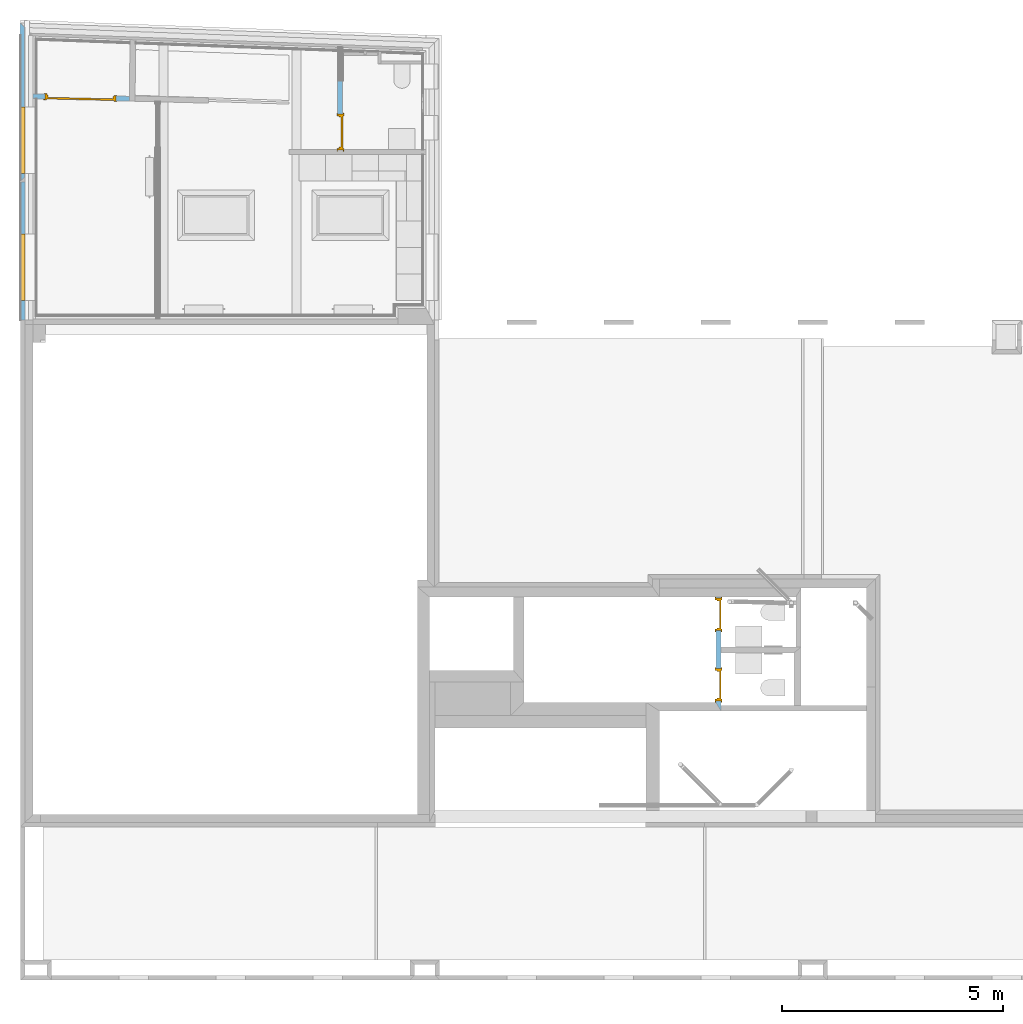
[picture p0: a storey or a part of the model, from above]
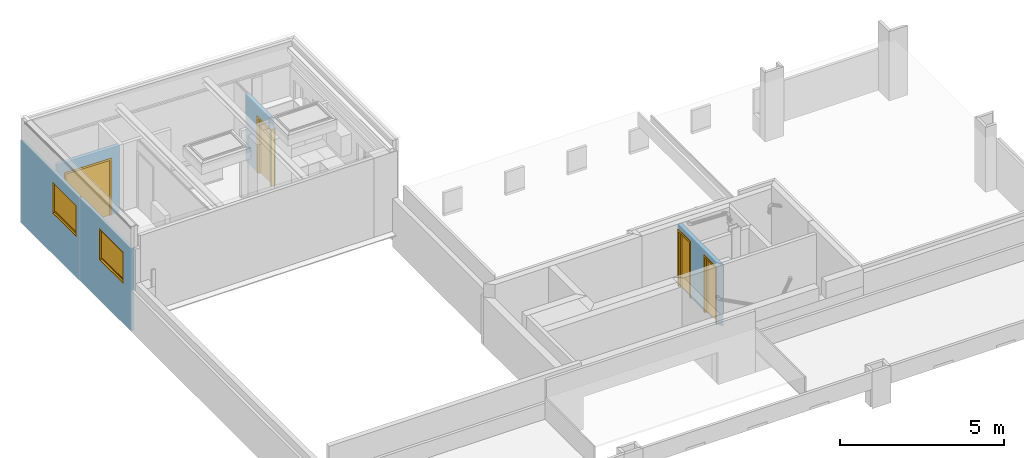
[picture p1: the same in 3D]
Properties of the parts of a building model (IFC2X3), part 1 of 17

# File
Description: ViewDefinition [CoordinationView_V2.0], Comment [Comments], Comment [System: OpenBuildings Designer24.00.03.14]
File name: SHE_DRAWING+SHEET revH1
Time: 2026-07-15T07:19:15+02:00
Author: First Name Last Name
Organization: spaceAgent.com
Written by: ST-DEVELOPER v16.13
Made in: OpenBuildings Designer 24.00.03.14
Authorization: Administrator
Comment: Generated by software containing ST-Developer * from STEP Tools, Inc. (www.steptools.com)
Comment: description
Comment: implementation_level
Comment: name
Comment: time_stamp
Comment: author
Comment: organization
Comment: preprocessor_version
Comment: originating_system
Comment: authorisation

# IfcProject, BuildingTemplate_UK
Project - Project Name: BuildingTemplate_UK

# IfcSite, Site
RefElevation: 0 m
Pset_SiteCommon - BuildableArea: 0 m2
Site - Site Name: Site; Building Height Limit: 0 m

# IfcBuilding, Building01
ElevationOfRefHeight: 4.64 m; ElevationOfTerrain: 0 m
Classification - Uniclass2015: Co_20
Building Parameters - Building Name: Building01

# IfcBuildingStorey (7)
In: Building01
Pset_BuildingStoreyCommon - GrossAreaPlanned: 9600 m2; NetAreaPlanned: 9600 m2
Structural Floor Parameters - Column Splice Floor: no
Floor Parameters - Length (Approx.): 120 m; Width (Approx.): 80 m; Typical Floor: no; Typical Floor Base Elevation: 0 m; ACS Rotation Angle: 0:0; Annotate: yes
Floor - Area (Gross): 9600 m2; Area (Net): 9600 m2
Name | Description = Floor Parameters, Description | Elevation (m) = Elevation | Finished Floor | Floor Name | Typical Floor Height (m)
GF | Ground Floor | 0 | GF | 3
MF | Mezzanine Floor | 2.6 | MF | 3
1F | First Floor | 5.15 | 1F | 0.004 | Classification - Uniclass2015: EF_30_20
3F | Third Floor | 12.13 | 3F | 3
5F | Fifth floor | 17.71 | 5F | 3
RL |  | 20.96 | RL | 0 | Classification - Uniclass2015: EF_30_20
2F | Second Floor | 8.64 | 2F | 3 | Classification - Uniclass2015: \

# IfcSpace: A-AdministrativeCommercialAndProtectiveSer, 0
In: GF
Type - PredefinedType: USERDEFINED
Type - Space Parameters - Label: Administrative & Commercial Spaces; Ceiling Height: 3 m; major: 1; minor: 1
Type - Materials - Part Definition: A-Spaces::A_BSUK_AdministrativeCommercialAndProtectiveSer
Type - Energy Analysis - Energy Analysis | Space Category: Interior
Type - Discipline - Discipline: Architectural
Type - Construction Phase - Phase: New Construction
Type - Classification - Uniclass2015: SL_20
Description: UNIT; LongName: commercial; ElevationWithFlooring: -4.64 m
Space Parameters - Label: UNIT; Space Number: 0; Label 2: commercial; Ceiling Height: 4.5 m; Perimeter: 44.9707 m; Area | Program: 0 m2; Area | Actual: 99.3628 m2
Space - Notes: skirting white

# IfcSpace: A-CirculationAndStorageSpaces (65)
Type - PredefinedType: USERDEFINED
Type - Space Parameters - Label: Circulation & Storage Spaces; Ceiling Height: 3 m; major: 1; minor: 1
Type - Materials - Part Definition: A-Spaces::A_BSUK_CirculationAndStorageSpaces
Type - Energy Analysis - Energy Analysis | Space Category: Interior
Type - Discipline - Discipline: Architectural
Type - Construction Phase - Phase: New Construction
ElevationWithFlooring: -4.64 m
Space Parameters - Area | Program: 0 m2
Name | In | Description = Label | LongName | Space Number | Label 2 | Ceiling Height (m) | Perimeter (m) | Area | Actual (m2) | Notes | Part Definition
1 | GF | stair | vinyl (acD) | 1 | vinyl (acD) | 2.5 | 9.93685 | 4.25527 | skirting vinyl
1 | GF | riser | 1 | 1 |  | 2.5 | 3.72964 | 0.510705 | n/a | A-Spaces::_Void
0 | GF | riser | 0 | 0 |  | 2.5 | 11.4772 | 2.99959 | n/a | A-Spaces::_Void
bike store | GF | bike store | asphalt |  | asphalt | 2 | 15.5649 | 11.0029 | n/a | A-Spaces::_Exterior_Space
bike store | GF | bike store | asphalt |  | asphalt | 2 | 9.73329 | 5.58868 | n/a | A-Spaces::_Exterior_Space
landing | MF | landing | vinyl (acD) |  | vinyl (acD) | 2.5 | 11.3025 | 5.20961 | skirting vinyl
WC | MF | WC | tile |  | tile | 2.5 | 8.28221 | 4.08071 | wall tile (up to 2m) | A-Spaces::_Interior_Space
1 | MF | storage | screed | 1 | screed | 2.5 | 8.26251 | 3.91896 | n/a
storage | MF | storage | screed |  | screed | 2.5 | 13.8687 | 10.5472 | n/a
1 | MF | stair | vinyl (acD) | 1 | vinyl (acD) | 2.5 | 11.6311 | 5.18709 | skirting vinyl
2 | MF | stair | vinyl (acD) | 2 | vinyl (acD) | 2.5 | 9.10975 | 3.67745 | skirting vinyl
landing | MF | landing | parquet |  | parquet | 2.5 | 6.70142 | 2.46885 | skirting white | A-Spaces::_Interior_Space
storage | MF | storage | parquet |  | parquet | 2.5 | 6.66153 | 2.57457 | n/a
bath | MF | bath | tile |  | tile | 2.5 | 8.02096 | 3.98235 | wall tile (up to 2m) | A-Spaces::_Interior_Space
1 | 1F | AOV | 1 | 1 |  | 2.6 | 3.35384 | 0.672727 | n/a | A-Spaces::_Void
1 | 1F | riser | 1 | 1 |  | 2.6 | 3.35384 | 0.672727 | n/a | A-Spaces::_Void
hall (vented) | 1F | hall (vented) | carpet (acC) |  | carpet (acC) | 2.6 | 20.45 | 10.5189 | skirting oak | A-Spaces::_Interior_Space
1 | 1F | stair | vinyl (acD) | 1 | vinyl (acD) | 2.5 | 11.2192 | 7.00439 | skirting vinyl
landing | 1F | landing | vinyl (acD) |  | vinyl (acD) | 2.6 | 7.88137 | 3.11561 | skirting vinyl
1 | 1F | lobby | carpet (acC) | 1 | carpet (acC) | 2.6 | 6.79532 | 2.84649 | skirting oak | A-Spaces::_Interior_Space
2 | 1F | riser | 2 | 2 |  | 2.6 | 2.83 | 0.258 | n/a | A-Spaces::_Void
2 | 1F | lobby | carpet (acC) | 2 | carpet (acC) | 2.6 | 13.4953 | 7.50678 | skirting oak | A-Spaces::_Interior_Space
1 | 3F | AOV | 1 | 1 |  | 2.6 | 3.35384 | 0.672727 | n/a | A-Spaces::_Void
1 | 3F | riser | 1 | 1 |  | 2.6 | 3.35384 | 0.672727 | n/a | A-Spaces::_Void
hall (vented) | 3F | hall (vented) | carpet (acC) |  | carpet (acC) | 2.6 | 20.4452 | 10.5149 | skirting oak | A-Spaces::_Interior_Space
1 | 3F | stair | vinyl (acD) | 1 | vinyl (acD) | 2.5 | 11.2192 | 7.00458 | skirting vinyl
landing | 3F | landing | vinyl (acD) |  | vinyl (acD) | 2.6 | 7.9118 | 3.13941 | skirting vinyl
1 | 3F | lobby | carpet (acC) | 1 | carpet (acC) | 2.6 | 6.79532 | 2.84649 | skirting oak | A-Spaces::_Interior_Space
2 | 3F | riser | 2 | 2 |  | 2.6 | 2.83 | 0.258 | n/a | A-Spaces::_Void
2 | 3F | lobby | carpet (acC) | 2 | carpet (acC) | 2.6 | 13.4942 | 7.50726 | skirting oak | A-Spaces::_Interior_Space
landing | 1F | landing | vinyl (acD) |  | vinyl (acD) | 2.5 | 7.02024 | 2.75607 | skirting vinyl
hall (vented) | 1F | hall (vented) | carpet (acC) |  | carpet (acC) | 2.5 | 16.6709 | 8.79017 | skirting oak | A-Spaces::_Interior_Space
1 | 1F | lobby | carpet (acC) | 1 | carpet (acC) | 2.5 | 7.86583 | 3.64937 | skirting oak | A-Spaces::_Interior_Space
2 | 1F | lobby | carpet (acC) | 2 | carpet (acC) | 2.5 | 7.53988 | 3.40491 | skirting oak | A-Spaces::_Interior_Space
1 | 1F | AOV | 1 | 1 |  | 2.5 | 4.25 | 0.936464 | n/a | A-Spaces::_Void
1 | 1F | riser | 1 | 1 |  | 2.5 | 3.23114 | 0.605336 | n/a | A-Spaces::_Void
1 | 1F | stair | vinyl (acD) | 1 | vinyl (acD) | 2.5 | 11.3017 | 7.67441 | skirting vinyl
3 | 1F | stair | parquet | 3 | parquet | 2.5 | 9.30005 | 3.43648 | skirting white | A-Spaces::_Interior_Space
4 | 1F | stair | parquet | 4 | parquet | 2.5 | 9.86062 | 3.62728 | skirting white | A-Spaces::_Interior_Space
5 | 1F | stair | parquet | 5 | parquet | 2.5 | 9.09993 | 3.28497 | skirting white | A-Spaces::_Interior_Space
6 | 1F | stair | parquet | 6 | parquet | 2.5 | 9.4 | 3.42 | skirting white | A-Spaces::_Interior_Space
26 | 5F | FLAT | 4b6p (upper) | 26 | 4b6p (upper) | 2.5 | 35.2527 | 38.2118 | n/a | A-Spaces::A_BSUK_ResidentialSpaces
23 | 5F | FLAT | 4b6p (upper) | 23 | 4b6p (upper) | 2.5 | 35.2129 | 43.2149 | n/a | A-Spaces::A_BSUK_ResidentialSpaces
24 | 5F | FLAT | 3b6p (upper) | 24 | 3b6p (upper) | 2.5 | 35.1807 | 43.4478 | n/a | A-Spaces::A_BSUK_ResidentialSpaces
25 | 5F | FLAT | 3b6p (upper) | 25 | 3b6p (upper) | 2.5 | 38.0413 | 41.0862 | n/a | A-Spaces::A_BSUK_ResidentialSpaces
1 | 5F | AOV | 1 | 1 |  | 2.5 | 3.5 | 0.715 | n/a | A-Spaces::_Void
2 | 5F | AOV | hatch over | 2 | hatch over | 2.5 | 5.99988 | 1.99994 | n/a | A-Spaces::_Void
ter.23 | 5F | ter.23 | tile |  | tile | 2.5 | 19.7927 | 12.5632 | n/a | A-Spaces::_Exterior_Space
ter.24 | 5F | ter.24 | tile |  | tile | 2.5 | 19.7924 | 12.5622 | n/a | A-Spaces::_Exterior_Space
ter.26 | 5F | ter.26 | tile |  | tile | 2.5 | 19.7922 | 12.5629 | n/a | A-Spaces::_Exterior_Space
ter.25 | 5F | ter.25 | tile |  | tile | 2.5 | 19.7919 | 12.5618 | n/a | A-Spaces::_Exterior_Space
k/d/l | 5F | k/d/l | parquet |  | parquet | 2.5 | 38.0527 | 44.7522 | skirting white | A-Spaces::_Interior_Space
k/d/l | 5F | k/d/l | parquet |  | parquet | 2.5 | 40.8413 | 47.1014 | skirting white | A-Spaces::_Interior_Space
k/d/l | 5F | k/d/l | parquet |  | parquet | 2.5 | 38.0129 | 49.2272 | skirting white | A-Spaces::_Interior_Space
k/d/l | 5F | k/d/l | parquet |  | parquet | 2.5 | 37.9807 | 49.449 | skirting white | A-Spaces::_Interior_Space
2 | RL | AOV | access hatch | 2 | access hatch | 2.5 | 5.99988 | 1.99994 | n/a | A-Spaces::_Void
1 | RL | AOV | MSVS | 1 | MSVS | 2.5 | 10.8891 | 5.66237 | n/a | A-Spaces::_Void
1 | 2F | AOV | 1 | 1 |  | 2.6 | 3.35384 | 0.672727 | n/a | A-Spaces::_Void
1 | 2F | riser | 1 | 1 |  | 2.6 | 3.35384 | 0.672727 | n/a | A-Spaces::_Void
hall (vented) | 2F | hall (vented) | carpet (acC) |  | carpet (acC) | 2.6 | 20.45 | 10.5189 | skirting oak | A-Spaces::_Interior_Space
1 | 2F | stair | vinyl (acD) | 1 | vinyl (acD) | 2.5 | 11.2192 | 7.00458 | skirting vinyl
landing | 2F | landing | vinyl (acD) |  | vinyl (acD) | 2.6 | 7.9118 | 3.13941 | skirting vinyl
1 | 2F | lobby | carpet (acC) | 1 | carpet (acC) | 2.6 | 6.79532 | 2.84649 | skirting oak | A-Spaces::_Interior_Space
2 | 2F | riser | 2 | 2 |  | 2.6 | 2.83 | 0.258 | n/a | A-Spaces::_Void
2 | 2F | lobby | carpet (acC) | 2 | carpet (acC) | 2.6 | 13.4953 | 7.50721 | skirting oak | A-Spaces::_Interior_Space

# IfcSpace: A-ResidentialSpaces (28)
Type - PredefinedType: USERDEFINED
Type - Space Parameters - Label: Residential Spaces; Ceiling Height: 3 m; major: 1; minor: 1
Type - Materials - Part Definition: A-Spaces::A_BSUK_ResidentialSpaces
Type - Energy Analysis - Energy Analysis | Space Category: Interior
Type - Discipline - Discipline: Architectural
Type - Construction Phase - Phase: New Construction
Type - Classification - Uniclass2015: SL_45
ElevationWithFlooring: -4.64 m
Space Parameters - Area | Program: 0 m2
Space - Notes: n/a
Name | In | Description = Label | LongName = Label 2 | Space Number | Ceiling Height (m) | Perimeter (m) | Area | Actual (m2)
01 | GF | FLAT | 2b4p (lower) | 01 | 2.5 | 30.3387 | 47.5078
ENTRANCE | GF | ENTRANCE | residential |  | 4.5 | 31.3079 | 32.4907
01 | MF | FLAT | 2b4p (upper) | 01 | 2.5 | 38.9329 | 49.2519
07 | 1F | FLAT | 1b1p | 07 | 2.6 | 25.786 | 41.2992
06 | 1F | FLAT | 1b1p | 06 | 2.6 | 30.6107 | 40.6276
05 | 1F | FLAT | 1b1p | 05 | 2.6 | 28.883 | 41.0837
04 | 1F | FLAT | 1b1p | 04 | 2.6 | 28.903 | 41.1303
03 | 1F | FLAT | 1b1p | 03 | 2.6 | 30.9647 | 42.3191
02 | 1F | FLAT | 2b4p | 02 | 2.6 | 40.6617 | 73.0578
08 | 1F | FLAT | 1b1p | 08 | 2.6 | 29.5789 | 45.4997
21 | 3F | FLAT | 1b1p | 21 | 2.6 | 27.53 | 42.5859
20 | 3F | FLAT | 1b1p | 20 | 2.6 | 31.4827 | 41.2785
19 | 3F | FLAT | 1b1p | 19 | 2.6 | 28.883 | 41.0727
18 | 3F | FLAT | 1b1p | 18 | 2.6 | 28.903 | 41.1303
17 | 3F | FLAT | 1b1p | 17 | 2.6 | 31.8367 | 42.96
16 | 3F | FLAT | 2b4p | 16 | 2.6 | 41.0977 | 73.3782
22 | 3F | FLAT | 1b1p | 22 | 2.6 | 30.0149 | 45.8163
26 | 1F | FLAT | 4b6p (lower) | 26 | 2.5 | 39.478 | 74.3995
23 | 1F | FLAT | 4b6p (lower) | 23 | 2.5 | 39.2381 | 76.1835
24 | 1F | FLAT | 3b6p (lower) | 24 | 2.5 | 39.6636 | 68.1409
25 | 1F | FLAT | 3b6p (lower) | 25 | 2.5 | 39.3775 | 63.4613
14 | 2F | FLAT | 1b1p | 14 | 2.6 | 27.53 | 42.5859
13 | 2F | FLAT | 1b1p | 13 | 2.6 | 31.4827 | 41.2785
12 | 2F | FLAT | 1b1p | 12 | 2.6 | 28.883 | 41.0837
11 | 2F | FLAT | 1b1p | 11 | 2.6 | 28.903 | 41.1303
10 | 2F | FLAT | 1b1p | 10 | 2.6 | 31.8367 | 42.96
09 | 2F | FLAT | 2b4p | 09 | 2.6 | 41.2696 | 73.3567
15 | 2F | FLAT | 1b1p | 15 | 2.6 | 30.0149 | 45.8163

# IfcSpace: _Exterior Space (23)
Type - PredefinedType: USERDEFINED
Type - Space Parameters - Label: EXTERIOR SPACE; Ceiling Height: 3 m; Area | Program: 0 m2; major: 1; minor: 1
Type - Materials - Part Definition: A-Spaces::_Exterior_Space
Type - Energy Analysis - Energy Analysis | Space Category: Exterior
Type - Discipline - Discipline: Architectural
Type - Construction Phase - Phase: New Construction
Type - Classification - Uniclass2015: PM_40_30_17
ElevationWithFlooring: -4.64 m
Name | In | Description = Label | LongName = Label 2 | Ceiling Height (m) | Perimeter (m) | Area | Actual (m2) | Notes | Space Number
storage | GF | storage | asphalt | 2.5 | 10.2434 | 4.88146 | n/a
plant | GF | plant | sprinkler | 2.5 | 13.8942 | 9.76522 | n/a
refuse area | GF | refuse area | asphalt | 2 | 23.634 | 16.6836 | n/a
bike store | GF | bike store | asphalt | 2 | 15.0532 | 9.86402 | n/a
0 | GF | YARD | asphalt | 4 | 45.5698 | 90.2117 | n/a | 0
UNDERCROFT (front) | GF | UNDERCROFT (front) | paving | 4 | 62.6011 | 86.1884 | n/a
UNDERCROFT (back) | GF | UNDERCROFT (back) | asphalt | 4 | 58.8215 | 136.239 | n/a
1 | GF | Car P. | flat23 | 2 | 14.8 | 12 | n/a | 1
2 | GF | Car P. | flat24 | 2 | 14.8 | 12 | n/a | 2
3 | GF | Car P. | flat25 | 2 | 14.8002 | 12.0005 | n/a | 3
4 | GF | Car P. | flat26 | 2 | 14.8 | 12 | n/a | 4
1 | GF | YARD | asphalt (flat01) | 4 | 17.9409 | 17.4995 | n/a | 1
5 | GF | Car P. | flat01 | 2 | 14.8 | 12 | n/a | 5
storage | 1F | storage | carpet | 2.5 | 8.04048 | 2.75523 | skirting white | Materials - Part Definition: A-Spaces::_Interior_Space
storage | 1F | storage | carpet | 2.5 | 8.04048 | 3.18825 | skirting white | Materials - Part Definition: A-Spaces::_Interior_Space
1 | 5F | AC | optional |  | 2.79325 | 0.397029 | n/a | 1
2 | 5F | AC | optional |  | 2.79325 | 0.397029 | n/a | 2
4 | 5F | AC | optional |  | 2.79325 | 0.397029 | n/a | 4
3 | 5F | AC | optional |  | 2.79325 | 0.397029 | n/a | 3
flat roof | RL | flat roof | brown roof (tbc) | 2 | 56.1601 | 160.64 | n/a
16 | GF | balc. | tile |  | 17.6972 | 14.8939 | n/a | 16
09 | GF | balc. | tile |  | 17.6972 | 14.8939 | n/a | 09
02 | GF | balc. | tile |  | 17.6972 | 14.8939 | n/a | 02

# IfcSpace: _Interior (139)
Type - PredefinedType: USERDEFINED
Type - Space Parameters - Label: INTERIOR SPACE; Ceiling Height: 3 m; Area | Program: 0 m2; major: 1; minor: 1
Type - Materials - Part Definition: A-Spaces::_Interior_Space
Type - Energy Analysis - Energy Analysis | Space Category: Interior
Type - Discipline - Discipline: Architectural
Type - Construction Phase - Phase: New Construction
Type - Classification - Uniclass2015: PM_40_30_17
ElevationWithFlooring: -4.64 m
Name | In | Description = Label | LongName = Label 2 | Ceiling Height (m) | Perimeter (m) | Area | Actual (m2) | Notes
firef. LIFT | GF | firef. LIFT | (1.1x1.4m) | 2.2 | 4.8 | 1.4 | n/a | Materials - Part Definition: A-Spaces::_Void
bed | GF | bed | carpet | 2.6 | 16.9306 | 16.1823 | skirting white
bath | GF | bath | tile | 2.6 | 8.42663 | 4.02329 | wall tile (up to 2m)
corridor | GF | corridor | parquet | 2.6 | 22.8095 | 18.4831 | skirting white
F | GF | WC | tile (disab.) | 2.6 | 8.46664 | 4.29711 | wall tile (up to 2m) | Space Parameters - Space Number: F
M | GF | WC | tile | 2.6 | 6.8273 | 2.65638 | wall tile (up to 2m) | Space Parameters - Space Number: M
firef. LIFT | MF | firef. LIFT | (1.1x1.4m) | 2.2 | 4.8 | 1.4 | n/a | Materials - Part Definition: A-Spaces::_Void
2 | MF | bed | carpet | 2.6 | 15.1363 | 13.1528 | skirting white | Space Parameters - Space Number: 2
k/d/l | MF | k/d/l | parquet | 2.6 | 21.6917 | 25.0467 | skirting white
k/d/l | 1F | k/d/l | parquet | 2.6 | 19.206 | 18.8529 | skirting white
bath | 1F | bath | tile | 2.6 | 7.57 | 3.188 | wall tile (up to 2m)
storage | 1F | storage | parquet | 2.6 | 5 | 1.26 | skirting white
bath | 1F | bath | tile | 2.6 | 8.85627 | 3.75315 | wall tile (up to 2m)
storage | 1F | storage | parquet | 2.6 | 4.75839 | 1.24325 | skirting white
k/d/l | 1F | k/d/l | parquet | 2.6 | 25.4441 | 23.3097 | skirting white
2 x bed | 1F | bed | carpet | 2.6 | 14.94 | 11.4885 | skirting white
k/d/l | 1F | k/d/l | parquet | 2.6 | 24.0409 | 23.4095 | skirting white
2 x bath | 1F | bath | tile | 2.6 | 7.8 | 3.6 | wall tile (up to 2m)
storage | 1F | storage | parquet | 2.6 | 6.58993 | 1.70217 | skirting white
storage | 1F | storage | parquet | 2.6 | 6.59 | 1.70223 | skirting white
2 x firef. LIFT | 1F | firef. LIFT | (1.1x1.4m) | 2.2 | 4.8 | 1.4 | n/a | Materials - Part Definition: A-Spaces::_Void
k/d/l | 1F | k/d/l | parquet | 2.6 | 24.497 | 23.2991 | skirting white
studio | 1F | studio | parquet | 2.6 | 31.4647 | 37.2975 | skirting white
bath | 1F | bath | tile | 2.6 | 7.898 | 3.43088 | wall tile (up to 2m)
corridor | 1F | corridor | parquet | 2.6 | 16.5296 | 9.0203 | skirting white
bath | 1F | bath | tile | 2.6 | 8.19 | 4.176 | wall tile (up to 2m)
k/d/l | 1F | k/d/l | parquet | 2.6 | 20.4702 | 23.828 | skirting white
2 | 1F | bed | carpet | 2.6 | 15.0894 | 11.9399 | skirting white | Space Parameters - Space Number: 2
1 | 1F | bed | carpet | 2.6 | 17.0797 | 15.1572 | skirting white | Space Parameters - Space Number: 1
storage | 1F | storage | parquet | 2.6 | 2.74374 | 0.470142 | skirting white
k/d/l | 1F | k/d/l | parquet | 2.6 | 20.6123 | 21.7383 | skirting white
corridor | 1F | corridor | parquet | 2.6 | 11.3315 | 6.13542 | skirting white
bath | 1F | bath | tile | 2.6 | 7.80943 | 3.60707 | wall tile (up to 2m)
storage | 1F | storage | parquet | 2.6 | 4.56315 | 1.30038 | skirting white
corridor | 1F | corridor | parquet | 2.6 | 13.57 | 6.7325 | skirting white
bed | 1F | bed | carpet | 2.6 | 14.4144 | 11.4258 | skirting white
bed | 1F | bed | carpet | 2.6 | 12.7068 | 9.99626 | skirting white
bed | 1F | bed | carpet | 2.6 | 14.3106 | 11.3749 | skirting white
ensuite | 1F | ensuite | tile | 2.6 | 7.89374 | 3.31102 | wall tile (up to 2m)
storage | 1F | storage | parquet | 2.6 | 4.59 | 1.1165 | skirting white
storage | 1F | storage | parquet | 2.6 | 10.8267 | 2.53079 | skirting white
k/d/l | 3F | k/d/l | parquet | 2.6 | 20.514 | 19.8142 | skirting white
bath | 3F | bath | tile | 2.6 | 7.57 | 3.188 | wall tile (up to 2m)
storage | 3F | storage | parquet | 2.6 | 5 | 1.26 | skirting white
bath | 3F | bath | tile | 2.6 | 8.85627 | 3.75315 | wall tile (up to 2m)
storage | 3F | storage | parquet | 2.6 | 4.75839 | 1.24325 | skirting white
k/d/l | 3F | k/d/l | parquet | 2.6 | 26.3161 | 23.9605 | skirting white
2 x bed | 3F | bed | carpet | 2.6 | 14.94 | 11.4885 | skirting white
k/d/l | 3F | k/d/l | parquet | 2.6 | 24.0409 | 23.4095 | skirting white
2 x bath | 3F | bath | tile | 2.6 | 7.8 | 3.6 | wall tile (up to 2m)
storage | 3F | storage | parquet | 2.6 | 6.58993 | 1.70217 | skirting white
storage | 3F | storage | parquet | 2.6 | 6.59 | 1.70223 | skirting white
firef. LIFT | 3F | firef. LIFT | (1.1x1.4m) | 2.2 | 4.8 | 1.4 | n/a | Materials - Part Definition: A-Spaces::_Void
k/d/l | 3F | k/d/l | parquet | 2.6 | 24.497 | 23.2991 | skirting white
studio | 3F | studio | parquet | 2.6 | 32.3367 | 37.9385 | skirting white
bath | 3F | bath | tile | 2.6 | 7.898 | 3.43088 | wall tile (up to 2m)
corridor | 3F | corridor | parquet | 2.6 | 16.5296 | 9.0203 | skirting white
bath | 3F | bath | tile | 2.6 | 8.19 | 4.176 | wall tile (up to 2m)
k/d/l | 3F | k/d/l | parquet | 2.6 | 20.9062 | 24.1484 | skirting white
2 | 3F | bed | carpet | 2.6 | 15.0894 | 11.9399 | skirting white | Space Parameters - Space Number: 2
1 | 3F | bed | carpet | 2.6 | 17.0797 | 15.1572 | skirting white | Space Parameters - Space Number: 1
storage | 3F | storage | parquet | 2.6 | 2.74374 | 0.470142 | skirting white
k/d/l | 3F | k/d/l | parquet | 2.6 | 20.8123 | 22.155 | skirting white
corridor | 3F | corridor | parquet | 2.6 | 11.1315 | 6.01011 | skirting white
bath | 3F | bath | tile | 2.6 | 7.80943 | 3.60707 | wall tile (up to 2m)
storage | 3F | storage | parquet | 2.6 | 4.56315 | 1.30038 | skirting white
corridor | 3F | corridor | parquet | 2.6 | 13.57 | 6.7325 | skirting white
bed | 3F | bed | carpet | 2.6 | 14.6504 | 11.4605 | skirting white
bed | 3F | bed | carpet | 2.6 | 13.1428 | 10.3217 | skirting white
bed | 3F | bed | carpet | 2.6 | 14.3106 | 11.3749 | skirting white
ensuite | 3F | ensuite | tile | 2.6 | 7.89374 | 3.31102 | wall tile (up to 2m)
storage | 3F | storage | parquet | 2.6 | 4.59 | 1.1165 | skirting white
storage | 3F | storage | parquet | 2.6 | 10.8267 | 2.53079 | skirting white
1 | 1F | bed | carpet | 2.5 | 18.5595 | 16.7018 | skirting white | Space Parameters - Space Number: 1
2 | 1F | bed | carpet | 2.5 | 17.0596 | 17.0642 | skirting white | Space Parameters - Space Number: 2
3 | 1F | bed | carpet | 2.5 | 15.5204 | 13.1055 | skirting white | Space Parameters - Space Number: 3
1 | 1F | bed | carpet | 2.5 | 15.4796 | 12.4714 | skirting white | Space Parameters - Space Number: 1
2 | 1F | bed | carpet | 2.5 | 17.0597 | 17.0642 | skirting white | Space Parameters - Space Number: 2
3 | 1F | bed | carpet | 2.5 | 21.2205 | 20.0816 | skirting white | Space Parameters - Space Number: 3
1 | 1F | bed | carpet | 2.5 | 15.8135 | 14.5623 | skirting white | Space Parameters - Space Number: 1
2 | 1F | bed | carpet | 2.5 | 13.9942 | 11.7202 | skirting white | Space Parameters - Space Number: 2
3 | 1F | bed | carpet | 2.5 | 15.43 | 13.4523 | skirting white | Space Parameters - Space Number: 3
1 | 1F | bed | carpet | 2.5 | 15.9594 | 15.0373 | skirting white | Space Parameters - Space Number: 1
2 | 1F | bed | carpet | 2.5 | 13.98 | 10.1834 | skirting white | Space Parameters - Space Number: 2
3 | 1F | bed | carpet | 2.5 | 15.39 | 13.2723 | skirting white | Space Parameters - Space Number: 3
corridor (protected) | 1F | corridor (protected) | parquet | 2.5 | 17.0031 | 11.5791 | skirting white
corridor (protected) | 1F | corridor (protected) | parquet | 2.5 | 15.5899 | 9.09301 | skirting white
corridor (protected) | 1F | corridor (protected) | parquet | 2.5 | 14.14 | 7.78613 | skirting white
corridor (protected) | 1F | corridor (protected) | parquet | 2.5 | 17.46 | 9.28961 | skirting white
bath | 1F | bath | tile | 2.5 | 11.4399 | 7.26747 | wall tile (up to 2m)
bath | 1F | bath | tile | 2.5 | 9.60027 | 4.97525 | wall tile (up to 2m)
bath | 1F | bath | tile | 2.5 | 9.61248 | 4.99208 | wall tile (up to 2m)
ensuite | 1F | ensuite | tile | 2.5 | 9.6127 | 4.9406 | wall tile (up to 2m)
ensuite | 1F | ensuite | tile | 2.5 | 8.21964 | 4.07132 | wall tile (up to 2m)
ensuite | 1F | ensuite | tile | 2.5 | 8.21964 | 4.07133 | wall tile (up to 2m)
bath | 1F | bath | tile | 2.5 | 8.94446 | 4.54559 | wall tile (up to 2m)
ensuite | 1F | ensuite | tile | 2.5 | 7.27294 | 3.08918 | wall tile (up to 2m)
storage | 1F | storage | parquet | 2.5 | 4.47976 | 1.20139 | skirting white
storage | 1F | storage | parquet | 2.5 | 5.08042 | 1.46085 | skirting white
firef. LIFT | 5F | firef. LIFT | (1.1x1.4m) | 2.2 | 4.8 | 1.4 | n/a | Materials - Part Definition: A-Spaces::_Void
k/d/l | 2F | k/d/l | parquet | 2.6 | 20.514 | 19.8142 | skirting white
bath | 2F | bath | tile | 2.6 | 7.57 | 3.188 | wall tile (up to 2m)
storage | 2F | storage | parquet | 2.6 | 5 | 1.26 | skirting white
bath | 2F | bath | tile | 2.6 | 8.85627 | 3.75315 | wall tile (up to 2m)
storage | 2F | storage | parquet | 2.6 | 4.75839 | 1.24325 | skirting white
k/d/l | 2F | k/d/l | parquet | 2.6 | 26.3161 | 23.9605 | skirting white
2 x bed | 2F | bed | carpet | 2.6 | 14.94 | 11.4885 | skirting white
k/d/l | 2F | k/d/l | parquet | 2.6 | 24.0409 | 23.4095 | skirting white
2 x bath | 2F | bath | tile | 2.6 | 7.8 | 3.6 | wall tile (up to 2m)
storage | 2F | storage | parquet | 2.6 | 6.58993 | 1.70217 | skirting white
storage | 2F | storage | parquet | 2.6 | 6.59 | 1.70223 | skirting white
firef. LIFT | 2F | firef. LIFT | (1.1x1.4m) | 2.2 | 4.8 | 1.4 | n/a | Materials - Part Definition: A-Spaces::_Void
k/d/l | 2F | k/d/l | parquet | 2.6 | 24.497 | 23.2991 | skirting white
studio | 2F | studio | parquet | 2.6 | 32.3367 | 37.9385 | skirting white
bath | 2F | bath | tile | 2.6 | 7.898 | 3.43088 | wall tile (up to 2m)
corridor | 2F | corridor | parquet | 2.6 | 16.5296 | 9.0203 | skirting white
bath | 2F | bath | tile | 2.6 | 8.19 | 4.176 | wall tile (up to 2m)
k/d/l | 2F | k/d/l | parquet | 2.6 | 20.9062 | 24.1484 | skirting white
2 | 2F | bed | carpet | 2.6 | 15.0894 | 11.9399 | skirting white | Space Parameters - Space Number: 2
1 | 2F | bed | carpet | 2.6 | 17.0797 | 15.1572 | skirting white | Space Parameters - Space Number: 1
storage | 2F | storage | parquet | 2.6 | 2.74374 | 0.470142 | skirting white
k/d/l | 2F | k/d/l | parquet | 2.6 | 20.8123 | 22.155 | skirting white
corridor | 2F | corridor | parquet | 2.6 | 11.1315 | 6.01011 | skirting white
bath | 2F | bath | tile | 2.6 | 7.80943 | 3.60707 | wall tile (up to 2m)
storage | 2F | storage | parquet | 2.6 | 4.56315 | 1.30038 | skirting white
corridor | 2F | corridor | parquet | 2.6 | 13.57 | 6.7325 | skirting white
bed | 2F | bed | carpet | 2.6 | 14.6504 | 11.4605 | skirting white
bed | 2F | bed | carpet | 2.6 | 13.1428 | 10.3217 | skirting white
bed | 2F | bed | carpet | 2.6 | 14.3106 | 11.3749 | skirting white
ensuite | 2F | ensuite | tile | 2.6 | 7.89374 | 3.31102 | wall tile (up to 2m)
storage | 2F | storage | parquet | 2.6 | 4.59 | 1.1165 | skirting white
storage | 2F | storage | parquet | 2.6 | 10.8267 | 2.53079 | skirting white

# IfcBeam: A-Beams-Steel (244)
Type - PredefinedType: BEAM
Type - Profile - Name: UB203X133X25
Type - Thermal Transmittance - Is External: no; Is Below Grade: no
Type - Structural Usage - Structural | Material: Steel
Type - Structural Parameters - Section Name: UB203X133X25; Structural Type: Beam; Tapered Member: no
Type - Steel Beam Results - End 1 Shear: 0; End 2 Shear: 0
Type - Materials - Part Definition: A-Beams::A_BSUK_Beams_Steel
Type - Fireproofing - Has Fireproofing: no
Type - Fire Resistance - Fire | IsCombustible: no; Fire | Compartmentation: no
Type - Discipline - Discipline: Architectural
Type - Construction Phase - Phase: New Construction
Type - Classification - Uniclass2015: Pr_20_85_08_11
Material: A_BSUK_Beams_Steel
Pset_BeamCommon - IsExternal: no; LoadBearing: no
Quantities | Structural - Material Density: 7850.000000
Fireproofing - Fireproofing Thickness: 0 m
BuildingDesignerForm - Cope Flange Clearance: 0.000; Cope Web Clearance: 0.000; Cope Corner Treatment: 0; Cope Corner Radius: 0.000; Local Y Offset: 0.000; Local Z Offset: 0.000
Name | In | Description | CodeSystem | Name = StructuralFramingCommon, Section Name | Structural Parameters, Section Name | Camber (m) | Length (m) | Area | Cross-sectional (m2) | Area | Cross-sectional Modeled (m2) | Area | Side Surfaces Modeled (Gross) (m2) | Area | All Surfaces Modeled (Net) (m2) | Volume | Perforation(s) (m3) | Volume (Gross) (m3) | Volume (Gross Modeled) (m3) | Volume (Net) (m3) | Volume (Net Modeled) (m3) | Unit Weight | Length x Unit Weight | Volume (Gross) x Density | Volume (Gross Modeled) x Density | Volume (Net) x Density | Volume (Net Modeled) x Density | ID | Number | ID | Name (Alternate) | ID | Description | ID | Keynote | FireRating = Fire | Rating
MZ | MF | existing internal beam :2 ,SHE-02.MEZZANINE.dgn,Design Model:192737 | BS UC | UC203X203X46 | 1\BS UC\UC203X203X46 | 0 | 6.35664 | 0.00587 | 0.005784 | 7.66866 | 7.68022 | 0 | 0.037314 | 0.036766 | 0.037314 | 0.036766 | 46.100000 | 293.041306 | 292.910995 | 288.611640 | 292.910995 | 288.611640 | MZ | retained beam | existing internal beam | intumescent paint | Construction Phase - Phase: Existing to Remain
MZ | MF | existing internal beam :2 ,SHE-02.MEZZANINE.dgn,Design Model:192800 | BS UC | UC203X203X46 | 1\BS UC\UC203X203X46 | 0 | 6.46778 | 0.00587 | 0.005784 | 7.80273 | 7.8143 | 0 | 0.037966 | 0.037409 | 0.037966 | 0.037409 | 46.100000 | 298.164608 | 298.032018 | 293.657497 | 298.032018 | 293.657497 | MZ | retained beam | existing internal beam | intumescent paint | Construction Phase - Phase: Existing to Remain
4F | 1F | internal beam :5 ,SHE-13.STEEL.dgn,Design Model:105049 | BS UC | UC203X203X46 | 1\BS UC\UC203X203X46 | 0 | 2.3816 | 0.00587 | 0.005784 | 2.87316 | 2.88473 | 0 | 0.01398 | 0.013775 | 0.01398 | 0.013775 | 46.100000 | 109.791760 | 109.742937 | 108.132128 | 109.742937 | 108.132128 | 4F | UC203a - pink | internal beam | intumescent paint | FD60 | Identification - ID | Notes: supported via bracket
4F | 1F | internal beam :5 ,SHE-13.STEEL.dgn,Design Model:105052 | BS UC | UC305X305X158 | 1\BS UC\UC305X305X158 | 0.015 | 8.21635 | 0.0201 | 0.019938 | 15.3432 | 15.3831 | 0 | 0.165149 | 0.163819 | 0.165149 | 0.163819 | 158.100000 | 1299.004935 | 1296.416785 | 1285.979662 | 1296.416785 | 1285.979662 | 4F | UC305d - turquoise | internal beam | intumescent paint | FD60 | Identification - ID | Notes: supported via bracket , PRE-CAMBER
4F | 1F | internal beam :5 ,SHE-13.STEEL.dgn,Design Model:105055 | BS UC | UC305X305X240 | 1\BS UC\UC305X305X240 | 0.015 | 8.6109 | 0.0306 | 0.030381 | 16.6414 | 16.7022 | 0 | 0.263494 | 0.261605 | 0.263494 | 0.261605 | 240.000000 | 2066.616000 | 2068.424289 | 2053.597878 | 2068.424289 | 2053.597878 | 4F | UC305f - blue | internal beam | intumescent paint | FD60 | Identification - ID | Notes: supported via bracket , PRE-CAMBER
4F | 1F | internal beam :5 ,SHE-13.STEEL.dgn,Design Model:105063 | BS UC | UC305X305X240 | 1\BS UC\UC305X305X240 | 0 | 8.42545 | 0.0306 | 0.030381 | 16.283 | 16.3438 | 0 | 0.257819 | 0.255971 | 0.257819 | 0.255971 | 240.000000 | 2022.108000 | 2023.877344 | 2009.370245 | 2023.877344 | 2009.370245 | 4F | UC305f - blue | internal beam | intumescent paint | FD60 | Identification - ID | Notes: supported via bracket
4F | 1F | internal beam :5 ,SHE-13.STEEL.dgn,Design Model:105065 | BS UC | UC305X305X240 | 1\BS UC\UC305X305X240 | 0 | 5.70725 | 0.0306 | 0.030381 | 11.0298 | 11.0906 | 0 | 0.174642 | 0.17339 | 0.174642 | 0.17339 | 240.000000 | 1369.740000 | 1370.938522 | 1361.111671 | 1370.938522 | 1361.111671 | 4F | UC305f - blue | internal beam | intumescent paint | FD120
4F | 1F | internal beam :5 ,SHE-13.STEEL.dgn,Design Model:105067 | BS UC | UC305X305X240 | 1\BS UC\UC305X305X240 | 0 | 8.435 | 0.0306 | 0.030381 | 16.3015 | 16.3622 | 0 | 0.258111 | 0.256261 | 0.258111 | 0.256261 | 240.000000 | 2024.400000 | 2026.171350 | 2011.647807 | 2026.171350 | 2011.647807 | 4F | UC305f - blue | internal beam | intumescent paint | FD60 | Identification - ID | Notes: supported via bracket
4F | 1F | internal beam :5 ,SHE-13.STEEL.dgn,Design Model:105069 | BS UC | UC305X305X240 | 1\BS UC\UC305X305X240 | 0 | 8.42545 | 0.0306 | 0.030381 | 16.283 | 16.3438 | 0 | 0.257819 | 0.255971 | 0.257819 | 0.255971 | 240.000000 | 2022.108000 | 2023.877344 | 2009.370245 | 2023.877344 | 2009.370245 | 4F | UC305f - blue | internal beam | intumescent paint | FD60 | Identification - ID | Notes: supported via bracket
4F | 1F | internal beam :5 ,SHE-13.STEEL.dgn,Design Model:105071 | BS UC | UC305X305X240 | 1\BS UC\UC305X305X240 | 0 | 8.61545 | 0.0306 | 0.030381 | 16.6502 | 16.711 | 0 | 0.263633 | 0.261743 | 0.263633 | 0.261743 | 240.000000 | 2067.708000 | 2069.517244 | 2054.682999 | 2069.517244 | 2054.682999 | 4F | UC305f - blue | internal beam | intumescent paint | FD120
4F | 1F | internal beam :5 ,SHE-13.STEEL.dgn,Design Model:105073 | BS UC | UC305X305X240 | 1\BS UC\UC305X305X240 | 0 | 8.41 | 0.0306 | 0.030381 | 16.2532 | 16.3139 | 0 | 0.257346 | 0.255501 | 0.257346 | 0.255501 | 240.000000 | 2018.400000 | 2020.166100 | 2005.685602 | 2020.166100 | 2005.685602 | 4F | UC305f - blue | internal beam | intumescent paint | FD60 | Identification - ID | Notes: supported via bracket
4F | 1F | internal beam :5 ,SHE-13.STEEL.dgn,Design Model:105076 | BS UC | UC203X203X86 | 1\BS UC\UC203X203X86 | 0 | 5.4208 | 0.011 | 0.010874 | 6.80527 | 6.82702 | 0 | 0.059629 | 0.058948 | 0.059629 | 0.058948 | 86.100000 | 466.730880 | 468.086080 | 462.738835 | 468.086080 | 462.738835 | 4F | UC203e - green | internal beam | intumescent paint | FD60 | Identification - ID | Notes: supported via bracket
4F | 1F | internal beam :5 ,SHE-13.STEEL.dgn,Design Model:105078 | BS UC | UC203X203X86 | 1\BS UC\UC203X203X86 | 0 | 5.1096 | 0.011 | 0.010874 | 6.41459 | 6.43634 | 0 | 0.056206 | 0.055564 | 0.056206 | 0.055564 | 86.100000 | 439.936560 | 441.213960 | 436.173692 | 441.213960 | 436.173692 | 4F | UC203e - green | internal beam | intumescent paint | FD60
4F | 1F | internal beam :5 ,SHE-13.STEEL.dgn,Design Model:105080 | BS UC | UC203X203X86 | 1\BS UC\UC203X203X86 | 0 | 5.7392 | 0.011 | 0.010874 | 7.20499 | 7.22674 | 0 | 0.063131 | 0.06241 | 0.063131 | 0.06241 | 86.100000 | 494.145120 | 495.579920 | 489.918595 | 495.579920 | 489.918595 | 4F | UC203e - green | internal beam | intumescent paint | FD60
4F | 1F | internal beam :5 ,SHE-13.STEEL.dgn,Design Model:105082 | BS UC | UC203X203X86 | 1\BS UC\UC203X203X86 | 0 | 5.1024 | 0.011 | 0.010874 | 6.40555 | 6.4273 | 0 | 0.056126 | 0.055485 | 0.056126 | 0.055485 | 86.100000 | 439.316640 | 440.592240 | 435.559074 | 440.592240 | 435.559074 | 4F | UC203e - green | internal beam | intumescent paint | FD60
4F | 1F | internal beam :5 ,SHE-13.STEEL.dgn,Design Model:105084 | BS UC | UC203X203X86 | 1\BS UC\UC203X203X86 | 0 | 5.505 | 0.011 | 0.010874 | 6.91098 | 6.93273 | 0 | 0.060555 | 0.059863 | 0.060555 | 0.059863 | 86.100000 | 473.980500 | 475.356750 | 469.926447 | 475.356750 | 469.926447 | 4F | UC203e - green | internal beam | intumescent paint | FD60
4F | 1F | internal beam :5 ,SHE-13.STEEL.dgn,Design Model:105086 | BS UC | UC203X203X86 | 1\BS UC\UC203X203X86 | 0 | 5.1096 | 0.011 | 0.010874 | 6.41459 | 6.43634 | 0 | 0.056206 | 0.055564 | 0.056206 | 0.055564 | 86.100000 | 439.936560 | 441.213960 | 436.173692 | 441.213960 | 436.173692 | 4F | UC203e - green | internal beam | intumescent paint | FD60
4F | 1F | internal beam :5 ,SHE-13.STEEL.dgn,Design Model:105088 | BS UC | UC203X203X86 | 1\BS UC\UC203X203X86 | 0 | 5.4208 | 0.011 | 0.010874 | 6.80527 | 6.82702 | 0 | 0.059629 | 0.058948 | 0.059629 | 0.058948 | 86.100000 | 466.730880 | 468.086080 | 462.738835 | 468.086080 | 462.738835 | 4F | UC203e - green | internal beam | intumescent paint | FD60 | Identification - ID | Notes: supported via bracket
4F | 1F | internal beam :5 ,SHE-13.STEEL.dgn,Design Model:105090 | BS UC | UC203X203X86 | 1\BS UC\UC203X203X86 | 0 | 5.4208 | 0.011 | 0.010874 | 6.80527 | 6.82702 | 0 | 0.059629 | 0.058948 | 0.059629 | 0.058948 | 86.100000 | 466.730880 | 468.086080 | 462.738835 | 468.086080 | 462.738835 | 4F | UC203e - green | internal beam | intumescent paint | FD60 | Identification - ID | Notes: supported via bracket
4F | 1F | internal beam :5 ,SHE-13.STEEL.dgn,Design Model:105092 | BS UC | UC203X203X86 | 1\BS UC\UC203X203X86 | 0 | 5.1096 | 0.011 | 0.010874 | 6.41459 | 6.43634 | 0 | 0.056206 | 0.055564 | 0.056206 | 0.055564 | 86.100000 | 439.936560 | 441.213960 | 436.173692 | 441.213960 | 436.173692 | 4F | UC203e - green | internal beam | intumescent paint | FD60
4F | 1F | internal beam :5 ,SHE-13.STEEL.dgn,Design Model:105094 | BS UC | UC203X203X86 | 1\BS UC\UC203X203X86 | 0 | 5.7392 | 0.011 | 0.010874 | 7.20499 | 7.22674 | 0 | 0.063131 | 0.06241 | 0.063131 | 0.06241 | 86.100000 | 494.145120 | 495.579920 | 489.918595 | 495.579920 | 489.918595 | 4F | UC203e - green | internal beam | intumescent paint | FD60
4F | 1F | internal beam :5 ,SHE-13.STEEL.dgn,Design Model:105096 | BS UC | UC203X203X86 | 1\BS UC\UC203X203X86 | 0 | 5.1024 | 0.011 | 0.010874 | 6.40555 | 6.4273 | 0 | 0.056126 | 0.055485 | 0.056126 | 0.055485 | 86.100000 | 439.316634 | 440.592234 | 435.559069 | 440.592234 | 435.559069 | 4F | UC203e - green | internal beam | intumescent paint | FD60
4F | 1F | internal beam :5 ,SHE-13.STEEL.dgn,Design Model:105098 | BS UC | UC203X203X86 | 1\BS UC\UC203X203X86 | 0 | 5.58 | 0.011 | 0.010874 | 7.00513 | 7.02688 | 0 | 0.06138 | 0.060679 | 0.06138 | 0.060679 | 86.100000 | 480.438000 | 481.833000 | 476.328715 | 481.833000 | 476.328715 | 4F | UC203e - green | internal beam | intumescent paint | FD60
4F | 1F | internal beam :5 ,SHE-13.STEEL.dgn,Design Model:105100 | BS UC | UC203X203X86 | 1\BS UC\UC203X203X86 | 0 | 5.1096 | 0.011 | 0.010874 | 6.41459 | 6.43634 | 0 | 0.056206 | 0.055564 | 0.056206 | 0.055564 | 86.100000 | 439.936560 | 441.213960 | 436.173692 | 441.213960 | 436.173692 | 4F | UC203e - green | internal beam | intumescent paint | FD60
4F | 1F | internal beam :5 ,SHE-13.STEEL.dgn,Design Model:105102 | BS UC | UC203X203X86 | 1\BS UC\UC203X203X86 | 0 | 5.4208 | 0.011 | 0.010874 | 6.80527 | 6.82702 | 0 | 0.059629 | 0.058948 | 0.059629 | 0.058948 | 86.100000 | 466.730880 | 468.086080 | 462.738835 | 468.086080 | 462.738835 | 4F | UC203e - green | internal beam | intumescent paint | FD60 | Identification - ID | Notes: supported via bracket
4F | 1F | internal beam :5 ,SHE-13.STEEL.dgn,Design Model:105104 | BS UC | UC203X203X46 | 1\BS UC\UC203X203X46 | 0 | 2.3816 | 0.00587 | 0.005784 | 2.87316 | 2.88473 | 0 | 0.01398 | 0.013775 | 0.01398 | 0.013775 | 46.100000 | 109.791760 | 109.742937 | 108.132128 | 109.742937 | 108.132128 | 4F | UC203a - pink | internal beam | intumescent paint | FD60
4F | 1F | internal beam :5 ,SHE-13.STEEL.dgn,Design Model:105106 | BS UC | UC203X203X46 | 1\BS UC\UC203X203X46 | 0 | 2.3816 | 0.00587 | 0.005784 | 2.87316 | 2.88473 | 0 | 0.01398 | 0.013775 | 0.01398 | 0.013775 | 46.100000 | 109.791763 | 109.742940 | 108.132131 | 109.742940 | 108.132131 | 4F | UC203a - pink | internal beam | intumescent paint | FD120
4F | 1F | internal beam :5 ,SHE-13.STEEL.dgn,Design Model:105108 | BS UC | UC203X203X46 | 1\BS UC\UC203X203X46 | 0 | 2.3816 | 0.00587 | 0.005784 | 2.87316 | 2.88473 | 0 | 0.01398 | 0.013775 | 0.01398 | 0.013775 | 46.100000 | 109.791763 | 109.742940 | 108.132131 | 109.742940 | 108.132131 | 4F | UC203a - pink | internal beam | intumescent paint | FD120
4F | 1F | internal beam :5 ,SHE-13.STEEL.dgn,Design Model:105110 | BS UC | UC203X203X46 | 1\BS UC\UC203X203X46 | 0 | 1.9664 | 0.00587 | 0.005784 | 2.37227 | 2.38383 | 0 | 0.011543 | 0.011373 | 0.011543 | 0.011373 | 46.100000 | 90.651040 | 90.610729 | 89.280742 | 90.610729 | 89.280742 | 4F | UC203a - pink | internal beam | intumescent paint | FD60
4F | 1F | internal beam :5 ,SHE-13.STEEL.dgn,Design Model:105112 | BS UC | UC203X203X46 | 1\BS UC\UC203X203X46 | 0 | 2.3816 | 0.00587 | 0.005784 | 2.87316 | 2.88473 | 0 | 0.01398 | 0.013775 | 0.01398 | 0.013775 | 46.100000 | 109.791760 | 109.742937 | 108.132128 | 109.742937 | 108.132128 | 4F | UC203a - pink | internal beam | intumescent paint | FD60
4F | 1F | internal beam :5 ,SHE-13.STEEL.dgn,Design Model:105114 | BS UC | UC203X203X46 | 1\BS UC\UC203X203X46 | 0 | 2.3816 | 0.00587 | 0.005784 | 2.87316 | 2.88473 | 0 | 0.01398 | 0.013775 | 0.01398 | 0.013775 | 46.100000 | 109.791760 | 109.742937 | 108.132128 | 109.742937 | 108.132128 | 4F | UC203a - pink | internal beam | intumescent paint | FD60 | Identification - ID | Notes: supported via bracket
4F | 1F | internal beam :5 ,SHE-13.STEEL.dgn,Design Model:105116 | BS UC | UC203X203X46 | 1\BS UC\UC203X203X46 | 0 | 4.2009 | 0.00587 | 0.005784 | 5.06797 | 5.07953 | 0 | 0.024659 | 0.024297 | 0.024659 | 0.024297 | 46.100000 | 193.661490 | 193.575372 | 190.734068 | 193.575372 | 190.734068 | 4F | UC203a - pink | internal beam | intumescent paint | FD60
4F | 1F | internal beam :5 ,SHE-13.STEEL.dgn,Design Model:105118 | BS UC | UC203X203X46 | 1\BS UC\UC203X203X46 | 0 | 4.2009 | 0.00587 | 0.005784 | 5.06797 | 5.07953 | 0 | 0.024659 | 0.024297 | 0.024659 | 0.024297 | 46.100000 | 193.661490 | 193.575372 | 190.734068 | 193.575372 | 190.734068 | 4F | UC203a - pink | internal beam | intumescent paint | FD60
4F | 1F | internal beam :5 ,SHE-13.STEEL.dgn,Design Model:105120 | BS UC | UC203X203X46 | 1\BS UC\UC203X203X46 | 0 | 0.6764 | 0.00587 | 0.005784 | 0.816009 | 0.827577 | 0 | 0.00397 | 0.003912 | 0.00397 | 0.003912 | 46.100000 | 31.182040 | 31.168174 | 30.710687 | 31.168174 | 30.710687 | 4F | UC203a - pink | internal beam | intumescent paint | FD60
4F | 1F | internal beam :5 ,SHE-13.STEEL.dgn,Design Model:105122 | BS UC | UC203X203X46 | 1\BS UC\UC203X203X46 | 0 | 0.7764 | 0.00587 | 0.005784 | 0.936649 | 0.948217 | 0 | 0.004557 | 0.004491 | 0.004557 | 0.004491 | 46.100000 | 35.792040 | 35.776124 | 35.251001 | 35.776124 | 35.251001 | 4F | UC203a - pink | internal beam | intumescent paint | FD60
4F | 1F | internal beam :5 ,SHE-13.STEEL.dgn,Design Model:105124 | BS UC | UC203X203X46 | 1\BS UC\UC203X203X46 | 0 | 4.2009 | 0.00587 | 0.005784 | 5.06797 | 5.07953 | 0 | 0.024659 | 0.024297 | 0.024659 | 0.024297 | 46.100000 | 193.661490 | 193.575372 | 190.734068 | 193.575372 | 190.734068 | 4F | UC203a - pink | internal beam | intumescent paint | FD60
4F | 1F | internal beam :5 ,SHE-13.STEEL.dgn,Design Model:105126 | BS UC | UC203X203X46 | 1\BS UC\UC203X203X46 | 0 | 4.2009 | 0.00587 | 0.005784 | 5.06797 | 5.07953 | 0 | 0.024659 | 0.024297 | 0.024659 | 0.024297 | 46.100000 | 193.661490 | 193.575372 | 190.734068 | 193.575372 | 190.734068 | 4F | UC203a - pink | internal beam | intumescent paint | FD60
4F | 1F | internal beam :5 ,SHE-13.STEEL.dgn,Design Model:105252 | BS UC | UC305X305X240 | 1\BS UC\UC305X305X240 | 0.015 | 8.6109 | 0.0306 | 0.030381 | 16.6414 | 16.7022 | 0 | 0.263494 | 0.261605 | 0.263494 | 0.261605 | 240.000000 | 2066.616000 | 2068.424289 | 2053.597878 | 2068.424289 | 2053.597878 | 4F | UC305f - blue | internal beam | intumescent paint | FD60 | Identification - ID | Notes: supported via bracket , PRE-CAMBER
4F | 1F | internal beam :5 ,SHE-13.STEEL.dgn,Design Model:105254 | BS UC | UC305X305X158 | 1\BS UC\UC305X305X158 | 0.015 | 8.19635 | 0.0201 | 0.019938 | 15.3059 | 15.3457 | 0 | 0.164747 | 0.16342 | 0.164747 | 0.16342 | 158.100000 | 1295.842935 | 1293.261085 | 1282.849368 | 1293.261085 | 1282.849368 | 4F | UC305d - turquoise | internal beam | intumescent paint | FD60 | Identification - ID | Notes: supported via bracket , PRE-CAMBER
4F | 1F | internal beam :5 ,SHE-13.STEEL.dgn,Design Model:105258 | BS UC | UC305X305X158 | 1\BS UC\UC305X305X158 | 0.015 | 8.21635 | 0.0201 | 0.019938 | 15.3432 | 15.3831 | 0 | 0.165149 | 0.163819 | 0.165149 | 0.163819 | 158.100000 | 1299.004935 | 1296.416785 | 1285.979662 | 1296.416785 | 1285.979662 | 4F | UC305d - turquoise | internal beam | intumescent paint | FD60 | Identification - ID | Notes: supported via bracket , PRE-CAMBER
4F | 1F | internal beam :5 ,SHE-13.STEEL.dgn,Design Model:105264 | BS UC | UC305X305X158 | 1\BS UC\UC305X305X158 | 0.015 | 8.19635 | 0.0201 | 0.019938 | 15.3059 | 15.3457 | 0 | 0.164747 | 0.16342 | 0.164747 | 0.16342 | 158.100000 | 1295.842935 | 1293.261085 | 1282.849368 | 1293.261085 | 1282.849368 | 4F | UC305d - turquoise | internal beam | intumescent paint | FD60 | Identification - ID | Notes: supported via bracket , PRE-CAMBER
5F | 1F | internal beam :5 ,SHE-13.STEEL.dgn,Design Model:105389 | BS UC | UC203X203X46 | 1\BS UC\UC203X203X46 | 0 | 2.4348 | 0.00587 | 0.005784 | 2.93734 | 2.94891 | 0 | 0.014292 | 0.014082 | 0.014292 | 0.014082 | 46.100000 | 112.244283 | 112.194370 | 110.547578 | 112.194370 | 110.547578 | 5F | UC203a - pink | internal beam | intumescent paint | FD60
5F | 1F | internal beam :5 ,SHE-13.STEEL.dgn,Design Model:105391 | BS UC | UC203X203X46 | 1\BS UC\UC203X203X46 | 0 | 3.5036 | 0.00587 | 0.005784 | 4.22674 | 4.23831 | 0 | 0.020566 | 0.020264 | 0.020566 | 0.020264 | 46.100000 | 161.515960 | 161.444136 | 159.074455 | 161.444136 | 159.074455 | 5F | UC203a - pink | internal beam | intumescent paint | FD60
5F | 1F | internal beam :5 ,SHE-13.STEEL.dgn,Design Model:105393 | BS UC | UC203X203X46 | 1\BS UC\UC203X203X46 | 0 | 8.3836 | 0.00587 | 0.005784 | 10.114 | 10.1255 | 0 | 0.049212 | 0.048489 | 0.049212 | 0.048489 | 46.100000 | 386.483960 | 386.312096 | 380.641798 | 386.312096 | 380.641798 | 5F | UC203a - pink | internal beam | intumescent paint | FD60
5F | 1F | internal beam :5 ,SHE-13.STEEL.dgn,Design Model:105395 | BS UC | UC203X203X46 | 1\BS UC\UC203X203X46 | 0 | 8.3936 | 0.00587 | 0.005784 | 10.126 | 10.1376 | 0 | 0.04927 | 0.048547 | 0.04927 | 0.048547 | 46.100000 | 386.944960 | 386.772891 | 381.095829 | 386.772891 | 381.095829 | 5F | UC203a - pink | internal beam | intumescent paint | FD60
5F | 1F | internal beam :5 ,SHE-13.STEEL.dgn,Design Model:105397 | BS UC | UC203X203X46 | 1\BS UC\UC203X203X46 | 0 | 3.4636 | 0.00587 | 0.005784 | 4.17849 | 4.19006 | 0 | 0.020331 | 0.020033 | 0.020331 | 0.020033 | 46.100000 | 159.671960 | 159.600956 | 157.258330 | 159.600956 | 157.258330 | 5F | UC203a - pink | internal beam | intumescent paint | FD60
5F | 1F | internal beam :5 ,SHE-13.STEEL.dgn,Design Model:105399 | BS UC | UC203X203X71 | 1\BS UC\UC203X203X71 | 0 | 4.66557 | 0.00904 | 0.008953 | 5.77225 | 5.79015 | 0 | 0.042177 | 0.041773 | 0.042177 | 0.041773 | 71.000000 | 331.255712 | 331.087752 | 327.917513 | 331.087752 | 327.917513 | 5F | UC203d - black | internal beam | intumescent paint | FD60
5F | 1F | internal beam :5 ,SHE-13.STEEL.dgn,Design Model:105401 | BS UC | UC203X203X71 | 1\BS UC\UC203X203X71 | 0 | 4.66557 | 0.00904 | 0.008953 | 5.77225 | 5.79015 | 0 | 0.042177 | 0.041773 | 0.042177 | 0.041773 | 71.000000 | 331.255712 | 331.087752 | 327.917513 | 331.087752 | 327.917513 | 5F | UC203d - black | internal beam | intumescent paint | FD60
5F | 1F | internal beam :5 ,SHE-13.STEEL.dgn,Design Model:105403 | BS UC | UC203X203X71 | 1\BS UC\UC203X203X71 | 0 | 4.86615 | 0.00904 | 0.008953 | 6.02039 | 6.0383 | 0 | 0.04399 | 0.043569 | 0.04399 | 0.043569 | 71.000000 | 345.496319 | 345.321138 | 342.014612 | 345.321138 | 342.014612 | 5F | UC203d - black | internal beam | intumescent paint | FD60
5F | 1F | internal beam :5 ,SHE-13.STEEL.dgn,Design Model:105405 | BS UC | UC203X203X71 | 1\BS UC\UC203X203X71 | 0 | 4.6839 | 0.00904 | 0.008953 | 5.79492 | 5.81283 | 0 | 0.042342 | 0.041937 | 0.042342 | 0.041937 | 71.000000 | 332.556900 | 332.388280 | 329.205588 | 332.388280 | 329.205588 | 5F | UC203d - black | internal beam | intumescent paint | FD60
5F | 1F | internal beam :5 ,SHE-13.STEEL.dgn,Design Model:105407 | BS UC | UC203X203X71 | 1\BS UC\UC203X203X71 | 0 | 4.90545 | 0.00904 | 0.008953 | 6.06902 | 6.08692 | 0 | 0.044345 | 0.043921 | 0.044345 | 0.043921 | 71.000000 | 348.286619 | 348.110023 | 344.776793 | 348.110023 | 344.776793 | 5F | UC203d - black | internal beam | intumescent paint | FD60
5F | 1F | internal beam :5 ,SHE-13.STEEL.dgn,Design Model:105409 | BS UC | UC203X203X71 | 1\BS UC\UC203X203X71 | 0 | 4.66557 | 0.00904 | 0.008953 | 5.77225 | 5.79015 | 0 | 0.042177 | 0.041773 | 0.042177 | 0.041773 | 71.000000 | 331.255712 | 331.087752 | 327.917513 | 331.087752 | 327.917513 | 5F | UC203d - black | internal beam | intumescent paint | FD60
5F | 1F | internal beam :5 ,SHE-13.STEEL.dgn,Design Model:105411 | BS UC | UC203X203X71 | 1\BS UC\UC203X203X71 | 0 | 4.66557 | 0.00904 | 0.008953 | 5.77225 | 5.79015 | 0 | 0.042177 | 0.041773 | 0.042177 | 0.041773 | 71.000000 | 331.255712 | 331.087752 | 327.917513 | 331.087752 | 327.917513 | 5F | UC203d - black | internal beam | intumescent paint | FD60
5F | 1F | internal beam :5 ,SHE-13.STEEL.dgn,Design Model:105413 | BS UC | UC203X203X46 | 1\BS UC\UC203X203X46 | 0 | 3.50225 | 0.00587 | 0.005784 | 4.22511 | 4.23668 | 0 | 0.020558 | 0.020256 | 0.020558 | 0.020256 | 46.100000 | 161.453725 | 161.381929 | 159.013161 | 161.381929 | 159.013161 | 5F | UC203a - pink | internal beam | intumescent paint | FD60
5F | 1F | internal beam :5 ,SHE-13.STEEL.dgn,Design Model:105415 | BS UC | UC203X203X46 | 1\BS UC\UC203X203X46 | 0 | 8.3836 | 0.00587 | 0.005784 | 10.114 | 10.1255 | 0 | 0.049212 | 0.048489 | 0.049212 | 0.048489 | 46.100000 | 386.483960 | 386.312096 | 380.641798 | 386.312096 | 380.641798 | 5F | UC203a - pink | internal beam | intumescent paint | FD60
5F | 1F | internal beam :5 ,SHE-13.STEEL.dgn,Design Model:105417 | BS UC | UC203X203X46 | 1\BS UC\UC203X203X46 | 0 | 8.38225 | 0.00587 | 0.005784 | 10.1123 | 10.1239 | 0 | 0.049204 | 0.048482 | 0.049204 | 0.048482 | 46.100000 | 386.421725 | 386.249889 | 380.580504 | 386.249889 | 380.580504 | 5F | UC203a - pink | internal beam | intumescent paint | FD60
5F | 1F | internal beam :5 ,SHE-13.STEEL.dgn,Design Model:105419 | BS UC | UC203X203X46 | 1\BS UC\UC203X203X46 | 0 | 3.47225 | 0.00587 | 0.005784 | 4.18892 | 4.20049 | 0 | 0.020382 | 0.020083 | 0.020382 | 0.020083 | 46.100000 | 160.070725 | 159.999544 | 157.651067 | 159.999544 | 157.651067 | 5F | UC203a - pink | internal beam | intumescent paint | FD60
5F | 1F | internal beam :5 ,SHE-13.STEEL.dgn,Design Model:105421 | BS UC | UC203X203X71 | 1\BS UC\UC203X203X71 | 0 | 4.66557 | 0.00904 | 0.008953 | 5.77225 | 5.79015 | 0 | 0.042177 | 0.041773 | 0.042177 | 0.041773 | 71.000000 | 331.255712 | 331.087752 | 327.917513 | 331.087752 | 327.917513 | 5F | UC203d - black | internal beam | intumescent paint | FD60
5F | 1F | internal beam :5 ,SHE-13.STEEL.dgn,Design Model:105423 | BS UC | UC203X203X71 | 1\BS UC\UC203X203X71 | 0 | 4.66557 | 0.00904 | 0.008953 | 5.77225 | 5.79015 | 0 | 0.042177 | 0.041773 | 0.042177 | 0.041773 | 71.000000 | 331.255712 | 331.087752 | 327.917513 | 331.087752 | 327.917513 | 5F | UC203d - black | internal beam | intumescent paint | FD60
5F | 1F | internal beam :5 ,SHE-13.STEEL.dgn,Design Model:105425 | BS UC | UC203X203X71 | 1\BS UC\UC203X203X71 | 0 | 4.98031 | 0.00904 | 0.008953 | 6.16164 | 6.17955 | 0 | 0.045022 | 0.044591 | 0.045022 | 0.044591 | 71.000000 | 353.602046 | 353.422755 | 350.038654 | 353.422755 | 350.038654 | 5F | UC203d - black | internal beam | intumescent paint | FD60
5F | 1F | internal beam :5 ,SHE-13.STEEL.dgn,Design Model:105427 | BS UC | UC203X203X71 | 1\BS UC\UC203X203X71 | 0 | 4.7982 | 0.00904 | 0.008953 | 5.93633 | 5.95424 | 0 | 0.043376 | 0.04296 | 0.043376 | 0.04296 | 71.000000 | 340.672200 | 340.499465 | 337.239107 | 340.499465 | 337.239107 | 5F | UC203d - black | internal beam | intumescent paint | FD60
5F | 1F | internal beam :5 ,SHE-13.STEEL.dgn,Design Model:105429 | BS UC | UC203X203X71 | 1\BS UC\UC203X203X71 | 0 | 4.98031 | 0.00904 | 0.008953 | 6.16164 | 6.17955 | 0 | 0.045022 | 0.044591 | 0.045022 | 0.044591 | 71.000000 | 353.602046 | 353.422755 | 350.038654 | 353.422755 | 350.038654 | 5F | UC203d - black | internal beam | intumescent paint | FD60
5F | 1F | internal beam :5 ,SHE-13.STEEL.dgn,Design Model:105431 | BS UC | UC203X203X71 | 1\BS UC\UC203X203X71 | 0 | 4.66557 | 0.00904 | 0.008953 | 5.77225 | 5.79015 | 0 | 0.042177 | 0.041773 | 0.042177 | 0.041773 | 71.000000 | 331.255712 | 331.087752 | 327.917513 | 331.087752 | 327.917513 | 5F | UC203d - black | internal beam | intumescent paint | FD60
5F | 1F | internal beam :5 ,SHE-13.STEEL.dgn,Design Model:105433 | BS UC | UC203X203X71 | 1\BS UC\UC203X203X71 | 0 | 4.66557 | 0.00904 | 0.008953 | 5.77225 | 5.79015 | 0 | 0.042177 | 0.041773 | 0.042177 | 0.041773 | 71.000000 | 331.255712 | 331.087752 | 327.917513 | 331.087752 | 327.917513 | 5F | UC203d - black | internal beam | intumescent paint | FD60
5F | 1F | internal beam :5 ,SHE-13.STEEL.dgn,Design Model:105435 | BS UC | UC203X203X46 | 1\BS UC\UC203X203X46 | 0 | 1.08477 | 0.00587 | 0.005784 | 1.30867 | 1.32024 | 0 | 0.006368 | 0.006274 | 0.006368 | 0.006274 | 46.100000 | 50.008057 | 49.985819 | 49.252126 | 49.985819 | 49.252126 | 5F | UC203a - pink | internal beam | intumescent paint | FD60
5F | 1F | internal beam :5 ,SHE-13.STEEL.dgn,Design Model:105437 | BS UC | UC203X203X46 | 1\BS UC\UC203X203X46 | 0 | 1.08298 | 0.00587 | 0.005784 | 1.30651 | 1.31808 | 0 | 0.006357 | 0.006264 | 0.006357 | 0.006264 | 46.100000 | 49.925527 | 49.903326 | 49.170844 | 49.903326 | 49.170844 | 5F | UC203a - pink | internal beam | intumescent paint | FD60
5F | 1F | internal beam :5 ,SHE-13.STEEL.dgn,Design Model:105439 | BS UC | UC203X203X46 | 1\BS UC\UC203X203X46 | 0 | 1.08483 | 0.00587 | 0.005784 | 1.30873 | 1.3203 | 0 | 0.006368 | 0.006274 | 0.006368 | 0.006274 | 46.100000 | 50.010506 | 49.988267 | 49.254538 | 49.988267 | 49.254538 | 5F | UC203a - pink | internal beam | intumescent paint | FD60
5F | 1F | internal beam :5 ,SHE-13.STEEL.dgn,Design Model:105441 | BS UC | UC203X203X46 | 1\BS UC\UC203X203X46 | 0 | 1.08477 | 0.00587 | 0.005784 | 1.30867 | 1.32024 | 0 | 0.006368 | 0.006274 | 0.006368 | 0.006274 | 46.100000 | 50.008057 | 49.985819 | 49.252126 | 49.985819 | 49.252126 | 5F | UC203a - pink | internal beam | intumescent paint | FD60
5F | 1F | internal beam :5 ,SHE-13.STEEL.dgn,Design Model:105443 | BS UC | UC203X203X46 | 1\BS UC\UC203X203X46 | 0 | 2.4857 | 0.00587 | 0.005784 | 2.99875 | 3.01032 | 0 | 0.014591 | 0.014377 | 0.014591 | 0.014377 | 46.100000 | 114.590770 | 114.539813 | 112.858595 | 114.539813 | 112.858595 | 5F | UC203a - pink | internal beam | intumescent paint | FD60
5F | 1F | internal beam :5 ,SHE-13.STEEL.dgn,Design Model:105445 | BS UC | UC203X203X46 | 1\BS UC\UC203X203X46 | 0 | 2.4839 | 0.00587 | 0.005784 | 2.99658 | 3.00815 | 0 | 0.01458 | 0.014366 | 0.01458 | 0.014366 | 46.100000 | 114.507833 | 114.456913 | 112.776911 | 114.456913 | 112.776911 | 5F | UC203a - pink | internal beam | intumescent paint | FD120
5F | 1F | internal beam :5 ,SHE-13.STEEL.dgn,Design Model:105447 | BS UC | UC203X203X46 | 1\BS UC\UC203X203X46 | 0 | 2.4857 | 0.00587 | 0.005784 | 2.99875 | 3.01032 | 0 | 0.014591 | 0.014377 | 0.014591 | 0.014377 | 46.100000 | 114.590770 | 114.539813 | 112.858595 | 114.539813 | 112.858595 | 5F | UC203a - pink | internal beam | intumescent paint | FD120
5F | 1F | internal beam :5 ,SHE-13.STEEL.dgn,Design Model:105449 | BS UC | UC203X203X46 | 1\BS UC\UC203X203X46 | 0 | 2.525 | 0.00587 | 0.005784 | 3.04616 | 3.05773 | 0 | 0.014822 | 0.014604 | 0.014822 | 0.014604 | 46.100000 | 116.402500 | 116.350737 | 114.642939 | 116.350737 | 114.642939 | 5F | UC203a - pink | internal beam | intumescent paint | FD60
5F | 1F | internal beam :5 ,SHE-13.STEEL.dgn,Design Model:105451 | BS UC | UC203X203X46 | 1\BS UC\UC203X203X46 | 0 | 1.08483 | 0.00587 | 0.005784 | 1.30873 | 1.3203 | 0 | 0.006368 | 0.006274 | 0.006368 | 0.006274 | 46.100000 | 50.010506 | 49.988267 | 49.254538 | 49.988267 | 49.254538 | 5F | UC203a - pink | internal beam | intumescent paint | FD60
5F | 1F | internal beam :5 ,SHE-13.STEEL.dgn,Design Model:105453 | BS UC | UC203X203X46 | 1\BS UC\UC203X203X46 | 0 | 1.08446 | 0.00587 | 0.005784 | 1.30829 | 1.31986 | 0 | 0.006366 | 0.006272 | 0.006366 | 0.006272 | 46.100000 | 49.993466 | 49.971235 | 49.237756 | 49.971235 | 49.237756 | 5F | UC203a - pink | internal beam | intumescent paint | FD60
5F | 1F | internal beam :5 ,SHE-13.STEEL.dgn,Design Model:105455 | BS UC | UC203X203X46 | 1\BS UC\UC203X203X46 | 0 | 2.43448 | 0.00587 | 0.005784 | 2.93696 | 2.94853 | 0 | 0.01429 | 0.014081 | 0.01429 | 0.014081 | 46.100000 | 112.229692 | 112.179785 | 110.533208 | 112.179785 | 110.533208 | 5F | UC203a - pink | internal beam | intumescent paint | FD60
5F | 1F | internal beam :5 ,SHE-13.STEEL.dgn,Design Model:105457 | BS UC | UC203X203X46 | 1\BS UC\UC203X203X46 | 0 | 2.53639 | 0.00587 | 0.005784 | 3.0599 | 3.07147 | 0 | 0.014889 | 0.01467 | 0.014889 | 0.01467 | 46.100000 | 116.927702 | 116.875705 | 115.160201 | 116.875705 | 115.160201 | 5F | UC203a - pink | internal beam | intumescent paint | FD60
5F | 1F | internal beam :5 ,SHE-13.STEEL.dgn,Design Model:105459 | BS UC | UC203X203X46 | 1\BS UC\UC203X203X46 | 0 | 0.695 | 0.00587 | 0.005784 | 0.838448 | 0.850016 | 0 | 0.00408 | 0.00402 | 0.00408 | 0.00402 | 46.100000 | 32.039500 | 32.025252 | 31.555185 | 32.025252 | 31.555185 | 5F | UC203a - pink | internal beam | intumescent paint | FD60
5F | 1F | internal beam :5 ,SHE-13.STEEL.dgn,Design Model:105461 | BS UC | UC203X203X46 | 1\BS UC\UC203X203X46 | 0 | 0.695 | 0.00587 | 0.005784 | 0.838448 | 0.850016 | 0 | 0.00408 | 0.00402 | 0.00408 | 0.00402 | 46.100000 | 32.039500 | 32.025252 | 31.555185 | 32.025252 | 31.555185 | 5F | UC203a - pink | internal beam | intumescent paint | FD60
5F | 1F | internal beam :5 ,SHE-13.STEEL.dgn,Design Model:105463 | BS UC | UC203X203X46 | 1\BS UC\UC203X203X46 | 0 | 1.9682 | 0.00587 | 0.005784 | 2.37444 | 2.386 | 0 | 0.011553 | 0.011384 | 0.011553 | 0.011384 | 46.100000 | 90.734020 | 90.693672 | 89.362468 | 90.693672 | 89.362468 | 5F | UC203a - pink | internal beam | intumescent paint | FD60
5F | 1F | internal beam :5 ,SHE-13.STEEL.dgn,Design Model:105465 | BS UC | UC203X203X46 | 1\BS UC\UC203X203X46 | 0 | 1.86305 | 0.00587 | 0.005784 | 2.24758 | 2.25915 | 0 | 0.010936 | 0.010776 | 0.010936 | 0.010776 | 46.100000 | 85.886605 | 85.848412 | 84.588327 | 85.848412 | 84.588327 | 5F | UC203a - pink | internal beam | intumescent paint | FD60
5F | 1F | internal beam :5 ,SHE-13.STEEL.dgn,Design Model:105467 | BS UC | UC203X203X46 | 1\BS UC\UC203X203X46 | 0 | 2.1297 | 0.00587 | 0.005784 | 2.56927 | 2.58084 | 0 | 0.012501 | 0.012318 | 0.012501 | 0.012318 | 46.100000 | 98.179170 | 98.135511 | 96.695076 | 98.135511 | 96.695076 | 5F | UC203a - pink | internal beam | intumescent paint | FD120
5F | 1F | internal beam :5 ,SHE-13.STEEL.dgn,Design Model:105469 | BS UC | UC203X203X46 | 1\BS UC\UC203X203X46 | 0 | 4.22985 | 0.00587 | 0.005784 | 5.10289 | 5.11446 | 0 | 0.024829 | 0.024465 | 0.024829 | 0.024465 | 46.100000 | 194.996085 | 194.909373 | 192.048489 | 194.909373 | 192.048489 | 5F | UC203a - pink | internal beam | intumescent paint | FD120
5F | 1F | internal beam :5 ,SHE-13.STEEL.dgn,Design Model:105471 | BS UC | UC203X203X46 | 1\BS UC\UC203X203X46 | 0 | 4.21 | 0.00587 | 0.005784 | 5.07894 | 5.09051 | 0 | 0.024713 | 0.02435 | 0.024713 | 0.02435 | 46.100000 | 194.081000 | 193.994695 | 191.147236 | 193.994695 | 191.147236 | 5F | UC203a - pink | internal beam | intumescent paint | FD120
5F | 1F | internal beam :5 ,SHE-13.STEEL.dgn,Design Model:105473 | BS UC | UC203X203X46 | 1\BS UC\UC203X203X46 | 0 | 4.2082 | 0.00587 | 0.005784 | 5.07677 | 5.08834 | 0 | 0.024702 | 0.02434 | 0.024702 | 0.02434 | 46.100000 | 193.998020 | 193.911752 | 191.065511 | 193.911752 | 191.065511 | 5F | UC203a - pink | internal beam | intumescent paint | FD120
5F | 1F | internal beam :5 ,SHE-13.STEEL.dgn,Design Model:105477 | BS UC | UC203X203X46 | 1\BS UC\UC203X203X46 | 0 | 4.2036 | 0.00587 | 0.005784 | 5.07122 | 5.08279 | 0 | 0.024675 | 0.024313 | 0.024675 | 0.024313 | 46.100000 | 193.785960 | 193.699786 | 190.856656 | 193.699786 | 190.856656 | 5F | UC203a - pink | internal beam | intumescent paint | FD60
5F | 1F | internal beam :5 ,SHE-13.STEEL.dgn,Design Model:105479 | BS UC | UC203X203X46 | 1\BS UC\UC203X203X46 | 0 | 3.9836 | 0.00587 | 0.005784 | 4.80581 | 4.81738 | 0 | 0.023384 | 0.023041 | 0.023384 | 0.023041 | 46.100000 | 183.643960 | 183.562296 | 180.867964 | 183.562296 | 180.867964 | 5F | UC203a - pink | internal beam | intumescent paint | FD60
5F | 1F | internal beam :5 ,SHE-13.STEEL.dgn,Design Model:105481 | BS UC | UC203X203X46 | 1\BS UC\UC203X203X46 | 0 | 4.20358 | 0.00587 | 0.005784 | 5.07119 | 5.08276 | 0 | 0.024675 | 0.024313 | 0.024675 | 0.024313 | 46.100000 | 193.784852 | 193.698678 | 190.855564 | 193.698678 | 190.855564 | 5F | UC203a - pink | internal beam | intumescent paint | FD60
5F | 1F | internal beam :5 ,SHE-13.STEEL.dgn,Design Model:105483 | BS UC | UC203X203X46 | 1\BS UC\UC203X203X46 | 0 | 3.9736 | 0.00587 | 0.005784 | 4.79375 | 4.80532 | 0 | 0.023325 | 0.022983 | 0.023325 | 0.022983 | 46.100000 | 183.182960 | 183.101501 | 180.413933 | 183.101501 | 180.413933 | 5F | UC203a - pink | internal beam | intumescent paint | FD60
5F | 1F | internal beam :5 ,SHE-13.STEEL.dgn,Design Model:105485 | BS UC | UC203X203X46 | 1\BS UC\UC203X203X46 | 0 | 3.9736 | 0.00587 | 0.005784 | 4.79375 | 4.80532 | 0 | 0.023325 | 0.022983 | 0.023325 | 0.022983 | 46.100000 | 183.182960 | 183.101501 | 180.413933 | 183.101501 | 180.413933 | 5F | UC203a - pink | internal beam | intumescent paint | FD60
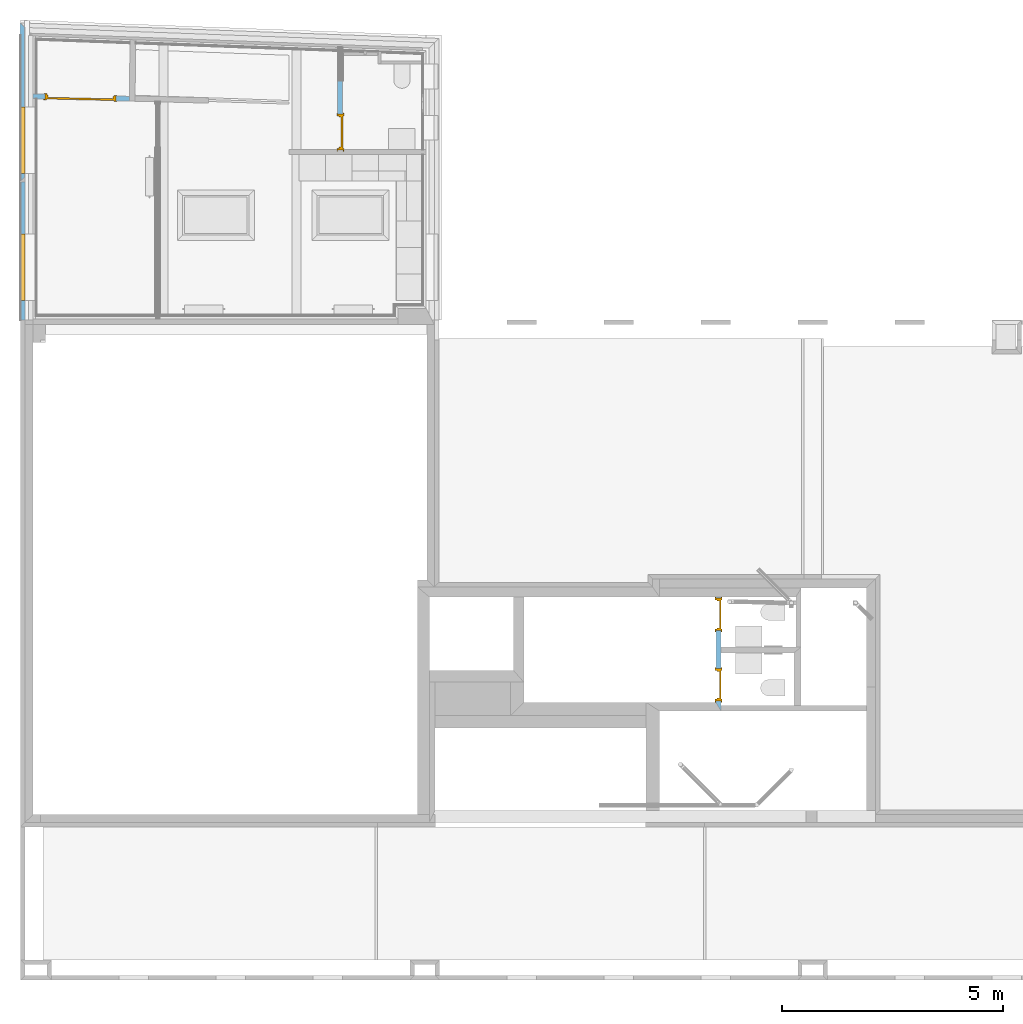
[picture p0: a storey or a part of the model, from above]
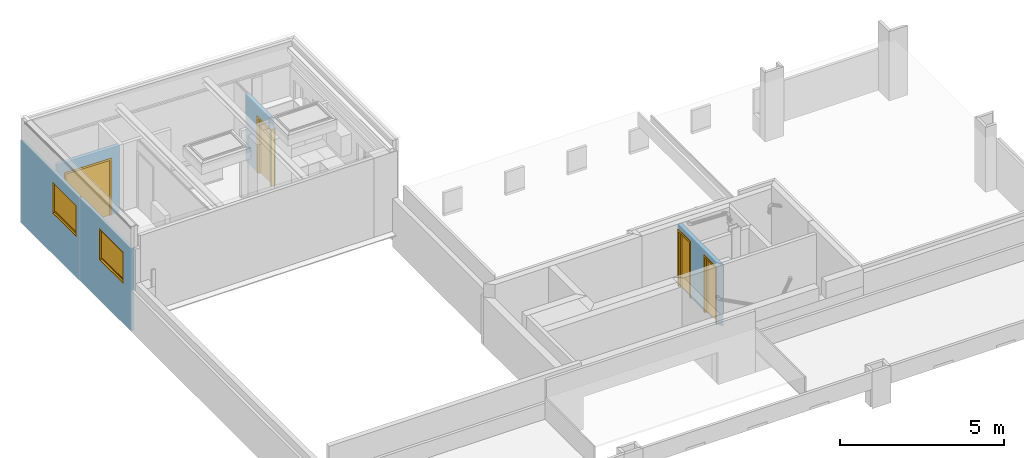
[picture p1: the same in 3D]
Properties of the parts of a building model (IFC2X3), part 2 of 17

# IfcBeam: A-Beams-Steel (244)
Name | In | Description | CodeSystem | Name = StructuralFramingCommon, Section Name | Structural Parameters, Section Name | Camber (m) | Length (m) | Area | Cross-sectional (m2) | Area | Cross-sectional Modeled (m2) | Area | Side Surfaces Modeled (Gross) (m2) | Area | All Surfaces Modeled (Net) (m2) | Volume | Perforation(s) (m3) | Volume (Gross) (m3) | Volume (Gross Modeled) (m3) | Volume (Net) (m3) | Volume (Net Modeled) (m3) | Unit Weight | Length x Unit Weight | Volume (Gross) x Density | Volume (Gross Modeled) x Density | Volume (Net) x Density | Volume (Net Modeled) x Density | ID | Number | ID | Name (Alternate) | ID | Description | ID | Keynote | FireRating = Fire | Rating
5F | 1F | internal beam :5 ,SHE-13.STEEL.dgn,Design Model:105487 | BS UC | UC203X203X46 | 1\BS UC\UC203X203X46 | 0 | 4.20358 | 0.00587 | 0.005784 | 5.07119 | 5.08276 | 0 | 0.024675 | 0.024313 | 0.024675 | 0.024313 | 46.100000 | 193.784852 | 193.698678 | 190.855564 | 193.698678 | 190.855564 | 5F | UC203a - pink | internal beam | intumescent paint | FD60
5F | 1F | internal beam :5 ,SHE-13.STEEL.dgn,Design Model:105489 | BS UC | UC203X203X46 | 1\BS UC\UC203X203X46 | 0 | 4.2036 | 0.00587 | 0.005784 | 5.07122 | 5.08279 | 0 | 0.024675 | 0.024313 | 0.024675 | 0.024313 | 46.100000 | 193.785960 | 193.699786 | 190.856656 | 193.699786 | 190.856656 | 5F | UC203a - pink | internal beam | intumescent paint | FD60
5F | 1F | internal beam :5 ,SHE-13.STEEL.dgn,Design Model:105491 | BS UC | UC203X203X46 | 1\BS UC\UC203X203X46 | 0 | 3.9836 | 0.00587 | 0.005784 | 4.80581 | 4.81738 | 0 | 0.023384 | 0.023041 | 0.023384 | 0.023041 | 46.100000 | 183.643960 | 183.562296 | 180.867964 | 183.562296 | 180.867964 | 5F | UC203a - pink | internal beam | intumescent paint | FD60
5F | 1F | internal beam :5 ,SHE-13.STEEL.dgn,Design Model:105494 | BS UC | UC254X254X167 | 1\BS UC\UC254X254X167 | 0 | 7.88305 | 0.0213 | 0.021147 | 12.6176 | 12.6599 | 0 | 0.167909 | 0.166704 | 0.167909 | 0.166704 | 167.100000 | 1317.257655 | 1318.085375 | 1308.624864 | 1318.085375 | 1308.624864 | 5F | UC254e - red | internal beam | intumescent paint | FD60
5F | 1F | internal beam :5 ,SHE-13.STEEL.dgn,Design Model:105496 | BS UC | UC254X254X167 | 1\BS UC\UC254X254X167 | 0 | 7.685 | 0.0213 | 0.021147 | 12.3006 | 12.3429 | 0 | 0.163691 | 0.162516 | 0.163691 | 0.162516 | 167.100000 | 1284.163500 | 1284.970425 | 1275.747595 | 1284.970425 | 1275.747595 | 5F | UC254e - red | internal beam | intumescent paint | FD60
5F | 1F | internal beam :5 ,SHE-13.STEEL.dgn,Design Model:105498 | BS UC | UC254X254X167 | 1\BS UC\UC254X254X167 | 0 | 7.685 | 0.0213 | 0.021147 | 12.3006 | 12.3429 | 0 | 0.16369 | 0.162516 | 0.16369 | 0.162516 | 167.100000 | 1284.163500 | 1284.970425 | 1275.747595 | 1284.970425 | 1275.747595 | 5F | UC254e - red | internal beam | intumescent paint | FD60
5F | 1F | internal beam :5 ,SHE-13.STEEL.dgn,Design Model:105500 | BS UC | UC254X254X167 | 1\BS UC\UC254X254X167 | 0 | 7.6568 | 0.0213 | 0.021147 | 12.2555 | 12.2978 | 0 | 0.16309 | 0.161919 | 0.16309 | 0.161919 | 167.100000 | 1279.451280 | 1280.255244 | 1271.066257 | 1280.255244 | 1271.066257 | 5F | UC254e - red | internal beam | intumescent paint | FD60
5F | 1F | internal beam :5 ,SHE-13.STEEL.dgn,Design Model:105502 | BS UC | UC254X254X167 | 1\BS UC\UC254X254X167 | 0 | 7.64359 | 0.0213 | 0.021147 | 12.2343 | 12.2766 | 0 | 0.162809 | 0.16164 | 0.162809 | 0.16164 | 167.100000 | 1277.244413 | 1278.046990 | 1268.873853 | 1278.046990 | 1268.873853 | 5F | UC254e - red | internal beam | intumescent paint | FD60
5F | 1F | internal beam :5 ,SHE-13.STEEL.dgn,Design Model:105504 | BS UC | UC254X254X167 | 1\BS UC\UC254X254X167 | 0 | 7.6818 | 0.0213 | 0.021147 | 12.2955 | 12.3378 | 0 | 0.163622 | 0.162448 | 0.163622 | 0.162448 | 167.100000 | 1283.628780 | 1284.435369 | 1275.216379 | 1284.435369 | 1275.216379 | 5F | UC254e - red | internal beam | intumescent paint | FD60
5F | 1F | internal beam :5 ,SHE-13.STEEL.dgn,Design Model:124955 | BS UC | UC203X203X46 | 1\BS UC\UC203X203X46 | 0 | 2.0364 | 0.00587 | 0.005784 | 2.45671 | 2.46828 | 0 | 0.011954 | 0.011778 | 0.011954 | 0.011778 | 46.100000 | 93.878040 | 93.836294 | 92.458962 | 93.836294 | 92.458962 | 5F | UC203a - pink | internal beam | intumescent paint | FD120
RP | 1F | internal beam :5 ,SHE-13.STEEL.dgn,Design Model:125220 | BS UC | UC305X305X240 | 1\BS UC\UC305X305X240 | 0 | 8.38638 | 0.0306 | 0.030381 | 16.2075 | 16.2683 | 0 | 0.256623 | 0.254784 | 0.256623 | 0.254784 | 240.000000 | 2012.730796 | 2014.491935 | 2000.052110 | 2014.491935 | 2000.052110 | RP | UC305f - blue | internal beam | intumescent paint | FD60
RP | 1F | internal beam :5 ,SHE-13.STEEL.dgn,Design Model:125222 | BS UC | UC203X203X46 | 1\BS UC\UC203X203X46 | 0 | 2.3424 | 0.00587 | 0.005784 | 2.82587 | 2.83744 | 0 | 0.01375 | 0.013548 | 0.01375 | 0.013548 | 46.100000 | 107.984640 | 107.936621 | 106.352325 | 107.936621 | 106.352325 | RP | UC203a - pink | internal beam | intumescent paint | FD60
RP | 1F | internal beam :5 ,SHE-13.STEEL.dgn,Design Model:125224 | BS UC | UC203X203X46 | 1\BS UC\UC203X203X46 | 0 | 2.546 | 0.00587 | 0.005784 | 3.07149 | 3.08306 | 0 | 0.014945 | 0.014726 | 0.014945 | 0.014726 | 46.100000 | 117.370600 | 117.318407 | 115.596405 | 117.318407 | 115.596405 | RP | UC203a - pink | internal beam | intumescent paint | FD60
RP | 1F | internal beam :5 ,SHE-13.STEEL.dgn,Design Model:125226 | BS UC | UC203X203X46 | 1\BS UC\UC203X203X46 | 0 | 2.49165 | 0.00587 | 0.005784 | 3.00593 | 3.01749 | 0 | 0.014626 | 0.014411 | 0.014626 | 0.014411 | 46.100000 | 114.865065 | 114.813986 | 113.128744 | 114.813986 | 113.128744 | RP | UC203a - pink | internal beam | intumescent paint | FD60
RP | 1F | internal beam :5 ,SHE-13.STEEL.dgn,Design Model:125228 | BS UC | UC203X203X46 | 1\BS UC\UC203X203X46 | 0 | 2.4936 | 0.00587 | 0.005784 | 3.00828 | 3.01985 | 0 | 0.014637 | 0.014423 | 0.014637 | 0.014423 | 46.100000 | 114.954960 | 114.903841 | 113.217280 | 114.903841 | 113.217280 | RP | UC203a - pink | internal beam | intumescent paint | FD60
RP | 1F | internal beam :5 ,SHE-13.STEEL.dgn,Design Model:125230 | BS UC | UC203X203X46 | 1\BS UC\UC203X203X46 | 0 | 2.546 | 0.00587 | 0.005784 | 3.07149 | 3.08306 | 0 | 0.014945 | 0.014726 | 0.014945 | 0.014726 | 46.100000 | 117.370600 | 117.318407 | 115.596405 | 117.318407 | 115.596405 | RP | UC203a - pink | internal beam | intumescent paint | FD60
RP | 1F | internal beam :5 ,SHE-13.STEEL.dgn,Design Model:125232 | BS UC | UC203X203X46 | 1\BS UC\UC203X203X46 | 0 | 2.3424 | 0.00587 | 0.005784 | 2.82587 | 2.83744 | 0 | 0.01375 | 0.013548 | 0.01375 | 0.013548 | 46.100000 | 107.984640 | 107.936621 | 106.352325 | 107.936621 | 106.352325 | RP | UC203a - pink | internal beam | intumescent paint | FD60
RP | 1F | internal beam :5 ,SHE-13.STEEL.dgn,Design Model:125234 | BS UC | UC203X203X46 | 1\BS UC\UC203X203X46 | 0 | 1.15342 | 0.00587 | 0.005784 | 1.39149 | 1.40306 | 0 | 0.006771 | 0.006671 | 0.006771 | 0.006671 | 46.100000 | 53.172740 | 53.149095 | 52.368971 | 53.149095 | 52.368971 | RP | UC203a - pink | internal beam | intumescent paint | FD60
RP | 1F | internal beam :5 ,SHE-13.STEEL.dgn,Design Model:125236 | BS UC | UC203X203X46 | 1\BS UC\UC203X203X46 | 0 | 1.15342 | 0.00587 | 0.005784 | 1.39149 | 1.40306 | 0 | 0.006771 | 0.006671 | 0.006771 | 0.006671 | 46.100000 | 53.172740 | 53.149095 | 52.368971 | 53.149095 | 52.368971 | RP | UC203a - pink | internal beam | intumescent paint | FD60
RP | 1F | internal beam :5 ,SHE-13.STEEL.dgn,Design Model:125238 | BS UC | UC203X203X46 | 1\BS UC\UC203X203X46 | 0 | 2.3176 | 0.00587 | 0.005784 | 2.79595 | 2.80752 | 0 | 0.013604 | 0.013405 | 0.013604 | 0.013405 | 46.100000 | 106.841360 | 106.793849 | 105.226327 | 106.793849 | 105.226327 | RP | UC203a - pink | internal beam | intumescent paint | FD60
RP | 1F | internal beam :5 ,SHE-13.STEEL.dgn,Design Model:125240 | BS UC | UC203X203X46 | 1\BS UC\UC203X203X46 | 0 | 2.4968 | 0.00587 | 0.005784 | 3.01214 | 3.02371 | 0 | 0.014656 | 0.014441 | 0.014656 | 0.014441 | 46.100000 | 115.102480 | 115.051296 | 113.362570 | 115.051296 | 113.362570 | RP | UC203a - pink | internal beam | intumescent paint | FD60
RP | 1F | internal beam :5 ,SHE-13.STEEL.dgn,Design Model:125242 | BS UC | UC203X203X46 | 1\BS UC\UC203X203X46 | 0 | 2.4208 | 0.00587 | 0.005784 | 2.92045 | 2.93202 | 0 | 0.01421 | 0.014002 | 0.01421 | 0.014002 | 46.100000 | 111.598880 | 111.549254 | 109.911931 | 111.549254 | 109.911931 | RP | UC203a - pink | internal beam | intumescent paint | FD60
RP | 1F | internal beam :5 ,SHE-13.STEEL.dgn,Design Model:125244 | BS UC | UC203X203X46 | 1\BS UC\UC203X203X46 | 0 | 2.4849 | 0.00587 | 0.005784 | 2.99778 | 3.00935 | 0 | 0.014586 | 0.014372 | 0.014586 | 0.014372 | 46.100000 | 114.553890 | 114.502950 | 112.822273 | 114.502950 | 112.822273 | RP | UC203a - pink | internal beam | intumescent paint | FD60
RP | 1F | internal beam :5 ,SHE-13.STEEL.dgn,Design Model:125246 | BS UC | UC203X203X46 | 1\BS UC\UC203X203X46 | 0 | 2.4857 | 0.00587 | 0.005784 | 2.99875 | 3.01032 | 0 | 0.014591 | 0.014377 | 0.014591 | 0.014377 | 46.100000 | 114.590770 | 114.539813 | 112.858595 | 114.539813 | 112.858595 | RP | UC203a - pink | internal beam | intumescent paint | FD60
RP | 1F | internal beam :5 ,SHE-13.STEEL.dgn,Design Model:125248 | BS UC | UC203X203X46 | 1\BS UC\UC203X203X46 | 0 | 2.5992 | 0.00587 | 0.005784 | 3.13567 | 3.14724 | 0 | 0.015257 | 0.015033 | 0.015257 | 0.015033 | 46.100000 | 119.823120 | 119.769836 | 118.011852 | 119.769836 | 118.011852 | RP | UC203a - pink | internal beam | intumescent paint | FD60
RP | 1F | internal beam :5 ,SHE-13.STEEL.dgn,Design Model:125250 | BS UC | UC203X203X46 | 1\BS UC\UC203X203X46 | 0 | 2.3176 | 0.00587 | 0.005784 | 2.79595 | 2.80752 | 0 | 0.013604 | 0.013405 | 0.013604 | 0.013405 | 46.100000 | 106.841360 | 106.793849 | 105.226327 | 106.793849 | 105.226327 | RP | UC203a - pink | internal beam | intumescent paint | FD60
RP | 1F | internal beam :5 ,SHE-13.STEEL.dgn,Design Model:125252 | BS UC | UC203X203X46 | 1\BS UC\UC203X203X46 | 0 | 2.495 | 0.00587 | 0.005784 | 3.00997 | 3.02154 | 0 | 0.014646 | 0.014431 | 0.014646 | 0.014431 | 46.100000 | 115.019500 | 114.968353 | 113.280844 | 114.968353 | 113.280844 | RP | UC203a - pink | internal beam | intumescent paint | FD60
RP | 1F | internal beam :5 ,SHE-13.STEEL.dgn,Design Model:125254 | BS UC | UC203X203X46 | 1\BS UC\UC203X203X46 | 0 | 2.319 | 0.00587 | 0.005784 | 2.79764 | 2.80921 | 0 | 0.013613 | 0.013413 | 0.013613 | 0.013413 | 46.100000 | 106.905900 | 106.858360 | 105.289891 | 106.858360 | 105.289891 | RP | UC203a - pink | internal beam | intumescent paint | FD60
RP | 1F | internal beam :5 ,SHE-13.STEEL.dgn,Design Model:125256 | BS UC | UC203X203X46 | 1\BS UC\UC203X203X46 | 0 | 2.546 | 0.00587 | 0.005784 | 3.07149 | 3.08306 | 0 | 0.014945 | 0.014726 | 0.014945 | 0.014726 | 46.100000 | 117.370600 | 117.318407 | 115.596405 | 117.318407 | 115.596405 | RP | UC203a - pink | internal beam | intumescent paint | FD60
RP | 1F | internal beam :5 ,SHE-13.STEEL.dgn,Design Model:125258 | BS UC | UC203X203X46 | 1\BS UC\UC203X203X46 | 0 | 2.4936 | 0.00587 | 0.005784 | 3.00828 | 3.01985 | 0 | 0.014637 | 0.014423 | 0.014637 | 0.014423 | 46.100000 | 114.954960 | 114.903841 | 113.217280 | 114.903841 | 113.217280 | RP | UC203a - pink | internal beam | intumescent paint | FD60
RP | 1F | internal beam :5 ,SHE-13.STEEL.dgn,Design Model:125260 | BS UC | UC203X203X46 | 1\BS UC\UC203X203X46 | 0 | 2.546 | 0.00587 | 0.005784 | 3.07149 | 3.08306 | 0 | 0.014945 | 0.014726 | 0.014945 | 0.014726 | 46.100000 | 117.370600 | 117.318407 | 115.596405 | 117.318407 | 115.596405 | RP | UC203a - pink | internal beam | intumescent paint | FD60
RP | 1F | internal beam :5 ,SHE-13.STEEL.dgn,Design Model:125262 | BS UC | UC203X203X46 | 1\BS UC\UC203X203X46 | 0 | 2.3424 | 0.00587 | 0.005784 | 2.82587 | 2.83744 | 0 | 0.01375 | 0.013548 | 0.01375 | 0.013548 | 46.100000 | 107.984640 | 107.936621 | 106.352325 | 107.936621 | 106.352325 | RP | UC203a - pink | internal beam | intumescent paint | FD60
RP | 1F | internal beam :5 ,SHE-13.STEEL.dgn,Design Model:125264 | BS UC | UC203X203X46 | 1\BS UC\UC203X203X46 | 0 | 2.4936 | 0.00587 | 0.005784 | 3.00828 | 3.01985 | 0 | 0.014637 | 0.014423 | 0.014637 | 0.014423 | 46.100000 | 114.954960 | 114.903841 | 113.217280 | 114.903841 | 113.217280 | RP | UC203a - pink | internal beam | intumescent paint | FD60
RP | 1F | internal beam :5 ,SHE-13.STEEL.dgn,Design Model:125266 | BS UC | UC203X203X46 | 1\BS UC\UC203X203X46 | 0 | 2.3424 | 0.00587 | 0.005784 | 2.82587 | 2.83744 | 0 | 0.01375 | 0.013548 | 0.01375 | 0.013548 | 46.100000 | 107.984640 | 107.936621 | 106.352325 | 107.936621 | 106.352325 | RP | UC203a - pink | internal beam | intumescent paint | FD60
RP | 1F | internal beam :5 ,SHE-13.STEEL.dgn,Design Model:125268 | BS UC | UC203X203X46 | 1\BS UC\UC203X203X46 | 0 | 1.13364 | 0.00587 | 0.005784 | 1.36762 | 1.37919 | 0 | 0.006654 | 0.006557 | 0.006654 | 0.006557 | 46.100000 | 52.260631 | 52.237392 | 51.470650 | 52.237392 | 51.470650 | RP | UC203a - pink | internal beam | intumescent paint | FD60
RP | 1F | internal beam :5 ,SHE-13.STEEL.dgn,Design Model:125270 | BS UC | UC203X203X46 | 1\BS UC\UC203X203X46 | 0 | 1.13364 | 0.00587 | 0.005784 | 1.36762 | 1.37919 | 0 | 0.006654 | 0.006557 | 0.006654 | 0.006557 | 46.100000 | 52.260631 | 52.237392 | 51.470650 | 52.237392 | 51.470650 | RP | UC203a - pink | internal beam | intumescent paint | FD60
RP | 1F | internal beam :5 ,SHE-13.STEEL.dgn,Design Model:125272 | BS UC | UC203X203X46 | 1\BS UC\UC203X203X46 | 0 | 2.0364 | 0.00587 | 0.005784 | 2.45671 | 2.46828 | 0 | 0.011954 | 0.011778 | 0.011954 | 0.011778 | 46.100000 | 93.878040 | 93.836294 | 92.458962 | 93.836294 | 92.458962 | RP | UC203a - pink | internal beam | intumescent paint | FD60
RP | 1F | internal beam :5 ,SHE-13.STEEL.dgn,Design Model:125274 | BS UC | UC203X203X46 | 1\BS UC\UC203X203X46 | 0 | 1.9664 | 0.00587 | 0.005784 | 2.37227 | 2.38383 | 0 | 0.011543 | 0.011373 | 0.011543 | 0.011373 | 46.100000 | 90.651040 | 90.610729 | 89.280742 | 90.610729 | 89.280742 | RP | UC203a - pink | internal beam | intumescent paint | FD60
RP | 1F | internal beam :5 ,SHE-13.STEEL.dgn,Design Model:125276 | BS UC | UC203X203X46 | 1\BS UC\UC203X203X46 | 0 | 1.9597 | 0.00587 | 0.005784 | 2.36418 | 2.37575 | 0 | 0.011503 | 0.011335 | 0.011503 | 0.011335 | 46.100000 | 90.342170 | 90.301996 | 88.976541 | 90.301996 | 88.976541 | RP | UC203a - pink | internal beam | intumescent paint | FD60
RP | 1F | internal beam :5 ,SHE-13.STEEL.dgn,Design Model:125278 | BS UC | UC203X203X46 | 1\BS UC\UC203X203X46 | 0 | 2.4839 | 0.00587 | 0.005784 | 2.99658 | 3.00814 | 0 | 0.01458 | 0.014366 | 0.01458 | 0.014366 | 46.100000 | 114.507790 | 114.456870 | 112.776869 | 114.456870 | 112.776869 | RP | UC203a - pink | internal beam | intumescent paint | FD60
RP | 1F | internal beam :5 ,SHE-13.STEEL.dgn,Design Model:125280 | BS UC | UC203X203X46 | 1\BS UC\UC203X203X46 | 0 | 2.0297 | 0.00587 | 0.005784 | 2.44863 | 2.4602 | 0 | 0.011914 | 0.011739 | 0.011914 | 0.011739 | 46.100000 | 93.569170 | 93.527561 | 92.154761 | 93.527561 | 92.154761 | RP | UC203a - pink | internal beam | intumescent paint | FD60
RP | 1F | internal beam :5 ,SHE-13.STEEL.dgn,Design Model:125282 | BS UC | UC203X203X46 | 1\BS UC\UC203X203X46 | 0 | 0.6964 | 0.00587 | 0.005784 | 0.840137 | 0.851705 | 0 | 0.004088 | 0.004028 | 0.004088 | 0.004028 | 46.100000 | 32.104040 | 32.089764 | 31.618749 | 32.089764 | 31.618749 | RP | UC203a - pink | internal beam | intumescent paint | FD60
RP | 1F | internal beam :5 ,SHE-13.STEEL.dgn,Design Model:125284 | BS UC | UC203X203X46 | 1\BS UC\UC203X203X46 | 0 | 2.319 | 0.00587 | 0.005784 | 2.79764 | 2.80921 | 0 | 0.013613 | 0.013413 | 0.013613 | 0.013413 | 46.100000 | 106.905900 | 106.858360 | 105.289891 | 106.858360 | 105.289891 | RP | UC203a - pink | internal beam | intumescent paint | FD60
RP | 1F | internal beam :5 ,SHE-13.STEEL.dgn,Design Model:125286 | BS UC | UC203X203X46 | 1\BS UC\UC203X203X46 | 0 | 4.20305 | 0.00587 | 0.005784 | 5.07056 | 5.08213 | 0 | 0.024672 | 0.02431 | 0.024672 | 0.02431 | 46.100000 | 193.760605 | 193.674442 | 190.831684 | 193.674442 | 190.831684 | RP | UC203a - pink | internal beam | intumescent paint | FD60
RP | 1F | internal beam :5 ,SHE-13.STEEL.dgn,Design Model:125288 | BS UC | UC203X203X46 | 1\BS UC\UC203X203X46 | 0 | 4.2064 | 0.00587 | 0.005784 | 5.0746 | 5.08617 | 0 | 0.024692 | 0.024329 | 0.024692 | 0.024329 | 46.100000 | 193.915040 | 193.828809 | 190.983785 | 193.828809 | 190.983785 | RP | UC203a - pink | internal beam | intumescent paint | FD60
RP | 1F | internal beam :5 ,SHE-13.STEEL.dgn,Design Model:125290 | BS UC | UC203X203X46 | 1\BS UC\UC203X203X46 | 0 | 4.2082 | 0.00587 | 0.005784 | 5.07677 | 5.08834 | 0 | 0.024702 | 0.02434 | 0.024702 | 0.02434 | 46.100000 | 193.998020 | 193.911752 | 191.065511 | 193.911752 | 191.065511 | RP | UC203a - pink | internal beam | intumescent paint | FD60
RP | 1F | internal beam :5 ,SHE-13.STEEL.dgn,Design Model:125292 | BS UC | UC203X203X46 | 1\BS UC\UC203X203X46 | 0 | 4.2082 | 0.00587 | 0.005784 | 5.07677 | 5.08834 | 0 | 0.024702 | 0.02434 | 0.024702 | 0.02434 | 46.100000 | 193.998020 | 193.911752 | 191.065511 | 193.911752 | 191.065511 | RP | UC203a - pink | internal beam | intumescent paint | FD60
RP | 1F | internal beam :5 ,SHE-13.STEEL.dgn,Design Model:125294 | BS UC | UC203X203X71 | 1\BS UC\UC203X203X71 | 0 | 5.53365 | 0.00904 | 0.008953 | 6.84623 | 6.86414 | 0 | 0.050024 | 0.049545 | 0.050024 | 0.049545 | 71.000000 | 392.889150 | 392.689939 | 388.929846 | 392.689939 | 388.929846 | RP | UC203d - black | internal beam | intumescent paint | FD60
RP | 1F | internal beam :5 ,SHE-13.STEEL.dgn,Design Model:125296 | BS UC | UC203X203X71 | 1\BS UC\UC203X203X71 | 0 | 5.537 | 0.00904 | 0.008953 | 6.85038 | 6.86828 | 0 | 0.050054 | 0.049575 | 0.050054 | 0.049575 | 71.000000 | 393.127000 | 392.927668 | 389.165299 | 392.927668 | 389.165299 | RP | UC203d - black | internal beam | intumescent paint | FD60
RP | 1F | internal beam :5 ,SHE-13.STEEL.dgn,Design Model:125298 | BS UC | UC203X203X71 | 1\BS UC\UC203X203X71 | 0 | 5.5172 | 0.00904 | 0.008953 | 6.82588 | 6.84379 | 0 | 0.049876 | 0.049398 | 0.049876 | 0.049398 | 71.000000 | 391.721352 | 391.522733 | 387.773816 | 391.522733 | 387.773816 | RP | UC203d - black | internal beam | intumescent paint | FD60
RP | 1F | internal beam :5 ,SHE-13.STEEL.dgn,Design Model:125300 | BS UC | UC203X203X71 | 1\BS UC\UC203X203X71 | 0 | 5.5172 | 0.00904 | 0.008953 | 6.82588 | 6.84379 | 0 | 0.049876 | 0.049398 | 0.049876 | 0.049398 | 71.000000 | 391.721352 | 391.522733 | 387.773816 | 391.522733 | 387.773816 | RP | UC203d - black | internal beam | intumescent paint | FD60
RP | 1F | internal beam :5 ,SHE-13.STEEL.dgn,Design Model:125302 | BS UC | UC305X305X240 | 1\BS UC\UC305X305X240 | 0 | 8.38637 | 0.0306 | 0.030381 | 16.2075 | 16.2683 | 0 | 0.256623 | 0.254783 | 0.256623 | 0.254783 | 240.000000 | 2012.727813 | 2014.488949 | 2000.049145 | 2014.488949 | 2000.049145 | RP | UC305f - blue | internal beam | intumescent paint | FD60
RP | 1F | internal beam :5 ,SHE-13.STEEL.dgn,Design Model:125306 | BS UC | UC305X305X240 | 1\BS UC\UC305X305X240 | 0 | 8.38638 | 0.0306 | 0.030381 | 16.2075 | 16.2683 | 0 | 0.256623 | 0.254784 | 0.256623 | 0.254784 | 240.000000 | 2012.730796 | 2014.491935 | 2000.052110 | 2014.491935 | 2000.052110 | RP | UC305f - blue | internal beam | intumescent paint | FD60
RP | 1F | internal beam :5 ,SHE-13.STEEL.dgn,Design Model:125308 | BS UC | UC305X305X240 | 1\BS UC\UC305X305X240 | 0 | 8.38637 | 0.0306 | 0.030381 | 16.2075 | 16.2683 | 0 | 0.256623 | 0.254783 | 0.256623 | 0.254783 | 240.000000 | 2012.727813 | 2014.488949 | 2000.049145 | 2014.488949 | 2000.049145 | RP | UC305f - blue | internal beam | intumescent paint | FD60
4F | 1F | FLT 100x10 - horizontal bracing :5,SHE-13.STEEL.dgn,Design Model:142506 | AS_FLAT | 100X10 | 1\AS_FLAT\100X10 | 0 | 6.51154 | 0.01 | 0.001 | 1.43254 | 1.43454 | 0 | 0.065115 | 0.006512 | 0.065115 | 0.006512 | 7.850000 | 51.115577 | 511.155771 | 51.115577 | 511.155771 | 51.115577 | 4F | HB | horizontal bracing | intumescent paint | FD60 | Identification - ID | Type ID: FLT 100x10
5F | 1F | FLT 100x10 - horizontal bracing :5,SHE-13.STEEL.dgn,Design Model:142679 | AS_FLAT | 100X10 | 1\AS_FLAT\100X10 | 0 | 5.83462 | 0.01 | 0.001 | 1.28362 | 1.28562 | 0 | 0.058346 | 0.005835 | 0.058346 | 0.005835 | 7.850000 | 45.801765 | 458.017654 | 45.801765 | 458.017654 | 45.801765 | 5F | HB | horizontal bracing | intumescent paint | FD60 | Identification - ID | Type ID: FLT 100x10
RP | 1F | FLT 100x10 - horizontal bracing :5,SHE-13.STEEL.dgn,Design Model:142681 | AS_FLAT | 100X10 | 1\AS_FLAT\100X10 | 0 | 5.82512 | 0.01 | 0.001 | 1.28153 | 1.28353 | 0 | 0.058251 | 0.005825 | 0.058251 | 0.005825 | 7.850000 | 45.727172 | 457.271720 | 45.727172 | 457.271720 | 45.727172 | RP | HB | horizontal bracing | intumescent paint | FD60 | Identification - ID | Type ID: FLT 100x10
4F | 1F | FLT 100x10 - horizontal bracing :5,SHE-13.STEEL.dgn,Design Model:142705 | AS_FLAT | 100X10 | 1\AS_FLAT\100X10 | 0 | 6.51154 | 0.01 | 0.001 | 1.43254 | 1.43454 | 0 | 0.065115 | 0.006512 | 0.065115 | 0.006512 | 7.850000 | 51.115577 | 511.155771 | 51.115577 | 511.155771 | 51.115577 | 4F | HB | horizontal bracing | intumescent paint | FD60 | Identification - ID | Type ID: FLT 100x10
4F | 1F | FLT 100x10 - horizontal bracing :5,SHE-13.STEEL.dgn,Design Model:142710 | AS_FLAT | 100X10 | 1\AS_FLAT\100X10 | 0 | 4.69133 | 0.01 | 0.001 | 1.03209 | 1.03409 | 0 | 0.046913 | 0.004691 | 0.046913 | 0.004691 | 7.850000 | 36.826934 | 368.269345 | 36.826934 | 368.269345 | 36.826934 | 4F | HB | horizontal bracing | intumescent paint | FD60 | Identification - ID | Type ID: FLT 100x10
4F | 1F | FLT 100x10 - horizontal bracing :5,SHE-13.STEEL.dgn,Design Model:142712 | AS_FLAT | 100X10 | 1\AS_FLAT\100X10 | 0 | 4.69133 | 0.01 | 0.001 | 1.03209 | 1.03409 | 0 | 0.046913 | 0.004691 | 0.046913 | 0.004691 | 7.850000 | 36.826934 | 368.269345 | 36.826934 | 368.269345 | 36.826934 | 4F | HB | horizontal bracing | intumescent paint | FD60 | Identification - ID | Type ID: FLT 100x10
4F | 1F | FLT 100x10 - horizontal bracing :5,SHE-13.STEEL.dgn,Design Model:142714 | AS_FLAT | 100X10 | 1\AS_FLAT\100X10 | 0 | 6.51154 | 0.01 | 0.001 | 1.43254 | 1.43454 | 0 | 0.065115 | 0.006512 | 0.065115 | 0.006512 | 7.850000 | 51.115577 | 511.155771 | 51.115577 | 511.155771 | 51.115577 | 4F | HB | horizontal bracing | intumescent paint | FD60 | Identification - ID | Type ID: FLT 100x10
4F | 1F | FLT 100x10 - horizontal bracing :5,SHE-13.STEEL.dgn,Design Model:142716 | AS_FLAT | 100X10 | 1\AS_FLAT\100X10 | 0 | 6.51154 | 0.01 | 0.001 | 1.43254 | 1.43454 | 0 | 0.065115 | 0.006512 | 0.065115 | 0.006512 | 7.850000 | 51.115577 | 511.155771 | 51.115577 | 511.155771 | 51.115577 | 4F | HB | horizontal bracing | intumescent paint | FD60 | Identification - ID | Type ID: FLT 100x10
4F | 1F | FLT 100x10 - horizontal bracing :5,SHE-13.STEEL.dgn,Design Model:142718 | AS_FLAT | 100X10 | 1\AS_FLAT\100X10 | 0 | 6.47117 | 0.01 | 0.001 | 1.42366 | 1.42566 | 0 | 0.064712 | 0.006471 | 0.064712 | 0.006471 | 7.850000 | 50.798695 | 507.986953 | 50.798695 | 507.986953 | 50.798695 | 4F | HB | horizontal bracing | intumescent paint | FD60 | Identification - ID | Type ID: FLT 100x10
4F | 1F | FLT 100x10 - horizontal bracing :5,SHE-13.STEEL.dgn,Design Model:142720 | AS_FLAT | 100X10 | 1\AS_FLAT\100X10 | 0 | 6.47117 | 0.01 | 0.001 | 1.42366 | 1.42566 | 0 | 0.064712 | 0.006471 | 0.064712 | 0.006471 | 7.850000 | 50.798695 | 507.986953 | 50.798695 | 507.986953 | 50.798695 | 4F | HB | horizontal bracing | intumescent paint | FD60 | Identification - ID | Type ID: FLT 100x10
4F | 1F | FLT 100x10 - horizontal bracing :5,SHE-13.STEEL.dgn,Design Model:142722 | AS_FLAT | 100X10 | 1\AS_FLAT\100X10 | 0 | 6.60924 | 0.01 | 0.001 | 1.45403 | 1.45603 | 0 | 0.066092 | 0.006609 | 0.066092 | 0.006609 | 7.850000 | 51.882530 | 518.825300 | 51.882530 | 518.825300 | 51.882530 | 4F | HB | horizontal bracing | intumescent paint | FD60 | Identification - ID | Type ID: FLT 100x10
4F | 1F | FLT 100x10 - horizontal bracing :5,SHE-13.STEEL.dgn,Design Model:142724 | AS_FLAT | 100X10 | 1\AS_FLAT\100X10 | 0 | 6.60924 | 0.01 | 0.001 | 1.45403 | 1.45603 | 0 | 0.066092 | 0.006609 | 0.066092 | 0.006609 | 7.850000 | 51.882530 | 518.825300 | 51.882530 | 518.825300 | 51.882530 | 4F | HB | horizontal bracing | intumescent paint | FD60 | Identification - ID | Type ID: FLT 100x10
4F | 1F | FLT 100x10 - horizontal bracing :5,SHE-13.STEEL.dgn,Design Model:142726 | AS_FLAT | 100X10 | 1\AS_FLAT\100X10 | 0 | 6.60913 | 0.01 | 0.001 | 1.45401 | 1.45601 | 0 | 0.066091 | 0.006609 | 0.066091 | 0.006609 | 7.850000 | 51.881654 | 518.816536 | 51.881654 | 518.816536 | 51.881654 | 4F | HB | horizontal bracing | intumescent paint | FD60 | Identification - ID | Type ID: FLT 100x10
4F | 1F | FLT 100x10 - horizontal bracing :5,SHE-13.STEEL.dgn,Design Model:142728 | AS_FLAT | 100X10 | 1\AS_FLAT\100X10 | 0 | 6.60913 | 0.01 | 0.001 | 1.45401 | 1.45601 | 0 | 0.066091 | 0.006609 | 0.066091 | 0.006609 | 7.850000 | 51.881654 | 518.816536 | 51.881654 | 518.816536 | 51.881654 | 4F | HB | horizontal bracing | intumescent paint | FD60 | Identification - ID | Type ID: FLT 100x10
4F | 1F | FLT 100x10 - horizontal bracing :5,SHE-13.STEEL.dgn,Design Model:142730 | AS_FLAT | 100X10 | 1\AS_FLAT\100X10 | 0 | 6.47105 | 0.01 | 0.001 | 1.42363 | 1.42563 | 0 | 0.06471 | 0.006471 | 0.06471 | 0.006471 | 7.850000 | 50.797741 | 507.977409 | 50.797741 | 507.977409 | 50.797741 | 4F | HB | horizontal bracing | intumescent paint | FD60 | Identification - ID | Type ID: FLT 100x10
4F | 1F | FLT 100x10 - horizontal bracing :5,SHE-13.STEEL.dgn,Design Model:142732 | AS_FLAT | 100X10 | 1\AS_FLAT\100X10 | 0 | 6.47105 | 0.01 | 0.001 | 1.42363 | 1.42563 | 0 | 0.06471 | 0.006471 | 0.06471 | 0.006471 | 7.850000 | 50.797741 | 507.977409 | 50.797741 | 507.977409 | 50.797741 | 4F | HB | horizontal bracing | intumescent paint | FD60 | Identification - ID | Type ID: FLT 100x10
4F | 1F | FLT 100x10 - horizontal bracing :5,SHE-13.STEEL.dgn,Design Model:142734 | AS_FLAT | 100X10 | 1\AS_FLAT\100X10 | 0 | 6.49916 | 0.01 | 0.001 | 1.42982 | 1.43182 | 0 | 0.064992 | 0.006499 | 0.064992 | 0.006499 | 7.850000 | 51.018405 | 510.184053 | 51.018405 | 510.184053 | 51.018405 | 4F | HB | horizontal bracing | intumescent paint | FD60 | Identification - ID | Type ID: FLT 100x10
4F | 1F | FLT 100x10 - horizontal bracing :5,SHE-13.STEEL.dgn,Design Model:142736 | AS_FLAT | 100X10 | 1\AS_FLAT\100X10 | 0 | 6.49916 | 0.01 | 0.001 | 1.42982 | 1.43182 | 0 | 0.064992 | 0.006499 | 0.064992 | 0.006499 | 7.850000 | 51.018405 | 510.184053 | 51.018405 | 510.184053 | 51.018405 | 4F | HB | horizontal bracing | intumescent paint | FD60 | Identification - ID | Type ID: FLT 100x10
4F | 1F | FLT 100x10 - horizontal bracing :5,SHE-13.STEEL.dgn,Design Model:142738 | AS_FLAT | 100X10 | 1\AS_FLAT\100X10 | 0 | 4.66551 | 0.01 | 0.001 | 1.02641 | 1.02841 | 0 | 0.046655 | 0.004666 | 0.046655 | 0.004666 | 7.850000 | 36.624233 | 366.242328 | 36.624233 | 366.242328 | 36.624233 | 4F | HB | horizontal bracing | intumescent paint | FD60 | Identification - ID | Type ID: FLT 100x10
4F | 1F | FLT 100x10 - horizontal bracing :5,SHE-13.STEEL.dgn,Design Model:142740 | AS_FLAT | 100X10 | 1\AS_FLAT\100X10 | 0 | 4.66551 | 0.01 | 0.001 | 1.02641 | 1.02841 | 0 | 0.046655 | 0.004666 | 0.046655 | 0.004666 | 7.850000 | 36.624233 | 366.242328 | 36.624233 | 366.242328 | 36.624233 | 4F | HB | horizontal bracing | intumescent paint | FD60 | Identification - ID | Type ID: FLT 100x10
4F | 1F | FLT 100x10 - horizontal bracing :5,SHE-13.STEEL.dgn,Design Model:142742 | AS_FLAT | 100X10 | 1\AS_FLAT\100X10 | 0 | 6.49916 | 0.01 | 0.001 | 1.42982 | 1.43182 | 0 | 0.064992 | 0.006499 | 0.064992 | 0.006499 | 7.850000 | 51.018405 | 510.184053 | 51.018405 | 510.184053 | 51.018405 | 4F | HB | horizontal bracing | intumescent paint | FD60 | Identification - ID | Type ID: FLT 100x10
4F | 1F | FLT 100x10 - horizontal bracing :5,SHE-13.STEEL.dgn,Design Model:142744 | AS_FLAT | 100X10 | 1\AS_FLAT\100X10 | 0 | 6.49916 | 0.01 | 0.001 | 1.42982 | 1.43182 | 0 | 0.064992 | 0.006499 | 0.064992 | 0.006499 | 7.850000 | 51.018405 | 510.184053 | 51.018405 | 510.184053 | 51.018405 | 4F | HB | horizontal bracing | intumescent paint | FD60 | Identification - ID | Type ID: FLT 100x10
5F | 1F | FLT 100x10 - horizontal bracing :5,SHE-13.STEEL.dgn,Design Model:143241 | AS_FLAT | 100X10 | 1\AS_FLAT\100X10 | 0 | 5.83546 | 0.01 | 0.001 | 1.2838 | 1.2858 | 0 | 0.058355 | 0.005835 | 0.058355 | 0.005835 | 7.850000 | 45.808366 | 458.083656 | 45.808366 | 458.083656 | 45.808366 | 5F | HB | horizontal bracing | intumescent paint | FD60 | Identification - ID | Type ID: FLT 100x10
5F | 1F | FLT 100x10 - horizontal bracing :5,SHE-13.STEEL.dgn,Design Model:143243 | AS_FLAT | 100X10 | 1\AS_FLAT\100X10 | 0 | 6.12838 | 0.01 | 0.001 | 1.34824 | 1.35024 | 0 | 0.061284 | 0.006128 | 0.061284 | 0.006128 | 7.850000 | 48.107803 | 481.078027 | 48.107803 | 481.078027 | 48.107803 | 5F | HB | horizontal bracing | intumescent paint | FD60 | Identification - ID | Type ID: FLT 100x10
5F | 1F | FLT 100x10 - horizontal bracing :5,SHE-13.STEEL.dgn,Design Model:143245 | AS_FLAT | 100X10 | 1\AS_FLAT\100X10 | 0 | 6.12838 | 0.01 | 0.001 | 1.34824 | 1.35024 | 0 | 0.061284 | 0.006128 | 0.061284 | 0.006128 | 7.850000 | 48.107803 | 481.078027 | 48.107803 | 481.078027 | 48.107803 | 5F | HB | horizontal bracing | intumescent paint | FD60 | Identification - ID | Type ID: FLT 100x10
5F | 1F | FLT 100x10 - horizontal bracing :5,SHE-13.STEEL.dgn,Design Model:143247 | AS_FLAT | 100X10 | 1\AS_FLAT\100X10 | 0 | 6.30289 | 0.01 | 0.001 | 1.38664 | 1.38864 | 0 | 0.063029 | 0.006303 | 0.063029 | 0.006303 | 7.850000 | 49.477694 | 494.776936 | 49.477694 | 494.776936 | 49.477694 | 5F | HB | horizontal bracing | intumescent paint | FD60 | Identification - ID | Type ID: FLT 100x10
5F | 1F | FLT 100x10 - horizontal bracing :5,SHE-13.STEEL.dgn,Design Model:143249 | AS_FLAT | 100X10 | 1\AS_FLAT\100X10 | 0 | 6.30159 | 0.01 | 0.001 | 1.38635 | 1.38835 | 0 | 0.063016 | 0.006302 | 0.063016 | 0.006302 | 7.850000 | 49.467486 | 494.674858 | 49.467486 | 494.674858 | 49.467486 | 5F | HB | horizontal bracing | intumescent paint | FD60 | Identification - ID | Type ID: FLT 100x10
5F | 1F | FLT 100x10 - horizontal bracing :5,SHE-13.STEEL.dgn,Design Model:143251 | AS_FLAT | 100X10 | 1\AS_FLAT\100X10 | 0 | 6.30254 | 0.01 | 0.001 | 1.38656 | 1.38856 | 0 | 0.063025 | 0.006303 | 0.063025 | 0.006303 | 7.850000 | 49.474923 | 494.749232 | 49.474923 | 494.749232 | 49.474923 | 5F | HB | horizontal bracing | intumescent paint | FD60 | Identification - ID | Type ID: FLT 100x10
5F | 1F | FLT 100x10 - horizontal bracing :5,SHE-13.STEEL.dgn,Design Model:143253 | AS_FLAT | 100X10 | 1\AS_FLAT\100X10 | 0 | 6.30278 | 0.01 | 0.001 | 1.38661 | 1.38861 | 0 | 0.063028 | 0.006303 | 0.063028 | 0.006303 | 7.850000 | 49.476838 | 494.768383 | 49.476838 | 494.768383 | 49.476838 | 5F | HB | horizontal bracing | intumescent paint | FD60 | Identification - ID | Type ID: FLT 100x10
5F | 1F | FLT 100x10 - horizontal bracing :5,SHE-13.STEEL.dgn,Design Model:143255 | AS_FLAT | 100X10 | 1\AS_FLAT\100X10 | 0 | 6.13475 | 0.01 | 0.001 | 1.34964 | 1.35164 | 0 | 0.061348 | 0.006135 | 0.061348 | 0.006135 | 7.850000 | 48.157804 | 481.578037 | 48.157804 | 481.578037 | 48.157804 | 5F | HB | horizontal bracing | intumescent paint | FD60 | Identification - ID | Type ID: FLT 100x10
5F | 1F | FLT 100x10 - horizontal bracing :5,SHE-13.STEEL.dgn,Design Model:143257 | AS_FLAT | 100X10 | 1\AS_FLAT\100X10 | 0 | 6.17869 | 0.01 | 0.001 | 1.35931 | 1.36131 | 0 | 0.061787 | 0.006179 | 0.061787 | 0.006179 | 7.850000 | 48.502717 | 485.027171 | 48.502717 | 485.027171 | 48.502717 | 5F | HB | horizontal bracing | intumescent paint | FD60 | Identification - ID | Type ID: FLT 100x10
5F | 1F | FLT 100x10 - horizontal bracing :5,SHE-13.STEEL.dgn,Design Model:143259 | AS_FLAT | 100X10 | 1\AS_FLAT\100X10 | 0 | 5.81069 | 0.01 | 0.001 | 1.27835 | 1.28035 | 0 | 0.058107 | 0.005811 | 0.058107 | 0.005811 | 7.850000 | 45.613904 | 456.139043 | 45.613904 | 456.139043 | 45.613904 | 5F | HB | horizontal bracing | intumescent paint | FD60 | Identification - ID | Type ID: FLT 100x10
5F | 1F | FLT 100x10 - horizontal bracing :5,SHE-13.STEEL.dgn,Design Model:143261 | AS_FLAT | 100X10 | 1\AS_FLAT\100X10 | 0 | 5.81069 | 0.01 | 0.001 | 1.27835 | 1.28035 | 0 | 0.058107 | 0.005811 | 0.058107 | 0.005811 | 7.850000 | 45.613904 | 456.139043 | 45.613904 | 456.139043 | 45.613904 | 5F | HB | horizontal bracing | intumescent paint | FD60 | Identification - ID | Type ID: FLT 100x10
5F | 1F | FLT 100x10 - horizontal bracing :5,SHE-13.STEEL.dgn,Design Model:143263 | AS_FLAT | 100X10 | 1\AS_FLAT\100X10 | 0 | 3.30507 | 0.01 | 0.001 | 0.727115 | 0.729115 | 0 | 0.033051 | 0.003305 | 0.033051 | 0.003305 | 7.850000 | 25.944786 | 259.447860 | 25.944786 | 259.447860 | 25.944786 | 5F | HB | horizontal bracing | intumescent paint | FD60 | Identification - ID | Type ID: FLT 100x10
5F | 1F | FLT 100x10 - horizontal bracing :5,SHE-13.STEEL.dgn,Design Model:143265 | AS_FLAT | 100X10 | 1\AS_FLAT\100X10 | 0 | 3.6256 | 0.01 | 0.001 | 0.797633 | 0.799633 | 0 | 0.036256 | 0.003626 | 0.036256 | 0.003626 | 7.850000 | 28.460983 | 284.609827 | 28.460983 | 284.609827 | 28.460983 | 5F | HB | horizontal bracing | intumescent paint | FD60 | Identification - ID | Type ID: FLT 100x10
5F | 1F | FLT 100x10 - horizontal bracing :5,SHE-13.STEEL.dgn,Design Model:143267 | AS_FLAT | 100X10 | 1\AS_FLAT\100X10 | 0 | 5.83462 | 0.01 | 0.001 | 1.28362 | 1.28562 | 0 | 0.058346 | 0.005835 | 0.058346 | 0.005835 | 7.850000 | 45.801765 | 458.017654 | 45.801765 | 458.017654 | 45.801765 | 5F | HB | horizontal bracing | intumescent paint | FD60 | Identification - ID | Type ID: FLT 100x10
5F | 1F | FLT 100x10 - horizontal bracing :5,SHE-13.STEEL.dgn,Design Model:143269 | AS_FLAT | 100X10 | 1\AS_FLAT\100X10 | 0 | 5.83546 | 0.01 | 0.001 | 1.2838 | 1.2858 | 0 | 0.058355 | 0.005835 | 0.058355 | 0.005835 | 7.850000 | 45.808366 | 458.083656 | 45.808366 | 458.083656 | 45.808366 | 5F | HB | horizontal bracing | intumescent paint | FD60 | Identification - ID | Type ID: FLT 100x10
5F | 1F | FLT 100x10 - horizontal bracing :5,SHE-13.STEEL.dgn,Design Model:143271 | AS_FLAT | 100X10 | 1\AS_FLAT\100X10 | 0 | 4.6102 | 0.01 | 0.001 | 1.01424 | 1.01624 | 0 | 0.046102 | 0.00461 | 0.046102 | 0.00461 | 7.850000 | 36.190062 | 361.900625 | 36.190062 | 361.900625 | 36.190062 | 5F | HB | horizontal bracing | intumescent paint | FD60 | Identification - ID | Type ID: FLT 100x10
5F | 1F | FLT 100x10 - horizontal bracing :5,SHE-13.STEEL.dgn,Design Model:143273 | AS_FLAT | 100X10 | 1\AS_FLAT\100X10 | 0 | 4.23491 | 0.01 | 0.001 | 0.931681 | 0.933681 | 0 | 0.042349 | 0.004235 | 0.042349 | 0.004235 | 7.850000 | 33.244056 | 332.440561 | 33.244056 | 332.440561 | 33.244056 | 5F | HB | horizontal bracing | intumescent paint | FD60 | Identification - ID | Type ID: FLT 100x10
5F | 1F | FLT 100x10 - horizontal bracing :5,SHE-13.STEEL.dgn,Design Model:143275 | AS_FLAT | 100X10 | 1\AS_FLAT\100X10 | 0 | 5.81069 | 0.01 | 0.001 | 1.27835 | 1.28035 | 0 | 0.058107 | 0.005811 | 0.058107 | 0.005811 | 7.850000 | 45.613904 | 456.139043 | 45.613904 | 456.139043 | 45.613904 | 5F | HB | horizontal bracing | intumescent paint | FD60 | Identification - ID | Type ID: FLT 100x10
5F | 1F | FLT 100x10 - horizontal bracing :5,SHE-13.STEEL.dgn,Design Model:143277 | AS_FLAT | 100X10 | 1\AS_FLAT\100X10 | 0 | 5.81069 | 0.01 | 0.001 | 1.27835 | 1.28035 | 0 | 0.058107 | 0.005811 | 0.058107 | 0.005811 | 7.850000 | 45.613904 | 456.139043 | 45.613904 | 456.139043 | 45.613904 | 5F | HB | horizontal bracing | intumescent paint | FD60 | Identification - ID | Type ID: FLT 100x10
RP | 1F | FLT 100x10 - horizontal bracing :5,SHE-13.STEEL.dgn,Design Model:143571 | AS_FLAT | 100X10 | 1\AS_FLAT\100X10 | 0 | 5.76082 | 0.01 | 0.001 | 1.26738 | 1.26938 | 0 | 0.057608 | 0.005761 | 0.057608 | 0.005761 | 7.850000 | 45.222471 | 452.224712 | 45.222471 | 452.224712 | 45.222471 | RP | HB | horizontal bracing | intumescent paint | FD60 | Identification - ID | Type ID: FLT 100x10
RP | 1F | FLT 100x10 - horizontal bracing :5,SHE-13.STEEL.dgn,Design Model:143573 | AS_FLAT | 100X10 | 1\AS_FLAT\100X10 | 0 | 5.88451 | 0.01 | 0.001 | 1.29459 | 1.29659 | 0 | 0.058845 | 0.005885 | 0.058845 | 0.005885 | 7.850000 | 46.193414 | 461.934142 | 46.193414 | 461.934142 | 46.193414 | RP | HB | horizontal bracing | intumescent paint | FD60 | Identification - ID | Type ID: FLT 100x10
RP | 1F | FLT 100x10 - horizontal bracing :5,SHE-13.STEEL.dgn,Design Model:143575 | AS_FLAT | 100X10 | 1\AS_FLAT\100X10 | 0 | 5.88755 | 0.01 | 0.001 | 1.29526 | 1.29726 | 0 | 0.058875 | 0.005888 | 0.058875 | 0.005888 | 7.850000 | 46.217235 | 462.172352 | 46.217235 | 462.172352 | 46.217235 | RP | HB | horizontal bracing | intumescent paint | FD60 | Identification - ID | Type ID: FLT 100x10
RP | 1F | FLT 100x10 - horizontal bracing :5,SHE-13.STEEL.dgn,Design Model:143577 | AS_FLAT | 100X10 | 1\AS_FLAT\100X10 | 0 | 5.82512 | 0.01 | 0.001 | 1.28153 | 1.28353 | 0 | 0.058251 | 0.005825 | 0.058251 | 0.005825 | 7.850000 | 45.727172 | 457.271720 | 45.727172 | 457.271720 | 45.727172 | RP | HB | horizontal bracing | intumescent paint | FD60 | Identification - ID | Type ID: FLT 100x10
RP | 1F | FLT 100x10 - horizontal bracing :5,SHE-13.STEEL.dgn,Design Model:143579 | AS_FLAT | 100X10 | 1\AS_FLAT\100X10 | 0 | 5.76082 | 0.01 | 0.001 | 1.26738 | 1.26938 | 0 | 0.057608 | 0.005761 | 0.057608 | 0.005761 | 7.850000 | 45.222471 | 452.224712 | 45.222471 | 452.224712 | 45.222471 | RP | HB | horizontal bracing | intumescent paint | FD60 | Identification - ID | Type ID: FLT 100x10
RP | 1F | FLT 100x10 - horizontal bracing :5,SHE-13.STEEL.dgn,Design Model:143581 | AS_FLAT | 100X10 | 1\AS_FLAT\100X10 | 0 | 4.73664 | 0.01 | 0.001 | 1.04206 | 1.04406 | 0 | 0.047366 | 0.004737 | 0.047366 | 0.004737 | 7.850000 | 37.182611 | 371.826109 | 37.182611 | 371.826109 | 37.182611 | RP | HB | horizontal bracing | intumescent paint | FD60 | Identification - ID | Type ID: FLT 100x10
RP | 1F | FLT 100x10 - horizontal bracing :5,SHE-13.STEEL.dgn,Design Model:143583 | AS_FLAT | 100X10 | 1\AS_FLAT\100X10 | 0 | 4.73155 | 0.01 | 0.001 | 1.04094 | 1.04294 | 0 | 0.047315 | 0.004732 | 0.047315 | 0.004732 | 7.850000 | 37.142632 | 371.426325 | 37.142632 | 371.426325 | 37.142632 | RP | HB | horizontal bracing | intumescent paint | FD60 | Identification - ID | Type ID: FLT 100x10
RP | 1F | FLT 100x10 - horizontal bracing :5,SHE-13.STEEL.dgn,Design Model:143585 | AS_FLAT | 100X10 | 1\AS_FLAT\100X10 | 0 | 4.73149 | 0.01 | 0.001 | 1.04093 | 1.04293 | 0 | 0.047315 | 0.004731 | 0.047315 | 0.004731 | 7.850000 | 37.142206 | 371.422058 | 37.142206 | 371.422058 | 37.142206 | RP | HB | horizontal bracing | intumescent paint | FD60 | Identification - ID | Type ID: FLT 100x10
RP | 1F | FLT 100x10 - horizontal bracing :5,SHE-13.STEEL.dgn,Design Model:143587 | AS_FLAT | 100X10 | 1\AS_FLAT\100X10 | 0 | 4.73658 | 0.01 | 0.001 | 1.04205 | 1.04405 | 0 | 0.047366 | 0.004737 | 0.047366 | 0.004737 | 7.850000 | 37.182181 | 371.821812 | 37.182181 | 371.821812 | 37.182181 | RP | HB | horizontal bracing | intumescent paint | FD60 | Identification - ID | Type ID: FLT 100x10
RP | 1F | FLT 100x10 - horizontal bracing :5,SHE-13.STEEL.dgn,Design Model:143589 | AS_FLAT | 100X10 | 1\AS_FLAT\100X10 | 0 | 5.74247 | 0.01 | 0.001 | 1.26334 | 1.26534 | 0 | 0.057425 | 0.005742 | 0.057425 | 0.005742 | 7.850000 | 45.078377 | 450.783775 | 45.078377 | 450.783775 | 45.078377 | RP | HB | horizontal bracing | intumescent paint | FD60 | Identification - ID | Type ID: FLT 100x10
RP | 1F | FLT 100x10 - horizontal bracing :5,SHE-13.STEEL.dgn,Design Model:143591 | AS_FLAT | 100X10 | 1\AS_FLAT\100X10 | 0 | 5.80696 | 0.01 | 0.001 | 1.27753 | 1.27953 | 0 | 0.05807 | 0.005807 | 0.05807 | 0.005807 | 7.850000 | 45.584641 | 455.846412 | 45.584641 | 455.846412 | 45.584641 | RP | HB | horizontal bracing | intumescent paint | FD60 | Identification - ID | Type ID: FLT 100x10
RP | 1F | FLT 100x10 - horizontal bracing :5,SHE-13.STEEL.dgn,Design Model:143593 | AS_FLAT | 100X10 | 1\AS_FLAT\100X10 | 0 | 5.87017 | 0.01 | 0.001 | 1.29144 | 1.29344 | 0 | 0.058702 | 0.00587 | 0.058702 | 0.00587 | 7.850000 | 46.080860 | 460.808600 | 46.080860 | 460.808600 | 46.080860 | RP | HB | horizontal bracing | intumescent paint | FD60 | Identification - ID | Type ID: FLT 100x10
RP | 1F | FLT 100x10 - horizontal bracing :5,SHE-13.STEEL.dgn,Design Model:143595 | AS_FLAT | 100X10 | 1\AS_FLAT\100X10 | 0 | 5.86958 | 0.01 | 0.001 | 1.29131 | 1.29331 | 0 | 0.058696 | 0.00587 | 0.058696 | 0.00587 | 7.850000 | 46.076190 | 460.761903 | 46.076190 | 460.761903 | 46.076190 | RP | HB | horizontal bracing | intumescent paint | FD60 | Identification - ID | Type ID: FLT 100x10
RP | 1F | FLT 100x10 - horizontal bracing :5,SHE-13.STEEL.dgn,Design Model:143597 | AS_FLAT | 100X10 | 1\AS_FLAT\100X10 | 0 | 5.74247 | 0.01 | 0.001 | 1.26334 | 1.26534 | 0 | 0.057425 | 0.005742 | 0.057425 | 0.005742 | 7.850000 | 45.078377 | 450.783775 | 45.078377 | 450.783775 | 45.078377 | RP | HB | horizontal bracing | intumescent paint | FD60 | Identification - ID | Type ID: FLT 100x10
RP | 1F | FLT 100x10 - horizontal bracing :5,SHE-13.STEEL.dgn,Design Model:143599 | AS_FLAT | 100X10 | 1\AS_FLAT\100X10 | 0 | 5.80697 | 0.01 | 0.001 | 1.27753 | 1.27953 | 0 | 0.05807 | 0.005807 | 0.05807 | 0.005807 | 7.850000 | 45.584690 | 455.846899 | 45.584690 | 455.846899 | 45.584690 | RP | HB | horizontal bracing | intumescent paint | FD60 | Identification - ID | Type ID: FLT 100x10
4F | 1F | FLT 100x10 - vertical bracing :5,SHE-13.STEEL.dgn,Design Model:143623 | AS_FLAT | 100X10 | 1\AS_FLAT\100X10 | 0 | 3.23324 | 0.01 | 0.001 | 0.711313 | 0.713313 | 0 | 0.032332 | 0.003233 | 0.032332 | 0.003233 | 7.850000 | 25.380928 | 253.809283 | 25.380928 | 253.809283 | 25.380928 | 4F | VB | vertical bracing | intumescent paint | FD120 | Identification - ID | Type ID: FLT 100x10
4F | 1F | FLT 100x10 - vertical bracing :5,SHE-13.STEEL.dgn,Design Model:144035 | AS_FLAT | 100X10 | 1\AS_FLAT\100X10 | 0 | 3.19483 | 0.01 | 0.001 | 0.702863 | 0.704863 | 0 | 0.031948 | 0.003195 | 0.031948 | 0.003195 | 7.850000 | 25.079424 | 250.794238 | 25.079424 | 250.794238 | 25.079424 | 4F | VB | vertical bracing | intumescent paint | FD120 | Identification - ID | Type ID: FLT 100x10
4F | 1F | FLT 100x10 - vertical bracing :5,SHE-13.STEEL.dgn,Design Model:144037 | AS_FLAT | 100X10 | 1\AS_FLAT\100X10 | 0 | 3.18225 | 0.01 | 0.001 | 0.700095 | 0.702095 | 0 | 0.031823 | 0.003182 | 0.031823 | 0.003182 | 7.850000 | 24.980671 | 249.806712 | 24.980671 | 249.806712 | 24.980671 | 4F | VB | vertical bracing | intumescent paint | FD60 | Identification - ID | Type ID: FLT 100x10
4F | 1F | FLT 100x10 - vertical bracing :5,SHE-13.STEEL.dgn,Design Model:144039 | AS_FLAT | 100X10 | 1\AS_FLAT\100X10 | 0 | 3.18242 | 0.01 | 0.001 | 0.700132 | 0.702132 | 0 | 0.031824 | 0.003182 | 0.031824 | 0.003182 | 7.850000 | 24.981973 | 249.819726 | 24.981973 | 249.819726 | 24.981973 | 4F | VB | vertical bracing | intumescent paint | FD60 | Identification - ID | Type ID: FLT 100x10
5F | 1F | FLT 100x10 - vertical bracing :5,SHE-13.STEEL.dgn,Design Model:144041 | AS_FLAT | 100X10 | 1\AS_FLAT\100X10 | 0 | 3.37475 | 0.01 | 0.001 | 0.742445 | 0.744445 | 0 | 0.033748 | 0.003375 | 0.033748 | 0.003375 | 7.850000 | 26.491792 | 264.917916 | 26.491792 | 264.917916 | 26.491792 | 5F | VB | vertical bracing | intumescent paint | FD120 | Identification - ID | Type ID: FLT 100x10
5F | 1F | FLT 100x10 - vertical bracing :5,SHE-13.STEEL.dgn,Design Model:144043 | AS_FLAT | 100X10 | 1\AS_FLAT\100X10 | 0 | 3.40824 | 0.01 | 0.001 | 0.749813 | 0.751813 | 0 | 0.034082 | 0.003408 | 0.034082 | 0.003408 | 7.850000 | 26.754700 | 267.546997 | 26.754700 | 267.546997 | 26.754700 | 5F | VB | vertical bracing | intumescent paint | FD120 | Identification - ID | Type ID: FLT 100x10
5F | 1F | FLT 100x10 - vertical bracing :5,SHE-13.STEEL.dgn,Design Model:144045 | AS_FLAT | 100X10 | 1\AS_FLAT\100X10 | 0 | 3.36923 | 0.01 | 0.001 | 0.74123 | 0.74323 | 0 | 0.033692 | 0.003369 | 0.033692 | 0.003369 | 7.850000 | 26.448448 | 264.484478 | 26.448448 | 264.484478 | 26.448448 | 5F | VB | vertical bracing | intumescent paint | FD60 | Identification - ID | Type ID: FLT 100x10
5F | 1F | FLT 100x10 - vertical bracing :5,SHE-13.STEEL.dgn,Design Model:144047 | AS_FLAT | 100X10 | 1\AS_FLAT\100X10 | 0 | 3.33626 | 0.01 | 0.001 | 0.733977 | 0.735977 | 0 | 0.033363 | 0.003336 | 0.033363 | 0.003336 | 7.850000 | 26.189616 | 261.896163 | 26.189616 | 261.896163 | 26.189616 | 5F | VB | vertical bracing | intumescent paint | FD60 | Identification - ID | Type ID: FLT 100x10
4F | 1F | FLT 100x10 - vertical bracing :5,SHE-13.STEEL.dgn,Design Model:144049 | AS_FLAT | 100X10 | 1\AS_FLAT\100X10 | 0 | 3.59478 | 0.01 | 0.001 | 0.790853 | 0.792853 | 0 | 0.035948 | 0.003595 | 0.035948 | 0.003595 | 7.850000 | 28.219056 | 282.190563 | 28.219056 | 282.190563 | 28.219056 | 4F | VB | vertical bracing | intumescent paint | FD60 | Identification - ID | Type ID: FLT 100x10
4F | 1F | FLT 100x10 - vertical bracing :5,SHE-13.STEEL.dgn,Design Model:144051 | AS_FLAT | 100X10 | 1\AS_FLAT\100X10 | 0 | 3.50123 | 0.01 | 0.001 | 0.770271 | 0.772271 | 0 | 0.035012 | 0.003501 | 0.035012 | 0.003501 | 7.850000 | 27.484655 | 274.846555 | 27.484655 | 274.846555 | 27.484655 | 4F | VB | vertical bracing | intumescent paint | FD60 | Identification - ID | Type ID: FLT 100x10
5F | 1F | FLT 100x10 - vertical bracing :5,SHE-13.STEEL.dgn,Design Model:169533 | AS_FLAT | 100X10 | 1\AS_FLAT\100X10 | 0 | 3.55995 | 0.01 | 0.001 | 0.78319 | 0.78519 | 0 | 0.0356 | 0.00356 | 0.0356 | 0.00356 | 7.850000 | 27.945633 | 279.456334 | 27.945633 | 279.456334 | 27.945633 | 5F | VB | vertical bracing | intumescent paint | FD60 | Identification - ID | Type ID: FLT 100x10
5F | 1F | FLT 100x10 - vertical bracing :5,SHE-13.STEEL.dgn,Design Model:169535 | AS_FLAT | 100X10 | 1\AS_FLAT\100X10 | 0 | 3.50123 | 0.01 | 0.001 | 0.770271 | 0.772271 | 0 | 0.035012 | 0.003501 | 0.035012 | 0.003501 | 7.850000 | 27.484655 | 274.846555 | 27.484655 | 274.846555 | 27.484655 | 5F | VB | vertical bracing | intumescent paint | FD60 | Identification - ID | Type ID: FLT 100x10
4F | 1F | FLT 100x10 - vertical bracing :5,SHE-13.STEEL.dgn,Design Model:176325 | AS_FLAT | 100X10 | 1\AS_FLAT\100X10 | 0 | 3.59478 | 0.01 | 0.001 | 0.790853 | 0.792853 | 0 | 0.035948 | 0.003595 | 0.035948 | 0.003595 | 7.850000 | 28.219056 | 282.190563 | 28.219056 | 282.190563 | 28.219056 | 4F | VB | vertical bracing | intumescent paint | FD60 | Identification - ID | Type ID: FLT 100x10
4F | 1F | FLT 100x10 - vertical bracing :5,SHE-13.STEEL.dgn,Design Model:176327 | AS_FLAT | 100X10 | 1\AS_FLAT\100X10 | 0 | 3.50123 | 0.01 | 0.001 | 0.770271 | 0.772271 | 0 | 0.035012 | 0.003501 | 0.035012 | 0.003501 | 7.850000 | 27.484655 | 274.846555 | 27.484655 | 274.846555 | 27.484655 | 4F | VB | vertical bracing | intumescent paint | FD60 | Identification - ID | Type ID: FLT 100x10
4F | 1F | internal beam :5 ,SHE-13.STEEL.dgn,Design Model:190658 | AS_PFC | 200X75PFC | 1\AS_PFC\200X75PFC | 0 | 25.8472 | 0.0292 | 0.002856 | 17.7829 | 17.6453 | 0.000571 | 0.754738 | 0.07382 | 0.754167 | 0.073248 | 22.900000 | 591.900880 | 5924.695184 | 579.483885 | 5920.211264 | 574.999965 | 4F |  | internal beam | intumescent paint | FD60 | Identification - ID | Notes: SFS support at cranck position
5F | 1F | internal beam :5 ,SHE-13.STEEL.dgn,Design Model:190730 | AS_PFC | 200X75PFC | 1\AS_PFC\200X75PFC | 0 | 3.35433 | 0.0292 | 0.002856 | 2.30778 | 2.23275 | 0.000316 | 0.097946 | 0.00958 | 0.09763 | 0.009264 | 22.900000 | 76.814203 | 768.879988 | 75.202782 | 766.397190 | 72.719984 | 5F |  | internal beam | intumescent paint | FD60 | Identification - ID | Notes: SFS support at cranck position
RP | 1F | internal beam :5 ,SHE-13.STEEL.dgn,Design Model:190732 | AS_PFC | 200X75PFC | 1\AS_PFC\200X75PFC | 0 | 2.11979 | 0.0292 | 0.002856 | 1.45842 | 1.38339 | 0.000316 | 0.061898 | 0.006054 | 0.061582 | 0.005738 | 22.900000 | 48.543215 | 485.898500 | 47.524867 | 483.415702 | 45.042069 | RP |  | internal beam | intumescent paint | FD60 | Identification - ID | Notes: SFS support at cranck position
4F | 1F | internal beam :5 ,SHE-13.STEEL.dgn,Design Model:190734 | AS_PFC | 200X75PFC | 1\AS_PFC\200X75PFC | 0 | 13.7774 | 0.0292 | 0.002856 | 9.47885 | 9.34125 | 0.000571 | 0.4023 | 0.039348 | 0.401729 | 0.038777 | 22.900000 | 315.502460 | 3158.055628 | 308.883797 | 3153.571708 | 304.399877 | 4F |  | internal beam | intumescent paint | FD60 | Identification - ID | Notes: SFS support at cranck position
5F | 1F | internal beam :5 ,SHE-13.STEEL.dgn,Design Model:190736 | AS_PFC | 200X75PFC | 1\AS_PFC\200X75PFC | 0 | 11.9453 | 0.0292 | 0.002856 | 8.21833 | 8.06256 | 0.000633 | 0.348801 | 0.034116 | 0.348169 | 0.033483 | 22.900000 | 273.546284 | 2738.090794 | 267.807785 | 2733.125198 | 262.842188 | 5F |  | internal beam | intumescent paint | FD60 | Identification - ID | Notes: SFS support at cranck position
RP | 1F | internal beam :5 ,SHE-13.STEEL.dgn,Design Model:190738 | AS_PFC | 200X75PFC | 1\AS_PFC\200X75PFC | 0 | 9.43344 | 0.0292 | 0.002856 | 6.4902 | 6.33444 | 0.000633 | 0.275456 | 0.026942 | 0.274824 | 0.026309 | 22.900000 | 216.025704 | 2162.332400 | 211.493881 | 2157.366803 | 206.528285 | RP |  | internal beam | intumescent paint | FD60 | Identification - ID | Notes: SFS support at cranck position
5F | 1F | internal beam :5 ,SHE-13.STEEL.dgn,Design Model:190766 | AS_PFC | 200X75PFC | 1\AS_PFC\200X75PFC | 0 | 11.9453 | 0.0292 | 0.002856 | 8.21833 | 8.06256 | 0.000633 | 0.348801 | 0.034116 | 0.348169 | 0.033483 | 22.900000 | 273.546284 | 2738.090794 | 267.807785 | 2733.125198 | 262.842188 | 5F |  | internal beam | intumescent paint | FD60 | Identification - ID | Notes: SFS support at cranck position
RP | 1F | internal beam :5 ,SHE-13.STEEL.dgn,Design Model:190768 | AS_PFC | 200X75PFC | 1\AS_PFC\200X75PFC | 0 | 9.43344 | 0.0292 | 0.002856 | 6.4902 | 6.33444 | 0.000633 | 0.275456 | 0.026942 | 0.274824 | 0.026309 | 22.900000 | 216.025704 | 2162.332400 | 211.493881 | 2157.366803 | 206.528285 | RP |  | internal beam | intumescent paint | FD60 | Identification - ID | Notes: SFS support at cranck position
4F | 1F | internal beam :5 ,SHE-13.STEEL.dgn,Design Model:190770 | AS_PFC | 200X75PFC | 1\AS_PFC\200X75PFC | 0 | 13.7774 | 0.0292 | 0.002856 | 9.47885 | 9.34125 | 0.000571 | 0.4023 | 0.039348 | 0.401729 | 0.038777 | 22.900000 | 315.502460 | 3158.055628 | 308.883797 | 3153.571708 | 304.399877 | 4F |  | internal beam | intumescent paint | FD60 | Identification - ID | Notes: SFS support at cranck position
4F | 1F | internal beam :5 ,SHE-13.STEEL.dgn,Design Model:190772 | AS_PFC | 200X75PFC | 1\AS_PFC\200X75PFC | 0 | 25.8472 | 0.0292 | 0.002856 | 17.7829 | 17.6453 | 0.000571 | 0.754738 | 0.07382 | 0.754167 | 0.073248 | 22.900000 | 591.900880 | 5924.695184 | 579.483885 | 5920.211264 | 574.999965 | 4F |  | internal beam | intumescent paint | FD60 | Identification - ID | Notes: SFS support at cranck position
5F | 1F | internal beam :5 ,SHE-13.STEEL.dgn,Design Model:190990 | AS_PFC | 200X75PFC | 1\AS_PFC\200X75PFC | 0 | 3.35433 | 0.0292 | 0.002856 | 2.30778 | 2.23275 | 0.000316 | 0.097946 | 0.00958 | 0.09763 | 0.009264 | 22.900000 | 76.814203 | 768.879988 | 75.202782 | 766.397190 | 72.719984 | 5F |  | internal beam | intumescent paint | FD60 | Identification - ID | Notes: SFS support at cranck position
RP | 1F | internal beam :5 ,SHE-13.STEEL.dgn,Design Model:190992 | AS_PFC | 200X75PFC | 1\AS_PFC\200X75PFC | 0 | 2.11979 | 0.0292 | 0.002856 | 1.45842 | 1.38339 | 0.000316 | 0.061898 | 0.006054 | 0.061582 | 0.005738 | 22.900000 | 48.543215 | 485.898500 | 47.524867 | 483.415702 | 45.042069 | RP |  | internal beam | intumescent paint | FD60 | Identification - ID | Notes: SFS support at cranck position
5F | 1F | internal beam :5 ,SHE-13.STEEL.dgn,Design Model:190998 | AS_PFC | 200X75PFC | 1\AS_PFC\200X75PFC | 0 | 3.35433 | 0.0292 | 0.002856 | 2.30778 | 2.23275 | 0.000316 | 0.097946 | 0.00958 | 0.09763 | 0.009264 | 22.900000 | 76.814203 | 768.879988 | 75.202782 | 766.397190 | 72.719984 | 5F |  | internal beam | intumescent paint | FD60 | Identification - ID | Notes: SFS support at cranck position
RP | 1F | internal beam :5 ,SHE-13.STEEL.dgn,Design Model:191000 | AS_PFC | 200X75PFC | 1\AS_PFC\200X75PFC | 0 | 2.11979 | 0.0292 | 0.002856 | 1.45842 | 1.38339 | 0.000316 | 0.061898 | 0.006054 | 0.061582 | 0.005738 | 22.900000 | 48.543215 | 485.898500 | 47.524867 | 483.415702 | 45.042069 | RP |  | internal beam | intumescent paint | FD60 | Identification - ID | Notes: SFS support at cranck position
RP | 1F | internal beam :5 ,SHE-13.STEEL.dgn,Design Model:191002 | AS_PFC | 200X75PFC | 1\AS_PFC\200X75PFC | 0 | 2.11979 | 0.0292 | 0.002856 | 1.45842 | 1.38339 | 0.000316 | 0.061898 | 0.006054 | 0.061582 | 0.005738 | 22.900000 | 48.543215 | 485.898500 | 47.524867 | 483.415702 | 45.042069 | RP |  | internal beam | intumescent paint | FD60 | Identification - ID | Notes: SFS support at cranck position
5F | 1F | internal beam :5 ,SHE-13.STEEL.dgn,Design Model:191004 | AS_PFC | 200X75PFC | 1\AS_PFC\200X75PFC | 0 | 3.35433 | 0.0292 | 0.002856 | 2.30778 | 2.23275 | 0.000316 | 0.097946 | 0.00958 | 0.09763 | 0.009264 | 22.900000 | 76.814203 | 768.879988 | 75.202782 | 766.397190 | 72.719984 | 5F |  | internal beam | intumescent paint | FD60 | Identification - ID | Notes: SFS support at cranck position
external | GF | existing external beam :15,SHE-14.BALCONY.dgn,Design Model:168529 | BS5950_UC | UC152X152X51 | 1\BS5950_UC\UC152X152X51 | 0 | 5.3944 | 0.0065 | 0.006469 | 5.11389 | 5.04575 | 0.000509 | 0.035064 | 0.034897 | 0.034554 | 0.034388 | 51.200000 | 276.193337 | 275.249317 | 273.943365 | 271.252702 | 269.946750 | external | retained beam | existing external beam | galvanized
external | GF | existing external beam :15,SHE-14.BALCONY.dgn,Design Model:168535 | BS5950_UC | UC152X152X51 | 1\BS5950_UC\UC152X152X51 | 0 | 5.4786 | 0.0065 | 0.006469 | 5.19371 | 5.0445 | 0.001018 | 0.035611 | 0.035442 | 0.034593 | 0.034424 | 51.200000 | 280.504377 | 279.545622 | 278.219285 | 271.552392 | 270.226056 | external | retained beam | existing external beam | galvanized
external | GF | existing external beam :15,SHE-14.BALCONY.dgn,Design Model:168539 | BS5950_UC | UC152X152X51 | 1\BS5950_UC\UC152X152X51 | 0 | 5.4786 | 0.0065 | 0.006469 | 5.19371 | 5.0445 | 0.001018 | 0.035611 | 0.035442 | 0.034593 | 0.034424 | 51.200000 | 280.504377 | 279.545622 | 278.219285 | 271.552392 | 270.226056 | external | retained beam | existing external beam | galvanized
external | GF | existing external beam :15,SHE-14.BALCONY.dgn,Design Model:168541 | BS5950_UC | UC152X152X51 | 1\BS5950_UC\UC152X152X51 | 0 | 2.905 | 0.0065 | 0.006469 | 2.75394 | 2.60473 | 0.001018 | 0.018882 | 0.018793 | 0.017864 | 0.017775 | 51.200000 | 148.736000 | 148.227625 | 147.524342 | 140.234396 | 139.531113 | external | retained beam | existing external beam | galvanized
external | GF | existing external beam :15,SHE-14.BALCONY.dgn,Design Model:168551 | BS5950_UC | UC152X152X51 | 1\BS5950_UC\UC152X152X51 | 0 | 3.84218 | 0.0065 | 0.006469 | 3.64239 | 3.57425 | 0.000509 | 0.024974 | 0.024856 | 0.024465 | 0.024347 | 51.200000 | 196.719650 | 196.047268 | 195.117099 | 192.050653 | 191.120485 | external | retained beam | existing external beam | galvanized
external | GF | existing external beam :15,SHE-14.BALCONY.dgn,Design Model:169209 | BS5950_UC | UC152X152X51 | 1\BS5950_UC\UC152X152X51 | 0 | 1.01038 | 0.0065 | 0.006469 | 0.957841 | 0.970779 | 0 | 0.006567 | 0.006536 | 0.006567 | 0.006536 | 51.200000 | 51.731490 | 51.554673 | 51.310066 | 51.554673 | 51.310066 | external | retained beam | existing external beam | galvanized
external | GF | existing external beam :15,SHE-14.BALCONY.dgn,Design Model:174204 | BS5950_UC | UC152X152X51 | 1\BS5950_UC\UC152X152X51 | 0 | 1.01038 | 0.0065 | 0.006469 | 0.957841 | 0.970779 | 0 | 0.006567 | 0.006536 | 0.006567 | 0.006536 | 51.200000 | 51.731490 | 51.554673 | 51.310066 | 51.554673 | 51.310066 | external | retained beam | existing external beam | galvanized
external | GF | existing external beam :15,SHE-14.BALCONY.dgn,Design Model:174262 | BS5950_UC | UC152X152X51 | 1\BS5950_UC\UC152X152X51 | 0 | 1.01038 | 0.0065 | 0.006469 | 0.957841 | 0.970779 | 0 | 0.006567 | 0.006536 | 0.006567 | 0.006536 | 51.200000 | 51.731490 | 51.554673 | 51.310066 | 51.554673 | 51.310066 | external | retained beam | existing external beam | galvanized
external | GF | existing external beam :15,SHE-14.BALCONY.dgn,Design Model:179383 | BS5950_UC | UC152X152X51 | 1\BS5950_UC\UC152X152X51 | 0 | 2.905 | 0.0065 | 0.006469 | 2.75394 | 2.60473 | 0.001018 | 0.018882 | 0.018793 | 0.017864 | 0.017775 | 51.200000 | 148.736000 | 148.227625 | 147.524342 | 140.234396 | 139.531113 | external | retained beam | existing external beam | galvanized
external | GF | existing external beam :15,SHE-14.BALCONY.dgn,Design Model:179385 | BS5950_UC | UC152X152X51 | 1\BS5950_UC\UC152X152X51 | 0 | 2.905 | 0.0065 | 0.006469 | 2.75394 | 2.60473 | 0.001018 | 0.018882 | 0.018793 | 0.017864 | 0.017775 | 51.200000 | 148.736000 | 148.227625 | 147.524342 | 140.234396 | 139.531113 | external | retained beam | existing external beam | galvanized
external | GF | existing external beam :15,SHE-14.BALCONY.dgn,Design Model:179389 | BS5950_UC | UC152X152X51 | 1\BS5950_UC\UC152X152X51 | 0 | 3.84218 | 0.0065 | 0.006469 | 3.64239 | 3.57425 | 0.000509 | 0.024974 | 0.024856 | 0.024465 | 0.024347 | 51.200000 | 196.719650 | 196.047268 | 195.117099 | 192.050653 | 191.120485 | external | retained beam | existing external beam | galvanized
external | GF | existing external beam :15,SHE-14.BALCONY.dgn,Design Model:179391 | BS5950_UC | UC152X152X51 | 1\BS5950_UC\UC152X152X51 | 0 | 3.84218 | 0.0065 | 0.006469 | 3.64239 | 3.57425 | 0.000509 | 0.024974 | 0.024856 | 0.024465 | 0.024347 | 51.200000 | 196.719650 | 196.047268 | 195.117099 | 192.050653 | 191.120485 | external | retained beam | existing external beam | galvanized
external | GF | existing external beam :15,SHE-14.BALCONY.dgn,Design Model:179394 | BS5950_UC | UC152X152X51 | 1\BS5950_UC\UC152X152X51 | 0 | 5.4786 | 0.0065 | 0.006469 | 5.19371 | 5.0445 | 0.001018 | 0.035611 | 0.035442 | 0.034593 | 0.034424 | 51.200000 | 280.504377 | 279.545622 | 278.219285 | 271.552392 | 270.226056 | external | retained beam | existing external beam | galvanized
external | GF | existing external beam :15,SHE-14.BALCONY.dgn,Design Model:179404 | BS5950_UC | UC152X152X51 | 1\BS5950_UC\UC152X152X51 | 0 | 5.3944 | 0.0065 | 0.006469 | 5.11389 | 5.04575 | 0.000509 | 0.035064 | 0.034897 | 0.034554 | 0.034388 | 51.200000 | 276.193337 | 275.249317 | 273.943365 | 271.252702 | 269.946750 | external | retained beam | existing external beam | galvanized
external | GF | existing external beam :15,SHE-14.BALCONY.dgn,Design Model:179406 | BS5950_UC | UC152X152X51 | 1\BS5950_UC\UC152X152X51 | 0 | 5.3944 | 0.0065 | 0.006469 | 5.11389 | 5.04575 | 0.000509 | 0.035064 | 0.034897 | 0.034554 | 0.034388 | 51.200000 | 276.193337 | 275.249317 | 273.943365 | 271.252702 | 269.946750 | external | retained beam | existing external beam | galvanized

# IfcBeam: S-Beams-PrecastConcrete (67)
Type - PredefinedType: BEAM
Type - Thermal Transmittance - Is External: no; Is Below Grade: no
Type - Structural Usage - Structural | Function: Undefined; Structural | Material: Concrete
Type - Structural Parameters - Section Name: 300x600; Structural Type: Beam; Tapered Member: no
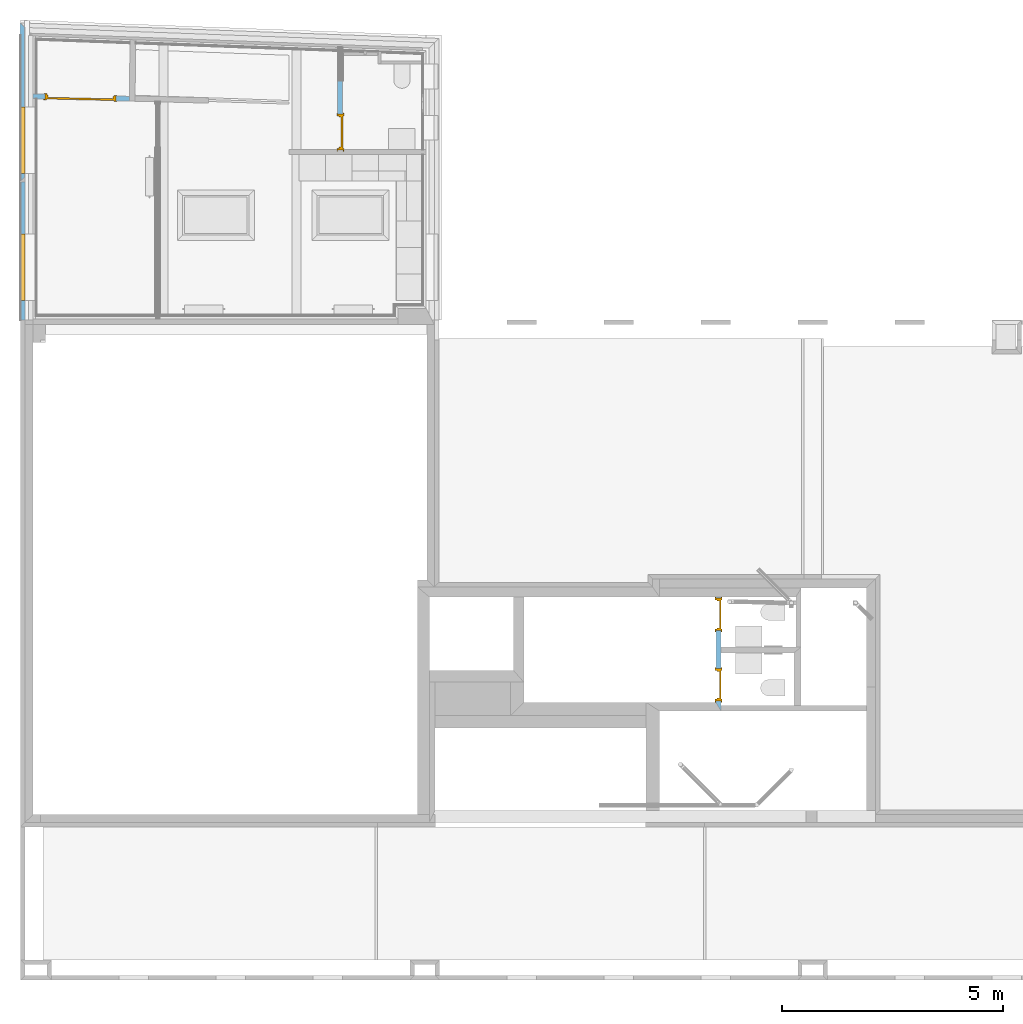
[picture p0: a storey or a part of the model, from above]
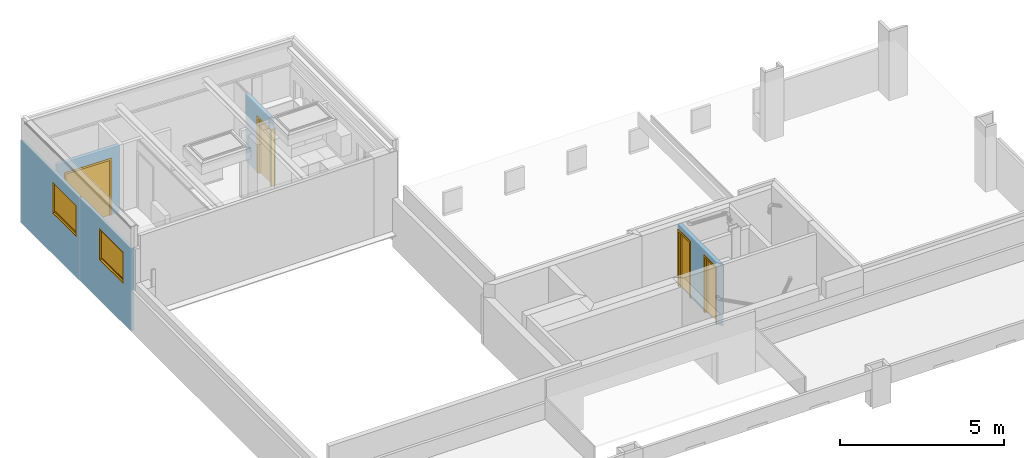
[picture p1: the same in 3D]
Properties of the parts of a building model (IFC2X3), part 3 of 17

# IfcBeam: S-Beams-PrecastConcrete (67)
Type - Quantities | Structural - Length: 0 m; Area | Cross-sectional: 0 m2; Area | Cross-sectional Modeled: 0 m2; Volume | Perforation(s): 0 m3; Volume (Gross): 0 m3; Volume (Gross Modeled): 0 m3; Volume (Net): 0 m3; Volume (Net Modeled): 0 m3; Unit Weight: 0; Material Density: 0; Length x Unit Weight: 0; Volume (Gross) x Density: 0; Volume (Gross Modeled) x Density: 0; Volume (Net) x Density: 0; Volume (Net Modeled) x Density: 0
Type - Materials - Part Definition: S-Beams::S_BSUK_Beams_PrecastConcrete
Type - LEED Parameters - LEED | Pre-consumer Recycled (%): 0; LEED | Regional Material: no; LEED | Post-consumer Recycled (%): 0
Type - Fire Resistance - Fire | IsCombustible: no; Fire | Compartmentation: no
Type - Discipline - Discipline: Structural
Type - Construction Phase - Phase: New Construction
Type - Classification - Uniclass2015: Pr_20_85_08_15
Material: S_BSUK_Beams_PrecastConcrete
Pset_BeamCommon - IsExternal: no; LoadBearing: no
Quantities | Structural - Material Density: 2400.000000
Construction Phase - Phase: Existing to Remain
Name | In | Description | StructuralFramingCommon, Section Name | Structural Parameters, Section Name | Length (m) | Area | Cross-sectional (m2) = Area | Cross-sectional Modeled (m2) | Area | Side Surfaces Modeled (Gross) (m2) | Area | All Surfaces Modeled (Net) (m2) | Volume (Gross) (m3) = Volume (Gross Modeled) (m3) = Volume (Net) (m3) = Volume (Net Modeled) (m3) | Unit Weight | Length x Unit Weight | Volume (Gross) x Density = Volume (Gross Modeled) x Density = Volume (Net) x Density = Volume (Net Modeled) x Density | Type | Material | Grade | Class | Cope Flange Clearance = Cope Web Clearance = Cope Corner Radius = Local Y Offset = Local Z Offset | Cope Corner Treatment
S-Beams-PrecastConcrete | 1F | 4 ,SHE-03.FIRST.dgn,Design Model:422495 | 0.250X2.700 | 6\RECTANGLE\0.250X2.700 | 2.7 | 0.675 | 15.93 | 17.28 | 1.8225 | 5298.750000 | 14306.625000 | 4374.000000 | Beam | Concrete | C40 | Gravity | 0.000 | 0
S-Beams-PrecastConcrete | 1F | 4 ,SHE-03.FIRST.dgn,Design Model:428088 | 0.250X0.548 | 6\RECTANGLE\0.250X0.548 | 0.95 | 0.137 | 1.5162 | 1.7902 | 0.13015 | 1075.450000 | 1021.677500 | 312.360000 | Beam | Concrete | C40 | Gravity | 0.000 | 0
S-Beams-PrecastConcrete | 3F | 6 ,SHE-05.THIRD.dgn,Design Model:524232 | 0.250X0.548 | 6\RECTANGLE\0.250X0.548 | 0.95 | 0.137 | 1.5162 | 1.7902 | 0.13015 | 1075.450000 | 1021.677500 | 312.360000 | Beam | Concrete | C40 | Gravity | 0.000 | 0
S-Beams-PrecastConcrete | 3F | 6 ,SHE-05.THIRD.dgn,Design Model:543879 |  | 6\RECTANGLE\0.250X2.700 | 2.71 | 0.6875 | 16.26 | 17.635 | 1.86312 | 5396.875000 | 14625.531250 | 4471.500000
S-Beams-PrecastConcrete | GF | 9 ,SHE-10.CONCRETE.dgn,Design Model:202154 | 0.400X0.500 | 6\RECTANGLE\0.400X0.500 | 14.06 | 0.2 | 25.308 | 25.708 | 2.812 | 1570.000000 | 22074.200000 | 6748.800000 | Beam | Concrete | C40 | Gravity | 0.000 | 0
S-Beams-PrecastConcrete | GF | 9 ,SHE-10.CONCRETE.dgn,Design Model:202156 | 0.400X0.500 | 6\RECTANGLE\0.400X0.500 | 5.8299 | 0.2 | 10.4938 | 10.8938 | 1.16598 | 1570.000000 | 9152.938324 | 2798.350570 | Beam | Concrete | C40 | Gravity | 0.000 | 0
S-Beams-PrecastConcrete | GF | 9 ,SHE-10.CONCRETE.dgn,Design Model:201619 | 0.400X0.380 | 6\RECTANGLE\0.400X0.380 | 11.1535 | 0.152 | 17.3995 | 17.7035 | 1.69534 | 1193.200000 | 13308.401638 | 4068.810692 | Beam | Concrete | C40 | Gravity | 0.000 | 0
S-Beams-PrecastConcrete | GF | 9 ,SHE-10.CONCRETE.dgn,Design Model:141247 | 0.500X1.800 | 6\RECTANGLE\0.500X1.800 | 13.62 | 0.9 | 62.652 | 64.452 | 12.258 | 7065.000000 | 96225.300000 | 29419.200000 | Beam | Concrete | C40 | Gravity | 0.000 | 0
S-Beams-PrecastConcrete | GF | 9 ,SHE-10.CONCRETE.dgn,Design Model:201617 | 0.400X1.030 | 6\RECTANGLE\0.400X1.030 | 3.54646 | 0.412 | 10.1429 | 10.9669 | 1.46114 | 3234.200000 | 11469.967139 | 3506.741546 | Beam | Concrete | C40 | Gravity | 0.000 | 0
S-Beams-PrecastConcrete | GF | 9 ,SHE-10.CONCRETE.dgn,Design Model:141269 | 0.300X1.030 | 6\RECTANGLE\0.300X1.030 | 25.98 | 0.309 | 69.1068 | 69.7248 | 8.02782 | 2425.650000 | 63018.387000 | 19266.768000 | Beam | Concrete | C40 | Gravity | 0.000 | 0
S-Beams-PrecastConcrete | GF | 9 ,SHE-10.CONCRETE.dgn,Design Model:201404 | 0.400X1.030 | 6\RECTANGLE\0.400X1.030 | 3.54646 | 0.412 | 10.1429 | 10.9669 | 1.46114 | 3234.200000 | 11469.967139 | 3506.741546 | Beam | Concrete | C40 | Gravity | 0.000 | 0
S-Beams-PrecastConcrete | GF | 9 ,SHE-10.CONCRETE.dgn,Design Model:201590 | 0.400X0.380 | 6\RECTANGLE\0.400X0.380 | 11.1535 | 0.152 | 17.3995 | 17.7035 | 1.69534 | 1193.200000 | 13308.401638 | 4068.810692 | Beam | Concrete | C40 | Gravity | 0.000 | 0
S-Beams-PrecastConcrete | GF | 9 ,SHE-10.CONCRETE.dgn,Design Model:204340 | 0.500X0.380 | 6\RECTANGLE\0.500X0.380 | 4.07 | 0.19 | 7.1632 | 7.5432 | 0.7733 | 1491.500000 | 6070.405000 | 1855.920000 | Beam | Concrete | C40 | Gravity | 0.000 | 0
S-Beams-PrecastConcrete | GF | 9 ,SHE-10.CONCRETE.dgn,Design Model:204388 | 0.500X0.380 | 6\RECTANGLE\0.500X0.380 | 8.29 | 0.19 | 14.5904 | 14.9704 | 1.5751 | 1491.500000 | 12364.535000 | 3780.240000 | Beam | Concrete | C40 | Gravity | 0.000 | 0
S-Beams-PrecastConcrete | GF | 9 ,SHE-10.CONCRETE.dgn,Design Model:221948 | 0.300X0.250 | 6\RECTANGLE\0.300X0.250 | 8.36 | 0.075 | 9.196 | 9.346 | 0.627 | 588.750000 | 4921.950000 | 1504.800000 | Beam | Concrete | C40 | Gravity | 0.000 | 0
S-Beams-PrecastConcrete | GF | 9 ,SHE-10.CONCRETE.dgn,Design Model:223033 | 0.250X0.700 | 6\RECTANGLE\0.250X0.700 | 8.40304 | 0.175 | 15.9658 | 16.3158 | 1.47053 | 1373.750000 | 11543.673441 | 3529.275956 | Beam | Concrete | C40 | Gravity | 0.000 | 0
S-Beams-PrecastConcrete | GF | 9 ,SHE-10.CONCRETE.dgn,Design Model:223466 | 0.400X0.340 | 6\RECTANGLE\0.400X0.340 | 14.06 | 0.136 | 20.8088 | 21.0808 | 1.91216 | 1067.600000 | 15010.456000 | 4589.184000 | Beam | Concrete | C40 | Gravity | 0.000 | 0
S-Beams-PrecastConcrete | GF | 9 ,SHE-10.CONCRETE.dgn,Design Model:223473 | 0.400X0.340 | 6\RECTANGLE\0.400X0.340 | 14.06 | 0.136 | 20.8088 | 21.0808 | 1.91216 | 1067.600000 | 15010.456000 | 4589.184000 | Beam | Concrete | C40 | Gravity | 0.000 | 0
S-Beams-PrecastConcrete | GF | 9 ,SHE-10.CONCRETE.dgn,Design Model:224976 | 0.400X0.340 | 6\RECTANGLE\0.400X0.340 | 6.47788 | 0.136 | 9.58727 | 9.85927 | 0.880992 | 1067.600000 | 6915.788288 | 2114.381133 | Beam | Concrete | C40 | Gravity | 0.000 | 0
S-Beams-PrecastConcrete | GF | 9 ,SHE-10.CONCRETE.dgn,Design Model:224978 | 0.400X0.340 | 6\RECTANGLE\0.400X0.340 | 6.17178 | 0.136 | 9.13424 | 9.40624 | 0.839363 | 1067.600000 | 6588.997190 | 2014.470479 | Beam | Concrete | C40 | Gravity | 0.000 | 0
S-Beams-PrecastConcrete | GF | 9 ,SHE-10.CONCRETE.dgn,Design Model:292563 | 0.330X0.950 | 6\RECTANGLE\0.330X0.950 | 25.9 | 0.3135 | 66.304 | 66.931 | 8.11965 | 2460.975000 | 63739.252500 | 19487.160000 | Beam | Concrete | C40 | Gravity | 0.000 | 0
S-Beams-PrecastConcrete | GF | 9 ,SHE-10.CONCRETE.dgn,Design Model:292566 | 0.370X0.950 | 6\RECTANGLE\0.370X0.950 | 14.56 | 0.3515 | 38.4384 | 39.1414 | 5.11784 | 2759.275000 | 40175.044000 | 12282.816000 | Beam | Concrete | C40 | Gravity | 0.000 | 0
S-Beams-PrecastConcrete | GF | 9 ,SHE-10.CONCRETE.dgn,Design Model:292568 | 0.330X0.950 | 6\RECTANGLE\0.330X0.950 | 25.9 | 0.3135 | 66.304 | 66.931 | 8.11965 | 2460.975000 | 63739.252500 | 19487.160000 | Beam | Concrete | C40 | Gravity | 0.000 | 0
S-Beams-PrecastConcrete | GF | 9 ,SHE-10.CONCRETE.dgn,Design Model:292570 | 0.370X0.950 | 6\RECTANGLE\0.370X0.950 | 14.56 | 0.3515 | 38.4384 | 39.1414 | 5.11784 | 2759.275000 | 40175.044000 | 12282.816000 | Beam | Concrete | C40 | Gravity | 0.000 | 0
S-Beams-PrecastConcrete | GF | 9 ,SHE-10.CONCRETE.dgn,Design Model:313489 | 0.390X0.500 | 6\RECTANGLE\0.390X0.500 | 8.46 | 0.195 | 15.0588 | 15.4488 | 1.6497 | 1530.750000 | 12950.145000 | 3959.280000 | Beam | Concrete | C40 | Gravity | 0.000 | 0
S-Beams-PrecastConcrete | GF | 9 ,SHE-10.CONCRETE.dgn,Design Model:314231 | 0.400X0.500 | 6\RECTANGLE\0.400X0.500 | 5.8299 | 0.2 | 10.4938 | 10.8938 | 1.16598 | 1570.000000 | 9152.938324 | 2798.350570 | Beam | Concrete | C40 | Gravity | 0.000 | 0
S-Beams-PrecastConcrete | GF | 9 ,SHE-10.CONCRETE.dgn,Design Model:314234 | 0.300X0.500 | 6\RECTANGLE\0.300X0.500 | 2.42021 | 0.15 | 3.87233 | 4.17233 | 0.363031 | 1177.500000 | 2849.792514 | 871.274144 | Beam | Concrete | C40 | Gravity | 0.000 | 0
S-Beams-PrecastConcrete | GF | 9 ,SHE-10.CONCRETE.dgn,Design Model:314855 | 0.400X0.500 | 6\RECTANGLE\0.400X0.500 | 5.8299 | 0.2 | 10.4938 | 10.8938 | 1.16598 | 1570.000000 | 9152.938324 | 2798.350570 | Beam | Concrete | C40 | Gravity | 0.000 | 0
S-Beams-PrecastConcrete | GF | 9 ,SHE-10.CONCRETE.dgn,Design Model:314857 | 0.300X0.500 | 6\RECTANGLE\0.300X0.500 | 2.42021 | 0.15 | 3.87233 | 4.17233 | 0.363031 | 1177.500000 | 2849.792514 | 871.274144 | Beam | Concrete | C40 | Gravity | 0.000 | 0
S-Beams-PrecastConcrete | GF | 9 ,SHE-10.CONCRETE.dgn,Design Model:314859 | 0.400X0.500 | 6\RECTANGLE\0.400X0.500 | 5.8299 | 0.2 | 10.4938 | 10.8938 | 1.16598 | 1570.000000 | 9152.938324 | 2798.350570 | Beam | Concrete | C40 | Gravity | 0.000 | 0
S-Beams-PrecastConcrete | GF | 9 ,SHE-10.CONCRETE.dgn,Design Model:314864 | 0.400X0.500 | 6\RECTANGLE\0.400X0.500 | 5.8299 | 0.2 | 10.4938 | 10.8938 | 1.16598 | 1570.000000 | 9152.938324 | 2798.350570 | Beam | Concrete | C40 | Gravity | 0.000 | 0
S-Beams-PrecastConcrete | GF | 9 ,SHE-10.CONCRETE.dgn,Design Model:314866 | 0.300X0.500 | 6\RECTANGLE\0.300X0.500 | 2.42021 | 0.15 | 3.87233 | 4.17233 | 0.363031 | 1177.500000 | 2849.792514 | 871.274144 | Beam | Concrete | C40 | Gravity | 0.000 | 0
S-Beams-PrecastConcrete | GF | 9 ,SHE-10.CONCRETE.dgn,Design Model:314868 | 0.400X0.500 | 6\RECTANGLE\0.400X0.500 | 5.8299 | 0.2 | 10.4938 | 10.8938 | 1.16598 | 1570.000000 | 9152.938324 | 2798.350570 | Beam | Concrete | C40 | Gravity | 0.000 | 0
S-Beams-PrecastConcrete | GF | 9 ,SHE-10.CONCRETE.dgn,Design Model:314879 | 0.390X0.500 | 6\RECTANGLE\0.390X0.500 | 8.46 | 0.195 | 15.0588 | 15.4488 | 1.6497 | 1530.750000 | 12950.145000 | 3959.280000 | Beam | Concrete | C40 | Gravity | 0.000 | 0
S-Beams-PrecastConcrete | GF | 9 ,SHE-10.CONCRETE.dgn,Design Model:314885 | 0.390X0.500 | 6\RECTANGLE\0.390X0.500 | 8.46 | 0.195 | 15.0588 | 15.4488 | 1.6497 | 1530.750000 | 12950.145000 | 3959.280000 | Beam | Concrete | C40 | Gravity | 0.000 | 0
S-Beams-PrecastConcrete | GF | 9 ,SHE-10.CONCRETE.dgn,Design Model:314897 | 0.400X0.500 | 6\RECTANGLE\0.400X0.500 | 14.06 | 0.2 | 25.308 | 25.708 | 2.812 | 1570.000000 | 22074.200000 | 6748.800000 | Beam | Concrete | C40 | Gravity | 0.000 | 0
S-Beams-PrecastConcrete | GF | 9 ,SHE-10.CONCRETE.dgn,Design Model:314899 | 0.400X0.500 | 6\RECTANGLE\0.400X0.500 | 14.06 | 0.2 | 25.308 | 25.708 | 2.812 | 1570.000000 | 22074.200000 | 6748.800000 | Beam | Concrete | C40 | Gravity | 0.000 | 0
S-Beams-PrecastConcrete | GF | 9 ,SHE-10.CONCRETE.dgn,Design Model:315719 | 0.390X0.500 | 6\RECTANGLE\0.390X0.500 | 8.46 | 0.195 | 15.0588 | 15.4488 | 1.6497 | 1530.750000 | 12950.145000 | 3959.280000 | Beam | Concrete | C40 | Gravity | 0.000 | 0
S-Beams-PrecastConcrete | GF | 9 ,SHE-10.CONCRETE.dgn,Design Model:315765 | 0.250X4.495 | 6\RECTANGLE\0.250X4.495 | 2.75 | 1.12375 | 26.0975 | 28.345 | 3.09031 | 8821.437500 | 24258.953125 | 7416.750000 | Beam | Concrete | C40 | Gravity | 0.000 | 0
S-Beams-PrecastConcrete | GF | 9 ,SHE-10.CONCRETE.dgn,Design Model:204245 | 0.250X0.750 | 6\RECTANGLE\0.250X0.750 | 26.14 | 0.1875 | 52.28 | 52.655 | 4.90125 | 1471.875000 | 38474.812500 | 11763.000000 | Beam | Concrete | C40 | Gravity | 0.000 | 0
S-Beams-PrecastConcrete | GF | 9 ,SHE-10.CONCRETE.dgn,Design Model:203918 | 0.250X0.750 | 6\RECTANGLE\0.250X0.750 | 14.56 | 0.1875 | 29.12 | 29.495 | 2.73 | 1471.875000 | 21430.500000 | 6552.000000 | Beam | Concrete | C40 | Gravity | 0.000 | 0
S-Beams-PrecastConcrete | GF | 9 ,SHE-10.CONCRETE.dgn,Design Model:204122 | 0.250X0.750 | 6\RECTANGLE\0.250X0.750 | 26.14 | 0.1875 | 52.28 | 52.655 | 4.90125 | 1471.875000 | 38474.812500 | 11763.000000 | Beam | Concrete | C40 | Gravity | 0.000 | 0
S-Beams-PrecastConcrete | GF | 9 ,SHE-10.CONCRETE.dgn,Design Model:204107 | 0.250X0.750 | 6\RECTANGLE\0.250X0.750 | 14.56 | 0.1875 | 29.12 | 29.495 | 2.73 | 1471.875000 | 21430.500000 | 6552.000000 | Beam | Concrete | C40 | Gravity | 0.000 | 0
S-Beams-PrecastConcrete | GF | 9 ,SHE-10.CONCRETE.dgn,Design Model:209403 | 0.250X0.750 | 6\RECTANGLE\0.250X0.750 | 14.56 | 0.1875 | 29.12 | 29.495 | 2.73 | 1471.875000 | 21430.500000 | 6552.000000 | Beam | Concrete | C40 | Gravity | 0.000 | 0
S-Beams-PrecastConcrete | GF | 9 ,SHE-10.CONCRETE.dgn,Design Model:209404 | 0.250X0.750 | 6\RECTANGLE\0.250X0.750 | 26.14 | 0.1875 | 52.28 | 52.655 | 4.90125 | 1471.875000 | 38474.812500 | 11763.000000 | Beam | Concrete | C40 | Gravity | 0.000 | 0
S-Beams-PrecastConcrete | GF | 9 ,SHE-10.CONCRETE.dgn,Design Model:209405 | 0.250X0.750 | 6\RECTANGLE\0.250X0.750 | 26.14 | 0.1875 | 52.28 | 52.655 | 4.90125 | 1471.875000 | 38474.812500 | 11763.000000 | Beam | Concrete | C40 | Gravity | 0.000 | 0
S-Beams-PrecastConcrete | GF | 9 ,SHE-10.CONCRETE.dgn,Design Model:209406 | 0.250X0.750 | 6\RECTANGLE\0.250X0.750 | 14.56 | 0.1875 | 29.12 | 29.495 | 2.73 | 1471.875000 | 21430.500000 | 6552.000000 | Beam | Concrete | C40 | Gravity | 0.000 | 0
S-Beams-PrecastConcrete | GF | 9 ,SHE-10.CONCRETE.dgn,Design Model:209414 | 0.250X0.750 | 6\RECTANGLE\0.250X0.750 | 26.14 | 0.1875 | 52.28 | 52.655 | 4.90125 | 1471.875000 | 38474.812500 | 11763.000000 | Beam | Concrete | C40 | Gravity | 0.000 | 0
S-Beams-PrecastConcrete | GF | 9 ,SHE-10.CONCRETE.dgn,Design Model:209412 | 0.250X0.750 | 6\RECTANGLE\0.250X0.750 | 14.56 | 0.1875 | 29.12 | 29.495 | 2.73 | 1471.875000 | 21430.500000 | 6552.000000 | Beam | Concrete | C40 | Gravity | 0.000 | 0
S-Beams-PrecastConcrete | GF | 9 ,SHE-10.CONCRETE.dgn,Design Model:209413 | 0.250X0.750 | 6\RECTANGLE\0.250X0.750 | 26.14 | 0.1875 | 52.28 | 52.655 | 4.90125 | 1471.875000 | 38474.812500 | 11763.000000 | Beam | Concrete | C40 | Gravity | 0.000 | 0
S-Beams-PrecastConcrete | GF | 9 ,SHE-10.CONCRETE.dgn,Design Model:209415 | 0.250X0.750 | 6\RECTANGLE\0.250X0.750 | 14.56 | 0.1875 | 29.12 | 29.495 | 2.73 | 1471.875000 | 21430.500000 | 6552.000000 | Beam | Concrete | C40 | Gravity | 0.000 | 0
S-Beams-PrecastConcrete | GF | 9 ,SHE-10.CONCRETE.dgn,Design Model:223496 | 0.400X0.340 | 6\RECTANGLE\0.400X0.340 | 14.06 | 0.136 | 20.8088 | 21.0808 | 1.91216 | 1067.600000 | 15010.456000 | 4589.184000 | Beam | Concrete | C40 | Gravity | 0.000 | 0
S-Beams-PrecastConcrete | GF | 9 ,SHE-10.CONCRETE.dgn,Design Model:223489 | 0.400X0.340 | 6\RECTANGLE\0.400X0.340 | 14.06 | 0.136 | 20.8088 | 21.0808 | 1.91216 | 1067.600000 | 15010.456000 | 4589.184000 | Beam | Concrete | C40 | Gravity | 0.000 | 0
S-Beams-PrecastConcrete | GF | 9 ,SHE-10.CONCRETE.dgn,Design Model:223615 | 0.400X0.340 | 6\RECTANGLE\0.400X0.340 | 14.06 | 0.136 | 20.8088 | 21.0808 | 1.91216 | 1067.600000 | 15010.456000 | 4589.184000 | Beam | Concrete | C40 | Gravity | 0.000 | 0
S-Beams-PrecastConcrete | GF | 9 ,SHE-10.CONCRETE.dgn,Design Model:223953 | 0.400X0.340 | 6\RECTANGLE\0.400X0.340 | 14.06 | 0.136 | 20.8088 | 21.0808 | 1.91216 | 1067.600000 | 15010.456000 | 4589.184000 | Beam | Concrete | C40 | Gravity | 0.000 | 0
S-Beams-PrecastConcrete | GF | 9 ,SHE-10.CONCRETE.dgn,Design Model:224292 | 0.400X0.340 | 6\RECTANGLE\0.400X0.340 | 14.06 | 0.136 | 20.8088 | 21.0808 | 1.91216 | 1067.600000 | 15010.456000 | 4589.184000 | Beam | Concrete | C40 | Gravity | 0.000 | 0
S-Beams-PrecastConcrete | GF | 9 ,SHE-10.CONCRETE.dgn,Design Model:224293 | 0.400X0.340 | 6\RECTANGLE\0.400X0.340 | 14.06 | 0.136 | 20.8088 | 21.0808 | 1.91216 | 1067.600000 | 15010.456000 | 4589.184000 | Beam | Concrete | C40 | Gravity | 0.000 | 0
S-Beams-PrecastConcrete | GF | 9 ,SHE-10.CONCRETE.dgn,Design Model:224297 | 0.400X0.340 | 6\RECTANGLE\0.400X0.340 | 14.06 | 0.136 | 20.8088 | 21.0808 | 1.91216 | 1067.600000 | 15010.456000 | 4589.184000 | Beam | Concrete | C40 | Gravity | 0.000 | 0
S-Beams-PrecastConcrete | GF | 9 ,SHE-10.CONCRETE.dgn,Design Model:224635 | 0.400X0.340 | 6\RECTANGLE\0.400X0.340 | 14.06 | 0.136 | 20.8088 | 21.0808 | 1.91216 | 1067.600000 | 15010.456000 | 4589.184000 | Beam | Concrete | C40 | Gravity | 0.000 | 0
S-Beams-PrecastConcrete | GF | 9 ,SHE-10.CONCRETE.dgn,Design Model:224974 | 0.400X0.340 | 6\RECTANGLE\0.400X0.340 | 14.06 | 0.136 | 20.8088 | 21.0808 | 1.91216 | 1067.600000 | 15010.456000 | 4589.184000 | Beam | Concrete | C40 | Gravity | 0.000 | 0
S-Beams-PrecastConcrete | GF | 9 ,SHE-10.CONCRETE.dgn,Design Model:224975 | 0.400X0.340 | 6\RECTANGLE\0.400X0.340 | 14.06 | 0.136 | 20.8088 | 21.0808 | 1.91216 | 1067.600000 | 15010.456000 | 4589.184000 | Beam | Concrete | C40 | Gravity | 0.000 | 0
S-Beams-PrecastConcrete | GF | 9 ,SHE-10.CONCRETE.dgn,Design Model:342522 | 0.170X0.150 | 6\RECTANGLE\0.170X0.150 | 26.64 | 0.0255 | 17.0496 | 17.1006 | 0.67932 | 200.175000 | 5332.662000 | 1630.368000 | Beam | Concrete | C40 | Gravity | 0.000 | 0
S-Beams-PrecastConcrete | GF | 9 ,SHE-10.CONCRETE.dgn,Design Model:342531 | 0.170X0.150 | 6\RECTANGLE\0.170X0.150 | 14.9 | 0.0255 | 9.536 | 9.587 | 0.37995 | 200.175000 | 2982.607500 | 911.880000 | Beam | Concrete | C40 | Gravity | 0.000 | 0
S-Beams-PrecastConcrete | GF | 9 ,SHE-10.CONCRETE.dgn,Design Model:342553 | 0.170X0.150 | 6\RECTANGLE\0.170X0.150 | 14.9 | 0.0255 | 9.536 | 9.587 | 0.37995 | 200.175000 | 2982.607500 | 911.880000 | Beam | Concrete | C40 | Gravity | 0.000 | 0
S-Beams-PrecastConcrete | GF | 9 ,SHE-10.CONCRETE.dgn,Design Model:342555 | 0.170X0.150 | 6\RECTANGLE\0.170X0.150 | 26.64 | 0.0255 | 17.0496 | 17.1006 | 0.67932 | 200.175000 | 5332.662000 | 1630.368000 | Beam | Concrete | C40 | Gravity | 0.000 | 0
S-Beams-PrecastConcrete | 2F | 18 ,SHE-04.SECOND.dgn,Design Model:417642 | 0.250X2.700 | 6\RECTANGLE\0.250X2.700 | 2.7 | 0.675 | 15.93 | 17.28 | 1.8225 | 5298.750000 | 14306.625000 | 4374.000000 | Beam | Concrete | C40 | Gravity | 0.000 | 0
S-Beams-PrecastConcrete | 2F | 18 ,SHE-04.SECOND.dgn,Design Model:417644 | 0.250X0.548 | 6\RECTANGLE\0.250X0.548 | 0.95 | 0.137 | 1.5162 | 1.7902 | 0.13015 | 1075.450000 | 1021.677500 | 312.360000 | Beam | Concrete | C40 | Gravity | 0.000 | 0

# IfcBeam: S-Beams:S_BSUK_Beams_PrecastConcrete (5)
Material: S_BSUK_Beams_PrecastConcrete
BuildingDesignerForm - Type: Beam; Material: Concrete; Grade: C40; Class: Gravity; Cope Flange Clearance: 0.000; Cope Web Clearance: 0.000; Cope Corner Treatment: 0; Cope Corner Radius: 0.000; Local Y Offset: 0.000; Local Z Offset: 0.000
Name | In | Description | Section Name
S-Beams--S_BSUK_Beams_PrecastConcrete | 1F | 4,SHE-03.FIRST.dgn ,Design Model:428093 | 0.250X0.548
S-Beams--S_BSUK_Beams_PrecastConcrete | 3F | 6,SHE-05.THIRD.dgn ,Design Model:524236 | 0.250X0.548
S-Beams--S_BSUK_Beams_PrecastConcrete | GF | 9,SHE-10.CONCRETE.dgn ,Design Model:302552 | 0.120X2.800
S-Beams--S_BSUK_Beams_PrecastConcrete | GF | 9,SHE-10.CONCRETE.dgn ,Design Model:302572 | 0.120X2.800
S-Beams--S_BSUK_Beams_PrecastConcrete | 2F | 18,SHE-04.SECOND.dgn ,Design Model:417640 | 0.250X0.548

# IfcBeam: SHE_A-Beams-Steel-Purlin_150m15 (479)
In: 1F
Type - Description: cold formed purlin; PredefinedType: BEAM
Type - Profile - CodeSystem: AS_C_PURLINS; Name: C15015
Type - Thermal Transmittance - Is External: no; Is Below Grade: no
Type - Structural Usage - Structural | Material: Steel
Type - Structural Parameters - Section Name: 1\AS_C_PURLINS\C15015; Structural Type: Beam; Tapered Member: no
Type - Steel Beam Results - Camber: 0 m; End 1 Shear: 0; End 2 Shear: 0
Type - Materials - Part Definition: A-Beams::A_BSUK_Beams_Steel
Type - Identification - ID | Type ID: 150m15; ID | Description: cold formed purlin
Type - Fireproofing - Has Fireproofing: no; Fireproofing Thickness: 0 m
Type - Fire Resistance - Fire | IsCombustible: no; Fire | Compartmentation: no
Type - Discipline - Discipline: Architectural
Type - Construction Phase - Phase: New Construction
Type - Classification - Uniclass2015: Pr_20_85_08_11
Material: A_BSUK_Beams_Steel
Pset_BeamCommon - IsExternal: no; LoadBearing: no
StructuralFramingCommon - Section Name: C15015
Quantities | Structural - Area | Cross-sectional: 0.00443 m2; Volume | Perforation(s): 0 m3; Unit Weight: 3.590000; Material Density: 7850.000000
Identification - ID | Name (Alternate): joist - grey; ID | Description: cold formed steel joists; ID | Keynote: intumescent paint
BuildingDesignerForm - Cope Flange Clearance: 0.000; Cope Web Clearance: 0.000; Cope Corner Treatment: 0; Cope Corner Radius: 0.000; Local Y Offset: 0.000; Local Z Offset: 0.000
Name | Description | FireRating = Fire | Rating | Length (m) | Area | Cross-sectional Modeled (m2) | Area | Side Surfaces Modeled (Gross) (m2) | Area | All Surfaces Modeled (Net) (m2) | Volume (Gross) (m3) = Volume (Net) (m3) | Volume (Gross Modeled) (m3) = Volume (Net Modeled) (m3) | Length x Unit Weight | Volume (Gross) x Density = Volume (Net) x Density | Volume (Gross Modeled) x Density = Volume (Net Modeled) x Density | ID | Number
4F | 150m15 - cold formed steel joists :5,SHE-13.STEEL.dgn,Design Model:123656 | FD60 | 3.9709 | 0.000457 | 2.43416 | 2.43508 | 0.017591 | 0.001817 | 14.255531 | 138.090033 | 14.260991 | 4F
4F | 150m15 - cold formed steel joists :5,SHE-13.STEEL.dgn,Design Model:123658 | FD60 | 3.9709 | 0.000457 | 2.43416 | 2.43508 | 0.017591 | 0.001817 | 14.255531 | 138.090033 | 14.260991 | 4F
4F | 150m15 - cold formed steel joists :5,SHE-13.STEEL.dgn,Design Model:123660 | FD60 | 3.9709 | 0.000457 | 2.43416 | 2.43508 | 0.017591 | 0.001817 | 14.255531 | 138.090033 | 14.260991 | 4F
4F | 150m15 - cold formed steel joists :5,SHE-13.STEEL.dgn,Design Model:123662 | FD60 | 3.9709 | 0.000457 | 2.43416 | 2.43508 | 0.017591 | 0.001817 | 14.255531 | 138.090033 | 14.260991 | 4F
4F | 150m15 - cold formed steel joists :5,SHE-13.STEEL.dgn,Design Model:123664 | FD60 | 3.9709 | 0.000457 | 2.43416 | 2.43508 | 0.017591 | 0.001817 | 14.255531 | 138.090033 | 14.260991 | 4F
4F | 150m15 - cold formed steel joists :5,SHE-13.STEEL.dgn,Design Model:123666 | FD60 | 3.9709 | 0.000457 | 2.43416 | 2.43508 | 0.017591 | 0.001817 | 14.255531 | 138.090033 | 14.260991 | 4F
4F | 150m15 - cold formed steel joists :5,SHE-13.STEEL.dgn,Design Model:123668 | FD60 | 3.9709 | 0.000457 | 2.43416 | 2.43508 | 0.017591 | 0.001817 | 14.255531 | 138.090033 | 14.260991 | 4F
4F | 150m15 - cold formed steel joists :5,SHE-13.STEEL.dgn,Design Model:123670 | FD60 | 3.9709 | 0.000457 | 2.43416 | 2.43508 | 0.017591 | 0.001817 | 14.255531 | 138.090033 | 14.260991 | 4F
4F | 150m15 - cold formed steel joists :5,SHE-13.STEEL.dgn,Design Model:123672 | FD60 | 3.9709 | 0.000457 | 2.43416 | 2.43508 | 0.017591 | 0.001817 | 14.255531 | 138.090033 | 14.260991 | 4F
4F | 150m15 - cold formed steel joists :5,SHE-13.STEEL.dgn,Design Model:123674 | FD60 | 3.9709 | 0.000457 | 2.43416 | 2.43508 | 0.017591 | 0.001817 | 14.255531 | 138.090033 | 14.260991 | 4F
4F | 150m15 - cold formed steel joists :5,SHE-13.STEEL.dgn,Design Model:123676 | FD60 | 3.9709 | 0.000457 | 2.43416 | 2.43508 | 0.017591 | 0.001817 | 14.255531 | 138.090033 | 14.260991 | 4F
4F | 150m15 - cold formed steel joists :5,SHE-13.STEEL.dgn,Design Model:123678 | FD60 | 3.9709 | 0.000457 | 2.43416 | 2.43508 | 0.017591 | 0.001817 | 14.255531 | 138.090033 | 14.260991 | 4F
4F | 150m15 - cold formed steel joists :5,SHE-13.STEEL.dgn,Design Model:123682 | FD60 | 4.2009 | 0.000457 | 2.57515 | 2.57607 | 0.01861 | 0.001922 | 15.081231 | 146.088398 | 15.087007 | 4F
4F | 150m15 - cold formed steel joists :5,SHE-13.STEEL.dgn,Design Model:123684 | FD60 | 4.2009 | 0.000457 | 2.57515 | 2.57607 | 0.01861 | 0.001922 | 15.081231 | 146.088398 | 15.087007 | 4F
4F | 150m15 - cold formed steel joists :5,SHE-13.STEEL.dgn,Design Model:123686 | FD60 | 4.2009 | 0.000457 | 2.57515 | 2.57607 | 0.01861 | 0.001922 | 15.081231 | 146.088398 | 15.087007 | 4F
4F | 150m15 - cold formed steel joists :5,SHE-13.STEEL.dgn,Design Model:123688 | FD60 | 4.2009 | 0.000457 | 2.57515 | 2.57607 | 0.01861 | 0.001922 | 15.081231 | 146.088398 | 15.087007 | 4F
4F | 150m15 - cold formed steel joists :5,SHE-13.STEEL.dgn,Design Model:123690 | FD60 | 4.2009 | 0.000457 | 2.57515 | 2.57607 | 0.01861 | 0.001922 | 15.081231 | 146.088398 | 15.087007 | 4F
4F | 150m15 - cold formed steel joists :5,SHE-13.STEEL.dgn,Design Model:123692 | FD60 | 4.2009 | 0.000457 | 2.57515 | 2.57607 | 0.01861 | 0.001922 | 15.081231 | 146.088398 | 15.087007 | 4F
4F | 150m15 - cold formed steel joists :5,SHE-13.STEEL.dgn,Design Model:123694 | FD60 | 4.2009 | 0.000457 | 2.57515 | 2.57607 | 0.01861 | 0.001922 | 15.081231 | 146.088398 | 15.087007 | 4F
4F | 150m15 - cold formed steel joists :5,SHE-13.STEEL.dgn,Design Model:123696 | FD60 | 4.2009 | 0.000457 | 2.57515 | 2.57607 | 0.01861 | 0.001922 | 15.081231 | 146.088398 | 15.087007 | 4F
4F | 150m15 - cold formed steel joists :5,SHE-13.STEEL.dgn,Design Model:123698 | FD60 | 4.2009 | 0.000457 | 2.57515 | 2.57607 | 0.01861 | 0.001922 | 15.081231 | 146.088398 | 15.087007 | 4F
4F | 150m15 - cold formed steel joists :5,SHE-13.STEEL.dgn,Design Model:123700 | FD60 | 4.2009 | 0.000457 | 2.57515 | 2.57607 | 0.01861 | 0.001922 | 15.081231 | 146.088398 | 15.087007 | 4F
4F | 150m15 - cold formed steel joists :5,SHE-13.STEEL.dgn,Design Model:123702 | FD60 | 4.2009 | 0.000457 | 2.57515 | 2.57607 | 0.01861 | 0.001922 | 15.081231 | 146.088398 | 15.087007 | 4F
4F | 150m15 - cold formed steel joists :5,SHE-13.STEEL.dgn,Design Model:123704 | FD60 | 4.2009 | 0.000457 | 2.57515 | 2.57607 | 0.01861 | 0.001922 | 15.081231 | 146.088398 | 15.087007 | 4F
4F | 150m15 - cold formed steel joists :5,SHE-13.STEEL.dgn,Design Model:123708 | FD60 | 4.2009 | 0.000457 | 2.57515 | 2.57607 | 0.01861 | 0.001922 | 15.081231 | 146.088398 | 15.087007 | 4F
4F | 150m15 - cold formed steel joists :5,SHE-13.STEEL.dgn,Design Model:123710 | FD60 | 4.2009 | 0.000457 | 2.57515 | 2.57607 | 0.01861 | 0.001922 | 15.081231 | 146.088398 | 15.087007 | 4F
4F | 150m15 - cold formed steel joists :5,SHE-13.STEEL.dgn,Design Model:123712 | FD60 | 4.2009 | 0.000457 | 2.57515 | 2.57607 | 0.01861 | 0.001922 | 15.081231 | 146.088398 | 15.087007 | 4F
4F | 150m15 - cold formed steel joists :5,SHE-13.STEEL.dgn,Design Model:123714 | FD60 | 4.2009 | 0.000457 | 2.57515 | 2.57607 | 0.01861 | 0.001922 | 15.081231 | 146.088398 | 15.087007 | 4F
4F | 150m15 - cold formed steel joists :5,SHE-13.STEEL.dgn,Design Model:123716 | FD60 | 4.2009 | 0.000457 | 2.57515 | 2.57607 | 0.01861 | 0.001922 | 15.081231 | 146.088398 | 15.087007 | 4F
4F | 150m15 - cold formed steel joists :5,SHE-13.STEEL.dgn,Design Model:123718 | FD60 | 4.2009 | 0.000457 | 2.57515 | 2.57607 | 0.01861 | 0.001922 | 15.081231 | 146.088398 | 15.087007 | 4F
4F | 150m15 - cold formed steel joists :5,SHE-13.STEEL.dgn,Design Model:123720 | FD60 | 4.2009 | 0.000457 | 2.57515 | 2.57607 | 0.01861 | 0.001922 | 15.081231 | 146.088398 | 15.087007 | 4F
4F | 150m15 - cold formed steel joists :5,SHE-13.STEEL.dgn,Design Model:123722 | FD60 | 4.2009 | 0.000457 | 2.57515 | 2.57607 | 0.01861 | 0.001922 | 15.081231 | 146.088398 | 15.087007 | 4F
4F | 150m15 - cold formed steel joists :5,SHE-13.STEEL.dgn,Design Model:123724 | FD60 | 4.2009 | 0.000457 | 2.57515 | 2.57607 | 0.01861 | 0.001922 | 15.081231 | 146.088398 | 15.087007 | 4F
4F | 150m15 - cold formed steel joists :5,SHE-13.STEEL.dgn,Design Model:123726 | FD60 | 4.2009 | 0.000457 | 2.57515 | 2.57607 | 0.01861 | 0.001922 | 15.081231 | 146.088398 | 15.087007 | 4F
4F | 150m15 - cold formed steel joists :5,SHE-13.STEEL.dgn,Design Model:123728 | FD60 | 4.2009 | 0.000457 | 2.57515 | 2.57607 | 0.01861 | 0.001922 | 15.081231 | 146.088398 | 15.087007 | 4F
4F | 150m15 - cold formed steel joists :5,SHE-13.STEEL.dgn,Design Model:123730 | FD60 | 4.2009 | 0.000457 | 2.57515 | 2.57607 | 0.01861 | 0.001922 | 15.081231 | 146.088398 | 15.087007 | 4F
4F | 150m15 - cold formed steel joists :5,SHE-13.STEEL.dgn,Design Model:123762 | FD60 | 3.9709 | 0.000457 | 2.43416 | 2.43508 | 0.017591 | 0.001817 | 14.255531 | 138.090033 | 14.260991 | 4F
4F | 150m15 - cold formed steel joists :5,SHE-13.STEEL.dgn,Design Model:123764 | FD60 | 3.9709 | 0.000457 | 2.43416 | 2.43508 | 0.017591 | 0.001817 | 14.255531 | 138.090033 | 14.260991 | 4F
4F | 150m15 - cold formed steel joists :5,SHE-13.STEEL.dgn,Design Model:123766 | FD60 | 3.9709 | 0.000457 | 2.43416 | 2.43508 | 0.017591 | 0.001817 | 14.255531 | 138.090033 | 14.260991 | 4F
4F | 150m15 - cold formed steel joists :5,SHE-13.STEEL.dgn,Design Model:123768 | FD60 | 3.9709 | 0.000457 | 2.43416 | 2.43508 | 0.017591 | 0.001817 | 14.255531 | 138.090033 | 14.260991 | 4F
4F | 150m15 - cold formed steel joists :5,SHE-13.STEEL.dgn,Design Model:123770 | FD60 | 3.9709 | 0.000457 | 2.43416 | 2.43508 | 0.017591 | 0.001817 | 14.255531 | 138.090033 | 14.260991 | 4F
4F | 150m15 - cold formed steel joists :5,SHE-13.STEEL.dgn,Design Model:123772 | FD60 | 3.9709 | 0.000457 | 2.43416 | 2.43508 | 0.017591 | 0.001817 | 14.255531 | 138.090033 | 14.260991 | 4F
4F | 150m15 - cold formed steel joists :5,SHE-13.STEEL.dgn,Design Model:123774 | FD60 | 3.9709 | 0.000457 | 2.43416 | 2.43508 | 0.017591 | 0.001817 | 14.255531 | 138.090033 | 14.260991 | 4F
4F | 150m15 - cold formed steel joists :5,SHE-13.STEEL.dgn,Design Model:123776 | FD60 | 3.9709 | 0.000457 | 2.43416 | 2.43508 | 0.017591 | 0.001817 | 14.255531 | 138.090033 | 14.260991 | 4F
4F | 150m15 - cold formed steel joists :5,SHE-13.STEEL.dgn,Design Model:123778 | FD60 | 3.9709 | 0.000457 | 2.43416 | 2.43508 | 0.017591 | 0.001817 | 14.255531 | 138.090033 | 14.260991 | 4F
4F | 150m15 - cold formed steel joists :5,SHE-13.STEEL.dgn,Design Model:123780 | FD60 | 3.9709 | 0.000457 | 2.43416 | 2.43508 | 0.017591 | 0.001817 | 14.255531 | 138.090033 | 14.260991 | 4F
4F | 150m15 - cold formed steel joists :5,SHE-13.STEEL.dgn,Design Model:123784 | FD60 | 3.9709 | 0.000457 | 2.43416 | 2.43508 | 0.017591 | 0.001817 | 14.255531 | 138.090033 | 14.260991 | 4F
4F | 150m15 - cold formed steel joists :5,SHE-13.STEEL.dgn,Design Model:123786 | FD60 | 3.9709 | 0.000457 | 2.43416 | 2.43508 | 0.017591 | 0.001817 | 14.255531 | 138.090033 | 14.260991 | 4F
4F | 150m15 - cold formed steel joists :5,SHE-13.STEEL.dgn,Design Model:123790 | FD60 | 3.9709 | 0.000457 | 2.43416 | 2.43508 | 0.017591 | 0.001817 | 14.255531 | 138.090033 | 14.260991 | 4F
4F | 150m15 - cold formed steel joists :5,SHE-13.STEEL.dgn,Design Model:123792 | FD60 | 3.9709 | 0.000457 | 2.43416 | 2.43508 | 0.017591 | 0.001817 | 14.255531 | 138.090033 | 14.260991 | 4F
4F | 150m15 - cold formed steel joists :5,SHE-13.STEEL.dgn,Design Model:123794 | FD60 | 3.9709 | 0.000457 | 2.43416 | 2.43508 | 0.017591 | 0.001817 | 14.255531 | 138.090033 | 14.260991 | 4F
4F | 150m15 - cold formed steel joists :5,SHE-13.STEEL.dgn,Design Model:123796 | FD60 | 3.9709 | 0.000457 | 2.43416 | 2.43508 | 0.017591 | 0.001817 | 14.255531 | 138.090033 | 14.260991 | 4F
4F | 150m15 - cold formed steel joists :5,SHE-13.STEEL.dgn,Design Model:123798 | FD60 | 3.9709 | 0.000457 | 2.43416 | 2.43508 | 0.017591 | 0.001817 | 14.255531 | 138.090033 | 14.260991 | 4F
4F | 150m15 - cold formed steel joists :5,SHE-13.STEEL.dgn,Design Model:123800 | FD60 | 3.9709 | 0.000457 | 2.43416 | 2.43508 | 0.017591 | 0.001817 | 14.255531 | 138.090033 | 14.260991 | 4F
4F | 150m15 - cold formed steel joists :5,SHE-13.STEEL.dgn,Design Model:123802 | FD60 | 3.9709 | 0.000457 | 2.43416 | 2.43508 | 0.017591 | 0.001817 | 14.255531 | 138.090033 | 14.260991 | 4F
4F | 150m15 - cold formed steel joists :5,SHE-13.STEEL.dgn,Design Model:123804 | FD60 | 3.9709 | 0.000457 | 2.43416 | 2.43508 | 0.017591 | 0.001817 | 14.255531 | 138.090033 | 14.260991 | 4F
4F | 150m15 - cold formed steel joists :5,SHE-13.STEEL.dgn,Design Model:123806 | FD60 | 3.9709 | 0.000457 | 2.43416 | 2.43508 | 0.017591 | 0.001817 | 14.255531 | 138.090033 | 14.260991 | 4F
4F | 150m15 - cold formed steel joists :5,SHE-13.STEEL.dgn,Design Model:123808 | FD60 | 3.9709 | 0.000457 | 2.43416 | 2.43508 | 0.017591 | 0.001817 | 14.255531 | 138.090033 | 14.260991 | 4F
4F | 150m15 - cold formed steel joists :5,SHE-13.STEEL.dgn,Design Model:123810 | FD60 | 3.9709 | 0.000457 | 2.43416 | 2.43508 | 0.017591 | 0.001817 | 14.255531 | 138.090033 | 14.260991 | 4F
4F | 150m15 - cold formed steel joists :5,SHE-13.STEEL.dgn,Design Model:123812 | FD60 | 3.9709 | 0.000457 | 2.43416 | 2.43508 | 0.017591 | 0.001817 | 14.255531 | 138.090033 | 14.260991 | 4F
4F | 150m15 - cold formed steel joists :5,SHE-13.STEEL.dgn,Design Model:123814 | FD60 | 3.9709 | 0.000457 | 2.43416 | 2.43508 | 0.017591 | 0.001817 | 14.255531 | 138.090033 | 14.260991 | 4F
4F | 150m15 - cold formed steel joists :5,SHE-13.STEEL.dgn,Design Model:123816 | FD60 | 4.2009 | 0.000457 | 2.57515 | 2.57607 | 0.01861 | 0.001922 | 15.081231 | 146.088398 | 15.087007 | 4F
4F | 150m15 - cold formed steel joists :5,SHE-13.STEEL.dgn,Design Model:123818 | FD60 | 4.2009 | 0.000457 | 2.57515 | 2.57607 | 0.01861 | 0.001922 | 15.081231 | 146.088398 | 15.087007 | 4F
4F | 150m15 - cold formed steel joists :5,SHE-13.STEEL.dgn,Design Model:123820 | FD60 | 4.2009 | 0.000457 | 2.57515 | 2.57607 | 0.01861 | 0.001922 | 15.081231 | 146.088398 | 15.087007 | 4F
4F | 150m15 - cold formed steel joists :5,SHE-13.STEEL.dgn,Design Model:123822 | FD60 | 4.2009 | 0.000457 | 2.57515 | 2.57607 | 0.01861 | 0.001922 | 15.081231 | 146.088398 | 15.087007 | 4F
4F | 150m15 - cold formed steel joists :5,SHE-13.STEEL.dgn,Design Model:123824 | FD60 | 4.2009 | 0.000457 | 2.57515 | 2.57607 | 0.01861 | 0.001922 | 15.081231 | 146.088398 | 15.087007 | 4F
4F | 150m15 - cold formed steel joists :5,SHE-13.STEEL.dgn,Design Model:123826 | FD60 | 4.2009 | 0.000457 | 2.57515 | 2.57607 | 0.01861 | 0.001922 | 15.081231 | 146.088398 | 15.087007 | 4F
4F | 150m15 - cold formed steel joists :5,SHE-13.STEEL.dgn,Design Model:123828 | FD60 | 4.2009 | 0.000457 | 2.57515 | 2.57607 | 0.01861 | 0.001922 | 15.081231 | 146.088398 | 15.087007 | 4F
4F | 150m15 - cold formed steel joists :5,SHE-13.STEEL.dgn,Design Model:123830 | FD60 | 4.2009 | 0.000457 | 2.57515 | 2.57607 | 0.01861 | 0.001922 | 15.081231 | 146.088398 | 15.087007 | 4F
4F | 150m15 - cold formed steel joists :5,SHE-13.STEEL.dgn,Design Model:123842 | FD60 | 3.9709 | 0.000457 | 2.43416 | 2.43508 | 0.017591 | 0.001817 | 14.255531 | 138.090033 | 14.260991 | 4F
4F | 150m15 - cold formed steel joists :5,SHE-13.STEEL.dgn,Design Model:123844 | FD60 | 3.9709 | 0.000457 | 2.43416 | 2.43508 | 0.017591 | 0.001817 | 14.255531 | 138.090033 | 14.260991 | 4F
4F | 150m15 - cold formed steel joists :5,SHE-13.STEEL.dgn,Design Model:123846 | FD60 | 3.9709 | 0.000457 | 2.43416 | 2.43508 | 0.017591 | 0.001817 | 14.255531 | 138.090033 | 14.260991 | 4F
4F | 150m15 - cold formed steel joists :5,SHE-13.STEEL.dgn,Design Model:123848 | FD60 | 3.9709 | 0.000457 | 2.43416 | 2.43508 | 0.017591 | 0.001817 | 14.255531 | 138.090033 | 14.260991 | 4F
4F | 150m15 - cold formed steel joists :5,SHE-13.STEEL.dgn,Design Model:123850 | FD60 | 3.9709 | 0.000457 | 2.43416 | 2.43508 | 0.017591 | 0.001817 | 14.255531 | 138.090033 | 14.260991 | 4F
4F | 150m15 - cold formed steel joists :5,SHE-13.STEEL.dgn,Design Model:123852 | FD60 | 3.9709 | 0.000457 | 2.43416 | 2.43508 | 0.017591 | 0.001817 | 14.255531 | 138.090033 | 14.260991 | 4F
4F | 150m15 - cold formed steel joists :5,SHE-13.STEEL.dgn,Design Model:123854 | FD60 | 3.9709 | 0.000457 | 2.43416 | 2.43508 | 0.017591 | 0.001817 | 14.255531 | 138.090033 | 14.260991 | 4F
4F | 150m15 - cold formed steel joists :5,SHE-13.STEEL.dgn,Design Model:123856 | FD60 | 3.9709 | 0.000457 | 2.43416 | 2.43508 | 0.017591 | 0.001817 | 14.255531 | 138.090033 | 14.260991 | 4F
4F | 150m15 - cold formed steel joists :5,SHE-13.STEEL.dgn,Design Model:123858 | FD60 | 3.9709 | 0.000457 | 2.43416 | 2.43508 | 0.017591 | 0.001817 | 14.255531 | 138.090033 | 14.260991 | 4F
4F | 150m15 - cold formed steel joists :5,SHE-13.STEEL.dgn,Design Model:123860 | FD60 | 3.9709 | 0.000457 | 2.43416 | 2.43508 | 0.017591 | 0.001817 | 14.255531 | 138.090033 | 14.260991 | 4F
4F | 150m15 - cold formed steel joists :5,SHE-13.STEEL.dgn,Design Model:123862 | FD60 | 3.9709 | 0.000457 | 2.43416 | 2.43508 | 0.017591 | 0.001817 | 14.255531 | 138.090033 | 14.260991 | 4F
4F | 150m15 - cold formed steel joists :5,SHE-13.STEEL.dgn,Design Model:123864 | FD60 | 3.9709 | 0.000457 | 2.43416 | 2.43508 | 0.017591 | 0.001817 | 14.255531 | 138.090033 | 14.260991 | 4F
4F | 150m15 - cold formed steel joists :5,SHE-13.STEEL.dgn,Design Model:123866 | FD60 | 3.9709 | 0.000457 | 2.43416 | 2.43508 | 0.017591 | 0.001817 | 14.255531 | 138.090033 | 14.260991 | 4F
4F | 150m15 - cold formed steel joists :5,SHE-13.STEEL.dgn,Design Model:123868 | FD60 | 4.2009 | 0.000457 | 2.57515 | 2.57607 | 0.01861 | 0.001922 | 15.081231 | 146.088398 | 15.087007 | 4F
4F | 150m15 - cold formed steel joists :5,SHE-13.STEEL.dgn,Design Model:123870 | FD60 | 4.2009 | 0.000457 | 2.57515 | 2.57607 | 0.01861 | 0.001922 | 15.081231 | 146.088398 | 15.087007 | 4F
4F | 150m15 - cold formed steel joists :5,SHE-13.STEEL.dgn,Design Model:123872 | FD60 | 4.2009 | 0.000457 | 2.57515 | 2.57607 | 0.01861 | 0.001922 | 15.081231 | 146.088398 | 15.087007 | 4F
4F | 150m15 - cold formed steel joists :5,SHE-13.STEEL.dgn,Design Model:123874 | FD60 | 4.2009 | 0.000457 | 2.57515 | 2.57607 | 0.01861 | 0.001922 | 15.081231 | 146.088398 | 15.087007 | 4F
4F | 150m15 - cold formed steel joists :5,SHE-13.STEEL.dgn,Design Model:123876 | FD60 | 4.2009 | 0.000457 | 2.57515 | 2.57607 | 0.01861 | 0.001922 | 15.081231 | 146.088398 | 15.087007 | 4F
4F | 150m15 - cold formed steel joists :5,SHE-13.STEEL.dgn,Design Model:123878 | FD60 | 4.2009 | 0.000457 | 2.57515 | 2.57607 | 0.01861 | 0.001922 | 15.081231 | 146.088398 | 15.087007 | 4F
4F | 150m15 - cold formed steel joists :5,SHE-13.STEEL.dgn,Design Model:123880 | FD60 | 4.2009 | 0.000457 | 2.57515 | 2.57607 | 0.01861 | 0.001922 | 15.081231 | 146.088398 | 15.087007 | 4F
4F | 150m15 - cold formed steel joists :5,SHE-13.STEEL.dgn,Design Model:123882 | FD60 | 4.2009 | 0.000457 | 2.57515 | 2.57607 | 0.01861 | 0.001922 | 15.081231 | 146.088398 | 15.087007 | 4F
5F | 150m15 - cold formed steel joists :5,SHE-13.STEEL.dgn,Design Model:123895 | FD60 | 3.5036 | 0.000457 | 2.14771 | 2.14862 | 0.015521 | 0.001603 | 12.577924 | 121.839442 | 12.582741 | 5F
5F | 150m15 - cold formed steel joists :5,SHE-13.STEEL.dgn,Design Model:123897 | FD60 | 3.5036 | 0.000457 | 2.14771 | 2.14862 | 0.015521 | 0.001603 | 12.577924 | 121.839442 | 12.582741 | 5F
5F | 150m15 - cold formed steel joists :5,SHE-13.STEEL.dgn,Design Model:123899 | FD60 | 3.5036 | 0.000457 | 2.14771 | 2.14862 | 0.015521 | 0.001603 | 12.577924 | 121.839442 | 12.582741 | 5F
5F | 150m15 - cold formed steel joists :5,SHE-13.STEEL.dgn,Design Model:123901 | FD60 | 3.5036 | 0.000457 | 2.14771 | 2.14862 | 0.015521 | 0.001603 | 12.577924 | 121.839442 | 12.582741 | 5F
5F | 150m15 - cold formed steel joists :5,SHE-13.STEEL.dgn,Design Model:123903 | FD60 | 3.5036 | 0.000457 | 2.14771 | 2.14862 | 0.015521 | 0.001603 | 12.577924 | 121.839442 | 12.582741 | 5F
5F | 150m15 - cold formed steel joists :5,SHE-13.STEEL.dgn,Design Model:123905 | FD60 | 3.5036 | 0.000457 | 2.14771 | 2.14862 | 0.015521 | 0.001603 | 12.577924 | 121.839442 | 12.582741 | 5F
5F | 150m15 - cold formed steel joists :5,SHE-13.STEEL.dgn,Design Model:123907 | FD60 | 3.5036 | 0.000457 | 2.14771 | 2.14862 | 0.015521 | 0.001603 | 12.577924 | 121.839442 | 12.582741 | 5F
5F | 150m15 - cold formed steel joists :5,SHE-13.STEEL.dgn,Design Model:123909 | FD60 | 3.5036 | 0.000457 | 2.14771 | 2.14862 | 0.015521 | 0.001603 | 12.577924 | 121.839442 | 12.582741 | 5F
5F | 150m15 - cold formed steel joists :5,SHE-13.STEEL.dgn,Design Model:123911 | FD60 | 3.5036 | 0.000457 | 2.14771 | 2.14862 | 0.015521 | 0.001603 | 12.577924 | 121.839442 | 12.582741 | 5F
5F | 150m15 - cold formed steel joists :5,SHE-13.STEEL.dgn,Design Model:123913 | FD60 | 3.5036 | 0.000457 | 2.14771 | 2.14862 | 0.015521 | 0.001603 | 12.577924 | 121.839442 | 12.582741 | 5F
5F | 150m15 - cold formed steel joists :5,SHE-13.STEEL.dgn,Design Model:123915 | FD60 | 3.5036 | 0.000457 | 2.14771 | 2.14862 | 0.015521 | 0.001603 | 12.577924 | 121.839442 | 12.582741 | 5F
5F | 150m15 - cold formed steel joists :5,SHE-13.STEEL.dgn,Design Model:124011 | FD60 | 3.4636 | 0.000457 | 2.12319 | 2.1241 | 0.015344 | 0.001585 | 12.434324 | 120.448422 | 12.439086 | 5F
5F | 150m15 - cold formed steel joists :5,SHE-13.STEEL.dgn,Design Model:124013 | FD60 | 3.4636 | 0.000457 | 2.12319 | 2.1241 | 0.015344 | 0.001585 | 12.434324 | 120.448422 | 12.439086 | 5F
5F | 150m15 - cold formed steel joists :5,SHE-13.STEEL.dgn,Design Model:124015 | FD60 | 3.4636 | 0.000457 | 2.12319 | 2.1241 | 0.015344 | 0.001585 | 12.434324 | 120.448422 | 12.439086 | 5F
5F | 150m15 - cold formed steel joists :5,SHE-13.STEEL.dgn,Design Model:124017 | FD60 | 3.4636 | 0.000457 | 2.12319 | 2.1241 | 0.015344 | 0.001585 | 12.434324 | 120.448422 | 12.439086 | 5F
5F | 150m15 - cold formed steel joists :5,SHE-13.STEEL.dgn,Design Model:124019 | FD60 | 3.4636 | 0.000457 | 2.12319 | 2.1241 | 0.015344 | 0.001585 | 12.434324 | 120.448422 | 12.439086 | 5F
5F | 150m15 - cold formed steel joists :5,SHE-13.STEEL.dgn,Design Model:124021 | FD60 | 3.4636 | 0.000457 | 2.12319 | 2.1241 | 0.015344 | 0.001585 | 12.434324 | 120.448422 | 12.439086 | 5F
5F | 150m15 - cold formed steel joists :5,SHE-13.STEEL.dgn,Design Model:124023 | FD60 | 3.4636 | 0.000457 | 2.12319 | 2.1241 | 0.015344 | 0.001585 | 12.434324 | 120.448422 | 12.439086 | 5F
5F | 150m15 - cold formed steel joists :5,SHE-13.STEEL.dgn,Design Model:124025 | FD60 | 3.4636 | 0.000457 | 2.12319 | 2.1241 | 0.015344 | 0.001585 | 12.434324 | 120.448422 | 12.439086 | 5F
5F | 150m15 - cold formed steel joists :5,SHE-13.STEEL.dgn,Design Model:124027 | FD60 | 3.4636 | 0.000457 | 2.12319 | 2.1241 | 0.015344 | 0.001585 | 12.434324 | 120.448422 | 12.439086 | 5F
5F | 150m15 - cold formed steel joists :5,SHE-13.STEEL.dgn,Design Model:124029 | FD60 | 3.4636 | 0.000457 | 2.12319 | 2.1241 | 0.015344 | 0.001585 | 12.434324 | 120.448422 | 12.439086 | 5F
5F | 150m15 - cold formed steel joists :5,SHE-13.STEEL.dgn,Design Model:124031 | FD60 | 3.4636 | 0.000457 | 2.12319 | 2.1241 | 0.015344 | 0.001585 | 12.434324 | 120.448422 | 12.439086 | 5F
5F | 150m15 - cold formed steel joists :5,SHE-13.STEEL.dgn,Design Model:124071 | FD60 | 3.305 | 0.000457 | 2.02596 | 2.02688 | 0.014641 | 0.001512 | 11.864950 | 114.933028 | 11.869494 | 5F
5F | 150m15 - cold formed steel joists :5,SHE-13.STEEL.dgn,Design Model:124073 | FD60 | 3.305 | 0.000457 | 2.02596 | 2.02688 | 0.014641 | 0.001512 | 11.864950 | 114.933028 | 11.869494 | 5F
5F | 150m15 - cold formed steel joists :5,SHE-13.STEEL.dgn,Design Model:124075 | FD60 | 3.305 | 0.000457 | 2.02596 | 2.02688 | 0.014641 | 0.001512 | 11.864950 | 114.933028 | 11.869494 | 5F
5F | 150m15 - cold formed steel joists :5,SHE-13.STEEL.dgn,Design Model:124077 | FD60 | 3.305 | 0.000457 | 2.02596 | 2.02688 | 0.014641 | 0.001512 | 11.864950 | 114.933028 | 11.869494 | 5F
5F | 150m15 - cold formed steel joists :5,SHE-13.STEEL.dgn,Design Model:124079 | FD60 | 3.305 | 0.000457 | 2.02596 | 2.02688 | 0.014641 | 0.001512 | 11.864950 | 114.933028 | 11.869494 | 5F
5F | 150m15 - cold formed steel joists :5,SHE-13.STEEL.dgn,Design Model:124081 | FD60 | 3.305 | 0.000457 | 2.02596 | 2.02688 | 0.014641 | 0.001512 | 11.864950 | 114.933028 | 11.869494 | 5F
5F | 150m15 - cold formed steel joists :5,SHE-13.STEEL.dgn,Design Model:124083 | FD60 | 3.5036 | 0.000457 | 2.14771 | 2.14862 | 0.015521 | 0.001603 | 12.577924 | 121.839442 | 12.582741 | 5F
5F | 150m15 - cold formed steel joists :5,SHE-13.STEEL.dgn,Design Model:124085 | FD60 | 3.5036 | 0.000457 | 2.14771 | 2.14862 | 0.015521 | 0.001603 | 12.577924 | 121.839442 | 12.582741 | 5F
5F | 150m15 - cold formed steel joists :5,SHE-13.STEEL.dgn,Design Model:124087 | FD60 | 3.5036 | 0.000457 | 2.14771 | 2.14862 | 0.015521 | 0.001603 | 12.577924 | 121.839442 | 12.582741 | 5F
5F | 150m15 - cold formed steel joists :5,SHE-13.STEEL.dgn,Design Model:124089 | FD60 | 3.5036 | 0.000457 | 2.14771 | 2.14862 | 0.015521 | 0.001603 | 12.577924 | 121.839442 | 12.582741 | 5F
5F | 150m15 - cold formed steel joists :5,SHE-13.STEEL.dgn,Design Model:124091 | FD60 | 3.5036 | 0.000457 | 2.14771 | 2.14862 | 0.015521 | 0.001603 | 12.577924 | 121.839442 | 12.582741 | 5F
5F | 150m15 - cold formed steel joists :5,SHE-13.STEEL.dgn,Design Model:124093 | FD60 | 3.5036 | 0.000457 | 2.14771 | 2.14862 | 0.015521 | 0.001603 | 12.577924 | 121.839442 | 12.582741 | 5F
5F | 150m15 - cold formed steel joists :5,SHE-13.STEEL.dgn,Design Model:124095 | FD60 | 3.5036 | 0.000457 | 2.14771 | 2.14862 | 0.015521 | 0.001603 | 12.577924 | 121.839442 | 12.582741 | 5F
5F | 150m15 - cold formed steel joists :5,SHE-13.STEEL.dgn,Design Model:124097 | FD60 | 3.5036 | 0.000457 | 2.14771 | 2.14862 | 0.015521 | 0.001603 | 12.577924 | 121.839442 | 12.582741 | 5F
5F | 150m15 - cold formed steel joists :5,SHE-13.STEEL.dgn,Design Model:124099 | FD60 | 3.5036 | 0.000457 | 2.14771 | 2.14862 | 0.015521 | 0.001603 | 12.577924 | 121.839442 | 12.582741 | 5F
5F | 150m15 - cold formed steel joists :5,SHE-13.STEEL.dgn,Design Model:124101 | FD60 | 3.5036 | 0.000457 | 2.14771 | 2.14862 | 0.015521 | 0.001603 | 12.577924 | 121.839442 | 12.582741 | 5F
5F | 150m15 - cold formed steel joists :5,SHE-13.STEEL.dgn,Design Model:124103 | FD60 | 3.5036 | 0.000457 | 2.14771 | 2.14862 | 0.015521 | 0.001603 | 12.577924 | 121.839442 | 12.582741 | 5F
5F | 150m15 - cold formed steel joists :5,SHE-13.STEEL.dgn,Design Model:124445 | FD60 | 3.4636 | 0.000457 | 2.12319 | 2.1241 | 0.015344 | 0.001585 | 12.434324 | 120.448422 | 12.439086 | 5F
5F | 150m15 - cold formed steel joists :5,SHE-13.STEEL.dgn,Design Model:124447 | FD60 | 3.4636 | 0.000457 | 2.12319 | 2.1241 | 0.015344 | 0.001585 | 12.434324 | 120.448422 | 12.439086 | 5F
5F | 150m15 - cold formed steel joists :5,SHE-13.STEEL.dgn,Design Model:124449 | FD60 | 3.4636 | 0.000457 | 2.12319 | 2.1241 | 0.015344 | 0.001585 | 12.434324 | 120.448422 | 12.439086 | 5F
5F | 150m15 - cold formed steel joists :5,SHE-13.STEEL.dgn,Design Model:124451 | FD60 | 3.4636 | 0.000457 | 2.12319 | 2.1241 | 0.015344 | 0.001585 | 12.434324 | 120.448422 | 12.439086 | 5F
5F | 150m15 - cold formed steel joists :5,SHE-13.STEEL.dgn,Design Model:124453 | FD60 | 3.4636 | 0.000457 | 2.12319 | 2.1241 | 0.015344 | 0.001585 | 12.434324 | 120.448422 | 12.439086 | 5F
5F | 150m15 - cold formed steel joists :5,SHE-13.STEEL.dgn,Design Model:124455 | FD60 | 3.4636 | 0.000457 | 2.12319 | 2.1241 | 0.015344 | 0.001585 | 12.434324 | 120.448422 | 12.439086 | 5F
5F | 150m15 - cold formed steel joists :5,SHE-13.STEEL.dgn,Design Model:124457 | FD60 | 3.4636 | 0.000457 | 2.12319 | 2.1241 | 0.015344 | 0.001585 | 12.434324 | 120.448422 | 12.439086 | 5F
5F | 150m15 - cold formed steel joists :5,SHE-13.STEEL.dgn,Design Model:124459 | FD60 | 3.4636 | 0.000457 | 2.12319 | 2.1241 | 0.015344 | 0.001585 | 12.434324 | 120.448422 | 12.439086 | 5F
5F | 150m15 - cold formed steel joists :5,SHE-13.STEEL.dgn,Design Model:124461 | FD60 | 3.4636 | 0.000457 | 2.12319 | 2.1241 | 0.015344 | 0.001585 | 12.434324 | 120.448422 | 12.439086 | 5F
5F | 150m15 - cold formed steel joists :5,SHE-13.STEEL.dgn,Design Model:124463 | FD60 | 3.4636 | 0.000457 | 2.12319 | 2.1241 | 0.015344 | 0.001585 | 12.434324 | 120.448422 | 12.439086 | 5F
5F | 150m15 - cold formed steel joists :5,SHE-13.STEEL.dgn,Design Model:124465 | FD60 | 3.4636 | 0.000457 | 2.12319 | 2.1241 | 0.015344 | 0.001585 | 12.434324 | 120.448422 | 12.439086 | 5F
5F | 150m15 - cold formed steel joists :5,SHE-13.STEEL.dgn,Design Model:124572 | FD60 | 0.695 | 0.000458 | 0.426035 | 0.42695 | 0.003079 | 0.000318 | 2.495050 | 24.168972 | 2.496006 | 5F
5F | 150m15 - cold formed steel joists :5,SHE-13.STEEL.dgn,Design Model:124574 | FD60 | 0.695 | 0.000458 | 0.426035 | 0.42695 | 0.003079 | 0.000318 | 2.495050 | 24.168972 | 2.496006 | 5F
4F | 150m15 - cold formed steel joists :5,SHE-13.STEEL.dgn,Design Model:125081 | FD60 | 4.01635 | 0.000457 | 2.46202 | 2.46294 | 0.017792 | 0.001837 | 14.418697 | 139.670579 | 14.424219 | 4F
4F | 150m15 - cold formed steel joists :5,SHE-13.STEEL.dgn,Design Model:125083 | FD60 | 4.01635 | 0.000457 | 2.46202 | 2.46294 | 0.017792 | 0.001837 | 14.418697 | 139.670579 | 14.424219 | 4F
4F | 150m15 - cold formed steel joists :5,SHE-13.STEEL.dgn,Design Model:125085 | FD60 | 4.01635 | 0.000457 | 2.46202 | 2.46294 | 0.017792 | 0.001837 | 14.418697 | 139.670579 | 14.424219 | 4F
4F | 150m15 - cold formed steel joists :5,SHE-13.STEEL.dgn,Design Model:125087 | FD60 | 4.01635 | 0.000457 | 2.46202 | 2.46294 | 0.017792 | 0.001837 | 14.418697 | 139.670579 | 14.424219 | 4F
4F | 150m15 - cold formed steel joists :5,SHE-13.STEEL.dgn,Design Model:125089 | FD60 | 4.01635 | 0.000457 | 2.46202 | 2.46294 | 0.017792 | 0.001837 | 14.418697 | 139.670579 | 14.424219 | 4F
4F | 150m15 - cold formed steel joists :5,SHE-13.STEEL.dgn,Design Model:125091 | FD60 | 4.01635 | 0.000457 | 2.46202 | 2.46294 | 0.017792 | 0.001837 | 14.418697 | 139.670579 | 14.424219 | 4F
4F | 150m15 - cold formed steel joists :5,SHE-13.STEEL.dgn,Design Model:125093 | FD60 | 4.01635 | 0.000457 | 2.46202 | 2.46294 | 0.017792 | 0.001837 | 14.418697 | 139.670579 | 14.424219 | 4F
4F | 150m15 - cold formed steel joists :5,SHE-13.STEEL.dgn,Design Model:125095 | FD60 | 4.01635 | 0.000457 | 2.46202 | 2.46294 | 0.017792 | 0.001837 | 14.418697 | 139.670579 | 14.424219 | 4F
4F | 150m15 - cold formed steel joists :5,SHE-13.STEEL.dgn,Design Model:125097 | FD60 | 4.01635 | 0.000457 | 2.46202 | 2.46294 | 0.017792 | 0.001837 | 14.418697 | 139.670579 | 14.424219 | 4F
4F | 150m15 - cold formed steel joists :5,SHE-13.STEEL.dgn,Design Model:125099 | FD60 | 4.01635 | 0.000457 | 2.46202 | 2.46294 | 0.017792 | 0.001837 | 14.418697 | 139.670579 | 14.424219 | 4F
4F | 150m15 - cold formed steel joists :5,SHE-13.STEEL.dgn,Design Model:125101 | FD60 | 4.01635 | 0.000457 | 2.46202 | 2.46294 | 0.017792 | 0.001837 | 14.418697 | 139.670579 | 14.424219 | 4F
4F | 150m15 - cold formed steel joists :5,SHE-13.STEEL.dgn,Design Model:125103 | FD60 | 4.01635 | 0.000457 | 2.46202 | 2.46294 | 0.017792 | 0.001837 | 14.418697 | 139.670579 | 14.424219 | 4F
4F | 150m15 - cold formed steel joists :5,SHE-13.STEEL.dgn,Design Model:125105 | FD60 | 4.01635 | 0.000457 | 2.46202 | 2.46294 | 0.017792 | 0.001837 | 14.418697 | 139.670579 | 14.424219 | 4F
4F | 150m15 - cold formed steel joists :5,SHE-13.STEEL.dgn,Design Model:125107 | FD60 | 4.01635 | 0.000457 | 2.46202 | 2.46294 | 0.017792 | 0.001837 | 14.418697 | 139.670579 | 14.424219 | 4F
4F | 150m15 - cold formed steel joists :5,SHE-13.STEEL.dgn,Design Model:125109 | FD60 | 4.01635 | 0.000457 | 2.46202 | 2.46294 | 0.017792 | 0.001837 | 14.418697 | 139.670579 | 14.424219 | 4F
4F | 150m15 - cold formed steel joists :5,SHE-13.STEEL.dgn,Design Model:125111 | FD60 | 4.01635 | 0.000457 | 2.46202 | 2.46294 | 0.017792 | 0.001837 | 14.418697 | 139.670579 | 14.424219 | 4F
4F | 150m15 - cold formed steel joists :5,SHE-13.STEEL.dgn,Design Model:125113 | FD60 | 4.01635 | 0.000457 | 2.46202 | 2.46294 | 0.017792 | 0.001837 | 14.418697 | 139.670579 | 14.424219 | 4F
4F | 150m15 - cold formed steel joists :5,SHE-13.STEEL.dgn,Design Model:125115 | FD60 | 4.01635 | 0.000457 | 2.46202 | 2.46294 | 0.017792 | 0.001837 | 14.418697 | 139.670579 | 14.424219 | 4F
4F | 150m15 - cold formed steel joists :5,SHE-13.STEEL.dgn,Design Model:125117 | FD60 | 4.01635 | 0.000457 | 2.46202 | 2.46294 | 0.017792 | 0.001837 | 14.418697 | 139.670579 | 14.424219 | 4F
4F | 150m15 - cold formed steel joists :5,SHE-13.STEEL.dgn,Design Model:125119 | FD60 | 4.01635 | 0.000457 | 2.46202 | 2.46294 | 0.017792 | 0.001837 | 14.418697 | 139.670579 | 14.424219 | 4F
4F | 150m15 - cold formed steel joists :5,SHE-13.STEEL.dgn,Design Model:125121 | FD60 | 4.01635 | 0.000457 | 2.46202 | 2.46294 | 0.017792 | 0.001837 | 14.418697 | 139.670579 | 14.424219 | 4F
4F | 150m15 - cold formed steel joists :5,SHE-13.STEEL.dgn,Design Model:125123 | FD60 | 4.01635 | 0.000457 | 2.46202 | 2.46294 | 0.017792 | 0.001837 | 14.418697 | 139.670579 | 14.424219 | 4F
4F | 150m15 - cold formed steel joists :5,SHE-13.STEEL.dgn,Design Model:125125 | FD60 | 4.01635 | 0.000457 | 2.46202 | 2.46294 | 0.017792 | 0.001837 | 14.418697 | 139.670579 | 14.424219 | 4F
4F | 150m15 - cold formed steel joists :5,SHE-13.STEEL.dgn,Design Model:125127 | FD60 | 4.01635 | 0.000457 | 2.46202 | 2.46294 | 0.017792 | 0.001837 | 14.418697 | 139.670579 | 14.424219 | 4F
4F | 150m15 - cold formed steel joists :5,SHE-13.STEEL.dgn,Design Model:125129 | FD60 | 4.01635 | 0.000457 | 2.46202 | 2.46294 | 0.017792 | 0.001837 | 14.418697 | 139.670579 | 14.424219 | 4F
4F | 150m15 - cold formed steel joists :5,SHE-13.STEEL.dgn,Design Model:125133 | FD60 | 4.03635 | 0.000457 | 2.47428 | 2.4752 | 0.017881 | 0.001847 | 14.490496 | 140.366089 | 14.496046 | 4F
4F | 150m15 - cold formed steel joists :5,SHE-13.STEEL.dgn,Design Model:125135 | FD60 | 4.03635 | 0.000457 | 2.47428 | 2.4752 | 0.017881 | 0.001847 | 14.490496 | 140.366089 | 14.496046 | 4F
4F | 150m15 - cold formed steel joists :5,SHE-13.STEEL.dgn,Design Model:125137 | FD60 | 4.03635 | 0.000457 | 2.47428 | 2.4752 | 0.017881 | 0.001847 | 14.490496 | 140.366089 | 14.496046 | 4F
4F | 150m15 - cold formed steel joists :5,SHE-13.STEEL.dgn,Design Model:125139 | FD60 | 4.03635 | 0.000457 | 2.47428 | 2.4752 | 0.017881 | 0.001847 | 14.490496 | 140.366089 | 14.496046 | 4F
4F | 150m15 - cold formed steel joists :5,SHE-13.STEEL.dgn,Design Model:125141 | FD60 | 4.03635 | 0.000457 | 2.47428 | 2.4752 | 0.017881 | 0.001847 | 14.490496 | 140.366089 | 14.496046 | 4F
4F | 150m15 - cold formed steel joists :5,SHE-13.STEEL.dgn,Design Model:125143 | FD60 | 4.03635 | 0.000457 | 2.47428 | 2.4752 | 0.017881 | 0.001847 | 14.490496 | 140.366089 | 14.496046 | 4F
4F | 150m15 - cold formed steel joists :5,SHE-13.STEEL.dgn,Design Model:125145 | FD60 | 4.03635 | 0.000457 | 2.47428 | 2.4752 | 0.017881 | 0.001847 | 14.490496 | 140.366089 | 14.496046 | 4F
4F | 150m15 - cold formed steel joists :5,SHE-13.STEEL.dgn,Design Model:125147 | FD60 | 4.03635 | 0.000457 | 2.47428 | 2.4752 | 0.017881 | 0.001847 | 14.490496 | 140.366089 | 14.496046 | 4F
4F | 150m15 - cold formed steel joists :5,SHE-13.STEEL.dgn,Design Model:125149 | FD60 | 4.03635 | 0.000457 | 2.47428 | 2.4752 | 0.017881 | 0.001847 | 14.490496 | 140.366089 | 14.496046 | 4F
4F | 150m15 - cold formed steel joists :5,SHE-13.STEEL.dgn,Design Model:125151 | FD60 | 4.03635 | 0.000457 | 2.47428 | 2.4752 | 0.017881 | 0.001847 | 14.490496 | 140.366089 | 14.496046 | 4F
4F | 150m15 - cold formed steel joists :5,SHE-13.STEEL.dgn,Design Model:125153 | FD60 | 4.03635 | 0.000457 | 2.47428 | 2.4752 | 0.017881 | 0.001847 | 14.490496 | 140.366089 | 14.496046 | 4F
4F | 150m15 - cold formed steel joists :5,SHE-13.STEEL.dgn,Design Model:125155 | FD60 | 4.03635 | 0.000457 | 2.47428 | 2.4752 | 0.017881 | 0.001847 | 14.490496 | 140.366089 | 14.496046 | 4F
4F | 150m15 - cold formed steel joists :5,SHE-13.STEEL.dgn,Design Model:125157 | FD60 | 4.03635 | 0.000457 | 2.47428 | 2.4752 | 0.017881 | 0.001847 | 14.490496 | 140.366089 | 14.496046 | 4F
4F | 150m15 - cold formed steel joists :5,SHE-13.STEEL.dgn,Design Model:125159 | FD60 | 4.03635 | 0.000457 | 2.47428 | 2.4752 | 0.017881 | 0.001847 | 14.490496 | 140.366089 | 14.496046 | 4F
4F | 150m15 - cold formed steel joists :5,SHE-13.STEEL.dgn,Design Model:125161 | FD60 | 4.03635 | 0.000457 | 2.47428 | 2.4752 | 0.017881 | 0.001847 | 14.490496 | 140.366089 | 14.496046 | 4F
4F | 150m15 - cold formed steel joists :5,SHE-13.STEEL.dgn,Design Model:125163 | FD60 | 4.03635 | 0.000457 | 2.47428 | 2.4752 | 0.017881 | 0.001847 | 14.490496 | 140.366089 | 14.496046 | 4F
4F | 150m15 - cold formed steel joists :5,SHE-13.STEEL.dgn,Design Model:125165 | FD60 | 4.03635 | 0.000457 | 2.47428 | 2.4752 | 0.017881 | 0.001847 | 14.490496 | 140.366089 | 14.496046 | 4F
4F | 150m15 - cold formed steel joists :5,SHE-13.STEEL.dgn,Design Model:125167 | FD60 | 4.03635 | 0.000457 | 2.47428 | 2.4752 | 0.017881 | 0.001847 | 14.490496 | 140.366089 | 14.496046 | 4F
4F | 150m15 - cold formed steel joists :5,SHE-13.STEEL.dgn,Design Model:125169 | FD60 | 4.03635 | 0.000457 | 2.47428 | 2.4752 | 0.017881 | 0.001847 | 14.490496 | 140.366089 | 14.496046 | 4F
4F | 150m15 - cold formed steel joists :5,SHE-13.STEEL.dgn,Design Model:125171 | FD60 | 4.03635 | 0.000457 | 2.47428 | 2.4752 | 0.017881 | 0.001847 | 14.490496 | 140.366089 | 14.496046 | 4F
4F | 150m15 - cold formed steel joists :5,SHE-13.STEEL.dgn,Design Model:125173 | FD60 | 4.03635 | 0.000457 | 2.47428 | 2.4752 | 0.017881 | 0.001847 | 14.490496 | 140.366089 | 14.496046 | 4F
4F | 150m15 - cold formed steel joists :5,SHE-13.STEEL.dgn,Design Model:125175 | FD60 | 4.03635 | 0.000457 | 2.47428 | 2.4752 | 0.017881 | 0.001847 | 14.490496 | 140.366089 | 14.496046 | 4F
4F | 150m15 - cold formed steel joists :5,SHE-13.STEEL.dgn,Design Model:125177 | FD60 | 4.03635 | 0.000457 | 2.47428 | 2.4752 | 0.017881 | 0.001847 | 14.490496 | 140.366089 | 14.496046 | 4F
4F | 150m15 - cold formed steel joists :5,SHE-13.STEEL.dgn,Design Model:125179 | FD60 | 4.03635 | 0.000457 | 2.47428 | 2.4752 | 0.017881 | 0.001847 | 14.490496 | 140.366089 | 14.496046 | 4F
4F | 150m15 - cold formed steel joists :5,SHE-13.STEEL.dgn,Design Model:125181 | FD60 | 4.03635 | 0.000457 | 2.47428 | 2.4752 | 0.017881 | 0.001847 | 14.490496 | 140.366089 | 14.496046 | 4F
4F | 150m15 - cold formed steel joists :5,SHE-13.STEEL.dgn,Design Model:125183 | FD60 | 4.03635 | 0.000457 | 2.47428 | 2.4752 | 0.017881 | 0.001847 | 14.490496 | 140.366089 | 14.496046 | 4F
RP | 150m15 - cold formed steel joists :5,SHE-13.STEEL.dgn,Design Model:125316 | FD60 | 1.24342 | 0.000457 | 0.762217 | 0.763132 | 0.005508 | 0.000569 | 4.463884 | 43.240611 | 4.465594 | RP
RP | 150m15 - cold formed steel joists :5,SHE-13.STEEL.dgn,Design Model:125318 | FD60 | 1.24342 | 0.000457 | 0.762217 | 0.763132 | 0.005508 | 0.000569 | 4.463884 | 43.240611 | 4.465594 | RP
RP | 150m15 - cold formed steel joists :5,SHE-13.STEEL.dgn,Design Model:125320 | FD60 | 1.24342 | 0.000457 | 0.762217 | 0.763132 | 0.005508 | 0.000569 | 4.463884 | 43.240611 | 4.465594 | RP
RP | 150m15 - cold formed steel joists :5,SHE-13.STEEL.dgn,Design Model:125322 | FD60 | 1.24342 | 0.000457 | 0.762217 | 0.763132 | 0.005508 | 0.000569 | 4.463884 | 43.240611 | 4.465594 | RP
RP | 150m15 - cold formed steel joists :5,SHE-13.STEEL.dgn,Design Model:125324 | FD60 | 1.24342 | 0.000457 | 0.762217 | 0.763132 | 0.005508 | 0.000569 | 4.463884 | 43.240611 | 4.465594 | RP
RP | 150m15 - cold formed steel joists :5,SHE-13.STEEL.dgn,Design Model:125344 | FD60 | 1.24342 | 0.000457 | 0.762217 | 0.763132 | 0.005508 | 0.000569 | 4.463884 | 43.240611 | 4.465594 | RP
RP | 150m15 - cold formed steel joists :5,SHE-13.STEEL.dgn,Design Model:125346 | FD60 | 1.24342 | 0.000457 | 0.762217 | 0.763132 | 0.005508 | 0.000569 | 4.463884 | 43.240611 | 4.465594 | RP
RP | 150m15 - cold formed steel joists :5,SHE-13.STEEL.dgn,Design Model:125348 | FD60 | 1.24342 | 0.000457 | 0.762217 | 0.763132 | 0.005508 | 0.000569 | 4.463884 | 43.240611 | 4.465594 | RP
RP | 150m15 - cold formed steel joists :5,SHE-13.STEEL.dgn,Design Model:125350 | FD60 | 1.24342 | 0.000457 | 0.762217 | 0.763132 | 0.005508 | 0.000569 | 4.463884 | 43.240611 | 4.465594 | RP
RP | 150m15 - cold formed steel joists :5,SHE-13.STEEL.dgn,Design Model:125352 | FD60 | 1.24342 | 0.000457 | 0.762217 | 0.763132 | 0.005508 | 0.000569 | 4.463884 | 43.240611 | 4.465594 | RP
RP | 150m15 - cold formed steel joists :5,SHE-13.STEEL.dgn,Design Model:125354 | FD60 | 1.24342 | 0.000457 | 0.762217 | 0.763132 | 0.005508 | 0.000569 | 4.463884 | 43.240611 | 4.465594 | RP
RP | 150m15 - cold formed steel joists :5,SHE-13.STEEL.dgn,Design Model:125356 | FD60 | 1.24342 | 0.000457 | 0.762217 | 0.763132 | 0.005508 | 0.000569 | 4.463884 | 43.240611 | 4.465594 | RP
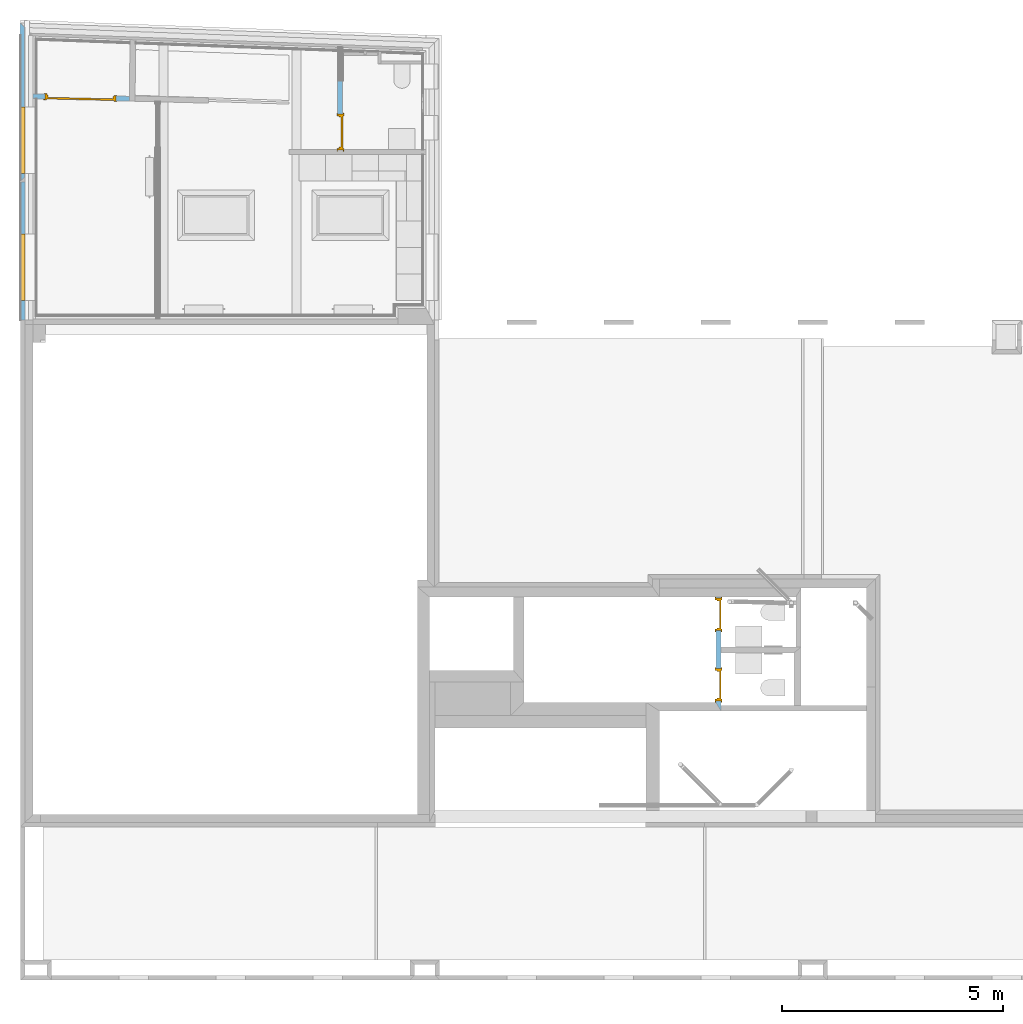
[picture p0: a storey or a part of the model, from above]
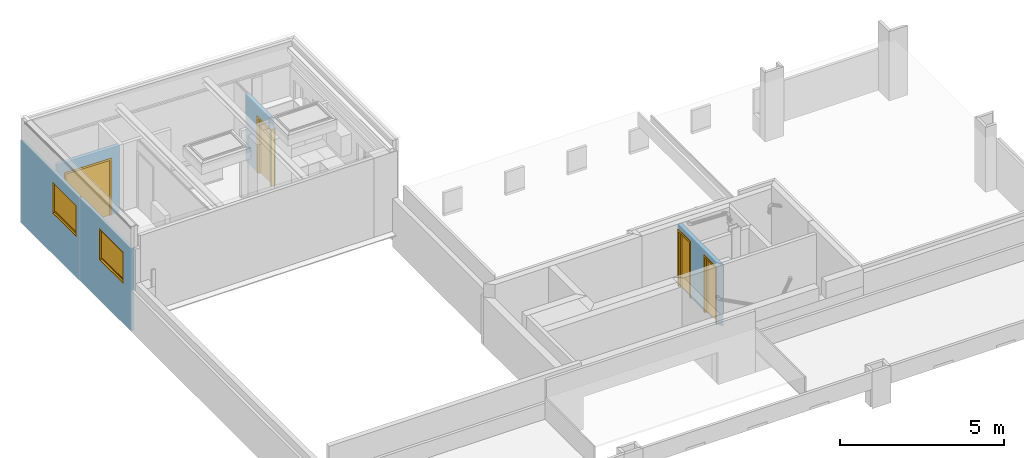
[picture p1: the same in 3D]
Properties of the parts of a building model (IFC2X3), part 4 of 17

# IfcBeam: SHE_A-Beams-Steel-Purlin_150m15 (479)
Name | Description | FireRating = Fire | Rating | Length (m) | Area | Cross-sectional Modeled (m2) | Area | Side Surfaces Modeled (Gross) (m2) | Area | All Surfaces Modeled (Net) (m2) | Volume (Gross) (m3) = Volume (Net) (m3) | Volume (Gross Modeled) (m3) = Volume (Net Modeled) (m3) | Length x Unit Weight | Volume (Gross) x Density = Volume (Net) x Density | Volume (Gross Modeled) x Density = Volume (Net Modeled) x Density | ID | Number
RP | 150m15 - cold formed steel joists :5,SHE-13.STEEL.dgn,Design Model:125358 | FD60 | 1.24342 | 0.000457 | 0.762217 | 0.763132 | 0.005508 | 0.000569 | 4.463884 | 43.240611 | 4.465594 | RP
RP | 150m15 - cold formed steel joists :5,SHE-13.STEEL.dgn,Design Model:125360 | FD60 | 1.24342 | 0.000457 | 0.762217 | 0.763132 | 0.005508 | 0.000569 | 4.463884 | 43.240611 | 4.465594 | RP
RP | 150m15 - cold formed steel joists :5,SHE-13.STEEL.dgn,Design Model:125362 | FD60 | 1.24342 | 0.000457 | 0.762217 | 0.763132 | 0.005508 | 0.000569 | 4.463884 | 43.240611 | 4.465594 | RP
RP | 150m15 - cold formed steel joists :5,SHE-13.STEEL.dgn,Design Model:125364 | FD60 | 1.24342 | 0.000457 | 0.762217 | 0.763132 | 0.005508 | 0.000569 | 4.463884 | 43.240611 | 4.465594 | RP
RP | 150m15 - cold formed steel joists :5,SHE-13.STEEL.dgn,Design Model:125462 | FD60 | 1.22364 | 0.000457 | 0.750089 | 0.751004 | 0.005421 | 0.00056 | 4.392854 | 42.552563 | 4.394537 | RP
RP | 150m15 - cold formed steel joists :5,SHE-13.STEEL.dgn,Design Model:125464 | FD60 | 1.22364 | 0.000457 | 0.750089 | 0.751004 | 0.005421 | 0.00056 | 4.392854 | 42.552563 | 4.394537 | RP
RP | 150m15 - cold formed steel joists :5,SHE-13.STEEL.dgn,Design Model:125466 | FD60 | 1.22364 | 0.000457 | 0.750089 | 0.751004 | 0.005421 | 0.00056 | 4.392854 | 42.552563 | 4.394537 | RP
RP | 150m15 - cold formed steel joists :5,SHE-13.STEEL.dgn,Design Model:125468 | FD60 | 1.22364 | 0.000457 | 0.750089 | 0.751004 | 0.005421 | 0.00056 | 4.392854 | 42.552563 | 4.394537 | RP
RP | 150m15 - cold formed steel joists :5,SHE-13.STEEL.dgn,Design Model:125470 | FD60 | 1.22364 | 0.000457 | 0.750089 | 0.751004 | 0.005421 | 0.00056 | 4.392854 | 42.552563 | 4.394537 | RP
RP | 150m15 - cold formed steel joists :5,SHE-13.STEEL.dgn,Design Model:125472 | FD60 | 1.22364 | 0.000457 | 0.750089 | 0.751004 | 0.005421 | 0.00056 | 4.392854 | 42.552563 | 4.394537 | RP
RP | 150m15 - cold formed steel joists :5,SHE-13.STEEL.dgn,Design Model:125474 | FD60 | 1.22364 | 0.000457 | 0.750089 | 0.751004 | 0.005421 | 0.00056 | 4.392854 | 42.552563 | 4.394537 | RP
RP | 150m15 - cold formed steel joists :5,SHE-13.STEEL.dgn,Design Model:125476 | FD60 | 1.22364 | 0.000457 | 0.750089 | 0.751004 | 0.005421 | 0.00056 | 4.392854 | 42.552563 | 4.394537 | RP
RP | 150m15 - cold formed steel joists :5,SHE-13.STEEL.dgn,Design Model:125478 | FD60 | 1.22364 | 0.000457 | 0.750089 | 0.751004 | 0.005421 | 0.00056 | 4.392854 | 42.552563 | 4.394537 | RP
RP | 150m15 - cold formed steel joists :5,SHE-13.STEEL.dgn,Design Model:125480 | FD60 | 1.22364 | 0.000457 | 0.750089 | 0.751004 | 0.005421 | 0.00056 | 4.392854 | 42.552563 | 4.394537 | RP
RP | 150m15 - cold formed steel joists :5,SHE-13.STEEL.dgn,Design Model:125482 | FD60 | 1.22364 | 0.000457 | 0.750089 | 0.751004 | 0.005421 | 0.00056 | 4.392854 | 42.552563 | 4.394537 | RP
RP | 150m15 - cold formed steel joists :5,SHE-13.STEEL.dgn,Design Model:125522 | FD60 | 1.22364 | 0.000457 | 0.750089 | 0.751004 | 0.005421 | 0.00056 | 4.392854 | 42.552563 | 4.394537 | RP
RP | 150m15 - cold formed steel joists :5,SHE-13.STEEL.dgn,Design Model:125524 | FD60 | 1.22364 | 0.000457 | 0.750089 | 0.751004 | 0.005421 | 0.00056 | 4.392854 | 42.552563 | 4.394537 | RP
RP | 150m15 - cold formed steel joists :5,SHE-13.STEEL.dgn,Design Model:125526 | FD60 | 1.22364 | 0.000457 | 0.750089 | 0.751004 | 0.005421 | 0.00056 | 4.392854 | 42.552563 | 4.394537 | RP
RP | 150m15 - cold formed steel joists :5,SHE-13.STEEL.dgn,Design Model:125528 | FD60 | 1.22364 | 0.000457 | 0.750089 | 0.751004 | 0.005421 | 0.00056 | 4.392854 | 42.552563 | 4.394537 | RP
RP | 150m15 - cold formed steel joists :5,SHE-13.STEEL.dgn,Design Model:125530 | FD60 | 1.22364 | 0.000457 | 0.750089 | 0.751004 | 0.005421 | 0.00056 | 4.392854 | 42.552563 | 4.394537 | RP
4F | 150m15 - cold formed steel joists :5,SHE-13.STEEL.dgn,Design Model:142529 | FD60 | 2.92365 | 0.000457 | 1.7922 | 1.79311 | 0.012952 | 0.001338 | 10.495903 | 101.671391 | 10.499924 | 4F
4F | 150m15 - cold formed steel joists :5,SHE-13.STEEL.dgn,Design Model:142531 | FD60 | 2.92365 | 0.000457 | 1.7922 | 1.79311 | 0.012952 | 0.001338 | 10.495903 | 101.671391 | 10.499924 | 4F
4F | 150m15 - cold formed steel joists :5,SHE-13.STEEL.dgn,Design Model:142547 | FD60 | 4.2009 | 0.000457 | 2.57515 | 2.57607 | 0.01861 | 0.001922 | 15.081231 | 146.088398 | 15.087007 | 4F
4F | 150m15 - cold formed steel joists :5,SHE-13.STEEL.dgn,Design Model:142549 | FD60 | 4.2009 | 0.000457 | 2.57515 | 2.57607 | 0.01861 | 0.001922 | 15.081231 | 146.088398 | 15.087007 | 4F
4F | 150m15 - cold formed steel joists :5,SHE-13.STEEL.dgn,Design Model:142553 | FD60 | 1.96365 | 0.000457 | 1.20372 | 1.20463 | 0.008699 | 0.000898 | 7.049504 | 68.286911 | 7.052204 | 4F
4F | 150m15 - cold formed steel joists :5,SHE-13.STEEL.dgn,Design Model:142555 | FD60 | 1.96365 | 0.000457 | 1.20372 | 1.20463 | 0.008699 | 0.000898 | 7.049504 | 68.286911 | 7.052204 | 4F
4F | 150m15 - cold formed steel joists :5,SHE-13.STEEL.dgn,Design Model:142579 | FD60 | 4.2009 | 0.000457 | 2.57515 | 2.57607 | 0.01861 | 0.001922 | 15.081231 | 146.088398 | 15.087007 | 4F
4F | 150m15 - cold formed steel joists :5,SHE-13.STEEL.dgn,Design Model:142581 | FD60 | 4.2009 | 0.000457 | 2.57515 | 2.57607 | 0.01861 | 0.001922 | 15.081231 | 146.088398 | 15.087007 | 4F
4F | 150m15 - cold formed steel joists :5,SHE-13.STEEL.dgn,Design Model:142583 | FD60 | 2.97365 | 0.000457 | 1.82285 | 1.82376 | 0.013173 | 0.00136 | 10.675404 | 103.410166 | 10.679492 | 4F
4F | 150m15 - cold formed steel joists :5,SHE-13.STEEL.dgn,Design Model:142585 | FD60 | 2.97365 | 0.000457 | 1.82285 | 1.82376 | 0.013173 | 0.00136 | 10.675404 | 103.410166 | 10.679492 | 4F
4F | 150m15 - cold formed steel joists :5,SHE-13.STEEL.dgn,Design Model:142598 | FD60 | 3.98365 | 0.000457 | 2.44198 | 2.44289 | 0.017648 | 0.001823 | 14.301304 | 138.533421 | 14.306781 | 4F
4F | 150m15 - cold formed steel joists :5,SHE-13.STEEL.dgn,Design Model:142600 | FD60 | 3.98365 | 0.000457 | 2.44198 | 2.44289 | 0.017648 | 0.001823 | 14.301304 | 138.533421 | 14.306781 | 4F
4F | 150m15 - cold formed steel joists :5,SHE-13.STEEL.dgn,Design Model:142602 | FD60 | 3.98365 | 0.000457 | 2.44198 | 2.44289 | 0.017648 | 0.001823 | 14.301304 | 138.533421 | 14.306781 | 4F
4F | 150m15 - cold formed steel joists :5,SHE-13.STEEL.dgn,Design Model:142604 | FD60 | 3.98365 | 0.000457 | 2.44198 | 2.44289 | 0.017648 | 0.001823 | 14.301304 | 138.533421 | 14.306781 | 4F
4F | 150m15 - cold formed steel joists :5,SHE-13.STEEL.dgn,Design Model:142606 | FD60 | 3.98365 | 0.000457 | 2.44198 | 2.44289 | 0.017648 | 0.001823 | 14.301304 | 138.533421 | 14.306781 | 4F
4F | 150m15 - cold formed steel joists :5,SHE-13.STEEL.dgn,Design Model:142608 | FD60 | 3.98365 | 0.000457 | 2.44198 | 2.44289 | 0.017648 | 0.001823 | 14.301304 | 138.533421 | 14.306781 | 4F
4F | 150m15 - cold formed steel joists :5,SHE-13.STEEL.dgn,Design Model:142620 | FD60 | 4.01185 | 0.000457 | 2.45926 | 2.46018 | 0.017772 | 0.001835 | 14.402542 | 139.514090 | 14.408058 | 4F
4F | 150m15 - cold formed steel joists :5,SHE-13.STEEL.dgn,Design Model:142622 | FD60 | 4.01185 | 0.000457 | 2.45926 | 2.46018 | 0.017772 | 0.001835 | 14.402542 | 139.514090 | 14.408058 | 4F
4F | 150m15 - cold formed steel joists :5,SHE-13.STEEL.dgn,Design Model:142624 | FD60 | 4.01185 | 0.000457 | 2.45926 | 2.46018 | 0.017772 | 0.001835 | 14.402542 | 139.514090 | 14.408058 | 4F
4F | 150m15 - cold formed steel joists :5,SHE-13.STEEL.dgn,Design Model:142626 | FD60 | 4.01185 | 0.000457 | 2.45926 | 2.46018 | 0.017772 | 0.001835 | 14.402542 | 139.514090 | 14.408058 | 4F
4F | 150m15 - cold formed steel joists :5,SHE-13.STEEL.dgn,Design Model:142628 | FD60 | 4.01185 | 0.000457 | 2.45926 | 2.46018 | 0.017772 | 0.001835 | 14.402542 | 139.514090 | 14.408058 | 4F
4F | 150m15 - cold formed steel joists :5,SHE-13.STEEL.dgn,Design Model:142630 | FD60 | 4.01185 | 0.000457 | 2.45926 | 2.46018 | 0.017772 | 0.001835 | 14.402542 | 139.514090 | 14.408058 | 4F
4F | 150m15 - cold formed steel joists :5,SHE-13.STEEL.dgn,Design Model:142632 | FD60 | 3.97365 | 0.000457 | 2.43585 | 2.43676 | 0.017603 | 0.001818 | 14.265404 | 138.185666 | 14.270867 | 4F
4F | 150m15 - cold formed steel joists :5,SHE-13.STEEL.dgn,Design Model:142655 | FD60 | 3.97365 | 0.000457 | 2.43585 | 2.43676 | 0.017603 | 0.001818 | 14.265404 | 138.185666 | 14.270867 | 4F
4F | 150m15 - cold formed steel joists :5,SHE-13.STEEL.dgn,Design Model:142657 | FD60 | 4.04185 | 0.000457 | 2.47765 | 2.47857 | 0.017905 | 0.001849 | 14.510241 | 140.557355 | 14.515799 | 4F
4F | 150m15 - cold formed steel joists :5,SHE-13.STEEL.dgn,Design Model:142659 | FD60 | 4.04185 | 0.000457 | 2.47765 | 2.47857 | 0.017905 | 0.001849 | 14.510241 | 140.557355 | 14.515799 | 4F
4F | 150m15 - cold formed steel joists :5,SHE-13.STEEL.dgn,Design Model:142661 | FD60 | 3.97365 | 0.000457 | 2.43585 | 2.43676 | 0.017603 | 0.001818 | 14.265404 | 138.185666 | 14.270867 | 4F
4F | 150m15 - cold formed steel joists :5,SHE-13.STEEL.dgn,Design Model:142663 | FD60 | 4.04185 | 0.000457 | 2.47765 | 2.47857 | 0.017905 | 0.001849 | 14.510241 | 140.557355 | 14.515799 | 4F
4F | 150m15 - cold formed steel joists :5,SHE-13.STEEL.dgn,Design Model:142665 | FD60 | 3.97365 | 0.000457 | 2.43585 | 2.43676 | 0.017603 | 0.001818 | 14.265404 | 138.185666 | 14.270867 | 4F
4F | 150m15 - cold formed steel joists :5,SHE-13.STEEL.dgn,Design Model:142667 | FD60 | 4.04185 | 0.000457 | 2.47765 | 2.47857 | 0.017905 | 0.001849 | 14.510241 | 140.557355 | 14.515799 | 4F
4F | 150m15 - cold formed steel joists :5,SHE-13.STEEL.dgn,Design Model:142669 | FD60 | 3.97365 | 0.000457 | 2.43585 | 2.43676 | 0.017603 | 0.001818 | 14.265404 | 138.185666 | 14.270867 | 4F
4F | 150m15 - cold formed steel joists :5,SHE-13.STEEL.dgn,Design Model:142671 | FD60 | 4.04185 | 0.000457 | 2.47765 | 2.47857 | 0.017905 | 0.001849 | 14.510241 | 140.557355 | 14.515799 | 4F
4F | 150m15 - cold formed steel joists :5,SHE-13.STEEL.dgn,Design Model:142673 | FD60 | 3.97365 | 0.000457 | 2.43585 | 2.43676 | 0.017603 | 0.001818 | 14.265404 | 138.185666 | 14.270867 | 4F
4F | 150m15 - cold formed steel joists :5,SHE-13.STEEL.dgn,Design Model:142675 | FD60 | 4.04185 | 0.000457 | 2.47765 | 2.47857 | 0.017905 | 0.001849 | 14.510241 | 140.557355 | 14.515799 | 4F
4F | 150m15 - cold formed steel joists :5,SHE-13.STEEL.dgn,Design Model:142677 | FD60 | 3.9709 | 0.000457 | 2.43416 | 2.43508 | 0.017591 | 0.001817 | 14.255531 | 138.090033 | 14.260991 | 4F
5F | 150m15 - cold formed steel joists :5,SHE-13.STEEL.dgn,Design Model:142764 | FD60 | 3.9736 | 0.000457 | 2.43582 | 2.43673 | 0.017603 | 0.001818 | 14.265224 | 138.183927 | 14.270688 | 5F
5F | 150m15 - cold formed steel joists :5,SHE-13.STEEL.dgn,Design Model:142766 | FD60 | 3.9736 | 0.000457 | 2.43582 | 2.43673 | 0.017603 | 0.001818 | 14.265224 | 138.183927 | 14.270688 | 5F
5F | 150m15 - cold formed steel joists :5,SHE-13.STEEL.dgn,Design Model:142798 | FD60 | 3.9736 | 0.000457 | 2.43582 | 2.43673 | 0.017603 | 0.001818 | 14.265224 | 138.183927 | 14.270688 | 5F
5F | 150m15 - cold formed steel joists :5,SHE-13.STEEL.dgn,Design Model:142800 | FD60 | 3.9736 | 0.000457 | 2.43582 | 2.43673 | 0.017603 | 0.001818 | 14.265224 | 138.183927 | 14.270688 | 5F
5F | 150m15 - cold formed steel joists :5,SHE-13.STEEL.dgn,Design Model:142802 | FD60 | 3.9736 | 0.000457 | 2.43582 | 2.43673 | 0.017603 | 0.001818 | 14.265224 | 138.183927 | 14.270688 | 5F
5F | 150m15 - cold formed steel joists :5,SHE-13.STEEL.dgn,Design Model:142804 | FD60 | 3.9736 | 0.000457 | 2.43582 | 2.43673 | 0.017603 | 0.001818 | 14.265224 | 138.183927 | 14.270688 | 5F
5F | 150m15 - cold formed steel joists :5,SHE-13.STEEL.dgn,Design Model:142806 | FD60 | 3.9736 | 0.000457 | 2.43582 | 2.43673 | 0.017603 | 0.001818 | 14.265224 | 138.183927 | 14.270688 | 5F
5F | 150m15 - cold formed steel joists :5,SHE-13.STEEL.dgn,Design Model:142808 | FD60 | 3.9736 | 0.000457 | 2.43582 | 2.43673 | 0.017603 | 0.001818 | 14.265224 | 138.183927 | 14.270688 | 5F
5F | 150m15 - cold formed steel joists :5,SHE-13.STEEL.dgn,Design Model:142810 | FD60 | 3.9736 | 0.000457 | 2.43582 | 2.43673 | 0.017603 | 0.001818 | 14.265224 | 138.183927 | 14.270688 | 5F
5F | 150m15 - cold formed steel joists :5,SHE-13.STEEL.dgn,Design Model:142812 | FD60 | 3.9736 | 0.000457 | 2.43582 | 2.43673 | 0.017603 | 0.001818 | 14.265224 | 138.183927 | 14.270688 | 5F
5F | 150m15 - cold formed steel joists :5,SHE-13.STEEL.dgn,Design Model:142814 | FD60 | 3.9736 | 0.000457 | 2.43582 | 2.43673 | 0.017603 | 0.001818 | 14.265224 | 138.183927 | 14.270688 | 5F
5F | 150m15 - cold formed steel joists :5,SHE-13.STEEL.dgn,Design Model:142826 | FD60 | 4.20358 | 0.000457 | 2.57679 | 2.57771 | 0.018622 | 0.001923 | 15.090838 | 146.181456 | 15.096618 | 5F
5F | 150m15 - cold formed steel joists :5,SHE-13.STEEL.dgn,Design Model:142828 | FD60 | 4.20358 | 0.000457 | 2.57679 | 2.57771 | 0.018622 | 0.001923 | 15.090838 | 146.181456 | 15.096618 | 5F
5F | 150m15 - cold formed steel joists :5,SHE-13.STEEL.dgn,Design Model:142830 | FD60 | 4.20358 | 0.000457 | 2.57679 | 2.57771 | 0.018622 | 0.001923 | 15.090838 | 146.181456 | 15.096618 | 5F
5F | 150m15 - cold formed steel joists :5,SHE-13.STEEL.dgn,Design Model:142832 | FD60 | 4.20358 | 0.000457 | 2.57679 | 2.57771 | 0.018622 | 0.001923 | 15.090838 | 146.181456 | 15.096618 | 5F
5F | 150m15 - cold formed steel joists :5,SHE-13.STEEL.dgn,Design Model:142834 | FD60 | 4.20358 | 0.000457 | 2.57679 | 2.57771 | 0.018622 | 0.001923 | 15.090838 | 146.181456 | 15.096618 | 5F
5F | 150m15 - cold formed steel joists :5,SHE-13.STEEL.dgn,Design Model:142856 | FD60 | 4.2036 | 0.000457 | 2.57681 | 2.57772 | 0.018622 | 0.001923 | 15.090924 | 146.182292 | 15.096704 | 5F
5F | 150m15 - cold formed steel joists :5,SHE-13.STEEL.dgn,Design Model:142858 | FD60 | 4.2036 | 0.000457 | 2.57681 | 2.57772 | 0.018622 | 0.001923 | 15.090924 | 146.182292 | 15.096704 | 5F
5F | 150m15 - cold formed steel joists :5,SHE-13.STEEL.dgn,Design Model:142860 | FD60 | 4.2036 | 0.000457 | 2.57681 | 2.57772 | 0.018622 | 0.001923 | 15.090924 | 146.182292 | 15.096704 | 5F
5F | 150m15 - cold formed steel joists :5,SHE-13.STEEL.dgn,Design Model:142862 | FD60 | 4.2036 | 0.000457 | 2.57681 | 2.57772 | 0.018622 | 0.001923 | 15.090924 | 146.182292 | 15.096704 | 5F
5F | 150m15 - cold formed steel joists :5,SHE-13.STEEL.dgn,Design Model:142864 | FD60 | 4.2036 | 0.000457 | 2.57681 | 2.57772 | 0.018622 | 0.001923 | 15.090924 | 146.182292 | 15.096704 | 5F
5F | 150m15 - cold formed steel joists :5,SHE-13.STEEL.dgn,Design Model:142866 | FD60 | 4.2036 | 0.000457 | 2.57681 | 2.57772 | 0.018622 | 0.001923 | 15.090924 | 146.182292 | 15.096704 | 5F
5F | 150m15 - cold formed steel joists :5,SHE-13.STEEL.dgn,Design Model:142868 | FD60 | 4.2036 | 0.000457 | 2.57681 | 2.57772 | 0.018622 | 0.001923 | 15.090924 | 146.182292 | 15.096704 | 5F
5F | 150m15 - cold formed steel joists :5,SHE-13.STEEL.dgn,Design Model:142870 | FD120 | 4.2036 | 0.000457 | 2.57681 | 2.57772 | 0.018622 | 0.001923 | 15.090924 | 146.182292 | 15.096704 | 5F
5F | 150m15 - cold formed steel joists :5,SHE-13.STEEL.dgn,Design Model:142875 | FD60 | 4.2036 | 0.000457 | 2.57681 | 2.57772 | 0.018622 | 0.001923 | 15.090924 | 146.182292 | 15.096704 | 5F
5F | 150m15 - cold formed steel joists :5,SHE-13.STEEL.dgn,Design Model:142877 | FD60 | 4.2036 | 0.000457 | 2.57681 | 2.57772 | 0.018622 | 0.001923 | 15.090924 | 146.182292 | 15.096704 | 5F
5F | 150m15 - cold formed steel joists :5,SHE-13.STEEL.dgn,Design Model:142879 | FD60 | 4.2036 | 0.000457 | 2.57681 | 2.57772 | 0.018622 | 0.001923 | 15.090924 | 146.182292 | 15.096704 | 5F
5F | 150m15 - cold formed steel joists :5,SHE-13.STEEL.dgn,Design Model:142881 | FD60 | 4.2036 | 0.000457 | 2.57681 | 2.57772 | 0.018622 | 0.001923 | 15.090924 | 146.182292 | 15.096704 | 5F
5F | 150m15 - cold formed steel joists :5,SHE-13.STEEL.dgn,Design Model:142902 | FD60 | 3.9836 | 0.000457 | 2.44195 | 2.44286 | 0.017647 | 0.001822 | 14.301124 | 138.531682 | 14.306601 | 5F
5F | 150m15 - cold formed steel joists :5,SHE-13.STEEL.dgn,Design Model:142904 | FD60 | 3.9836 | 0.000457 | 2.44195 | 2.44286 | 0.017647 | 0.001822 | 14.301124 | 138.531682 | 14.306601 | 5F
5F | 150m15 - cold formed steel joists :5,SHE-13.STEEL.dgn,Design Model:142933 | FD60 | 3.9836 | 0.000457 | 2.44195 | 2.44286 | 0.017647 | 0.001822 | 14.301124 | 138.531682 | 14.306601 | 5F
5F | 150m15 - cold formed steel joists :5,SHE-13.STEEL.dgn,Design Model:142935 | FD60 | 3.9836 | 0.000457 | 2.44195 | 2.44286 | 0.017647 | 0.001822 | 14.301124 | 138.531682 | 14.306601 | 5F
5F | 150m15 - cold formed steel joists :5,SHE-13.STEEL.dgn,Design Model:142937 | FD60 | 3.9836 | 0.000457 | 2.44195 | 2.44286 | 0.017647 | 0.001822 | 14.301124 | 138.531682 | 14.306601 | 5F
5F | 150m15 - cold formed steel joists :5,SHE-13.STEEL.dgn,Design Model:142939 | FD60 | 3.9836 | 0.000457 | 2.44195 | 2.44286 | 0.017647 | 0.001822 | 14.301124 | 138.531682 | 14.306601 | 5F
5F | 150m15 - cold formed steel joists :5,SHE-13.STEEL.dgn,Design Model:142941 | FD60 | 3.9836 | 0.000457 | 2.44195 | 2.44286 | 0.017647 | 0.001822 | 14.301124 | 138.531682 | 14.306601 | 5F
5F | 150m15 - cold formed steel joists :5,SHE-13.STEEL.dgn,Design Model:142943 | FD60 | 3.9836 | 0.000457 | 2.44195 | 2.44286 | 0.017647 | 0.001822 | 14.301124 | 138.531682 | 14.306601 | 5F
5F | 150m15 - cold formed steel joists :5,SHE-13.STEEL.dgn,Design Model:142945 | FD60 | 3.9836 | 0.000457 | 2.44195 | 2.44286 | 0.017647 | 0.001822 | 14.301124 | 138.531682 | 14.306601 | 5F
5F | 150m15 - cold formed steel joists :5,SHE-13.STEEL.dgn,Design Model:142947 | FD60 | 3.9836 | 0.000457 | 2.44195 | 2.44286 | 0.017647 | 0.001822 | 14.301124 | 138.531682 | 14.306601 | 5F
5F | 150m15 - cold formed steel joists :5,SHE-13.STEEL.dgn,Design Model:142949 | FD60 | 3.9836 | 0.000457 | 2.44195 | 2.44286 | 0.017647 | 0.001822 | 14.301124 | 138.531682 | 14.306601 | 5F
5F | 150m15 - cold formed steel joists :5,SHE-13.STEEL.dgn,Design Model:142969 | FD60 | 3.9722 | 0.000457 | 2.43496 | 2.43587 | 0.017597 | 0.001817 | 14.260198 | 138.135241 | 14.265660 | 5F
5F | 150m15 - cold formed steel joists :5,SHE-13.STEEL.dgn,Design Model:142971 | FD60 | 3.9722 | 0.000457 | 2.43496 | 2.43587 | 0.017597 | 0.001817 | 14.260198 | 138.135241 | 14.265660 | 5F
5F | 150m15 - cold formed steel joists :5,SHE-13.STEEL.dgn,Design Model:142973 | FD60 | 3.9722 | 0.000457 | 2.43496 | 2.43587 | 0.017597 | 0.001817 | 14.260198 | 138.135241 | 14.265660 | 5F
5F | 150m15 - cold formed steel joists :5,SHE-13.STEEL.dgn,Design Model:142975 | FD60 | 3.9722 | 0.000457 | 2.43496 | 2.43587 | 0.017597 | 0.001817 | 14.260198 | 138.135241 | 14.265660 | 5F
5F | 150m15 - cold formed steel joists :5,SHE-13.STEEL.dgn,Design Model:142977 | FD60 | 3.9722 | 0.000457 | 2.43496 | 2.43587 | 0.017597 | 0.001817 | 14.260198 | 138.135241 | 14.265660 | 5F
5F | 150m15 - cold formed steel joists :5,SHE-13.STEEL.dgn,Design Model:142979 | FD60 | 3.9722 | 0.000457 | 2.43496 | 2.43587 | 0.017597 | 0.001817 | 14.260198 | 138.135241 | 14.265660 | 5F
5F | 150m15 - cold formed steel joists :5,SHE-13.STEEL.dgn,Design Model:142981 | FD60 | 3.9722 | 0.000457 | 2.43496 | 2.43587 | 0.017597 | 0.001817 | 14.260198 | 138.135241 | 14.265660 | 5F
5F | 150m15 - cold formed steel joists :5,SHE-13.STEEL.dgn,Design Model:142983 | FD60 | 3.9722 | 0.000457 | 2.43496 | 2.43587 | 0.017597 | 0.001817 | 14.260198 | 138.135241 | 14.265660 | 5F
5F | 150m15 - cold formed steel joists :5,SHE-13.STEEL.dgn,Design Model:142985 | FD60 | 3.9722 | 0.000457 | 2.43496 | 2.43587 | 0.017597 | 0.001817 | 14.260198 | 138.135241 | 14.265660 | 5F
5F | 150m15 - cold formed steel joists :5,SHE-13.STEEL.dgn,Design Model:142987 | FD60 | 3.9722 | 0.000457 | 2.43496 | 2.43587 | 0.017597 | 0.001817 | 14.260198 | 138.135241 | 14.265660 | 5F
5F | 150m15 - cold formed steel joists :5,SHE-13.STEEL.dgn,Design Model:142989 | FD60 | 3.9722 | 0.000457 | 2.43496 | 2.43587 | 0.017597 | 0.001817 | 14.260198 | 138.135241 | 14.265660 | 5F
5F | 150m15 - cold formed steel joists :5,SHE-13.STEEL.dgn,Design Model:143014 | FD60 | 4.2036 | 0.000457 | 2.57681 | 2.57772 | 0.018622 | 0.001923 | 15.090924 | 146.182292 | 15.096704 | 5F
5F | 150m15 - cold formed steel joists :5,SHE-13.STEEL.dgn,Design Model:143016 | FD60 | 4.2036 | 0.000457 | 2.57681 | 2.57772 | 0.018622 | 0.001923 | 15.090924 | 146.182292 | 15.096704 | 5F
5F | 150m15 - cold formed steel joists :5,SHE-13.STEEL.dgn,Design Model:143018 | FD60 | 4.2036 | 0.000457 | 2.57681 | 2.57772 | 0.018622 | 0.001923 | 15.090924 | 146.182292 | 15.096704 | 5F
5F | 150m15 - cold formed steel joists :5,SHE-13.STEEL.dgn,Design Model:143020 | FD60 | 4.2036 | 0.000457 | 2.57681 | 2.57772 | 0.018622 | 0.001923 | 15.090924 | 146.182292 | 15.096704 | 5F
5F | 150m15 - cold formed steel joists :5,SHE-13.STEEL.dgn,Design Model:143022 | FD60 | 4.2036 | 0.000457 | 2.57681 | 2.57772 | 0.018622 | 0.001923 | 15.090924 | 146.182292 | 15.096704 | 5F
5F | 150m15 - cold formed steel joists :5,SHE-13.STEEL.dgn,Design Model:143024 | FD60 | 4.2036 | 0.000457 | 2.57681 | 2.57772 | 0.018622 | 0.001923 | 15.090924 | 146.182292 | 15.096704 | 5F
5F | 150m15 - cold formed steel joists :5,SHE-13.STEEL.dgn,Design Model:143026 | FD60 | 4.2036 | 0.000457 | 2.57681 | 2.57772 | 0.018622 | 0.001923 | 15.090924 | 146.182292 | 15.096704 | 5F
5F | 150m15 - cold formed steel joists :5,SHE-13.STEEL.dgn,Design Model:143028 | FD60 | 4.2036 | 0.000457 | 2.57681 | 2.57772 | 0.018622 | 0.001923 | 15.090924 | 146.182292 | 15.096704 | 5F
5F | 150m15 - cold formed steel joists :5,SHE-13.STEEL.dgn,Design Model:143030 | FD60 | 4.2036 | 0.000457 | 2.57681 | 2.57772 | 0.018622 | 0.001923 | 15.090924 | 146.182292 | 15.096704 | 5F
5F | 150m15 - cold formed steel joists :5,SHE-13.STEEL.dgn,Design Model:143032 | FD60 | 4.2036 | 0.000457 | 2.57681 | 2.57772 | 0.018622 | 0.001923 | 15.090924 | 146.182292 | 15.096704 | 5F
5F | 150m15 - cold formed steel joists :5,SHE-13.STEEL.dgn,Design Model:143034 | FD60 | 4.2036 | 0.000457 | 2.57681 | 2.57772 | 0.018622 | 0.001923 | 15.090924 | 146.182292 | 15.096704 | 5F
5F | 150m15 - cold formed steel joists :5,SHE-13.STEEL.dgn,Design Model:143058 | FD60 | 4.2036 | 0.000457 | 2.57681 | 2.57772 | 0.018622 | 0.001923 | 15.090924 | 146.182292 | 15.096704 | 5F
5F | 150m15 - cold formed steel joists :5,SHE-13.STEEL.dgn,Design Model:143060 | FD60 | 4.2036 | 0.000457 | 2.57681 | 2.57772 | 0.018622 | 0.001923 | 15.090924 | 146.182292 | 15.096704 | 5F
5F | 150m15 - cold formed steel joists :5,SHE-13.STEEL.dgn,Design Model:143062 | FD60 | 4.2036 | 0.000457 | 2.57681 | 2.57772 | 0.018622 | 0.001923 | 15.090924 | 146.182292 | 15.096704 | 5F
5F | 150m15 - cold formed steel joists :5,SHE-13.STEEL.dgn,Design Model:143064 | FD60 | 4.2036 | 0.000457 | 2.57681 | 2.57772 | 0.018622 | 0.001923 | 15.090924 | 146.182292 | 15.096704 | 5F
5F | 150m15 - cold formed steel joists :5,SHE-13.STEEL.dgn,Design Model:143066 | FD60 | 4.2036 | 0.000457 | 2.57681 | 2.57772 | 0.018622 | 0.001923 | 15.090924 | 146.182292 | 15.096704 | 5F
5F | 150m15 - cold formed steel joists :5,SHE-13.STEEL.dgn,Design Model:143068 | FD60 | 4.2036 | 0.000457 | 2.57681 | 2.57772 | 0.018622 | 0.001923 | 15.090924 | 146.182292 | 15.096704 | 5F
5F | 150m15 - cold formed steel joists :5,SHE-13.STEEL.dgn,Design Model:143070 | FD60 | 4.2036 | 0.000457 | 2.57681 | 2.57772 | 0.018622 | 0.001923 | 15.090924 | 146.182292 | 15.096704 | 5F
5F | 150m15 - cold formed steel joists :5,SHE-13.STEEL.dgn,Design Model:143072 | FD60 | 4.2036 | 0.000457 | 2.57681 | 2.57772 | 0.018622 | 0.001923 | 15.090924 | 146.182292 | 15.096704 | 5F
5F | 150m15 - cold formed steel joists :5,SHE-13.STEEL.dgn,Design Model:143074 | FD60 | 4.2036 | 0.000457 | 2.57681 | 2.57772 | 0.018622 | 0.001923 | 15.090924 | 146.182292 | 15.096704 | 5F
5F | 150m15 - cold formed steel joists :5,SHE-13.STEEL.dgn,Design Model:143076 | FD60 | 4.2036 | 0.000457 | 2.57681 | 2.57772 | 0.018622 | 0.001923 | 15.090924 | 146.182292 | 15.096704 | 5F
5F | 150m15 - cold formed steel joists :5,SHE-13.STEEL.dgn,Design Model:143078 | FD60 | 4.2036 | 0.000457 | 2.57681 | 2.57772 | 0.018622 | 0.001923 | 15.090924 | 146.182292 | 15.096704 | 5F
5F | 150m15 - cold formed steel joists :5,SHE-13.STEEL.dgn,Design Model:143080 | FD60 | 4.2036 | 0.000457 | 2.57681 | 2.57772 | 0.018622 | 0.001923 | 15.090924 | 146.182292 | 15.096704 | 5F
5F | 150m15 - cold formed steel joists :5,SHE-13.STEEL.dgn,Design Model:143104 | FD60 | 3.9822 | 0.000457 | 2.44109 | 2.442 | 0.017641 | 0.001822 | 14.296098 | 138.482996 | 14.301574 | 5F
5F | 150m15 - cold formed steel joists :5,SHE-13.STEEL.dgn,Design Model:143106 | FD60 | 3.9822 | 0.000457 | 2.44109 | 2.442 | 0.017641 | 0.001822 | 14.296098 | 138.482996 | 14.301574 | 5F
5F | 150m15 - cold formed steel joists :5,SHE-13.STEEL.dgn,Design Model:143110 | FD60 | 3.9822 | 0.000457 | 2.44109 | 2.442 | 0.017641 | 0.001822 | 14.296098 | 138.482996 | 14.301574 | 5F
5F | 150m15 - cold formed steel joists :5,SHE-13.STEEL.dgn,Design Model:143112 | FD60 | 3.9822 | 0.000457 | 2.44109 | 2.442 | 0.017641 | 0.001822 | 14.296098 | 138.482996 | 14.301574 | 5F
5F | 150m15 - cold formed steel joists :5,SHE-13.STEEL.dgn,Design Model:143114 | FD60 | 3.9822 | 0.000457 | 2.44109 | 2.442 | 0.017641 | 0.001822 | 14.296098 | 138.482996 | 14.301574 | 5F
5F | 150m15 - cold formed steel joists :5,SHE-13.STEEL.dgn,Design Model:143116 | FD60 | 3.9822 | 0.000457 | 2.44109 | 2.442 | 0.017641 | 0.001822 | 14.296098 | 138.482996 | 14.301574 | 5F
5F | 150m15 - cold formed steel joists :5,SHE-13.STEEL.dgn,Design Model:143118 | FD60 | 3.9822 | 0.000457 | 2.44109 | 2.442 | 0.017641 | 0.001822 | 14.296098 | 138.482996 | 14.301574 | 5F
5F | 150m15 - cold formed steel joists :5,SHE-13.STEEL.dgn,Design Model:143120 | FD60 | 3.9822 | 0.000457 | 2.44109 | 2.442 | 0.017641 | 0.001822 | 14.296098 | 138.482996 | 14.301574 | 5F
5F | 150m15 - cold formed steel joists :5,SHE-13.STEEL.dgn,Design Model:143122 | FD60 | 3.9822 | 0.000457 | 2.44109 | 2.442 | 0.017641 | 0.001822 | 14.296098 | 138.482996 | 14.301574 | 5F
5F | 150m15 - cold formed steel joists :5,SHE-13.STEEL.dgn,Design Model:143124 | FD60 | 3.9822 | 0.000457 | 2.44109 | 2.442 | 0.017641 | 0.001822 | 14.296098 | 138.482996 | 14.301574 | 5F
5F | 150m15 - cold formed steel joists :5,SHE-13.STEEL.dgn,Design Model:143126 | FD60 | 3.9822 | 0.000457 | 2.44109 | 2.442 | 0.017641 | 0.001822 | 14.296098 | 138.482996 | 14.301574 | 5F
5F | 150m15 - cold formed steel joists :5,SHE-13.STEEL.dgn,Design Model:143138 | FD120 | 4.2064 | 0.000457 | 2.57852 | 2.57944 | 0.018634 | 0.001924 | 15.100976 | 146.279663 | 15.106760 | 5F
5F | 150m15 - cold formed steel joists :5,SHE-13.STEEL.dgn,Design Model:143140 | FD120 | 4.2064 | 0.000457 | 2.57852 | 2.57944 | 0.018634 | 0.001924 | 15.100976 | 146.279663 | 15.106760 | 5F
5F | 150m15 - cold formed steel joists :5,SHE-13.STEEL.dgn,Design Model:143142 | FD120 | 4.2064 | 0.000457 | 2.57852 | 2.57944 | 0.018634 | 0.001924 | 15.100976 | 146.279663 | 15.106760 | 5F
5F | 150m15 - cold formed steel joists :5,SHE-13.STEEL.dgn,Design Model:143144 | FD120 | 4.2064 | 0.000457 | 2.57852 | 2.57944 | 0.018634 | 0.001924 | 15.100976 | 146.279663 | 15.106760 | 5F
5F | 150m15 - cold formed steel joists :5,SHE-13.STEEL.dgn,Design Model:143146 | FD120 | 4.2064 | 0.000457 | 2.57852 | 2.57944 | 0.018634 | 0.001924 | 15.100976 | 146.279663 | 15.106760 | 5F
5F | 150m15 - cold formed steel joists :5,SHE-13.STEEL.dgn,Design Model:143148 | FD120 | 4.2064 | 0.000457 | 2.57852 | 2.57944 | 0.018634 | 0.001924 | 15.100976 | 146.279663 | 15.106760 | 5F
5F | 150m15 - cold formed steel joists :5,SHE-13.STEEL.dgn,Design Model:143167 | FD60 | 3.465 | 0.000457 | 2.12405 | 2.12496 | 0.01535 | 0.001585 | 12.439350 | 120.497107 | 12.444114 | 5F
5F | 150m15 - cold formed steel joists :5,SHE-13.STEEL.dgn,Design Model:143169 | FD60 | 3.465 | 0.000457 | 2.12405 | 2.12496 | 0.01535 | 0.001585 | 12.439350 | 120.497107 | 12.444114 | 5F
5F | 150m15 - cold formed steel joists :5,SHE-13.STEEL.dgn,Design Model:143171 | FD60 | 3.465 | 0.000457 | 2.12405 | 2.12496 | 0.01535 | 0.001585 | 12.439350 | 120.497107 | 12.444114 | 5F
5F | 150m15 - cold formed steel joists :5,SHE-13.STEEL.dgn,Design Model:143173 | FD60 | 3.915 | 0.000457 | 2.39989 | 2.40081 | 0.017343 | 0.001791 | 14.054850 | 136.146082 | 14.060233 | 5F
5F | 150m15 - cold formed steel joists :5,SHE-13.STEEL.dgn,Design Model:143175 | FD60 | 3.915 | 0.000457 | 2.39989 | 2.40081 | 0.017343 | 0.001791 | 14.054850 | 136.146082 | 14.060233 | 5F
5F | 150m15 - cold formed steel joists :5,SHE-13.STEEL.dgn,Design Model:143177 | FD60 | 3.915 | 0.000457 | 2.39989 | 2.40081 | 0.017343 | 0.001791 | 14.054850 | 136.146082 | 14.060233 | 5F
5F | 150m15 - cold formed steel joists :5,SHE-13.STEEL.dgn,Design Model:143184 | FD120 | 2.035 | 0.000458 | 1.24745 | 1.24837 | 0.009015 | 0.000931 | 7.305650 | 70.768142 | 7.308448 | 5F
5F | 150m15 - cold formed steel joists :5,SHE-13.STEEL.dgn,Design Model:143186 | FD120 | 2.035 | 0.000458 | 1.24745 | 1.24837 | 0.009015 | 0.000931 | 7.305650 | 70.768142 | 7.308448 | 5F
5F | 150m15 - cold formed steel joists :5,SHE-13.STEEL.dgn,Design Model:143188 | FD120 | 2.035 | 0.000458 | 1.24745 | 1.24837 | 0.009015 | 0.000931 | 7.305650 | 70.768142 | 7.308448 | 5F
5F | 150m15 - cold formed steel joists :5,SHE-13.STEEL.dgn,Design Model:143194 | FD60 | 1.9664 | 0.000458 | 1.2054 | 1.20632 | 0.008711 | 0.0009 | 7.059376 | 68.382543 | 7.062080 | 5F
5F | 150m15 - cold formed steel joists :5,SHE-13.STEEL.dgn,Design Model:143215 | FD60 | 2.6864 | 0.000457 | 1.64676 | 1.64768 | 0.011901 | 0.001229 | 9.644176 | 93.420903 | 9.647870 | 5F
5F | 150m15 - cold formed steel joists :5,SHE-13.STEEL.dgn,Design Model:143217 | FD60 | 2.6864 | 0.000457 | 1.64676 | 1.64768 | 0.011901 | 0.001229 | 9.644176 | 93.420903 | 9.647870 | 5F
5F | 150m15 - cold formed steel joists :5,SHE-13.STEEL.dgn,Design Model:143219 | FD60 | 2.6864 | 0.000457 | 1.64676 | 1.64768 | 0.011901 | 0.001229 | 9.644176 | 93.420903 | 9.647870 | 5F
5F | 150m15 - cold formed steel joists :5,SHE-13.STEEL.dgn,Design Model:143221 | FD60 | 2.2364 | 0.000458 | 1.37091 | 1.37183 | 0.009907 | 0.001023 | 8.028676 | 77.771928 | 8.031751 | 5F
5F | 150m15 - cold formed steel joists :5,SHE-13.STEEL.dgn,Design Model:143223 | FD60 | 2.2364 | 0.000458 | 1.37091 | 1.37183 | 0.009907 | 0.001023 | 8.028676 | 77.771928 | 8.031751 | 5F
5F | 150m15 - cold formed steel joists :5,SHE-13.STEEL.dgn,Design Model:143225 | FD60 | 2.2364 | 0.000458 | 1.37091 | 1.37183 | 0.009907 | 0.001023 | 8.028676 | 77.771928 | 8.031751 | 5F
5F | 150m15 - cold formed steel joists :5,SHE-13.STEEL.dgn,Design Model:143227 | FD60 | 1.5464 | 0.000458 | 0.947943 | 0.948858 | 0.006851 | 0.000707 | 5.551576 | 53.776833 | 5.553702 | 5F
5F | 150m15 - cold formed steel joists :5,SHE-13.STEEL.dgn,Design Model:143229 | FD60 | 1.5464 | 0.000458 | 0.947943 | 0.948858 | 0.006851 | 0.000707 | 5.551576 | 53.776833 | 5.553702 | 5F
5F | 150m15 - cold formed steel joists :5,SHE-13.STEEL.dgn,Design Model:143231 | FD60 | 1.5464 | 0.000458 | 0.947943 | 0.948858 | 0.006851 | 0.000707 | 5.551576 | 53.776833 | 5.553702 | 5F
5F | 150m15 - cold formed steel joists :5,SHE-13.STEEL.dgn,Design Model:143233 | FD60 | 1.1964 | 0.000458 | 0.733393 | 0.734308 | 0.0053 | 0.000547 | 4.295076 | 41.605408 | 4.296721 | 5F
5F | 150m15 - cold formed steel joists :5,SHE-13.STEEL.dgn,Design Model:143235 | FD60 | 1.1964 | 0.000458 | 0.733393 | 0.734308 | 0.0053 | 0.000547 | 4.295076 | 41.605408 | 4.296721 | 5F
5F | 150m15 - cold formed steel joists :5,SHE-13.STEEL.dgn,Design Model:143237 | FD60 | 1.1964 | 0.000458 | 0.733393 | 0.734308 | 0.0053 | 0.000547 | 4.295076 | 41.605408 | 4.296721 | 5F
RP | 150m15 - cold formed steel joists :5,SHE-13.STEEL.dgn,Design Model:143308 | FD60 | 3.97638 | 0.000457 | 2.43752 | 2.43844 | 0.017615 | 0.001819 | 14.275198 | 138.280544 | 14.280666 | RP
RP | 150m15 - cold formed steel joists :5,SHE-13.STEEL.dgn,Design Model:143310 | FD60 | 3.97638 | 0.000457 | 2.43752 | 2.43844 | 0.017615 | 0.001819 | 14.275198 | 138.280544 | 14.280666 | RP
RP | 150m15 - cold formed steel joists :5,SHE-13.STEEL.dgn,Design Model:143312 | FD60 | 3.97638 | 0.000457 | 2.43752 | 2.43844 | 0.017615 | 0.001819 | 14.275198 | 138.280544 | 14.280666 | RP
RP | 150m15 - cold formed steel joists :5,SHE-13.STEEL.dgn,Design Model:143314 | FD60 | 3.97638 | 0.000457 | 2.43752 | 2.43844 | 0.017615 | 0.001819 | 14.275198 | 138.280544 | 14.280666 | RP
RP | 150m15 - cold formed steel joists :5,SHE-13.STEEL.dgn,Design Model:143316 | FD60 | 3.97638 | 0.000457 | 2.43752 | 2.43844 | 0.017615 | 0.001819 | 14.275198 | 138.280544 | 14.280666 | RP
RP | 150m15 - cold formed steel joists :5,SHE-13.STEEL.dgn,Design Model:143318 | FD60 | 3.97638 | 0.000457 | 2.43752 | 2.43844 | 0.017615 | 0.001819 | 14.275198 | 138.280544 | 14.280666 | RP
RP | 150m15 - cold formed steel joists :5,SHE-13.STEEL.dgn,Design Model:143320 | FD60 | 3.97638 | 0.000457 | 2.43752 | 2.43844 | 0.017615 | 0.001819 | 14.275198 | 138.280544 | 14.280666 | RP
RP | 150m15 - cold formed steel joists :5,SHE-13.STEEL.dgn,Design Model:143322 | FD60 | 3.97638 | 0.000457 | 2.43752 | 2.43844 | 0.017615 | 0.001819 | 14.275198 | 138.280544 | 14.280666 | RP
RP | 150m15 - cold formed steel joists :5,SHE-13.STEEL.dgn,Design Model:143324 | FD60 | 3.97638 | 0.000457 | 2.43752 | 2.43844 | 0.017615 | 0.001819 | 14.275198 | 138.280544 | 14.280666 | RP
RP | 150m15 - cold formed steel joists :5,SHE-13.STEEL.dgn,Design Model:143326 | FD60 | 3.97638 | 0.000457 | 2.43752 | 2.43844 | 0.017615 | 0.001819 | 14.275198 | 138.280544 | 14.280666 | RP
RP | 150m15 - cold formed steel joists :5,SHE-13.STEEL.dgn,Design Model:143328 | FD60 | 3.97638 | 0.000457 | 2.43752 | 2.43844 | 0.017615 | 0.001819 | 14.275198 | 138.280544 | 14.280666 | RP
RP | 150m15 - cold formed steel joists :5,SHE-13.STEEL.dgn,Design Model:143330 | FD60 | 3.97638 | 0.000457 | 2.43752 | 2.43844 | 0.017615 | 0.001819 | 14.275198 | 138.280544 | 14.280666 | RP
RP | 150m15 - cold formed steel joists :5,SHE-13.STEEL.dgn,Design Model:143332 | FD60 | 3.97638 | 0.000457 | 2.43752 | 2.43844 | 0.017615 | 0.001819 | 14.275198 | 138.280544 | 14.280666 | RP
RP | 150m15 - cold formed steel joists :5,SHE-13.STEEL.dgn,Design Model:143334 | FD60 | 3.97638 | 0.000457 | 2.43752 | 2.43844 | 0.017615 | 0.001819 | 14.275198 | 138.280544 | 14.280666 | RP
RP | 150m15 - cold formed steel joists :5,SHE-13.STEEL.dgn,Design Model:143336 | FD60 | 3.97638 | 0.000457 | 2.43752 | 2.43844 | 0.017615 | 0.001819 | 14.275198 | 138.280544 | 14.280666 | RP
RP | 150m15 - cold formed steel joists :5,SHE-13.STEEL.dgn,Design Model:143338 | FD60 | 3.97638 | 0.000457 | 2.43752 | 2.43844 | 0.017615 | 0.001819 | 14.275198 | 138.280544 | 14.280666 | RP
RP | 150m15 - cold formed steel joists :5,SHE-13.STEEL.dgn,Design Model:143356 | FD60 | 1.9664 | 0.000457 | 1.2054 | 1.20632 | 0.008711 | 0.0009 | 7.059376 | 68.382543 | 7.062080 | RP
RP | 150m15 - cold formed steel joists :5,SHE-13.STEEL.dgn,Design Model:143372 | FD60 | 4.2064 | 0.000457 | 2.57852 | 2.57944 | 0.018634 | 0.001924 | 15.100976 | 146.279663 | 15.106760 | RP
RP | 150m15 - cold formed steel joists :5,SHE-13.STEEL.dgn,Design Model:143374 | FD60 | 4.2064 | 0.000457 | 2.57852 | 2.57944 | 0.018634 | 0.001924 | 15.100976 | 146.279663 | 15.106760 | RP
RP | 150m15 - cold formed steel joists :5,SHE-13.STEEL.dgn,Design Model:143376 | FD60 | 4.2064 | 0.000457 | 2.57852 | 2.57944 | 0.018634 | 0.001924 | 15.100976 | 146.279663 | 15.106760 | RP
RP | 150m15 - cold formed steel joists :5,SHE-13.STEEL.dgn,Design Model:143378 | FD60 | 4.2064 | 0.000457 | 2.57852 | 2.57944 | 0.018634 | 0.001924 | 15.100976 | 146.279663 | 15.106760 | RP
RP | 150m15 - cold formed steel joists :5,SHE-13.STEEL.dgn,Design Model:143380 | FD60 | 4.2064 | 0.000457 | 2.57852 | 2.57944 | 0.018634 | 0.001924 | 15.100976 | 146.279663 | 15.106760 | RP
RP | 150m15 - cold formed steel joists :5,SHE-13.STEEL.dgn,Design Model:143393 | FD60 | 2.0364 | 0.000457 | 1.24831 | 1.24923 | 0.009021 | 0.000932 | 7.310676 | 70.816828 | 7.313476 | RP
RP | 150m15 - cold formed steel joists :5,SHE-13.STEEL.dgn,Design Model:143395 | FD60 | 2.0364 | 0.000457 | 1.24831 | 1.24923 | 0.009021 | 0.000932 | 7.310676 | 70.816828 | 7.313476 | RP
RP | 150m15 - cold formed steel joists :5,SHE-13.STEEL.dgn,Design Model:143397 | FD60 | 2.0364 | 0.000457 | 1.24831 | 1.24923 | 0.009021 | 0.000932 | 7.310676 | 70.816828 | 7.313476 | RP
RP | 150m15 - cold formed steel joists :5,SHE-13.STEEL.dgn,Design Model:143408 | FD60 | 0.6964 | 0.000457 | 0.426893 | 0.427808 | 0.003085 | 0.000319 | 2.500076 | 24.217658 | 2.501034 | RP
RP | 150m15 - cold formed steel joists :5,SHE-13.STEEL.dgn,Design Model:143410 | FD60 | 3.3064 | 0.000457 | 2.02682 | 2.02774 | 0.014647 | 0.001513 | 11.869976 | 114.981713 | 11.874522 | RP
RP | 150m15 - cold formed steel joists :5,SHE-13.STEEL.dgn,Design Model:143412 | FD60 | 3.3064 | 0.000457 | 2.02682 | 2.02774 | 0.014647 | 0.001513 | 11.869976 | 114.981713 | 11.874522 | RP
RP | 150m15 - cold formed steel joists :5,SHE-13.STEEL.dgn,Design Model:143414 | FD60 | 3.3064 | 0.000457 | 2.02682 | 2.02774 | 0.014647 | 0.001513 | 11.869976 | 114.981713 | 11.874522 | RP
RP | 150m15 - cold formed steel joists :5,SHE-13.STEEL.dgn,Design Model:143416 | FD60 | 3.3064 | 0.000457 | 2.02682 | 2.02774 | 0.014647 | 0.001513 | 11.869976 | 114.981713 | 11.874522 | RP
RP | 150m15 - cold formed steel joists :5,SHE-13.STEEL.dgn,Design Model:143418 | FD60 | 3.3064 | 0.000457 | 2.02682 | 2.02774 | 0.014647 | 0.001513 | 11.869976 | 114.981713 | 11.874522 | RP
RP | 150m15 - cold formed steel joists :5,SHE-13.STEEL.dgn,Design Model:143430 | FD60 | 4.2064 | 0.000457 | 2.57852 | 2.57944 | 0.018634 | 0.001924 | 15.100976 | 146.279663 | 15.106760 | RP
RP | 150m15 - cold formed steel joists :5,SHE-13.STEEL.dgn,Design Model:143432 | FD60 | 4.2064 | 0.000457 | 2.57852 | 2.57944 | 0.018634 | 0.001924 | 15.100976 | 146.279663 | 15.106760 | RP
RP | 150m15 - cold formed steel joists :5,SHE-13.STEEL.dgn,Design Model:143434 | FD60 | 4.2064 | 0.000457 | 2.57852 | 2.57944 | 0.018634 | 0.001924 | 15.100976 | 146.279663 | 15.106760 | RP
RP | 150m15 - cold formed steel joists :5,SHE-13.STEEL.dgn,Design Model:143436 | FD60 | 4.2064 | 0.000457 | 2.57852 | 2.57944 | 0.018634 | 0.001924 | 15.100976 | 146.279663 | 15.106760 | RP
RP | 150m15 - cold formed steel joists :5,SHE-13.STEEL.dgn,Design Model:143438 | FD60 | 4.2064 | 0.000457 | 2.57852 | 2.57944 | 0.018634 | 0.001924 | 15.100976 | 146.279663 | 15.106760 | RP
RP | 150m15 - cold formed steel joists :5,SHE-13.STEEL.dgn,Design Model:143470 | FD60 | 4.2064 | 0.000457 | 2.57852 | 2.57944 | 0.018634 | 0.001924 | 15.100976 | 146.279663 | 15.106760 | RP
RP | 150m15 - cold formed steel joists :5,SHE-13.STEEL.dgn,Design Model:143472 | FD60 | 4.2064 | 0.000457 | 2.57852 | 2.57944 | 0.018634 | 0.001924 | 15.100976 | 146.279663 | 15.106760 | RP
RP | 150m15 - cold formed steel joists :5,SHE-13.STEEL.dgn,Design Model:143474 | FD60 | 4.2064 | 0.000457 | 2.57852 | 2.57944 | 0.018634 | 0.001924 | 15.100976 | 146.279663 | 15.106760 | RP
RP | 150m15 - cold formed steel joists :5,SHE-13.STEEL.dgn,Design Model:143476 | FD60 | 4.2064 | 0.000457 | 2.57852 | 2.57944 | 0.018634 | 0.001924 | 15.100976 | 146.279663 | 15.106760 | RP
RP | 150m15 - cold formed steel joists :5,SHE-13.STEEL.dgn,Design Model:143478 | FD60 | 4.2064 | 0.000457 | 2.57852 | 2.57944 | 0.018634 | 0.001924 | 15.100976 | 146.279663 | 15.106760 | RP
RP | 150m15 - cold formed steel joists :5,SHE-13.STEEL.dgn,Design Model:143480 | FD60 | 4.2064 | 0.000457 | 2.57852 | 2.57944 | 0.018634 | 0.001924 | 15.100976 | 146.279663 | 15.106760 | RP
RP | 150m15 - cold formed steel joists :5,SHE-13.STEEL.dgn,Design Model:143482 | FD60 | 4.2064 | 0.000457 | 2.57852 | 2.57944 | 0.018634 | 0.001924 | 15.100976 | 146.279663 | 15.106760 | RP
RP | 150m15 - cold formed steel joists :5,SHE-13.STEEL.dgn,Design Model:143484 | FD60 | 4.2064 | 0.000457 | 2.57852 | 2.57944 | 0.018634 | 0.001924 | 15.100976 | 146.279663 | 15.106760 | RP
RP | 150m15 - cold formed steel joists :5,SHE-13.STEEL.dgn,Design Model:143486 | FD60 | 4.2064 | 0.000457 | 2.57852 | 2.57944 | 0.018634 | 0.001924 | 15.100976 | 146.279663 | 15.106760 | RP
RP | 150m15 - cold formed steel joists :5,SHE-13.STEEL.dgn,Design Model:143488 | FD60 | 4.2064 | 0.000457 | 2.57852 | 2.57944 | 0.018634 | 0.001924 | 15.100976 | 146.279663 | 15.106760 | RP
RP | 150m15 - cold formed steel joists :5,SHE-13.STEEL.dgn,Design Model:143490 | FD60 | 4.2064 | 0.000457 | 2.57852 | 2.57944 | 0.018634 | 0.001924 | 15.100976 | 146.279663 | 15.106760 | RP
RP | 150m15 - cold formed steel joists :5,SHE-13.STEEL.dgn,Design Model:143521 | FD60 | 3.97637 | 0.000457 | 2.43751 | 2.43843 | 0.017615 | 0.001819 | 14.275154 | 138.280112 | 14.280621 | RP
RP | 150m15 - cold formed steel joists :5,SHE-13.STEEL.dgn,Design Model:143523 | FD60 | 3.97637 | 0.000457 | 2.43751 | 2.43843 | 0.017615 | 0.001819 | 14.275154 | 138.280112 | 14.280621 | RP
RP | 150m15 - cold formed steel joists :5,SHE-13.STEEL.dgn,Design Model:143525 | FD60 | 3.97637 | 0.000457 | 2.43751 | 2.43843 | 0.017615 | 0.001819 | 14.275154 | 138.280112 | 14.280621 | RP
RP | 150m15 - cold formed steel joists :5,SHE-13.STEEL.dgn,Design Model:143527 | FD60 | 3.97637 | 0.000457 | 2.43751 | 2.43843 | 0.017615 | 0.001819 | 14.275154 | 138.280112 | 14.280621 | RP
RP | 150m15 - cold formed steel joists :5,SHE-13.STEEL.dgn,Design Model:143529 | FD60 | 3.97637 | 0.000457 | 2.43751 | 2.43843 | 0.017615 | 0.001819 | 14.275154 | 138.280112 | 14.280621 | RP
RP | 150m15 - cold formed steel joists :5,SHE-13.STEEL.dgn,Design Model:143532 | FD60 | 3.97637 | 0.000457 | 2.43751 | 2.43843 | 0.017615 | 0.001819 | 14.275154 | 138.280112 | 14.280621 | RP
RP | 150m15 - cold formed steel joists :5,SHE-13.STEEL.dgn,Design Model:143534 | FD60 | 3.97637 | 0.000457 | 2.43751 | 2.43843 | 0.017615 | 0.001819 | 14.275154 | 138.280112 | 14.280621 | RP
RP | 150m15 - cold formed steel joists :5,SHE-13.STEEL.dgn,Design Model:143536 | FD60 | 3.97637 | 0.000457 | 2.43751 | 2.43843 | 0.017615 | 0.001819 | 14.275154 | 138.280112 | 14.280621 | RP
RP | 150m15 - cold formed steel joists :5,SHE-13.STEEL.dgn,Design Model:143538 | FD60 | 3.97637 | 0.000457 | 2.43751 | 2.43843 | 0.017615 | 0.001819 | 14.275154 | 138.280112 | 14.280621 | RP
RP | 150m15 - cold formed steel joists :5,SHE-13.STEEL.dgn,Design Model:143540 | FD60 | 3.97637 | 0.000457 | 2.43751 | 2.43843 | 0.017615 | 0.001819 | 14.275154 | 138.280112 | 14.280621 | RP
RP | 150m15 - cold formed steel joists :5,SHE-13.STEEL.dgn,Design Model:143542 | FD60 | 3.97637 | 0.000457 | 2.43751 | 2.43843 | 0.017615 | 0.001819 | 14.275154 | 138.280112 | 14.280621 | RP
RP | 150m15 - cold formed steel joists :5,SHE-13.STEEL.dgn,Design Model:143544 | FD60 | 3.97637 | 0.000457 | 2.43751 | 2.43843 | 0.017615 | 0.001819 | 14.275154 | 138.280112 | 14.280621 | RP
RP | 150m15 - cold formed steel joists :5,SHE-13.STEEL.dgn,Design Model:143546 | FD60 | 3.97637 | 0.000457 | 2.43751 | 2.43843 | 0.017615 | 0.001819 | 14.275154 | 138.280112 | 14.280621 | RP
RP | 150m15 - cold formed steel joists :5,SHE-13.STEEL.dgn,Design Model:143548 | FD60 | 3.97637 | 0.000457 | 2.43751 | 2.43843 | 0.017615 | 0.001819 | 14.275154 | 138.280112 | 14.280621 | RP
RP | 150m15 - cold formed steel joists :5,SHE-13.STEEL.dgn,Design Model:143550 | FD60 | 3.97637 | 0.000457 | 2.43751 | 2.43843 | 0.017615 | 0.001819 | 14.275154 | 138.280112 | 14.280621 | RP
RP | 150m15 - cold formed steel joists :5,SHE-13.STEEL.dgn,Design Model:143552 | FD60 | 3.97637 | 0.000457 | 2.43751 | 2.43843 | 0.017615 | 0.001819 | 14.275154 | 138.280112 | 14.280621 | RP
4F | 150m15 - cold formed steel joists :5,SHE-13.STEEL.dgn,Design Model:154804 | FD120 | 2.91044 | 0.000457 | 1.7841 | 1.78502 | 0.012893 | 0.001332 | 10.448492 | 101.212128 | 10.452494 | 4F
4F | 150m15 - cold formed steel joists :5,SHE-13.STEEL.dgn,Design Model:154806 | FD120 | 2.91044 | 0.000457 | 1.7841 | 1.78502 | 0.012893 | 0.001332 | 10.448492 | 101.212128 | 10.452494 | 4F
4F | 150m15 - cold formed steel joists :5,SHE-13.STEEL.dgn,Design Model:154808 | FD120 | 2.91044 | 0.000457 | 1.7841 | 1.78502 | 0.012893 | 0.001332 | 10.448492 | 101.212128 | 10.452494 | 4F
4F | 150m15 - cold formed steel joists :5,SHE-13.STEEL.dgn,Design Model:154810 | FD120 | 2.91044 | 0.000457 | 1.7841 | 1.78502 | 0.012893 | 0.001332 | 10.448492 | 101.212128 | 10.452494 | 4F
4F | 150m15 - cold formed steel joists :5,SHE-13.STEEL.dgn,Design Model:154812 | FD120 | 2.91044 | 0.000457 | 1.7841 | 1.78502 | 0.012893 | 0.001332 | 10.448492 | 101.212128 | 10.452494 | 4F
4F | 150m15 - cold formed steel joists :5,SHE-13.STEEL.dgn,Design Model:154814 | FD120 | 2.91044 | 0.000457 | 1.7841 | 1.78502 | 0.012893 | 0.001332 | 10.448492 | 101.212128 | 10.452494 | 4F
RP | 150m15 - cold formed steel joists :5,SHE-13.STEEL.dgn,Design Model:190789 | FD60 | 1.67561 | 0.000457 | 1.02715 | 1.02807 | 0.007423 | 0.000767 | 6.015453 | 58.270306 | 6.017757 | RP
RP | 150m15 - cold formed steel joists :5,SHE-13.STEEL.dgn,Design Model:190798 | FD60 | 1.67223 | 0.000457 | 1.02508 | 1.02599 | 0.007408 | 0.000765 | 6.003304 | 58.152622 | 6.005604 | RP
RP | 150m15 - cold formed steel joists :5,SHE-13.STEEL.dgn,Design Model:190814 | FD60 | 1.67561 | 0.000457 | 1.02715 | 1.02807 | 0.007423 | 0.000767 | 6.015453 | 58.270306 | 6.017757 | RP
RP | 150m15 - cold formed steel joists :5,SHE-13.STEEL.dgn,Design Model:190816 | FD60 | 1.67223 | 0.000457 | 1.02508 | 1.02599 | 0.007408 | 0.000765 | 6.003304 | 58.152622 | 6.005604 | RP
RP | 150m15 - cold formed steel joists :5,SHE-13.STEEL.dgn,Design Model:190822 | FD60 | 0.579603 | 0.000457 | 0.355297 | 0.356212 | 0.002568 | 0.000265 | 2.080774 | 20.155981 | 2.081571 | RP
RP | 150m15 - cold formed steel joists :5,SHE-13.STEEL.dgn,Design Model:190824 | FD60 | 0.579603 | 0.000457 | 0.355297 | 0.356212 | 0.002568 | 0.000265 | 2.080774 | 20.155981 | 2.081571 | RP
RP | 150m15 - cold formed steel joists :5,SHE-13.STEEL.dgn,Design Model:190826 | FD60 | 0.579603 | 0.000457 | 0.355297 | 0.356212 | 0.002568 | 0.000265 | 2.080774 | 20.155981 | 2.081571 | RP
RP | 150m15 - cold formed steel joists :5,SHE-13.STEEL.dgn,Design Model:190828 | FD60 | 0.579603 | 0.000457 | 0.355297 | 0.356212 | 0.002568 | 0.000265 | 2.080774 | 20.155981 | 2.081571 | RP
RP | 150m15 - cold formed steel joists :5,SHE-13.STEEL.dgn,Design Model:190830 | FD60 | 0.579603 | 0.000457 | 0.355297 | 0.356212 | 0.002568 | 0.000265 | 2.080774 | 20.155981 | 2.081571 | RP
RP | 150m15 - cold formed steel joists :5,SHE-13.STEEL.dgn,Design Model:190832 | FD60 | 0.579603 | 0.000457 | 0.355297 | 0.356212 | 0.002568 | 0.000265 | 2.080774 | 20.155981 | 2.081571 | RP
RP | 150m15 - cold formed steel joists :5,SHE-13.STEEL.dgn,Design Model:190836 | FD60 | 0.579603 | 0.000457 | 0.355297 | 0.356212 | 0.002568 | 0.000265 | 2.080774 | 20.155981 | 2.081571 | RP
RP | 150m15 - cold formed steel joists :5,SHE-13.STEEL.dgn,Design Model:190839 | FD60 | 0.579603 | 0.000457 | 0.355297 | 0.356212 | 0.002568 | 0.000265 | 2.080774 | 20.155981 | 2.081571 | RP
RP | 150m15 - cold formed steel joists :5,SHE-13.STEEL.dgn,Design Model:190841 | FD60 | 0.579603 | 0.000457 | 0.355297 | 0.356212 | 0.002568 | 0.000265 | 2.080774 | 20.155981 | 2.081571 | RP
RP | 150m15 - cold formed steel joists :5,SHE-13.STEEL.dgn,Design Model:190843 | FD60 | 0.579603 | 0.000457 | 0.355297 | 0.356212 | 0.002568 | 0.000265 | 2.080774 | 20.155981 | 2.081571 | RP
RP | 150m15 - cold formed steel joists :5,SHE-13.STEEL.dgn,Design Model:190845 | FD60 | 0.579603 | 0.000457 | 0.355297 | 0.356212 | 0.002568 | 0.000265 | 2.080774 | 20.155981 | 2.081571 | RP
RP | 150m15 - cold formed steel joists :5,SHE-13.STEEL.dgn,Design Model:190847 | FD60 | 0.579603 | 0.000457 | 0.355297 | 0.356212 | 0.002568 | 0.000265 | 2.080774 | 20.155981 | 2.081571 | RP
RP | 150m15 - cold formed steel joists :5,SHE-13.STEEL.dgn,Design Model:190849 | FD60 | 0.579603 | 0.000457 | 0.355297 | 0.356212 | 0.002568 | 0.000265 | 2.080774 | 20.155981 | 2.081571 | RP
RP | 150m15 - cold formed steel joists :5,SHE-13.STEEL.dgn,Design Model:190851 | FD60 | 0.579603 | 0.000457 | 0.355297 | 0.356212 | 0.002568 | 0.000265 | 2.080774 | 20.155981 | 2.081571 | RP
RP | 150m15 - cold formed steel joists :5,SHE-13.STEEL.dgn,Design Model:190853 | FD60 | 0.579603 | 0.000457 | 0.355297 | 0.356212 | 0.002568 | 0.000265 | 2.080774 | 20.155981 | 2.081571 | RP
RP | 150m15 - cold formed steel joists :5,SHE-13.STEEL.dgn,Design Model:190855 | FD60 | 0.579603 | 0.000457 | 0.355297 | 0.356212 | 0.002568 | 0.000265 | 2.080774 | 20.155981 | 2.081571 | RP
RP | 150m15 - cold formed steel joists :5,SHE-13.STEEL.dgn,Design Model:190857 | FD60 | 0.579603 | 0.000457 | 0.355297 | 0.356212 | 0.002568 | 0.000265 | 2.080774 | 20.155981 | 2.081571 | RP
RP | 150m15 - cold formed steel joists :5,SHE-13.STEEL.dgn,Design Model:190859 | FD60 | 0.579603 | 0.000457 | 0.355297 | 0.356212 | 0.002568 | 0.000265 | 2.080774 | 20.155981 | 2.081571 | RP
RP | 150m15 - cold formed steel joists :5,SHE-13.STEEL.dgn,Design Model:190861 | FD60 | 0.579603 | 0.000457 | 0.355297 | 0.356212 | 0.002568 | 0.000265 | 2.080774 | 20.155981 | 2.081571 | RP
RP | 150m15 - cold formed steel joists :5,SHE-13.STEEL.dgn,Design Model:190863 | FD60 | 0.579603 | 0.000457 | 0.355297 | 0.356212 | 0.002568 | 0.000265 | 2.080774 | 20.155981 | 2.081571 | RP
RP | 150m15 - cold formed steel joists :5,SHE-13.STEEL.dgn,Design Model:190865 | FD60 | 0.579603 | 0.000457 | 0.355297 | 0.356212 | 0.002568 | 0.000265 | 2.080774 | 20.155981 | 2.081571 | RP
RP | 150m15 - cold formed steel joists :5,SHE-13.STEEL.dgn,Design Model:190867 | FD60 | 0.579603 | 0.000457 | 0.355297 | 0.356212 | 0.002568 | 0.000265 | 2.080774 | 20.155981 | 2.081571 | RP
RP | 150m15 - cold formed steel joists :5,SHE-13.STEEL.dgn,Design Model:190869 | FD60 | 0.579603 | 0.000457 | 0.355297 | 0.356212 | 0.002568 | 0.000265 | 2.080774 | 20.155981 | 2.081571 | RP
RP | 150m15 - cold formed steel joists :5,SHE-13.STEEL.dgn,Design Model:190871 | FD60 | 0.579603 | 0.000457 | 0.355297 | 0.356212 | 0.002568 | 0.000265 | 2.080774 | 20.155981 | 2.081571 | RP
RP | 150m15 - cold formed steel joists :5,SHE-13.STEEL.dgn,Design Model:190873 | FD60 | 0.579603 | 0.000457 | 0.355297 | 0.356212 | 0.002568 | 0.000265 | 2.080774 | 20.155981 | 2.081571 | RP
RP | 150m15 - cold formed steel joists :5,SHE-13.STEEL.dgn,Design Model:190875 | FD60 | 0.579603 | 0.000457 | 0.355297 | 0.356212 | 0.002568 | 0.000265 | 2.080774 | 20.155981 | 2.081571 | RP
RP | 150m15 - cold formed steel joists :5,SHE-13.STEEL.dgn,Design Model:190877 | FD60 | 0.579603 | 0.000457 | 0.355297 | 0.356212 | 0.002568 | 0.000265 | 2.080774 | 20.155981 | 2.081571 | RP
RP | 150m15 - cold formed steel joists :5,SHE-13.STEEL.dgn,Design Model:190879 | FD60 | 0.579603 | 0.000457 | 0.355297 | 0.356212 | 0.002568 | 0.000265 | 2.080774 | 20.155981 | 2.081571 | RP
RP | 150m15 - cold formed steel joists :5,SHE-13.STEEL.dgn,Design Model:190881 | FD60 | 0.579603 | 0.000457 | 0.355297 | 0.356212 | 0.002568 | 0.000265 | 2.080774 | 20.155981 | 2.081571 | RP
RP | 150m15 - cold formed steel joists :5,SHE-13.STEEL.dgn,Design Model:190883 | FD60 | 0.579603 | 0.000457 | 0.355297 | 0.356212 | 0.002568 | 0.000265 | 2.080774 | 20.155981 | 2.081571 | RP
RP | 150m15 - cold formed steel joists :5,SHE-13.STEEL.dgn,Design Model:190885 | FD60 | 0.579603 | 0.000457 | 0.355297 | 0.356212 | 0.002568 | 0.000265 | 2.080774 | 20.155981 | 2.081571 | RP
RP | 150m15 - cold formed steel joists :5,SHE-13.STEEL.dgn,Design Model:190887 | FD60 | 0.579603 | 0.000457 | 0.355297 | 0.356212 | 0.002568 | 0.000265 | 2.080774 | 20.155981 | 2.081571 | RP
RP | 150m15 - cold formed steel joists :5,SHE-13.STEEL.dgn,Design Model:190889 | FD60 | 0.579603 | 0.000457 | 0.355297 | 0.356212 | 0.002568 | 0.000265 | 2.080774 | 20.155981 | 2.081571 | RP
RP | 150m15 - cold formed steel joists :5,SHE-13.STEEL.dgn,Design Model:190891 | FD60 | 0.579603 | 0.000457 | 0.355297 | 0.356212 | 0.002568 | 0.000265 | 2.080774 | 20.155981 | 2.081571 | RP

# IfcBuildingElementPart (3784)
Name | In | Material
10 x 1 | GF | A_BSUK_Walls_Timber
18 x 2 | GF | A_BSUK_WallInternal_Finishes_Plasterboard
5 x 3 | GF | A_BSUK_WallInternal_Finishes_Plasterboard
3 x 4 | GF | Air Cavity
3 x 5 | GF | A_BSUK_Insulation
3 x 6 | GF | Air Cavity
3 x 7 | GF | A_BSUK_WallInternal_Finishes_Plasterboard
5 x 8 | GF | A_BSUK_WallInternal_Finishes_Plasterboard
4 x 9 | GF | A_BSUK_Walls_Timber
5 x 3 | GF | Air Cavity
5 x 4 | GF | A_BSUK_Insulation
7 x 5 | GF | Air Cavity
5 x 6 | GF | A_BSUK_WallInternal_Finishes_Plasterboard
5 x 7 | GF | A_BSUK_Walls_Timber
3 x 2 | GF | A_BSUK_Walls_Timber
2 x 4 | GF | A_BSUK_WallInternal_Finishes_Plasterboard
2 x 6 | GF | A_BSUK_Insulation
2 x 7 | GF | Air Cavity
9 | GF | A_BSUK_WallInternal_Finishes_Plasterboard
10 | GF | A_BSUK_Walls_Timber
11 | GF | A_BSUK_Walls_Timber
11 x 1 | GF | A_BSUK_Insulation
11 x 3 | GF | A_BSUK_Walls_Timber
2 x 1 | MF | A_BSUK_Walls_Timber
13 x 2 | MF | A_BSUK_WallInternal_Finishes_Plasterboard
2 x 3 | MF | Air Cavity
2 x 4 | MF | A_BSUK_Insulation
2 x 5 | MF | Air Cavity
2 x 6 | MF | A_BSUK_WallInternal_Finishes_Plasterboard
2 x 7 | MF | A_BSUK_Walls_Timber
11 x 1 | MF | A_BSUK_Insulation
11 x 3 | MF | A_BSUK_Walls_Timber
159 x 1 | 1F | A_BSUK_Walls_Timber
244 x 2 | 1F | A_BSUK_WallInternal_Finishes_Plasterboard
5 x 3 | 1F | A_BSUK_WallsInternal_Block
5 x 4 | 1F | A_BSUK_WallInternal_Finishes_Plaster
5 x 5 | 1F | A_BSUK_Walls_Timber
4 x 5 | 1F | A_BSUK_WallInternal_Finishes_Plaster
38 x 6 | 1F | A_BSUK_Walls_Timber
71 x 3 | 1F | A_BSUK_WallInternal_Finishes_Plasterboard
47 x 4 | 1F | Air Cavity
46 x 5 | 1F | A_BSUK_Insulation
22 x 6 | 1F | Air Cavity
34 x 7 | 1F | A_BSUK_WallInternal_Finishes_Plasterboard
35 x 8 | 1F | A_BSUK_WallInternal_Finishes_Plasterboard
32 x 9 | 1F | A_BSUK_Walls_Timber
110 x 1 | 1F | A_BSUK_Insulation
87 x 3 | 1F | A_BSUK_Walls_Timber
28 x 4 | 1F | A_BSUK_WallInternal_Finishes_Plasterboard
17 x 5 | 1F | A_BSUK_WallInternal_Finishes_Plasterboard
2 x 7 | 1F | A_BSUK_Insulation
5 x 8 | 1F | Air Cavity
9 x 9 | 1F | A_BSUK_WallInternal_Finishes_Plasterboard
7 x 10 | 1F | A_BSUK_WallInternal_Finishes_Plasterboard
8 x 11 | 1F | A_BSUK_WallInternal_Finishes_Plasterboard
8 x 12 | 1F | A_BSUK_WallInternal_Finishes_Plasterboard
5 x 13 | 1F | A_BSUK_Walls_Timber
72 x 3 | 1F | Air Cavity
73 x 4 | 1F | A_BSUK_Insulation
86 x 5 | 1F | Air Cavity
81 x 6 | 1F | A_BSUK_WallInternal_Finishes_Plasterboard
74 x 7 | 1F | A_BSUK_Walls_Timber
25 x 2 | 1F | A_BSUK_Walls_Timber
14 x 6 | 1F | A_BSUK_Insulation
42 x 7 | 1F | Air Cavity
10 x 10 | 1F | A_BSUK_Walls_Timber
6 x 11 | 1F | A_BSUK_Walls_Timber
4 x 8 | 1F | A_BSUK_Insulation
5 x 9 | 1F | Air Cavity
5 x 12 | 1F | A_BSUK_Walls_Timber
5 x 14 | 1F | A_BSUK_Walls_Timber
3 x 9 | 1F | A_BSUK_Insulation
3 x 10 | 1F | Air Cavity
5 x 13 | 1F | A_BSUK_WallInternal_Finishes_Plasterboard
3 x 14 | 1F | A_BSUK_WallInternal_Finishes_Plasterboard
4 x 15 | 1F | A_BSUK_Walls_Timber
4 x 16 | 1F | A_BSUK_Walls_Timber
17 | 1F | A_BSUK_Walls_Timber
18 | 1F | A_BSUK_Walls_Timber
19 | 1F | A_BSUK_Walls_Timber
2 x 10 | 1F | A_BSUK_Insulation
2 x 11 | 1F | Air Cavity
28 x 4 | 1F | A_BSUK_Walls_Timber
2 x 8 | 1F | A_BSUK_WallsInternal_Block
2 x 9 | 1F | A_BSUK_WallInternal_Finishes_Plaster
10 | 1F | A_BSUK_WallInternal_Finishes_Plaster
11 | 1F | A_BSUK_WallInternal_Finishes_Plaster
9 x 8 | 1F | A_BSUK_Walls_Timber
36 x 3 | 1F | A_BSUK_Insulation
80 x 1 | 3F | A_BSUK_Walls_Timber
147 x 2 | 3F | A_BSUK_WallInternal_Finishes_Plasterboard
3 x 3 | 3F | A_BSUK_WallsInternal_Block
3 x 4 | 3F | A_BSUK_WallInternal_Finishes_Plaster
4 x 5 | 3F | A_BSUK_Walls_Timber
5 | 3F | A_BSUK_WallInternal_Finishes_Plaster
6 x 6 | 3F | A_BSUK_Walls_Timber
47 x 3 | 3F | A_BSUK_WallInternal_Finishes_Plasterboard
8 x 4 | 3F | Air Cavity
8 x 5 | 3F | A_BSUK_Insulation
10 x 6 | 3F | Air Cavity
15 x 7 | 3F | A_BSUK_WallInternal_Finishes_Plasterboard
15 x 8 | 3F | A_BSUK_WallInternal_Finishes_Plasterboard
14 x 9 | 3F | A_BSUK_Walls_Timber
82 x 1 | 3F | A_BSUK_Insulation
71 x 3 | 3F | A_BSUK_Walls_Timber
17 x 4 | 3F | A_BSUK_WallInternal_Finishes_Plasterboard
11 x 5 | 3F | A_BSUK_WallInternal_Finishes_Plasterboard
5 x 7 | 3F | A_BSUK_Insulation
3 x 8 | 3F | Air Cavity
5 x 9 | 3F | A_BSUK_WallInternal_Finishes_Plasterboard
3 x 10 | 3F | A_BSUK_WallInternal_Finishes_Plasterboard
4 x 11 | 3F | A_BSUK_WallInternal_Finishes_Plasterboard
4 x 12 | 3F | A_BSUK_WallInternal_Finishes_Plasterboard
3 x 13 | 3F | A_BSUK_Walls_Timber
17 x 4 | 3F | A_BSUK_Walls_Timber
41 x 3 | 3F | Air Cavity
53 x 4 | 3F | A_BSUK_Insulation
47 x 5 | 3F | Air Cavity
47 x 6 | 3F | A_BSUK_WallInternal_Finishes_Plasterboard
41 x 7 | 3F | A_BSUK_Walls_Timber
15 x 2 | 3F | A_BSUK_Walls_Timber
6 x 6 | 3F | A_BSUK_Insulation
7 x 7 | 3F | Air Cavity
7 x 10 | 3F | A_BSUK_Walls_Timber
3 x 11 | 3F | A_BSUK_Walls_Timber
8 | 3F | A_BSUK_Insulation
2 x 9 | 3F | Air Cavity
3 x 12 | 3F | A_BSUK_Walls_Timber
2 x 14 | 3F | A_BSUK_Walls_Timber
9 | 3F | A_BSUK_Insulation
10 | 3F | Air Cavity
2 x 13 | 3F | A_BSUK_WallInternal_Finishes_Plasterboard
14 | 3F | A_BSUK_WallInternal_Finishes_Plasterboard
2 x 15 | 3F | A_BSUK_Walls_Timber
16 | 3F | A_BSUK_Walls_Timber
17 | 3F | A_BSUK_Walls_Timber
18 | 3F | A_BSUK_Walls_Timber
19 | 3F | A_BSUK_Walls_Timber
10 | 3F | A_BSUK_Insulation
11 | 3F | Air Cavity
2 x 8 | 3F | A_BSUK_WallsInternal_Block
2 x 9 | 3F | A_BSUK_WallInternal_Finishes_Plaster
10 | 3F | A_BSUK_WallInternal_Finishes_Plaster
11 | 3F | A_BSUK_WallInternal_Finishes_Plaster
3 x 8 | 3F | A_BSUK_Walls_Timber
25 x 8 | 1F | A_BSUK_WallInternal_Finishes_Metal
1 | 1F | A_BSUK_WallInternal_Finishes_Metal
2 x 2 | 1F | Air Cavity
15 | 1F | A_BSUK_WallInternal_Finishes_Plasterboard
1 | 1F | A_BSUK_WallInternal_Finishes_Plasterboard
4 | 1F | A_BSUK_WallsInternal_Block
11 x 1 | 5F | A_BSUK_Walls_Timber
9 x 2 | 5F | A_BSUK_WallInternal_Finishes_Plasterboard
10 x 3 | 5F | A_BSUK_WallInternal_Finishes_Plasterboard
12 x 4 | 5F | Air Cavity
9 x 5 | 5F | A_BSUK_Insulation
10 x 6 | 5F | Air Cavity
19 x 7 | 5F | A_BSUK_WallInternal_Finishes_Plasterboard
12 x 8 | 5F | A_BSUK_WallInternal_Finishes_Plasterboard
12 x 9 | 5F | A_BSUK_Walls_Timber
6 x 1 | 5F | A_BSUK_WallInternal_Finishes_Metal
9 x 2 | 5F | Air Cavity
7 x 3 | 5F | A_BSUK_Walls_Timber
6 x 4 | 5F | A_BSUK_Insulation
6 x 5 | 5F | Air Cavity
6 x 6 | 5F | A_BSUK_Insulation
7 x 8 | 5F | A_BSUK_Walls_Timber
2 x 10 | 5F | A_BSUK_Walls_Timber
2 x 2 | 5F | A_BSUK_Walls_Timber
2 x 4 | 5F | A_BSUK_WallInternal_Finishes_Plasterboard
5 x 5 | 5F | A_BSUK_WallInternal_Finishes_Plasterboard
4 x 6 | 5F | A_BSUK_WallInternal_Finishes_Plasterboard
2 x 9 | 5F | A_BSUK_WallInternal_Finishes_Plasterboard
10 | 5F | Air Cavity
11 | 5F | A_BSUK_Insulation
12 | 5F | Air Cavity
13 | 5F | A_BSUK_WallInternal_Finishes_Plasterboard
14 | 5F | A_BSUK_WallInternal_Finishes_Plasterboard
15 | 5F | A_BSUK_Walls_Timber
3 x 1 | 5F | A_BSUK_WallInternal_Finishes_Plasterboard
3 x 3 | 5F | A_BSUK_Insulation
7 | 5F | A_BSUK_Insulation
8 | 5F | Air Cavity
84 x 1 | 2F | A_BSUK_Walls_Timber
148 x 2 | 2F | A_BSUK_WallInternal_Finishes_Plasterboard
3 x 3 | 2F | A_BSUK_WallsInternal_Block
3 x 4 | 2F | A_BSUK_WallInternal_Finishes_Plaster
4 x 5 | 2F | A_BSUK_Walls_Timber
5 | 2F | A_BSUK_WallInternal_Finishes_Plaster
7 x 6 | 2F | A_BSUK_Walls_Timber
47 x 3 | 2F | A_BSUK_WallInternal_Finishes_Plasterboard
8 x 4 | 2F | Air Cavity
8 x 5 | 2F | A_BSUK_Insulation
10 x 6 | 2F | Air Cavity
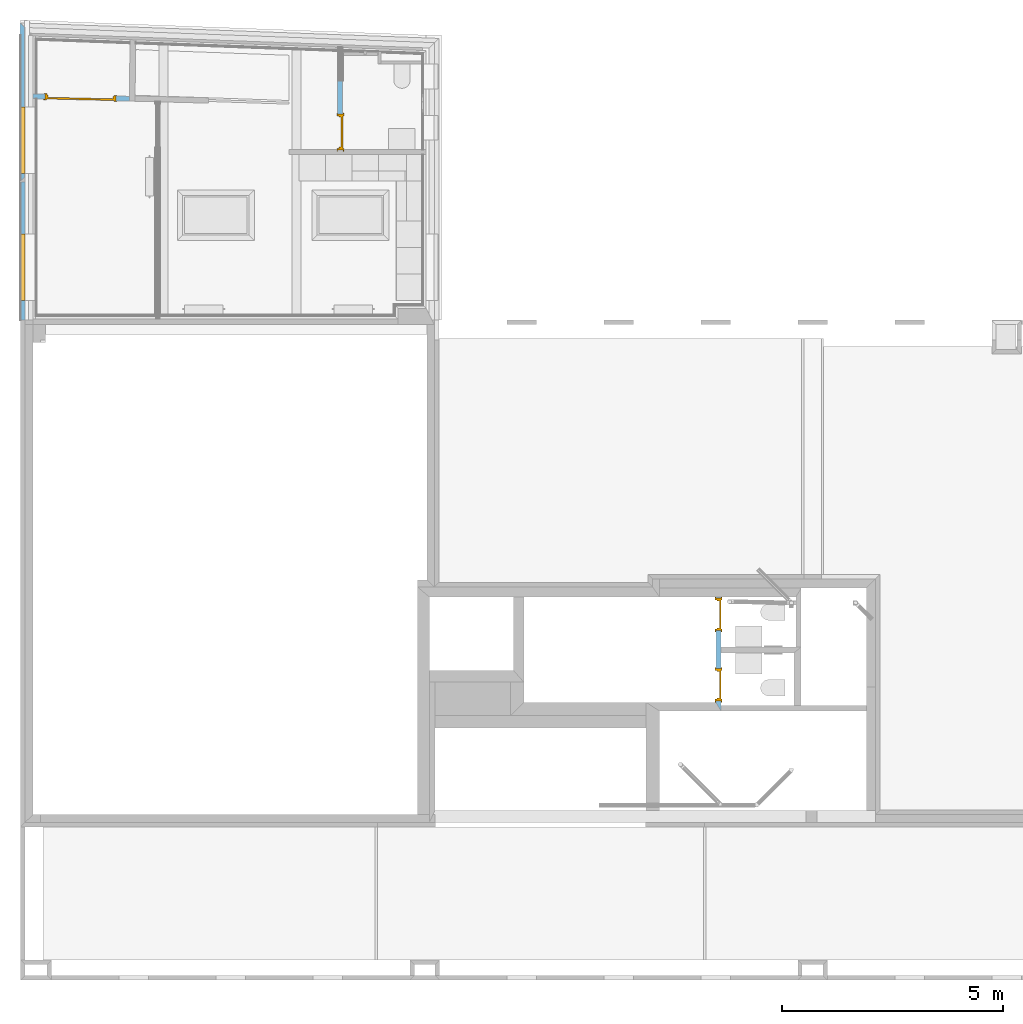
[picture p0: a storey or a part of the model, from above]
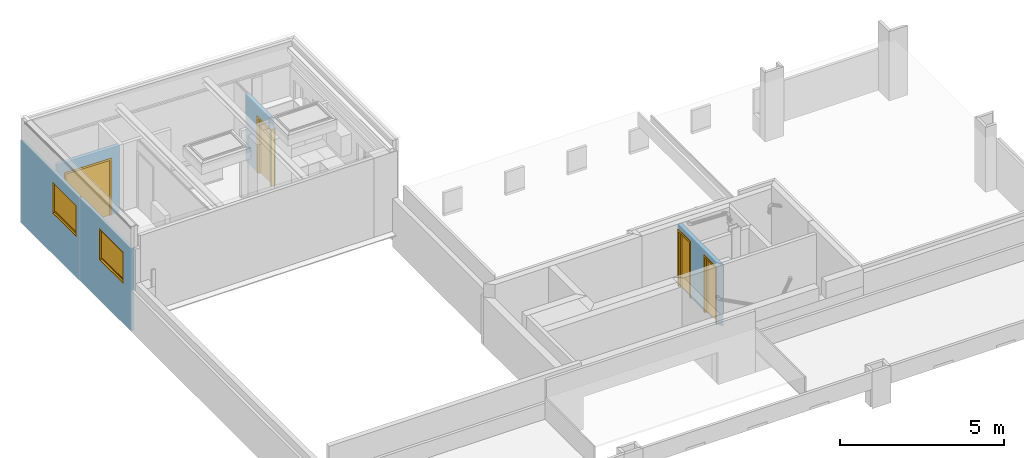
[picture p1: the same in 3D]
Properties of the parts of a building model (IFC2X3), part 5 of 17

# IfcBuildingElementPart (3784)
Name | In | Material
15 x 7 | 2F | A_BSUK_WallInternal_Finishes_Plasterboard
15 x 8 | 2F | A_BSUK_WallInternal_Finishes_Plasterboard
14 x 9 | 2F | A_BSUK_Walls_Timber
78 x 1 | 2F | A_BSUK_Insulation
71 x 3 | 2F | A_BSUK_Walls_Timber
17 x 4 | 2F | A_BSUK_WallInternal_Finishes_Plasterboard
11 x 5 | 2F | A_BSUK_WallInternal_Finishes_Plasterboard
4 x 7 | 2F | A_BSUK_Insulation
3 x 8 | 2F | Air Cavity
5 x 9 | 2F | A_BSUK_WallInternal_Finishes_Plasterboard
3 x 10 | 2F | A_BSUK_WallInternal_Finishes_Plasterboard
4 x 11 | 2F | A_BSUK_WallInternal_Finishes_Plasterboard
4 x 12 | 2F | A_BSUK_WallInternal_Finishes_Plasterboard
3 x 13 | 2F | A_BSUK_Walls_Timber
12 x 4 | 2F | A_BSUK_Walls_Timber
41 x 3 | 2F | Air Cavity
58 x 4 | 2F | A_BSUK_Insulation
47 x 5 | 2F | Air Cavity
46 x 6 | 2F | A_BSUK_WallInternal_Finishes_Plasterboard
42 x 7 | 2F | A_BSUK_Walls_Timber
14 x 2 | 2F | A_BSUK_Walls_Timber
6 x 6 | 2F | A_BSUK_Insulation
7 x 7 | 2F | Air Cavity
7 x 10 | 2F | A_BSUK_Walls_Timber
3 x 11 | 2F | A_BSUK_Walls_Timber
8 | 2F | A_BSUK_Insulation
2 x 9 | 2F | Air Cavity
3 x 12 | 2F | A_BSUK_Walls_Timber
2 x 14 | 2F | A_BSUK_Walls_Timber
10 | 2F | A_BSUK_Insulation
11 | 2F | Air Cavity
2 x 13 | 2F | A_BSUK_WallInternal_Finishes_Plasterboard
2 x 15 | 2F | A_BSUK_Walls_Timber
2 x 8 | 2F | A_BSUK_WallsInternal_Block
2 x 9 | 2F | A_BSUK_WallInternal_Finishes_Plaster
10 | 2F | A_BSUK_WallInternal_Finishes_Plaster
11 | 2F | A_BSUK_WallInternal_Finishes_Plaster
3 x 8 | 2F | A_BSUK_Walls_Timber
9 | 2F | A_BSUK_Insulation
10 | 2F | Air Cavity
14 | 2F | A_BSUK_WallInternal_Finishes_Plasterboard
16 | 2F | A_BSUK_Walls_Timber
17 | 2F | A_BSUK_Walls_Timber
18 | 2F | A_BSUK_Walls_Timber
19 | 2F | A_BSUK_Walls_Timber

# IfcBuildingElementProxy (15)
Name | In | Description
 | 5F | 8 ,SHE-07.FIFTH.dgn,Design Model:213484
 | 5F | 8 ,SHE-07.FIFTH.dgn,Design Model:213545
 | 5F | 8 ,SHE-07.FIFTH.dgn,Design Model:294809
 | 5F | 8 ,SHE-07.FIFTH.dgn,Design Model:294810
 | 5F | 8 ,SHE-07.FIFTH.dgn,Design Model:295030
 | 5F | 8 ,SHE-07.FIFTH.dgn,Design Model:295250
 | GF | 9 ,SHE-10.CONCRETE.dgn,Design Model:207748
 | GF | 9 ,SHE-10.CONCRETE.dgn,Design Model:223616
 | GF | 9 ,SHE-10.CONCRETE.dgn,Design Model:223955
 | GF | 9 ,SHE-10.CONCRETE.dgn,Design Model:224298
 | GF | 9 ,SHE-10.CONCRETE.dgn,Design Model:224637
 | GF | 11 ,SHE-15.MEHP.dgn,Design Model:126959
 | GF | 11 ,SHE-15.MEHP.dgn,Design Model:127989
 | GF | 11 ,SHE-15.MEHP.dgn,Design Model:129019
 | GF | 11 ,SHE-15.MEHP.dgn,Design Model:130435

# IfcBuildingElementProxy: Fireproofing:Cementitious (9)
In: 1F
Material: Cementitious
Name | Description
Fireproofing--Cementitious | 5,SHE-13.STEEL.dgn,Design Model:155774
Fireproofing--Cementitious | 5,SHE-13.STEEL.dgn,Design Model:211927
Fireproofing--Cementitious | 5,SHE-13.STEEL.dgn,Design Model:212046
Fireproofing--Cementitious | 5,SHE-13.STEEL.dgn,Design Model:212699
Fireproofing--Cementitious | 5,SHE-13.STEEL.dgn,Design Model:212732
Fireproofing--Cementitious | 5,SHE-13.STEEL.dgn,Design Model:212765
Fireproofing--Cementitious | 5,SHE-13.STEEL.dgn,Design Model:219674
Fireproofing--Cementitious | 5,SHE-13.STEEL.dgn,Design Model:219691
Fireproofing--Cementitious | 5,SHE-13.STEEL.dgn,Design Model:239527

# IfcColumn: A-Columns-Concrete (27)
In: GF
Type - PredefinedType: COLUMN
Type - Thermal Transmittance - Is External: no; Is Below Grade: no
Type - Structural Usage - Structural | Material: Concrete
Type - Structural Parameters - Section Name: 600x600; Structural Type: Column; Tapered Member: no
Type - Space Bounding - Is Space Bounding: yes
Type - Materials - Part Definition: A-Columns::A_BSUK_Columns_ReinforcedConcrete
Type - Fire Resistance - Fire | IsCombustible: no; Fire | Compartmentation: no
Type - Discipline - Discipline: Architectural
Type - Construction Phase - Phase: New Construction
Type - Classification - Uniclass2015: Pr_20_85_16_15
Material: A_BSUK_Columns_ReinforcedConcrete
Pset_ColumnCommon - IsExternal: no; LoadBearing: no
Structural Location - Column Location: N/A
Quantities | Structural - Volume | Perforation(s): 0 m3; Material Density: 2400.000000
Construction Phase - Phase: Existing to Remain
Name | Description | StructuralFramingCommon, Section Name | Structural Parameters, Section Name | Length (m) | Area | Cross-sectional (m2) = Area | Cross-sectional Modeled (m2) | Area | Side Surfaces Modeled (Gross) (m2) | Area | All Surfaces Modeled (Net) (m2) | Volume (Gross) (m3) = Volume (Gross Modeled) (m3) = Volume (Net) (m3) = Volume (Net Modeled) (m3) | Unit Weight | Length x Unit Weight | Volume (Gross) x Density = Volume (Gross Modeled) x Density = Volume (Net) x Density = Volume (Net Modeled) x Density | Cope Flange Clearance = Cope Web Clearance = Cope Corner Radius = Local Y Offset = Local Z Offset | Cope Corner Treatment
A-Columns-Concrete | 9 ,SHE-10.CONCRETE.dgn,Design Model:128950 | 0.400X0.400 | 6\RECTANGLE\0.400X0.400 | 4.115 | 0.16 | 6.584 | 6.904 | 0.6584 | 1256.000000 | 5168.440000 | 1580.160000 | 0.000 | 0
A-Columns-Concrete | 9 ,SHE-10.CONCRETE.dgn,Design Model:128956 | 0.450X0.280 | 6\RECTANGLE\0.450X0.280 | 9.73 | 0.126 | 14.2058 | 14.4578 | 1.22598 | 989.100000 | 9623.943000 | 2942.352000 | 0.000 | 0
A-Columns-Concrete | 9 ,SHE-10.CONCRETE.dgn,Design Model:129684 | 0.400X0.400 | 6\RECTANGLE\0.400X0.400 | 4.115 | 0.16 | 6.584 | 6.904 | 0.6584 | 1256.000000 | 5168.440000 | 1580.160000 | 0.000 | 0
A-Columns-Concrete | 9 ,SHE-10.CONCRETE.dgn,Design Model:129690 | 0.400X0.400 | 6\RECTANGLE\0.400X0.400 | 4.115 | 0.16 | 6.584 | 6.904 | 0.6584 | 1256.000000 | 5168.440000 | 1580.160000 | 0.000 | 0
A-Columns-Concrete | 9 ,SHE-10.CONCRETE.dgn,Design Model:129692 | 0.400X0.400 | 6\RECTANGLE\0.400X0.400 | 4.115 | 0.16 | 6.584 | 6.904 | 0.6584 | 1256.000000 | 5168.440000 | 1580.160000 | 0.000 | 0
A-Columns-Concrete | 9 ,SHE-10.CONCRETE.dgn,Design Model:129694 | 0.500X0.300 | 6\RECTANGLE\0.500X0.300 | 3.465 | 0.15 | 5.544 | 5.844 | 0.51975 | 1177.500000 | 4080.037500 | 1247.400000 | 0.000 | 0
A-Columns-Concrete | 9 ,SHE-10.CONCRETE.dgn,Design Model:130413 | 0.670X0.280 | 6\RECTANGLE\0.670X0.280 | 9.73 | 0.1876 | 18.487 | 18.8622 | 1.82535 | 1472.660000 | 14328.981800 | 4380.835200 | 0.000 | 0
A-Columns-Concrete | 9 ,SHE-10.CONCRETE.dgn,Design Model:130415 | 0.670X0.280 | 6\RECTANGLE\0.670X0.280 | 9.73 | 0.1876 | 18.487 | 18.8622 | 1.82535 | 1472.660000 | 14328.981800 | 4380.835200 | 0.000 | 0
A-Columns-Concrete | 9 ,SHE-10.CONCRETE.dgn,Design Model:130419 | 0.500X0.300 | 6\RECTANGLE\0.500X0.300 | 3.465 | 0.15 | 5.544 | 5.844 | 0.51975 | 1177.500000 | 4080.037500 | 1247.400000 | 0.000 | 0
A-Columns-Concrete | 9 ,SHE-10.CONCRETE.dgn,Design Model:130423 | 0.500X0.300 | 6\RECTANGLE\0.500X0.300 | 3.465 | 0.15 | 5.544 | 5.844 | 0.51975 | 1177.500000 | 4080.037500 | 1247.400000 | 0.000 | 0
A-Columns-Concrete | 9 ,SHE-10.CONCRETE.dgn,Design Model:132869 | 0.500X0.300 | 6\RECTANGLE\0.500X0.300 | 3.465 | 0.15 | 5.544 | 5.844 | 0.51975 | 1177.500000 | 4080.037500 | 1247.400000 | 0.000 | 0
A-Columns-Concrete | 9 ,SHE-10.CONCRETE.dgn,Design Model:132871 | 0.450X0.280 | 6\RECTANGLE\0.450X0.280 | 9.73 | 0.126 | 14.2058 | 14.4578 | 1.22598 | 989.100000 | 9623.943000 | 2942.352000 | 0.000 | 0
A-Columns-Concrete | 9 ,SHE-10.CONCRETE.dgn,Design Model:141219 | 0.400X0.700 | 6\RECTANGLE\0.400X0.700 | 3.135 | 0.28 | 6.897 | 7.457 | 0.8778 | 2198.000000 | 6890.730000 | 2106.720000 | 0.000 | 0
A-Columns-Concrete | 9 ,SHE-10.CONCRETE.dgn,Design Model:141223 | 0.400X0.500 | 6\RECTANGLE\0.400X0.500 | 3.97 | 0.2 | 7.146 | 7.546 | 0.794 | 1570.000000 | 6232.900000 | 1905.600000 | 0.000 | 0
A-Columns-Concrete | 9 ,SHE-10.CONCRETE.dgn,Design Model:141283 | 0.400X0.500 | 6\RECTANGLE\0.400X0.500 | 3.1 | 0.2 | 5.58 | 5.98 | 0.62 | 1570.000000 | 4867.000000 | 1488.000000 | 0.000 | 0
A-Columns-Concrete | 9 ,SHE-10.CONCRETE.dgn,Design Model:201598 | 0.400X0.400 | 6\RECTANGLE\0.400X0.400 | 3.97 | 0.16 | 6.352 | 6.672 | 0.6352 | 1256.000000 | 4986.320000 | 1524.480000 | 0.000 | 0
A-Columns-Concrete | 9 ,SHE-10.CONCRETE.dgn,Design Model:201644 | 0.330X0.400 | 6\RECTANGLE\0.330X0.400 | 9.73 | 0.132 | 14.2058 | 14.4698 | 1.28436 | 1036.200000 | 10082.226000 | 3082.464000 | 0.000 | 0
A-Columns-Concrete | 9 ,SHE-10.CONCRETE.dgn,Design Model:201646 | 0.330X0.400 | 6\RECTANGLE\0.330X0.400 | 9.73 | 0.132 | 14.2058 | 14.4698 | 1.28436 | 1036.200000 | 10082.226000 | 3082.464000 | 0.000 | 0
A-Columns-Concrete | 9 ,SHE-10.CONCRETE.dgn,Design Model:219914 | 0.250X0.250 | 6\RECTANGLE\0.250X0.250 | 2.535 | 0.0625 | 2.535 | 2.66 | 0.158437 | 490.625000 | 1243.734375 | 380.250000 | 0.000 | 0
A-Columns-Concrete | 9 ,SHE-10.CONCRETE.dgn,Design Model:219933 | 0.250X0.250 | 6\RECTANGLE\0.250X0.250 | 2.535 | 0.0625 | 2.535 | 2.66 | 0.158437 | 490.625000 | 1243.734375 | 380.250000 | 0.000 | 0
A-Columns-Concrete | 9 ,SHE-10.CONCRETE.dgn,Design Model:221932 | 0.300X0.500 | 6\RECTANGLE\0.300X0.500 | 4.795 | 0.15 | 7.672 | 7.972 | 0.71925 | 1177.500000 | 5646.112500 | 1726.200000 | 0.000 | 0
A-Columns-Concrete | 9 ,SHE-10.CONCRETE.dgn,Design Model:314982 | 0.330X0.400 | 6\RECTANGLE\0.330X0.400 | 9.73 | 0.132 | 14.2058 | 14.4698 | 1.28436 | 1036.200000 | 10082.226000 | 3082.464000 | 0.000 | 0
A-Columns-Concrete | 9 ,SHE-10.CONCRETE.dgn,Design Model:314984 | 0.330X0.400 | 6\RECTANGLE\0.330X0.400 | 9.73 | 0.132 | 14.2058 | 14.4698 | 1.28436 | 1036.200000 | 10082.226000 | 3082.464000 | 0.000 | 0
A-Columns-Concrete | 9 ,SHE-10.CONCRETE.dgn,Design Model:315001 | 0.450X0.230 | 6\RECTANGLE\0.450X0.230 | 9.73 | 0.1035 | 13.2328 | 13.4398 | 1.00706 | 812.475000 | 7905.381750 | 2416.932000 | 0.000 | 0
A-Columns-Concrete | 9 ,SHE-10.CONCRETE.dgn,Design Model:315003 | 0.670X0.230 | 6\RECTANGLE\0.670X0.230 | 9.73 | 0.1541 | 17.514 | 17.8222 | 1.49939 | 1209.685000 | 11770.235050 | 3598.543200 | 0.000 | 0
A-Columns-Concrete | 9 ,SHE-10.CONCRETE.dgn,Design Model:315005 |  | 6\RECTANGLE\0.670X0.230 | 9.73 | 0.201 | 18.8762 | 19.2782 | 1.95573 | 1577.850000 | 15352.480500 | 4693.752000
A-Columns-Concrete | 9 ,SHE-10.CONCRETE.dgn,Design Model:315007 | 0.450X0.230 | 6\RECTANGLE\0.450X0.230 | 9.73 | 0.1035 | 13.2328 | 13.4398 | 1.00706 | 812.475000 | 7905.381750 | 2416.932000 | 0.000 | 0

# IfcColumn: A-Columns-Steel (97)
Type - PredefinedType: COLUMN
Type - Thermal Transmittance - Is External: no; Is Below Grade: no
Type - Structural Usage - Structural | Material: Steel
Type - Structural Parameters - Section Name: UC254X254X107; Structural Type: Column; Tapered Member: no
Type - Materials - Part Definition: A-Columns::A_BSUK_Columns_Steel
Type - Fireproofing - Has Fireproofing: no
Type - Fire Resistance - Fire | IsCombustible: no; Fire | Compartmentation: no
Type - Discipline - Discipline: Architectural
Type - Construction Phase - Phase: New Construction
Type - Classification - Uniclass2015: Pr_20_85_16_11
Material: A_BSUK_Columns_Steel
Pset_ColumnCommon - IsExternal: no; LoadBearing: no
Structural Location - Column Location: N/A
Quantities | Structural - Material Density: 600.000000
BuildingDesignerForm - Cope Flange Clearance: 0.000; Cope Web Clearance: 0.000; Cope Corner Treatment: 0; Cope Corner Radius: 0.000; Local Y Offset: 0.000; Local Z Offset: 0.000
Name | In | Description | FireRating = Fire | Rating | StructuralFramingCommon, Section Name | Structural Parameters, Section Name | Length (m) | Area | Cross-sectional (m2) | Area | Cross-sectional Modeled (m2) | Area | Side Surfaces Modeled (Gross) (m2) | Area | All Surfaces Modeled (Net) (m2) | Volume | Perforation(s) (m3) | Volume (Gross) (m3) | Volume (Gross Modeled) (m3) | Volume (Net) (m3) | Volume (Net Modeled) (m3) | Unit Weight | Length x Unit Weight | Volume (Gross) x Density | Volume (Gross Modeled) x Density | Volume (Net) x Density | Volume (Net Modeled) x Density | ID | Name (Alternate) | ID | Description | ID | Keynote | Fireproofing Thickness (m) | ID | Type ID
UC203f | 1F | column - lift shaft :5 ,SHE-13.STEEL.dgn,Design Model:105129 | FD60 | UC203X203X100 | 1\BS_UC\UC203X203X100 | 5.497 | 0.0127 | 0.012596 | 6.97789 | 7.00308 | 0 | 0.069812 | 0.069238 | 0.069812 | 0.069238 | 99.600000 | 547.501200 | 41.887140 | 41.542874 | 41.887140 | 41.542874 | UC203f | column - lift shaft | intumescent paint | 0.02 | Identification - ID | Notes: E7; Fireproofing - Has Fireproofing: yes; Fire Proofing Type: S-Fireproofing-Cementitious; Fireproofing Material: Cementitious; Fireproofing Part Definition: Fireproofing::Cementitious
UC203f | 1F | column - lift shaft and stair wall :5,SHE-13.STEEL.dgn,Design Model:105131 | FD120 | UC203X203X100 | 1\BS_UC\UC203X203X100 | 5.497 | 0.0127 | 0.012596 | 6.97789 | 7.00308 | 0 | 0.069812 | 0.069238 | 0.069812 | 0.069238 | 99.600000 | 547.501200 | 41.887140 | 41.542874 | 41.887140 | 41.542874 | UC203f | column - lift shaft and stair wall | intumescent paint | 0.02 | Identification - ID | Notes: F7; Fireproofing - Has Fireproofing: yes; Fire Proofing Type: S-Fireproofing-Cementitious; Fireproofing Material: Cementitious; Fireproofing Part Definition: Fireproofing::Cementitious
UC203f | 1F | column - party and stair wall (55dB) :5,SHE-13.STEEL.dgn,Design Model:105133 | FD120 | UC203X203X100 | 1\BS_UC\UC203X203X100 | 5.497 | 0.0127 | 0.012596 | 6.97789 | 7.00308 | 0 | 0.069812 | 0.069238 | 0.069812 | 0.069238 | 99.600000 | 547.501200 | 41.887140 | 41.542874 | 41.887140 | 41.542874 | UC203f | column - party and stair wall (55dB) | intumescent paint | 0.02 | Identification - ID | Notes: G7; Fireproofing - Has Fireproofing: yes; Fire Proofing Type: S-Fireproofing-Cementitious; Fireproofing Material: Cementitious; Fireproofing Part Definition: Fireproofing::Cementitious
SHS150a | 1F | column - free standing :5,SHE-13.STEEL.dgn,Design Model:105136 | FD60 | SHS150X150X5 | 1\BS HYBOX SHS\SHS150X150X5 | 5.497 | 0.00284 | 0.0029 | 6.37652 | 6.38232 | 0 | 0.015611 | 0.015941 | 0.015611 | 0.015941 | 22.300000 | 122.583100 | 9.366888 | 9.564780 | 9.366888 | 9.564780 | SHS150a | column - free standing | intumescent paint | 0.02 | Identification - ID | Notes: J7; Fireproofing - Has Fireproofing: yes; Fire Proofing Type: S-Fireproofing-Cementitious; Fireproofing Material: Cementitious; Fireproofing Part Definition: Fireproofing::Cementitious
RHS200h | 1F | column - corridor wall and free standing :5,SHE-13.STEEL.dgn ,Design Model:105139 | FD60 | RHS200X100X10 | 1\BS CELSIUS RHS\RHS200X100X10 | 5.497 | 0.00549 | 0.0056 | 6.15664 | 6.16784 | 0 | 0.030179 | 0.030783 | 0.030179 | 0.030783 | 43.100000 | 236.920700 | 18.107118 | 18.469920 | 18.107118 | 18.469920 | RHS200h | column - corridor wall and free standing | intumescent paint | 0.02 | Identification - ID | Notes: E5; Fireproofing - Has Fireproofing: yes; Fire Proofing Type: S-Fireproofing-Cementitious; Fireproofing Material: Cementitious; Fireproofing Part Definition: Fireproofing::Cementitious
RHS200h | 1F | column - lift shaft and stair wall :5,SHE-13.STEEL.dgn,Design Model:105141 | FD120 | RHS200X100X10 | 1\BS CELSIUS RHS\RHS200X100X10 | 2.547 | 0.00549 | 0.0056 | 2.85264 | 2.86384 | 0 | 0.013983 | 0.014263 | 0.013983 | 0.014263 | 43.100000 | 109.775700 | 8.389818 | 8.557920 | 8.389818 | 8.557920 | RHS200h | column - lift shaft and stair wall | intumescent paint | 0.02 | Identification - ID | Notes: F5/6 - 4F; Fireproofing - Has Fireproofing: yes; Fire Proofing Type: S-Fireproofing-Cementitious; Fireproofing Material: Cementitious; Fireproofing Part Definition: Fireproofing::Cementitious
RHS200h | 1F | column - lift shaft and stair wall :5,SHE-13.STEEL.dgn,Design Model:105143 | FD60 | RHS200X100X10 | 1\BS CELSIUS RHS\RHS200X100X10 | 2.747 | 0.00549 | 0.0056 | 3.07664 | 3.08784 | 0 | 0.015081 | 0.015383 | 0.015081 | 0.015383 | 43.100000 | 118.395700 | 9.048618 | 9.229920 | 9.048618 | 9.229920 | RHS200h | column - lift shaft and stair wall | intumescent paint | 0.02 | Identification - ID | Notes: F5/6 - 5F; Fireproofing - Has Fireproofing: yes; Fire Proofing Type: S-Fireproofing-Cementitious; Fireproofing Material: Cementitious; Fireproofing Part Definition: Fireproofing::Cementitious
RHS200h | 1F | column - free standing and party wall (55dB) :5,SHE-13.STEEL.dgn ,Design Model:105145 | FD120 | RHS200X100X10 | 1\BS CELSIUS RHS\RHS200X100X10 | 5.497 | 0.00549 | 0.0056 | 6.15664 | 6.16784 | 0 | 0.030179 | 0.030783 | 0.030179 | 0.030783 | 43.100000 | 236.920700 | 18.107118 | 18.469920 | 18.107118 | 18.469920 | RHS200h | column - free standing and party wall (55dB) | intumescent paint | 0.02 | Identification - ID | Notes: G5; Fireproofing - Has Fireproofing: yes; Fire Proofing Type: S-Fireproofing-Cementitious; Fireproofing Material: Cementitious; Fireproofing Part Definition: Fireproofing::Cementitious
RHS200h | 1F | column - free standing :5,SHE-13.STEEL.dgn,Design Model:105147 | FD60 | RHS200X100X10 | 1\BS CELSIUS RHS\RHS200X100X10 | 5.497 | 0.00549 | 0.0056 | 6.15664 | 6.16784 | 0 | 0.030179 | 0.030783 | 0.030179 | 0.030783 | 43.100000 | 236.920700 | 18.107118 | 18.469920 | 18.107118 | 18.469920 | RHS200h | column - free standing | intumescent paint | 0.02 | Identification - ID | Notes: J5; Fireproofing - Has Fireproofing: yes; Fire Proofing Type: S-Fireproofing-Cementitious; Fireproofing Material: Cementitious; Fireproofing Part Definition: Fireproofing::Cementitious
UC203f | 1F | A2 - crancked steel - mansard :5,SHE-13.STEEL.dgn,Design Model:105152 | FD60 | UC203X203X100 | 1\BS_UC\UC203X203X100 | 2.96432 | 0.0127 | 0.012596 | 3.76291 | 3.71825 | 0.000443 | 0.037647 | 0.037337 | 0.037204 | 0.036894 | 99.600000 | 295.246595 | 22.588143 | 22.402493 | 22.322233 | 22.136583 | UC203f | crancked steel - mansard | intumescent paint | 0 | A2
UC203f | 1F | A2 - crancked steel - mansard :5,SHE-13.STEEL.dgn,Design Model:105154 | FD60 | UC203X203X100 | 1\BS_UC\UC203X203X100 | 0.914031 | 0.0127 | 0.012596 | 1.16027 | 1.14989 | 0.000228 | 0.011608 | 0.011513 | 0.01138 | 0.011285 | 99.600000 | 91.037445 | 6.964913 | 6.907669 | 6.828099 | 6.770855 | UC203f | crancked steel - mansard | intumescent paint | 0 | A2
UC203f | 1F | A2 - crancked steel - mansard :5,SHE-13.STEEL.dgn,Design Model:105158 | FD60 | UC203X203X100 | 1\BS5950_UC\UC203X203X100 | 1.01893 | 0.0127 | 0.012596 | 1.29343 | 1.28305 | 0.000228 | 0.01294 | 0.012834 | 0.012712 | 0.012606 | 99.600000 | 101.485485 | 7.764251 | 7.700437 | 7.627437 | 7.563624 | UC203f | crancked steel - mansard | intumescent paint | 0 | A2
UC203f | 1F | A2 - crancked steel - mansard :5,SHE-13.STEEL.dgn,Design Model:105160 | FD60 | UC203X203X100 | 1\BS_UC\UC203X203X100 | 1.80699 | 0.0127 | 0.012596 | 2.29379 | 2.2834 | 0.000228 | 0.022949 | 0.02276 | 0.022721 | 0.022532 | 99.600000 | 179.975839 | 13.769236 | 13.656068 | 13.632422 | 13.519254 | UC203f | crancked steel - mansard | intumescent paint | 0 | A2
UC203f | 1F | A2 - crancked steel - mansard :5,SHE-13.STEEL.dgn,Design Model:105162 | FD60 | UC203X203X100 | 1\BS_UC\UC203X203X100 | 0.888631 | 0.0127 | 0.012596 | 1.12803 | 1.11764 | 0.000228 | 0.011286 | 0.011193 | 0.011058 | 0.010965 | 99.600000 | 88.507605 | 6.771365 | 6.715712 | 6.634551 | 6.578898 | UC203f | crancked steel - mansard | intumescent paint | 0 | A2
UC203f | 1F | A2 - crancked steel - mansard :5,SHE-13.STEEL.dgn,Design Model:105164 | FD60 | UC203X203X100 | 1\BS_UC\UC203X203X100 | 2.96432 | 0.0127 | 0.012596 | 3.76291 | 3.71825 | 0.000443 | 0.037647 | 0.037337 | 0.037204 | 0.036894 | 99.600000 | 295.246595 | 22.588143 | 22.402494 | 22.322233 | 22.136583 | UC203f | crancked steel - mansard | intumescent paint | 0 | A2
UC203f | 1F | A2 - crancked steel - mansard :5,SHE-13.STEEL.dgn,Design Model:105170 | FD60 | UC203X203X100 | 1\BS_UC\UC203X203X100 | 1.01893 | 0.0127 | 0.012596 | 1.29343 | 1.28305 | 0.000228 | 0.01294 | 0.012834 | 0.012712 | 0.012606 | 99.600000 | 101.485485 | 7.764251 | 7.700437 | 7.627437 | 7.563624 | UC203f | crancked steel - mansard | intumescent paint | 0 | A2
UC203f | 1F | A2 - crancked steel - mansard :5,SHE-13.STEEL.dgn,Design Model:105172 | FD60 | UC203X203X100 | 1\BS_UC\UC203X203X100 | 1.80699 | 0.0127 | 0.012596 | 2.29379 | 2.2834 | 0.000228 | 0.022949 | 0.02276 | 0.022721 | 0.022532 | 99.600000 | 179.975839 | 13.769236 | 13.656068 | 13.632422 | 13.519254 | UC203f | crancked steel - mansard | intumescent paint | 0 | A2
UC203f | 1F | A2 - crancked steel - mansard :5,SHE-13.STEEL.dgn,Design Model:105174 | FD60 | UC203X203X100 | 1\BS_UC\UC203X203X100 | 0.914031 | 0.0127 | 0.012596 | 1.16027 | 1.14989 | 0.000228 | 0.011608 | 0.011513 | 0.01138 | 0.011285 | 99.600000 | 91.037445 | 6.964913 | 6.907669 | 6.828099 | 6.770855 | UC203f | crancked steel - mansard | intumescent paint | 0 | A2
UC203f | 1F | A2 - crancked steel - mansard :5,SHE-13.STEEL.dgn,Design Model:105176 | FD60 | UC203X203X100 | 1\BS_UC\UC203X203X100 | 2.96432 | 0.0127 | 0.012596 | 3.76291 | 3.71825 | 0.000443 | 0.037647 | 0.037337 | 0.037204 | 0.036894 | 99.600000 | 295.246595 | 22.588143 | 22.402493 | 22.322233 | 22.136583 | UC203f | crancked steel - mansard | intumescent paint | 0 | A2
UC203f | 1F | A2 - crancked steel - mansard :5,SHE-13.STEEL.dgn,Design Model:105216 | FD60 | UC203X203X100 | 1\BS_UC\UC203X203X100 | 2.26506 | 0.0127 | 0.012596 | 2.87527 | 2.77806 | 0.000965 | 0.028766 | 0.02853 | 0.027802 | 0.027565 | 99.600000 | 225.600214 | 17.259775 | 17.117919 | 16.681009 | 16.539152 | UC203f | crancked steel - mansard | intumescent paint | 0 | A2
UC203f | 1F | A2 - crancked steel - mansard :5,SHE-13.STEEL.dgn,Design Model:105218 | FD60 | UC203X203X100 | 1\BS_UC\UC203X203X100 | 2.96432 | 0.0127 | 0.012596 | 3.76291 | 3.71825 | 0.000443 | 0.037647 | 0.037337 | 0.037204 | 0.036894 | 99.600000 | 295.246595 | 22.588143 | 22.402493 | 22.322233 | 22.136583 | UC203f | crancked steel - mansard | intumescent paint | 0 | A2
UC203f | 1F | A2 - crancked steel - mansard :5,SHE-13.STEEL.dgn,Design Model:105220 | FD60 | UC203X203X100 | 1\BS_UC\UC203X203X100 | 1.01893 | 0.0127 | 0.012596 | 1.29343 | 1.28305 | 0.000228 | 0.01294 | 0.012834 | 0.012712 | 0.012606 | 99.600000 | 101.485485 | 7.764251 | 7.700437 | 7.627437 | 7.563624 | UC203f | crancked steel - mansard | intumescent paint | 0 | A2
UC203f | 1F | A2 - crancked steel - mansard :5,SHE-13.STEEL.dgn,Design Model:105222 | FD60 | UC203X203X100 | 1\BS_UC\UC203X203X100 | 1.01893 | 0.0127 | 0.012596 | 1.29343 | 1.28305 | 0.000228 | 0.01294 | 0.012834 | 0.012712 | 0.012606 | 99.600000 | 101.485485 | 7.764251 | 7.700437 | 7.627437 | 7.563624 | UC203f | crancked steel - mansard | intumescent paint | 0 | A2
UC203f | 1F | A2 - crancked steel - mansard :5,SHE-13.STEEL.dgn,Design Model:105224 | FD60 | UC203X203X100 | 1\BS_UC\UC203X203X100 | 2.96432 | 0.0127 | 0.012596 | 3.76291 | 3.71825 | 0.000443 | 0.037647 | 0.037337 | 0.037204 | 0.036894 | 99.600000 | 295.246595 | 22.588143 | 22.402493 | 22.322233 | 22.136583 | UC203f | crancked steel - mansard | intumescent paint | 0 | A2
UC203f | 1F | A2 - crancked steel - mansard :5,SHE-13.STEEL.dgn,Design Model:105226 | FD60 | UC203X203X100 | 1\BS_UC\UC203X203X100 | 2.26506 | 0.0127 | 0.012596 | 2.87527 | 2.77806 | 0.000965 | 0.028766 | 0.02853 | 0.027802 | 0.027565 | 99.600000 | 225.600214 | 17.259775 | 17.117919 | 16.681009 | 16.539152 | UC203f | crancked steel - mansard | intumescent paint | 0 | A2
UC203f | 1F | A2 - crancked steel - mansard :5,SHE-13.STEEL.dgn,Design Model:105230 | FD60 | UC203X203X100 | 1\BS_UC\UC203X203X100 | 1.01893 | 0.0127 | 0.012596 | 1.29343 | 1.28305 | 0.000228 | 0.01294 | 0.012834 | 0.012712 | 0.012606 | 99.600000 | 101.485485 | 7.764251 | 7.700437 | 7.627437 | 7.563624 | UC203f | crancked steel - mansard | intumescent paint | 0 | A2
UC203f | 1F | A2 - crancked steel - mansard :5,SHE-13.STEEL.dgn,Design Model:105232 | FD60 | UC203X203X100 | 1\BS_UC\UC203X203X100 | 2.96432 | 0.0127 | 0.012596 | 3.76291 | 3.71825 | 0.000443 | 0.037647 | 0.037337 | 0.037204 | 0.036894 | 99.600000 | 295.246595 | 22.588143 | 22.402493 | 22.322233 | 22.136583 | UC203f | crancked steel - mansard | intumescent paint | 0 | A2
UC203f | 1F | A2 - crancked steel - mansard :5,SHE-13.STEEL.dgn,Design Model:105234 | FD60 | UC203X203X100 | 1\BS_UC\UC203X203X100 | 2.26506 | 0.0127 | 0.012596 | 2.87527 | 2.77806 | 0.000965 | 0.028766 | 0.02853 | 0.027802 | 0.027565 | 99.600000 | 225.600214 | 17.259775 | 17.117919 | 16.681009 | 16.539152 | UC203f | crancked steel - mansard | intumescent paint | 0 | A2
UC203f | 1F | A2 - crancked steel - mansard :5,SHE-13.STEEL.dgn,Design Model:105240 | FD60 | UC203X203X100 | 1\BS_UC\UC203X203X100 | 2.26506 | 0.0127 | 0.012596 | 2.87527 | 2.77806 | 0.000965 | 0.028766 | 0.02853 | 0.027802 | 0.027565 | 99.600000 | 225.600214 | 17.259775 | 17.117919 | 16.681009 | 16.539152 | UC203f | crancked steel - mansard | intumescent paint | 0 | A2
UC203f | 1F | A2 - crancked steel - mansard :5,SHE-13.STEEL.dgn,Design Model:105242 | FD60 | UC203X203X100 | 1\BS_UC\UC203X203X100 | 2.96432 | 0.0127 | 0.012596 | 3.76291 | 3.71825 | 0.000443 | 0.037647 | 0.037337 | 0.037204 | 0.036894 | 99.600000 | 295.246595 | 22.588143 | 22.402493 | 22.322233 | 22.136583 | UC203f | crancked steel - mansard | intumescent paint | 0 | A2
UC203f | 1F | A2 - crancked steel - mansard :5,SHE-13.STEEL.dgn,Design Model:105244 | FD60 | UC203X203X100 | 1\BS_UC\UC203X203X100 | 1.01893 | 0.0127 | 0.012596 | 1.29343 | 1.28305 | 0.000228 | 0.01294 | 0.012834 | 0.012712 | 0.012606 | 99.600000 | 101.485485 | 7.764251 | 7.700437 | 7.627437 | 7.563624 | UC203f | crancked steel - mansard | intumescent paint | 0 | A2
UC203f | 1F | A2 - crancked steel - mansard :5,SHE-13.STEEL.dgn,Design Model:105246 | FD60 | UC203X203X100 | 1\BS_UC\UC203X203X100 | 2.93613 | 0.0127 | 0.012596 | 3.72713 | 3.6697 | 0.00057 | 0.037289 | 0.036982 | 0.036719 | 0.036413 | 99.600000 | 292.438872 | 22.373335 | 22.189451 | 22.031414 | 21.847530 | UC203f | crancked steel - mansard | intumescent paint | 0 | A2
UC203f | 1F | A2 - crancked steel - mansard :5,SHE-13.STEEL.dgn,Design Model:105248 | FD60 | UC203X203X100 | 1\BS_UC\UC203X203X100 | 1.21575 | 0.0127 | 0.012596 | 1.54328 | 1.52199 | 0.000336 | 0.01544 | 0.015313 | 0.015104 | 0.014977 | 99.600000 | 121.089197 | 9.264053 | 9.187913 | 9.062344 | 8.986203 | UC203f | crancked steel - mansard | intumescent paint | 0 | A2
UC203f | 1F | A2 - crancked steel - mansard :5,SHE-13.STEEL.dgn,Design Model:105266 | FD60 | UC203X203X100 | 1\BS_UC\UC203X203X100 | 2.59738 | 0.0127 | 0.012596 | 3.29711 | 3.21306 | 0.000834 | 0.032987 | 0.032716 | 0.032153 | 0.031882 | 99.600000 | 258.698817 | 19.792018 | 19.629349 | 19.291591 | 19.128923 | UC203f | crancked steel - mansard | intumescent paint | 0 | A2
UC203f | 1F | A2 - crancked steel - mansard :5,SHE-13.STEEL.dgn,Design Model:105286 | FD60 | UC203X203X100 | 1\BS_UC\UC203X203X100 | 2.59738 | 0.0127 | 0.012596 | 3.29711 | 3.21306 | 0.000834 | 0.032987 | 0.032716 | 0.032153 | 0.031882 | 99.600000 | 258.698817 | 19.792018 | 19.629349 | 19.291591 | 19.128923 | UC203f | crancked steel - mansard | intumescent paint | 0 | A2
UC203f | 1F | A2 - crancked steel - mansard :5,SHE-13.STEEL.dgn,Design Model:105288 | FD60 | UC203X203X100 | 1\BS_UC\UC203X203X100 | 2.93613 | 0.0127 | 0.012596 | 3.72713 | 3.70584 | 0.000336 | 0.037289 | 0.036982 | 0.036953 | 0.036646 | 99.600000 | 292.438872 | 22.373335 | 22.189451 | 22.171626 | 21.987742 | UC203f | crancked steel - mansard | intumescent paint | 0 | A2
UC203f | 1F | A2 - crancked steel - mansard :5,SHE-13.STEEL.dgn,Design Model:105290 | FD60 | UC203X203X100 | 1\BS_UC\UC203X203X100 | 1.21575 | 0.0127 | 0.012596 | 1.54328 | 1.52199 | 0.000336 | 0.01544 | 0.015313 | 0.015104 | 0.014977 | 99.600000 | 121.089197 | 9.264053 | 9.187913 | 9.062344 | 8.986203 | UC203f | crancked steel - mansard | intumescent paint | 0 | A2
UC203f | 1F | A2 - crancked steel - mansard :5,SHE-13.STEEL.dgn,Design Model:125200 | FD60 | UC203X203X100 | 1\BS_UC\UC203X203X100 | 0.669587 | 0.0127 | 0.012596 | 0.849974 | 0.787039 | 0.000749 | 0.008504 | 0.008434 | 0.007754 | 0.007684 | 99.600000 | 66.690898 | 5.102255 | 5.060321 | 4.652586 | 4.610651 | UC203f | crancked steel - mansard | intumescent paint | 0 | A2
UC203f | 1F | A2 - crancked steel - mansard :5,SHE-13.STEEL.dgn,Design Model:125202 | FD60 | UC203X203X100 | 1\BS_UC\UC203X203X100 | 0.669668 | 0.0127 | 0.012596 | 0.850077 | 0.787142 | 0.000749 | 0.008505 | 0.008435 | 0.007755 | 0.007685 | 99.600000 | 66.698970 | 5.102873 | 5.060933 | 4.653203 | 4.611263 | UC203f | crancked steel - mansard | intumescent paint | 0 | A2
UC203f | 1F | A2 - crancked steel - mansard :5,SHE-13.STEEL.dgn,Design Model:125204 | FD60 | UC203X203X100 | 1\BS_UC\UC203X203X100 | 0.669668 | 0.0127 | 0.012596 | 0.850077 | 0.787142 | 0.000749 | 0.008505 | 0.008435 | 0.007755 | 0.007685 | 99.600000 | 66.698970 | 5.102873 | 5.060933 | 4.653203 | 4.611263 | UC203f | crancked steel - mansard | intumescent paint | 0 | A2
UC203f | 1F | A2 - crancked steel - mansard :5,SHE-13.STEEL.dgn,Design Model:125206 | FD60 | UC203X203X100 | 1\BS_UC\UC203X203X100 | 1.06233 | 0.0127 | 0.012596 | 1.34852 | 1.30061 | 0.0006 | 0.013492 | 0.013381 | 0.012891 | 0.01278 | 99.600000 | 105.808182 | 8.094963 | 8.028432 | 7.734748 | 7.668217 | UC203f | crancked steel - mansard | intumescent paint | 0 | A2
UC203f | 1F | A2 - crancked steel - mansard :5,SHE-13.STEEL.dgn,Design Model:125212 | FD60 | UC203X203X100 | 1\BS_UC\UC203X203X100 | 1.06321 | 0.0127 | 0.012596 | 1.34964 | 1.30173 | 0.0006 | 0.013503 | 0.013392 | 0.012902 | 0.012791 | 99.600000 | 105.895691 | 8.101658 | 8.035072 | 7.741443 | 7.674857 | UC203f | crancked steel - mansard | intumescent paint | 0 | A2
UC203f | 1F | A2 - crancked steel - mansard :5,SHE-13.STEEL.dgn,Design Model:140408 | FD60 | UC203X203X100 | 1\BS5950_UC\UC203X203X100 | 2.26485 | 0.0127 | 0.012596 | 2.87501 | 2.77592 | 0.000983 | 0.028764 | 0.028527 | 0.02778 | 0.027544 | 99.600000 | 225.579525 | 17.258193 | 17.116349 | 16.668268 | 16.526425 | UC203f | crancked steel - mansard | intumescent paint | 0 | A2
UC203f | 1F | A2 - crancked steel - mansard :5,SHE-13.STEEL.dgn,Design Model:140410 | FD60 | UC203X203X100 | 1\BS_UC\UC203X203X100 | 0.674505 | 0.0127 | 0.012596 | 0.856217 | 0.793275 | 0.00075 | 0.008566 | 0.008496 | 0.007817 | 0.007746 | 99.600000 | 67.180702 | 5.139728 | 5.097485 | 4.690015 | 4.647773 | UC203f | crancked steel - mansard | intumescent paint | 0 | A2
UC203f | 1F | A2 - crancked steel - mansard :5,SHE-13.STEEL.dgn,Design Model:140415 | FD60 | UC203X203X100 | 1\BS_UC\UC203X203X100 | 2.26485 | 0.0127 | 0.012596 | 2.87501 | 2.77592 | 0.000983 | 0.028764 | 0.028527 | 0.02778 | 0.027544 | 99.600000 | 225.579525 | 17.258193 | 17.116349 | 16.668268 | 16.526425 | UC203f | crancked steel - mansard | intumescent paint | 0 | A2
UC203f | 1F | A2 - crancked steel - mansard :5,SHE-13.STEEL.dgn,Design Model:140417 | FD60 | UC203X203X100 | 1\BS_UC\UC203X203X100 | 0.724505 | 0.0127 | 0.012596 | 0.919687 | 0.856745 | 0.00075 | 0.009201 | 0.009126 | 0.008452 | 0.008376 | 99.600000 | 72.160702 | 5.520728 | 5.475354 | 5.071015 | 5.025641 | UC203f | crancked steel - mansard | intumescent paint | 0 | A2
UC203f | 1F | A2 - crancked steel - mansard :5,SHE-13.STEEL.dgn,Design Model:140429 | FD60 | UC203X203X100 | 1\BS_UC\UC203X203X100 | 2.26485 | 0.0127 | 0.012596 | 2.87501 | 2.77592 | 0.000983 | 0.028764 | 0.028527 | 0.02778 | 0.027544 | 99.600000 | 225.579525 | 17.258193 | 17.116349 | 16.668268 | 16.526425 | UC203f | crancked steel - mansard | intumescent paint | 0 | A2
UC203f | 1F | A2 - crancked steel - mansard :5,SHE-13.STEEL.dgn,Design Model:140431 | FD60 | UC203X203X100 | 1\BS_UC\UC203X203X100 | 0.674505 | 0.0127 | 0.012596 | 0.856217 | 0.793275 | 0.00075 | 0.008566 | 0.008496 | 0.007817 | 0.007746 | 99.600000 | 67.180702 | 5.139728 | 5.097485 | 4.690015 | 4.647773 | UC203f | crancked steel - mansard | intumescent paint | 0 | A2
UC203f | 1F | A2 - crancked steel - mansard :5,SHE-13.STEEL.dgn,Design Model:143627 | FD60 | UC203X203X100 | 1\BS_UC\UC203X203X100 | 0.669587 | 0.0127 | 0.012596 | 0.849974 | 0.787039 | 0.000749 | 0.008504 | 0.008434 | 0.007754 | 0.007684 | 99.600000 | 66.690898 | 5.102255 | 5.060321 | 4.652586 | 4.610651 | UC203f | crancked steel - mansard | intumescent paint | 0 | A2
A2 | 1F | A2 - mansard roof profile :5,SHE-13.STEEL.dgn,Design Model:105186 | FD60 | UC203X203X100 | 1\BS_UC\UC203X203X100 | 2.96432 | 0.0127 | 0.012596 | 3.76291 | 3.71825 | 0.000443 | 0.037647 | 0.037337 | 0.037204 | 0.036894 | 99.600000 | 295.246595 | 22.588143 | 22.402493 | 22.322233 | 22.136583 |  | mansard roof profile |  | 0 | A2 | Identification - ID | Notes: intumescent paint
A2 | 1F | A2 - mansard roof profile :5,SHE-13.STEEL.dgn,Design Model:105188 | FD60 | UC203X203X100 | 1\BS_UC\UC203X203X100 | 0.914031 | 0.0127 | 0.012596 | 1.16027 | 1.14989 | 0.000228 | 0.011608 | 0.011513 | 0.01138 | 0.011285 | 99.600000 | 91.037445 | 6.964913 | 6.907669 | 6.828099 | 6.770855 |  | mansard roof profile |  | 0 | A2 | Identification - ID | Notes: intumescent paint
A2 | 1F | A2 - mansard roof profile :5,SHE-13.STEEL.dgn,Design Model:105190 | FD60 | UC203X203X100 | 1\BS_UC\UC203X203X100 | 1.80655 | 0.0127 | 0.012596 | 2.29324 | 2.28285 | 0.000228 | 0.022943 | 0.022755 | 0.022715 | 0.022527 | 99.600000 | 179.932382 | 13.765911 | 13.652771 | 13.629097 | 13.515957 |  | mansard roof profile |  | 0 | A2 | Identification - ID | Notes: intumescent paint
A2 | 1F | A2 - mansard roof profile :5,SHE-13.STEEL.dgn,Design Model:105192 | FD60 | UC203X203X100 | 1\BS_UC\UC203X203X100 | 1.01893 | 0.0127 | 0.012596 | 1.29343 | 1.28305 | 0.000228 | 0.01294 | 0.012834 | 0.012712 | 0.012606 | 99.600000 | 101.485485 | 7.764251 | 7.700437 | 7.627437 | 7.563624 |  | mansard roof profile |  | 0 | A2 | Identification - ID | Notes: intumescent paint
A2 | 1F | A2 - mansard roof profile :5,SHE-13.STEEL.dgn,Design Model:105194 | FD60 | UC203X203X100 | 1\BS_UC\UC203X203X100 | 0.888631 | 0.0127 | 0.012596 | 1.12803 | 1.11764 | 0.000228 | 0.011286 | 0.011193 | 0.011058 | 0.010965 | 99.600000 | 88.507605 | 6.771365 | 6.715712 | 6.634551 | 6.578898 |  | mansard roof profile |  | 0 | A2 | Identification - ID | Notes: intumescent paint
A2 | 1F | A2 - mansard roof profile :5,SHE-13.STEEL.dgn,Design Model:105196 | FD60 | UC203X203X100 | 1\BS_UC\UC203X203X100 | 2.96432 | 0.0127 | 0.012596 | 3.76291 | 3.71825 | 0.000443 | 0.037647 | 0.037337 | 0.037204 | 0.036894 | 99.600000 | 295.246595 | 22.588143 | 22.402493 | 22.322233 | 22.136583 |  | mansard roof profile |  | 0 | A2 | Identification - ID | Notes: intumescent paint
A2 | 1F | A2 - mansard roof profile :5,SHE-13.STEEL.dgn,Design Model:105202 | FD60 | UC203X203X100 | 1\BS_UC\UC203X203X100 | 1.01893 | 0.0127 | 0.012596 | 1.29343 | 1.28305 | 0.000228 | 0.01294 | 0.012834 | 0.012712 | 0.012606 | 99.600000 | 101.485485 | 7.764251 | 7.700437 | 7.627437 | 7.563624 |  | mansard roof profile |  | 0 | A2 | Identification - ID | Notes: intumescent paint
A2 | 1F | A2 - mansard roof profile :5,SHE-13.STEEL.dgn,Design Model:105204 | FD60 | UC203X203X100 | 1\BS_UC\UC203X203X100 | 1.80655 | 0.0127 | 0.012596 | 2.29324 | 2.28285 | 0.000228 | 0.022943 | 0.022755 | 0.022715 | 0.022527 | 99.600000 | 179.932382 | 13.765911 | 13.652771 | 13.629097 | 13.515957 |  | mansard roof profile |  | 0 | A2 | Identification - ID | Notes: intumescent paint
A2 | 1F | A2 - mansard roof profile :5,SHE-13.STEEL.dgn,Design Model:105206 | FD60 | UC203X203X100 | 1\BS_UC\UC203X203X100 | 0.914031 | 0.0127 | 0.012596 | 1.16027 | 1.14989 | 0.000228 | 0.011608 | 0.011513 | 0.01138 | 0.011285 | 99.600000 | 91.037445 | 6.964913 | 6.907669 | 6.828099 | 6.770855 |  | mansard roof profile |  | 0 | A2 | Identification - ID | Notes: intumescent paint
A2 | 1F | A2 - mansard roof profile :5,SHE-13.STEEL.dgn,Design Model:105208 | FD60 | UC203X203X100 | 1\BS_UC\UC203X203X100 | 2.96432 | 0.0127 | 0.012596 | 3.76291 | 3.71825 | 0.000443 | 0.037647 | 0.037337 | 0.037204 | 0.036894 | 99.600000 | 295.246595 | 22.588143 | 22.402493 | 22.322233 | 22.136583 |  | mansard roof profile |  | 0 | A2 | Identification - ID | Notes: intumescent paint
A2 | 1F | A2 - mansard roof profile :5,SHE-13.STEEL.dgn,Design Model:105268 | FD60 | UC203X203X100 | 1\BS_UC\UC203X203X100 | 1.21575 | 0.0127 | 0.012596 | 1.54328 | 1.52199 | 0.000336 | 0.01544 | 0.015313 | 0.015104 | 0.014977 | 99.600000 | 121.089197 | 9.264053 | 9.187913 | 9.062344 | 8.986203 |  | mansard roof profile |  | 0 | A2 | Identification - ID | Notes: intumescent paint
A2 | 1F | A2 - mansard roof profile :5,SHE-13.STEEL.dgn,Design Model:105270 | FD60 | UC203X203X100 | 1\BS_UC\UC203X203X100 | 2.93613 | 0.0127 | 0.012596 | 3.72713 | 3.6697 | 0.00057 | 0.037289 | 0.036982 | 0.036719 | 0.036413 | 99.600000 | 292.438872 | 22.373335 | 22.189451 | 22.031414 | 21.847530 |  | mansard roof profile |  | 0 | A2 | Identification - ID | Notes: intumescent paint
A2 | 1F | A2 - mansard roof profile :5,SHE-13.STEEL.dgn,Design Model:105272 | FD60 | UC203X203X100 | 1\BS_UC\UC203X203X100 | 2.59738 | 0.0127 | 0.012596 | 3.29711 | 3.21306 | 0.000834 | 0.032987 | 0.032716 | 0.032153 | 0.031882 | 99.600000 | 258.698817 | 19.792018 | 19.629349 | 19.291591 | 19.128923 |  | mansard roof profile |  | 0 | A2 | Identification - ID | Notes: intumescent paint
A2 | 1F | A2 - mansard roof profile :5,SHE-13.STEEL.dgn,Design Model:105276 | FD60 | UC203X203X100 | 1\BS_UC\UC203X203X100 | 1.21575 | 0.0127 | 0.012596 | 1.54328 | 1.52199 | 0.000336 | 0.01544 | 0.015313 | 0.015104 | 0.014977 | 99.600000 | 121.089197 | 9.264053 | 9.187913 | 9.062344 | 8.986203 |  | mansard roof profile |  | 0 | A2 | Identification - ID | Notes: intumescent paint
A2 | 1F | A2 - mansard roof profile :5,SHE-13.STEEL.dgn,Design Model:105278 | FD60 | UC203X203X100 | 1\BS_UC\UC203X203X100 | 2.93613 | 0.0127 | 0.012596 | 3.72713 | 3.6697 | 0.00057 | 0.037289 | 0.036982 | 0.036719 | 0.036413 | 99.600000 | 292.438872 | 22.373335 | 22.189451 | 22.031414 | 21.847530 |  | mansard roof profile |  | 0 | A2 | Identification - ID | Notes: intumescent paint
A2 | 1F | A2 - mansard roof profile :5,SHE-13.STEEL.dgn,Design Model:105280 | FD60 | UC203X203X100 | 1\BS_UC\UC203X203X100 | 2.59738 | 0.0127 | 0.012596 | 3.29711 | 3.28616 | 0.000234 | 0.032987 | 0.032716 | 0.032753 | 0.032482 | 99.600000 | 258.698817 | 19.792018 | 19.629349 | 19.651806 | 19.489138 |  | mansard roof profile |  | 0 | A2 | Identification - ID | Notes: intumescent paint
A2 | 1F | A2 - mansard roof profile :5,SHE-13.STEEL.dgn,Design Model:125208 | FD60 | UC203X203X100 | 1\BS_UC\UC203X203X100 | 1.06268 | 0.0127 | 0.012596 | 1.34896 | 1.30106 | 0.0006 | 0.013496 | 0.013385 | 0.012896 | 0.012785 | 99.600000 | 105.842879 | 8.097618 | 8.031064 | 7.737403 | 7.670849 |  | mansard roof profile |  | 0 | A2 | Identification - ID | Notes: intumescent paint
A2 | 1F | A2 - mansard roof profile :5,SHE-13.STEEL.dgn,Design Model:125210 | FD60 | UC203X203X100 | 1\BS_UC\UC203X203X100 | 1.06333 | 0.0127 | 0.012596 | 1.34979 | 1.30188 | 0.0006 | 0.013504 | 0.013393 | 0.012904 | 0.012793 | 99.600000 | 105.907782 | 8.102583 | 8.035989 | 7.742368 | 7.675774 |  | mansard roof profile |  | 0 | A2 | Identification - ID | Notes: intumescent paint
A2 | 1F | A2 - mansard roof profile :5,SHE-13.STEEL.dgn,Design Model:140441 | FD60 | UC203X203X100 | 1\BS_UC\UC203X203X100 | 6.26485 | 0.0127 | 0.012596 | 7.95261 | 2.77592 | 0.051366 | 0.079564 | 0.07891 | 0.028198 | 0.027544 | 99.600000 | 623.979525 | 47.738193 | 47.345837 | 16.918780 | 16.526425 |  | mansard roof profile |  | 0 | A2 | Identification - ID | Notes: intumescent paint
A2 | 1F | A2 - mansard roof profile :5,SHE-13.STEEL.dgn,Design Model:140443 | FD60 | UC203X203X100 | 1\BS_UC\UC203X203X100 | 0.724505 | 0.0127 | 0.012596 | 0.919687 | 0.856745 | 0.00075 | 0.009201 | 0.009126 | 0.008452 | 0.008376 | 99.600000 | 72.160702 | 5.520728 | 5.475354 | 5.071015 | 5.025641 |  | mansard roof profile |  | 0 | A2 | Identification - ID | Notes: intumescent paint
A2 | 1F | A2 - mansard roof profile :5,SHE-13.STEEL.dgn,Design Model:140452 | FD60 | UC203X203X100 | 1\BS_UC\UC203X203X100 | 6.26485 | 0.0127 | 0.012596 | 7.95261 | 2.77592 | 0.051366 | 0.079564 | 0.07891 | 0.028198 | 0.027544 | 99.600000 | 623.979525 | 47.738193 | 47.345837 | 16.918780 | 16.526425 |  | mansard roof profile |  | 0 | A2 | Identification - ID | Notes: intumescent paint
A2 | 1F | A2 - mansard roof profile :5,SHE-13.STEEL.dgn,Design Model:140454 | FD60 | UC203X203X100 | 1\BS_UC\UC203X203X100 | 0.674505 | 0.0127 | 0.012596 | 0.856217 | 0.793275 | 0.00075 | 0.008566 | 0.008496 | 0.007817 | 0.007746 | 99.600000 | 67.180702 | 5.139728 | 5.097485 | 4.690015 | 4.647773 |  | mansard roof profile |  | 0 | A2 | Identification - ID | Notes: intumescent paint
A2 | 1F | A2 - mansard roof profile :5,SHE-13.STEEL.dgn,Design Model:140456 | FD60 | UC203X203X100 | 1\BS_UC\UC203X203X100 | 6.26485 | 0.0127 | 0.012596 | 7.95261 | 2.77592 | 0.051366 | 0.079564 | 0.07891 | 0.028198 | 0.027544 | 99.600000 | 623.979525 | 47.738193 | 47.345837 | 16.918780 | 16.526425 |  | mansard roof profile |  | 0 | A2 | Identification - ID | Notes: intumescent paint
A2 | 1F | A2 - mansard roof profile :5,SHE-13.STEEL.dgn,Design Model:140458 | FD60 | UC203X203X100 | 1\BS_UC\UC203X203X100 | 0.674505 | 0.0127 | 0.012596 | 0.856217 | 0.793275 | 0.00075 | 0.008566 | 0.008496 | 0.007817 | 0.007746 | 99.600000 | 67.180702 | 5.139728 | 5.097485 | 4.690015 | 4.647773 |  | mansard roof profile |  | 0 | A2 | Identification - ID | Notes: intumescent paint
column | GF | external column - existing :15,SHE-14.BALCONY.dgn,Design Model:168506 |  | UC152X152X51 | 1\BS5950_UC\UC152X152X51 | 4.894 | 0.0065 | 0.006469 | 4.63951 | 4.65245 | 0 | 0.031811 | 0.03166 | 0.031811 | 0.03166 | 51.200000 | 250.572800 | 19.086600 | 18.996041 | 19.086600 | 18.996041 | column | external column - existing | galvanized | 0 | Construction Phase - Phase: Temporary Construction
column | GF | external column - existing :15,SHE-14.BALCONY.dgn,Design Model:168508 |  | UC152X152X51 | 1\BS5950_UC\UC152X152X51 | 4.894 | 0.0065 | 0.006469 | 4.63951 | 4.65245 | 0 | 0.031811 | 0.03166 | 0.031811 | 0.03166 | 51.200000 | 250.572800 | 19.086600 | 18.996041 | 19.086600 | 18.996041 | column | external column - existing | galvanized | 0 | Construction Phase - Phase: Temporary Construction
column | GF | external column - existing :15,SHE-14.BALCONY.dgn,Design Model:168510 |  | UC152X152X51 | 1\BS5950_UC\UC152X152X51 | 4.894 | 0.0065 | 0.006469 | 4.63951 | 4.65245 | 0 | 0.031811 | 0.03166 | 0.031811 | 0.03166 | 51.200000 | 250.572800 | 19.086600 | 18.996041 | 19.086600 | 18.996041 | column | external column - existing | galvanized | 0 | Construction Phase - Phase: Temporary Construction
column | GF | external column - existing :15,SHE-14.BALCONY.dgn,Design Model:168512 |  | UC152X152X51 | 1\BS5950_UC\UC152X152X51 | 4.894 | 0.0065 | 0.006469 | 4.63951 | 4.65245 | 0 | 0.031811 | 0.03166 | 0.031811 | 0.03166 | 51.200000 | 250.572800 | 19.086600 | 18.996041 | 19.086600 | 18.996041 | column | external column - existing | galvanized | 0 | Construction Phase - Phase: Temporary Construction
column | GF | external column - existing :15,SHE-14.BALCONY.dgn,Design Model:168514 |  | UC152X152X51 | 1\BS5950_UC\UC152X152X51 | 4.894 | 0.0065 | 0.006469 | 4.63951 | 4.65245 | 0 | 0.031811 | 0.03166 | 0.031811 | 0.03166 | 51.200000 | 250.572800 | 19.086600 | 18.996041 | 19.086600 | 18.996041 | column | external column - existing | galvanized | 0 | Construction Phase - Phase: Temporary Construction
column | GF | external column - existing :15,SHE-14.BALCONY.dgn,Design Model:168516 |  | UC152X152X51 | 1\BS5950_UC\UC152X152X51 | 4.894 | 0.0065 | 0.006469 | 4.63951 | 4.65245 | 0 | 0.031811 | 0.03166 | 0.031811 | 0.03166 | 51.200000 | 250.572800 | 19.086600 | 18.996041 | 19.086600 | 18.996041 | column | external column - existing | galvanized | 0 | Construction Phase - Phase: Temporary Construction
column | GF | external column - existing :15,SHE-14.BALCONY.dgn,Design Model:168518 |  | UC152X152X51 | 1\BS5950_UC\UC152X152X51 | 4.894 | 0.0065 | 0.006469 | 4.63951 | 4.65245 | 0 | 0.031811 | 0.03166 | 0.031811 | 0.03166 | 51.200000 | 250.572800 | 19.086600 | 18.996041 | 19.086600 | 18.996041 | column | external column - existing | galvanized | 0 | Construction Phase - Phase: Temporary Construction
column | GF | external column - existing :15,SHE-14.BALCONY.dgn,Design Model:168520 |  | UC152X152X51 | 1\BS5950_UC\UC152X152X51 | 4.894 | 0.0065 | 0.006469 | 4.63951 | 4.65245 | 0 | 0.031811 | 0.03166 | 0.031811 | 0.03166 | 51.200000 | 250.572800 | 19.086600 | 18.996041 | 19.086600 | 18.996041 | column | external column - existing | galvanized | 0 | Construction Phase - Phase: Temporary Construction
column | GF | external column - existing :15,SHE-14.BALCONY.dgn,Design Model:179408 |  | UC152X152X51 | 1\BS5950_UC\UC152X152X51 | 3.353 | 0.0065 | 0.006469 | 3.17864 | 3.19158 | 0 | 0.021795 | 0.021691 | 0.021795 | 0.021691 | 51.200000 | 171.673600 | 13.076700 | 13.014656 | 13.076700 | 13.014656 | column | external column - existing | galvanized | 0 | Construction Phase - Phase: Temporary Construction
column | GF | external column - existing :15,SHE-14.BALCONY.dgn,Design Model:179410 |  | UC152X152X51 | 1\BS5950_UC\UC152X152X51 | 3.353 | 0.0065 | 0.006469 | 3.17864 | 3.19158 | 0 | 0.021795 | 0.021691 | 0.021795 | 0.021691 | 51.200000 | 171.673600 | 13.076700 | 13.014656 | 13.076700 | 13.014656 | column | external column - existing | galvanized | 0 | Construction Phase - Phase: Temporary Construction
column | GF | external column - existing :15,SHE-14.BALCONY.dgn,Design Model:179412 |  | UC152X152X51 | 1\BS5950_UC\UC152X152X51 | 3.353 | 0.0065 | 0.006469 | 3.17864 | 3.19158 | 0 | 0.021795 | 0.021691 | 0.021795 | 0.021691 | 51.200000 | 171.673600 | 13.076700 | 13.014656 | 13.076700 | 13.014656 | column | external column - existing | galvanized | 0 | Construction Phase - Phase: Temporary Construction
column | GF | external column - existing :15,SHE-14.BALCONY.dgn,Design Model:179414 |  | UC152X152X51 | 1\BS5950_UC\UC152X152X51 | 3.353 | 0.0065 | 0.006469 | 3.17864 | 3.19158 | 0 | 0.021795 | 0.021691 | 0.021795 | 0.021691 | 51.200000 | 171.673600 | 13.076700 | 13.014656 | 13.076700 | 13.014656 | column | external column - existing | galvanized | 0 | Construction Phase - Phase: Temporary Construction
column | GF | external column - existing :15,SHE-14.BALCONY.dgn,Design Model:179416 |  | UC152X152X51 | 1\BS5950_UC\UC152X152X51 | 3.353 | 0.0065 | 0.006469 | 3.17864 | 3.19158 | 0 | 0.021795 | 0.021691 | 0.021795 | 0.021691 | 51.200000 | 171.673600 | 13.076700 | 13.014656 | 13.076700 | 13.014656 | column | external column - existing | galvanized | 0 | Construction Phase - Phase: Temporary Construction
column | GF | external column - existing :15,SHE-14.BALCONY.dgn,Design Model:179418 |  | UC152X152X51 | 1\BS5950_UC\UC152X152X51 | 3.353 | 0.0065 | 0.006469 | 3.17864 | 3.19158 | 0 | 0.021795 | 0.021691 | 0.021795 | 0.021691 | 51.200000 | 171.673600 | 13.076700 | 13.014656 | 13.076700 | 13.014656 | column | external column - existing | galvanized | 0 | Construction Phase - Phase: Temporary Construction
column | GF | external column - existing :15,SHE-14.BALCONY.dgn,Design Model:179420 |  | UC152X152X51 | 1\BS5950_UC\UC152X152X51 | 3.353 | 0.0065 | 0.006469 | 3.17864 | 3.19158 | 0 | 0.021795 | 0.021691 | 0.021795 | 0.021691 | 51.200000 | 171.673600 | 13.076700 | 13.014656 | 13.076700 | 13.014656 | column | external column - existing | galvanized | 0 | Construction Phase - Phase: Temporary Construction
column | GF | external column - existing :15,SHE-14.BALCONY.dgn,Design Model:179422 |  | UC152X152X51 | 1\BS5950_UC\UC152X152X51 | 3.353 | 0.0065 | 0.006469 | 3.17864 | 3.19158 | 0 | 0.021795 | 0.021691 | 0.021795 | 0.021691 | 51.200000 | 171.673600 | 13.076700 | 13.014656 | 13.076700 | 13.014656 | column | external column - existing | galvanized | 0 | Construction Phase - Phase: Temporary Construction
column | GF | external column - existing :15,SHE-14.BALCONY.dgn,Design Model:179424 |  | UC152X152X51 | 1\BS5950_UC\UC152X152X51 | 3.413 | 0.0065 | 0.006469 | 3.23552 | 3.24846 | 0 | 0.022184 | 0.022079 | 0.022184 | 0.022079 | 51.200000 | 174.745600 | 13.310700 | 13.247546 | 13.310700 | 13.247546 | column | external column - existing | galvanized | 0 | Construction Phase - Phase: Temporary Construction
column | GF | external column - existing :15,SHE-14.BALCONY.dgn,Design Model:179426 |  | UC152X152X51 | 1\BS5950_UC\UC152X152X51 | 3.413 | 0.0065 | 0.006469 | 3.23552 | 3.24846 | 0 | 0.022184 | 0.022079 | 0.022184 | 0.022079 | 51.200000 | 174.745600 | 13.310700 | 13.247546 | 13.310700 | 13.247546 | column | external column - existing | galvanized | 0 | Construction Phase - Phase: Temporary Construction
column | GF | external column - existing :15,SHE-14.BALCONY.dgn,Design Model:179428 |  | UC152X152X51 | 1\BS5950_UC\UC152X152X51 | 3.413 | 0.0065 | 0.006469 | 3.23552 | 3.24846 | 0 | 0.022184 | 0.022079 | 0.022184 | 0.022079 | 51.200000 | 174.745600 | 13.310700 | 13.247546 | 13.310700 | 13.247546 | column | external column - existing | galvanized | 0 | Construction Phase - Phase: Temporary Construction
column | GF | external column - existing :15,SHE-14.BALCONY.dgn,Design Model:179430 |  | UC152X152X51 | 1\BS5950_UC\UC152X152X51 | 3.413 | 0.0065 | 0.006469 | 3.23552 | 3.24846 | 0 | 0.022184 | 0.022079 | 0.022184 | 0.022079 | 51.200000 | 174.745600 | 13.310700 | 13.247546 | 13.310700 | 13.247546 | column | external column - existing | galvanized | 0 | Construction Phase - Phase: Temporary Construction
column | GF | external column - existing :15,SHE-14.BALCONY.dgn,Design Model:179432 |  | UC152X152X51 | 1\BS5950_UC\UC152X152X51 | 3.413 | 0.0065 | 0.006469 | 3.23552 | 3.24846 | 0 | 0.022184 | 0.022079 | 0.022184 | 0.022079 | 51.200000 | 174.745600 | 13.310700 | 13.247546 | 13.310700 | 13.247546 | column | external column - existing | galvanized | 0 | Construction Phase - Phase: Temporary Construction
column | GF | external column - existing :15,SHE-14.BALCONY.dgn,Design Model:179434 |  | UC152X152X51 | 1\BS5950_UC\UC152X152X51 | 3.413 | 0.0065 | 0.006469 | 3.23552 | 3.24846 | 0 | 0.022184 | 0.022079 | 0.022184 | 0.022079 | 51.200000 | 174.745600 | 13.310700 | 13.247546 | 13.310700 | 13.247546 | column | external column - existing | galvanized | 0 | Construction Phase - Phase: Temporary Construction
column | GF | external column - existing :15,SHE-14.BALCONY.dgn,Design Model:179436 |  | UC152X152X51 | 1\BS5950_UC\UC152X152X51 | 3.413 | 0.0065 | 0.006469 | 3.23552 | 3.24846 | 0 | 0.022184 | 0.022079 | 0.022184 | 0.022079 | 51.200000 | 174.745600 | 13.310700 | 13.247546 | 13.310700 | 13.247546 | column | external column - existing | galvanized | 0 | Construction Phase - Phase: Temporary Construction
column | GF | external column - existing :15,SHE-14.BALCONY.dgn,Design Model:179438 |  | UC152X152X51 | 1\BS5950_UC\UC152X152X51 | 3.413 | 0.0065 | 0.006469 | 3.23552 | 3.24846 | 0 | 0.022184 | 0.022079 | 0.022184 | 0.022079 | 51.200000 | 174.745600 | 13.310700 | 13.247546 | 13.310700 | 13.247546 | column | external column - existing | galvanized | 0 | Construction Phase - Phase: Temporary Construction

# IfcColumn: A-Columns:A_BSUK_Columns_ReinforcedConcrete (2)
In: GF
Material: A_BSUK_Columns_ReinforcedConcrete
BuildingDesignerForm - Cope Flange Clearance: 0.000; Cope Web Clearance: 0.000; Cope Corner Treatment: 0; Cope Corner Radius: 0.000; Local Y Offset: 0.000; Local Z Offset: 0.000
Name | Description | Section Name
A-Columns--A_BSUK_Columns_ReinforcedConcrete | 16,SHE-12.STAIR.dgn ,Design Model:202031 | 0.670X0.300
A-Columns--A_BSUK_Columns_ReinforcedConcrete | 16,SHE-12.STAIR.dgn ,Design Model:202033 | 0.500X0.300

# IfcCurtainWall: Generic - Maximum Spacing (4)
Type - Space Bounding - Is Space Bounding: yes
Type - Materials - Part Definition: A-CurtainWall::A-CurtainWall_Frame
Type - Curtain Wall | Panel - Panel | Type: Glazing Type 1; Panel | Thickness: 0.02 m; Panel | Offset: 0 m
Type - Curtain Wall | Mullion - Vertical - Vertical | Profile: _Generic - Mullion; Vertical | Width: 0.05 m; Vertical | Depth: 0.15 m
Type - Curtain Wall | Mullion - Horizontal - Horizontal | Profile: _Generic - Mullion; Horizontal | Width: 0.05 m; Horizontal | Depth: 0.15 m
Type - Curtain Wall | Frame - Sill - Sill | Same as Jamb: yes
Type - Curtain Wall | Frame - Jamb - Jamb | Profile: _Generic - Frame; Jamb | Width: 0.05 m; Jamb | Depth: 0.15 m
Type - Curtain Wall | Frame - Head - Head | Same as Jamb: yes
Type - Curtain Wall | Frame - Corner - Corner | Profile: _Generic - Corner; Corner | Width: 0.05 m; Corner | Depth: 0.15 m
Type - Curtain Wall Properties - Hurricane Resistant: no
Type - Curtain Wall Parameters - Curtain Wall Type: Storefront; Perforate Host: yes; Sense Distance: 0.3 m; Mullion Continuity: Continuous Vertical; Layout | Horizontal Layout: Maximum Spacing; Layout | Horizontal Justification: Bottom; Layout | Horizontal Number: 1; Layout | Horizontal Spacing: 2 m; Layout | Horizontal Pattern: no; Layout | Horizontal Pattern Spacing: 2000;1000;1000; Layout | Vertical Layout: Maximum Spacing; Layout | Vertical Justification: Start; Layout | Vertical Number: 1; Layout | Vertical Spacing: 1 m; Layout | Vertical Pattern: no; Layout | Vertical Pattern Spacing: 3000;1000
Type - Classification - Uniclass2015: Ss_25_10_20
Material: A-CurtainWall_Frame
Identification - ID | Description: AOV1 vented hall louver
Curtain Wall | Panel - Panel | Type: Louvers
Curtain Wall | Frame - Sill - Sill | Profile: _Generic - Frame; Sill | Width: 0.05 m; Sill | Depth: 0.15 m
Curtain Wall | Frame - Head - Head | Profile: _Generic - Frame; Head | Width: 0.05 m; Head | Depth: 0.15 m
Curtain Wall | Frame - Corner - Corner | Width: 0.18 m
Curtain Wall Parameters - Curtain Wall Type: Punched Opening; Height: 1.5 m; Length: 0.9 m; Layout | Horizontal Spacing: 1.5 m; Layout | Horizontal Pattern Spacing: 2.000;1.000;1.000; Layout | Vertical Spacing: 1.5 m; Layout | Vertical Pattern Spacing: 3.000;1.000
Name | In | Description
Generic - Maximum Spacing | 1F | AOV1 vented hall louver :4,SHE-03.FIRST.dgn,Design Model:147014
Generic - Maximum Spacing | 3F | AOV1 vented hall louver :6,SHE-05.THIRD.dgn,Design Model:147014
Generic - Maximum Spacing | 1F | AOV1 vented hall louver :7,SHE-06.FOURTH.dgn,Design Model:212650 | Curtain Wall | Frame - Jamb - Jamb | Profile: SHE_50x100Center - Frame; Jamb | Depth: 0.1 m
Generic - Maximum Spacing | 2F | AOV1 vented hall louver :18,SHE-04.SECOND.dgn,Design Model:147014

# IfcCurtainWall: Pattern - Maximum Spacing (30)
In: 1F
Type - Space Bounding - Is Space Bounding: yes
Type - Materials - Part Definition: A-CurtainWall::A-CurtainWall_Frame
Type - Curtain Wall | Panel - Panel | Type: Glazing Type 1; Panel | Thickness: 0.02 m; Panel | Offset: 0 m
Type - Curtain Wall | Mullion - Vertical - Vertical | Profile: _Generic - Mullion; Vertical | Width: 0.05 m; Vertical | Depth: 0.15 m
Type - Curtain Wall | Mullion - Horizontal - Horizontal | Profile: _Generic - Mullion; Horizontal | Width: 0.05 m; Horizontal | Depth: 0.15 m
Type - Curtain Wall | Frame - Sill - Sill | Same as Jamb: yes
Type - Curtain Wall | Frame - Jamb - Jamb | Profile: _Generic - Frame; Jamb | Width: 0.05 m; Jamb | Depth: 0.15 m
Type - Curtain Wall | Frame - Head - Head | Same as Jamb: yes
Type - Curtain Wall | Frame - Corner - Corner | Profile: _Generic - Corner; Corner | Width: 0.05 m; Corner | Depth: 0.15 m
Type - Curtain Wall Properties - Hurricane Resistant: no
Type - Curtain Wall Parameters - Curtain Wall Type: Storefront; Perforate Host: yes; Sense Distance: 0.3 m; Mullion Continuity: Continuous Vertical; Layout | Horizontal Layout: Maximum Spacing; Layout | Horizontal Justification: Bottom; Layout | Horizontal Number: 1; Layout | Horizontal Spacing: 2 m; Layout | Horizontal Pattern: yes; Layout | Horizontal Pattern Spacing: 2000;1000;1000; Layout | Vertical Layout: Maximum Spacing; Layout | Vertical Justification: Start; Layout | Vertical Number: 1; Layout | Vertical Spacing: 1 m; Layout | Vertical Pattern: yes; Layout | Vertical Pattern Spacing: 3000;1000
Type - Classification - Uniclass2015: Ss_25_10_20
Material: A-CurtainWall_Frame
Identification - ID | Type ID: U-Value 1.4; ID | Name (Alternate): G-Value 0.6; ID | Asset Tag: safety glass internal up to 800mm, balustrade Part K compliance , brocken mullion, double glazed opaque spandral panel , no capping above spandral panel
Curtain Wall | Panel - Panel | Thickness: 0.01 m
Curtain Wall | Mullion - Vertical - Vertical | Profile: SHE_50x100Center - Mullion; Vertical | Depth: 0.1 m
Curtain Wall | Mullion - Horizontal - Horizontal | Profile: SHE_50x100Center - Mullion; Horizontal | Depth: 0.1 m
Curtain Wall | Frame - Sill - Sill | Profile: _Generic - Frame; Sill | Width: 0.05 m; Sill | Depth: 0.15 m
Curtain Wall | Frame - Jamb - Jamb | Profile: SHE_50x100Center - Frame; Jamb | Depth: 0.1 m
Curtain Wall | Frame - Head - Head | Profile: _Generic - Frame; Head | Width: 0.05 m; Head | Depth: 0.15 m
Curtain Wall | Frame - Corner - Corner | Width: 0.18 m
Curtain Wall Parameters - Curtain Wall Type: Curtain Wall; Length: 1.52 m; Layout | Vertical Pattern Spacing: 1.60
Name | Description | ID | Number | ID | Description | ID | Keynote | ID | Notes | Height (m) | Layout | Horizontal Pattern Spacing
09 | U-Value 1.4 - bedroom at back/over flat roof :3,SHE-09.FACADE.dgn ,Design Model:105400 | 09 | bedroom at back/over flat roof | Rw 37dB, Rw+Ctr 35dB , trickle vent 45dB | 3 x tilt and turn windows 1.4x1.6m | 8.2 | 1.200;0.900;0.900;1.700;0.900;0.900;1.680;
02 | U-Value 1.4 - kdl at back :3,SHE-09.FACADE.dgn,Design Model:105404 | 02 | kdl at back | Rw 34dB, Rw+Ctr 30dB , trickle vent 45dB | 3 x tilt and turn windows 1.4x1.6m | 10.75 | 1.130;0.900;1.700;0.900;0.900;1.700;0.900;0.900;1.680;
03 | U-Value 1.4 - bedroom at back :3,SHE-09.FACADE.dgn,Design Model:105409 | 03 | bedroom at back | Rw 37dB, Rw+Ctr 35dB , trickle vent 45dB | 3 x tilt and turn windows 1.4x1.6m | 10.75 | 1.130;0.900;1.700;0.900;0.900;1.700;0.900;0.900;1.680;
04 | U-Value 1.4 - bedroom at back :3,SHE-09.FACADE.dgn,Design Model:105414 | 04 | bedroom at back | Rw 37dB, Rw+Ctr 35dB , trickle vent 45dB | 3 x tilt and turn windows 1.4x1.6m | 10.75 | 1.130;0.900;1.700;0.900;0.900;1.700;0.900;0.900;1.680;
05 | U-Value 1.4 - bedroom at back :3,SHE-09.FACADE.dgn,Design Model:105419 | 05 | bedroom at back | Rw 37dB, Rw+Ctr 35dB , trickle vent 45dB | 3 x tilt and turn windows 1.4x1.6m | 10.75 | 1.130;0.900;1.700;0.900;0.900;1.700;0.900;0.900;1.680;
06 | U-Value 1.4 - kdl at back :3,SHE-09.FACADE.dgn,Design Model:105424 | 06 | kdl at back | Rw 34dB, Rw+Ctr 30dB , trickle vent 45dB | 3 x tilt and turn windows 1.4x1.6m | 10.75 | 1.130;0.900;1.700;0.900;0.900;1.700;0.900;0.900;1.680;
07 | U-Value 1.4 - kdl at back :3,SHE-09.FACADE.dgn,Design Model:105429 | 07 | kdl at back | Rw 34dB, Rw+Ctr 30dB , trickle vent 45dB | 3 x tilt and turn windows 1.4x1.6m | 10.75 | 1.130;0.900;1.700;0.900;0.900;1.700;0.900;0.900;1.680;
08 | U-Value 1.4 - bedroom at back :3,SHE-09.FACADE.dgn,Design Model:105434 | 08 | bedroom at back | Rw 37dB, Rw+Ctr 35dB , trickle vent 45dB | 3 x tilt and turn windows 1.4x1.6m | 10.75 | 1.130;0.900;1.700;0.900;0.900;1.700;0.900;0.900;1.680;
01 | U-Value 1.4 - kdl at back with balcony doors :3,SHE-09.FACADE.dgn ,Design Model:106177 | 01 | kdl at back with balcony doors | Rw 34dB, Rw+Ctr 30dB , trickle vent 45dB | 3 x glass doors 1.05x2 ,1m with top/side panel | 10.75 | 1.130;0.900;1.700;0.900;0.900;1.700;0.900;0.900;1.680;
10 | U-Value 1.4 - kdl at back/over flat roof :3,SHE-09.FACADE.dgn ,Design Model:106183 | 10 | kdl at back/over flat roof | Rw 34dB, Rw+Ctr 30dB , trickle vent 45dB | 3 x tilt and turn windows 1.4x1.6m | 8.2 | 1.200;0.900;0.900;1.700;0.900;0.900;1.680;
11 | U-Value 1.4 - kdl at back/over flat roof :3,SHE-09.FACADE.dgn ,Design Model:106188 | 11 | kdl at back/over flat roof | Rw 34dB, Rw+Ctr 30dB , trickle vent 45dB | 3 x tilt and turn windows 1.4x1.6m | 8.2 | 1.200;0.900;0.900;1.700;0.900;0.900;1.680;
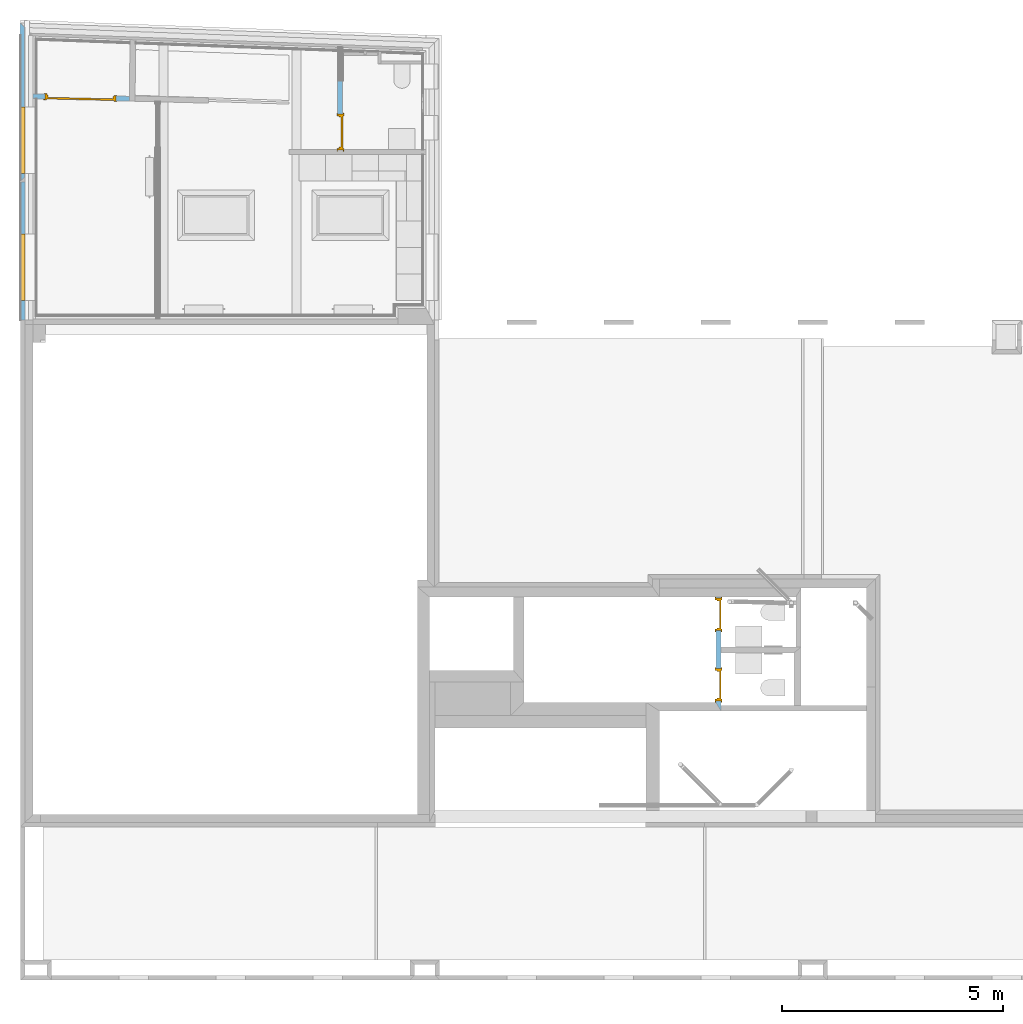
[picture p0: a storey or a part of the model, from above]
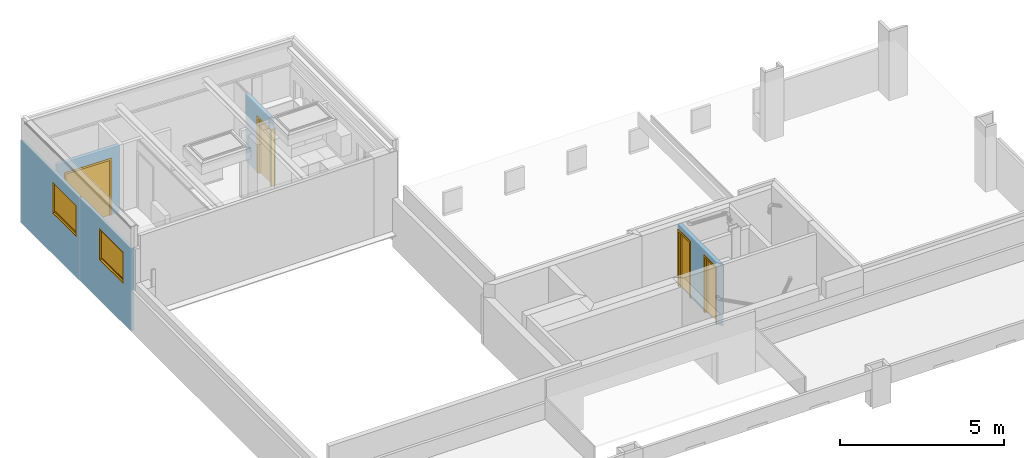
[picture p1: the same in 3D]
Properties of the parts of a building model (IFC2X3), part 6 of 17

# IfcCurtainWall: Pattern - Maximum Spacing (30)
Name | Description | ID | Number | ID | Description | ID | Keynote | ID | Notes | Height (m) | Layout | Horizontal Pattern Spacing
12 | U-Value 1.4 - kdl at back/over flat roof :3,SHE-09.FACADE.dgn ,Design Model:106193 | 12 | kdl at back/over flat roof | Rw 34dB, Rw+Ctr 30dB , trickle vent 45dB | 3 x tilt and turn windows 1.4x1.6m | 8.2 | 1.200;0.900;0.900;1.700;0.900;0.900;1.680;
13 | U-Value 1.4 - bedroom at side :3,SHE-09.FACADE.dgn,Design Model:106198 | 13 | bedroom at side | Rw 37dB, Rw+Ctr 35dB , trickle vent 45dB | 3 x tilt and turn windows 1.4x1.6m | 8.7 | 1.700;0.900;0.900;1.700;0.900;0.900;1.680;
14 | U-Value 1.4 - kdl at side :3,SHE-09.FACADE.dgn,Design Model:106203 | 14 | kdl at side | Rw 34dB, Rw+Ctr 30dB , trickle vent 45dB | 3 x tilt and turn windows 1.4x1.6m | 8.7 | 1.700;0.900;0.900;1.700;0.900;0.900;1.680;
15 | U-Value 1.4 - kdl at side :3,SHE-09.FACADE.dgn,Design Model:106208 | 15 | kdl at side | Rw 34dB, Rw+Ctr 30dB , trickle vent 45dB | 3 x tilt and turn windows 1.4x1.6m | 8.7 | 1.700;0.900;0.900;1.700;0.900;0.900;1.680;
30 | U-Value 1.4 - kdl at side :3,SHE-09.FACADE.dgn,Design Model:106213 | 30 | kdl at side | Rw 34dB, Rw+Ctr 30dB , trickle vent 45dB | 3 x tilt and turn windows 1.4x1.6m | 8.7 | 1.700;0.900;0.900;1.700;0.900;0.900;1.680;
29 | U-Value 1.4 - kdl at side :3,SHE-09.FACADE.dgn,Design Model:106218 | 29 | kdl at side | Rw 34dB, Rw+Ctr 30dB , trickle vent 45dB | 3 x tilt and turn windows 1.4x1.6m | 8.7 | 1.700;0.900;0.900;1.700;0.900;0.900;1.680;
28 | U-Value 1.4 - kdl at side :3,SHE-09.FACADE.dgn,Design Model:106223 | 28 | kdl at side | Rw 34dB, Rw+Ctr 30dB , trickle vent 45dB | 3 x tilt and turn windows 1.4x1.6m | 8.7 | 1.700;0.900;0.900;1.700;0.900;0.900;1.680;
26 | U-Value 1.4 - bedroom at front :3,SHE-09.FACADE.dgn,Design Model:106227 | 26 | bedroom at front | Rw 37dB, Rw+Ctr 35dB , trickle vent 45dB | 3 x tilt and turn windows 1.4x1.6m | 10.75 | 1.130;0.900;1.700;0.900;0.900;1.700;0.900;0.900;1.680;
25 | U-Value 1.4 - bedroom at front :3,SHE-09.FACADE.dgn,Design Model:106232 | 25 | bedroom at front | Rw 37dB, Rw+Ctr 35dB , trickle vent 45dB | 3 x tilt and turn windows 1.4x1.6m | 10.75 | 1.130;0.900;1.700;0.900;0.900;1.700;0.900;0.900;1.680;
24 | U-Value 1.4 - kdl at front :3,SHE-09.FACADE.dgn,Design Model:106237 | 24 | kdl at front | Rw 34dB, Rw+Ctr 30dB , trickle vent 45dB | 3 x tilt and turn windows 1.4x1.6m | 10.75 | 1.130;0.900;1.700;0.900;0.900;1.700;0.900;0.900;1.680;
23 | U-Value 1.4 - kdl at front :3,SHE-09.FACADE.dgn,Design Model:106242 | 23 | kdl at front | Rw 34dB, Rw+Ctr 30dB , trickle vent 45dB | 3 x tilt and turn windows 1.4x1.6m | 10.75 | 1.130;0.900;1.700;0.900;0.900;1.700;0.900;0.900;1.680;
22 | U-Value 1.4 - kdl at front :3,SHE-09.FACADE.dgn,Design Model:106247 | 22 | kdl at front | Rw 34dB, Rw+Ctr 30dB , trickle vent 45dB | 3 x tilt and turn windows 1.4x1.6m | 10.75 | 1.130;0.900;1.700;0.900;0.900;1.700;0.900;0.900;1.680;
21 | U-Value 1.4 - kdl at front :3,SHE-09.FACADE.dgn,Design Model:106252 | 21 | kdl at front | Rw 34dB, Rw+Ctr 30dB , trickle vent 45dB | 3 x tilt and turn windows 1.4x1.6m | 10.75 | 1.130;0.900;1.700;0.900;0.900;1.700;0.900;0.900;1.680;
20 | U-Value 1.4 - kdl at front :3,SHE-09.FACADE.dgn,Design Model:106257 | 20 | kdl at front | Rw 34dB, Rw+Ctr 30dB , trickle vent 45dB | 3 x tilt and turn windows 1.4x1.6m | 10.75 | 1.130;0.900;1.700;0.900;0.900;1.700;0.900;0.900;1.680;
27 | U-Value 1.4 - bedroom at front :3,SHE-09.FACADE.dgn,Design Model:106262 | 27 | bedroom at front | Rw 37dB, Rw+Ctr 35dB , trickle vent 45dB | 3 x tilt and turn windows 1.4x1.6m | 10.75 | 1.130;0.900;1.700;0.900;0.900;1.700;0.900;0.900;1.680;
19 | U-Value 1.4 - kdl at front :3,SHE-09.FACADE.dgn,Design Model:106267 | 19 | kdl at front | Rw 34dB, Rw+Ctr 30dB , trickle vent 45dB | 3 x tilt and turn windows 1.4x1.6m | 10.75 | 1.130;0.900;1.700;0.900;0.900;1.700;0.900;0.900;1.680;
18 | U-Value 1.4 - bedroom at front :3,SHE-09.FACADE.dgn,Design Model:106272 | 18 | bedroom at front | Rw 37dB, Rw+Ctr 35dB , trickle vent 45dB | 3 x tilt and turn windows 1.4x1.6m | 10.75 | 1.130;0.900;1.700;0.900;0.900;1.700;0.900;0.900;1.680;
17 | U-Value 1.4 - bedroom at front :3,SHE-09.FACADE.dgn,Design Model:106277 | 17 | bedroom at front | Rw 37dB, Rw+Ctr 35dB , trickle vent 45dB | 3 x tilt and turn windows 1.4x1.6m | 10.75 | 1.130;0.900;1.700;0.900;0.900;1.700;0.900;0.900;1.680;
16 | U-Value 1.4 - bedroom at front :3,SHE-09.FACADE.dgn,Design Model:106282 | 16 | bedroom at front | Rw 37dB, Rw+Ctr 35dB , trickle vent 45dB | 3 x tilt and turn windows 1.4x1.6m | 10.75 | 1.130;0.900;1.700;0.900;0.900;1.700;0.900;0.900;1.680;

# IfcDistributionFlowElement: M-BmvCthwconnection-CTHWConnection (4)
Type - Parameters - Insulation | Thickness (mm): 0; Lining | Thickness (mm): 0; Correction Factor: 1.0; Wall Thickness: 0
Type - End Spec1_1 (1 Connection: Rect) - Width 1 (W1): 1150; Depth 1 (D1): 250
Type - Classification - Uniclass2015: Pr_60_60_13
Type - Cabinet Type with Hot Water Connection - Tag: CTHWConnection; Box | Height: 625; Box | Width: 1250; Box | Length: 1250; Connection 1 | Length (L1): 0; Coil Inlet | Top Offset: 50; Coil Inlet | Side Offset: 625; Coil Outlet | Top Offset: 50; Coil Outlet | Side Offset: 625; Coil Inlet-Outlet | Diameter: 50; Coil | Length: 50; Coil Inlet | Connection Side: 1-left; Coil Outlet | Connection Side: 2-right; Connection | End Type: -;; View Display: Iso
Material: M_BSUK_Ventilation
Parameters - Surface Area: 2.56391 m2; Center Of Gravity: 500.00; -0.93; 6.19;; Insulation | Surface Area: 0 m2; Lining | Surface Area: 0 m2; Status: BSUK; Air Flow: M
End Spec1_1 (1 Connection: Rect) - Width 1 (W1): 360
Cabinet Type with Hot Water Connection - Box | Width: 400; Box | Length: 1000; Coil Inlet | Side Offset: 350; Coil Outlet | Side Offset: 350
Name | In | Description
M-BmvCthwconnection-CTHWConnection | ter.26 | 8,SHE-07.FIFTH.dgn,Design Model:281830
M-BmvCthwconnection-CTHWConnection | ter.23 | 8,SHE-07.FIFTH.dgn,Design Model:282996
M-BmvCthwconnection-CTHWConnection | ter.24 | 8,SHE-07.FIFTH.dgn,Design Model:283090
M-BmvCthwconnection-CTHWConnection | ter.25 | 8,SHE-07.FIFTH.dgn,Design Model:283184

# IfcDoor: A-Doors-DoubleFlush, 0.05
In: ENTRANCE
Type - OperationType: DOUBLE_DOOR_SINGLE_SWING; ConstructionType: USERDEFINED; ParameterTakesPrecedence: no; Sizeable: no
Type - Lining - LiningDepth: 0.07 m; LiningThickness: 0.069 m
Type - Thermal Transmittance - Is External: no; Is Below Grade: no
Type - Fire Resistance - Fire | IsCombustible: no; Fire | Compartmentation: no
Type - Door Parameters - Parametric | File Type: PAZ; Parametric | File Name: DoorDoubleFlush; Dimension | Leaf Width: 1.726 m; Dimension | Height: 2.058 m; Dimension | Frame Depth: 0.07 m; Dimension | Frame Depth Match Wall: yes; Dimension | Architrave Width: 0.069 m; Dimension | Leaf Thickness: 0.04 m
Type - Door - Door | Type: F - Flush; Door | IsEgress: no; Frame | Material: HM
Type - Discipline - Discipline: Architectural
Type - Classification - Uniclass2015: Pr_30_59_23
Description: riser duct :1 ,SHE-01.GROUND.dgn,Design Model:101662; OverallHeight: 2.127 m; OverallWidth: 1.178 m; Material: A_BSUK_Doors
Pset_DoorCommon - FireExit: no; FireRating: FD30
Identification - ID | Number: 0.05; ID | Description: riser duct; ID | Keynote: FIRE DOOR KEEP CLOSED; ID | Notes: common parts
Fire Resistance - Fire | Rating: FD30
Door Parameters - Dimension | Leaf Width: 1.04 m
Door - Door | Finish: white; Door | Under Cut: 0 m; Glazing: no; Louver: no
Construction Phase - Phase: New Construction

# IfcDoor: A-Doors-DoubleFlush, 0.17
In: 01
Type - OperationType: DOUBLE_DOOR_SINGLE_SWING; ConstructionType: USERDEFINED; ParameterTakesPrecedence: no; Sizeable: no
Type - Lining - LiningDepth: 0.08 m; LiningThickness: 0.069 m
Type - Thermal Transmittance - Is External: no; Is Below Grade: no
Type - Fire Resistance - Fire | IsCombustible: no; Fire | Compartmentation: no
Type - Door Parameters - Parametric | File Type: PAZ; Parametric | File Name: DoorDoubleFlush; Dimension | Leaf Width: 1.726 m; Dimension | Height: 2.058 m; Dimension | Frame Depth: 0.08 m; Dimension | Frame Depth Match Wall: yes; Dimension | Architrave Width: 0.069 m; Dimension | Leaf Thickness: 0.04 m
Type - Door - Door | Type: F - Flush; Door | IsEgress: no; Frame | Material: HM
Type - Discipline - Discipline: Architectural
Type - Classification - Uniclass2015: Pr_30_59_23
Description: storage :1 ,SHE-01.GROUND.dgn,Design Model:160385; OverallHeight: 2.127 m; OverallWidth: 1.178 m; Material: A_BSUK_Doors
Pset_DoorCommon - FireExit: no
Identification - ID | Number: 0.17; ID | Name (Alternate): Flat 01; ID | Description: storage; ID | Notes: residential
Door Parameters - Dimension | Leaf Width: 1.04 m
Door - Door | Finish: white; Door | Under Cut: 0 m; Glazing: no; Louver: no
Construction Phase - Phase: New Construction

# IfcDoor: A-Doors-DoubleFlush (4)
Type - OperationType: DOUBLE_DOOR_SINGLE_SWING; ConstructionType: USERDEFINED; ParameterTakesPrecedence: no; Sizeable: no
Type - Lining - LiningDepth: 0.1 m; LiningThickness: 0.069 m
Type - Thermal Transmittance - Is External: no; Is Below Grade: no
Type - Fire Resistance - Fire | IsCombustible: no; Fire | Compartmentation: no
Type - Door Parameters - Parametric | File Type: PAZ; Parametric | File Name: DoorDoubleFlush; Dimension | Leaf Width: 1.726 m; Dimension | Height: 2.058 m; Dimension | Frame Depth: 0.1 m; Dimension | Frame Depth Match Wall: yes; Dimension | Architrave Width: 0.069 m; Dimension | Leaf Thickness: 0.04 m
Type - Door - Door | Type: F - Flush; Door | IsEgress: no; Frame | Material: HM
Type - Discipline - Discipline: Architectural
Type - Classification - Uniclass2015: Pr_30_59_23
Material: A_BSUK_Doors
Pset_DoorCommon - FireExit: no
Door - Door | Finish: white; Door | Under Cut: 0 m; Glazing: no; Louver: no
Construction Phase - Phase: New Construction
Name | In | Description | OverallHeight (m) | OverallWidth (m) | ID | Number | ID | Description | ID | Notes | Dimension | Leaf Width (m)
0.02 | UNDERCROFT (back) | storage :1 ,SHE-01.GROUND.dgn,Design Model:98220 | 2.1 | 1.784 | 0.02 | storage | external | 1.7
0.03 | UNDERCROFT (back) | storage :1 ,SHE-01.GROUND.dgn,Design Model:98529 | 2.1 | 1.784 | 0.03 | storage | external | 1.7
0.23 | 01 | storage :2 ,SHE-02.MEZZANINE.dgn,Design Model:95957 | 2.127 | 1.658 | 0.23 | storage | residential | 1.52 | Identification - ID | Name (Alternate): Flat 01
4.03 | hall (vented) | riser duct :7 ,SHE-06.FOURTH.dgn,Design Model:212337 | 2.13 | 0.984 | 4.03 | riser duct | common parts | 0.9 | Pset_DoorCommon - FireRating: FD30; Identification - ID | Keynote: FIRE DOOR KEEP CLOSED; Fire Resistance - Fire | Rating: FD30; Door Parameters - Dimension | Frame Depth Match Wall: no

# IfcDoor: A-Doors-DoubleFlush (3)
In: 2
Type - OperationType: DOUBLE_DOOR_SINGLE_SWING; ConstructionType: USERDEFINED; ParameterTakesPrecedence: no; Sizeable: no
Type - Lining - LiningDepth: 0.102 m; LiningThickness: 0.069 m
Type - Thermal Transmittance - Is External: no; Is Below Grade: no
Type - Fire Resistance - Fire | IsCombustible: no; Fire | Compartmentation: no
Type - Door Parameters - Parametric | File Type: PAZ; Parametric | File Name: DoorDoubleFlush; Dimension | Leaf Width: 1.726 m; Dimension | Height: 2.058 m; Dimension | Frame Depth: 0.102 m; Dimension | Frame Depth Match Wall: yes; Dimension | Architrave Width: 0.069 m; Dimension | Leaf Thickness: 0.04 m
Type - Door - Door | Type: F - Flush; Door | IsEgress: no; Frame | Material: HM
Type - Discipline - Discipline: Architectural
Type - Classification - Uniclass2015: Pr_30_59_23
OverallHeight: 2.1 m; OverallWidth: 0.984 m; Material: A_BSUK_Doors
Pset_DoorCommon - FireExit: no; FireRating: FD30
Identification - ID | Description: riser duct; ID | Keynote: FIRE DOOR KEEP CLOSED; ID | Notes: common parts
Fire Resistance - Fire | Rating: FD30
Door Parameters - Dimension | Leaf Width: 0.9 m
Door - Door | Finish: white; Door | Under Cut: 0 m; Glazing: no; Louver: no
Construction Phase - Phase: New Construction
Name | Description | ID | Number
1.28 | riser duct :4 ,SHE-03.FIRST.dgn,Design Model:163330 | 1.28
3.28 | riser duct :6 ,SHE-05.THIRD.dgn,Design Model:163330 | 3.28
2.28 | riser duct :18 ,SHE-04.SECOND.dgn,Design Model:163330 | 2.28

# IfcDoor: A-Doors-DoubleFlush (2)
In: ENTRANCE
Type - OperationType: DOUBLE_DOOR_SINGLE_SWING; ConstructionType: USERDEFINED; ParameterTakesPrecedence: no; Sizeable: no
Type - Lining - LiningDepth: 0.103 m; LiningThickness: 0.069 m
Type - Thermal Transmittance - Is External: no; Is Below Grade: no
Type - Fire Resistance - Fire | IsCombustible: no; Fire | Compartmentation: no
Type - Door Parameters - Parametric | File Type: PAZ; Parametric | File Name: DoorDoubleFlush; Dimension | Leaf Width: 1.726 m; Dimension | Height: 2.058 m; Dimension | Frame Depth: 0.103 m; Dimension | Frame Depth Match Wall: yes; Dimension | Architrave Width: 0.069 m; Dimension | Leaf Thickness: 0.04 m
Type - Door - Door | Type: F - Flush; Door | IsEgress: no; Frame | Material: HM
Type - Discipline - Discipline: Architectural
Type - Classification - Uniclass2015: Pr_30_59_23
OverallHeight: 2.127 m; OverallWidth: 1.703 m; Material: A_BSUK_Doors
Pset_DoorCommon - FireExit: no; FireRating: FD30
Identification - ID | Description: riser duct; ID | Keynote: FIRE DOOR KEEP CLOSED; ID | Notes: common parts
Fire Resistance - Fire | Rating: FD30
Door Parameters - Dimension | Leaf Width: 1.565 m
Door - Door | Finish: white; Door | Under Cut: 0 m; Glazing: no; Louver: no
Construction Phase - Phase: New Construction
Name | Description | ID | Number
0.06 | riser duct :1 ,SHE-01.GROUND.dgn,Design Model:101971 | 0.06
0.07 | riser duct :1 ,SHE-01.GROUND.dgn,Design Model:102276 | 0.07

# IfcDoor: A-Doors-DoubleFlush, 0.01
In: UNDERCROFT (front)
Type - OperationType: DOUBLE_DOOR_SINGLE_SWING; ConstructionType: USERDEFINED; ParameterTakesPrecedence: no; Sizeable: no
Type - Lining - LiningDepth: 0.1524 m; LiningThickness: 0.069 m
Type - Thermal Transmittance - Is External: no; Is Below Grade: no
Type - Fire Resistance - Fire | IsCombustible: no; Fire | Compartmentation: no
Type - Door Parameters - Parametric | File Type: PAZ; Parametric | File Name: DoorDoubleFlush; Dimension | Leaf Width: 1.726 m; Dimension | Height: 2.058 m; Dimension | Frame Depth: 0.1524 m; Dimension | Frame Depth Match Wall: yes; Dimension | Architrave Width: 0.069 m; Dimension | Leaf Thickness: 0.04 m
Type - Door - Door | Type: F - Flush; Door | IsEgress: no; Frame | Material: HM
Type - Discipline - Discipline: Architectural
Type - Classification - Uniclass2015: Pr_30_59_23
Description: entrance - main residential :1,SHE-01.GROUND.dgn,Design Model:137758; OverallHeight: 2.1 m; OverallWidth: 1.934 m; Material: A_BSUK_Doors
Pset_DoorCommon - FireExit: no
Identification - ID | Number: 0.01; ID | Description: entrance - main residential; ID | Keynote: security - Part Q / PAS24 compliance, Emergency Exit Lock; ID | Notes: external
Door Parameters - Dimension | Leaf Width: 1.85 m
Door - Door | Finish: RAL 9017 - traffic black matt textured; Door | Under Cut: 0 m; Glazing: no; Glazing | Notes: glazing; Louver: no; Frame | Material: Glass
Construction Phase - Phase: New Construction

# IfcDoor: A-Doors-DoubleFlush (3)
In: hall (vented)
Type - OperationType: DOUBLE_DOOR_SINGLE_SWING; ConstructionType: USERDEFINED; ParameterTakesPrecedence: no; Sizeable: no
Type - Lining - LiningDepth: 0.17 m; LiningThickness: 0.069 m
Type - Thermal Transmittance - Is External: no; Is Below Grade: no
Type - Fire Resistance - Fire | IsCombustible: no; Fire | Compartmentation: no
Type - Door Parameters - Parametric | File Type: PAZ; Parametric | File Name: DoorDoubleFlush; Dimension | Leaf Width: 1.726 m; Dimension | Height: 2.058 m; Dimension | Frame Depth: 0.17 m; Dimension | Frame Depth Match Wall: yes; Dimension | Architrave Width: 0.069 m; Dimension | Leaf Thickness: 0.04 m
Type - Door - Door | Type: F - Flush; Door | IsEgress: no; Frame | Material: HM
Type - Discipline - Discipline: Architectural
Type - Classification - Uniclass2015: Pr_30_59_23
OverallHeight: 2.127 m; OverallWidth: 1.038 m; Material: A_BSUK_Doors
Pset_DoorCommon - FireExit: no; FireRating: FD30
Identification - ID | Description: riser duct; ID | Keynote: FIRE DOOR KEEP CLOSED; ID | Notes: common parts
Fire Resistance - Fire | Rating: FD30
Door Parameters - Dimension | Leaf Width: 0.9 m; Dimension | Frame Depth Match Wall: no
Door - Door | Finish: white; Door | Under Cut: 0 m; Glazing: no; Louver: no
Construction Phase - Phase: New Construction
Name | Description | ID | Number
1.03 | riser duct :4 ,SHE-03.FIRST.dgn,Design Model:140797 | 1.03
3.03 | riser duct :6 ,SHE-05.THIRD.dgn,Design Model:140797 | 3.03
2.03 | riser duct :18 ,SHE-04.SECOND.dgn,Design Model:140797 | 2.03

# IfcDoor: A-Doors-SingleFlush (9)
Type - OperationType: SINGLE_SWING_LEFT; ConstructionType: USERDEFINED; ParameterTakesPrecedence: no; Sizeable: no
Type - Lining - LiningDepth: 0.08 m; LiningThickness: 0.069 m
Type - Thermal Transmittance - Is External: no; Is Below Grade: no
Type - Fire Resistance - Fire | IsCombustible: no; Fire | Compartmentation: no
Type - Door Parameters - Parametric | File Type: PAZ; Parametric | File Name: DoorSingleFlush; Dimension | Leaf Width: 0.826 m; Dimension | Height: 2.058 m; Dimension | Frame Depth: 0.08 m; Dimension | Frame Depth Match Wall: yes; Dimension | Architrave Width: 0.069 m; Dimension | Leaf Thickness: 0.04 m
Type - Door - Door | Type: F - Flush; Door | IsEgress: no; Frame | Material: HM
Type - Discipline - Discipline: Architectural
Type - Classification - Uniclass2015: Pr_30_59_23
Material: A_BSUK_Doors
Pset_DoorCommon - FireExit: no
Door Parameters - Dimension | Frame Depth Match Wall: no
Door - Door | Finish: white; Door | Under Cut: 0 m; Glazing: no; Louver: no
Construction Phase - Phase: New Construction
Name | In | Description | OverallHeight (m) | OverallWidth (m) | ID | Number | ID | Description | ID | Notes | Dimension | Leaf Width (m) | ID | Name (Alternate) | Dimension | Height (m)
0.16 | 0 | WC :1,SHE-01.GROUND.dgn ,Design Model:153928 | 2.127 | 0.888 | 0.16 | WC | common parts | 0.75
4.27 | 26 | bedroom :7 ,SHE-06.FOURTH.dgn,Design Model:106404 | 2.169 | 1.038 | 4.27 | bedroom | residential | 0.9 | Flat 26 | 2.1 | Pset_DoorCommon - FireRating: FD30; Fire Resistance - Fire | Rating: FD30
4.19 | 25 | bathroom :7 ,SHE-06.FOURTH.dgn,Design Model:108984 | 2.169 | 0.888 | 4.19 | bathroom | residential | 0.75 | Flat 25 | 2.1
4.20 | 25 | bedroom :7 ,SHE-06.FOURTH.dgn,Design Model:109242 | 2.169 | 1.038 | 4.20 | bedroom | residential | 0.9 | Flat 25 | 2.1 | Pset_DoorCommon - FireRating: FD30; Fire Resistance - Fire | Rating: FD30
4.22 | 25 | bedroom :7 ,SHE-06.FOURTH.dgn,Design Model:109758 | 2.169 | 1.038 | 4.22 | bedroom | residential | 0.9 | Flat 25 | 2.1 | Pset_DoorCommon - FireRating: FD30; Fire Resistance - Fire | Rating: FD30
4.24 | 25 | storage :7 ,SHE-06.FOURTH.dgn,Design Model:110274 | 2.169 | 0.888 | 4.24 | storage | residential | 0.75 | Flat 25 | 2.1
4.13 | 24 | ensuite :7 ,SHE-06.FOURTH.dgn,Design Model:110532 | 2.169 | 0.888 | 4.13 | ensuite | residential | 0.75 | Flat 24 | 2.1
4.16 | 24 | bedroom :7 ,SHE-06.FOURTH.dgn,Design Model:111564 | 2.169 | 1.038 | 4.16 | bedroom | residential | 0.9 | Flat 24 | 2.1 | Pset_DoorCommon - FireRating: FD30; Fire Resistance - Fire | Rating: FD30
4.09 | 23 | ensuite :7 ,SHE-06.FOURTH.dgn,Design Model:261310 | 2.142 | 0.834 | 4.09 | ensuite | residential | 0.75 | Flat 23 | 2.1

# IfcDoor: A-Doors-SingleFlush (21)
Type - OperationType: SINGLE_SWING_LEFT; ConstructionType: USERDEFINED; ParameterTakesPrecedence: no; Sizeable: no
Type - Lining - LiningDepth: 0.095 m; LiningThickness: 0.069 m
Type - Thermal Transmittance - Is External: no; Is Below Grade: no
Type - Fire Resistance - Fire | IsCombustible: no; Fire | Compartmentation: no
Type - Door Parameters - Parametric | File Type: PAZ; Parametric | File Name: DoorSingleFlush; Dimension | Leaf Width: 0.826 m; Dimension | Height: 2.058 m; Dimension | Frame Depth: 0.095 m; Dimension | Frame Depth Match Wall: yes; Dimension | Architrave Width: 0.069 m; Dimension | Leaf Thickness: 0.04 m
Type - Door - Door | Type: F - Flush; Door | IsEgress: no; Frame | Material: HM
Type - Discipline - Discipline: Architectural
Type - Classification - Uniclass2015: Pr_30_59_23
Material: A_BSUK_Doors
Pset_DoorCommon - FireExit: no
Identification - ID | Notes: residential
Door Parameters - Dimension | Height: 2.1 m; Dimension | Frame Depth Match Wall: no
Door - Door | Finish: white; Door | Under Cut: 0 m; Glazing: no; Louver: no
Construction Phase - Phase: New Construction
Name | In | Description | OverallHeight (m) | OverallWidth (m) | ID | Number | ID | Name (Alternate) | ID | Description | Dimension | Leaf Width (m)
1.18 | 06 | bathroom :4 ,SHE-03.FIRST.dgn,Design Model:136605 | 2.169 | 0.888 | 1.18 | Flat 06 | bathroom | 0.75
1.07 | 02 | bedroom :4 ,SHE-03.FIRST.dgn,Design Model:137379 | 2.169 | 1.038 | 1.07 | Flat 02 | bedroom | 0.9
1.14 | 04 | bedroom :4 ,SHE-03.FIRST.dgn,Design Model:138411 | 2.157 | 1.56178 | 1.14 | Flat 04 | bedroom | 0.9
1.15 | 05 | bathroom :4 ,SHE-03.FIRST.dgn,Design Model:142280 | 2.169 | 0.888 | 1.15 | Flat 05 | bathroom | 0.75
1.21 | 07 | bedroom :4 ,SHE-03.FIRST.dgn,Design Model:222420 | 2.142 | 0.984 | 1.21 | Flat 07 | bedroom | 0.9
1.05 | 02 | ensuite :4 ,SHE-03.FIRST.dgn,Design Model:227303 | 2.142 | 0.834 | 1.05 | Flat 02 | ensuite | 0.75
1.19 | 06 | bedroom :4 ,SHE-03.FIRST.dgn,Design Model:224353 | 2.172 | 1.083 | 1.19 | Flat 06 | bedroom | 0.9
3.18 | 20 | bathroom :6 ,SHE-05.THIRD.dgn,Design Model:136605 | 2.169 | 0.888 | 3.18 | Flat 20 | bathroom | 0.75
3.07 | 16 | bedroom :6 ,SHE-05.THIRD.dgn,Design Model:137379 | 2.169 | 1.038 | 3.07 | Flat 16 | bedroom | 0.9
3.14 | 18 | bedroom :6 ,SHE-05.THIRD.dgn,Design Model:138411 | 2.157 | 1.56178 | 3.14 | Flat 18 | bedroom | 0.9
3.15 | 19 | bathroom :6 ,SHE-05.THIRD.dgn,Design Model:142280 | 2.169 | 0.888 | 3.15 | Flat 19 | bathroom | 0.75
3.21 | 21 | bedroom :6 ,SHE-05.THIRD.dgn,Design Model:222420 | 2.142 | 0.984 | 3.21 | Flat 21 | bedroom | 0.9
3.05 | 16 | ensuite :6 ,SHE-05.THIRD.dgn,Design Model:227303 | 2.142 | 0.834 | 3.05 | Flat 16 | ensuite | 0.75
3.19 | 20 | bedroom :6 ,SHE-05.THIRD.dgn,Design Model:224353 | 2.172 | 1.083 | 3.19 | Flat 20 | bedroom | 0.9
2.18 | 13 | bathroom :18 ,SHE-04.SECOND.dgn,Design Model:136605 | 2.169 | 0.888 | 2.18 | Flat 13 | bathroom | 0.75
2.07 | 09 | bedroom :18 ,SHE-04.SECOND.dgn,Design Model:137379 | 2.169 | 1.038 | 2.07 | Flat 09 | bedroom | 0.9
2.14 | 11 | bedroom :18 ,SHE-04.SECOND.dgn,Design Model:138411 | 2.157 | 1.56178 | 2.14 | Flat 11 | bedroom | 0.9
2.15 | 12 | bathroom :18 ,SHE-04.SECOND.dgn,Design Model:142280 | 2.169 | 0.888 | 2.15 | Flat 12 | bathroom | 0.75
2.21 | 14 | bedroom :18 ,SHE-04.SECOND.dgn,Design Model:222420 | 2.142 | 0.984 | 2.21 | Flat 14 | bedroom | 0.9
2.05 | 09 | ensuite :18 ,SHE-04.SECOND.dgn,Design Model:227303 | 2.142 | 0.834 | 2.05 | Flat 09 | ensuite | 0.75
2.19 | 13 | bedroom :18 ,SHE-04.SECOND.dgn,Design Model:224353 | 2.172 | 1.083 | 2.19 | Flat 13 | bedroom | 0.9

# IfcDoor: A-Doors-SingleFlush, 0.20
In: ENTRANCE
Type - OperationType: SINGLE_SWING_LEFT; ConstructionType: USERDEFINED; ParameterTakesPrecedence: no; Sizeable: no
Type - Lining - LiningDepth: 0.118 m; LiningThickness: 0.069 m
Type - Thermal Transmittance - Is External: no; Is Below Grade: no
Type - Fire Resistance - Fire | IsCombustible: no; Fire | Compartmentation: no
Type - Door Parameters - Parametric | File Type: PAZ; Parametric | File Name: DoorSingleFlush; Dimension | Leaf Width: 0.826 m; Dimension | Height: 2.058 m; Dimension | Frame Depth: 0.118 m; Dimension | Frame Depth Match Wall: yes; Dimension | Architrave Width: 0.069 m; Dimension | Leaf Thickness: 0.04 m
Type - Door - Door | Type: F - Flush; Door | IsEgress: no; Frame | Material: HM
Type - Discipline - Discipline: Architectural
Type - Classification - Uniclass2015: Pr_30_59_23
Description: WC :2 ,SHE-02.MEZZANINE.dgn,Design Model:94311; OverallHeight: 2.1 m; OverallWidth: 0.734 m; Material: A_BSUK_Doors
Pset_DoorCommon - FireExit: no
Identification - ID | Number: 0.20; ID | Description: WC; ID | Notes: common parts
Door Parameters - Dimension | Leaf Width: 0.65 m
Door - Door | Finish: white; Door | Under Cut: 0 m; Glazing: no; Louver: no
Construction Phase - Phase: New Construction

# IfcDoor: A-Doors-SingleFlush (2)
Type - OperationType: SINGLE_SWING_LEFT; ConstructionType: USERDEFINED; ParameterTakesPrecedence: no; Sizeable: no
Type - Lining - LiningDepth: 0.2 m; LiningThickness: 0.069 m
Type - Thermal Transmittance - Is External: no; Is Below Grade: no
Type - Fire Resistance - Fire | IsCombustible: no; Fire | Compartmentation: no
Type - Door Parameters - Parametric | File Type: PAZ; Parametric | File Name: DoorSingleFlush; Dimension | Leaf Width: 0.826 m; Dimension | Height: 2.058 m; Dimension | Frame Depth: 0.2 m; Dimension | Frame Depth Match Wall: yes; Dimension | Architrave Width: 0.069 m; Dimension | Leaf Thickness: 0.04 m
Type - Door - Door | Type: F - Flush; Door | IsEgress: no; Frame | Material: HM
Type - Discipline - Discipline: Architectural
Type - Classification - Uniclass2015: Pr_30_59_23
OverallHeight: 2.169 m; OverallWidth: 1.138 m; Material: A_BSUK_Doors
Pset_DoorCommon - FireExit: no; FireRating: FD30S
Identification - ID | Description: flat entrance; ID | Keynote: 25kg/m2 + seal; ID | Notes: residential entrance
Fire Resistance - Fire | Rating: FD30S
Door Parameters - Dimension | Leaf Width: 1 m; Dimension | Height: 2.1 m; Dimension | Frame Depth Match Wall: no
Door - Door | Finish: french oak veneer; Door | Under Cut: 0 m; Glazing: no; Louver: no
Construction Phase - Phase: New Construction
Name | In | Description | ID | Number | ID | Name (Alternate)
4.07 | 23 | flat entrance :7 ,SHE-06.FOURTH.dgn,Design Model:104542 | 4.07 | Flat 23
4.12 | corridor (protected) | flat entrance :7 ,SHE-06.FOURTH.dgn,Design Model:104800 | 4.12 | Flat 24

# IfcDoor: A-Doors-SingleFlush (12)
Type - OperationType: SINGLE_SWING_LEFT; ConstructionType: USERDEFINED; ParameterTakesPrecedence: no; Sizeable: no
Type - Lining - LiningDepth: 0.225 m; LiningThickness: 0.069 m
Type - Thermal Transmittance - Is External: no; Is Below Grade: no
Type - Fire Resistance - Fire | IsCombustible: no; Fire | Compartmentation: no
Type - Door Parameters - Parametric | File Type: PAZ; Parametric | File Name: DoorSingleFlush; Dimension | Leaf Width: 0.826 m; Dimension | Height: 2.058 m; Dimension | Frame Depth: 0.225 m; Dimension | Frame Depth Match Wall: yes; Dimension | Architrave Width: 0.069 m; Dimension | Leaf Thickness: 0.04 m
Type - Door - Door | Type: F - Flush; Door | IsEgress: no; Frame | Material: HM
Type - Discipline - Discipline: Architectural
Type - Classification - Uniclass2015: Pr_30_59_23
Material: A_BSUK_Doors
Pset_DoorCommon - FireExit: no; FireRating: FD30S
Identification - ID | Description: flat entrance; ID | Keynote: 25kg/m2 + seal; ID | Notes: residential entrance
Fire Resistance - Fire | Rating: FD30S
Door Parameters - Dimension | Leaf Width: 1 m; Dimension | Height: 2.1 m
Door - Door | Finish: french oak veneer; Door | Under Cut: 0 m; Glazing: no; Louver: no
Construction Phase - Phase: New Construction
Name | In | Description | OverallHeight (m) | OverallWidth (m) | ID | Number | ID | Name (Alternate) | Dimension | Frame Depth Match Wall
1.20 | corridor | flat entrance :4 ,SHE-03.FIRST.dgn,Design Model:132588 | 2.169 | 1.138 | 1.20 | Flat 07
1.17 | 06 | flat entrance :4 ,SHE-03.FIRST.dgn,Design Model:132846 | 2.169 | 1.138 | 1.17 | Flat 06 | no
1.12 | 04 | flat entrance :4 ,SHE-03.FIRST.dgn,Design Model:141364 | 2.169 | 1.138 | 1.12 | Flat 04 | no
1.23 | corridor | flat entrance :4 ,SHE-03.FIRST.dgn,Design Model:169731 | 2.142 | 1.084 | 1.23 | Flat 08 | no
3.20 | 21 | flat entrance :6 ,SHE-05.THIRD.dgn,Design Model:132588 | 2.169 | 1.138 | 3.20 | Flat 21
3.17 | k/d/l | flat entrance :6 ,SHE-05.THIRD.dgn,Design Model:132846 | 2.169 | 1.138 | 3.17 | Flat 20 | no
3.12 | 18 | flat entrance :6 ,SHE-05.THIRD.dgn,Design Model:141364 | 2.169 | 1.138 | 3.12 | Flat 18 | no
3.23 | corridor | flat entrance :6 ,SHE-05.THIRD.dgn,Design Model:169731 | 2.142 | 1.084 | 3.23 | Flat 22 | no
2.20 | corridor | flat entrance :18 ,SHE-04.SECOND.dgn,Design Model:132588 | 2.169 | 1.138 | 2.20 | Flat 14
2.17 | 13 | flat entrance :18 ,SHE-04.SECOND.dgn,Design Model:132846 | 2.169 | 1.138 | 2.17 | Flat 13 | no
2.12 | k/d/l | flat entrance :18 ,SHE-04.SECOND.dgn,Design Model:141364 | 2.169 | 1.138 | 2.12 | Flat 11 | no
2.23 | corridor | flat entrance :18 ,SHE-04.SECOND.dgn,Design Model:169731 | 2.142 | 1.084 | 2.23 | Flat 15 | no

# IfcDoor: A-Doors-SingleFlush, 0.04
In: ENTRANCE
Type - OperationType: SINGLE_SWING_LEFT; ConstructionType: USERDEFINED; ParameterTakesPrecedence: no; Sizeable: no
Type - Lining - LiningDepth: 0.231 m; LiningThickness: 0.069 m
Type - Thermal Transmittance - Is External: no; Is Below Grade: no
Type - Fire Resistance - Fire | IsCombustible: no; Fire | Compartmentation: no
Type - Door Parameters - Parametric | File Type: PAZ; Parametric | File Name: DoorSingleFlush; Dimension | Leaf Width: 0.826 m; Dimension | Height: 2.058 m; Dimension | Frame Depth: 0.231 m; Dimension | Frame Depth Match Wall: yes; Dimension | Architrave Width: 0.069 m; Dimension | Leaf Thickness: 0.04 m
Type - Door - Door | Type: F - Flush; Door | IsEgress: no; Frame | Material: HM
Type - Discipline - Discipline: Architectural
Type - Classification - Uniclass2015: Pr_30_59_23
Description: entrance - carpark :1 ,SHE-01.GROUND.dgn,Design Model:101400; OverallHeight: 2.142 m; OverallWidth: 1.084 m; Material: A_BSUK_Doors
Pset_DoorCommon - FireExit: no
Identification - ID | Number: 0.04; ID | Description: entrance - carpark; ID | Keynote: security - Part Q / PAS24 compliance; ID | Notes: external
Door Parameters - Dimension | Leaf Width: 1 m; Dimension | Height: 2.1 m
Door - Door | Finish: RAL 9017 - traffic black matt textured; Door | Under Cut: 0 m; Glazing: no; Louver: no
Construction Phase - Phase: New Construction

# IfcDoor: A-Doors-SingleFlush, 0.08
In: 01
Type - OperationType: SINGLE_SWING_LEFT; ConstructionType: USERDEFINED; ParameterTakesPrecedence: no; Sizeable: no
Type - Lining - LiningDepth: 0.36 m; LiningThickness: 0.069 m
Type - Thermal Transmittance - Is External: no; Is Below Grade: no
Type - Fire Resistance - Fire | IsCombustible: no; Fire | Compartmentation: no
Type - Door Parameters - Parametric | File Type: PAZ; Parametric | File Name: DoorSingleFlush; Dimension | Leaf Width: 0.826 m; Dimension | Height: 2.058 m; Dimension | Frame Depth: 0.36 m; Dimension | Frame Depth Match Wall: yes; Dimension | Architrave Width: 0.069 m; Dimension | Leaf Thickness: 0.04 m
Type - Door - Door | Type: F - Flush; Door | IsEgress: no; Frame | Material: HM
Type - Discipline - Discipline: Architectural
Type - Classification - Uniclass2015: Pr_30_59_23
Description: entrance - mews house :1 ,SHE-01.GROUND.dgn,Design Model:98838; OverallHeight: 2.142 m; OverallWidth: 0.909 m; Material: A_BSUK_Doors
Pset_DoorCommon - FireExit: no
Identification - ID | Number: 0.08; ID | Name (Alternate): Flat 01; ID | Description: entrance - mews house; ID | Keynote: security - Part Q / PAS24 compliance; ID | Notes: external
Door Parameters - Dimension | Leaf Width: 0.825 m; Dimension | Height: 2.1 m
Door - Door | Finish: RAL 9017 - traffic black matt textured; Door | Under Cut: 0 m; Glazing: no; Louver: no
Construction Phase - Phase: New Construction

# IfcDoor: A-Doors-SingleFlush (18)
Type - OperationType: SINGLE_SWING_RIGHT; ConstructionType: USERDEFINED; ParameterTakesPrecedence: no; Sizeable: no
Type - Lining - LiningDepth: 0.08 m; LiningThickness: 0.069 m
Type - Thermal Transmittance - Is External: no; Is Below Grade: no
Type - Fire Resistance - Fire | IsCombustible: no; Fire | Compartmentation: no
Type - Door Parameters - Parametric | File Type: PAZ; Parametric | File Name: DoorSingleFlush; Dimension | Leaf Width: 0.826 m; Dimension | Height: 2.058 m; Dimension | Frame Depth: 0.08 m; Dimension | Frame Depth Match Wall: yes; Dimension | Architrave Width: 0.069 m; Dimension | Leaf Thickness: 0.04 m
Type - Door - Door | Type: F - Flush; Door | IsEgress: no; Frame | Material: HM
Type - Discipline - Discipline: Architectural
Type - Classification - Uniclass2015: Pr_30_59_23
Material: A_BSUK_Doors
Pset_DoorCommon - FireExit: no
Door - Door | Finish: white; Door | Under Cut: 0 m; Glazing: no; Louver: no
Construction Phase - Phase: New Construction
Name | In | Description | OverallHeight (m) | OverallWidth (m) | ID | Number | ID | Name (Alternate) | ID | Description | ID | Notes | Dimension | Leaf Width (m) | Dimension | Frame Depth Match Wall | Dimension | Height (m)
0.11 | 01 | bathroom :1 ,SHE-01.GROUND.dgn,Design Model:103097 | 2.127 | 1.038 | 0.11 | Flat 01 | bathroom | residential | 0.9 | no
0.12 | 01 | bedroom :1 ,SHE-01.GROUND.dgn,Design Model:132007 | 2.127 | 1.038 | 0.12 | Flat 01 | bedroom | residential | 0.9 | no
0.15 | 0 | WC (disabl.) :1 ,SHE-01.GROUND.dgn,Design Model:153321 | 2.127 | 1.138 | 0.15 |  | WC (disabl.) | common parts | 1
0.22 | 01 | bedroom :2 ,SHE-02.MEZZANINE.dgn,Design Model:143206 | 2.1 | 0.984 | 0.22 | Flat 01 | bedroom | residential | 0.9
4.11 | 24 | storage :7 ,SHE-06.FOURTH.dgn,Design Model:96561 | 2.169 | 0.888 | 4.11 | Flat 24 | storage | residential | 0.75 | no | 2.1
4.29 | 26 | bedroom :7 ,SHE-06.FOURTH.dgn,Design Model:106920 | 2.169 | 1.038 | 4.29 | Flat 26 | bedroom | residential | 0.9 | no | 2.1 | Pset_DoorCommon - FireRating: FD30; Fire Resistance - Fire | Rating: FD30
4.30 | 26 | bedroom :7 ,SHE-06.FOURTH.dgn,Design Model:107178 | 2.169 | 1.038 | 4.30 | Flat 26 | bedroom | residential | 0.9 | no | 2.1 | Pset_DoorCommon - FireRating: FD30; Fire Resistance - Fire | Rating: FD30
4.05 | 23 | bathroom :7 ,SHE-06.FOURTH.dgn,Design Model:107436 | 2.169 | 0.888 | 4.05 | Flat 23 | bathroom | residential | 0.75 | no | 2.1
4.06 | 23 | bedroom :7 ,SHE-06.FOURTH.dgn,Design Model:107694 | 2.169 | 1.038 | 4.06 | Flat 23 | bedroom | residential | 0.9 | no | 2.1 | Pset_DoorCommon - FireRating: FD30; Fire Resistance - Fire | Rating: FD30
4.08 | 23 | bedroom :7 ,SHE-06.FOURTH.dgn,Design Model:108210 | 2.169 | 1.038 | 4.08 | Flat 23 | bedroom | residential | 0.9 | no | 2.1 | Pset_DoorCommon - FireRating: FD30; Fire Resistance - Fire | Rating: FD30
4.10 | 23 | bedroom :7 ,SHE-06.FOURTH.dgn,Design Model:108726 | 2.169 | 1.038 | 4.10 | Flat 23 | bedroom | residential | 0.9 | no | 2.1 | Pset_DoorCommon - FireRating: FD30; Fire Resistance - Fire | Rating: FD30
4.21 | 25 | bedroom :7 ,SHE-06.FOURTH.dgn,Design Model:109500 | 2.142 | 0.984 | 4.21 | Flat 25 | bedroom | residential | 0.9 | no | 2.1 | Pset_DoorCommon - FireRating: FD30; Fire Resistance - Fire | Rating: FD30
4.23 | 25 | ensuite :7 ,SHE-06.FOURTH.dgn,Design Model:110016 | 2.169 | 0.888 | 4.23 | Flat 25 | ensuite | residential | 0.75 | no | 2.1
4.14 | 24 | bedroom :7 ,SHE-06.FOURTH.dgn,Design Model:111048 | 2.169 | 1.038 | 4.14 | Flat 24 | bedroom | residential | 0.9 | no | 2.1 | Pset_DoorCommon - FireRating: FD30; Fire Resistance - Fire | Rating: FD30
4.15 | 24 | bedroom :7 ,SHE-06.FOURTH.dgn,Design Model:111306 | 2.169 | 1.038 | 4.15 | Flat 24 | bedroom | residential | 0.9 | no | 2.1 | Pset_DoorCommon - FireRating: FD30; Fire Resistance - Fire | Rating: FD30
4.17 | 24 | bathroom :7 ,SHE-06.FOURTH.dgn,Design Model:111822 | 2.169 | 0.888 | 4.17 | Flat 24 | bathroom | residential | 0.75 | no | 2.1
4.31 | 26 | ensuite :7 ,SHE-06.FOURTH.dgn,Design Model:112080 | 2.142 | 0.734 | 4.31 | Flat 26 | ensuite | residential | 0.65 | no | 2.1
4.26 | 26 | bathroom :7 ,SHE-06.FOURTH.dgn,Design Model:326372 | 2.142 | 0.834 | 4.26 | Flat 26 | bathroom | residential | 0.75 | no | 2.1

# IfcDoor: A-Doors-SingleFlush (24)
Type - OperationType: SINGLE_SWING_RIGHT; ConstructionType: USERDEFINED; ParameterTakesPrecedence: no; Sizeable: no
Type - Lining - LiningDepth: 0.095 m; LiningThickness: 0.069 m
Type - Thermal Transmittance - Is External: no; Is Below Grade: no
Type - Fire Resistance - Fire | IsCombustible: no; Fire | Compartmentation: no
Type - Door Parameters - Parametric | File Type: PAZ; Parametric | File Name: DoorSingleFlush; Dimension | Leaf Width: 0.826 m; Dimension | Height: 2.058 m; Dimension | Frame Depth: 0.095 m; Dimension | Frame Depth Match Wall: yes; Dimension | Architrave Width: 0.069 m; Dimension | Leaf Thickness: 0.04 m
Type - Door - Door | Type: F - Flush; Door | IsEgress: no; Frame | Material: HM
Type - Discipline - Discipline: Architectural
Type - Classification - Uniclass2015: Pr_30_59_23
Material: A_BSUK_Doors
Pset_DoorCommon - FireExit: no
Identification - ID | Notes: residential
Door Parameters - Dimension | Height: 2.1 m; Dimension | Frame Depth Match Wall: no
Door - Door | Finish: white; Door | Under Cut: 0 m; Glazing: no; Louver: no
Construction Phase - Phase: New Construction
Name | In | Description | OverallHeight (m) | OverallWidth (m) | ID | Number | ID | Name (Alternate) | ID | Description | Dimension | Leaf Width (m)
1.06 | 02 | bedroom :4 ,SHE-03.FIRST.dgn,Design Model:137121 | 2.169 | 1.038 | 1.06 | Flat 02 | bedroom | 0.9
1.16 | 05 | bedroom :4 ,SHE-03.FIRST.dgn,Design Model:138669 | 2.157 | 1.56178 | 1.16 | Flat 05 | bedroom | 0.9
1.11 | 03 | bathroom :4 ,SHE-03.FIRST.dgn,Design Model:142544 | 2.169 | 0.888 | 1.11 | Flat 03 | bathroom | 0.75
1.13 | 04 | bathroom :4 ,SHE-03.FIRST.dgn,Design Model:136863 | 2.169 | 0.888 | 1.13 | Flat 04 | bathroom | 0.75
1.24 | 08 | storage :4 ,SHE-03.FIRST.dgn,Design Model:172500 | 2.142 | 0.834 | 1.24 | Flat 08 | storage | 0.75
1.26 | 08 | bathroom :4 ,SHE-03.FIRST.dgn,Design Model:172809 | 2.142 | 0.834 | 1.26 | Flat 08 | bathroom | 0.75
1.25 | 08 | bedroom :4 ,SHE-03.FIRST.dgn,Design Model:176072 | 2.142 | 1.12712 | 1.25 | Flat 08 | bedroom | 0.9
1.22 | 07 | bathroom :4 ,SHE-03.FIRST.dgn,Design Model:241330 | 2.169 | 0.888 | 1.22 | Flat 07 | bathroom | 0.75
3.06 | 16 | bedroom :6 ,SHE-05.THIRD.dgn,Design Model:137121 | 2.169 | 1.038 | 3.06 | Flat 16 | bedroom | 0.9
3.16 | 19 | bedroom :6 ,SHE-05.THIRD.dgn,Design Model:138669 | 2.157 | 1.56178 | 3.16 | Flat 19 | bedroom | 0.9
3.11 | 17 | bathroom :6 ,SHE-05.THIRD.dgn,Design Model:142544 | 2.169 | 0.888 | 3.11 | Flat 17 | bathroom | 0.75
3.13 | 18 | bathroom :6 ,SHE-05.THIRD.dgn,Design Model:136863 | 2.169 | 0.888 | 3.13 | Flat 18 | bathroom | 0.75
3.24 | 22 | storage :6 ,SHE-05.THIRD.dgn,Design Model:172500 | 2.142 | 0.834 | 3.24 | Flat 22 | storage | 0.75
3.26 | 22 | bathroom :6 ,SHE-05.THIRD.dgn,Design Model:172809 | 2.142 | 0.834 | 3.26 | Flat 22 | bathroom | 0.75
3.25 | 22 | bedroom :6 ,SHE-05.THIRD.dgn,Design Model:176072 | 2.142 | 1.12712 | 3.25 | Flat 22 | bedroom | 0.9
3.22 | 21 | bathroom :6 ,SHE-05.THIRD.dgn,Design Model:241330 | 2.169 | 0.888 | 3.22 | Flat 21 | bathroom | 0.75
2.06 | 09 | bedroom :18 ,SHE-04.SECOND.dgn,Design Model:137121 | 2.169 | 1.038 | 2.06 | Flat 09 | bedroom | 0.9
2.16 | 12 | bedroom :18 ,SHE-04.SECOND.dgn,Design Model:138669 | 2.157 | 1.56178 | 2.16 | Flat 12 | bedroom | 0.9
2.11 | 10 | bathroom :18 ,SHE-04.SECOND.dgn,Design Model:142544 | 2.169 | 0.888 | 2.11 | Flat 10 | bathroom | 0.75
2.13 | 11 | bathroom :18 ,SHE-04.SECOND.dgn,Design Model:136863 | 2.169 | 0.888 | 2.13 | Flat 11 | bathroom | 0.75
2.24 | 15 | storage :18 ,SHE-04.SECOND.dgn,Design Model:172500 | 2.142 | 0.834 | 2.24 | Flat 15 | storage | 0.75
2.26 | 15 | bathroom :18 ,SHE-04.SECOND.dgn,Design Model:172809 | 2.142 | 0.834 | 2.26 | Flat 15 | bathroom | 0.75
2.25 | 15 | bedroom :18 ,SHE-04.SECOND.dgn,Design Model:176072 | 2.142 | 1.12712 | 2.25 | Flat 15 | bedroom | 0.9
2.22 | 14 | bathroom :18 ,SHE-04.SECOND.dgn,Design Model:241330 | 2.169 | 0.888 | 2.22 | Flat 14 | bathroom | 0.75

# IfcDoor: A-Doors-SingleFlush, 0.19
In: ENTRANCE
Type - OperationType: SINGLE_SWING_RIGHT; ConstructionType: USERDEFINED; ParameterTakesPrecedence: no; Sizeable: no
Type - Lining - LiningDepth: 0.118 m; LiningThickness: 0.069 m
Type - Thermal Transmittance - Is External: no; Is Below Grade: no
Type - Fire Resistance - Fire | IsCombustible: no; Fire | Compartmentation: no
Type - Door Parameters - Parametric | File Type: PAZ; Parametric | File Name: DoorSingleFlush; Dimension | Leaf Width: 0.826 m; Dimension | Height: 2.058 m; Dimension | Frame Depth: 0.118 m; Dimension | Frame Depth Match Wall: yes; Dimension | Architrave Width: 0.069 m; Dimension | Leaf Thickness: 0.04 m
Type - Door - Door | Type: F - Flush; Door | IsEgress: no; Frame | Material: HM
Type - Discipline - Discipline: Architectural
Type - Classification - Uniclass2015: Pr_30_59_23
Description: WC :2 ,SHE-02.MEZZANINE.dgn,Design Model:94569; OverallHeight: 2.1 m; OverallWidth: 0.734 m; Material: A_BSUK_Doors
Pset_DoorCommon - FireExit: no
Identification - ID | Number: 0.19; ID | Description: WC; ID | Notes: common parts
Door Parameters - Dimension | Leaf Width: 0.65 m
Door - Door | Finish: white; Door | Under Cut: 0 m; Glazing: no; Louver: no
Construction Phase - Phase: New Construction

# IfcDoor: A-Doors-SingleFlush, 0.21
In: 01
Type - OperationType: SINGLE_SWING_RIGHT; ConstructionType: USERDEFINED; ParameterTakesPrecedence: no; Sizeable: no
Type - Lining - LiningDepth: 0.12 m; LiningThickness: 0.069 m
Type - Thermal Transmittance - Is External: no; Is Below Grade: no
Type - Fire Resistance - Fire | IsCombustible: no; Fire | Compartmentation: no
Type - Door Parameters - Parametric | File Type: PAZ; Parametric | File Name: DoorSingleFlush; Dimension | Leaf Width: 0.826 m; Dimension | Height: 2.058 m; Dimension | Frame Depth: 0.12 m; Dimension | Frame Depth Match Wall: yes; Dimension | Architrave Width: 0.069 m; Dimension | Leaf Thickness: 0.04 m
Type - Door - Door | Type: F - Flush; Door | IsEgress: no; Frame | Material: HM
Type - Discipline - Discipline: Architectural
Type - Classification - Uniclass2015: Pr_30_59_23
Description: bathroom :2 ,SHE-02.MEZZANINE.dgn,Design Model:96528; OverallHeight: 2.127 m; OverallWidth: 0.868 m; Material: A_BSUK_Doors
Pset_DoorCommon - FireExit: no
Identification - ID | Number: 0.21; ID | Name (Alternate): Flat 01; ID | Description: bathroom; ID | Notes: residential
Door Parameters - Dimension | Leaf Width: 0.73 m
Door - Door | Finish: white; Door | Under Cut: 0 m; Glazing: no; Louver: no
Construction Phase - Phase: New Construction

# IfcDoor: A-Doors-SingleFlush (2)
In: 01
Type - OperationType: SINGLE_SWING_RIGHT; ConstructionType: USERDEFINED; ParameterTakesPrecedence: no; Sizeable: no
Type - Lining - LiningDepth: 0.131 m; LiningThickness: 0.069 m
Type - Thermal Transmittance - Is External: no; Is Below Grade: no
Type - Fire Resistance - Fire | IsCombustible: no; Fire | Compartmentation: no
Type - Door Parameters - Parametric | File Type: PAZ; Parametric | File Name: DoorSingleFlush; Dimension | Leaf Width: 0.826 m; Dimension | Height: 2.058 m; Dimension | Frame Depth: 0.131 m; Dimension | Frame Depth Match Wall: yes; Dimension | Architrave Width: 0.069 m; Dimension | Leaf Thickness: 0.04 m
Type - Door - Door | Type: F - Flush; Door | IsEgress: no; Frame | Material: HM
Type - Discipline - Discipline: Architectural
Type - Classification - Uniclass2015: Pr_30_59_23
OverallHeight: 2.1 m; Material: A_BSUK_Doors
Pset_DoorCommon - FireExit: no
Identification - ID | Name (Alternate): Flat 01; ID | Notes: residential
Door - Door | Finish: white; Door | Under Cut: 0 m; Glazing: no; Louver: no
Construction Phase - Phase: New Construction
Name | Description | OverallWidth (m) | ID | Number | ID | Description | Dimension | Leaf Width (m)
0.09 | stair :1 ,SHE-01.GROUND.dgn,Design Model:102581 | 0.984 | 0.09 | stair | 0.9
0.10 | storage :1 ,SHE-01.GROUND.dgn,Design Model:102839 | 0.834 | 0.10 | storage | 0.75

# IfcDoor: A-Doors-SingleFlush (2)
Type - OperationType: SINGLE_SWING_RIGHT; ConstructionType: USERDEFINED; ParameterTakesPrecedence: no; Sizeable: no
Type - Lining - LiningDepth: 0.2 m; LiningThickness: 0.069 m
Type - Thermal Transmittance - Is External: no; Is Below Grade: no
Type - Fire Resistance - Fire | IsCombustible: no; Fire | Compartmentation: no
Type - Door Parameters - Parametric | File Type: PAZ; Parametric | File Name: DoorSingleFlush; Dimension | Leaf Width: 0.826 m; Dimension | Height: 2.058 m; Dimension | Frame Depth: 0.2 m; Dimension | Frame Depth Match Wall: yes; Dimension | Architrave Width: 0.069 m; Dimension | Leaf Thickness: 0.04 m
Type - Door - Door | Type: F - Flush; Door | IsEgress: no; Frame | Material: HM
Type - Discipline - Discipline: Architectural
Type - Classification - Uniclass2015: Pr_30_59_23
OverallHeight: 2.142 m; Material: A_BSUK_Doors
Pset_DoorCommon - FireExit: no; FireRating: FD30S
Identification - ID | Description: flat entrance; ID | Keynote: 25kg/m2 + seal; ID | Notes: residential entrance
Fire Resistance - Fire | Rating: FD30S
Door Parameters - Dimension | Leaf Width: 1 m; Dimension | Height: 2.1 m; Dimension | Frame Depth Match Wall: no
Door - Door | Finish: french oak veneer; Door | Under Cut: 0 m; Glazing: no; Louver: no
Construction Phase - Phase: New Construction
Name | In | Description | OverallWidth (m) | ID | Number | ID | Name (Alternate)
4.18 | corridor (protected) | flat entrance :7 ,SHE-06.FOURTH.dgn,Design Model:104284 | 1.134 | 4.18 | Flat 25
4.25 | 26 | flat entrance :7 ,SHE-06.FOURTH.dgn,Design Model:197915 | 1.084 | 4.25 | Flat 26

# IfcDoor: A-Doors-SingleFlush (9)
Type - OperationType: SINGLE_SWING_RIGHT; ConstructionType: USERDEFINED; ParameterTakesPrecedence: no; Sizeable: no
Type - Lining - LiningDepth: 0.225 m; LiningThickness: 0.069 m
Type - Thermal Transmittance - Is External: no; Is Below Grade: no
Type - Fire Resistance - Fire | IsCombustible: no; Fire | Compartmentation: no
Type - Door Parameters - Parametric | File Type: PAZ; Parametric | File Name: DoorSingleFlush; Dimension | Leaf Width: 0.826 m; Dimension | Height: 2.058 m; Dimension | Frame Depth: 0.225 m; Dimension | Frame Depth Match Wall: yes; Dimension | Architrave Width: 0.069 m; Dimension | Leaf Thickness: 0.04 m
Type - Door - Door | Type: F - Flush; Door | IsEgress: no; Frame | Material: HM
Type - Discipline - Discipline: Architectural
Type - Classification - Uniclass2015: Pr_30_59_23
Material: A_BSUK_Doors
Pset_DoorCommon - FireExit: no; FireRating: FD30S
Identification - ID | Description: flat entrance; ID | Keynote: 25kg/m2 + seal; ID | Notes: residential entrance
Fire Resistance - Fire | Rating: FD30S
Door Parameters - Dimension | Leaf Width: 1 m; Dimension | Height: 2.1 m; Dimension | Frame Depth Match Wall: no
Door - Door | Finish: french oak veneer; Door | Under Cut: 0 m; Glazing: no; Louver: no
Construction Phase - Phase: New Construction
Name | In | Description | OverallHeight (m) | OverallWidth (m) | ID | Number | ID | Name (Alternate)
1.10 | 03 | flat entrance :4 ,SHE-03.FIRST.dgn,Design Model:132330 | 2.169 | 1.138 | 1.10 | Flat 03
1.09 | 02 | flat entrance :4 ,SHE-03.FIRST.dgn,Design Model:141106 | 2.172 | 1.087 | 1.09 | Flat 02
1.27 | 05 | flat entrance :4 ,SHE-03.FIRST.dgn,Design Model:141624 | 2.169 | 1.138 | 1.27 | Flat 05
3.10 | studio | flat entrance :6 ,SHE-05.THIRD.dgn,Design Model:132330 | 2.169 | 1.138 | 3.10 | Flat 17
3.09 | 16 | flat entrance :6 ,SHE-05.THIRD.dgn,Design Model:141106 | 2.172 | 1.087 | 3.09 | Flat 16
3.27 | 19 | flat entrance :6 ,SHE-05.THIRD.dgn,Design Model:141624 | 2.169 | 1.138 | 3.27 | Flat 19
2.10 | 10 | flat entrance :18 ,SHE-04.SECOND.dgn,Design Model:132330 | 2.169 | 1.138 | 2.10 | Flat 10
2.09 | 09 | flat entrance :18 ,SHE-04.SECOND.dgn,Design Model:141106 | 2.172 | 1.087 | 2.09 | Flat 09
2.27 | k/d/l | flat entrance :18 ,SHE-04.SECOND.dgn,Design Model:141624 | 2.169 | 1.138 | 2.27 | Flat 12

# IfcDoor: A-Doors-SingleFlush (3)
Type - OperationType: SINGLE_SWING_RIGHT; ConstructionType: USERDEFINED; ParameterTakesPrecedence: no; Sizeable: no
Type - Lining - LiningDepth: 0.25 m; LiningThickness: 0.069 m
Type - Thermal Transmittance - Is External: no; Is Below Grade: no
Type - Fire Resistance - Fire | IsCombustible: no; Fire | Compartmentation: no
Type - Door Parameters - Parametric | File Type: PAZ; Parametric | File Name: DoorSingleFlush; Dimension | Leaf Width: 0.826 m; Dimension | Height: 2.058 m; Dimension | Frame Depth: 0.25 m; Dimension | Frame Depth Match Wall: yes; Dimension | Architrave Width: 0.069 m; Dimension | Leaf Thickness: 0.04 m
Type - Door - Door | Type: F - Flush; Door | IsEgress: no; Frame | Material: HM
Type - Discipline - Discipline: Architectural
Type - Classification - Uniclass2015: Pr_30_59_23
OverallHeight: 2.142 m; OverallWidth: 0.784 m; Material: A_BSUK_Doors
Pset_DoorCommon - FireExit: no
Identification - ID | Description: bathroom; ID | Notes: residential
Door Parameters - Dimension | Leaf Width: 0.7 m; Dimension | Height: 2.1 m
Door - Door | Finish: white; Door | Under Cut: 0 m; Glazing: no; Louver: no
Construction Phase - Phase: New Construction
Name | In | Description | ID | Number | ID | Name (Alternate)
1.08 | 02 | bathroom :4 ,SHE-03.FIRST.dgn,Design Model:427756 | 1.08 | Flat 02 | Door Parameters - Dimension | Frame Depth Match Wall: no
3.08 | 16 | bathroom :6 ,SHE-05.THIRD.dgn,Design Model:140141 | 3.08 | Flat 16
2.08 | 09 | bathroom :18 ,SHE-04.SECOND.dgn,Design Model:140141 | 2.08 | Flat 09

# IfcDoor: A-Doors-SingleVisionPanels, 0.13
In: 0
Type - OperationType: SINGLE_SWING_LEFT; ConstructionType: USERDEFINED; ParameterTakesPrecedence: no; Sizeable: no
Type - Lining - LiningDepth: 0.1 m; LiningThickness: 0.069 m
Type - Thermal Transmittance - Is External: no; Is Below Grade: no
Type - Fire Resistance - Fire | IsCombustible: no; Fire | Compartmentation: no
Type - Door Parameters - Parametric | File Type: PAZ; Parametric | File Name: DoorSingle2Lites; Dimension | Leaf Width: 0.826 m; Dimension | Height: 2.058 m; Dimension | Frame Depth: 0.1 m; Dimension | Frame Depth Match Wall: yes; Dimension | Architrave Width: 0.069 m; Dimension | Leaf Thickness: 0.04 m
Type - Door - Door | Type: 2G - 2 Lite; Door | IsEgress: no; Glazing: yes; Frame | Material: HM
Type - Discipline - Discipline: Architectural
Type - Classification - Uniclass2015: Pr_30_59_23
Description: entrance - commercial unit :1,SHE-01.GROUND.dgn,Design Model:119205; OverallHeight: 2.199 m; OverallWidth: 1.188 m; Material: A_BSUK_Doors
Pset_DoorCommon - FireExit: no
Identification - ID | Number: 0.13; ID | Description: entrance - commercial unit; ID | Keynote: security - Part Q / PAS24 compliance; ID | Notes: external
Door Parameters - Dimension | Leaf Width: 1.05 m; Dimension | Height: 2.13 m
Door - Door | Finish: RAL 9017 - traffic black matt textured; Door | Under Cut: 0 m; Glazing | Notes: glazing; Louver: no
Construction Phase - Phase: New Construction

# IfcDoor: A-Doors-SingleVisionPanels, 4.02
In: hall (vented)
Type - OperationType: SINGLE_SWING_LEFT; ConstructionType: USERDEFINED; ParameterTakesPrecedence: no; Sizeable: no
Type - Lining - LiningDepth: 0.2 m; LiningThickness: 0.069 m
Type - Thermal Transmittance - Is External: no; Is Below Grade: no
Type - Fire Resistance - Fire | IsCombustible: no; Fire | Compartmentation: no
Type - Door Parameters - Parametric | File Type: PAZ; Parametric | File Name: DoorSingle2Lites; Dimension | Leaf Width: 0.826 m; Dimension | Height: 2.058 m; Dimension | Frame Depth: 0.2 m; Dimension | Frame Depth Match Wall: yes; Dimension | Architrave Width: 0.069 m; Dimension | Leaf Thickness: 0.04 m
Type - Door - Door | Type: 2G - 2 Lite; Door | IsEgress: no; Glazing: yes; Frame | Material: HM
Type - Discipline - Discipline: Architectural
Type - Classification - Uniclass2015: Pr_30_59_23
Description: hall with vision panel :7,SHE-06.FOURTH.dgn,Design Model:194839; OverallHeight: 2.169 m; OverallWidth: 1.038 m; Material: A_BSUK_Doors
Pset_DoorCommon - FireExit: no; FireRating: FD30S
Identification - ID | Number: 4.02; ID | Description: hall with vision panel; ID | Keynote: FIRE DOOR KEEP CLOSED; ID | Notes: common parts
Fire Resistance - Fire | Rating: FD30S
Door Parameters - Dimension | Leaf Width: 0.9 m; Dimension | Height: 2.1 m; Dimension | Frame Depth Match Wall: no
Door - Door | Finish: white; Door | Under Cut: 0 m; Glazing | Notes: glazing - fire rated; Louver: no
Construction Phase - Phase: New Construction

# IfcDoor: A-Doors-SingleVisionPanels (3)
In: hall (vented)
Type - OperationType: SINGLE_SWING_LEFT; ConstructionType: USERDEFINED; ParameterTakesPrecedence: no; Sizeable: no
Type - Lining - LiningDepth: 0.25 m; LiningThickness: 0.069 m
Type - Thermal Transmittance - Is External: no; Is Below Grade: no
Type - Fire Resistance - Fire | IsCombustible: no; Fire | Compartmentation: no
Type - Door Parameters - Parametric | File Type: PAZ; Parametric | File Name: DoorSingle2Lites; Dimension | Leaf Width: 0.826 m; Dimension | Height: 2.058 m; Dimension | Frame Depth: 0.25 m; Dimension | Frame Depth Match Wall: yes; Dimension | Architrave Width: 0.069 m; Dimension | Leaf Thickness: 0.04 m
Type - Door - Door | Type: 2G - 2 Lite; Door | IsEgress: no; Glazing: yes; Frame | Material: HM
Type - Discipline - Discipline: Architectural
Type - Classification - Uniclass2015: Pr_30_59_23
OverallHeight: 2.142 m; Material: A_BSUK_Doors
Pset_DoorCommon - FireExit: no; FireRating: FD30S
Identification - ID | Description: hall with vision panel; ID | Keynote: FIRE DOOR KEEP CLOSED; ID | Notes: common parts
Fire Resistance - Fire | Rating: FD30S
Door Parameters - Dimension | Leaf Width: 0.9 m; Dimension | Height: 2.1 m; Dimension | Frame Depth Match Wall: no
Door - Door | Finish: white; Door | Under Cut: 0 m; Glazing | Notes: glazing - fire rated; Louver: no
Construction Phase - Phase: New Construction
Name | Description | OverallWidth (m) | ID | Number
1.02 | hall with vision panel :4,SHE-03.FIRST.dgn,Design Model:140403 | 0.984 | 1.02
3.02 | hall with vision panel :6,SHE-05.THIRD.dgn,Design Model:140403 | 1.00726 | 3.02
2.02 | hall with vision panel :18,SHE-04.SECOND.dgn,Design Model:140403 | 1.00726 | 2.02

# IfcDoor: A-Doors-SingleVisionPanels (5)
Type - OperationType: SINGLE_SWING_RIGHT; ConstructionType: USERDEFINED; ParameterTakesPrecedence: no; Sizeable: no
Type - Lining - LiningDepth: 0.1 m; LiningThickness: 0.069 m
Type - Thermal Transmittance - Is External: no; Is Below Grade: no
Type - Fire Resistance - Fire | IsCombustible: no; Fire | Compartmentation: no
Type - Door Parameters - Parametric | File Type: PAZ; Parametric | File Name: DoorSingle2Lites; Dimension | Leaf Width: 0.826 m; Dimension | Height: 2.058 m; Dimension | Frame Depth: 0.1 m; Dimension | Frame Depth Match Wall: yes; Dimension | Architrave Width: 0.069 m; Dimension | Leaf Thickness: 0.04 m
Type - Door - Door | Type: 2G - 2 Lite; Door | IsEgress: no; Glazing: yes; Frame | Material: HM
Type - Discipline - Discipline: Architectural
Type - Classification - Uniclass2015: Pr_30_59_23
Material: A_BSUK_Doors
Pset_DoorCommon - FireExit: no
Door - Door | Under Cut: 0 m; Louver: no
Construction Phase - Phase: New Construction
Name | In | Description | OverallHeight (m) | OverallWidth (m) | ID | Number | ID | Description | ID | Keynote | ID | Notes | Dimension | Leaf Width (m) | Dimension | Height (m) | Door | Finish | Glazing | Notes | FireRating = Fire | Rating | Dimension | Frame Depth Match Wall
0.14 | 0 | entrance - commercial unit :1,SHE-01.GROUND.dgn,Design Model:122638 | 2.199 | 1.188 | 0.14 | entrance - commercial unit | security - Part Q / PAS24 compliance | external | 1.05 | 2.13 | RAL 9017 - traffic black matt textured | glazing
1.04 | landing | stair with vision panel :4,SHE-03.FIRST.dgn,Design Model:138927 | 2.142 | 0.984 | 1.04 | stair with vision panel | FIRE DOOR KEEP CLOSED | common parts | 0.9 | 2.1 | white | glazing - fire rated | FD60S | no
3.04 | landing | stair with vision panel :6,SHE-05.THIRD.dgn,Design Model:138927 | 2.157 | 0.984 | 3.04 | stair with vision panel | FIRE DOOR KEEP CLOSED | common parts | 0.9 | 2.1 | white | glazing - fire rated | FD60S | no
4.04 | landing | stair with vision panel :7,SHE-06.FOURTH.dgn,Design Model:190650 | 2.157 | 1.05044 | 4.04 | stair with vision panel | FIRE DOOR KEEP CLOSED | common parts | 0.9 | 2.1 | white | glazing - fire rated | FD60S | no
2.04 | landing | stair with vision panel :18,SHE-04.SECOND.dgn,Design Model:138927 | 2.142 | 0.984 | 2.04 | stair with vision panel | FIRE DOOR KEEP CLOSED | common parts | 0.9 | 2.1 | white | glazing - fire rated | FD60S | no

# IfcDoor: A-Doors-SingleVisionPanels (2)
In: hall (vented)
Type - OperationType: SINGLE_SWING_RIGHT; ConstructionType: USERDEFINED; ParameterTakesPrecedence: no; Sizeable: no
Type - Lining - LiningDepth: 0.17 m; LiningThickness: 0.069 m
Type - Thermal Transmittance - Is External: no; Is Below Grade: no
Type - Fire Resistance - Fire | IsCombustible: no; Fire | Compartmentation: no
Type - Door Parameters - Parametric | File Type: PAZ; Parametric | File Name: DoorSingle2Lites; Dimension | Leaf Width: 0.826 m; Dimension | Height: 2.058 m; Dimension | Frame Depth: 0.17 m; Dimension | Frame Depth Match Wall: yes; Dimension | Architrave Width: 0.069 m; Dimension | Leaf Thickness: 0.04 m
Type - Door - Door | Type: 2G - 2 Lite; Door | IsEgress: no; Glazing: yes; Frame | Material: HM
Type - Discipline - Discipline: Architectural
Type - Classification - Uniclass2015: Pr_30_59_23
OverallHeight: 2.169 m; OverallWidth: 1.038 m; Material: A_BSUK_Doors
Pset_DoorCommon - FireExit: no; FireRating: FD30S
Identification - ID | Description: hall with vision panel; ID | Keynote: FIRE DOOR KEEP CLOSED; ID | Notes: common parts
Fire Resistance - Fire | Rating: FD30S
Door Parameters - Dimension | Leaf Width: 0.9 m; Dimension | Height: 2.1 m; Dimension | Frame Depth Match Wall: no
Door - Door | Finish: white; Door | Under Cut: 0 m; Glazing | Notes: glazing - fire rated; Louver: no
Construction Phase - Phase: New Construction
Name | Description | ID | Number
1.01 | hall with vision panel :4,SHE-03.FIRST.dgn,Design Model:139747 | 1.01
4.01 | hall with vision panel :7,SHE-06.FOURTH.dgn,Design Model:191470 | 4.01

# IfcDoor: A-Doors-SingleVisionPanels (2)
In: hall (vented)
Type - OperationType: SINGLE_SWING_RIGHT; ConstructionType: USERDEFINED; ParameterTakesPrecedence: no; Sizeable: no
Type - Lining - LiningDepth: 0.25 m; LiningThickness: 0.069 m
Type - Thermal Transmittance - Is External: no; Is Below Grade: no
Type - Fire Resistance - Fire | IsCombustible: no; Fire | Compartmentation: no
Type - Door Parameters - Parametric | File Type: PAZ; Parametric | File Name: DoorSingle2Lites; Dimension | Leaf Width: 0.826 m; Dimension | Height: 2.058 m; Dimension | Frame Depth: 0.25 m; Dimension | Frame Depth Match Wall: yes; Dimension | Architrave Width: 0.069 m; Dimension | Leaf Thickness: 0.04 m
Type - Door - Door | Type: 2G - 2 Lite; Door | IsEgress: no; Glazing: yes; Frame | Material: HM
Type - Discipline - Discipline: Architectural
Type - Classification - Uniclass2015: Pr_30_59_23
OverallHeight: 2.142 m; OverallWidth: 0.984 m; Material: A_BSUK_Doors
Pset_DoorCommon - FireExit: no; FireRating: FD30S
Identification - ID | Description: hall with vision panel; ID | Keynote: FIRE DOOR KEEP CLOSED; ID | Notes: common parts
Fire Resistance - Fire | Rating: FD30S
Door Parameters - Dimension | Leaf Width: 0.9 m; Dimension | Height: 2.1 m; Dimension | Frame Depth Match Wall: no
Door - Door | Finish: white; Door | Under Cut: 0 m; Glazing | Notes: glazing - fire rated; Louver: no
Construction Phase - Phase: New Construction
Name | Description | ID | Number
3.01 | hall with vision panel :6,SHE-05.THIRD.dgn,Design Model:139747 | 3.01
2.01 | hall with vision panel :18,SHE-04.SECOND.dgn,Design Model:139747 | 2.01

# IfcDoor: A-ElevatorCallButton
In: ENTRANCE
Type - Description: Elevator Call Button; ConstructionType: USERDEFINED; ParameterTakesPrecedence: no; Sizeable: no
Type - Lining - LiningDepth: 0 m; LiningThickness: 0.002 m
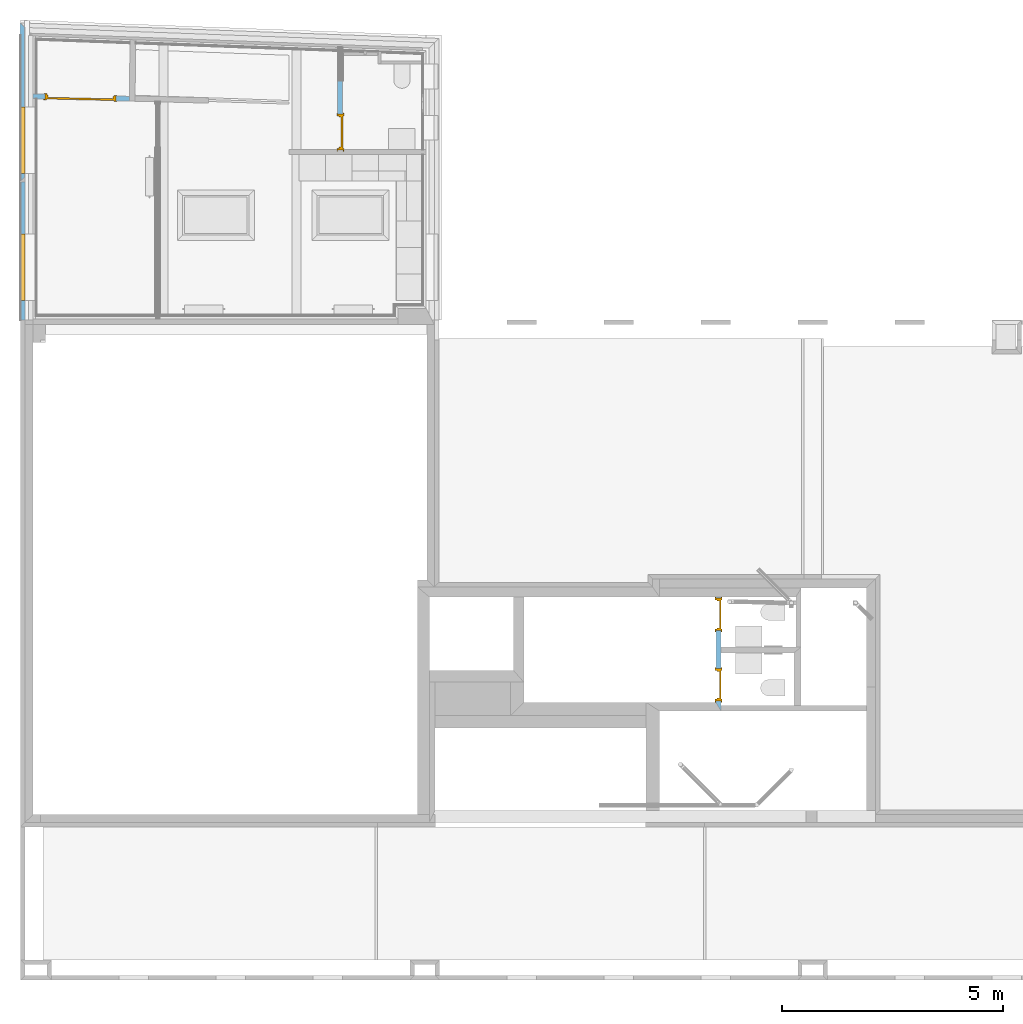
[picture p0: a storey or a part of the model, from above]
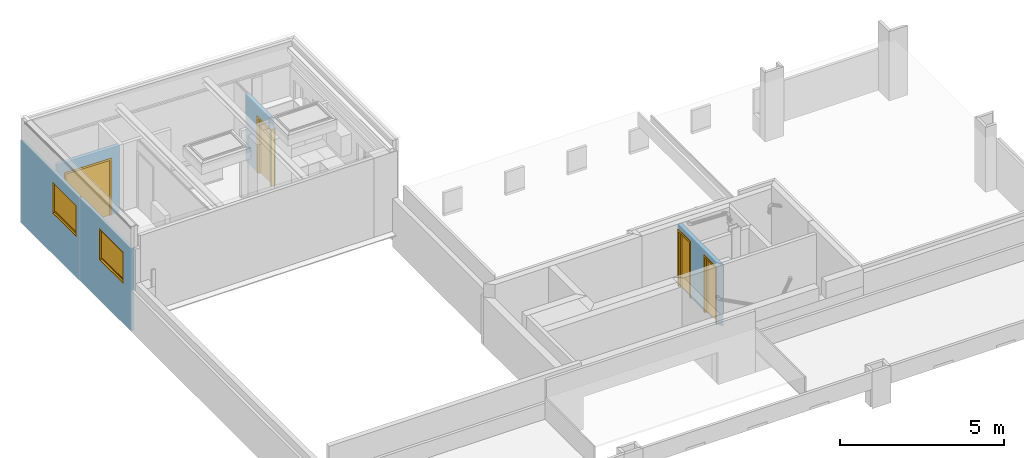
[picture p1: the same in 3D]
Properties of the parts of a building model (IFC2X3), part 7 of 17

# IfcDoor: A-ElevatorCallButton
Type - Parametric Definition - Parametric | File Type: PAZ; Parametric | File Name: Elev_CallButton
Type - Identification - ID | Description: Elevator Call Button
Type - Elevator Door - Frame | Thickness: 0.002 m; Frame | Depth: 0 m
Description: Elevator Call Button :1,SHE-01.GROUND.dgn,Design Model:94580; OverallHeight: 0.2794 m; OverallWidth: 0.127 m; Material: A_BSUK_Doors
Elevator Door - Lift Door | Width: 0 m; Lift Door | Height: 0 m; Frame | Head Thickness: 0 m; Lift Door | Side Offset: 0 m; Frame | Return Thickness: 0 m; Lift Cab | Height: 0 m; Lift Cab | Width: 0 m; Lift Cab | Side Wall Thickness: 0 m; Lift Cab | Depth: 0 m; Lift Cab | Door Thickness: 0 m; Lift Cab | Front Wall Thickness: 0 m; Lift Cab | Inset: 0 m

# IfcDoor: A-ElevatorDoor-2Speed (4)
In: firef. LIFT
Type - Description: 2-Speed Elevator Door; OperationType: USERDEFINED; ConstructionType: USERDEFINED; ParameterTakesPrecedence: no; Sizeable: no
Type - Lining - LiningDepth: 0.125 m; LiningThickness: 0.05 m
Type - Parametric Definition - Parametric | File Type: PAZ; Parametric | File Name: ElevatorDoor_1_2speed_NoCab
Type - Identification - ID | Description: 2-Speed Elevator Door
Type - Elevator Door - Lift Doors | Type: Two-Speed Side Opening; Lift Door | Width: 1.2 m; Lift Door | Height: 2.1 m; Frame | Thickness: 0.05 m; Frame | Head Thickness: 0.1 m; Frame | Return Thickness: 0.012 m; Frame | Depth: 0.125 m; Lift Cab | Width: 2.4 m; Lift Cab | Side Wall Thickness: 0.1 m; Lift Cab | Depth: 1.8 m; Lift Cab | Door Thickness: 0.05 m; Lift Cab | Front Wall Thickness: 0.225 m; Lift Cab | Inset: 0.1 m
Type - Discipline - Discipline: Architectural
Type - Classification - Uniclass2015: Pr_30_59_46_46
Material: A_BSUK_Doors
Elevator Door - Lift Doors | Type: Single-Speed; Lift Door | Width: 1 m; Lift Door | Side Offset: 0 m; Lift Cab | Height: 0 m; Lift Cab | Width: 1.35 m; Lift Cab | Depth: 1.15 m
Name | Description | OverallHeight (m) | OverallWidth (m)
A-ElevatorDoor-2Speed | 2-Speed Elevator Door :4,SHE-03.FIRST.dgn,Design Model:139324 | 2.14 | 1.1333
A-ElevatorDoor-2Speed | 2-Speed Elevator Door :6,SHE-05.THIRD.dgn,Design Model:139324 | 2.14 | 1.1333
A-ElevatorDoor-2Speed | 2-Speed Elevator Door :7,SHE-06.FOURTH.dgn,Design Model:191047 | 2.155 | 1.1333
A-ElevatorDoor-2Speed | 2-Speed Elevator Door :18,SHE-04.SECOND.dgn,Design Model:139324 | 2.14 | 1.09

# IfcDoor: A-ElevatorDoor-2SpeedWithCab
In: UNDERCROFT (back)
Type - Description: 2-Speed Elevator Door; OperationType: USERDEFINED; ConstructionType: USERDEFINED; ParameterTakesPrecedence: no; Sizeable: no
Type - Lining - LiningDepth: 0.125 m; LiningThickness: 0.05 m
Type - Parametric Definition - Parametric | File Type: PAZ; Parametric | File Name: ElevatorDoor_1_2speed
Type - Identification - ID | Description: 2-Speed Elevator Door
Type - Elevator Door - Lift Doors | Type: Two-Speed Side Opening; Lift Door | Width: 1.2 m; Lift Door | Height: 2.1 m; Frame | Thickness: 0.05 m; Frame | Head Thickness: 0.1 m; Lift Door | Side Offset: 0.15 m; Frame | Return Thickness: 0.012 m; Frame | Depth: 0.125 m; Lift Cab | Height: 3 m; Lift Cab | Width: 2.4 m; Lift Cab | Side Wall Thickness: 0.1 m; Lift Cab | Depth: 1.8 m; Lift Cab | Door Thickness: 0.05 m; Lift Cab | Front Wall Thickness: 0.225 m; Lift Cab | Inset: 0.1 m
Type - Discipline - Discipline: Architectural
Type - Classification - Uniclass2015: Pr_30_59_46_46
Description: 2-Speed Elevator Door :1,SHE-01.GROUND.dgn,Design Model:129492; OverallHeight: 2.14 m; OverallWidth: 1.08 m; Material: A_BSUK_Doors
Elevator Door - Lift Door | Width: 1 m; Lift Door | Side Offset: 0 m; Lift Cab | Height: 2.4 m; Lift Cab | Width: 1.35 m; Lift Cab | Depth: 1.15 m

# IfcFlowFitting: A-RainwaterDrainageSystems-GutterCorner (4)
In: 1F
Type - Description: Manufactured Gutter Corner
Type - Roof Specialty - Roof Type: Gutter; Dimension | Length: 0.3 m; Dimension | Width: 0.15 m; Dimension | Height: 0.1 m
Type - Parametric Definition - Parametric | File Type: PAZ; Parametric | File Name: GutterType1_Corner
Type - Identification - ID | Description: Manufactured Gutter Corner
Type - Discipline - Discipline: Architectural
Type - Classification - Uniclass2015: Ss_50_30_02_28
Material: A_BSUK_RainwaterDrainageSystems
Construction Phase - Phase: New Construction
Name | Description
A-RainwaterDrainageSystems-GutterCorner | Manufactured Gutter Corner :7 ,SHE-06.FOURTH.dgn,Design Model:99780
A-RainwaterDrainageSystems-GutterCorner | Manufactured Gutter Corner :7 ,SHE-06.FOURTH.dgn,Design Model:100026
A-RainwaterDrainageSystems-GutterCorner | Manufactured Gutter Corner :7 ,SHE-06.FOURTH.dgn,Design Model:100272
A-RainwaterDrainageSystems-GutterCorner | Manufactured Gutter Corner :7 ,SHE-06.FOURTH.dgn,Design Model:100518

# IfcFlowFitting: A-RainwaterDrainageSystems-GutterStraight (4)
In: 1F
Type - Roof Specialty - Roof Type: Gutter; Dimension | Length: 3 m; Dimension | Width: 0.15 m; Dimension | Height: 0.1 m
Type - Parametric Definition - Parametric | File Type: PAZ; Parametric | File Name: GutterType1_Straight
Type - Discipline - Discipline: Architectural
Type - Classification - Uniclass2015: Ss_50_30_02_28
Material: A_BSUK_RainwaterDrainageSystems
Name | Description | Dimension | Length (m)
A-RainwaterDrainageSystems-GutterStraight | 7,SHE-06.FOURTH.dgn ,Design Model:100170 | 25.951
A-RainwaterDrainageSystems-GutterStraight | 7,SHE-06.FOURTH.dgn ,Design Model:355454 | 13.871
A-RainwaterDrainageSystems-GutterStraight | 7,SHE-06.FOURTH.dgn ,Design Model:385278 | 13.871
A-RainwaterDrainageSystems-GutterStraight | 7,SHE-06.FOURTH.dgn ,Design Model:385380 | 25.951

# IfcFlowFitting: M-BmpElbow-DefaultElbow (62)
Type - PredefinedType: BEND
Type - Plumbing Elbow Parameters - AutoSize: Radius; Inlet | Outer Diameter: 25; Outlet | Outer Diameter: 25; Standard Angle: 90; Bend Angle: 90; Bending Radius: 50; Radius to Diameter Ratio: 1; Connection 1 | Length (L1): 0; Connection 2 | Length (L2): 0; View Display: iso
Type - Parameters - Insulation | Thickness (mm): 0; Correction Factor: 1.0; Wall Thickness: 0
Type - Insulation/Lining Symbology Parameters - Insulation/Lining | Color: 4; Insulation/Lining | Line Weight: 2; Insulation/ Lining | Line Style: 0; Insulation/Lining | Level Name: Level 2
Type - End Spec2_22 (2 Connections: Round | Round) - Diameter 1 (D1 Ø): 50; Diameter 2 (D2 Ø): 50
Type - Classification - Uniclass2015: Pr_65_52_63
Material: M_BSUK_ColdWater
Plumbing Elbow Parameters - Inlet | Outer Diameter: 100; Outlet | Outer Diameter: 100; Connection | End Type: -;-;
Parameters - Insulation | Surface Area: 0 m2; Lining | Thickness (mm): 0; Lining | Surface Area: 0 m2; Status: BSUK; Pressure Class: PN16; Air Flow: M
End Spec2_22 (2 Connections: Round | Round) - Diameter 1 (D1 Ø): 100; Diameter 2 (D2 Ø): 100
Construction Phase - Phase: New Construction
Name | In | Description | AutoSize | Standard Angle = Bend Angle | Bending Radius | Surface Area (m2) | Center Of Gravity | System ID | Group
M-BmpElbow-DefaultElbow | 17 | 11,SHE-15.MEHP.dgn,Design Model:119148 | RadToDia | 89.2838 | 100 | 0.048955 | 71.29; 0.00; -27.81; | SVP7 | SVP
M-BmpElbow-DefaultElbow | 17 | 11,SHE-15.MEHP.dgn,Design Model:119198 | RadToDia | 89.2838 | 100 | 0.048955 | 71.29; 0.00; -27.81; | SVP7 | SVP
M-BmpElbow-DefaultElbow | bath | 11,SHE-15.MEHP.dgn,Design Model:119317 | RadToDia | 89.2838 | 100 | 0.048955 | 71.29; 0.00; -27.81; | SVP7 | SVP
M-BmpElbow-DefaultElbow | 22 | 11,SHE-15.MEHP.dgn,Design Model:119393 | RadToDia | 89.2838 | 100 | 0.048955 | 71.29; 0.00; -27.81; | SVP4 | SVP
M-BmpElbow-DefaultElbow | 20 | 11,SHE-15.MEHP.dgn,Design Model:119694 | RadToDia | 89.2838 | 100 | 0.048955 | 71.29; 0.00; -27.81; | SVP1 | SVP
M-BmpElbow-DefaultElbow | 20 | 11,SHE-15.MEHP.dgn,Design Model:119770 | RadToDia | 89.2838 | 100 | 0.048955 | 71.29; 0.00; -27.81; | SVP1 | SVP
M-BmpElbow-DefaultElbow | 20 | 11,SHE-15.MEHP.dgn,Design Model:119889 | RadToDia | 89.2838 | 100 | 0.048955 | 71.29; 0.00; -27.81; | SVP1 | SVP
M-BmpElbow-DefaultElbow | 19 | 11,SHE-15.MEHP.dgn,Design Model:120017 | RadToDia | 89.991 | 100 | 0.049343 | 0.00; 0.00; 0.00; | SVP3 | SVP
M-BmpElbow-DefaultElbow | 19 | 11,SHE-15.MEHP.dgn,Design Model:120093 | RadToDia | 89.991 | 100 | 0.049343 | 0.00; 0.00; 0.00; | SVP3 | SVP
M-BmpElbow-DefaultElbow | storage | 11,SHE-15.MEHP.dgn,Design Model:120169 | RadToDia | 89.2838 | 100 | 0.048955 | 0.00; 0.00; 0.00; | SVP3 | SVP
M-BmpElbow-DefaultElbow | 19 | 11,SHE-15.MEHP.dgn,Design Model:120219 | RadToDia | 89.2838 | 100 | 0.048955 | 0.00; 0.00; 0.00; | SVP3 | SVP
M-BmpElbow-DefaultElbow | 18 | 11,SHE-15.MEHP.dgn,Design Model:120295 | RadToDia | 89.2838 | 100 | 0.048955 | 0.00; 0.00; 0.00; | SVP5 | SVP
M-BmpElbow-DefaultElbow | 18 | 11,SHE-15.MEHP.dgn,Design Model:120345 | RadToDia | 89.991 | 100 | 0.049343 | 0.00; 0.00; 0.00; | SVP5 | SVP
M-BmpElbow-DefaultElbow | storage | 11,SHE-15.MEHP.dgn,Design Model:120421 | RadToDia | 89.991 | 100 | 0.049343 | 0.00; 0.00; 0.00; | SVP5 | SVP
M-BmpElbow-DefaultElbow | storage | 11,SHE-15.MEHP.dgn,Design Model:120497 | RadToDia | 89.2838 | 100 | 0.048955 | 0.00; 0.00; 0.00; | SVP5 | SVP
M-BmpElbow-DefaultElbow | GF | 11,SHE-15.MEHP.dgn,Design Model:120573 |  | 60 | 80 | 0.026319 | 45.66; 0.00; -0.92; | SVP7 | SVP | Plumbing Elbow Parameters - Radius to Diameter Ratio: 0.8
M-BmpElbow-DefaultElbow | 03 | 11,SHE-15.MEHP.dgn,Design Model:120623 |  | 60 | 80 | 0.026319 | 45.66; 0.00; -0.92; | SVP7 | SVP | Plumbing Elbow Parameters - Radius to Diameter Ratio: 0.8
M-BmpElbow-DefaultElbow | GF | 11,SHE-15.MEHP.dgn,Design Model:121061 | RadToDia | 44.9963 | 100 | 0.024672 | 41.95; 0.00; 1.29; | SVP4 | SVP
M-BmpElbow-DefaultElbow | WC | 11,SHE-15.MEHP.dgn,Design Model:121187 | RadToDia | 89.2838 | 100 | 0.048955 | 71.29; 0.00; -27.81; | SVP4 | SVP
M-BmpElbow-DefaultElbow | WC | 11,SHE-15.MEHP.dgn,Design Model:121263 | RadToDia | 89.2838 | 100 | 0.048955 | 71.29; 0.00; -27.81; | SVP6 | SVP
M-BmpElbow-DefaultElbow | WC | 11,SHE-15.MEHP.dgn,Design Model:121313 | RadToDia | 89.2838 | 100 | 0.048955 | 71.29; 0.00; -27.81; | SVP6 | SVP
M-BmpElbow-DefaultElbow | GF | 11,SHE-15.MEHP.dgn,Design Model:121390 | RadToDia | 44.9963 | 100 | 0.024672 | 41.95; 0.00; 1.29; | SVP3 | SVP
M-BmpElbow-DefaultElbow | storage | 11,SHE-15.MEHP.dgn,Design Model:121466 | RadToDia | 44.9963 | 100 | 0.024672 | 41.95; 0.00; 1.29; | SVP3-5 | SVP3
M-BmpElbow-DefaultElbow | storage | 11,SHE-15.MEHP.dgn,Design Model:121542 | RadToDia | 44.9963 | 100 | 0.024672 | 41.95; 0.00; 1.29; | SVP3-5 | SVP3
M-BmpElbow-DefaultElbow | storage | 11,SHE-15.MEHP.dgn,Design Model:121927 | RadToDia | 89.2838 | 100 | 0.048955 | 71.29; 0.00; -27.81; | SVP5 | SVP
M-BmpElbow-DefaultElbow | GF | 11,SHE-15.MEHP.dgn,Design Model:121977 | RadToDia | 89.2838 | 100 | 0.048955 | 71.29; 0.00; -27.81; | SVP3 | SVP
M-BmpElbow-DefaultElbow | GF | 11,SHE-15.MEHP.dgn,Design Model:122079 | RadToDia | 44.9963 | 100 | 0.024672 | 41.95; 0.00; 1.29; | SVP7 | SVP
M-BmpElbow-DefaultElbow | GF | 11,SHE-15.MEHP.dgn,Design Model:122155 | RadToDia | 89.2838 | 100 | 0.048955 | 71.29; 0.00; -27.81; | SVP7 | SVP
M-BmpElbow-DefaultElbow | 1 | 11,SHE-15.MEHP.dgn,Design Model:122205 | RadToDia | 89.2838 | 100 | 0.048955 | 71.29; 0.00; -27.81; | SVP7 | SVP
M-BmpElbow-DefaultElbow | WC | 11,SHE-15.MEHP.dgn,Design Model:122281 | RadToDia | 89.2838 | 100 | 0.048955 | 71.29; 0.00; -27.81; | SVP3-4-5-6 | SVP3-4-5
M-BmpElbow-DefaultElbow | 0 | 11,SHE-15.MEHP.dgn,Design Model:122478 | RadToDia | 44.9963 | 100 | 0.024672 | 41.95; 0.00; 1.29; | SVP1 | SVP
M-BmpElbow-DefaultElbow | 0 | 11,SHE-15.MEHP.dgn,Design Model:122554 | RadToDia | 44.9963 | 100 | 0.024672 | 41.95; 0.00; 1.29; | SVP1 | SVP
M-BmpElbow-DefaultElbow | 0 | 11,SHE-15.MEHP.dgn,Design Model:122656 | RadToDia | 44.9963 | 100 | 0.024672 | 41.95; 0.00; 1.29; | SVP2 | SVP
M-BmpElbow-DefaultElbow | 0 | 11,SHE-15.MEHP.dgn,Design Model:122732 | RadToDia | 89.2838 | 100 | 0.048955 | 71.29; 0.00; -27.81; | SVP2 | SVP
M-BmpElbow-DefaultElbow | 0 | 11,SHE-15.MEHP.dgn,Design Model:122782 | RadToDia | 89.2838 | 100 | 0.048955 | 71.29; 0.00; -27.81; | SVP1 | SVP
M-BmpElbow-DefaultElbow | GF | 11,SHE-15.MEHP.dgn,Design Model:122832 | RadToDia | 89.2838 | 100 | 0.048955 | 71.29; 0.00; -27.81; | SVP1-2 | SVP1
M-BmpElbow-DefaultElbow | GF | 11,SHE-15.MEHP.dgn,Design Model:123012 | RadToDia | 88.8542 | 100 | 0.04872 | 71.09; 0.00; -27.47; | RW3 | RW
M-BmpElbow-DefaultElbow | GF | 11,SHE-15.MEHP.dgn,Design Model:123062 | RadToDia | 88.8542 | 100 | 0.04872 | 71.09; 0.00; -27.47; | RW3 | RW
M-BmpElbow-DefaultElbow | GF | 11,SHE-15.MEHP.dgn,Design Model:123112 | RadToDia | 88.8542 | 100 | 0.04872 | 71.09; 0.00; -27.47; | RW3 | RW
M-BmpElbow-DefaultElbow | 1 | 11,SHE-15.MEHP.dgn,Design Model:123162 | RadToDia | 88.8542 | 100 | 0.04872 | 71.09; 0.00; -27.47; | RW4 | RW
M-BmpElbow-DefaultElbow | GF | 11,SHE-15.MEHP.dgn,Design Model:123238 | RadToDia | 88.8542 | 100 | 0.04872 | 71.09; 0.00; -27.47; | RW4 | RW
M-BmpElbow-DefaultElbow | GF | 11,SHE-15.MEHP.dgn,Design Model:123314 | RadToDia | 88.8542 | 100 | 0.04872 | 71.09; 0.00; -27.47; | RW4 | RW
M-BmpElbow-DefaultElbow | bike store | 11,SHE-15.MEHP.dgn,Design Model:123364 | RadToDia | 88.8542 | 100 | 0.04872 | 71.09; 0.00; -27.47; | RW5 | RW
M-BmpElbow-DefaultElbow | GF | 11,SHE-15.MEHP.dgn,Design Model:123414 | RadToDia | 88.8542 | 100 | 0.04872 | 71.09; 0.00; -27.47; | RW3 | RW
M-BmpElbow-DefaultElbow | GF | 11,SHE-15.MEHP.dgn,Design Model:123490 | RadToDia | 88.8542 | 100 | 0.04872 | 71.09; 0.00; -27.47; | RW4 | RW
M-BmpElbow-DefaultElbow | ENTRANCE | 11,SHE-15.MEHP.dgn,Design Model:130538 | RadToDia | 89.2838 | 100 | 0.048955 | 71.29; 0.00; -27.81; | DRM | DRM
M-BmpElbow-DefaultElbow | 1 | 11,SHE-15.MEHP.dgn,Design Model:130588 | RadToDia | 89.2838 | 100 | 0.048955 | 71.29; 0.00; -27.81; | DRM | DRM
M-BmpElbow-DefaultElbow | 1 | 11,SHE-15.MEHP.dgn,Design Model:130638 | RadToDia | 89.2838 | 100 | 0.048955 | 71.29; 0.00; -27.81; | DRM | DRM
M-BmpElbow-DefaultElbow | landing | 11,SHE-15.MEHP.dgn,Design Model:131189 | RadToDia | 89.2838 | 100 | 0.048955 | 71.29; 0.00; -27.81; | DRM | DRM
M-BmpElbow-DefaultElbow | landing | 11,SHE-15.MEHP.dgn,Design Model:131239 | RadToDia | 89.2838 | 100 | 0.048955 | 71.29; 0.00; -27.81; | DRM | DRM
M-BmpElbow-DefaultElbow | GF | 11,SHE-15.MEHP.dgn,Design Model:131879 | RadToDia | 88.8542 | 100 | 0.04872 | 71.09; 0.00; -27.47; | RW5 | RW
M-BmpElbow-DefaultElbow | GF | 11,SHE-15.MEHP.dgn,Design Model:131955 | RadToDia | 88.8542 | 100 | 0.04872 | 71.09; 0.00; -27.47; | RW5 | RW
M-BmpElbow-DefaultElbow | GF | 11,SHE-15.MEHP.dgn,Design Model:132031 | RadToDia | 88.8542 | 100 | 0.04872 | 71.09; 0.00; -27.47; | RW5 | RW
M-BmpElbow-DefaultElbow | GF | 11,SHE-15.MEHP.dgn,Design Model:132107 | RadToDia | 88.8542 | 100 | 0.04872 | 71.09; 0.00; -27.47; | RW3 | RW
M-BmpElbow-DefaultElbow | GF | 11,SHE-15.MEHP.dgn,Design Model:132209 | RadToDia | 88.8542 | 100 | 0.04872 | 71.09; 0.00; -27.47; | RW3 | RW
M-BmpElbow-DefaultElbow | GF | 11,SHE-15.MEHP.dgn,Design Model:132285 | RadToDia | 88.8542 | 100 | 0.04872 | 71.09; 0.00; -27.47; | RW3 | RW
M-BmpElbow-DefaultElbow | GF | 11,SHE-15.MEHP.dgn,Design Model:132361 | RadToDia | 88.8542 | 100 | 0.04872 | 71.09; 0.00; -27.47; | RW3 | RW
M-BmpElbow-DefaultElbow | GF | 11,SHE-15.MEHP.dgn,Design Model:132411 | RadToDia | 88.8542 | 100 | 0.04872 | 71.09; 0.00; -27.47; | RW5 | RW
M-BmpElbow-DefaultElbow | GF | 11,SHE-15.MEHP.dgn,Design Model:132461 | RadToDia | 88.8542 | 100 | 0.04872 | 71.09; 0.00; -27.47; | RW5 | RW
M-BmpElbow-DefaultElbow | bath | 11,SHE-15.MEHP.dgn,Design Model:132563 | RadToDia | 89.2838 | 100 | 0.048955 | 71.29; 0.00; -27.81; | RW2 | RW
M-BmpElbow-DefaultElbow | 16 | 11,SHE-15.MEHP.dgn,Design Model:132639 | RadToDia | 89.2838 | 100 | 0.048955 | 71.29; 0.00; -27.81; | RW2 | RW
M-BmpElbow-DefaultElbow | storage | 11,SHE-15.MEHP.dgn,Design Model:140838 | RadToDia | 35.9648 | 100 | 0.01972 | 34.16; 0.00; 5.26; | SVP4 | SVP

# IfcFlowFitting: M-BmpTee-DefaultTee (11)
Type - PredefinedType: JUNCTION
Type - Plumbing Tee Parameters - Standard Angle: 88; Angle: 88; Inlet | Outer Diameter: 28.575; Outlet | Outer Diameter: 28.575; Branch | Outer Diameter: 15.875; Total Length: 28.575; Inlet | Length: 5; Outlet | Length: 5; Branch | Connection Length: 5; Center to Branch Distance: 25; Center to Inlet Distance: 6.35; Connection | End Type: m-1;m-1;m-1;; View Display: iso
Type - Parameters - Insulation | Thickness (mm): 0; Lining | Thickness (mm): 0; Status: New; Pressure Class: Low; Air Flow: Supply; Correction Factor: 1.0; Wall Thickness: 0
Type - Insulation/Lining Symbology Parameters - Insulation/Lining | Color: 4; Insulation/Lining | Line Weight: 2; Insulation/ Lining | Line Style: 0; Insulation/Lining | Level Name: Level 2
Type - End Spec3_222 (3 Connections: 3 Round) - Diameter 1 (D1 Ø): 50; Diameter 2 (D2 Ø): 50; Diameter 3 (D3 Ø): 50
Type - Classification - Uniclass2015: Pr_65_52_63
Material: M_BSUK_ColdWater
Plumbing Tee Parameters - Inlet | Outer Diameter: 100; Outlet | Outer Diameter: 100; Branch | Outer Diameter: 100; Connection | End Type: -;-;-;
Parameters - Insulation | Surface Area: 0 m2; Lining | Surface Area: 0 m2; Status: BSUK; Pressure Class: PN16; Air Flow: M
End Spec3_222 (3 Connections: 3 Round) - Diameter 1 (D1 Ø): 100; Diameter 2 (D2 Ø): 100; Diameter 3 (D3 Ø): 100
Construction Phase - Phase: New Construction
Name | In | Description | Standard Angle = Angle | Total Length | Center to Branch Distance | Center to Inlet Distance | Surface Area (m2) | Center Of Gravity | System ID | Group
M-BmpTee-DefaultTee | 17 | 11 ,SHE-15.MEHP.dgn,Design Model:119248 | 89.2838 | 100.012 | 50.6299 | 49.3819 | 0.032036 | 49.86; 0.00; 3.21; | SVP7 | SVP
M-BmpTee-DefaultTee | 22 | 11 ,SHE-15.MEHP.dgn,Design Model:119443 | 89.2838 | 100.012 | 50.6299 | 49.3819 | 0.032036 | 49.86; 0.00; 3.21; | SVP4 | SVP
M-BmpTee-DefaultTee | bath | 11 ,SHE-15.MEHP.dgn,Design Model:119820 | 89.2838 | 100.012 | 50.6299 | 49.3819 | 0.032036 | 49.86; 0.00; 3.21; | SVP1 | SVP
M-BmpTee-DefaultTee | storage | 11 ,SHE-15.MEHP.dgn,Design Model:121618 | 44.9963 | 141.433 | 120.723 | 20.7098 | 0.058785 | 69.79; 0.00; -18.05; | SVP3-5 | SVP3
M-BmpTee-DefaultTee | WC | 11 ,SHE-15.MEHP.dgn,Design Model:121765 | 89.2838 | 100.012 | 50.6299 | 49.3819 | 0.032036 | 49.86; 0.00; 3.21; | SVP3-5 | SVP3
M-BmpTee-DefaultTee | 1 | 11 ,SHE-15.MEHP.dgn,Design Model:122357 | 89.2838 | 100.012 | 50.6299 | 49.3819 | 0.032036 | 49.86; 0.00; 3.21; | SVP3-4-5-6-7 | SVP3-4-5-6
M-BmpTee-DefaultTee | ENTRANCE | 11 ,SHE-15.MEHP.dgn,Design Model:130714 | 89.2838 | 100.012 | 50.6299 | 49.3819 | 0.032036 | 49.86; 0.00; 3.21; | DRM | DRM
M-BmpTee-DefaultTee | landing | 11 ,SHE-15.MEHP.dgn,Design Model:130783 | 89.2838 | 100.012 | 50.6299 | 49.3819 | 0.032036 | 49.86; 0.00; 3.21; | DRM | DRM
M-BmpTee-DefaultTee | landing | 11 ,SHE-15.MEHP.dgn,Design Model:130878 | 89.2838 | 100.012 | 50.6299 | 49.3819 | 0.032036 | 49.86; 0.00; 3.21; | DRM | DRM
M-BmpTee-DefaultTee | landing | 11 ,SHE-15.MEHP.dgn,Design Model:130947 | 89.2838 | 100.012 | 50.6299 | 49.3819 | 0.032036 | 49.86; 0.00; 3.21; | DRM | DRM
M-BmpTee-DefaultTee | landing | 11 ,SHE-15.MEHP.dgn,Design Model:131068 | 89.2838 | 100.012 | 50.6299 | 49.3819 | 0.032036 | 49.86; 0.00; 3.21; | DRM | DRM

# IfcFlowFitting: M-BmpTransition-DefaultTransition
In: WC
Type - PredefinedType: TRANSITION
Type - Plumbing Transition Parameters - Inlet | Outer Diameter: 56; Outlet | Outer Diameter: 28.5; Total Length: 132; Rise: 0; Run: 0; Inlet | Length: 12; Outlet | Length: 12; Connection | End Type: -;-;; View Display: iso
Type - Parameters - Insulation | Thickness (mm): 0; Correction Factor: 1.0; Wall Thickness: 0
Type - Insulation/Lining Symbology Parameters - Insulation/Lining | Color: 4; Insulation/Lining | Line Weight: 2; Insulation/ Lining | Line Style: 0; Insulation/Lining | Level Name: Level 2
Type - End Spec2_22 (2 Connections: Round | Round) - Diameter 1 (D1 Ø): 100; Diameter 2 (D2 Ø): 50
Type - Classification - Uniclass2015: Pr_65_52_63
Description: 11,SHE-15.MEHP.dgn,Design Model:121860; Material: M_BSUK_ColdWater; Group: SVP3
Plumbing Transition Parameters - Inlet | Outer Diameter: 100; Outlet | Outer Diameter: 100; Total Length: 25.000000; Offset Options: t;; Run: 0.964637
Parameters - Surface Area: 0.015396 m2; Center Of Gravity: 12.50; -0.48; 0.00;; System ID: SVP3-5; Insulation | Surface Area: 0 m2; Lining | Thickness (mm): 0; Lining | Surface Area: 0 m2; Status: BSUK; Pressure Class: PN16; Air Flow: M
End Spec2_22 (2 Connections: Round | Round) - Diameter 2 (D2 Ø): 100
Construction Phase - Phase: New Construction

# IfcFlowFitting: M-PlenumBoxOvalMultiPort-Side (2)
Type - PredefinedType: JUNCTION
Type - Parameters - Insulation | Thickness (mm): 0; Lining | Thickness (mm): 0; Correction Factor: 1.0; Wall Thickness: 0
Type - Multi Port Plenum Box Parameters - Box | Height: 200; Box | Width: 550; Box | Depth: 150; No. Of Ports: 2; Port | Offset: 50; Connection | On Left Side: 2-No; Connection | On Right Side: 2-No; Duct Connection Length: 50; Equipment Connection Length: 50; Connection | End Type: -;; View Display: iso; Air Flow Rate: 0; Air Flow Rate Unit: 1-l/s
Type - End Spec7_1333333 (7 Connections: 1 Rect | 6 Oval) - Width 1 (W1): 550; Depth 1 (D1): 150; Width 2 (W2): 250; Depth 2 (D2): 150; Width 3 (W3): 250; Depth 3 (D3): 150; Width 4 (W4): 250; Depth 4 (D4): 150; Width 5 (W5): 250; Depth 5 (D5): 150; Width 6 (W6): 250; Depth 6 (D6): 150; Width 7 (W7): 250; Depth 7 (D7): 150
Type - Classification - Uniclass2015: Pr_70_65_04_04
Material: M_BSUK_Ventilation
Parameters - Surface Area: 0.469336 m2; Center Of Gravity: -3.86; 0.00; 98.92;; Insulation | Surface Area: 0 m2; Lining | Surface Area: 0 m2; Status: BSUK; Air Flow: M
Multi Port Plenum Box Parameters - Box | Width: 600; Connection | End Type: -;-;-;-;-;-;-;
Name | In | Description
M-PlenumBoxOvalMultiPort-Side | GF | 11,SHE-15.MEHP.dgn,Design Model:130140
M-PlenumBoxOvalMultiPort-Side | flat roof | 11,SHE-15.MEHP.dgn,Design Model:130255

# IfcFlowFitting: M-PlenumBoxRoundMultiPort-Side (2)
Type - PredefinedType: JUNCTION
Type - Parameters - Insulation | Thickness (mm): 0; Lining | Thickness (mm): 0; Correction Factor: 1.0; Wall Thickness: 0
Type - Multi Port Plenum Box Parameters - Box | Height: 200; Box | Width: 550; Box | Depth: 150; No. Of Ports: 3; Port | Offset: 50; Connection | On Left Side: 2-No; Connection | On Right Side: 2-No; Duct Connection Length: 50; Equipment Connection Length: 50; Connection | End Type: -;; View Display: iso; Air Flow Rate: 0; Air Flow Rate Unit: 1-l/s
Type - End Spec7_1222222 (7 Connections: 1 Rect | 6 Round) - Width 1 (W1): 550; Depth 1 (D1): 150; Diameter 2 (D2 Ø): 150; Diameter 3 (D3 Ø): 150; Diameter 4 (D4 Ø): 150; Diameter 5 (D5 Ø): 150; Diameter 6 (D6 Ø): 150; Diameter 7 (D7 Ø): 150
Type - Classification - Uniclass2015: Pr_70_65_04_04
Material: M_BSUK_Ventilation
Parameters - Surface Area: 0.485226 m2; Center Of Gravity: -6.37; 0.00; 98.96;; Insulation | Surface Area: 0 m2; Lining | Surface Area: 0 m2; Status: BSUK; Air Flow: M
Multi Port Plenum Box Parameters - Box | Width: 600; Connection | End Type: -;-;-;-;-;-;-;
Name | In | Description
M-PlenumBoxRoundMultiPort-Side | GF | 11,SHE-15.MEHP.dgn,Design Model:130075
M-PlenumBoxRoundMultiPort-Side | flat roof | 11,SHE-15.MEHP.dgn,Design Model:130370

# IfcFlowFitting: M-Roundelbow-DefaultRound (7)
Type - PredefinedType: BEND
Type - Round Elbow Parameters - AutoSize: Radius; Standard Angle: 90; Angle: 90; Radius to Diameter Ratio: 1.5; Radius: 750; Connection 1 | Length (L1): 50; Connection 2 | Length (L2): 50; Connection | End Type: m-5;m-5; View Display: iso
Type - Parameters - Insulation | Thickness (mm): 0; Lining | Thickness (mm): 0; Correction Factor: 1.0; Wall Thickness: 0
Type - End Spec2_22 (2 Connections: Round | Round) - Diameter 1 (D1 Ø): 500; Diameter 2 (D2 Ø): 500
Type - Classification - Uniclass2015: Pr_65_65_25_14
Material: M_BSUK_Ventilation; Group: EXT. Flat
Round Elbow Parameters - AutoSize: RadToDia; Radius to Diameter Ratio: 1; Radius: 100; Connection | End Type: -;-;
Parameters - Surface Area: 0.080764 m2; Center Of Gravity: 58.35; 0.00; -41.65;; Insulation | Surface Area: 0 m2; Lining | Surface Area: 0 m2; Status: BSUK; Air Flow: M
End Spec2_22 (2 Connections: Round | Round) - Diameter 1 (D1 Ø): 100; Diameter 2 (D2 Ø): 100
Construction Phase - Phase: New Construction
Name | In | Description | System ID
M-Roundelbow-DefaultRound | corridor (protected) | 11,SHE-15.MEHP.dgn,Design Model:123666 | EXT. Flat 23
M-Roundelbow-DefaultRound | corridor (protected) | 11,SHE-15.MEHP.dgn,Design Model:123773 | EXT. Flat 23
M-Roundelbow-DefaultRound | ensuite | 11,SHE-15.MEHP.dgn,Design Model:123964 | EXT. Flat 24
M-Roundelbow-DefaultRound | bath | 11,SHE-15.MEHP.dgn,Design Model:124071 | EXT. Flat 24
M-Roundelbow-DefaultRound | 26 | 11,SHE-15.MEHP.dgn,Design Model:124304 | EXT. Flat 25
M-Roundelbow-DefaultRound | 26 | 11,SHE-15.MEHP.dgn,Design Model:124411 | EXT. Flat 26
M-Roundelbow-DefaultRound | 26 | 11,SHE-15.MEHP.dgn,Design Model:124560 | EXT. Flat 26

# IfcFlowSegment: M-BmpStraightpipe-DefaultPipe (85)
Type - PredefinedType: RIGIDSEGMENT
Type - Pipe Parameters - Pipe Outer Diameter: 25; Pipe Length: 500; Minimum Length: 50; Connection 1 | Length (L1): 0; Connection 2 | Length (L2): 0; Connection | End Type: -;-;; View Display: iso
Type - Pipe Analytical Parameters - Additional Loss (N/m^2): 0; Additional K Value: 0; Insulation K Value (W/m°C): 0.03
Type - Parameters - Insulation | Thickness (mm): 0; Lining | Thickness (mm): 0; Status: New; Pressure Class: PN16; Air Flow: Supply; Correction Factor: 1.0; Wall Thickness: 0
Type - Insulation/Lining Symbology Parameters - Insulation/Lining | Color: 4; Insulation/Lining | Line Weight: 2; Insulation/ Lining | Line Style: 0; Insulation/Lining | Level Name: Level 2
Type - End Spec1_2 (1 Connection: Round) - Diameter 1 (D1 Ø): 50
Type - Classification - Uniclass2015: Pr_65_52_63
Material: M_BSUK_ColdWater
Pipe Parameters - Pipe Outer Diameter: 100.000000; Base Offset: 0.000
Parameters - Insulation | Surface Area: 0 m2; Lining | Surface Area: 0 m2; Status: BSUK; Air Flow: M
End Spec1_2 (1 Connection: Round) - Diameter 1 (D1 Ø): 100
Name | In | Description | Pipe Length | Slope Value | Slope Method | Surface Area (m2) | Center Of Gravity | System ID | Phase | Group
M-BmpStraightpipe-DefaultPipe | GF | 11,SHE-15.MEHP.dgn,Design Model:118888 | 50 | 0.0 | Degree | 0.015708 | 25.00; 0.00; 0.00; | SVP7 | New Construction | SVP
M-BmpStraightpipe-DefaultPipe | GF | 11,SHE-15.MEHP.dgn,Design Model:118914 | 50 | 0.0 | Degree | 0.015708 | 25.00; 0.00; 0.00; | SVP1 | New Construction | SVP
M-BmpStraightpipe-DefaultPipe | GF | 11,SHE-15.MEHP.dgn,Design Model:118940 | 207.268 | 0.0 | Degree | 0.065115 | 103.63; 0.00; 0.00; | SVP4 | New Construction | SVP
M-BmpStraightpipe-DefaultPipe | GF | 11,SHE-15.MEHP.dgn,Design Model:118966 | 326.115 | 0.0 | Degree | 0.102452 | 163.06; 0.00; 0.00; | SVP1 | New Construction | SVP
M-BmpStraightpipe-DefaultPipe | GF | 11,SHE-15.MEHP.dgn,Design Model:118992 | 315.312 | 0.0 | Degree | 0.099058 | 157.66; 0.00; 0.00; | SVP7 | New Construction | SVP
M-BmpStraightpipe-DefaultPipe | GF | 11,SHE-15.MEHP.dgn,Design Model:119018 | 262.571 | 0.0 | Degree | 0.082489 | 131.29; 0.00; 0.00; | SVP4 | New Construction | SVP
M-BmpStraightpipe-DefaultPipe | GF | 11,SHE-15.MEHP.dgn,Design Model:119070 | 2950.35 | 1 : 80 | Rise / Run | 0.926879 | 1475.17; 0.00; 0.00; | SVP7 | New Construction | SVP
M-BmpStraightpipe-DefaultPipe | GF | 11,SHE-15.MEHP.dgn,Design Model:119096 | 2744.81 | 1 : 80 | Rise / Run | 0.862308 | 1372.41; 0.00; 0.00; | SVP7 | New Construction | SVP
M-BmpStraightpipe-DefaultPipe | GF | 11,SHE-15.MEHP.dgn,Design Model:119122 | 115.318 | 0.0 | Degree | 0.036228 | 57.66; 0.00; 0.00; | SVP7 | New Construction | SVP
M-BmpStraightpipe-DefaultPipe | GF | 11,SHE-15.MEHP.dgn,Design Model:119367 | 819.683 | 1 : 80 | Rise / Run | 0.257511 | 409.84; 0.00; 0.00; | SVP4 | New Construction | SVP
M-BmpStraightpipe-DefaultPipe | GF | 11,SHE-15.MEHP.dgn,Design Model:119512 | 9644.6 | 0.0 | Degree | 3.02994 | 4822.30; 0.00; 0.00; | SVP1 | New Construction | SVP
M-BmpStraightpipe-DefaultPipe | GF | 11,SHE-15.MEHP.dgn,Design Model:119538 | 7432.07 | 0.0 | Degree | 2.33486 | 3716.04; 0.00; 0.00; | SVP2 | New Construction | SVP
M-BmpStraightpipe-DefaultPipe | GF | 11,SHE-15.MEHP.dgn,Design Model:119564 | 7206.42 | 0.0 | Degree | 2.26396 | 3603.21; 0.00; 0.00; | SVP6 | New Construction | SVP
M-BmpStraightpipe-DefaultPipe | GF | 11,SHE-15.MEHP.dgn,Design Model:119590 | 9685.92 | 0.0 | Degree | 3.04292 | 4842.96; 0.00; 0.00; | SVP3 | New Construction | SVP
M-BmpStraightpipe-DefaultPipe | GF | 11,SHE-15.MEHP.dgn,Design Model:119616 | 9722.06 | 0.0 | Degree | 3.05428 | 4861.03; 0.00; 0.00; | SVP5 | New Construction | SVP
M-BmpStraightpipe-DefaultPipe | GF | 11,SHE-15.MEHP.dgn,Design Model:119642 | 2295.8 | 1 : 80 | Rise / Run | 0.721246 | 1147.90; 0.00; 0.00; | SVP1 | New Construction | SVP
M-BmpStraightpipe-DefaultPipe | GF | 11,SHE-15.MEHP.dgn,Design Model:119668 | 1947.92 | 1 : 80 | Rise / Run | 0.611956 | 973.96; 0.00; 0.00; | SVP1 | New Construction | SVP
M-BmpStraightpipe-DefaultPipe | GF | 11,SHE-15.MEHP.dgn,Design Model:119744 | 125.624 | 0.0 | Degree | 0.039466 | 62.81; 0.00; 0.00; | SVP1 | New Construction | SVP
M-BmpStraightpipe-DefaultPipe | GF | 11,SHE-15.MEHP.dgn,Design Model:119939 | 190.779 | 0.0 | Degree | 0.059935 | 95.39; 0.00; 0.00; | SVP3 | New Construction | SVP
M-BmpStraightpipe-DefaultPipe | GF | 11,SHE-15.MEHP.dgn,Design Model:119965 | 190.779 | 0.0 | Degree | 0.059935 | 95.39; 0.00; 0.00; | SVP5 | New Construction | SVP
M-BmpStraightpipe-DefaultPipe | GF | 11,SHE-15.MEHP.dgn,Design Model:119991 | 1151.36 | 1 : 80 | Rise / Run | 0.361711 | 575.68; 0.00; 0.00; | SVP3 | New Construction | SVP
M-BmpStraightpipe-DefaultPipe | GF | 11,SHE-15.MEHP.dgn,Design Model:120067 | 1000.12 | 1 : 80 | Rise / Run | 0.314199 | 500.06; 0.00; 0.00; | SVP3 | New Construction | SVP
M-BmpStraightpipe-DefaultPipe | GF | 11,SHE-15.MEHP.dgn,Design Model:120143 | 528.362 | 1 : 80 | Rise / Run | 0.16599 | 264.18; 0.00; 0.00; | SVP3 | New Construction | SVP
M-BmpStraightpipe-DefaultPipe | GF | 11,SHE-15.MEHP.dgn,Design Model:120269 | 1151.36 | 1 : 80 | Rise / Run | 0.361711 | 0.00; 0.00; 0.00; | SVP5 | New Construction | SVP
M-BmpStraightpipe-DefaultPipe | GF | 11,SHE-15.MEHP.dgn,Design Model:120395 | 1000.12 | 1 : 80 | Rise / Run | 0.314199 | 0.00; 0.00; 0.00; | SVP5 | New Construction | SVP
M-BmpStraightpipe-DefaultPipe | GF | 11,SHE-15.MEHP.dgn,Design Model:120471 | 528.362 | 1 : 80 | Rise / Run | 0.16599 | 0.00; 0.00; 0.00; | SVP5 | New Construction | SVP
M-BmpStraightpipe-DefaultPipe | GF | 11,SHE-15.MEHP.dgn,Design Model:120673 | 215.962 | 0.0 | Degree | 0.067846 | 107.98; 0.00; 0.00; | SVP7 | New Construction | SVP
M-BmpStraightpipe-DefaultPipe | GF | 11,SHE-15.MEHP.dgn,Design Model:120699 | 619.743 | 0.0 | Degree | 0.194698 | 309.87; 0.00; 0.00; | SVP7 | New Construction | SVP
M-BmpStraightpipe-DefaultPipe | GF | 11,SHE-15.MEHP.dgn,Design Model:120725 | 24351.6 | 0.0 | Degree | 7.65027 | 12175.79; 0.00; 0.00; | RW1 | New Construction | RW
M-BmpStraightpipe-DefaultPipe | GF | 11,SHE-15.MEHP.dgn,Design Model:120751 | 7805.33 | 0.0 | Degree | 2.45212 | 3902.66; 0.00; 0.00; | SVP0 | New Construction | SVP
M-BmpStraightpipe-DefaultPipe | WC | 11,SHE-15.MEHP.dgn,Design Model:120779 | 20.788 | 0.0 | Degree | 0.006531 | 10.39; 0.00; 0.00; | SVP7 | New Construction | SVP | Pipe Parameters - Minimum Length: 20.788
M-BmpStraightpipe-DefaultPipe | GF | 11,SHE-15.MEHP.dgn,Design Model:121035 | 3529.67 | 1 : 80 | Rise / Run | 1.10888 | 1764.83; 0.00; 0.00; | SVP4 | New Construction | SVP
M-BmpStraightpipe-DefaultPipe | WC | 11,SHE-15.MEHP.dgn,Design Model:121111 | 971.684 | 1 : 80 | Rise / Run | 0.305264 | 485.84; 0.00; 0.00; | SVP4 | New Construction | SVP
M-BmpStraightpipe-DefaultPipe | WC | 11,SHE-15.MEHP.dgn,Design Model:121237 | 1204.91 | 1 : 80 | Rise / Run | 0.378534 | 602.46; 0.00; 0.00; | SVP6 | New Construction | SVP
M-BmpStraightpipe-DefaultPipe | GF | 11,SHE-15.MEHP.dgn,Design Model:121364 | 1157.49 | 1 : 80 | Rise / Run | 0.363635 | 578.74; 0.00; 0.00; | SVP3 | New Construction | SVP
M-BmpStraightpipe-DefaultPipe | storage | 11,SHE-15.MEHP.dgn,Design Model:121440 | 2632.82 | 1 : 80 | Rise / Run | 0.827125 | 1316.41; 0.00; 0.00; | SVP3 | New Construction | SVP
M-BmpStraightpipe-DefaultPipe | storage | 11,SHE-15.MEHP.dgn,Design Model:121516 | 1027.66 | 1 : 80 | Rise / Run | 0.322849 | 513.83; 0.00; 0.00; | SVP3-5 | New Construction | SVP3
M-BmpStraightpipe-DefaultPipe | GF | 11,SHE-15.MEHP.dgn,Design Model:121592 | 3622.03 | 1 : 80 | Rise / Run | 1.13789 | 1811.01; 0.00; 0.00; | SVP3-5 | New Construction | SVP3
M-BmpStraightpipe-DefaultPipe | storage | 11,SHE-15.MEHP.dgn,Design Model:121687 | 736.484 | 1 : 80 | Rise / Run | 0.231373 | 368.24; 0.00; 0.00; | SVP3-5 | New Construction | SVP3
M-BmpStraightpipe-DefaultPipe | storage | 11,SHE-15.MEHP.dgn,Design Model:121713 | 1072.99 | 1 : 80 | Rise / Run | 0.337089 | 536.49; 0.00; 0.00; | SVP5 | New Construction | SVP
M-BmpStraightpipe-DefaultPipe | GF | 11,SHE-15.MEHP.dgn,Design Model:121739 | 88.98 | 0.0 | Degree | 0.027954 | 44.49; 0.00; 0.00; | SVP3-4-5-6 | New Construction | SVP3-4-5
M-BmpStraightpipe-DefaultPipe | WC | 11,SHE-15.MEHP.dgn,Design Model:121834 | 50 | 0.0 | Degree | 0.015708 | 25.00; 0.00; 0.00;
M-BmpStraightpipe-DefaultPipe | 1 | 11,SHE-15.MEHP.dgn,Design Model:122027 | 122.618 | 0.0 | Degree | 0.038521 | 61.31; 0.00; 0.00; | SVP7 | New Construction | SVP
M-BmpStraightpipe-DefaultPipe | GF | 11,SHE-15.MEHP.dgn,Design Model:122053 | 2682.17 | 1 : 80 | Rise / Run | 0.842628 | 1341.08; 0.00; 0.00; | SVP7 | New Construction | SVP
M-BmpStraightpipe-DefaultPipe | 1 | 11,SHE-15.MEHP.dgn,Design Model:122129 | 425.554 | 1 : 80 | Rise / Run | 0.133692 | 212.78; 0.00; 0.00; | SVP7 | New Construction | SVP
M-BmpStraightpipe-DefaultPipe | GF | 11,SHE-15.MEHP.dgn,Design Model:122255 | 1293.32 | 1 : 80 | Rise / Run | 0.406307 | 646.66; 0.00; 0.00; | SVP3-4-5-6 | New Construction | SVP3-4-5
M-BmpStraightpipe-DefaultPipe | GF | 11,SHE-15.MEHP.dgn,Design Model:122331 | 7759.69 | 0.0 | Degree | 2.43778 | 3879.85; 0.00; 0.00; | SVP3-4-5-6-7 | New Construction | SVP3-4-5-6
M-BmpStraightpipe-DefaultPipe | GF | 11,SHE-15.MEHP.dgn,Design Model:122426 | 7925.4 | 0.0 | Degree | 2.48984 | 3962.70; 0.00; 0.00; | SVP1-2 | New Construction | SVP1
M-BmpStraightpipe-DefaultPipe | 0 | 11,SHE-15.MEHP.dgn,Design Model:122452 | 4139.69 | 1 : 80 | Rise / Run | 1.30052 | 2069.84; 0.00; 0.00; | SVP1 | New Construction | SVP
M-BmpStraightpipe-DefaultPipe | 0 | 11,SHE-15.MEHP.dgn,Design Model:122528 | 362.22 | 1 : 80 | Rise / Run | 0.113795 | 181.11; 0.00; 0.00; | SVP1 | New Construction | SVP
M-BmpStraightpipe-DefaultPipe | 0 | 11,SHE-15.MEHP.dgn,Design Model:122604 | 5796.24 | 1 : 80 | Rise / Run | 1.82094 | 2898.12; 0.00; 0.00; | SVP1-2 | New Construction | SVP1
M-BmpStraightpipe-DefaultPipe | 0 | 11,SHE-15.MEHP.dgn,Design Model:122630 | 1522.04 | 1 : 80 | Rise / Run | 0.478162 | 761.02; 0.00; 0.00; | SVP2 | New Construction | SVP
M-BmpStraightpipe-DefaultPipe | 0 | 11,SHE-15.MEHP.dgn,Design Model:122706 | 403.638 | 1 : 80 | Rise / Run | 0.126807 | 201.82; 0.00; 0.00; | SVP2 | New Construction | SVP
M-BmpStraightpipe-DefaultPipe | GF | 11,SHE-15.MEHP.dgn,Design Model:122882 | 9027.6 | 0.0 | Degree | 2.83611 | 4513.80; 0.00; 0.00; | RW3 | New Construction | RW
M-BmpStraightpipe-DefaultPipe | GF | 11,SHE-15.MEHP.dgn,Design Model:122908 | 9229.31 | 0.0 | Degree | 2.89947 | 4614.66; 0.00; 0.00; | RW4 | New Construction | RW
M-BmpStraightpipe-DefaultPipe | GF | 11,SHE-15.MEHP.dgn,Design Model:122934 | 15176.6 | 0.0 | Degree | 4.76787 | 7588.31; 0.00; 0.00; | RW5 | New Construction | RW
M-BmpStraightpipe-DefaultPipe | GF | 11,SHE-15.MEHP.dgn,Design Model:122960 | 6071.43 | 0.0 | Degree | 1.9074 | 3035.71; 0.00; 0.00; | RW3 | New Construction | RW
M-BmpStraightpipe-DefaultPipe | GF | 11,SHE-15.MEHP.dgn,Design Model:122986 | 311.95 | 0.0 | Degree | 0.098002 | 155.98; 0.00; 0.00; | RW3 | New Construction | RW
M-BmpStraightpipe-DefaultPipe | 1 | 11,SHE-15.MEHP.dgn,Design Model:123212 | 5986.89 | 0.0 | Degree | 1.88084 | 2993.45; 0.00; 0.00; | RW4 | New Construction | RW
M-BmpStraightpipe-DefaultPipe | GF | 11,SHE-15.MEHP.dgn,Design Model:123288 | 234.392 | 0.0 | Degree | 0.073636 | 117.20; 0.00; 0.00; | RW4 | New Construction | RW
M-BmpStraightpipe-DefaultPipe | GF | 11,SHE-15.MEHP.dgn,Design Model:123464 | 50 | 1 : 80 | Rise / Run | 0.015708 | 25.00; 0.00; 0.00; | RW4 | New Construction | RW
M-BmpStraightpipe-DefaultPipe | 0 | 11,SHE-15.MEHP.dgn,Design Model:130049 | 12003 | 0.0 | Degree | 3.77087 | 6001.52; 0.00; 0.00; | RW6 | New Construction | RW
M-BmpStraightpipe-DefaultPipe | GF | 11,SHE-15.MEHP.dgn,Design Model:130460 | 1019.92 | 0.0 | Degree | 0.320417 | 509.96; 0.00; 0.00; | DRM | New Construction | DRM
M-BmpStraightpipe-DefaultPipe | 1 | 11,SHE-15.MEHP.dgn,Design Model:130486 | 1519.3 | 0.0 | Degree | 0.477302 | 759.65; 0.00; 0.00; | DRM | New Construction | DRM
M-BmpStraightpipe-DefaultPipe | GF | 11,SHE-15.MEHP.dgn,Design Model:130512 | 4452.11 | 1 : 80 | Rise / Run | 1.39867 | 2226.05; 0.00; 0.00; | DRM | New Construction | DRM
M-BmpStraightpipe-DefaultPipe | GF | 11,SHE-15.MEHP.dgn,Design Model:130688 | 466.449 | 1 : 80 | Rise / Run | 0.146539 | 233.22; 0.00; 0.00; | DRM | New Construction | DRM
M-BmpStraightpipe-DefaultPipe | GF | 11,SHE-15.MEHP.dgn,Design Model:130852 | 2439.99 | 0.0 | Degree | 0.766545 | 1219.99; 0.00; 0.00; | DRM | New Construction | DRM
M-BmpStraightpipe-DefaultPipe | GF | 11,SHE-15.MEHP.dgn,Design Model:131016 | 3379.99 | 0.0 | Degree | 1.06185 | 1689.99; 0.00; 0.00; | DRM | New Construction | DRM
M-BmpStraightpipe-DefaultPipe | GF | 11,SHE-15.MEHP.dgn,Design Model:131042 | 3379.99 | 0.0 | Degree | 1.06185 | 1689.99; 0.00; 0.00; | DRM | New Construction | DRM
M-BmpStraightpipe-DefaultPipe | landing | 11,SHE-15.MEHP.dgn,Design Model:131137 | 893.583 | 0.0 | Degree | 0.280727 | 446.79; 0.00; 0.00; | DRM | New Construction | DRM
M-BmpStraightpipe-DefaultPipe | landing | 11,SHE-15.MEHP.dgn,Design Model:131163 | 1647.66 | 0.0 | Degree | 0.517627 | 823.83; 0.00; 0.00; | DRM | New Construction | DRM
M-BmpStraightpipe-DefaultPipe | GF | 11,SHE-15.MEHP.dgn,Design Model:131853 | 13297.2 | 0.0 | Degree | 4.17744 | 6648.61; 0.00; 0.00; | RW5 | New Construction | RW
M-BmpStraightpipe-DefaultPipe | GF | 11,SHE-15.MEHP.dgn,Design Model:131929 | 14511.9 | 0.0 | Degree | 4.55904 | 7255.93; 0.00; 0.00; | RW5 | New Construction | RW
M-BmpStraightpipe-DefaultPipe | GF | 11,SHE-15.MEHP.dgn,Design Model:132005 | 4475.88 | 0.0 | Degree | 1.40614 | 2237.94; 0.00; 0.00; | RW5 | New Construction | RW
M-BmpStraightpipe-DefaultPipe | GF | 11,SHE-15.MEHP.dgn,Design Model:132081 | 8636.03 | 0.0 | Degree | 2.71309 | 4318.01; 0.00; 0.00; | RW5 | New Construction | RW
M-BmpStraightpipe-DefaultPipe | GF | 11,SHE-15.MEHP.dgn,Design Model:132157 | 117.502 | 0.0 | Degree | 0.036914 | 58.75; 0.00; 0.00; | RW3 | New Construction | RW
M-BmpStraightpipe-DefaultPipe | GF | 11,SHE-15.MEHP.dgn,Design Model:132183 | 12987.9 | 0.0 | Degree | 4.08026 | 6493.94; 0.00; 0.00; | RW3 | New Construction | RW
M-BmpStraightpipe-DefaultPipe | GF | 11,SHE-15.MEHP.dgn,Design Model:132259 | 14511.9 | 0.0 | Degree | 4.55904 | 7255.93; 0.00; 0.00; | RW3 | New Construction | RW
M-BmpStraightpipe-DefaultPipe | GF | 11,SHE-15.MEHP.dgn,Design Model:132335 | 13297.2 | 0.0 | Degree | 4.17744 | 6648.61; 0.00; 0.00; | RW3 | New Construction | RW
M-BmpStraightpipe-DefaultPipe | GF | 11,SHE-15.MEHP.dgn,Design Model:132511 | 5974.07 | 0.0 | Degree | 1.87681 | 2987.04; 0.00; 0.00; | RW2 | New Construction | RW
M-BmpStraightpipe-DefaultPipe | GF | 11,SHE-15.MEHP.dgn,Design Model:132537 | 18166 | 0.0 | Degree | 5.70702 | 9083.01; 0.00; 0.00; | RW2 | New Construction | RW
M-BmpStraightpipe-DefaultPipe | GF | 11,SHE-15.MEHP.dgn,Design Model:132613 | 172.177 | 1 : 80 | Rise / Run | 0.054091 | 86.09; 0.00; 0.00; | RW2 | New Construction | RW
M-BmpStraightpipe-DefaultPipe | GF | 11,SHE-15.MEHP.dgn,Design Model:140454 | 9199.95 | 0.0 | Degree | 2.89025 | 4599.98; 0.00; 0.00; | SVP4 | New Construction | SVP
M-BmpStraightpipe-DefaultPipe | GF | 11,SHE-15.MEHP.dgn,Design Model:140480 | 9008.09 | 0.0 | Degree | 2.82998 | 4504.05; 0.00; 0.00; | SVP7 | New Construction | SVP
M-BmpStraightpipe-DefaultPipe | GF | 11,SHE-15.MEHP.dgn,Design Model:140964 | 2855.54 | 1 : 80 | Rise / Run | 0.897095 | 1427.77; 0.00; 0.00; | SVP4 | New Construction | SVP

# IfcFlowSegment: M-RoundDuct (25)
Type - PredefinedType: RIGIDSEGMENT
Type - Round Duct Parameters - Length: 2000; Minimum Length: 100; Connection 1 | Length (L1): 0; Connection 2 | Length (L2): 0; Connection | End Type: m-5;m-5; View Display: iso
Type - Parameters - Insulation | Thickness (mm): 0; Lining | Thickness (mm): 0; Correction Factor: 1.0; Wall Thickness: 0
Type - End Spec1_2 (1 Connection: Round) - Diameter 1 (D1 Ø): 500
Type - Classification - Uniclass2015: Pr_65_65_25_14
Material: M_BSUK_Ventilation
Round Duct Parameters - Connection | End Type: m-5;m-5;; Base Offset: 0.000
Parameters - Insulation | Surface Area: 0 m2; Lining | Surface Area: 0 m2; Status: BSUK; Air Flow: M
Name | In | Description | Length | VulcanParameters | Surface Area (m2) | Center Of Gravity | System ID | Diameter 1 (D1 Ø) | Phase | Group
M-RoundDuct | GF | 11 ,SHE-15.MEHP.dgn,Design Model:123540 | 3209.54 | FN=302-m;W=100;L=3209.544714;CN1=Male 5;CN2=Male 5;END | 1.00831 | 1604.77; 0.00; 0.00; | EXT. Flat 23 | 100 | New Construction | EXT. Flat
M-RoundDuct | GF | 11 ,SHE-15.MEHP.dgn,Design Model:123582 | 3108.93 | FN=302-m;W=100;L=3108.93321;CN1=Male 5;CN2=Male 5;END | 0.9767 | 1554.47; 0.00; 0.00; | EXT. Flat 26 | 100 | New Construction | EXT. Flat
M-RoundDuct | GF | 11 ,SHE-15.MEHP.dgn,Design Model:123624 | 100 | FN=302-m;W=100;L=100;CN1=Male 5;CN2=Male 5;END | 0.031416 | 50.00; 0.00; 0.00; | EXT. Flat 23 | 100 | New Construction | EXT. Flat
M-RoundDuct | GF | 11 ,SHE-15.MEHP.dgn,Design Model:123731 | 662.619 | FN=302-m;W=100;L=662.619324;CN1=Male 5;CN2=Male 5;END | 0.208168 | 331.31; 0.00; 0.00; | EXT. Flat 23 | 100 | New Construction | EXT. Flat
M-RoundDuct | GF | 11 ,SHE-15.MEHP.dgn,Design Model:123838 | 7980.06 | FN=302-m;W=100;L=7980.060544;CN1=Male 5;CN2=Male 5;END | 2.50701 | 3990.03; 0.00; 0.00; | EXT. Flat 23 | 100 | New Construction | EXT. Flat
M-RoundDuct | GF | 11 ,SHE-15.MEHP.dgn,Design Model:123880 | 282.911 | FN=302-m;W=100;L=282.910663;CN1=Male 5;CN2=Male 5;END | 0.088879 | 141.46; 0.00; 0.00; | EXT. Flat 23 | 100 | New Construction | EXT. Flat
M-RoundDuct | GF | 11 ,SHE-15.MEHP.dgn,Design Model:123922 | 2100.06 | FN=302-m;W=100;L=2100.060544;CN1=Male 5;CN2=Male 5;END | 0.659753 | 1050.03; 0.00; 0.00; | EXT. Flat 24 | 100 | New Construction | EXT. Flat
M-RoundDuct | GF | 11 ,SHE-15.MEHP.dgn,Design Model:124029 | 982.619 | FN=302-m;W=100;L=982.619324;CN1=Male 5;CN2=Male 5;END | 0.308699 | 491.31; 0.00; 0.00; | EXT. Flat 24 | 100 | New Construction | EXT. Flat
M-RoundDuct | GF | 11 ,SHE-15.MEHP.dgn,Design Model:124136 | 320.63 | FN=302-m;W=100;L=320.629531;CN1=Male 5;CN2=Male 5;END | 0.100729 | 160.31; 0.00; 0.00; | EXT. Flat 24 | 100 | New Construction | EXT. Flat
M-RoundDuct | GF | 11 ,SHE-15.MEHP.dgn,Design Model:124178 | 922.649 | FN=302-m;W=100;L=922.64892;CN1=Male 5;CN2=Male 5;END | 0.289859 | 461.32; 0.00; 0.00; | EXT. Flat 24 | 100 | New Construction | EXT. Flat
M-RoundDuct | GF | 11 ,SHE-15.MEHP.dgn,Design Model:124220 | 922.649 | FN=302-m;W=100;L=922.64892;CN1=Male 5;CN2=Male 5;END | 0.289859 | 461.32; 0.00; 0.00; | EXT. Flat 25 | 100 | New Construction | EXT. Flat
M-RoundDuct | GF | 11 ,SHE-15.MEHP.dgn,Design Model:124262 | 1172.6 | FN=302-m;W=100;L=1172.595446;CN1=Male 5;CN2=Male 5;END | 0.368382 | 586.30; 0.00; 0.00; | EXT. Flat 25 | 100 | New Construction | EXT. Flat
M-RoundDuct | GF | 11 ,SHE-15.MEHP.dgn,Design Model:124369 | 2120.1 | FN=302-m;W=100;L=2120.095613;CN1=Male 5;CN2=Male 5;END | 0.666048 | 1060.05; 0.00; 0.00; | EXT. Flat 25 | 100 | New Construction | EXT. Flat
M-RoundDuct | GF | 11 ,SHE-15.MEHP.dgn,Design Model:124476 | 2620.1 | FN=302-m;W=100;L=2620.095613;CN1=Male 5;CN2=Male 5;END | 0.823127 | 1310.05; 0.00; 0.00; | EXT. Flat 26 | 100 | New Construction | EXT. Flat
M-RoundDuct | GF | 11 ,SHE-15.MEHP.dgn,Design Model:124518 | 2682.64 | FN=302-m;W=100;L=2682.641613;CN1=Male 5;CN2=Male 5;END | 0.842777 | 1341.32; 0.00; 0.00; | EXT. Flat 26 | 100 | New Construction | EXT. Flat
M-RoundDuct | GF | 11 ,SHE-15.MEHP.dgn,Design Model:124625 | 1188.14 | FN=302-m;W=100;L=1188.137127;CN1=Male 5;CN2=Male 5;END | 0.373264 | 594.07; 0.00; 0.00; | EXT. Flat 26 | 100 | New Construction | EXT. Flat
M-RoundDuct | GF | 11 ,SHE-15.MEHP.dgn,Design Model:124667 | 2106.22 | FN=302-m;W=100;L=2106.217613;CN1=Male 5;CN2=Male 5;END | 0.661688 | 1053.11; 0.00; 0.00; | EXT. Flat 23 | 100 | New Construction | EXT. Flat
M-RoundDuct | GF | 11 ,SHE-15.MEHP.dgn,Design Model:124709 | 2106.22 | FN=302-m;W=100;L=2106.217613;CN1=Male 5;CN2=Male 5;END | 0.661688 | 1053.11; 0.00; 0.00; | EXT. Flat 24 | 100 | New Construction | EXT. Flat
M-RoundDuct | GF | 11 ,SHE-15.MEHP.dgn,Design Model:124751 | 1075 | FN=302-m;W=100;L=1075;CN1=Male 5;CN2=Male 5;END | 0.337721 | 537.50; 0.00; 0.00; | EXT. Flat 25 | 100 | New Construction | EXT. Flat
M-RoundDuct | flat roof | 11 ,SHE-15.MEHP.dgn,Design Model:124793 | 4044.55 | FN=302-m;W=1200;L=4044.548191;CN1=Male 5;CN2=Male 5;END | 15.2476 | 2022.27; 0.00; 0.00; | EXT. AOV | 1200 |  | EXT. AOV
M-RoundDuct | landing | 11 ,SHE-15.MEHP.dgn,Design Model:131289 | 100 | FN=302-m;W=100;L=100;CN1=Male 5;CN2=Male 5;END | 0.031416 | 50.00; 0.00; 0.00; | DRM | 100 | New Construction | DRM
M-RoundDuct | landing | 11 ,SHE-15.MEHP.dgn,Design Model:131331 | 100 | FN=302-m;W=100;L=100;CN1=Male 5;CN2=Male 5;END | 0.031416 | 50.00; 0.00; 0.00; | DRM | 100 | New Construction | DRM
M-RoundDuct | landing | 11 ,SHE-15.MEHP.dgn,Design Model:131373 | 100 | FN=302-m;W=100;L=100;CN1=Male 5;CN2=Male 5;END | 0.031416 | 50.00; 0.00; 0.00; | DRM | 100 | New Construction | DRM
M-RoundDuct | landing | 11 ,SHE-15.MEHP.dgn,Design Model:131415 | 100 | FN=302-m;W=100;L=100;CN1=Male 5;CN2=Male 5;END | 0.031416 | 50.00; 0.00; 0.00; | DRM | 100 | New Construction | DRM
M-RoundDuct | GF | 11 ,SHE-15.MEHP.dgn,Design Model:131457 | 100 | FN=302-m;W=100;L=100;CN1=Male 5;CN2=Male 5;END | 0.031416 | 50.00; 0.00; 0.00; | DRM | 100 | New Construction | DRM

# IfcFlowTerminal: M-BmvRadiator-Column (34)
Type - Radiator Parameters - Box | Height: 625; Box | Width: 150; Box | Length: 500; Number Of Sections: 10; Flow | Connection Side: 1-Left; Flow | Outside Diameter: 25; Flow Top Offset: 525; Flow | Length: 50; Return | Connection Side: 2-Right; Return | Outer Diameter: 25; Return | Top Offset: 100; Return | Length: 50; Connection 1 | Length (L1): 0; Connection | End Type: -; View Display: Iso
Type - Parameters - Insulation | Thickness (mm): 0; Lining | Thickness (mm): 0; Correction Factor: 1.0; Wall Thickness: 0
Type - End Spec1_2 (1 Connection: Round) - Diameter 1 (D1 Ø): 100
Type - Emitters Analytical Parameters - Heat Emission (W): 0; Pressure Drop Type: 1-k value; Emitter Pressure Drop: 0; Flow Valve Type: 1-No Valve; Flow Valve K Value (W/m°C): 0; Return Valve Type: 1-No Valve; Return Valve K Value (W/m°C): 0
Type - Classification - Uniclass2015: Pr_70_60_36_72
Material: M_BSUK_Ventilation
Radiator Parameters - Box | Height: 1200; Box | Width: 25; Number Of Sections: 5; Flow | Outside Diameter: 20; Flow Top Offset: 107.5; Return | Outer Diameter: 20; Return | Top Offset: 101.6; Connection | End Type: -;
Parameters - Type: Towel warmer; Insulation | Surface Area: 0 m2; Lining | Surface Area: 0 m2; Status: BSUK; Air Flow: M
Name | In | Description | Surface Area (m2) | Center Of Gravity
M-BmvRadiator-Column | bath | 1 ,SHE-01.GROUND.dgn,Design Model:262253 | 0.801283 | 150.00; 0.00; 3.89; | Radiator Parameters - Box | Length: 300
M-BmvRadiator-Column | 01 | 2 ,SHE-02.MEZZANINE.dgn,Design Model:194896 | 0.801283 | 150.00; 0.00; 3.89; | Radiator Parameters - Box | Length: 300
M-BmvRadiator-Column | WC | 2 ,SHE-02.MEZZANINE.dgn,Design Model:195239 | 0.801283 | 150.00; 0.00; 3.89; | Radiator Parameters - Box | Length: 300
M-BmvRadiator-Column | WC | 2 ,SHE-02.MEZZANINE.dgn,Design Model:195352 | 0.801283 | 150.00; 0.00; 3.89; | Radiator Parameters - Box | Length: 300
M-BmvRadiator-Column | bath | 4 ,SHE-03.FIRST.dgn,Design Model:133362 | 1.04628 | 200.00; 0.00; 2.98; | Radiator Parameters - Box | Length: 400
M-BmvRadiator-Column | bath | 4 ,SHE-03.FIRST.dgn,Design Model:143194 | 1.29128 | 250.00; 0.00; 2.41;
M-BmvRadiator-Column | bath | 4 ,SHE-03.FIRST.dgn,Design Model:145994 | 1.29128 | 250.00; 0.00; 2.41;
M-BmvRadiator-Column | bath | 4 ,SHE-03.FIRST.dgn,Design Model:142051 | 1.29128 | 250.00; 0.00; 2.41;
M-BmvRadiator-Column | 07 | 4 ,SHE-03.FIRST.dgn,Design Model:133475 | 0.801283 | 150.00; 0.00; 3.89; | Radiator Parameters - Box | Length: 300
M-BmvRadiator-Column | ensuite | 4 ,SHE-03.FIRST.dgn,Design Model:229302 | 1.29128 | 250.00; 0.00; 2.41;
M-BmvRadiator-Column | 05 | 4 ,SHE-03.FIRST.dgn,Design Model:300364 | 1.29128 | 250.00; 0.00; 2.41;
M-BmvRadiator-Column | bath | 4 ,SHE-03.FIRST.dgn,Design Model:352516 | 1.29128 | 250.00; 0.00; 2.41;
M-BmvRadiator-Column | bath | 6 ,SHE-05.THIRD.dgn,Design Model:133362 | 1.04628 | 200.00; 0.00; 2.98; | Radiator Parameters - Box | Length: 400
M-BmvRadiator-Column | bath | 6 ,SHE-05.THIRD.dgn,Design Model:143194 | 1.29128 | 250.00; 0.00; 2.41;
M-BmvRadiator-Column | bath | 6 ,SHE-05.THIRD.dgn,Design Model:145994 | 1.29128 | 250.00; 0.00; 2.41;
M-BmvRadiator-Column | bath | 6 ,SHE-05.THIRD.dgn,Design Model:142051 | 1.29128 | 250.00; 0.00; 2.41;
M-BmvRadiator-Column | 21 | 6 ,SHE-05.THIRD.dgn,Design Model:133475 | 0.801283 | 150.00; 0.00; 3.89; | Radiator Parameters - Box | Length: 300
M-BmvRadiator-Column | ensuite | 6 ,SHE-05.THIRD.dgn,Design Model:229302 | 1.29128 | 250.00; 0.00; 2.41;
M-BmvRadiator-Column | 19 | 6 ,SHE-05.THIRD.dgn,Design Model:300364 | 1.29128 | 250.00; 0.00; 2.41;
M-BmvRadiator-Column | bath | 6 ,SHE-05.THIRD.dgn,Design Model:435141 | 1.29128 | 250.00; 0.00; 2.41;
M-BmvRadiator-Column | 26 | 7 ,SHE-06.FOURTH.dgn,Design Model:485879 | 1.29128 | 250.00; 0.00; 2.41;
M-BmvRadiator-Column | 25 | 7 ,SHE-06.FOURTH.dgn,Design Model:488452 | 1.29128 | 250.00; 0.00; 2.41;
M-BmvRadiator-Column | ensuite | 7 ,SHE-06.FOURTH.dgn,Design Model:488565 | 1.29128 | 250.00; 0.00; 2.41;
M-BmvRadiator-Column | ensuite | 7 ,SHE-06.FOURTH.dgn,Design Model:488678 | 1.29128 | 250.00; 0.00; 2.41;
M-BmvRadiator-Column | 24 | 7 ,SHE-06.FOURTH.dgn,Design Model:488791 | 1.29128 | 250.00; 0.00; 2.41;
M-BmvRadiator-Column | ensuite | 7 ,SHE-06.FOURTH.dgn,Design Model:488904 | 1.29128 | 250.00; 0.00; 2.41;
M-BmvRadiator-Column | bath | 18,SHE-04.SECOND.dgn,Design Model:133362 | 1.04628 | 200.00; 0.00; 2.98; | Radiator Parameters - Box | Length: 400
M-BmvRadiator-Column | bath | 18,SHE-04.SECOND.dgn,Design Model:143194 | 1.29128 | 250.00; 0.00; 2.41;
M-BmvRadiator-Column | bath | 18,SHE-04.SECOND.dgn,Design Model:145994 | 1.29128 | 250.00; 0.00; 2.41;
M-BmvRadiator-Column | bath | 18,SHE-04.SECOND.dgn,Design Model:142051 | 1.29128 | 250.00; 0.00; 2.41;
M-BmvRadiator-Column | 14 | 18,SHE-04.SECOND.dgn,Design Model:133475 | 0.801283 | 150.00; 0.00; 3.89; | Radiator Parameters - Box | Length: 300
M-BmvRadiator-Column | ensuite | 18,SHE-04.SECOND.dgn,Design Model:229302 | 1.29128 | 250.00; 0.00; 2.41;
M-BmvRadiator-Column | 12 | 18,SHE-04.SECOND.dgn,Design Model:300364 | 1.29128 | 250.00; 0.00; 2.41;
M-BmvRadiator-Column | 15 | 18,SHE-04.SECOND.dgn,Design Model:374557 | 0.801283 | 150.00; 0.00; 3.89; | Radiator Parameters - Box | Length: 300

# IfcFlowTerminal: M-BmvRadiatorpanel-Panel (66)
Type - Radiator Panel Parameters - Box | Height: 450; Box | Width: 150; Box | Length: 750; Mounting Height: 350; Mounting Width: 50; Mounting Length: 600; Radiator Type: 1-Panel; Panel Type: 1-Single; Flow | Connection Side: 1-Left; Flow Location: 1-Panel 1; Flow | Outside Diameter: 25; Flow Top Offset: 375; Flow | Length: 50; Return | Connection Side: 2-Right; Return Location: 1-Panel 1; Return | Outer Diameter: 25; Return | Top Offset: 100; Return | Length: 50; Connection 1 | Length (L1): 0; Connection | End Type: -; View Display: Iso
Type - Parameters - Insulation | Thickness (mm): 0; Lining | Thickness (mm): 0; Correction Factor: 1.0; Wall Thickness: 0
Type - End Spec1_2 (1 Connection: Round) - Diameter 1 (D1 Ø): 100
Type - Emitters Analytical Parameters - Heat Emission (W): 0; Pressure Drop Type: 1-k value; Emitter Pressure Drop: 0; Flow Valve Type: 1-No Valve; Flow Valve K Value (W/m°C): 0; Return Valve Type: 1-No Valve; Return Valve K Value (W/m°C): 0
Type - Classification - Uniclass2015: Pr_70_60_36_71
Material: M_BSUK_Ventilation
Radiator Panel Parameters - Box | Height: 730; Box | Width: 185; Mounting Width: 25; Connection | End Type: -;
Parameters - Insulation | Surface Area: 0 m2; Lining | Surface Area: 0 m2; Status: BSUK; Air Flow: M
Construction Phase - Phase: New Construction
Name | In | Description | Box | Length | Type | Surface Area (m2) | Center Of Gravity
M-BmvRadiatorpanel-Panel | 01 | 1,SHE-01.GROUND.dgn,Design Model:257385 | 865 | Dimplex QM100RF | 2.3441 | 0.00; 0.00; 0.00;
M-BmvRadiatorpanel-Panel | 01 | 1,SHE-01.GROUND.dgn,Design Model:259679 | 865 | Dimplex QM100RF | 2.3441 | 0.00; 0.00; 0.00;
M-BmvRadiatorpanel-Panel | 01 | 2,SHE-02.MEZZANINE.dgn,Design Model:195011 | 865 | Dimplex QM100RF | 2.3441 | 0.00; 0.00; 0.00;
M-BmvRadiatorpanel-Panel | k/d/l | 2,SHE-02.MEZZANINE.dgn,Design Model:195087 | 865 | Dimplex QM100RF | 2.3441 | 0.00; 0.00; 0.00;
M-BmvRadiatorpanel-Panel | k/d/l | 2,SHE-02.MEZZANINE.dgn,Design Model:195163 | 865 | Dimplex QM100RF | 2.3441 | 0.00; 0.00; 0.00;
M-BmvRadiatorpanel-Panel | 07 | 4,SHE-03.FIRST.dgn,Design Model:351056 | 865 | Dimplex QM100RF | 2.3441 | 0.00; 0.00; 0.00;
M-BmvRadiatorpanel-Panel | k/d/l | 4,SHE-03.FIRST.dgn,Design Model:351132 | 1069 | Dimplex QM150RF | 2.71742 | 534.50; 23.45; 1.08;
M-BmvRadiatorpanel-Panel | k/d/l | 4,SHE-03.FIRST.dgn,Design Model:351832 | 1069 | Dimplex QM150RF | 2.71742 | 534.50; 23.45; 1.08;
M-BmvRadiatorpanel-Panel | studio | 4,SHE-03.FIRST.dgn,Design Model:351908 | 865 | Dimplex QM100RF | 2.3441 | 0.00; 0.00; 0.00;
M-BmvRadiatorpanel-Panel | 05 | 4,SHE-03.FIRST.dgn,Design Model:351984 | 1069 | Dimplex QM150RF | 2.71742 | 534.50; 23.45; 1.08;
M-BmvRadiatorpanel-Panel | studio | 4,SHE-03.FIRST.dgn,Design Model:352060 | 1069 | Dimplex QM150RF | 2.71742 | 534.50; 23.45; 1.08;
M-BmvRadiatorpanel-Panel | k/d/l | 4,SHE-03.FIRST.dgn,Design Model:352136 | 1069 | Dimplex QM150RF | 2.71742 | 534.50; 23.45; 1.08;
M-BmvRadiatorpanel-Panel | 02 | 4,SHE-03.FIRST.dgn,Design Model:352212 | 865 | Dimplex QM100RF | 2.3441 | 0.00; 0.00; 0.00;
M-BmvRadiatorpanel-Panel | 02 | 4,SHE-03.FIRST.dgn,Design Model:352288 | 865 | Dimplex QM100RF | 2.3441 | 0.00; 0.00; 0.00;
M-BmvRadiatorpanel-Panel | k/d/l | 4,SHE-03.FIRST.dgn,Design Model:352364 | 1069 | Dimplex QM150RF | 2.71742 | 534.50; 23.45; 1.08;
M-BmvRadiatorpanel-Panel | 08 | 4,SHE-03.FIRST.dgn,Design Model:352440 | 865 | Dimplex QM100RF | 2.3441 | 0.00; 0.00; 0.00;
M-BmvRadiatorpanel-Panel | 06 | 4,SHE-03.FIRST.dgn,Design Model:352815 | 865 | Dimplex QM100RF | 2.3441 | 0.00; 0.00; 0.00;
M-BmvRadiatorpanel-Panel | bed | 4,SHE-03.FIRST.dgn,Design Model:352967 | 865 | Dimplex QM100RF | 2.3441 | 0.00; 0.00; 0.00;
M-BmvRadiatorpanel-Panel | bed | 4,SHE-03.FIRST.dgn,Design Model:353043 | 865 | Dimplex QM100RF | 2.3441 | 0.00; 0.00; 0.00;
M-BmvRadiatorpanel-Panel | 04 | 4,SHE-03.FIRST.dgn,Design Model:353119 | 1069 | Dimplex QM150RF | 2.71742 | 534.50; 23.45; 1.08;
M-BmvRadiatorpanel-Panel | k/d/l | 6,SHE-05.THIRD.dgn,Design Model:435952 | 1069 | Dimplex QM150RF | 2.71742 | 534.50; 23.45; 1.08;
M-BmvRadiatorpanel-Panel | 21 | 6,SHE-05.THIRD.dgn,Design Model:436028 | 865 | Dimplex QM100RF | 2.3441 | 0.00; 0.00; 0.00;
M-BmvRadiatorpanel-Panel | k/d/l | 6,SHE-05.THIRD.dgn,Design Model:436104 | 1069 | Dimplex QM150RF | 2.71742 | 534.50; 23.45; 1.08;
M-BmvRadiatorpanel-Panel | 20 | 6,SHE-05.THIRD.dgn,Design Model:436180 | 865 | Dimplex QM100RF | 2.3441 | 0.00; 0.00; 0.00;
M-BmvRadiatorpanel-Panel | bed | 6,SHE-05.THIRD.dgn,Design Model:436256 | 865 | Dimplex QM100RF | 2.3441 | 0.00; 0.00; 0.00;
M-BmvRadiatorpanel-Panel | 19 | 6,SHE-05.THIRD.dgn,Design Model:436332 | 1069 | Dimplex QM150RF | 2.71742 | 534.50; 23.45; 1.08;
M-BmvRadiatorpanel-Panel | 18 | 6,SHE-05.THIRD.dgn,Design Model:436408 | 1069 | Dimplex QM150RF | 2.71742 | 534.50; 23.45; 1.08;
M-BmvRadiatorpanel-Panel | bed | 6,SHE-05.THIRD.dgn,Design Model:436484 | 865 | Dimplex QM100RF | 2.3441 | 0.00; 0.00; 0.00;
M-BmvRadiatorpanel-Panel | studio | 6,SHE-05.THIRD.dgn,Design Model:436560 | 1069 | Dimplex QM150RF | 2.71742 | 534.50; 23.45; 1.08;
M-BmvRadiatorpanel-Panel | studio | 6,SHE-05.THIRD.dgn,Design Model:436636 | 865 | Dimplex QM100RF | 2.3441 | 0.00; 0.00; 0.00;
M-BmvRadiatorpanel-Panel | k/d/l | 6,SHE-05.THIRD.dgn,Design Model:436712 | 1069 | Dimplex QM150RF | 2.71742 | 534.50; 23.45; 1.08;
M-BmvRadiatorpanel-Panel | 16 | 6,SHE-05.THIRD.dgn,Design Model:436788 | 865 | Dimplex QM100RF | 2.3441 | 0.00; 0.00; 0.00;
M-BmvRadiatorpanel-Panel | 16 | 6,SHE-05.THIRD.dgn,Design Model:436864 | 865 | Dimplex QM100RF | 2.3441 | 0.00; 0.00; 0.00;
M-BmvRadiatorpanel-Panel | k/d/l | 6,SHE-05.THIRD.dgn,Design Model:436940 | 1069 | Dimplex QM150RF | 2.71742 | 534.50; 23.45; 1.08;
M-BmvRadiatorpanel-Panel | 22 | 6,SHE-05.THIRD.dgn,Design Model:437016 | 865 | Dimplex QM100RF | 2.3441 | 0.00; 0.00; 0.00;
M-BmvRadiatorpanel-Panel | 26 | 7,SHE-06.FOURTH.dgn,Design Model:485803 | 865 | Dimplex QM100RF | 2.3441 | 0.00; 0.00; 0.00;
M-BmvRadiatorpanel-Panel | 26 | 7,SHE-06.FOURTH.dgn,Design Model:485992 | 865 | Dimplex QM100RF | 2.3441 | 0.00; 0.00; 0.00;
M-BmvRadiatorpanel-Panel | 26 | 7,SHE-06.FOURTH.dgn,Design Model:486068 | 865 | Dimplex QM100RF | 2.3441 | 0.00; 0.00; 0.00;
M-BmvRadiatorpanel-Panel | 23 | 7,SHE-06.FOURTH.dgn,Design Model:486144 | 865 | Dimplex QM100RF | 2.3441 | 0.00; 0.00; 0.00;
M-BmvRadiatorpanel-Panel | 23 | 7,SHE-06.FOURTH.dgn,Design Model:486220 | 865 | Dimplex QM100RF | 2.3441 | 0.00; 0.00; 0.00;
M-BmvRadiatorpanel-Panel | 26 | 7,SHE-06.FOURTH.dgn,Design Model:487072 | 580 | Dimplex QM150RF | 1.80702 | 290.00; 34.14; 1.58; | Radiator Panel Parameters - Mounting Length: 580
M-BmvRadiatorpanel-Panel | 23 | 7,SHE-06.FOURTH.dgn,Design Model:487616 | 580 | Dimplex QM150RF | 1.80702 | 290.00; 34.14; 1.58; | Radiator Panel Parameters - Mounting Length: 580
M-BmvRadiatorpanel-Panel | 24 | 7,SHE-06.FOURTH.dgn,Design Model:487692 | 580 | Dimplex QM150RF | 1.80702 | 290.00; 34.14; 1.58; | Radiator Panel Parameters - Mounting Length: 580
M-BmvRadiatorpanel-Panel | 25 | 7,SHE-06.FOURTH.dgn,Design Model:487768 | 580 | Dimplex QM150RF | 1.80702 | 290.00; 34.14; 1.58; | Radiator Panel Parameters - Mounting Length: 580
M-BmvRadiatorpanel-Panel | 25 | 7,SHE-06.FOURTH.dgn,Design Model:487920 | 865 | Dimplex QM100RF | 2.3441 | 0.00; 0.00; 0.00;
M-BmvRadiatorpanel-Panel | 25 | 7,SHE-06.FOURTH.dgn,Design Model:487996 | 865 | Dimplex QM100RF | 2.3441 | 0.00; 0.00; 0.00;
M-BmvRadiatorpanel-Panel | 25 | 7,SHE-06.FOURTH.dgn,Design Model:488072 | 865 | Dimplex QM100RF | 2.3441 | 0.00; 0.00; 0.00;
M-BmvRadiatorpanel-Panel | 24 | 7,SHE-06.FOURTH.dgn,Design Model:488148 | 865 | Dimplex QM100RF | 2.3441 | 0.00; 0.00; 0.00;
M-BmvRadiatorpanel-Panel | 24 | 7,SHE-06.FOURTH.dgn,Design Model:488224 | 865 | Dimplex QM100RF | 2.3441 | 0.00; 0.00; 0.00;
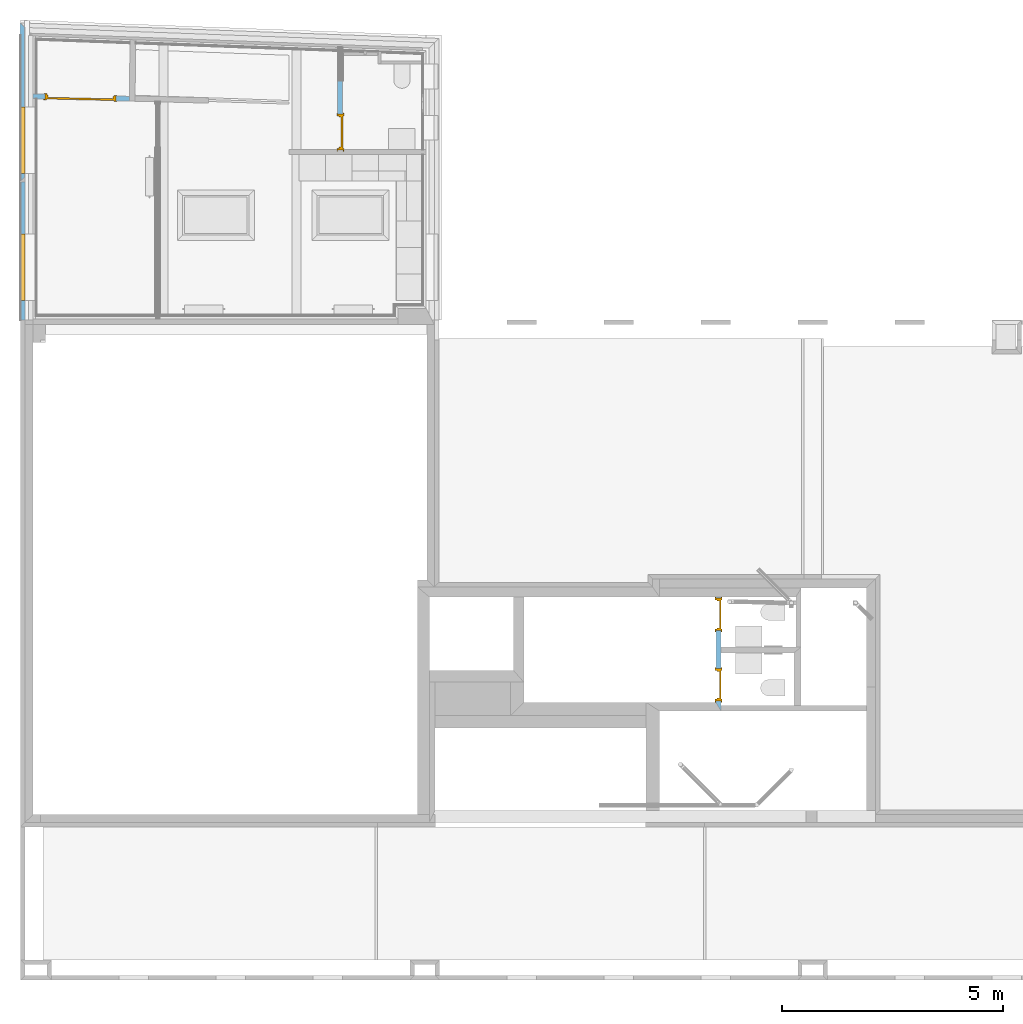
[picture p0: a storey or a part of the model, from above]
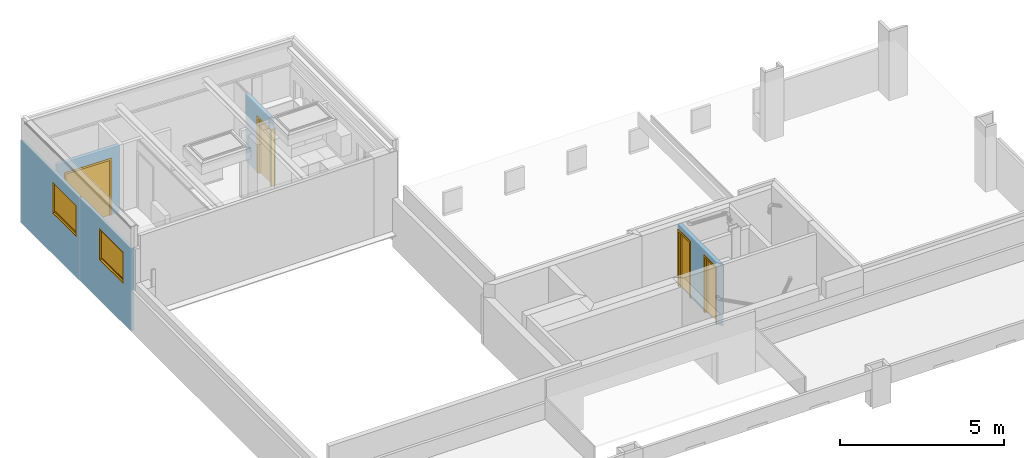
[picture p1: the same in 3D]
Properties of the parts of a building model (IFC2X3), part 8 of 17

# IfcFlowTerminal: M-BmvRadiatorpanel-Panel (66)
Name | In | Description | Box | Length | Type | Surface Area (m2) | Center Of Gravity
M-BmvRadiatorpanel-Panel | 24 | 7,SHE-06.FOURTH.dgn,Design Model:488300 | 865 | Dimplex QM100RF | 2.3441 | 0.00; 0.00; 0.00;
M-BmvRadiatorpanel-Panel | 23 | 7,SHE-06.FOURTH.dgn,Design Model:488376 | 865 | Dimplex QM100RF | 2.3441 | 0.00; 0.00; 0.00;
M-BmvRadiatorpanel-Panel | k/d/l | 18,SHE-04.SECOND.dgn,Design Model:373417 | 1069 | Dimplex QM150RF | 2.71742 | 534.50; 23.45; 1.08;
M-BmvRadiatorpanel-Panel | 14 | 18,SHE-04.SECOND.dgn,Design Model:373493 | 865 | Dimplex QM100RF | 2.3441 | 0.00; 0.00; 0.00;
M-BmvRadiatorpanel-Panel | k/d/l | 18,SHE-04.SECOND.dgn,Design Model:373569 | 1069 | Dimplex QM150RF | 2.71742 | 534.50; 23.45; 1.08;
M-BmvRadiatorpanel-Panel | 13 | 18,SHE-04.SECOND.dgn,Design Model:373645 | 865 | Dimplex QM100RF | 2.3441 | 0.00; 0.00; 0.00;
M-BmvRadiatorpanel-Panel | bed | 18,SHE-04.SECOND.dgn,Design Model:373721 | 865 | Dimplex QM100RF | 2.3441 | 0.00; 0.00; 0.00;
M-BmvRadiatorpanel-Panel | 12 | 18,SHE-04.SECOND.dgn,Design Model:373797 | 1069 | Dimplex QM150RF | 2.71742 | 534.50; 23.45; 1.08;
M-BmvRadiatorpanel-Panel | 11 | 18,SHE-04.SECOND.dgn,Design Model:373873 | 1069 | Dimplex QM150RF | 2.71742 | 534.50; 23.45; 1.08;
M-BmvRadiatorpanel-Panel | bed | 18,SHE-04.SECOND.dgn,Design Model:373949 | 865 | Dimplex QM100RF | 2.3441 | 0.00; 0.00; 0.00;
M-BmvRadiatorpanel-Panel | studio | 18,SHE-04.SECOND.dgn,Design Model:374025 | 1069 | Dimplex QM150RF | 2.71742 | 534.50; 23.45; 1.08;
M-BmvRadiatorpanel-Panel | studio | 18,SHE-04.SECOND.dgn,Design Model:374101 | 865 | Dimplex QM100RF | 2.3441 | 0.00; 0.00; 0.00;
M-BmvRadiatorpanel-Panel | k/d/l | 18,SHE-04.SECOND.dgn,Design Model:374177 | 1069 | Dimplex QM150RF | 2.71742 | 534.50; 23.45; 1.08;
M-BmvRadiatorpanel-Panel | 09 | 18,SHE-04.SECOND.dgn,Design Model:374253 | 865 | Dimplex QM100RF | 2.3441 | 0.00; 0.00; 0.00;
M-BmvRadiatorpanel-Panel | 09 | 18,SHE-04.SECOND.dgn,Design Model:374329 | 865 | Dimplex QM100RF | 2.3441 | 0.00; 0.00; 0.00;
M-BmvRadiatorpanel-Panel | k/d/l | 18,SHE-04.SECOND.dgn,Design Model:374405 | 1069 | Dimplex QM150RF | 2.71742 | 534.50; 23.45; 1.08;
M-BmvRadiatorpanel-Panel | 15 | 18,SHE-04.SECOND.dgn,Design Model:374481 | 865 | Dimplex QM100RF | 2.3441 | 0.00; 0.00; 0.00;

# IfcFlowTerminal: M-RectBarSlotsEndGrille-BarSlots (22)
Type - PredefinedType: REGISTER
Type - Parameters - Insulation | Thickness (mm): 0; Lining | Thickness (mm): 0; Status: New; Pressure Class: Low; Air Flow: Supply; Correction Factor: 1.0; Wall Thickness: 0
Type - End Spec1_1 (1 Connection: Rect) - Width 1 (W1): 400; Depth 1 (D1): 350
Type - Classification - Uniclass2015: Pr_70_65_04_03
Type - Bar Slot Rectangular Grille Parameters - Thickness: 75; Side Distance: 25; Bottom Distance: 25; Inside Width: 350; Inside Depth: 300; No. Of Slots: 10; Slot Thickness: 5; Horizontal: yes; Panel Width: 0; Panel Depth: 0; Panel Thickness: 0; With Damper: no; Damper | Angle: 0; Damper | Thickness: 0; Connection | Offset: 0; Blade Orientation: 2-opposing; View Display: iso; Air Flow Rate: 0; Air Flow Rate Unit: 1-l/s; Center Offset: 0
Material: M_BSUK_Ventilation
Parameters - Insulation | Surface Area: 0 m2; Lining | Surface Area: 0 m2; Status: BSUK; Air Flow: M
End Spec1_1 (1 Connection: Rect) - Width 1 (W1): 800
Bar Slot Rectangular Grille Parameters - AutoSize: 1-symprop; Thickness: 20; Side Distance: 40; Inside Width: 720; Panel Width: 800; Outlet Pressure (Pa): 0
Name | In | Description | Surface Area (m2) | Center Of Gravity | Depth 1 (D1) = Panel Depth | Bottom Distance | Inside Depth
M-RectBarSlotsEndGrille-BarSlots | 25 | 7,SHE-06.FOURTH.dgn,Design Model:503159 | 0.0632 | 14.43; 0.00; 0.00; | 80 | 4 | 72
M-RectBarSlotsEndGrille-BarSlots | 25 | 7,SHE-06.FOURTH.dgn,Design Model:503649 | 0.0632 | 14.43; 0.00; 0.00; | 80 | 4 | 72
M-RectBarSlotsEndGrille-BarSlots | 25 | 7,SHE-06.FOURTH.dgn,Design Model:503727 | 0.0632 | 14.43; 0.00; 0.00; | 80 | 4 | 72
M-RectBarSlotsEndGrille-BarSlots | 3 | 7,SHE-06.FOURTH.dgn,Design Model:503884 | 0.0632 | 14.43; 0.00; 0.00; | 80 | 4 | 72
M-RectBarSlotsEndGrille-BarSlots | 24 | 7,SHE-06.FOURTH.dgn,Design Model:503962 | 0.0632 | 14.43; 0.00; 0.00; | 80 | 4 | 72
M-RectBarSlotsEndGrille-BarSlots | 24 | 7,SHE-06.FOURTH.dgn,Design Model:504040 | 0.0632 | 14.43; 0.00; 0.00; | 80 | 4 | 72
M-RectBarSlotsEndGrille-BarSlots | 5F | 8,SHE-07.FIFTH.dgn,Design Model:291397 | 0.08 | 15.50; 0.00; 0.00; | 100 | 5 | 90
M-RectBarSlotsEndGrille-BarSlots | 5F | 8,SHE-07.FIFTH.dgn,Design Model:292002 | 0.08 | 15.50; 0.00; 0.00; | 100 | 5 | 90
M-RectBarSlotsEndGrille-BarSlots | 5F | 8,SHE-07.FIFTH.dgn,Design Model:292080 | 0.08 | 15.50; 0.00; 0.00; | 100 | 5 | 90
M-RectBarSlotsEndGrille-BarSlots | 5F | 8,SHE-07.FIFTH.dgn,Design Model:292158 | 0.08 | 15.50; 0.00; 0.00; | 100 | 5 | 90
M-RectBarSlotsEndGrille-BarSlots | 5F | 8,SHE-07.FIFTH.dgn,Design Model:292236 | 0.08 | 15.50; 0.00; 0.00; | 100 | 5 | 90
M-RectBarSlotsEndGrille-BarSlots | 5F | 8,SHE-07.FIFTH.dgn,Design Model:292314 | 0.08 | 15.50; 0.00; 0.00; | 100 | 5 | 90
M-RectBarSlotsEndGrille-BarSlots | 5F | 8,SHE-07.FIFTH.dgn,Design Model:292392 | 0.08 | 15.50; 0.00; 0.00; | 100 | 5 | 90
M-RectBarSlotsEndGrille-BarSlots | 5F | 8,SHE-07.FIFTH.dgn,Design Model:292470 | 0.08 | 15.50; 0.00; 0.00; | 100 | 5 | 90
M-RectBarSlotsEndGrille-BarSlots | 5F | 8,SHE-07.FIFTH.dgn,Design Model:292548 | 0.08 | 15.50; 0.00; 0.00; | 100 | 5 | 90
M-RectBarSlotsEndGrille-BarSlots | 5F | 8,SHE-07.FIFTH.dgn,Design Model:292626 | 0.08 | 15.50; 0.00; 0.00; | 100 | 5 | 90
M-RectBarSlotsEndGrille-BarSlots | 5F | 8,SHE-07.FIFTH.dgn,Design Model:292704 | 0.08 | 15.50; 0.00; 0.00; | 100 | 5 | 90
M-RectBarSlotsEndGrille-BarSlots | 5F | 8,SHE-07.FIFTH.dgn,Design Model:292782 | 0.08 | 15.50; 0.00; 0.00; | 100 | 5 | 90
M-RectBarSlotsEndGrille-BarSlots | 5F | 8,SHE-07.FIFTH.dgn,Design Model:292860 | 0.08 | 15.50; 0.00; 0.00; | 100 | 5 | 90
M-RectBarSlotsEndGrille-BarSlots | 5F | 8,SHE-07.FIFTH.dgn,Design Model:292938 | 0.08 | 15.50; 0.00; 0.00; | 100 | 5 | 90
M-RectBarSlotsEndGrille-BarSlots | 5F | 8,SHE-07.FIFTH.dgn,Design Model:293016 | 0.08 | 15.50; 0.00; 0.00; | 100 | 5 | 90
M-RectBarSlotsEndGrille-BarSlots | 5F | 8,SHE-07.FIFTH.dgn,Design Model:293094 | 0.08 | 15.50; 0.00; 0.00; | 100 | 5 | 90

# IfcFlowTerminal: SHE_A-Sink_47x60 (8)
Type - Plumbing Fixture - Connection | Vent: no
Type - Accessibility - Accessibility | Handicap Accessible: no; Has Non-skid Surface: no
Plumbing Fixture - Connection | Cold Water: 0 m; Connection | Hot Water: 0 m; Connection | Waste: 0 m; Mounting | Height: 0 m
Parametric Definition - Parametric | File Type: BXC; Parametric | File Name: K-3206-3
Identification - ID | Description: washbasin; ID | Notes: 600x470mm
Discipline - Discipline: Architectural
Construction Phase - Phase: New Construction
Classification - Uniclass2015: Pr_40_20_96_15
Name | In | Description | ID | Number
00 | M | washbasin :1 ,SHE-01.GROUND.dgn,Design Model:155272 | 00
00 | 0 | washbasin :1 ,SHE-01.GROUND.dgn,Design Model:156320 | 00
00 | 01 | washbasin :2 ,SHE-02.MEZZANINE.dgn,Design Model:120921 | 00
00 | WC | washbasin :2 ,SHE-02.MEZZANINE.dgn,Design Model:120938 | 00
00 | WC | washbasin :2 ,SHE-02.MEZZANINE.dgn,Design Model:120946 | 00
07 | 07 | washbasin :4 ,SHE-03.FIRST.dgn,Design Model:146459 | 07
21 | bath | washbasin :6 ,SHE-05.THIRD.dgn,Design Model:146459 | 21
14 | bath | washbasin :18 ,SHE-04.SECOND.dgn,Design Model:146459 | 14

# IfcFlowTerminal: SHE_A-Sink_47x70 (15)
Type - Plumbing Fixture - Connection | Vent: no
Type - Accessibility - Accessibility | Handicap Accessible: no; Has Non-skid Surface: no
Plumbing Fixture - Connection | Cold Water: 0 m; Connection | Hot Water: 0 m; Connection | Waste: 0 m; Mounting | Height: 0 m
Parametric Definition - Parametric | File Type: BXC; Parametric | File Name: K-3206-3
Identification - ID | Description: washbasin; ID | Notes: 600x470mm
Discipline - Discipline: Architectural
Construction Phase - Phase: New Construction
Classification - Uniclass2015: Pr_40_20_96_15
Name | In | Description | ID | Number
08 | 08 | washbasin :4 ,SHE-03.FIRST.dgn,Design Model:146478 | 08
03 | 03 | washbasin :4 ,SHE-03.FIRST.dgn,Design Model:292382 | 03
04 | bath | washbasin :4 ,SHE-03.FIRST.dgn,Design Model:299615 | 04
05 | 05 | washbasin :4 ,SHE-03.FIRST.dgn,Design Model:300571 | 05
06 | bath | washbasin :4 ,SHE-03.FIRST.dgn,Design Model:327377 | 06
22 | 22 | washbasin :6 ,SHE-05.THIRD.dgn,Design Model:146478 | 22
17 | 17 | washbasin :6 ,SHE-05.THIRD.dgn,Design Model:292382 | 17
18 | bath | washbasin :6 ,SHE-05.THIRD.dgn,Design Model:299615 | 18
19 | 19 | washbasin :6 ,SHE-05.THIRD.dgn,Design Model:300571 | 19
20 | bath | washbasin :6 ,SHE-05.THIRD.dgn,Design Model:327377 | 20
15 | 15 | washbasin :18 ,SHE-04.SECOND.dgn,Design Model:146478 | 15
10 | 10 | washbasin :18 ,SHE-04.SECOND.dgn,Design Model:292382 | 10
11 | bath | washbasin :18 ,SHE-04.SECOND.dgn,Design Model:299615 | 11
12 | 12 | washbasin :18 ,SHE-04.SECOND.dgn,Design Model:300571 | 12
13 | bath | washbasin :18 ,SHE-04.SECOND.dgn,Design Model:327377 | 13

# IfcFlowTerminal: SHE_A-Sink_47x80 (7)
Type - Plumbing Fixture - Connection | Vent: no
Type - Accessibility - Accessibility | Handicap Accessible: no; Has Non-skid Surface: no
Plumbing Fixture - Connection | Cold Water: 0 m; Connection | Hot Water: 0 m; Connection | Waste: 0 m; Mounting | Height: 0 m
Parametric Definition - Parametric | File Type: BXC; Parametric | File Name: K-3206-3
Identification - ID | Description: washbasin; ID | Notes: 600x470mm
Discipline - Discipline: Architectural
Construction Phase - Phase: New Construction
Classification - Uniclass2015: Pr_40_20_96_15
Name | In | Description | ID | Number
01 | 01 | washbasin :1 ,SHE-01.GROUND.dgn,Design Model:141034 | 01
02 | bath | washbasin :4 ,SHE-03.FIRST.dgn,Design Model:146548 | 02
02 | 02 | washbasin :4 ,SHE-03.FIRST.dgn,Design Model:232319 | 02
16 | 16 | washbasin :6 ,SHE-05.THIRD.dgn,Design Model:146548 | 16
16 | 16 | washbasin :6 ,SHE-05.THIRD.dgn,Design Model:232319 | 16
09 | 09 | washbasin :18 ,SHE-04.SECOND.dgn,Design Model:146548 | 09
09 | 09 | washbasin :18 ,SHE-04.SECOND.dgn,Design Model:232319 | 09

# IfcFlowTerminal: SHE_A-Toilet_base (30)
Plumbing Fixture - Connection | Cold Water: 0 m; Connection | Hot Water: 0 m; Connection | Waste: 0 m; Connection | Vent: no; Mounting | Height: 0 m
Parametric Definition - Parametric | File Type: CEL; Parametric | File Name: toilet
Identification - ID | Description: toilet; ID | Notes: 550x370mm
Discipline - Discipline: Architectural
Construction Phase - Phase: New Construction
Classification - Uniclass2015: Pr_40_20_06_11
Accessibility - Accessibility | Handicap Accessible: no; Has Non-skid Surface: no
Name | In | Description | ID | Number
00 | 0 | toilet :1 ,SHE-01.GROUND.dgn,Design Model:155284 | 00
00 | 0 | toilet :1 ,SHE-01.GROUND.dgn,Design Model:155702 | 00
01 | 01 | toilet :1 ,SHE-01.GROUND.dgn,Design Model:183802 | 01
00 | 01 | toilet :2 ,SHE-02.MEZZANINE.dgn,Design Model:120912 | 00
00 | WC | toilet :2 ,SHE-02.MEZZANINE.dgn,Design Model:120929 | 00
00 | WC | toilet :2 ,SHE-02.MEZZANINE.dgn,Design Model:120954 | 00
08 | 08 | toilet :4 ,SHE-03.FIRST.dgn,Design Model:146467 | 08
03 | 03 | toilet :4 ,SHE-03.FIRST.dgn,Design Model:146486 | 03
02 | bath | toilet :4 ,SHE-03.FIRST.dgn,Design Model:146539 | 02
04 | 04 | toilet :4 ,SHE-03.FIRST.dgn,Design Model:146503 | 04
02 | ensuite | toilet :4 ,SHE-03.FIRST.dgn,Design Model:229416 | 02
07 | 07 | toilet :4 ,SHE-03.FIRST.dgn,Design Model:270354 | 07
05 | 05 | toilet :4 ,SHE-03.FIRST.dgn,Design Model:300522 | 05
06 | 06 | toilet :4 ,SHE-03.FIRST.dgn,Design Model:327218 | 06
22 | 22 | toilet :6 ,SHE-05.THIRD.dgn,Design Model:146467 | 22
17 | bath | toilet :6 ,SHE-05.THIRD.dgn,Design Model:146486 | 17
16 | bath | toilet :6 ,SHE-05.THIRD.dgn,Design Model:146539 | 16
18 | 18 | toilet :6 ,SHE-05.THIRD.dgn,Design Model:146503 | 18
16 | ensuite | toilet :6 ,SHE-05.THIRD.dgn,Design Model:229416 | 16
21 | 21 | toilet :6 ,SHE-05.THIRD.dgn,Design Model:270354 | 21
19 | 19 | toilet :6 ,SHE-05.THIRD.dgn,Design Model:300522 | 19
20 | 20 | toilet :6 ,SHE-05.THIRD.dgn,Design Model:327218 | 20
15 | 15 | toilet :18 ,SHE-04.SECOND.dgn,Design Model:146467 | 15
10 | 10 | toilet :18 ,SHE-04.SECOND.dgn,Design Model:146486 | 10
09 | 09 | toilet :18 ,SHE-04.SECOND.dgn,Design Model:146539 | 09
11 | bath | toilet :18 ,SHE-04.SECOND.dgn,Design Model:146503 | 11
09 | 09 | toilet :18 ,SHE-04.SECOND.dgn,Design Model:229416 | 09
14 | 14 | toilet :18 ,SHE-04.SECOND.dgn,Design Model:270354 | 14
12 | 12 | toilet :18 ,SHE-04.SECOND.dgn,Design Model:300522 | 12
13 | 13 | toilet :18 ,SHE-04.SECOND.dgn,Design Model:327218 | 13

# IfcFurnishingElement: SHE_A-Cupboard_Electro (26)
Type - Pset_FurnitureTypeCommon - NominalDepth: 0.25 m; NominalHeight: 2.5 m; NominalLength: 0.7 m
Type - Discipline - Discipline: Architectural
Type - Classification - Uniclass2015: Pr_40_30_78
Type - Casework Parameters - Casework | Type: Tall
Type - Casework - Parametric | File Type: BXF; Parametric | File Name: 01-TallUK; Dimension | Width: 0.7 m; Dimension | Height: 2.5 m; Dimension | Depth: 0.25 m
Casework - Dimension | Width: 0.25 m
Name | In | Description | ID | Number
01 | corridor | 1 ,SHE-01.GROUND.dgn,Design Model:263240 | 01
06 | 06 | 4 ,SHE-03.FIRST.dgn,Design Model:135481 | 06
08 | 08 | 4 ,SHE-03.FIRST.dgn,Design Model:135495 | 08
02 | storage | 4 ,SHE-03.FIRST.dgn,Design Model:135502 | 02
03 | 03 | 4 ,SHE-03.FIRST.dgn,Design Model:135523 | 03
07 | storage | 4 ,SHE-03.FIRST.dgn,Design Model:272307 | 07
04 | 04 | 4 ,SHE-03.FIRST.dgn,Design Model:288350 | 04
05 | 05 | 4 ,SHE-03.FIRST.dgn,Design Model:302316 | 05
20 | 20 | 6 ,SHE-05.THIRD.dgn,Design Model:135481 | 20
22 | 22 | 6 ,SHE-05.THIRD.dgn,Design Model:135495 | 22
16 | storage | 6 ,SHE-05.THIRD.dgn,Design Model:135502 | 16
17 | storage | 6 ,SHE-05.THIRD.dgn,Design Model:135523 | 17
21 | 21 | 6 ,SHE-05.THIRD.dgn,Design Model:272307 | 21
18 | 18 | 6 ,SHE-05.THIRD.dgn,Design Model:288350 | 18
19 | 19 | 6 ,SHE-05.THIRD.dgn,Design Model:302316 | 19
26 | 26 | 7 ,SHE-06.FOURTH.dgn,Design Model:490931 | 26
25 | 25 | 7 ,SHE-06.FOURTH.dgn,Design Model:490940 | 25
24 | storage | 7 ,SHE-06.FOURTH.dgn,Design Model:490947 | 24
23 | 23 | 7 ,SHE-06.FOURTH.dgn,Design Model:490954 | 23
13 | 13 | 18 ,SHE-04.SECOND.dgn,Design Model:135481 | 13
15 | 15 | 18 ,SHE-04.SECOND.dgn,Design Model:135495 | 15
09 | 09 | 18 ,SHE-04.SECOND.dgn,Design Model:135502 | 09
10 | 10 | 18 ,SHE-04.SECOND.dgn,Design Model:135523 | 10
14 | storage | 18 ,SHE-04.SECOND.dgn,Design Model:272307 | 14
11 | storage | 18 ,SHE-04.SECOND.dgn,Design Model:288350 | 11
12 | storage | 18 ,SHE-04.SECOND.dgn,Design Model:302316 | 12

# IfcFurnishingElement: SHE_A-Kitchenunit-Base (120)
Type - Pset_FurnitureTypeCommon - NominalDepth: 0.6 m; NominalHeight: 0.86 m; NominalLength: 0.6 m
Type - Discipline - Discipline: Architectural
Type - Classification - Uniclass2015: Pr_40_30_78
Type - Casework Parameters - Casework | Type: Base
Type - Casework - Parametric | File Type: BXF; Parametric | File Name: 01-BaseUK; Dimension | Width: 0.6 m; Dimension | Height: 0.86 m; Dimension | Depth: 0.6 m
Material: A_BSUK_StorageScreening_Ffe
Name | In | Description | ID | Number
01 | 01 | 2 ,SHE-02.MEZZANINE.dgn,Design Model:120072 | 01
01 | 01 | 2 ,SHE-02.MEZZANINE.dgn,Design Model:120083 | 01
01 | 01 | 2 ,SHE-02.MEZZANINE.dgn,Design Model:120092 | 01
01 | 01 | 2 ,SHE-02.MEZZANINE.dgn,Design Model:120100 | 01
01 | 01 | 2 ,SHE-02.MEZZANINE.dgn,Design Model:147775 | 01
01 | 01 | 2 ,SHE-02.MEZZANINE.dgn,Design Model:226182 | 01
06 | 06 | 4 ,SHE-03.FIRST.dgn,Design Model:134902 | 06
06 | 06 | 4 ,SHE-03.FIRST.dgn,Design Model:134910 | 06
06 | 06 | 4 ,SHE-03.FIRST.dgn,Design Model:134918 | 06
08 | 08 | 4 ,SHE-03.FIRST.dgn,Design Model:134968 | 08
08 | 08 | 4 ,SHE-03.FIRST.dgn,Design Model:134976 | 08
08 | 08 | 4 ,SHE-03.FIRST.dgn,Design Model:134977 | 08
08 | 08 | 4 ,SHE-03.FIRST.dgn,Design Model:134978 | 08
08 | 08 | 4 ,SHE-03.FIRST.dgn,Design Model:134979 | 08
08 | 08 | 4 ,SHE-03.FIRST.dgn,Design Model:135001 | 08
02 | k/d/l | 4 ,SHE-03.FIRST.dgn,Design Model:135003 | 02
02 | k/d/l | 4 ,SHE-03.FIRST.dgn,Design Model:135011 | 02
02 | k/d/l | 4 ,SHE-03.FIRST.dgn,Design Model:135019 | 02
02 | 02 | 4 ,SHE-03.FIRST.dgn,Design Model:135027 | 02
02 | 02 | 4 ,SHE-03.FIRST.dgn,Design Model:135035 | 02
03 | 03 | 4 ,SHE-03.FIRST.dgn,Design Model:135088 | 03
03 | 03 | 4 ,SHE-03.FIRST.dgn,Design Model:135176 | 03
03 | 03 | 4 ,SHE-03.FIRST.dgn,Design Model:135226 | 03
03 | 03 | 4 ,SHE-03.FIRST.dgn,Design Model:135269 | 03
04 | k/d/l | 4 ,SHE-03.FIRST.dgn,Design Model:135326 | 04
04 | k/d/l | 4 ,SHE-03.FIRST.dgn,Design Model:135405 | 04
04 | k/d/l | 4 ,SHE-03.FIRST.dgn,Design Model:135455 | 04
05 | 05 | 4 ,SHE-03.FIRST.dgn,Design Model:135463 | 05
05 | 05 | 4 ,SHE-03.FIRST.dgn,Design Model:135471 | 05
05 | 05 | 4 ,SHE-03.FIRST.dgn,Design Model:135479 | 05
07 | k/d/l | 4 ,SHE-03.FIRST.dgn,Design Model:186406 | 07
07 | k/d/l | 4 ,SHE-03.FIRST.dgn,Design Model:186431 | 07
07 | 07 | 4 ,SHE-03.FIRST.dgn,Design Model:254800 | 07 | Casework - Dimension | Width: 0.9 m
07 | k/d/l | 4 ,SHE-03.FIRST.dgn,Design Model:272203 | 07
07 | k/d/l | 4 ,SHE-03.FIRST.dgn,Design Model:272232 | 07
07 | k/d/l | 4 ,SHE-03.FIRST.dgn,Design Model:272292 | 07
20 | k/d/l | 6 ,SHE-05.THIRD.dgn,Design Model:134902 | 20
20 | k/d/l | 6 ,SHE-05.THIRD.dgn,Design Model:134910 | 20
20 | k/d/l | 6 ,SHE-05.THIRD.dgn,Design Model:134918 | 20
22 | k/d/l | 6 ,SHE-05.THIRD.dgn,Design Model:134968 | 22
22 | k/d/l | 6 ,SHE-05.THIRD.dgn,Design Model:134976 | 22
22 | k/d/l | 6 ,SHE-05.THIRD.dgn,Design Model:134977 | 22
22 | k/d/l | 6 ,SHE-05.THIRD.dgn,Design Model:134978 | 22
22 | k/d/l | 6 ,SHE-05.THIRD.dgn,Design Model:134979 | 22
22 | k/d/l | 6 ,SHE-05.THIRD.dgn,Design Model:135001 | 22
16 | k/d/l | 6 ,SHE-05.THIRD.dgn,Design Model:135003 | 16
16 | k/d/l | 6 ,SHE-05.THIRD.dgn,Design Model:135011 | 16
16 | k/d/l | 6 ,SHE-05.THIRD.dgn,Design Model:135019 | 16
16 | k/d/l | 6 ,SHE-05.THIRD.dgn,Design Model:135027 | 16
16 | k/d/l | 6 ,SHE-05.THIRD.dgn,Design Model:135035 | 16
17 | studio | 6 ,SHE-05.THIRD.dgn,Design Model:135088 | 17
17 | studio | 6 ,SHE-05.THIRD.dgn,Design Model:135176 | 17
17 | studio | 6 ,SHE-05.THIRD.dgn,Design Model:135226 | 17
17 | studio | 6 ,SHE-05.THIRD.dgn,Design Model:135269 | 17
18 | 18 | 6 ,SHE-05.THIRD.dgn,Design Model:135326 | 18
18 | 18 | 6 ,SHE-05.THIRD.dgn,Design Model:135405 | 18
18 | 18 | 6 ,SHE-05.THIRD.dgn,Design Model:135455 | 18
19 | 19 | 6 ,SHE-05.THIRD.dgn,Design Model:135463 | 19
19 | 19 | 6 ,SHE-05.THIRD.dgn,Design Model:135471 | 19
19 | 19 | 6 ,SHE-05.THIRD.dgn,Design Model:135479 | 19
21 | 21 | 6 ,SHE-05.THIRD.dgn,Design Model:186406 | 21
21 | 21 | 6 ,SHE-05.THIRD.dgn,Design Model:186431 | 21
21 | 21 | 6 ,SHE-05.THIRD.dgn,Design Model:254800 | 21 | Casework - Dimension | Width: 0.9 m
21 | 21 | 6 ,SHE-05.THIRD.dgn,Design Model:272203 | 21
21 | 21 | 6 ,SHE-05.THIRD.dgn,Design Model:272232 | 21
21 | 21 | 6 ,SHE-05.THIRD.dgn,Design Model:272292 | 21
23 | k/d/l | 8 ,SHE-07.FIFTH.dgn,Design Model:157111 | 23
23 | k/d/l | 8 ,SHE-07.FIFTH.dgn,Design Model:157192 | 23
23 | k/d/l | 8 ,SHE-07.FIFTH.dgn,Design Model:157200 | 23
23 | k/d/l | 8 ,SHE-07.FIFTH.dgn,Design Model:157208 | 23
23 | k/d/l | 8 ,SHE-07.FIFTH.dgn,Design Model:157232 | 23
23 | k/d/l | 8 ,SHE-07.FIFTH.dgn,Design Model:157255 | 23
23 | 23 | 8 ,SHE-07.FIFTH.dgn,Design Model:157278 | 23
24 | k/d/l | 8 ,SHE-07.FIFTH.dgn,Design Model:157287 | 24
24 | k/d/l | 8 ,SHE-07.FIFTH.dgn,Design Model:157295 | 24
24 | k/d/l | 8 ,SHE-07.FIFTH.dgn,Design Model:157303 | 24
24 | k/d/l | 8 ,SHE-07.FIFTH.dgn,Design Model:157311 | 24
24 | k/d/l | 8 ,SHE-07.FIFTH.dgn,Design Model:157335 | 24
24 | 24 | 8 ,SHE-07.FIFTH.dgn,Design Model:157358 | 24
24 | 24 | 8 ,SHE-07.FIFTH.dgn,Design Model:157381 | 24
25 | 25 | 8 ,SHE-07.FIFTH.dgn,Design Model:157426 | 25
25 | k/d/l | 8 ,SHE-07.FIFTH.dgn,Design Model:157470 | 25
25 | k/d/l | 8 ,SHE-07.FIFTH.dgn,Design Model:157523 | 25
25 | 25 | 8 ,SHE-07.FIFTH.dgn,Design Model:157546 | 25
25 | 25 | 8 ,SHE-07.FIFTH.dgn,Design Model:157569 | 25
26 | 26 | 8 ,SHE-07.FIFTH.dgn,Design Model:157637 | 26
26 | k/d/l | 8 ,SHE-07.FIFTH.dgn,Design Model:157645 | 26
26 | k/d/l | 8 ,SHE-07.FIFTH.dgn,Design Model:157653 | 26
26 | 26 | 8 ,SHE-07.FIFTH.dgn,Design Model:157661 | 26
26 | 26 | 8 ,SHE-07.FIFTH.dgn,Design Model:157669 | 26
13 | 13 | 18 ,SHE-04.SECOND.dgn,Design Model:134902 | 13
13 | 13 | 18 ,SHE-04.SECOND.dgn,Design Model:134910 | 13
13 | 13 | 18 ,SHE-04.SECOND.dgn,Design Model:134918 | 13
15 | k/d/l | 18 ,SHE-04.SECOND.dgn,Design Model:134968 | 15
15 | k/d/l | 18 ,SHE-04.SECOND.dgn,Design Model:134976 | 15
15 | k/d/l | 18 ,SHE-04.SECOND.dgn,Design Model:134977 | 15
15 | k/d/l | 18 ,SHE-04.SECOND.dgn,Design Model:134978 | 15
15 | k/d/l | 18 ,SHE-04.SECOND.dgn,Design Model:134979 | 15
15 | k/d/l | 18 ,SHE-04.SECOND.dgn,Design Model:135001 | 15
09 | 09 | 18 ,SHE-04.SECOND.dgn,Design Model:135003 | 09
09 | 09 | 18 ,SHE-04.SECOND.dgn,Design Model:135011 | 09
09 | 09 | 18 ,SHE-04.SECOND.dgn,Design Model:135019 | 09
09 | 09 | 18 ,SHE-04.SECOND.dgn,Design Model:135027 | 09
09 | 09 | 18 ,SHE-04.SECOND.dgn,Design Model:135035 | 09
10 | 10 | 18 ,SHE-04.SECOND.dgn,Design Model:135088 | 10
10 | 10 | 18 ,SHE-04.SECOND.dgn,Design Model:135176 | 10
10 | 10 | 18 ,SHE-04.SECOND.dgn,Design Model:135226 | 10
10 | 10 | 18 ,SHE-04.SECOND.dgn,Design Model:135269 | 10
11 | k/d/l | 18 ,SHE-04.SECOND.dgn,Design Model:135326 | 11
11 | k/d/l | 18 ,SHE-04.SECOND.dgn,Design Model:135405 | 11
11 | k/d/l | 18 ,SHE-04.SECOND.dgn,Design Model:135455 | 11
12 | k/d/l | 18 ,SHE-04.SECOND.dgn,Design Model:135463 | 12
12 | k/d/l | 18 ,SHE-04.SECOND.dgn,Design Model:135471 | 12
12 | k/d/l | 18 ,SHE-04.SECOND.dgn,Design Model:135479 | 12
14 | k/d/l | 18 ,SHE-04.SECOND.dgn,Design Model:186406 | 14
14 | k/d/l | 18 ,SHE-04.SECOND.dgn,Design Model:186431 | 14
14 | k/d/l | 18 ,SHE-04.SECOND.dgn,Design Model:254800 | 14 | Casework - Dimension | Width: 0.9 m
14 | k/d/l | 18 ,SHE-04.SECOND.dgn,Design Model:272203 | 14
14 | k/d/l | 18 ,SHE-04.SECOND.dgn,Design Model:272232 | 14
14 | k/d/l | 18 ,SHE-04.SECOND.dgn,Design Model:272292 | 14

# IfcFurnishingElement: SHE_A-Kitchenunit-Base 37x60 (9)
Type - Pset_FurnitureTypeCommon - NominalDepth: 0.37 m; NominalHeight: 0.86 m; NominalLength: 0.6 m
Type - Discipline - Discipline: Architectural
Type - Classification - Uniclass2015: Pr_40_30_78
Type - Casework Parameters - Casework | Type: Base
Type - Casework - Parametric | File Type: BXF; Parametric | File Name: 01-BaseUK; Dimension | Width: 0.6 m; Dimension | Height: 0.86 m; Dimension | Depth: 0.37 m
Material: A_BSUK_StorageScreening_Ffe
Name | In | Description | ID | Number
23 | k/d/l | 8 ,SHE-07.FIFTH.dgn,Design Model:157136 | 23
23 | k/d/l | 8 ,SHE-07.FIFTH.dgn,Design Model:157233 | 23
23 | k/d/l | 8 ,SHE-07.FIFTH.dgn,Design Model:157256 | 23
24 | k/d/l | 8 ,SHE-07.FIFTH.dgn,Design Model:157313 | 24
24 | k/d/l | 8 ,SHE-07.FIFTH.dgn,Design Model:157336 | 24
24 | k/d/l | 8 ,SHE-07.FIFTH.dgn,Design Model:157359 | 24
25 | k/d/l | 8 ,SHE-07.FIFTH.dgn,Design Model:157522 | 25
25 | 25 | 8 ,SHE-07.FIFTH.dgn,Design Model:157545 | 25
25 | 25 | 8 ,SHE-07.FIFTH.dgn,Design Model:157568 | 25

# IfcFurnishingElement: SHE_A-Kitchenunit-Base60x30, 25
In: 25
Type - Pset_FurnitureTypeCommon - NominalDepth: 0.6 m; NominalHeight: 0.86 m; NominalLength: 0.3 m
Type - Discipline - Discipline: Architectural
Type - Classification - Uniclass2015: Pr_40_30_78
Type - Casework Parameters - Casework | Type: Base
Type - Casework - Parametric | File Type: BXF; Parametric | File Name: 01-BaseUK; Dimension | Width: 0.3 m; Dimension | Height: 0.86 m; Dimension | Depth: 0.6 m
Description: 8 ,SHE-07.FIFTH.dgn,Design Model:158601; Material: A_BSUK_StorageScreening_Ffe
Identification - ID | Number: 25

# IfcFurnishingElement: SHE_A-Kitchenunit-Base60x45 (10)
Type - Pset_FurnitureTypeCommon - NominalDepth: 0.6 m; NominalHeight: 0.86 m; NominalLength: 0.45 m
Type - Discipline - Discipline: Architectural
Type - Classification - Uniclass2015: Pr_40_30_78
Type - Casework Parameters - Casework | Type: Base
Type - Casework - Parametric | File Type: BXF; Parametric | File Name: 01-BaseUK; Dimension | Width: 0.45 m; Dimension | Height: 0.86 m; Dimension | Depth: 0.6 m
Material: A_BSUK_StorageScreening_Ffe
Name | In | Description | ID | Number
04 | k/d/l | 4 ,SHE-03.FIRST.dgn,Design Model:135593 | 04
05 | 05 | 4 ,SHE-03.FIRST.dgn,Design Model:135643 | 05
06 | 06 | 4 ,SHE-03.FIRST.dgn,Design Model:135651 | 06
18 | 18 | 6 ,SHE-05.THIRD.dgn,Design Model:135593 | 18
19 | 19 | 6 ,SHE-05.THIRD.dgn,Design Model:135643 | 19
20 | k/d/l | 6 ,SHE-05.THIRD.dgn,Design Model:135651 | 20
25 | k/d/l | 8 ,SHE-07.FIFTH.dgn,Design Model:158593 | 25
11 | k/d/l | 18 ,SHE-04.SECOND.dgn,Design Model:135593 | 11
12 | k/d/l | 18 ,SHE-04.SECOND.dgn,Design Model:135643 | 12
13 | 13 | 18 ,SHE-04.SECOND.dgn,Design Model:135651 | 13

# IfcFurnishingElement: SHE_A-Kitchenunit-Base60x75, 25
In: k/d/l
Type - Pset_FurnitureTypeCommon - NominalDepth: 0.6 m; NominalHeight: 0.86 m; NominalLength: 0.75 m
Type - Discipline - Discipline: Architectural
Type - Classification - Uniclass2015: Pr_40_30_78
Type - Casework Parameters - Casework | Type: Base
Type - Casework - Parametric | File Type: BXF; Parametric | File Name: 01-BaseUK; Dimension | Width: 0.75 m; Dimension | Height: 0.86 m; Dimension | Depth: 0.6 m
Description: 8 ,SHE-07.FIFTH.dgn,Design Model:158585; Material: A_BSUK_StorageScreening_Ffe
Identification - ID | Number: 25

# IfcFurnishingElement: SHE_A-Kitchenunit-Base60x90, 01
In: 01
Type - Pset_FurnitureTypeCommon - NominalDepth: 0.6 m; NominalHeight: 0.86 m; NominalLength: 0.9 m
Type - Discipline - Discipline: Architectural
Type - Classification - Uniclass2015: Pr_40_30_78
Type - Casework Parameters - Casework | Type: Base
Type - Casework - Parametric | File Type: BXF; Parametric | File Name: 01-BaseUK; Dimension | Width: 0.9 m; Dimension | Height: 0.86 m; Dimension | Depth: 0.6 m
Description: 2 ,SHE-02.MEZZANINE.dgn,Design Model:120963; Material: A_BSUK_StorageScreening_Ffe
Identification - ID | Number: 01

# IfcFurnishingElement: SHE_A-Kitchenunit-Tall (35)
Type - Pset_FurnitureTypeCommon - NominalDepth: 0.6 m; NominalHeight: 2.26 m; NominalLength: 0.6 m
Type - Discipline - Discipline: Architectural
Type - Classification - Uniclass2015: Pr_40_30_78
Type - Casework Parameters - Casework | Type: Tall
Type - Casework - Parametric | File Type: BXF; Parametric | File Name: 01-TallUK; Dimension | Width: 0.6 m; Dimension | Height: 2.26 m; Dimension | Depth: 0.6 m
Material: A_BSUK_StorageScreening_Ffe
Name | In | Description | ID | Number
01 | 01 | 2 ,SHE-02.MEZZANINE.dgn,Design Model:120048 | 01
01 | 01 | 2 ,SHE-02.MEZZANINE.dgn,Design Model:120091 | 01
06 | k/d/l | 4 ,SHE-03.FIRST.dgn,Design Model:134878 | 06
08 | k/d/l | 4 ,SHE-03.FIRST.dgn,Design Model:134967 | 08
02 | 02 | 4 ,SHE-03.FIRST.dgn,Design Model:135002 | 02
02 | k/d/l | 4 ,SHE-03.FIRST.dgn,Design Model:135043 | 02
03 | 03 | 4 ,SHE-03.FIRST.dgn,Design Model:135126 | 03
04 | k/d/l | 4 ,SHE-03.FIRST.dgn,Design Model:135355 | 04
05 | 05 | 4 ,SHE-03.FIRST.dgn,Design Model:135480 | 05
07 | k/d/l | 4 ,SHE-03.FIRST.dgn,Design Model:186405 | 07
20 | 20 | 6 ,SHE-05.THIRD.dgn,Design Model:134878 | 20
22 | 22 | 6 ,SHE-05.THIRD.dgn,Design Model:134967 | 22
16 | 16 | 6 ,SHE-05.THIRD.dgn,Design Model:135002 | 16
16 | k/d/l | 6 ,SHE-05.THIRD.dgn,Design Model:135043 | 16
17 | studio | 6 ,SHE-05.THIRD.dgn,Design Model:135126 | 17
18 | k/d/l | 6 ,SHE-05.THIRD.dgn,Design Model:135355 | 18
19 | 19 | 6 ,SHE-05.THIRD.dgn,Design Model:135480 | 19
21 | 21 | 6 ,SHE-05.THIRD.dgn,Design Model:186405 | 21
23 | 23 | 8 ,SHE-07.FIFTH.dgn,Design Model:157080 | 23
23 | 23 | 8 ,SHE-07.FIFTH.dgn,Design Model:157209 | 23
24 | 24 | 8 ,SHE-07.FIFTH.dgn,Design Model:157279 | 24
24 | 24 | 8 ,SHE-07.FIFTH.dgn,Design Model:157312 | 24
25 | 25 | 8 ,SHE-07.FIFTH.dgn,Design Model:157441 | 25
26 | 26 | 8 ,SHE-07.FIFTH.dgn,Design Model:157584 | 26
26 | 26 | 8 ,SHE-07.FIFTH.dgn,Design Model:157599 | 26
26 | 26 | 8 ,SHE-07.FIFTH.dgn,Design Model:157614 | 26
26 | 26 | 8 ,SHE-07.FIFTH.dgn,Design Model:157629 | 26
13 | 13 | 18 ,SHE-04.SECOND.dgn,Design Model:134878 | 13
15 | k/d/l | 18 ,SHE-04.SECOND.dgn,Design Model:134967 | 15
09 | 09 | 18 ,SHE-04.SECOND.dgn,Design Model:135002 | 09
09 | 09 | 18 ,SHE-04.SECOND.dgn,Design Model:135043 | 09
10 | 10 | 18 ,SHE-04.SECOND.dgn,Design Model:135126 | 10
11 | k/d/l | 18 ,SHE-04.SECOND.dgn,Design Model:135355 | 11
12 | k/d/l | 18 ,SHE-04.SECOND.dgn,Design Model:135480 | 12
14 | k/d/l | 18 ,SHE-04.SECOND.dgn,Design Model:186405 | 14

# IfcFurnishingElement: SHE_A-Kitchenunit-Wall (101)
Type - Pset_FurnitureTypeCommon - NominalDepth: 0.37 m; NominalHeight: 0.76 m; NominalLength: 0.6 m
Type - Discipline - Discipline: Architectural
Type - Classification - Uniclass2015: Pr_40_30_78
Type - Casework Parameters - Casework | Type: Wall
Type - Casework - Parametric | File Type: BXF; Parametric | File Name: 01-WallUK; Dimension | Width: 0.6 m; Dimension | Height: 0.76 m; Dimension | Depth: 0.37 m
Casework - Dimension | Width: 0.37 m; Dimension | Depth: 0.6 m
Name | In | Description | ID | Number
01 | k/d/l | 2 ,SHE-02.MEZZANINE.dgn,Design Model:120073 | 01
01 | 01 | 2 ,SHE-02.MEZZANINE.dgn,Design Model:120084 | 01
06 | k/d/l | 4 ,SHE-03.FIRST.dgn,Design Model:134903 | 06
06 | k/d/l | 4 ,SHE-03.FIRST.dgn,Design Model:134911 | 06
06 | k/d/l | 4 ,SHE-03.FIRST.dgn,Design Model:134919 | 06
08 | k/d/l | 4 ,SHE-03.FIRST.dgn,Design Model:134969 | 08
08 | k/d/l | 4 ,SHE-03.FIRST.dgn,Design Model:134980 | 08
08 | k/d/l | 4 ,SHE-03.FIRST.dgn,Design Model:134987 | 08
08 | k/d/l | 4 ,SHE-03.FIRST.dgn,Design Model:134994 | 08
02 | 02 | 4 ,SHE-03.FIRST.dgn,Design Model:135004 | 02
02 | 02 | 4 ,SHE-03.FIRST.dgn,Design Model:135012 | 02
02 | 02 | 4 ,SHE-03.FIRST.dgn,Design Model:135020 | 02
02 | 02 | 4 ,SHE-03.FIRST.dgn,Design Model:135028 | 02
02 | 02 | 4 ,SHE-03.FIRST.dgn,Design Model:135036 | 02
03 | studio | 4 ,SHE-03.FIRST.dgn,Design Model:135089 | 03
03 | studio | 4 ,SHE-03.FIRST.dgn,Design Model:135127 | 03
03 | studio | 4 ,SHE-03.FIRST.dgn,Design Model:135177 | 03
03 | studio | 4 ,SHE-03.FIRST.dgn,Design Model:135270 | 03
04 | 04 | 4 ,SHE-03.FIRST.dgn,Design Model:135277 | 04
04 | 04 | 4 ,SHE-03.FIRST.dgn,Design Model:135356 | 04
04 | k/d/l | 4 ,SHE-03.FIRST.dgn,Design Model:135406 | 04
05 | k/d/l | 4 ,SHE-03.FIRST.dgn,Design Model:135456 | 05
05 | k/d/l | 4 ,SHE-03.FIRST.dgn,Design Model:135464 | 05
05 | k/d/l | 4 ,SHE-03.FIRST.dgn,Design Model:135472 | 05
07 | k/d/l | 4 ,SHE-03.FIRST.dgn,Design Model:186432 | 07
07 | k/d/l | 4 ,SHE-03.FIRST.dgn,Design Model:255109 | 07
07 | k/d/l | 4 ,SHE-03.FIRST.dgn,Design Model:255116 | 07
07 | k/d/l | 4 ,SHE-03.FIRST.dgn,Design Model:272204 | 07
07 | k/d/l | 4 ,SHE-03.FIRST.dgn,Design Model:272233 | 07
07 | k/d/l | 4 ,SHE-03.FIRST.dgn,Design Model:272300 | 07
20 | 20 | 6 ,SHE-05.THIRD.dgn,Design Model:134903 | 20
20 | 20 | 6 ,SHE-05.THIRD.dgn,Design Model:134911 | 20
20 | 20 | 6 ,SHE-05.THIRD.dgn,Design Model:134919 | 20
22 | 22 | 6 ,SHE-05.THIRD.dgn,Design Model:134969 | 22
22 | 22 | 6 ,SHE-05.THIRD.dgn,Design Model:134980 | 22
22 | 22 | 6 ,SHE-05.THIRD.dgn,Design Model:134987 | 22
22 | 22 | 6 ,SHE-05.THIRD.dgn,Design Model:134994 | 22
16 | k/d/l | 6 ,SHE-05.THIRD.dgn,Design Model:135004 | 16
16 | k/d/l | 6 ,SHE-05.THIRD.dgn,Design Model:135012 | 16
16 | k/d/l | 6 ,SHE-05.THIRD.dgn,Design Model:135020 | 16
16 | 16 | 6 ,SHE-05.THIRD.dgn,Design Model:135028 | 16
16 | 16 | 6 ,SHE-05.THIRD.dgn,Design Model:135036 | 16
17 | studio | 6 ,SHE-05.THIRD.dgn,Design Model:135089 | 17
17 | studio | 6 ,SHE-05.THIRD.dgn,Design Model:135127 | 17
17 | studio | 6 ,SHE-05.THIRD.dgn,Design Model:135177 | 17
17 | studio | 6 ,SHE-05.THIRD.dgn,Design Model:135270 | 17
18 | 18 | 6 ,SHE-05.THIRD.dgn,Design Model:135277 | 18
18 | 18 | 6 ,SHE-05.THIRD.dgn,Design Model:135356 | 18
18 | 18 | 6 ,SHE-05.THIRD.dgn,Design Model:135406 | 18
19 | 19 | 6 ,SHE-05.THIRD.dgn,Design Model:135456 | 19
19 | 19 | 6 ,SHE-05.THIRD.dgn,Design Model:135464 | 19
19 | 19 | 6 ,SHE-05.THIRD.dgn,Design Model:135472 | 19
21 | k/d/l | 6 ,SHE-05.THIRD.dgn,Design Model:186432 | 21
21 | k/d/l | 6 ,SHE-05.THIRD.dgn,Design Model:255109 | 21
21 | k/d/l | 6 ,SHE-05.THIRD.dgn,Design Model:255116 | 21
21 | k/d/l | 6 ,SHE-05.THIRD.dgn,Design Model:272204 | 21
21 | k/d/l | 6 ,SHE-05.THIRD.dgn,Design Model:272233 | 21
21 | k/d/l | 6 ,SHE-05.THIRD.dgn,Design Model:272300 | 21
23 | 23 | 8 ,SHE-07.FIFTH.dgn,Design Model:157081 | 23
23 | 23 | 8 ,SHE-07.FIFTH.dgn,Design Model:157185 | 23
23 | k/d/l | 8 ,SHE-07.FIFTH.dgn,Design Model:157193 | 23
23 | 23 | 8 ,SHE-07.FIFTH.dgn,Design Model:157201 | 23
24 | 24 | 8 ,SHE-07.FIFTH.dgn,Design Model:157280 | 24
24 | 24 | 8 ,SHE-07.FIFTH.dgn,Design Model:157288 | 24
24 | 24 | 8 ,SHE-07.FIFTH.dgn,Design Model:157296 | 24
24 | 24 | 8 ,SHE-07.FIFTH.dgn,Design Model:157304 | 24
25 | k/d/l | 8 ,SHE-07.FIFTH.dgn,Design Model:157398 | 25
25 | k/d/l | 8 ,SHE-07.FIFTH.dgn,Design Model:157442 | 25
26 | k/d/l | 8 ,SHE-07.FIFTH.dgn,Design Model:157630 | 26
26 | k/d/l | 8 ,SHE-07.FIFTH.dgn,Design Model:157638 | 26
26 | k/d/l | 8 ,SHE-07.FIFTH.dgn,Design Model:157646 | 26
26 | k/d/l | 8 ,SHE-07.FIFTH.dgn,Design Model:157654 | 26
26 | k/d/l | 8 ,SHE-07.FIFTH.dgn,Design Model:157662 | 26
13 | 13 | 18 ,SHE-04.SECOND.dgn,Design Model:134903 | 13
13 | 13 | 18 ,SHE-04.SECOND.dgn,Design Model:134911 | 13
13 | 13 | 18 ,SHE-04.SECOND.dgn,Design Model:134919 | 13
15 | 15 | 18 ,SHE-04.SECOND.dgn,Design Model:134969 | 15
15 | 15 | 18 ,SHE-04.SECOND.dgn,Design Model:134980 | 15
15 | 15 | 18 ,SHE-04.SECOND.dgn,Design Model:134987 | 15
15 | 15 | 18 ,SHE-04.SECOND.dgn,Design Model:134994 | 15
09 | k/d/l | 18 ,SHE-04.SECOND.dgn,Design Model:135004 | 09
09 | k/d/l | 18 ,SHE-04.SECOND.dgn,Design Model:135012 | 09
09 | k/d/l | 18 ,SHE-04.SECOND.dgn,Design Model:135020 | 09
09 | 09 | 18 ,SHE-04.SECOND.dgn,Design Model:135028 | 09
09 | 09 | 18 ,SHE-04.SECOND.dgn,Design Model:135036 | 09
10 | studio | 18 ,SHE-04.SECOND.dgn,Design Model:135089 | 10
10 | studio | 18 ,SHE-04.SECOND.dgn,Design Model:135127 | 10
10 | studio | 18 ,SHE-04.SECOND.dgn,Design Model:135177 | 10
10 | studio | 18 ,SHE-04.SECOND.dgn,Design Model:135270 | 10
11 | 11 | 18 ,SHE-04.SECOND.dgn,Design Model:135277 | 11
11 | 11 | 18 ,SHE-04.SECOND.dgn,Design Model:135356 | 11
11 | 11 | 18 ,SHE-04.SECOND.dgn,Design Model:135406 | 11
12 | 12 | 18 ,SHE-04.SECOND.dgn,Design Model:135456 | 12
12 | 12 | 18 ,SHE-04.SECOND.dgn,Design Model:135464 | 12
12 | 12 | 18 ,SHE-04.SECOND.dgn,Design Model:135472 | 12
14 | k/d/l | 18 ,SHE-04.SECOND.dgn,Design Model:186432 | 14
14 | k/d/l | 18 ,SHE-04.SECOND.dgn,Design Model:255109 | 14
14 | k/d/l | 18 ,SHE-04.SECOND.dgn,Design Model:255116 | 14
14 | k/d/l | 18 ,SHE-04.SECOND.dgn,Design Model:272204 | 14
14 | k/d/l | 18 ,SHE-04.SECOND.dgn,Design Model:272233 | 14
14 | k/d/l | 18 ,SHE-04.SECOND.dgn,Design Model:272300 | 14

# IfcFurnishingElement: SHE_A-Kitchenunit-Wall37x30 (2)
In: 25
Type - Pset_FurnitureTypeCommon - NominalDepth: 0.37 m; NominalHeight: 0.76 m; NominalLength: 0.3 m
Type - Discipline - Discipline: Architectural
Type - Classification - Uniclass2015: Pr_40_30_78
Type - Casework Parameters - Casework | Type: Wall
Type - Casework - Parametric | File Type: BXF; Parametric | File Name: 01-WallUK; Dimension | Width: 0.3 m; Dimension | Height: 0.76 m; Dimension | Depth: 0.37 m
Identification - ID | Number: 25
Casework - Dimension | Width: 0.37 m
Name | Description
25 | 8 ,SHE-07.FIFTH.dgn,Design Model:158602
25 | 8 ,SHE-07.FIFTH.dgn,Design Model:158609

# IfcFurnishingElement: SHE_A-Kitchenunit-Wall37x45 (10)
Type - Pset_FurnitureTypeCommon - NominalDepth: 0.37 m; NominalHeight: 0.76 m; NominalLength: 0.45 m
Type - Discipline - Discipline: Architectural
Type - Classification - Uniclass2015: Pr_40_30_78
Type - Casework Parameters - Casework | Type: Wall
Type - Casework - Parametric | File Type: BXF; Parametric | File Name: 01-WallUK; Dimension | Width: 0.45 m; Dimension | Height: 0.76 m; Dimension | Depth: 0.37 m
Casework - Dimension | Width: 0.37 m
Name | In | Description | ID | Number
04 | 04 | 4 ,SHE-03.FIRST.dgn,Design Model:135594 | 04
05 | 05 | 4 ,SHE-03.FIRST.dgn,Design Model:135644 | 05
06 | 06 | 4 ,SHE-03.FIRST.dgn,Design Model:135652 | 06
18 | k/d/l | 6 ,SHE-05.THIRD.dgn,Design Model:135594 | 18
19 | 19 | 6 ,SHE-05.THIRD.dgn,Design Model:135644 | 19
20 | 20 | 6 ,SHE-05.THIRD.dgn,Design Model:135652 | 20
25 | 25 | 8 ,SHE-07.FIFTH.dgn,Design Model:158594 | 25
11 | k/d/l | 18 ,SHE-04.SECOND.dgn,Design Model:135594 | 11
12 | 12 | 18 ,SHE-04.SECOND.dgn,Design Model:135644 | 12
13 | 13 | 18 ,SHE-04.SECOND.dgn,Design Model:135652 | 13

# IfcFurnishingElement: SHE_A-Kitchenunit-Wall37x75, 25
In: 25
Type - Pset_FurnitureTypeCommon - NominalDepth: 0.37 m; NominalHeight: 0.76 m; NominalLength: 0.75 m
Type - Discipline - Discipline: Architectural
Type - Classification - Uniclass2015: Pr_40_30_78
Type - Casework Parameters - Casework | Type: Wall
Type - Casework - Parametric | File Type: BXF; Parametric | File Name: 01-WallUK; Dimension | Width: 0.75 m; Dimension | Height: 0.76 m; Dimension | Depth: 0.37 m
Description: 8 ,SHE-07.FIFTH.dgn,Design Model:158586
Identification - ID | Number: 25
Casework - Dimension | Width: 0.37 m

# IfcFurnishingElement: SHE_A-Kitchenunit-Wall37x90 (2)
Type - Pset_FurnitureTypeCommon - NominalDepth: 0.37 m; NominalHeight: 0.76 m; NominalLength: 0.9 m
Type - Discipline - Discipline: Architectural
Type - Classification - Uniclass2015: Pr_40_30_78
Type - Casework Parameters - Casework | Type: Wall
Type - Casework - Parametric | File Type: BXF; Parametric | File Name: 01-WallUK; Dimension | Width: 0.9 m; Dimension | Height: 0.76 m; Dimension | Depth: 0.37 m
Identification - ID | Number: 01
Casework - Dimension | Width: 0.37 m
Name | In | Description
01 | 01 | 2 ,SHE-02.MEZZANINE.dgn,Design Model:120964
01 | k/d/l | 2 ,SHE-02.MEZZANINE.dgn,Design Model:147783

# IfcFurnishingElement: SHE_A-UtilityCupbord (36)
Type - Pset_FurnitureTypeCommon - NominalDepth: 0.05 m; NominalHeight: 2.5 m; NominalLength: 0.7 m
Type - Discipline - Discipline: Architectural
Type - Classification - Uniclass2015: Pr_40_30_78
Type - Casework Parameters - Casework | Type: Tall
Type - Casework - Parametric | File Type: BXF; Parametric | File Name: 01-TallUK; Dimension | Width: 0.7 m; Dimension | Height: 2.5 m; Dimension | Depth: 0.05 m
Name | In | Description | ID | Number | Dimension | Width (m)
06 | k/d/l | 4 ,SHE-03.FIRST.dgn,Design Model:146573 | 06 | 1.5817
03 | studio | 4 ,SHE-03.FIRST.dgn,Design Model:146594 | 03 | 0.7725
04 | k/d/l | 4 ,SHE-03.FIRST.dgn,Design Model:165590 | 04 | 0.85
04 | k/d/l | 4 ,SHE-03.FIRST.dgn,Design Model:165597 | 04 | 0.85
07 | corridor | 4 ,SHE-03.FIRST.dgn,Design Model:189947 | 07 | 0.6
02 | corridor | 4 ,SHE-03.FIRST.dgn,Design Model:243611 | 02 | 0.3525
02 | corridor | 4 ,SHE-03.FIRST.dgn,Design Model:243618 | 02 | 0.3525
03 | 03 | 4 ,SHE-03.FIRST.dgn,Design Model:267279 | 03 | 1.402 | Material: A_BSUK_StorageScreening_Ffe
07 | corridor | 4 ,SHE-03.FIRST.dgn,Design Model:272168 | 07 | 0.6
07 | corridor | 4 ,SHE-03.FIRST.dgn,Design Model:272175 | 07 | 0.6
05 | k/d/l | 4 ,SHE-03.FIRST.dgn,Design Model:302323 | 05 | 0.85
05 | k/d/l | 4 ,SHE-03.FIRST.dgn,Design Model:302330 | 05 | 0.85
20 | k/d/l | 6 ,SHE-05.THIRD.dgn,Design Model:146573 | 20 | 1.5817
17 | studio | 6 ,SHE-05.THIRD.dgn,Design Model:146594 | 17 | 0.7725
18 | k/d/l | 6 ,SHE-05.THIRD.dgn,Design Model:165590 | 18 | 0.85
18 | k/d/l | 6 ,SHE-05.THIRD.dgn,Design Model:165597 | 18 | 0.85
21 | corridor | 6 ,SHE-05.THIRD.dgn,Design Model:189947 | 21 | 0.6
16 | corridor | 6 ,SHE-05.THIRD.dgn,Design Model:243611 | 16 | 0.3525
16 | corridor | 6 ,SHE-05.THIRD.dgn,Design Model:243618 | 16 | 0.3525
17 | studio | 6 ,SHE-05.THIRD.dgn,Design Model:267279 | 17 | 1.402 | Material: A_BSUK_StorageScreening_Ffe
21 | corridor | 6 ,SHE-05.THIRD.dgn,Design Model:272168 | 21 | 0.6
21 | corridor | 6 ,SHE-05.THIRD.dgn,Design Model:272175 | 21 | 0.6
19 | k/d/l | 6 ,SHE-05.THIRD.dgn,Design Model:302323 | 19 | 0.85
19 | k/d/l | 6 ,SHE-05.THIRD.dgn,Design Model:302330 | 19 | 0.85
13 | k/d/l | 18 ,SHE-04.SECOND.dgn,Design Model:146573 | 13 | 1.5817
10 | studio | 18 ,SHE-04.SECOND.dgn,Design Model:146594 | 10 | 0.7725
11 | k/d/l | 18 ,SHE-04.SECOND.dgn,Design Model:165590 | 11 | 0.85
11 | k/d/l | 18 ,SHE-04.SECOND.dgn,Design Model:165597 | 11 | 0.85
14 | corridor | 18 ,SHE-04.SECOND.dgn,Design Model:189947 | 14 | 0.6
09 | corridor | 18 ,SHE-04.SECOND.dgn,Design Model:243611 | 09 | 0.3525
09 | corridor | 18 ,SHE-04.SECOND.dgn,Design Model:243618 | 09 | 0.3525
10 | 10 | 18 ,SHE-04.SECOND.dgn,Design Model:267279 | 10 | 1.402 | Material: A_BSUK_StorageScreening_Ffe
14 | corridor | 18 ,SHE-04.SECOND.dgn,Design Model:272168 | 14 | 0.6
14 | corridor | 18 ,SHE-04.SECOND.dgn,Design Model:272175 | 14 | 0.6
12 | k/d/l | 18 ,SHE-04.SECOND.dgn,Design Model:302323 | 12 | 0.85
12 | k/d/l | 18 ,SHE-04.SECOND.dgn,Design Model:302330 | 12 | 0.85

# IfcFurnishingElement: SHE_A-Wardrobe_hall 40x90 (15)
Type - Pset_FurnitureTypeCommon - NominalDepth: 0.4 m; NominalHeight: 2.1 m; NominalLength: 0.9 m
Type - Discipline - Discipline: Architectural
Type - Classification - Uniclass2015: Pr_40_30_78
Type - Casework Parameters - Casework | Type: Tall
Type - Casework - Parametric | File Type: BXF; Parametric | File Name: 01-TallUK; Dimension | Width: 0.9 m; Dimension | Height: 2.1 m; Dimension | Depth: 0.4 m
Casework - Dimension | Width: 0.6 m
Name | In | Description | ID | Number
06 | 06 | 4 ,SHE-03.FIRST.dgn,Design Model:134933 | 06
03 | 03 | 4 ,SHE-03.FIRST.dgn,Design Model:279673 | 03
08 | 08 | 4 ,SHE-03.FIRST.dgn,Design Model:282336 | 08
05 | 05 | 4 ,SHE-03.FIRST.dgn,Design Model:282519 | 05
04 | k/d/l | 4 ,SHE-03.FIRST.dgn,Design Model:282526 | 04
20 | 20 | 6 ,SHE-05.THIRD.dgn,Design Model:134933 | 20
17 | studio | 6 ,SHE-05.THIRD.dgn,Design Model:279673 | 17
22 | 22 | 6 ,SHE-05.THIRD.dgn,Design Model:282336 | 22
19 | 19 | 6 ,SHE-05.THIRD.dgn,Design Model:282519 | 19
18 | k/d/l | 6 ,SHE-05.THIRD.dgn,Design Model:282526 | 18
13 | 13 | 18 ,SHE-04.SECOND.dgn,Design Model:134933 | 13
10 | 10 | 18 ,SHE-04.SECOND.dgn,Design Model:279673 | 10
15 | 15 | 18 ,SHE-04.SECOND.dgn,Design Model:282336 | 15
12 | k/d/l | 18 ,SHE-04.SECOND.dgn,Design Model:282519 | 12
11 | k/d/l | 18 ,SHE-04.SECOND.dgn,Design Model:282526 | 11

# IfcGrid, OrthogonalGrid
In: Building01
Description: Grid Template\Default, Orthogonal

# IfcMember: A-Baseplate (42)
In: GF
Type - PredefinedType: PLATE
Type - Parametric Definition - Parametric | File Type: PAZ; Parametric | File Name: BasePlate_NoGrout_Architectural
Type - Discipline - Discipline: Architectural
Type - Classification - Uniclass2015: Pr_20_29_03_13
Type - Base Plate | Steel - Plate | Thickness: 0.025 m; Plate | Length: 0.3 m; Plate | Width: 0.3 m; Grout | Thickness: 0 m; Grout | Angle: n/a
Material: A_BSUK_BasePlates
Identification - ID | Type ID: Solar panel
Construction Phase - Phase: New Construction
Base Plate | Steel - Bottom Elevation: 0 m; Plate | Thickness: 0.05 m; Plate | Length: 1 m; Plate | Width: 1.7 m
Name | Description
Solar panel | 11 ,SHE-15.MEHP.dgn,Design Model:124835
Solar panel | 11 ,SHE-15.MEHP.dgn,Design Model:124894
Solar panel | 11 ,SHE-15.MEHP.dgn,Design Model:124953
Solar panel | 11 ,SHE-15.MEHP.dgn,Design Model:125012
Solar panel | 11 ,SHE-15.MEHP.dgn,Design Model:125071
Solar panel | 11 ,SHE-15.MEHP.dgn,Design Model:125130
Solar panel | 11 ,SHE-15.MEHP.dgn,Design Model:125189
Solar panel | 11 ,SHE-15.MEHP.dgn,Design Model:125248
Solar panel | 11 ,SHE-15.MEHP.dgn,Design Model:125307
Solar panel | 11 ,SHE-15.MEHP.dgn,Design Model:125366
Solar panel | 11 ,SHE-15.MEHP.dgn,Design Model:125425
Solar panel | 11 ,SHE-15.MEHP.dgn,Design Model:125484
Solar panel | 11 ,SHE-15.MEHP.dgn,Design Model:125543
Solar panel | 11 ,SHE-15.MEHP.dgn,Design Model:125602
Solar panel | 11 ,SHE-15.MEHP.dgn,Design Model:125661
Solar panel | 11 ,SHE-15.MEHP.dgn,Design Model:125720
Solar panel | 11 ,SHE-15.MEHP.dgn,Design Model:125779
Solar panel | 11 ,SHE-15.MEHP.dgn,Design Model:125838
Solar panel | 11 ,SHE-15.MEHP.dgn,Design Model:125897
Solar panel | 11 ,SHE-15.MEHP.dgn,Design Model:125956
Solar panel | 11 ,SHE-15.MEHP.dgn,Design Model:126015
Solar panel | 11 ,SHE-15.MEHP.dgn,Design Model:126074
Solar panel | 11 ,SHE-15.MEHP.dgn,Design Model:126133
Solar panel | 11 ,SHE-15.MEHP.dgn,Design Model:126192
Solar panel | 11 ,SHE-15.MEHP.dgn,Design Model:126251
Solar panel | 11 ,SHE-15.MEHP.dgn,Design Model:126310
Solar panel | 11 ,SHE-15.MEHP.dgn,Design Model:126369
Solar panel | 11 ,SHE-15.MEHP.dgn,Design Model:126428
Solar panel | 11 ,SHE-15.MEHP.dgn,Design Model:126487
Solar panel | 11 ,SHE-15.MEHP.dgn,Design Model:126546
Solar panel | 11 ,SHE-15.MEHP.dgn,Design Model:126605
Solar panel | 11 ,SHE-15.MEHP.dgn,Design Model:126664
Solar panel | 11 ,SHE-15.MEHP.dgn,Design Model:126723
Solar panel | 11 ,SHE-15.MEHP.dgn,Design Model:126782
Solar panel | 11 ,SHE-15.MEHP.dgn,Design Model:126841
Solar panel | 11 ,SHE-15.MEHP.dgn,Design Model:126900
Solar panel | 11 ,SHE-15.MEHP.dgn,Design Model:131499
Solar panel | 11 ,SHE-15.MEHP.dgn,Design Model:131558
Solar panel | 11 ,SHE-15.MEHP.dgn,Design Model:131617
Solar panel | 11 ,SHE-15.MEHP.dgn,Design Model:131676
Solar panel | 11 ,SHE-15.MEHP.dgn,Design Model:131735
Solar panel | 11 ,SHE-15.MEHP.dgn,Design Model:131794

# IfcMember: A-FrameElements:A_BSUK_Steel_Miscellaneous (5)
In: GF
Material: A_BSUK_Steel_Miscellaneous
Name | Description
A-FrameElements--A_BSUK_Steel_Miscellaneous | 1,SHE-01.GROUND.dgn ,Design Model:148739
A-FrameElements--A_BSUK_Steel_Miscellaneous | 1,SHE-01.GROUND.dgn ,Design Model:148741
A-FrameElements--A_BSUK_Steel_Miscellaneous | 1,SHE-01.GROUND.dgn ,Design Model:148742
A-FrameElements--A_BSUK_Steel_Miscellaneous | 1,SHE-01.GROUND.dgn ,Design Model:148743
A-FrameElements--A_BSUK_Steel_Miscellaneous | 1,SHE-01.GROUND.dgn ,Design Model:148744

# IfcMember: A-ZeeProfile01 (4)
In: MF
Type - Profile Parameters - Cell Symbol Name: Profiles::Zee-Profile-01; Rotation Angle: 0; Flip State: no
Type - Materials - Part Definition: A-Finishes::A_BSUK_WallCeilingInteriorTrim
Type - Classification - Uniclass2015: Pr_35_90_43
Material: A_BSUK_Steel_Miscellaneous
Materials - Part Definition: A-FrameElements::A_BSUK_Steel_Miscellaneous
Name | Description
A-ZeeProfile01 | 2 ,SHE-02.MEZZANINE.dgn,Design Model:237689
A-ZeeProfile01 | 2 ,SHE-02.MEZZANINE.dgn,Design Model:237714
A-ZeeProfile01 | 2 ,SHE-02.MEZZANINE.dgn,Design Model:237726
A-ZeeProfile01 | 2 ,SHE-02.MEZZANINE.dgn,Design Model:239697

# IfcRailing: A-Handrail-900mm (6)
In: GF
Type - Railing Quantities - Start Post | Count: 0; Corner Post | Count: 0; End Post | Count: 0; Intermediate Post | Count: 0; Mounting Bracket | Count: 0; Balusters 1 | Count: 0; Balusters 2 | Count: 0; Balusters 3 | Count: 0
Type - Railing Parameters - Part Definition: A-FrameElements::A_BSUK_Steel_Miscellaneous; Generate Drawing Symbols: no; Rail 1 | Name: Handrail; Rail 1 | Height: 0.9 m; Rail 1 | Profile Type: Structural Section; Rail 1 | Profile: CHS76.1X5; Rail 1 | Side Offset: 0.1 m; Rail 1 | Part Definition: A-FrameElements::A_BSUK_Steel_Miscellaneous; Rail 1 | Join Method: Vertical; Rail 2 | Name: Middle; Rail 2 | Height: 0.8 m; Rail 2 | Profile Type: <none>; Rail 2 | Profile: CHS42.4X3.2; Rail 2 | Side Offset: 0 m; Rail 2 | Part Definition: A-FrameElements::A_BSUK_Steel_Miscellaneous; Rail 2 | Join Method: Vertical; Rail 3 | Name: Bottom; Rail 3 | Height: 0.15 m; Rail 3 | Profile Type: <none>; Rail 3 | Profile: CHS42.4X3.2; Rail 3 | Side Offset: 0 m; Rail 3 | Part definition: A-FrameElements::A_BSUK_Steel_Miscellaneous; Rail 3 | Join Method: Vertical; Rail 4 | Name: Lower; Rail 4 | Height: 0.1 m; Rail 4 | Profile Type: <none>; Rail 4 | Profile: CHS42.4X3.2; Rail 4 | Side Offset: 0.1 m; Rail 4 | Join Method: Vertical; Rail 5 | Profile Type: <none>; Rail 5 | Height: 0 m; Rail 5 | Side Offset: 0 m; Rail 5 | Join Method: Vertical; Rail 6 | Profile Type: <none>; Rail 6 | Height: 0 m; Rail 6 | Side Offset: 0 m; Rail 6 | Join Method: Vertical; Start Post | Name: Start Post; Start Post | Spacing: 0 m; Start Post | Profile Type: <none>; Start Post | Profile: SHS40x40x3.0; Start Post | Height: 0.001 m; Start Post | Base Offset: 0 m; Start Post | Side Offset: 0 m; Start Post | Part Definition: A-FrameElements::A_BSUK_Steel_Miscellaneous; Corner Post | Name: Corner Post; Corner Post | Spacing: 0 m; Corner Post | Profile Type: <none>; Corner Post | Profile: SHS40x40x3.0; Corner Post | Height: 0.86 m; Corner Post | Base Offset: 0 m; Corner Post | Side Offset: 0 m; Corner Post | Part Definition: A-FrameElements::A_BSUK_Steel_Miscellaneous; End Post | Name: End Post; End Post | Spacing: 0 m; End Post | Profile Type: <none>; End Post | Profile: SHS40x40x3.0; End Post | Height: 0.86 m; End Post | Base Offset: 0 m; End Post | Side Offset: 0 m; End Post | Part Definition: A-FrameElements::A_BSUK_Steel_Miscellaneous; Intermediate Post 1 | Name: Intermediate Post; Intermediate Post 1 | Spacing: 1.2 m; Intermediate Post 1 | Profile Type: <none>; Intermediate Post 1 | Profile: SHS40x40x3.0; Intermediate Post1 | Height: 0.86 m; Intermediate Post1 | Base Offset: 0 m; Intermediate Post1 | Side Offset: 0 m; Intermediate Post 1 | Spacing Type: Max Spacing; Mounting Bracket | Spacing: 0 m; Mounting Bracket | Profile Type: <none>; Mounting Bracket | Height: 0 m; Mounting Bracket | Base Offset: 0 m; Mounting Bracket | Side Offset: 0 m; Mounting Bracket | Spacing Type: Max Spacing; Balusters 1 | Name: Pickets; Balusters 1 | Spacing: 0.1 m; Balusters 1 | Spacing Type: Max Spacing; Balusters 1 | Profile Type: <none>; Balusters 1 | Profile: CHS26.9x3.2; Balusters 1 | Height: 0.78 m; Balusters 1 | Base Offset: 0.15 m; Balusters 1 | Side Offset: 0 m; Balusters 1 | Part Definition: A-FrameElements::A_BSUK_Steel_Miscellaneous; Balusters 2 | Spacing: 0.1 m; Balusters 2 | Spacing Type: Max Spacing; Balusters 2 | Profile Type: <none>; Balusters 2 | Profile: CHS26.9x3.2; Balusters 2 | Height: 0.75 m; Balusters 2 | Base Offset: 0 m; Balusters 2 | Side Offset: 0 m; Balusters 2 | Part Definition: A-FrameElements::A_BSUK_Steel_Miscellaneous; Balusters 3 | Spacing: 0.425 m; Balusters 3 | Spacing Type: Max Spacing; Balusters 3 | Profile Type: <none>; Balusters 3 | Profile: CHS26.9x3.2; Balusters 3 | Height: 0.75 m; Balusters 3 | Base Offset: 0 m; Balusters 3 | Side Offset: 0 m; Balusters 3 | Part Definition: A-FrameElements::A_BSUK_Steel_Miscellaneous; Railing End | Start Name: Start; Railing End | Start Top Offset: 0 m; Railing End | Start Side Offset: 0.1 m; Railing End | End Name: End; Railing Ends | End Top Offset: 0 m; Railing End | End Side Offset: 0.1 m
Type - Classification - Uniclass2015: Ss_25_15_60_66
PredefinedType: HANDRAIL; Material: A_BSUK_Steel_Miscellaneous
Railing Quantities - Rail 2 | Length: 0 m; Rail 3 | Length: 0 m; Rail 4 | Length: 0 m; Rail 5 | Length: 0 m; Rail 6 | Length: 0 m; Start Post | Length: 0 m; Start Post | Total Length: 0 m; Corner Post | Length: 0 m; Corner Post | Total Length: 0 m; End Post | Length: 0 m; End Post | Total Length: 0 m; Intermediate Post | Length: 0 m; Intermediate Post | Total Length: 0 m; Mounting Bracket | Length: 0 m; Mounting Bracket | Total Length: 0 m; Balusters 1 | Length: 0 m; Balusters 1 | Total Length: 0 m; Balusters 2 | Length: 0 m; Balusters 2 | Total Length: 0 m; Balusters 3 | Length: 0 m; Balusters 3 | Total Length: 0 m
Railing Parameters - Rail 1 | Profile Type: ProStructures Shape; Balusters 1 | Thickness: 0 m; Balusters 2 | Thickness: 0 m; Balusters 3 | Thickness: 0 m
Name | Description | Rail 1 | Length (m) | Rail 1 | Profile | Rail 1 | Side Offset (m)
A-Handrail-900mm | 1 ,SHE-01.GROUND.dgn,Design Model:156478 | 1.7989 | 1\ANSI_PIPE\15NBX3.73WT_PIPE | 0
A-Handrail-900mm | 1 ,SHE-01.GROUND.dgn,Design Model:156544 | 1.13322 | 1\ANSI_PIPE\15NBX3.73WT_PIPE | 0
A-Handrail-900mm | 16 ,SHE-12.STAIR.dgn,Design Model:223116 | 6.23703 | 1\AS_SHS_C450\40X4.0SHS | 0
A-Handrail-900mm | 16 ,SHE-12.STAIR.dgn,Design Model:223387 | 6.37497 | 1\AS_SHS_C450\40X4.0SHS | 0
A-Handrail-900mm | 16 ,SHE-12.STAIR.dgn,Design Model:223924 | 6.20102 | 1\AS_SHS_C450\40X4.0SHS | 0.001
A-Handrail-900mm | 16 ,SHE-12.STAIR.dgn,Design Model:224304 | 4.98098 | 1\AS_SHS_C450\40X4.0SHS | 0

# IfcRailing: A-RailingGlassPanel-1050mm (25)
Type - Railing Parameters - Part Definition: A-FrameElements::A_BSUK_Steel_Miscellaneous; Generate Drawing Symbols: no; Rail 1 | Name: Top; Rail 1 | Height: 1.05 m; Rail 1 | Profile Type: Profile; Rail 1 | Profile: Round Cap; Rail 1 | Side Offset: 0 m; Rail 1 | Part Definition: A-Finishes::A_BSUK_ChromeRailingSystems; Rail 1 | Join Method: Vertical; Rail 2 | Name: Bottom; Rail 2 | Height: 0 m; Rail 2 | Profile Type: Profile; Rail 2 | Profile: Shoe 65x100; Rail 2 | Side Offset: 0 m; Rail 2 | Part Definition: A-Finishes::A_BSUK_ChromeRailingSystems; Rail 2 | Join Method: <none>; Rail 3 | Name: Bottom; Rail 3 | Height: 0.15 m; Rail 3 | Profile Type: <none>; Rail 3 | Profile: CHS42.4X3.2; Rail 3 | Side Offset: 0 m; Rail 3 | Part definition: A-FrameElements::A_BSUK_Steel_Miscellaneous; Rail 3 | Join Method: Vertical; Rail 4 | Name: Lower; Rail 4 | Height: 0.1 m; Rail 4 | Profile Type: <none>; Rail 4 | Profile: CHS42.4X3.2; Rail 4 | Side Offset: 0.1 m; Rail 4 | Join Method: Vertical; Rail 5 | Profile Type: <none>; Rail 5 | Height: 0 m; Rail 5 | Side Offset: 0 m; Rail 5 | Join Method: Vertical; Rail 6 | Profile Type: <none>; Rail 6 | Height: 0 m; Rail 6 | Side Offset: 0 m; Rail 6 | Join Method: Vertical; Start Post | Name: Start Post; Start Post | Spacing: 0 m; Start Post | Profile Type: Cell; Start Post | Profile: Gap; Start Post | Height: 1.05 m; Start Post | Base Offset: 0 m; Start Post | Side Offset: 0 m; Start Post | Part Definition: A-FrameElements::A_BSUK_Steel_Miscellaneous; Corner Post | Name: Corner Post; Corner Post | Spacing: 0 m; Corner Post | Profile Type: Cell; Corner Post | Profile: Gap; Corner Post | Height: 1.02 m; Corner Post | Base Offset: 0 m; Corner Post | Side Offset: 0 m; Corner Post | Part Definition: A-FrameElements::A_BSUK_Steel_Miscellaneous; End Post | Name: End Post; End Post | Spacing: 0 m; End Post | Profile Type: Cell; End Post | Profile: Gap; End Post | Height: 1.05 m; End Post | Base Offset: 0 m; End Post | Side Offset: 0 m; End Post | Part Definition: A-FrameElements::A_BSUK_Steel_Miscellaneous; Intermediate Post 1 | Name: Intermediate; Intermediate Post 1 | Spacing: 1.5 m; Intermediate Post 1 | Profile Type: Cell; Intermediate Post 1 | Profile: Gap; Intermediate Post1 | Height: 1.03 m; Intermediate Post1 | Base Offset: 0 m; Intermediate Post1 | Side Offset: 0 m; Intermediate Post 1 | Part Definition: A-Finishes::A_BSUK_ChromeRailingSystems; Intermediate Post 1 | Spacing Type: Max Spacing; Mounting Bracket | Spacing: 0 m; Mounting Bracket | Profile Type: <none>; Mounting Bracket | Height: 0 m; Mounting Bracket | Base Offset: 0 m; Mounting Bracket | Side Offset: 0 m; Balusters 1 | Name: Baluster 1; Balusters 1 | Spacing: 0 m; Balusters 1 | Spacing Type: Max Spacing; Balusters 1 | Profile Type: Parametric Panel; Balusters 1 | Profile: Panel Glass; Balusters 1 | Height: 1.025 m; Balusters 1 | Base Offset: 0.05 m; Balusters 1 | Side Offset: 0 m; Balusters 1 | Thickness: 0.01 m; Balusters 1 | Part Definition: A-Finishes::A_BSUK_GlassPanelRailingSystems; Balusters 2 | Spacing: 0.1 m; Balusters 2 | Spacing Type: Max Spacing; Balusters 2 | Profile Type: <none>; Balusters 2 | Profile: CHS26.9x3.2; Balusters 2 | Height: 0.75 m; Balusters 2 | Base Offset: 0 m; Balusters 2 | Side Offset: 0 m; Balusters 2 | Thickness: 0 m; Balusters 2 | Part Definition: A-FrameElements::A_BSUK_Steel_Miscellaneous; Balusters 3 | Spacing: 0.425 m; Balusters 3 | Spacing Type: Max Spacing; Balusters 3 | Profile Type: <none>; Balusters 3 | Profile: CHS26.9x3.2; Balusters 3 | Height: 0.75 m; Balusters 3 | Base Offset: 0 m; Balusters 3 | Side Offset: 0 m; Balusters 3 | Thickness: 0 m; Balusters 3 | Part Definition: A-FrameElements::A_BSUK_Steel_Miscellaneous; Railing End | Start Name: Start; Railing End | Start Top Offset: 0 m; Railing End | Start Side Offset: 0.1 m; Railing End | End Name: End; Railing Ends | End Top Offset: 0 m; Railing End | End Side Offset: 0.1 m
Type - Classification - Uniclass2015: Ss_25_15_60_66
PredefinedType: HANDRAIL; Material: A_BSUK_Steel_Miscellaneous
Railing Quantities - Rail 3 | Length: 0 m; Rail 4 | Length: 0 m; Rail 5 | Length: 0 m; Rail 6 | Length: 0 m; Start Post | Count: 1; Start Post | Length: 1.2 m; Start Post | Total Length: 1.2 m; End Post | Count: 1; End Post | Length: 1.2 m; End Post | Total Length: 1.2 m; Mounting Bracket | Count: 0; Mounting Bracket | Length: 0 m; Mounting Bracket | Total Length: 0 m; Balusters 1 | Length: 0 m; Balusters 1 | Total Length: 0 m; Balusters 2 | Count: 0; Balusters 2 | Length: 0 m; Balusters 2 | Total Length: 0 m; Balusters 3 | Count: 0; Balusters 3 | Length: 0 m; Balusters 3 | Total Length: 0 m
Name | In | Description | Rail 1 | Length (m) | Rail 2 | Length (m) | Corner Post | Count | Corner Post | Length (m) | Corner Post | Total Length (m) | Intermediate Post | Count | Intermediate Post | Length (m) | Intermediate Post | Total Length (m) | Balusters 1 | Count | Phase
A-RailingGlassPanel-1050mm | MF | 2,SHE-02.MEZZANINE.dgn,Design Model:204526 | 1.82104 | 1.82104 | 0 | 0 | 0 | 1 | 1.2 | 1.2 | 2 | Railing Parameters - Rail 1 | Height: 0.855 m; Rail 1 | Profile: Square 45x45mm; Rail 2 | Profile: Square 45x45mm; Balusters 1 | Height: 0.85 m
A-RailingGlassPanel-1050mm | 5F | 8,SHE-07.FIFTH.dgn,Design Model:331689 | 5.50502 | 5.42594 | 3 | 1.2 | 3.6 | 2 | 1.2 | 2.4 | 6 | Railing Parameters - Rail 1 | Height: 0.855 m; Rail 1 | Profile: Square 45x45mm; Rail 2 | Profile: Square 45x45mm; Balusters 1 | Height: 0.85 m
A-RailingGlassPanel-1050mm | 5F | 8,SHE-07.FIFTH.dgn,Design Model:332696 | 2.42085 | 2.42085 | 0 | 0 | 0 | 1 | 1.2 | 1.2 | 2 | Railing Parameters - Rail 1 | Height: 0.855 m; Rail 1 | Profile: Square 45x45mm; Rail 2 | Profile: Square 45x45mm; Balusters 1 | Height: 0.85 m
A-RailingGlassPanel-1050mm | 5F | 8,SHE-07.FIFTH.dgn,Design Model:332857 | 1.21662 | 1.21662 | 0 | 0 | 0 | 0 | 0 | 0 | 1 | Railing Parameters - Rail 1 | Height: 0.855 m; Rail 1 | Profile: Square 45x45mm; Rail 2 | Profile: Square 45x45mm; Balusters 1 | Height: 0.85 m
A-RailingGlassPanel-1050mm | 5F | 8,SHE-07.FIFTH.dgn,Design Model:333239 | 5.89924 | 5.82016 | 3 | 1.2 | 3.6 | 2 | 1.2 | 2.4 | 6 | Railing Parameters - Rail 1 | Height: 0.855 m; Rail 1 | Profile: Square 45x45mm; Rail 2 | Profile: Square 45x45mm; Balusters 1 | Height: 0.85 m
A-RailingGlassPanel-1050mm | 5F | 8,SHE-07.FIFTH.dgn,Design Model:334241 | 5.56748 | 5.48839 | 3 | 1.2 | 3.6 | 2 | 1.2 | 2.4 | 6 | Railing Parameters - Rail 1 | Height: 0.855 m; Rail 1 | Profile: Square 45x45mm; Rail 2 | Profile: Square 45x45mm; Balusters 1 | Height: 0.85 m
A-RailingGlassPanel-1050mm | GF | 15,SHE-14.BALCONY.dgn,Design Model:174469 | 2.7366 | 2.7366 | 0 | 0 | 0 | 0 | 0 | 0 | 1 | New Construction
A-RailingGlassPanel-1050mm | GF | 15,SHE-14.BALCONY.dgn,Design Model:174632 | 1.0182 | 1.0182 | 0 | 0 | 0 | 0 | 0 | 0 | 1 | New Construction
A-RailingGlassPanel-1050mm | GF | 15,SHE-14.BALCONY.dgn,Design Model:174789 | 2.3998 | 2.3998 | 0 | 0 | 0 | 0 | 0 | 0 | 1 | New Construction
A-RailingGlassPanel-1050mm | GF | 15,SHE-14.BALCONY.dgn,Design Model:174944 | 1.3798 | 1.3798 | 0 | 0 | 0 | 0 | 0 | 0 | 1 | New Construction
A-RailingGlassPanel-1050mm | GF | 15,SHE-14.BALCONY.dgn,Design Model:175104 | 2.7366 | 2.7366 | 0 | 0 | 0 | 0 | 0 | 0 | 1 | New Construction
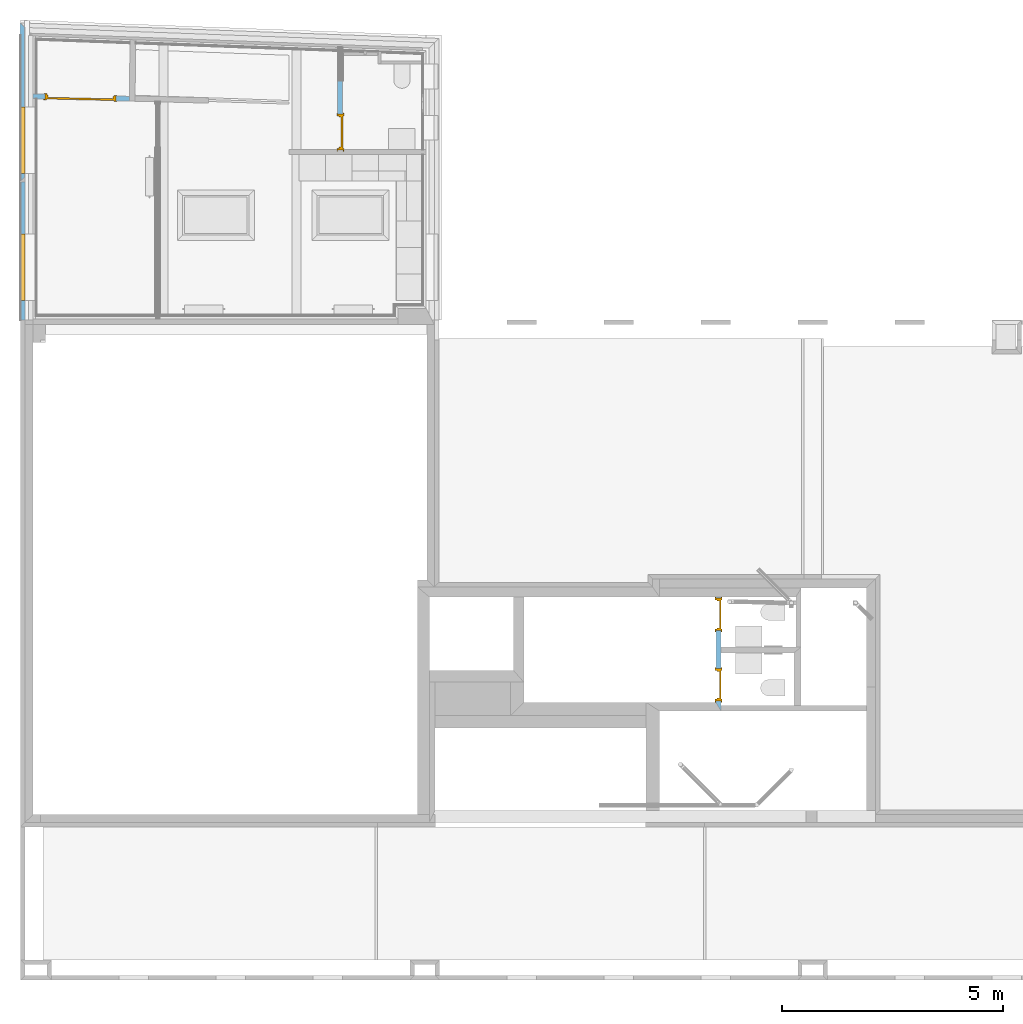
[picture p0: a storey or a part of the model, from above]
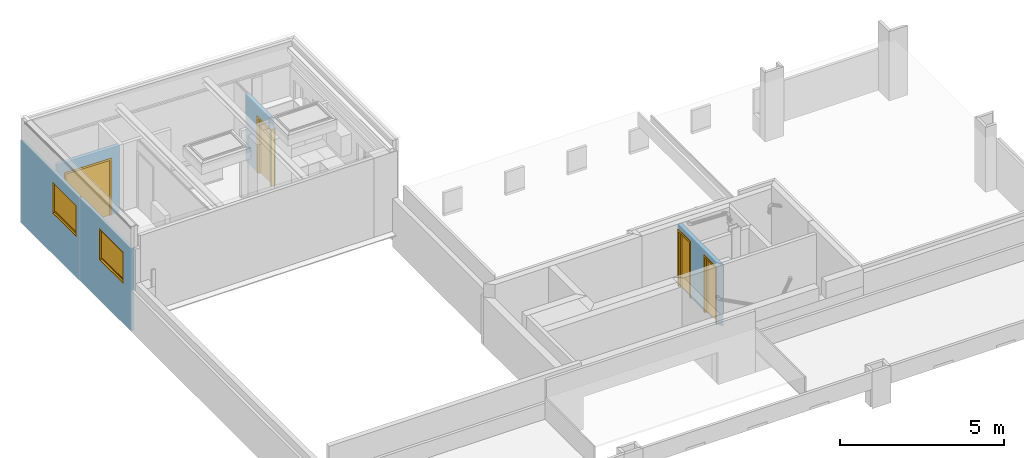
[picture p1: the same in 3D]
Properties of the parts of a building model (IFC2X3), part 10 of 17

# IfcSlab: A-FloorsSlabs A_BSUK_Slabs (1519)
Name | In | Description | Material | Phase | Part Definition
A-FloorsSlabs A_BSUK_Slabs | 1F | shelving - window :4,SHE-03.FIRST.dgn,Design Model:295793 | A_BSUK_Timber_Miscellaneous | New Construction | A-FrameElements::A_BSUK_Timber_Miscellaneous | Identification - ID | Description: shelving - window
A-FloorsSlabs A_BSUK_Slabs | 1F | shelving - window :4,SHE-03.FIRST.dgn,Design Model:295847 | A_BSUK_Timber_Miscellaneous | New Construction | A-FrameElements::A_BSUK_Timber_Miscellaneous | Identification - ID | Description: shelving - window
A-FloorsSlabs A_BSUK_Slabs | 1F | shelving - window :4,SHE-03.FIRST.dgn,Design Model:295875 | A_BSUK_Timber_Miscellaneous | New Construction | A-FrameElements::A_BSUK_Timber_Miscellaneous | Identification - ID | Description: shelving - window
A-FloorsSlabs A_BSUK_Slabs | 1F | shelving - window :4,SHE-03.FIRST.dgn,Design Model:295903 | A_BSUK_Timber_Miscellaneous | New Construction | A-FrameElements::A_BSUK_Timber_Miscellaneous | Identification - ID | Description: shelving - window
A-FloorsSlabs A_BSUK_Slabs | 1F | shelving - window :4,SHE-03.FIRST.dgn,Design Model:296022 | A_BSUK_Timber_Miscellaneous | New Construction | A-FrameElements::A_BSUK_Timber_Miscellaneous | Identification - ID | Description: shelving - window
A-FloorsSlabs A_BSUK_Slabs | 1F | shelving - window :4,SHE-03.FIRST.dgn,Design Model:296050 | A_BSUK_Timber_Miscellaneous | New Construction | A-FrameElements::A_BSUK_Timber_Miscellaneous | Identification - ID | Description: shelving - window
A-FloorsSlabs A_BSUK_Slabs | 1F | shelving - window :4,SHE-03.FIRST.dgn,Design Model:321361 | A_BSUK_Timber_Miscellaneous | New Construction | A-FrameElements::A_BSUK_Timber_Miscellaneous | Identification - ID | Description: shelving - window
A-FloorsSlabs A_BSUK_Slabs | 1F | fire board - ceiling :4,SHE-03.FIRST.dgn,Design Model:409334 | A_BSUK_CeilingSoffitFinishes_Suspended | New Construction | A-Ceilings::A_BSUK_CeilingSoffitFinishes_Suspended | Identification - ID | Description: fire board - ceiling
A-FloorsSlabs A_BSUK_Slabs | 1F | fire board - ceiling :4,SHE-03.FIRST.dgn,Design Model:409441 | A_BSUK_CeilingSoffitFinishes_Suspended | New Construction | A-Ceilings::A_BSUK_CeilingSoffitFinishes_Suspended | Identification - ID | Description: fire board - ceiling
A-FloorsSlabs A_BSUK_Slabs | 1F | fire board - ceiling :4,SHE-03.FIRST.dgn,Design Model:409495 | A_BSUK_CeilingSoffitFinishes_Suspended | New Construction | A-Ceilings::A_BSUK_CeilingSoffitFinishes_Suspended | Identification - ID | Description: fire board - ceiling
A-FloorsSlabs A_BSUK_Slabs | 1F | fire board - ceiling :4,SHE-03.FIRST.dgn,Design Model:409536 | A_BSUK_CeilingSoffitFinishes_Suspended | New Construction | A-Ceilings::A_BSUK_CeilingSoffitFinishes_Suspended | Identification - ID | Description: fire board - ceiling
A-FloorsSlabs A_BSUK_Slabs | 1F | fire board - ceiling :4,SHE-03.FIRST.dgn,Design Model:409577 | A_BSUK_CeilingSoffitFinishes_Suspended | New Construction | A-Ceilings::A_BSUK_CeilingSoffitFinishes_Suspended | Identification - ID | Description: fire board - ceiling
A-FloorsSlabs A_BSUK_Slabs | 1F | fire board - ceiling :4,SHE-03.FIRST.dgn,Design Model:409762 | A_BSUK_CeilingSoffitFinishes_Suspended | New Construction | A-Ceilings::A_BSUK_CeilingSoffitFinishes_Suspended | Identification - ID | Description: fire board - ceiling
A-FloorsSlabs A_BSUK_Slabs | 1F | fire board - ceiling :4,SHE-03.FIRST.dgn,Design Model:409763 | A_BSUK_CeilingSoffitFinishes_Suspended | New Construction | A-Ceilings::A_BSUK_CeilingSoffitFinishes_Suspended | Identification - ID | Description: fire board - ceiling
A-FloorsSlabs A_BSUK_Slabs | 1F | fire board - ceiling :4,SHE-03.FIRST.dgn,Design Model:409843 | A_BSUK_CeilingSoffitFinishes_Suspended | New Construction | A-Ceilings::A_BSUK_CeilingSoffitFinishes_Suspended | Identification - ID | Description: fire board - ceiling
A-FloorsSlabs A_BSUK_Slabs | 1F | fire board - ceiling :4,SHE-03.FIRST.dgn,Design Model:409884 | A_BSUK_CeilingSoffitFinishes_Suspended | New Construction | A-Ceilings::A_BSUK_CeilingSoffitFinishes_Suspended | Identification - ID | Description: fire board - ceiling
A-FloorsSlabs A_BSUK_Slabs | 1F | fire board - ceiling :4,SHE-03.FIRST.dgn,Design Model:409925 | A_BSUK_CeilingSoffitFinishes_Suspended | New Construction | A-Ceilings::A_BSUK_CeilingSoffitFinishes_Suspended | Identification - ID | Description: fire board - ceiling
A-FloorsSlabs A_BSUK_Slabs | 1F | fire board - ceiling :4,SHE-03.FIRST.dgn,Design Model:412315 | A_BSUK_CeilingSoffitFinishes_Suspended | New Construction | A-Ceilings::A_BSUK_CeilingSoffitFinishes_Suspended | Identification - ID | Description: fire board - ceiling
A-FloorsSlabs A_BSUK_Slabs | 1F | fire board - ceiling :4,SHE-03.FIRST.dgn,Design Model:412330 | A_BSUK_CeilingSoffitFinishes_Suspended | New Construction | A-Ceilings::A_BSUK_CeilingSoffitFinishes_Suspended | Identification - ID | Description: fire board - ceiling
A-FloorsSlabs A_BSUK_Slabs | 1F | fire board - ceiling :4,SHE-03.FIRST.dgn,Design Model:412345 | A_BSUK_CeilingSoffitFinishes_Suspended | New Construction | A-Ceilings::A_BSUK_CeilingSoffitFinishes_Suspended | Identification - ID | Description: fire board - ceiling
A-FloorsSlabs A_BSUK_Slabs | 1F | fire board - ceiling :4,SHE-03.FIRST.dgn,Design Model:412360 | A_BSUK_CeilingSoffitFinishes_Suspended | New Construction | A-Ceilings::A_BSUK_CeilingSoffitFinishes_Suspended | Identification - ID | Description: fire board - ceiling
A-FloorsSlabs A_BSUK_Slabs | 1F | fire board - ceiling :4,SHE-03.FIRST.dgn,Design Model:412375 | A_BSUK_CeilingSoffitFinishes_Suspended | New Construction | A-Ceilings::A_BSUK_CeilingSoffitFinishes_Suspended | Identification - ID | Description: fire board - ceiling
A-FloorsSlabs A_BSUK_Slabs | 1F | fire board - ceiling :4,SHE-03.FIRST.dgn,Design Model:412404 | A_BSUK_CeilingSoffitFinishes_Suspended | New Construction | A-Ceilings::A_BSUK_CeilingSoffitFinishes_Suspended | Identification - ID | Description: fire board - ceiling
A-FloorsSlabs A_BSUK_Slabs | 1F | fire board - ceiling :4,SHE-03.FIRST.dgn,Design Model:412405 | A_BSUK_CeilingSoffitFinishes_Suspended | New Construction | A-Ceilings::A_BSUK_CeilingSoffitFinishes_Suspended | Identification - ID | Description: fire board - ceiling
A-FloorsSlabs A_BSUK_Slabs | 1F | fire board - ceiling :4,SHE-03.FIRST.dgn,Design Model:412420 | A_BSUK_CeilingSoffitFinishes_Suspended | New Construction | A-Ceilings::A_BSUK_CeilingSoffitFinishes_Suspended | Identification - ID | Description: fire board - ceiling
A-FloorsSlabs A_BSUK_Slabs | 1F | fire board - ceiling :4,SHE-03.FIRST.dgn,Design Model:412435 | A_BSUK_CeilingSoffitFinishes_Suspended | New Construction | A-Ceilings::A_BSUK_CeilingSoffitFinishes_Suspended | Identification - ID | Description: fire board - ceiling
A-FloorsSlabs A_BSUK_Slabs | 1F | fire board - ceiling :4,SHE-03.FIRST.dgn,Design Model:412450 | A_BSUK_CeilingSoffitFinishes_Suspended | New Construction | A-Ceilings::A_BSUK_CeilingSoffitFinishes_Suspended | Identification - ID | Description: fire board - ceiling
A-FloorsSlabs A_BSUK_Slabs | 3F | shelving - bath :6,SHE-05.THIRD.dgn,Design Model:142164 | A_BSUK_Ceramic_WallTiles | New Construction | A-Finishes::A_BSUK_Ceramic_WallTiles | Identification - ID | Description: shelving - bath
A-FloorsSlabs A_BSUK_Slabs | 3F | shelving - bath :6,SHE-05.THIRD.dgn,Design Model:142179 | A_BSUK_Ceramic_WallTiles | New Construction | A-Finishes::A_BSUK_Ceramic_WallTiles | Identification - ID | Description: shelving - bath
A-FloorsSlabs A_BSUK_Slabs | 3F | shelving - bath :6,SHE-05.THIRD.dgn,Design Model:142194 | A_BSUK_Ceramic_WallTiles | New Construction | A-Finishes::A_BSUK_Ceramic_WallTiles | Identification - ID | Description: shelving - bath
A-FloorsSlabs A_BSUK_Slabs | 3F | shelving - bath :6,SHE-05.THIRD.dgn,Design Model:300477 | A_BSUK_Ceramic_WallTiles | New Construction | A-Finishes::A_BSUK_Ceramic_WallTiles | Identification - ID | Description: shelving - bath
A-FloorsSlabs A_BSUK_Slabs | 3F | shelving - bath :6,SHE-05.THIRD.dgn,Design Model:300491 | A_BSUK_Ceramic_WallTiles | New Construction | A-Finishes::A_BSUK_Ceramic_WallTiles | Identification - ID | Description: shelving - bath
A-FloorsSlabs A_BSUK_Slabs | 3F | shelving - bath :6,SHE-05.THIRD.dgn,Design Model:300505 | A_BSUK_Ceramic_WallTiles | New Construction | A-Finishes::A_BSUK_Ceramic_WallTiles | Identification - ID | Description: shelving - bath
A-FloorsSlabs A_BSUK_Slabs | 3F | shelving - bath :6,SHE-05.THIRD.dgn,Design Model:327204 | A_BSUK_Ceramic_WallTiles | New Construction | A-Finishes::A_BSUK_Ceramic_WallTiles | Identification - ID | Description: shelving - bath
A-FloorsSlabs A_BSUK_Slabs | 3F | 6 ,SHE-05.THIRD.dgn,Design Model:134859 | A_BSUK_InternalFinishes_FloorScreed | New Construction | A-FloorsSlabs::A_BSUK_InternalFinishes_FloorScreed
A-FloorsSlabs A_BSUK_Slabs | 3F | 6 ,SHE-05.THIRD.dgn,Design Model:134860 | A_BSUK_InternalFinishes_FloorScreed | New Construction | A-FloorsSlabs::A_BSUK_InternalFinishes_FloorScreed
A-FloorsSlabs A_BSUK_Slabs | 3F | 6 ,SHE-05.THIRD.dgn,Design Model:135695 | A_BSUK_Ceramic_WallTiles | New Construction | A-Finishes::A_BSUK_Ceramic_WallTiles
A-FloorsSlabs A_BSUK_Slabs | 3F | 6 ,SHE-05.THIRD.dgn,Design Model:135710 | A_BSUK_Ceramic_WallTiles | New Construction | A-Finishes::A_BSUK_Ceramic_WallTiles
A-FloorsSlabs A_BSUK_Slabs | 3F | 6 ,SHE-05.THIRD.dgn,Design Model:135725 | A_BSUK_Ceramic_WallTiles | New Construction | A-Finishes::A_BSUK_Ceramic_WallTiles
A-FloorsSlabs A_BSUK_Slabs | 3F | 6 ,SHE-05.THIRD.dgn,Design Model:135770 | A_BSUK_Ceramic_WallTiles | New Construction | A-Finishes::A_BSUK_Ceramic_WallTiles
A-FloorsSlabs A_BSUK_Slabs | 3F | 6 ,SHE-05.THIRD.dgn,Design Model:142049 | A_BSUK_InternalFinishes_FloorScreed | Existing to Remain | A-FloorsSlabs::A_BSUK_InternalFinishes_FloorScreed
A-FloorsSlabs A_BSUK_Slabs | 3F | 6 ,SHE-05.THIRD.dgn,Design Model:143321 | A_BSUK_Ceramic_WallTiles | New Construction | A-Finishes::A_BSUK_Ceramic_WallTiles
A-FloorsSlabs A_BSUK_Slabs | 3F | 6 ,SHE-05.THIRD.dgn,Design Model:143864 | A_BSUK_ExpandedPolystyreneBoards | New Construction | A-FloorsSlabs::A_BSUK_ExpandedPolystyreneBoards
A-FloorsSlabs A_BSUK_Slabs | 3F | 6 ,SHE-05.THIRD.dgn,Design Model:143891 | A_BSUK_ExpandedPolystyreneBoards | New Construction | A-FloorsSlabs::A_BSUK_ExpandedPolystyreneBoards
A-FloorsSlabs A_BSUK_Slabs | 3F | 6 ,SHE-05.THIRD.dgn,Design Model:143969 | A_BSUK_ExpandedPolystyreneBoards | New Construction | A-FloorsSlabs::A_BSUK_ExpandedPolystyreneBoards
A-FloorsSlabs A_BSUK_Slabs | 3F | 6 ,SHE-05.THIRD.dgn,Design Model:144064 | A_BSUK_ExpandedPolystyreneBoards | New Construction | A-FloorsSlabs::A_BSUK_ExpandedPolystyreneBoards
A-FloorsSlabs A_BSUK_Slabs | 3F | 6 ,SHE-05.THIRD.dgn,Design Model:144148 | A_BSUK_ExpandedPolystyreneBoards | New Construction | A-FloorsSlabs::A_BSUK_ExpandedPolystyreneBoards
A-FloorsSlabs A_BSUK_Slabs | 3F | 6 ,SHE-05.THIRD.dgn,Design Model:144277 | A_BSUK_ExpandedPolystyreneBoards | New Construction | A-FloorsSlabs::A_BSUK_ExpandedPolystyreneBoards
A-FloorsSlabs A_BSUK_Slabs | 3F | 6 ,SHE-05.THIRD.dgn,Design Model:144370 | A_BSUK_ExpandedPolystyreneBoards | New Construction | A-FloorsSlabs::A_BSUK_ExpandedPolystyreneBoards
A-FloorsSlabs A_BSUK_Slabs | 3F | 6 ,SHE-05.THIRD.dgn,Design Model:144454 | A_BSUK_ExpandedPolystyreneBoards | New Construction | A-FloorsSlabs::A_BSUK_ExpandedPolystyreneBoards
A-FloorsSlabs A_BSUK_Slabs | 3F | 6 ,SHE-05.THIRD.dgn,Design Model:144538 | A_BSUK_ExpandedPolystyreneBoards | New Construction | A-FloorsSlabs::A_BSUK_ExpandedPolystyreneBoards
A-FloorsSlabs A_BSUK_Slabs | 3F | 6 ,SHE-05.THIRD.dgn,Design Model:144628 | A_BSUK_ExpandedPolystyreneBoards | New Construction | A-FloorsSlabs::A_BSUK_ExpandedPolystyreneBoards
A-FloorsSlabs A_BSUK_Slabs | 3F | 6 ,SHE-05.THIRD.dgn,Design Model:144629 | A_BSUK_Parquet_Floor |  | A-Finishes::A_BSUK_Parquet_Floor
A-FloorsSlabs A_BSUK_Slabs | 3F | 6 ,SHE-05.THIRD.dgn,Design Model:144740 | A_BSUK_Carpet-Pile | New Construction | A-Finishes::A_BSUK_Carpet-Pile
A-FloorsSlabs A_BSUK_Slabs | 3F | 6 ,SHE-05.THIRD.dgn,Design Model:144773 | A_BSUK_Ceramic_FloorTiles |  | A-Finishes::A_BSUK_Ceramic_FloorTiles
A-FloorsSlabs A_BSUK_Slabs | 3F | 6 ,SHE-05.THIRD.dgn,Design Model:144788 | A_BSUK_Parquet_Floor |  | A-Finishes::A_BSUK_Parquet_Floor
A-FloorsSlabs A_BSUK_Slabs | 3F | 6 ,SHE-05.THIRD.dgn,Design Model:144899 | A_BSUK_Parquet_Floor |  | A-Finishes::A_BSUK_Parquet_Floor
A-FloorsSlabs A_BSUK_Slabs | 3F | 6 ,SHE-05.THIRD.dgn,Design Model:144914 | A_BSUK_Carpet-Pile |  | A-Finishes::A_BSUK_Carpet-Pile
A-FloorsSlabs A_BSUK_Slabs | 3F | 6 ,SHE-05.THIRD.dgn,Design Model:144959 | A_BSUK_Ceramic_FloorTiles |  | A-Finishes::A_BSUK_Ceramic_FloorTiles
A-FloorsSlabs A_BSUK_Slabs | 3F | 6 ,SHE-05.THIRD.dgn,Design Model:144974 | A_BSUK_Parquet_Floor |  | A-Finishes::A_BSUK_Parquet_Floor
A-FloorsSlabs A_BSUK_Slabs | 3F | 6 ,SHE-05.THIRD.dgn,Design Model:145109 | A_BSUK_Ceramic_FloorTiles |  | A-Finishes::A_BSUK_Ceramic_FloorTiles
A-FloorsSlabs A_BSUK_Slabs | 3F | 6 ,SHE-05.THIRD.dgn,Design Model:145124 | A_BSUK_Carpet-Pile |  | A-Finishes::A_BSUK_Carpet-Pile
A-FloorsSlabs A_BSUK_Slabs | 3F | 6 ,SHE-05.THIRD.dgn,Design Model:145163 | A_BSUK_Carpet-Pile |  | A-Finishes::A_BSUK_Carpet-Pile
A-FloorsSlabs A_BSUK_Slabs | 3F | 6 ,SHE-05.THIRD.dgn,Design Model:145196 | A_BSUK_Parquet_Floor |  | A-Finishes::A_BSUK_Parquet_Floor
A-FloorsSlabs A_BSUK_Slabs | 3F | 6 ,SHE-05.THIRD.dgn,Design Model:145313 | A_BSUK_Ceramic_FloorTiles |  | A-Finishes::A_BSUK_Ceramic_FloorTiles
A-FloorsSlabs A_BSUK_Slabs | 3F | 6 ,SHE-05.THIRD.dgn,Design Model:145328 | A_BSUK_Parquet_Floor |  | A-Finishes::A_BSUK_Parquet_Floor
A-FloorsSlabs A_BSUK_Slabs | 3F | 6 ,SHE-05.THIRD.dgn,Design Model:145427 | A_BSUK_Ceramic_FloorTiles |  | A-Finishes::A_BSUK_Ceramic_FloorTiles
A-FloorsSlabs A_BSUK_Slabs | 3F | 6 ,SHE-05.THIRD.dgn,Design Model:145448 | A_BSUK_Carpet-Pile |  | A-Finishes::A_BSUK_Carpet-Pile
A-FloorsSlabs A_BSUK_Slabs | 3F | 6 ,SHE-05.THIRD.dgn,Design Model:145631 | A_BSUK_Parquet_Floor |  | A-Finishes::A_BSUK_Parquet_Floor
A-FloorsSlabs A_BSUK_Slabs | 3F | 6 ,SHE-05.THIRD.dgn,Design Model:145632 | A_BSUK_Ceramic_FloorTiles |  | A-Finishes::A_BSUK_Ceramic_FloorTiles
A-FloorsSlabs A_BSUK_Slabs | 3F | 6 ,SHE-05.THIRD.dgn,Design Model:145633 | A_BSUK_Carpet-Pile |  | A-Finishes::A_BSUK_Carpet-Pile
A-FloorsSlabs A_BSUK_Slabs | 3F | 6 ,SHE-05.THIRD.dgn,Design Model:145634 | A_BSUK_Parquet_Floor |  | A-Finishes::A_BSUK_Parquet_Floor
A-FloorsSlabs A_BSUK_Slabs | 3F | 6 ,SHE-05.THIRD.dgn,Design Model:145739 | A_BSUK_Ceramic_FloorTiles |  | A-Finishes::A_BSUK_Ceramic_FloorTiles
A-FloorsSlabs A_BSUK_Slabs | 3F | 6 ,SHE-05.THIRD.dgn,Design Model:145754 | A_BSUK_Carpet-Pile | New Construction | A-Finishes::A_BSUK_Carpet-Pile
A-FloorsSlabs A_BSUK_Slabs | 3F | 6 ,SHE-05.THIRD.dgn,Design Model:145787 | A_BSUK_Carpet-Pile |  | A-Finishes::A_BSUK_Carpet-Pile
A-FloorsSlabs A_BSUK_Slabs | 3F | 6 ,SHE-05.THIRD.dgn,Design Model:145826 | A_BSUK_Carpet-Pile |  | A-Finishes::A_BSUK_Carpet-Pile
A-FloorsSlabs A_BSUK_Slabs | 3F | 6 ,SHE-05.THIRD.dgn,Design Model:145862 | A_BSUK_Carpet-Pile |  | A-Finishes::A_BSUK_Carpet-Pile
A-FloorsSlabs A_BSUK_Slabs | 3F | 6 ,SHE-05.THIRD.dgn,Design Model:145967 | A_BSUK_Carpet-Pile |  | A-Finishes::A_BSUK_Carpet-Pile
A-FloorsSlabs A_BSUK_Slabs | 3F | 6 ,SHE-05.THIRD.dgn,Design Model:229439 | A_BSUK_Ceramic_WallTiles | New Construction | A-Finishes::A_BSUK_Ceramic_WallTiles
A-FloorsSlabs A_BSUK_Slabs | 3F | 6 ,SHE-05.THIRD.dgn,Design Model:232461 | A_BSUK_Ceramic_FloorTiles |  | A-Finishes::A_BSUK_Ceramic_FloorTiles
A-FloorsSlabs A_BSUK_Slabs | 3F | 6 ,SHE-05.THIRD.dgn,Design Model:270352 | A_BSUK_Ceramic_WallTiles | New Construction | A-Finishes::A_BSUK_Ceramic_WallTiles
A-FloorsSlabs A_BSUK_Slabs | 3F | 6 ,SHE-05.THIRD.dgn,Design Model:270751 | A_BSUK_Ceramic_WallTiles | New Construction | A-Finishes::A_BSUK_Ceramic_WallTiles
A-FloorsSlabs A_BSUK_Slabs | 3F | shelving - bath :6,SHE-05.THIRD.dgn,Design Model:277457 | A_BSUK_Ceramic_WallTiles | New Construction | A-Finishes::A_BSUK_Ceramic_WallTiles | Identification - ID | Description: shelving - bath
A-FloorsSlabs A_BSUK_Slabs | 3F | shelving - bath :6,SHE-05.THIRD.dgn,Design Model:280881 | A_BSUK_Ceramic_WallTiles | New Construction | A-Finishes::A_BSUK_Ceramic_WallTiles | Identification - ID | Description: shelving - bath
A-FloorsSlabs A_BSUK_Slabs | 3F | 6 ,SHE-05.THIRD.dgn,Design Model:282366 | A_BSUK_Ceramic_WallTiles | New Construction | A-Finishes::A_BSUK_Ceramic_WallTiles
A-FloorsSlabs A_BSUK_Slabs | 3F | fire board - ceiling :6,SHE-05.THIRD.dgn,Design Model:466372 | A_BSUK_CeilingSoffitFinishes_Suspended | New Construction | A-Ceilings::A_BSUK_CeilingSoffitFinishes_Suspended | Identification - ID | Description: fire board - ceiling; Fire Resistance - Fire | Rating: F60
A-FloorsSlabs A_BSUK_Slabs | 3F | fire board - ceiling :6,SHE-05.THIRD.dgn,Design Model:466615 | A_BSUK_CeilingSoffitFinishes_Suspended | New Construction | A-Ceilings::A_BSUK_CeilingSoffitFinishes_Suspended | Identification - ID | Description: fire board - ceiling; ID | Notes: F60
A-FloorsSlabs A_BSUK_Slabs | 3F | fire board - ceiling :6,SHE-05.THIRD.dgn,Design Model:468576 | A_BSUK_CeilingSoffitFinishes_Suspended | New Construction | A-Ceilings::A_BSUK_CeilingSoffitFinishes_Suspended | Identification - ID | Description: fire board - ceiling; ID | Notes: F60
A-FloorsSlabs A_BSUK_Slabs | 3F | fire board - ceiling :6,SHE-05.THIRD.dgn,Design Model:468819 | A_BSUK_CeilingSoffitFinishes_Suspended | New Construction | A-Ceilings::A_BSUK_CeilingSoffitFinishes_Suspended | Identification - ID | Description: fire board - ceiling; ID | Notes: F60
A-FloorsSlabs A_BSUK_Slabs | 3F | 6 ,SHE-05.THIRD.dgn,Design Model:511311 | A_BSUK_CeilingSoffitFinishes_Suspended | New Construction | A-Ceilings::A_BSUK_CeilingSoffitFinishes_Suspended | Fire Resistance - Fire | Rating: FD60
A-FloorsSlabs A_BSUK_Slabs | 1F | 7 ,SHE-06.FOURTH.dgn,Design Model:248740 | A_BSUK_Ceramic_WallTiles | New Construction | A-Finishes::A_BSUK_Ceramic_WallTiles
A-FloorsSlabs A_BSUK_Slabs | 1F | 7 ,SHE-06.FOURTH.dgn,Design Model:256503 | A_BSUK_Ceramic_WallTiles | New Construction | A-Finishes::A_BSUK_Ceramic_WallTiles
A-FloorsSlabs A_BSUK_Slabs | 1F | 7 ,SHE-06.FOURTH.dgn,Design Model:387778 | A_BSUK_Steel_Miscellaneous |  | A-FrameElements::A_BSUK_Steel_Miscellaneous
A-FloorsSlabs A_BSUK_Slabs | 1F | 7 ,SHE-06.FOURTH.dgn,Design Model:388005 | A_BSUK_Timber_Miscellaneous |  | A-FrameElements::A_BSUK_Timber_Miscellaneous
A-FloorsSlabs A_BSUK_Slabs | 1F | 7 ,SHE-06.FOURTH.dgn,Design Model:388020 | A_BSUK_Steel_Miscellaneous |  | A-FrameElements::A_BSUK_Steel_Miscellaneous
A-FloorsSlabs A_BSUK_Slabs | 1F | 7 ,SHE-06.FOURTH.dgn,Design Model:388054 | A_BSUK_Timber_Miscellaneous |  | A-FrameElements::A_BSUK_Timber_Miscellaneous
A-FloorsSlabs A_BSUK_Slabs | 1F | 7 ,SHE-06.FOURTH.dgn,Design Model:388069 | A_BSUK_Steel_Miscellaneous |  | A-FrameElements::A_BSUK_Steel_Miscellaneous
A-FloorsSlabs A_BSUK_Slabs | 1F | 7 ,SHE-06.FOURTH.dgn,Design Model:388103 | A_BSUK_Timber_Miscellaneous |  | A-FrameElements::A_BSUK_Timber_Miscellaneous
A-FloorsSlabs A_BSUK_Slabs | 1F | 7 ,SHE-06.FOURTH.dgn,Design Model:388118 | A_BSUK_Steel_Miscellaneous |  | A-FrameElements::A_BSUK_Steel_Miscellaneous
A-FloorsSlabs A_BSUK_Slabs | 1F | 7 ,SHE-06.FOURTH.dgn,Design Model:388152 | A_BSUK_Timber_Miscellaneous |  | A-FrameElements::A_BSUK_Timber_Miscellaneous
A-FloorsSlabs A_BSUK_Slabs | 1F | 7 ,SHE-06.FOURTH.dgn,Design Model:388167 | A_BSUK_Steel_Miscellaneous |  | A-FrameElements::A_BSUK_Steel_Miscellaneous
A-FloorsSlabs A_BSUK_Slabs | 1F | 7 ,SHE-06.FOURTH.dgn,Design Model:388201 | A_BSUK_Timber_Miscellaneous |  | A-FrameElements::A_BSUK_Timber_Miscellaneous
A-FloorsSlabs A_BSUK_Slabs | 1F | 7 ,SHE-06.FOURTH.dgn,Design Model:388216 | A_BSUK_Steel_Miscellaneous |  | A-FrameElements::A_BSUK_Steel_Miscellaneous
A-FloorsSlabs A_BSUK_Slabs | 1F | 7 ,SHE-06.FOURTH.dgn,Design Model:388250 | A_BSUK_Timber_Miscellaneous |  | A-FrameElements::A_BSUK_Timber_Miscellaneous
A-FloorsSlabs A_BSUK_Slabs | 1F | 7 ,SHE-06.FOURTH.dgn,Design Model:388265 | A_BSUK_Steel_Miscellaneous |  | A-FrameElements::A_BSUK_Steel_Miscellaneous
A-FloorsSlabs A_BSUK_Slabs | 1F | 7 ,SHE-06.FOURTH.dgn,Design Model:388299 | A_BSUK_Timber_Miscellaneous |  | A-FrameElements::A_BSUK_Timber_Miscellaneous
A-FloorsSlabs A_BSUK_Slabs | 1F | 7 ,SHE-06.FOURTH.dgn,Design Model:388314 | A_BSUK_Steel_Miscellaneous |  | A-FrameElements::A_BSUK_Steel_Miscellaneous
A-FloorsSlabs A_BSUK_Slabs | 1F | 7 ,SHE-06.FOURTH.dgn,Design Model:388348 | A_BSUK_Timber_Miscellaneous |  | A-FrameElements::A_BSUK_Timber_Miscellaneous
A-FloorsSlabs A_BSUK_Slabs | 1F | 7 ,SHE-06.FOURTH.dgn,Design Model:388363 | A_BSUK_Steel_Miscellaneous |  | A-FrameElements::A_BSUK_Steel_Miscellaneous
A-FloorsSlabs A_BSUK_Slabs | 1F | 7 ,SHE-06.FOURTH.dgn,Design Model:388397 | A_BSUK_Timber_Miscellaneous |  | A-FrameElements::A_BSUK_Timber_Miscellaneous
A-FloorsSlabs A_BSUK_Slabs | 1F | 7 ,SHE-06.FOURTH.dgn,Design Model:388412 | A_BSUK_Steel_Miscellaneous |  | A-FrameElements::A_BSUK_Steel_Miscellaneous
A-FloorsSlabs A_BSUK_Slabs | 1F | 7 ,SHE-06.FOURTH.dgn,Design Model:388495 | A_BSUK_Timber_Miscellaneous |  | A-FrameElements::A_BSUK_Timber_Miscellaneous
A-FloorsSlabs A_BSUK_Slabs | 1F | 7 ,SHE-06.FOURTH.dgn,Design Model:388510 | A_BSUK_Steel_Miscellaneous |  | A-FrameElements::A_BSUK_Steel_Miscellaneous
A-FloorsSlabs A_BSUK_Slabs | 1F | 7 ,SHE-06.FOURTH.dgn,Design Model:388544 | A_BSUK_Timber_Miscellaneous |  | A-FrameElements::A_BSUK_Timber_Miscellaneous
A-FloorsSlabs A_BSUK_Slabs | 1F | 7 ,SHE-06.FOURTH.dgn,Design Model:388559 | A_BSUK_Steel_Miscellaneous |  | A-FrameElements::A_BSUK_Steel_Miscellaneous
A-FloorsSlabs A_BSUK_Slabs | 1F | 7 ,SHE-06.FOURTH.dgn,Design Model:388593 | A_BSUK_Timber_Miscellaneous |  | A-FrameElements::A_BSUK_Timber_Miscellaneous
A-FloorsSlabs A_BSUK_Slabs | 1F | 7 ,SHE-06.FOURTH.dgn,Design Model:388608 | A_BSUK_Steel_Miscellaneous |  | A-FrameElements::A_BSUK_Steel_Miscellaneous
A-FloorsSlabs A_BSUK_Slabs | 1F | 7 ,SHE-06.FOURTH.dgn,Design Model:388642 | A_BSUK_Timber_Miscellaneous |  | A-FrameElements::A_BSUK_Timber_Miscellaneous
A-FloorsSlabs A_BSUK_Slabs | 1F | 7 ,SHE-06.FOURTH.dgn,Design Model:388657 | A_BSUK_Steel_Miscellaneous |  | A-FrameElements::A_BSUK_Steel_Miscellaneous
A-FloorsSlabs A_BSUK_Slabs | 1F | 7 ,SHE-06.FOURTH.dgn,Design Model:388691 | A_BSUK_Timber_Miscellaneous |  | A-FrameElements::A_BSUK_Timber_Miscellaneous
A-FloorsSlabs A_BSUK_Slabs | 1F | 7 ,SHE-06.FOURTH.dgn,Design Model:388706 | A_BSUK_Steel_Miscellaneous |  | A-FrameElements::A_BSUK_Steel_Miscellaneous
A-FloorsSlabs A_BSUK_Slabs | 1F | 7 ,SHE-06.FOURTH.dgn,Design Model:388740 | A_BSUK_Timber_Miscellaneous |  | A-FrameElements::A_BSUK_Timber_Miscellaneous
A-FloorsSlabs A_BSUK_Slabs | 1F | 7 ,SHE-06.FOURTH.dgn,Design Model:388755 | A_BSUK_Steel_Miscellaneous |  | A-FrameElements::A_BSUK_Steel_Miscellaneous
A-FloorsSlabs A_BSUK_Slabs | 1F | 7 ,SHE-06.FOURTH.dgn,Design Model:388789 | A_BSUK_Timber_Miscellaneous |  | A-FrameElements::A_BSUK_Timber_Miscellaneous
A-FloorsSlabs A_BSUK_Slabs | 1F | 7 ,SHE-06.FOURTH.dgn,Design Model:388804 | A_BSUK_Steel_Miscellaneous |  | A-FrameElements::A_BSUK_Steel_Miscellaneous
A-FloorsSlabs A_BSUK_Slabs | 1F | 7 ,SHE-06.FOURTH.dgn,Design Model:388838 | A_BSUK_Timber_Miscellaneous |  | A-FrameElements::A_BSUK_Timber_Miscellaneous
A-FloorsSlabs A_BSUK_Slabs | 1F | 7 ,SHE-06.FOURTH.dgn,Design Model:388853 | A_BSUK_Steel_Miscellaneous |  | A-FrameElements::A_BSUK_Steel_Miscellaneous
A-FloorsSlabs A_BSUK_Slabs | 1F | 7 ,SHE-06.FOURTH.dgn,Design Model:388887 | A_BSUK_Timber_Miscellaneous |  | A-FrameElements::A_BSUK_Timber_Miscellaneous
A-FloorsSlabs A_BSUK_Slabs | 1F | 7 ,SHE-06.FOURTH.dgn,Design Model:388902 | A_BSUK_Steel_Miscellaneous |  | A-FrameElements::A_BSUK_Steel_Miscellaneous
A-FloorsSlabs A_BSUK_Slabs | 1F | 7 ,SHE-06.FOURTH.dgn,Design Model:388936 | A_BSUK_Timber_Miscellaneous |  | A-FrameElements::A_BSUK_Timber_Miscellaneous
A-FloorsSlabs A_BSUK_Slabs | 1F | 7 ,SHE-06.FOURTH.dgn,Design Model:388951 | A_BSUK_Steel_Miscellaneous |  | A-FrameElements::A_BSUK_Steel_Miscellaneous
A-FloorsSlabs A_BSUK_Slabs | 1F | 7 ,SHE-06.FOURTH.dgn,Design Model:388985 | A_BSUK_Timber_Miscellaneous |  | A-FrameElements::A_BSUK_Timber_Miscellaneous
A-FloorsSlabs A_BSUK_Slabs | 1F | 7 ,SHE-06.FOURTH.dgn,Design Model:389000 | A_BSUK_Steel_Miscellaneous |  | A-FrameElements::A_BSUK_Steel_Miscellaneous
A-FloorsSlabs A_BSUK_Slabs | 1F | 7 ,SHE-06.FOURTH.dgn,Design Model:389034 | A_BSUK_Timber_Miscellaneous |  | A-FrameElements::A_BSUK_Timber_Miscellaneous
A-FloorsSlabs A_BSUK_Slabs | 1F | 7 ,SHE-06.FOURTH.dgn,Design Model:389049 | A_BSUK_Steel_Miscellaneous |  | A-FrameElements::A_BSUK_Steel_Miscellaneous
A-FloorsSlabs A_BSUK_Slabs | 1F | 7 ,SHE-06.FOURTH.dgn,Design Model:389083 | A_BSUK_Timber_Miscellaneous |  | A-FrameElements::A_BSUK_Timber_Miscellaneous
A-FloorsSlabs A_BSUK_Slabs | 1F | 7 ,SHE-06.FOURTH.dgn,Design Model:389098 | A_BSUK_Steel_Miscellaneous |  | A-FrameElements::A_BSUK_Steel_Miscellaneous
A-FloorsSlabs A_BSUK_Slabs | 1F | 7 ,SHE-06.FOURTH.dgn,Design Model:389181 | A_BSUK_Timber_Miscellaneous |  | A-FrameElements::A_BSUK_Timber_Miscellaneous
A-FloorsSlabs A_BSUK_Slabs | 1F | 7 ,SHE-06.FOURTH.dgn,Design Model:389196 | A_BSUK_Steel_Miscellaneous |  | A-FrameElements::A_BSUK_Steel_Miscellaneous
A-FloorsSlabs A_BSUK_Slabs | 1F | 7 ,SHE-06.FOURTH.dgn,Design Model:389230 | A_BSUK_Timber_Miscellaneous |  | A-FrameElements::A_BSUK_Timber_Miscellaneous
A-FloorsSlabs A_BSUK_Slabs | 1F | 7 ,SHE-06.FOURTH.dgn,Design Model:389245 | A_BSUK_Steel_Miscellaneous |  | A-FrameElements::A_BSUK_Steel_Miscellaneous
A-FloorsSlabs A_BSUK_Slabs | 1F | 7 ,SHE-06.FOURTH.dgn,Design Model:389279 | A_BSUK_Timber_Miscellaneous |  | A-FrameElements::A_BSUK_Timber_Miscellaneous
A-FloorsSlabs A_BSUK_Slabs | 1F | 7 ,SHE-06.FOURTH.dgn,Design Model:389294 | A_BSUK_Steel_Miscellaneous |  | A-FrameElements::A_BSUK_Steel_Miscellaneous
A-FloorsSlabs A_BSUK_Slabs | 1F | 7 ,SHE-06.FOURTH.dgn,Design Model:243527 | A_BSUK_Ceramic_WallTiles | New Construction | A-Finishes::A_BSUK_Ceramic_WallTiles
A-FloorsSlabs A_BSUK_Slabs | 1F | 7 ,SHE-06.FOURTH.dgn,Design Model:243809 | A_BSUK_Ceramic_WallTiles | New Construction | A-Finishes::A_BSUK_Ceramic_WallTiles
A-FloorsSlabs A_BSUK_Slabs | 1F | 7 ,SHE-06.FOURTH.dgn,Design Model:243869 | A_BSUK_Ceramic_WallTiles | New Construction | A-Finishes::A_BSUK_Ceramic_WallTiles
A-FloorsSlabs A_BSUK_Slabs | 1F | 7 ,SHE-06.FOURTH.dgn,Design Model:245327 | A_BSUK_Ceramic_WallTiles | New Construction | A-Finishes::A_BSUK_Ceramic_WallTiles
A-FloorsSlabs A_BSUK_Slabs | 1F | 7 ,SHE-06.FOURTH.dgn,Design Model:245946 | A_BSUK_Ceramic_WallTiles | New Construction | A-Finishes::A_BSUK_Ceramic_WallTiles
A-FloorsSlabs A_BSUK_Slabs | 1F | 7 ,SHE-06.FOURTH.dgn,Design Model:247372 | A_BSUK_Ceramic_WallTiles | New Construction | A-Finishes::A_BSUK_Ceramic_WallTiles
A-FloorsSlabs A_BSUK_Slabs | 1F | 7 ,SHE-06.FOURTH.dgn,Design Model:247962 | A_BSUK_Ceramic_WallTiles | New Construction | A-Finishes::A_BSUK_Ceramic_WallTiles
A-FloorsSlabs A_BSUK_Slabs | 1F | 7 ,SHE-06.FOURTH.dgn,Design Model:269882 | A_BSUK_CeilingSoffitFinishes_Suspended | New Construction | A-Ceilings::A_BSUK_CeilingSoffitFinishes_Suspended
A-FloorsSlabs A_BSUK_Slabs | 1F | 7 ,SHE-06.FOURTH.dgn,Design Model:269977 | A_BSUK_CeilingSoffitFinishes_Suspended | New Construction | A-Ceilings::A_BSUK_CeilingSoffitFinishes_Suspended
A-FloorsSlabs A_BSUK_Slabs | 1F | 7 ,SHE-06.FOURTH.dgn,Design Model:270029 | A_BSUK_CeilingSoffitFinishes_Suspended | New Construction | A-Ceilings::A_BSUK_CeilingSoffitFinishes_Suspended
A-FloorsSlabs A_BSUK_Slabs | 1F | 7 ,SHE-06.FOURTH.dgn,Design Model:270081 | A_BSUK_CeilingSoffitFinishes_Suspended | New Construction | A-Ceilings::A_BSUK_CeilingSoffitFinishes_Suspended
A-FloorsSlabs A_BSUK_Slabs | 1F | 7 ,SHE-06.FOURTH.dgn,Design Model:270169 | A_BSUK_CeilingSoffitFinishes_Suspended | New Construction | A-Ceilings::A_BSUK_CeilingSoffitFinishes_Suspended
A-FloorsSlabs A_BSUK_Slabs | 1F | 7 ,SHE-06.FOURTH.dgn,Design Model:270245 | A_BSUK_CeilingSoffitFinishes_Suspended | New Construction | A-Ceilings::A_BSUK_CeilingSoffitFinishes_Suspended
A-FloorsSlabs A_BSUK_Slabs | 1F | 7 ,SHE-06.FOURTH.dgn,Design Model:270272 | A_BSUK_CeilingSoffitFinishes_Suspended | New Construction | A-Ceilings::A_BSUK_CeilingSoffitFinishes_Suspended
A-FloorsSlabs A_BSUK_Slabs | 1F | 7 ,SHE-06.FOURTH.dgn,Design Model:270349 | A_BSUK_CeilingSoffitFinishes_Suspended | New Construction | A-Ceilings::A_BSUK_CeilingSoffitFinishes_Suspended
A-FloorsSlabs A_BSUK_Slabs | 1F | 7 ,SHE-06.FOURTH.dgn,Design Model:270437 | A_BSUK_CeilingSoffitFinishes_Suspended | New Construction | A-Ceilings::A_BSUK_CeilingSoffitFinishes_Suspended
A-FloorsSlabs A_BSUK_Slabs | 1F | 7 ,SHE-06.FOURTH.dgn,Design Model:270470 | A_BSUK_CeilingSoffitFinishes_Suspended | New Construction | A-Ceilings::A_BSUK_CeilingSoffitFinishes_Suspended
A-FloorsSlabs A_BSUK_Slabs | 1F | 7 ,SHE-06.FOURTH.dgn,Design Model:270497 | A_BSUK_CeilingSoffitFinishes_Suspended | New Construction | A-Ceilings::A_BSUK_CeilingSoffitFinishes_Suspended
A-FloorsSlabs A_BSUK_Slabs | 1F | 7 ,SHE-06.FOURTH.dgn,Design Model:270617 | A_BSUK_CeilingSoffitFinishes_Suspended | New Construction | A-Ceilings::A_BSUK_CeilingSoffitFinishes_Suspended
A-FloorsSlabs A_BSUK_Slabs | 1F | 7 ,SHE-06.FOURTH.dgn,Design Model:270681 | A_BSUK_CeilingSoffitFinishes_Suspended | New Construction | A-Ceilings::A_BSUK_CeilingSoffitFinishes_Suspended
A-FloorsSlabs A_BSUK_Slabs | 1F | 7 ,SHE-06.FOURTH.dgn,Design Model:270714 | A_BSUK_CeilingSoffitFinishes_Suspended | New Construction | A-Ceilings::A_BSUK_CeilingSoffitFinishes_Suspended
A-FloorsSlabs A_BSUK_Slabs | 1F | 7 ,SHE-06.FOURTH.dgn,Design Model:270840 | A_BSUK_CeilingSoffitFinishes_Suspended | New Construction | A-Ceilings::A_BSUK_CeilingSoffitFinishes_Suspended
A-FloorsSlabs A_BSUK_Slabs | 1F | 7 ,SHE-06.FOURTH.dgn,Design Model:271066 | A_BSUK_CeilingSoffitFinishes_Suspended | New Construction | A-Ceilings::A_BSUK_CeilingSoffitFinishes_Suspended
A-FloorsSlabs A_BSUK_Slabs | 1F | 7 ,SHE-06.FOURTH.dgn,Design Model:271105 | A_BSUK_CeilingSoffitFinishes_Suspended | New Construction | A-Ceilings::A_BSUK_CeilingSoffitFinishes_Suspended
A-FloorsSlabs A_BSUK_Slabs | 1F | 7 ,SHE-06.FOURTH.dgn,Design Model:271144 | A_BSUK_CeilingSoffitFinishes_Suspended | New Construction | A-Ceilings::A_BSUK_CeilingSoffitFinishes_Suspended
A-FloorsSlabs A_BSUK_Slabs | 1F | 7 ,SHE-06.FOURTH.dgn,Design Model:271183 | A_BSUK_CeilingSoffitFinishes_Suspended | New Construction | A-Ceilings::A_BSUK_CeilingSoffitFinishes_Suspended
A-FloorsSlabs A_BSUK_Slabs | 1F | 7 ,SHE-06.FOURTH.dgn,Design Model:271198 | A_BSUK_CeilingSoffitFinishes_Suspended | New Construction | A-Ceilings::A_BSUK_CeilingSoffitFinishes_Suspended
A-FloorsSlabs A_BSUK_Slabs | 1F | 7 ,SHE-06.FOURTH.dgn,Design Model:271216 | A_BSUK_CeilingSoffitFinishes_Suspended | New Construction | A-Ceilings::A_BSUK_CeilingSoffitFinishes_Suspended
A-FloorsSlabs A_BSUK_Slabs | 1F | 7 ,SHE-06.FOURTH.dgn,Design Model:271231 | A_BSUK_CeilingSoffitFinishes_Suspended | New Construction | A-Ceilings::A_BSUK_CeilingSoffitFinishes_Suspended
A-FloorsSlabs A_BSUK_Slabs | 1F | 7 ,SHE-06.FOURTH.dgn,Design Model:271258 | A_BSUK_CeilingSoffitFinishes_Suspended | New Construction | A-Ceilings::A_BSUK_CeilingSoffitFinishes_Suspended
A-FloorsSlabs A_BSUK_Slabs | 1F | 7 ,SHE-06.FOURTH.dgn,Design Model:271285 | A_BSUK_CeilingSoffitFinishes_Suspended | New Construction | A-Ceilings::A_BSUK_CeilingSoffitFinishes_Suspended
A-FloorsSlabs A_BSUK_Slabs | 1F | 7 ,SHE-06.FOURTH.dgn,Design Model:271318 | A_BSUK_CeilingSoffitFinishes_Suspended | New Construction | A-Ceilings::A_BSUK_CeilingSoffitFinishes_Suspended
A-FloorsSlabs A_BSUK_Slabs | 1F | 7 ,SHE-06.FOURTH.dgn,Design Model:271345 | A_BSUK_CeilingSoffitFinishes_Suspended | New Construction | A-Ceilings::A_BSUK_CeilingSoffitFinishes_Suspended
A-FloorsSlabs A_BSUK_Slabs | 1F | 7 ,SHE-06.FOURTH.dgn,Design Model:271372 | A_BSUK_CeilingSoffitFinishes_Suspended | New Construction | A-Ceilings::A_BSUK_CeilingSoffitFinishes_Suspended
A-FloorsSlabs A_BSUK_Slabs | 1F | 7 ,SHE-06.FOURTH.dgn,Design Model:271771 | A_BSUK_CeilingSoffitFinishes_Suspended | New Construction | A-Ceilings::A_BSUK_CeilingSoffitFinishes_Suspended
A-FloorsSlabs A_BSUK_Slabs | 1F | 7 ,SHE-06.FOURTH.dgn,Design Model:271792 | A_BSUK_CeilingSoffitFinishes_Suspended | New Construction | A-Ceilings::A_BSUK_CeilingSoffitFinishes_Suspended
A-FloorsSlabs A_BSUK_Slabs | 1F | 7 ,SHE-06.FOURTH.dgn,Design Model:271819 | A_BSUK_CeilingSoffitFinishes_Suspended | New Construction | A-Ceilings::A_BSUK_CeilingSoffitFinishes_Suspended
A-FloorsSlabs A_BSUK_Slabs | 1F | 7 ,SHE-06.FOURTH.dgn,Design Model:271840 | A_BSUK_CeilingSoffitFinishes_Suspended | New Construction | A-Ceilings::A_BSUK_CeilingSoffitFinishes_Suspended
A-FloorsSlabs A_BSUK_Slabs | 1F | 15mm CDM MTA :7,SHE-06.FOURTH.dgn,Design Model:277591 | A_BSUK_InternalFinishes_FloorScreed | New Construction | A-FloorsSlabs::A_BSUK_InternalFinishes_FloorScreed | Identification - ID | Description: 15mm CDM MTA
A-FloorsSlabs A_BSUK_Slabs | 1F | 15mm CDM MTA :7,SHE-06.FOURTH.dgn,Design Model:277593 | A_BSUK_InternalFinishes_FloorScreed | New Construction | A-FloorsSlabs::A_BSUK_InternalFinishes_FloorScreed | Identification - ID | Description: 15mm CDM MTA
A-FloorsSlabs A_BSUK_Slabs | 1F | 32mm Isocheck 32T :7,SHE-06.FOURTH.dgn,Design Model:281259 | A_BSUK_ExpandedPolystyreneBoards | New Construction | A-FloorsSlabs::A_BSUK_ExpandedPolystyreneBoards | Identification - ID | Description: 32mm Isocheck 32T
A-FloorsSlabs A_BSUK_Slabs | 1F | 32mm Isocheck 32T :7,SHE-06.FOURTH.dgn,Design Model:281260 | A_BSUK_ExpandedPolystyreneBoards | New Construction | A-FloorsSlabs::A_BSUK_ExpandedPolystyreneBoards | Identification - ID | Description: 32mm Isocheck 32T
A-FloorsSlabs A_BSUK_Slabs | 1F | 32mm Isocheck 32T :7,SHE-06.FOURTH.dgn,Design Model:281261 | A_BSUK_ExpandedPolystyreneBoards | New Construction | A-FloorsSlabs::A_BSUK_ExpandedPolystyreneBoards | Identification - ID | Description: 32mm Isocheck 32T
A-FloorsSlabs A_BSUK_Slabs | 1F | 32mm Isocheck 32T :7,SHE-06.FOURTH.dgn,Design Model:281262 | A_BSUK_ExpandedPolystyreneBoards | New Construction | A-FloorsSlabs::A_BSUK_ExpandedPolystyreneBoards | Identification - ID | Description: 32mm Isocheck 32T
A-FloorsSlabs A_BSUK_Slabs | 1F | 32mm Isocheck 32T :7,SHE-06.FOURTH.dgn,Design Model:281263 | A_BSUK_ExpandedPolystyreneBoards | New Construction | A-FloorsSlabs::A_BSUK_ExpandedPolystyreneBoards | Identification - ID | Description: 32mm Isocheck 32T
A-FloorsSlabs A_BSUK_Slabs | 1F | 32mm Isocheck 32T :7,SHE-06.FOURTH.dgn,Design Model:281264 | A_BSUK_ExpandedPolystyreneBoards | New Construction | A-FloorsSlabs::A_BSUK_ExpandedPolystyreneBoards | Identification - ID | Description: 32mm Isocheck 32T
A-FloorsSlabs A_BSUK_Slabs | 1F | 32mm Isocheck 32T :7,SHE-06.FOURTH.dgn,Design Model:281265 | A_BSUK_ExpandedPolystyreneBoards | New Construction | A-FloorsSlabs::A_BSUK_ExpandedPolystyreneBoards | Identification - ID | Description: 32mm Isocheck 32T
A-FloorsSlabs A_BSUK_Slabs | 1F | 32mm Isocheck 32T :7,SHE-06.FOURTH.dgn,Design Model:281266 | A_BSUK_ExpandedPolystyreneBoards | New Construction | A-FloorsSlabs::A_BSUK_ExpandedPolystyreneBoards | Identification - ID | Description: 32mm Isocheck 32T
A-FloorsSlabs A_BSUK_Slabs | 1F | 32mm Isocheck 32T :7,SHE-06.FOURTH.dgn,Design Model:281267 | A_BSUK_ExpandedPolystyreneBoards | New Construction | A-FloorsSlabs::A_BSUK_ExpandedPolystyreneBoards | Identification - ID | Description: 32mm Isocheck 32T
A-FloorsSlabs A_BSUK_Slabs | 1F | 32mm Isocheck 32T :7,SHE-06.FOURTH.dgn,Design Model:281268 | A_BSUK_ExpandedPolystyreneBoards | New Construction | A-FloorsSlabs::A_BSUK_ExpandedPolystyreneBoards | Identification - ID | Description: 32mm Isocheck 32T
A-FloorsSlabs A_BSUK_Slabs | 1F | 32mm Isocheck 32T :7,SHE-06.FOURTH.dgn,Design Model:281269 | A_BSUK_ExpandedPolystyreneBoards | New Construction | A-FloorsSlabs::A_BSUK_ExpandedPolystyreneBoards | Identification - ID | Description: 32mm Isocheck 32T
A-FloorsSlabs A_BSUK_Slabs | 1F | 32mm Isocheck 32T :7,SHE-06.FOURTH.dgn,Design Model:281270 | A_BSUK_ExpandedPolystyreneBoards | New Construction | A-FloorsSlabs::A_BSUK_ExpandedPolystyreneBoards | Identification - ID | Description: 32mm Isocheck 32T
A-FloorsSlabs A_BSUK_Slabs | 1F | 32mm Isocheck 32T :7,SHE-06.FOURTH.dgn,Design Model:281271 | A_BSUK_ExpandedPolystyreneBoards | New Construction | A-FloorsSlabs::A_BSUK_ExpandedPolystyreneBoards | Identification - ID | Description: 32mm Isocheck 32T
A-FloorsSlabs A_BSUK_Slabs | 1F | 32mm Isocheck 32T :7,SHE-06.FOURTH.dgn,Design Model:281272 | A_BSUK_ExpandedPolystyreneBoards | New Construction | A-FloorsSlabs::A_BSUK_ExpandedPolystyreneBoards | Identification - ID | Description: 32mm Isocheck 32T
A-FloorsSlabs A_BSUK_Slabs | 1F | 32mm Isocheck 32T :7,SHE-06.FOURTH.dgn,Design Model:281273 | A_BSUK_ExpandedPolystyreneBoards | New Construction | A-FloorsSlabs::A_BSUK_ExpandedPolystyreneBoards | Identification - ID | Description: 32mm Isocheck 32T
A-FloorsSlabs A_BSUK_Slabs | 1F | 32mm Isocheck 32T :7,SHE-06.FOURTH.dgn,Design Model:281274 | A_BSUK_ExpandedPolystyreneBoards | New Construction | A-FloorsSlabs::A_BSUK_ExpandedPolystyreneBoards | Identification - ID | Description: 32mm Isocheck 32T
A-FloorsSlabs A_BSUK_Slabs | 1F | 32mm Isocheck 32T :7,SHE-06.FOURTH.dgn,Design Model:281275 | A_BSUK_ExpandedPolystyreneBoards | New Construction | A-FloorsSlabs::A_BSUK_ExpandedPolystyreneBoards | Identification - ID | Description: 32mm Isocheck 32T
A-FloorsSlabs A_BSUK_Slabs | 1F | 32mm Isocheck 32T :7,SHE-06.FOURTH.dgn,Design Model:281276 | A_BSUK_ExpandedPolystyreneBoards | New Construction | A-FloorsSlabs::A_BSUK_ExpandedPolystyreneBoards | Identification - ID | Description: 32mm Isocheck 32T
A-FloorsSlabs A_BSUK_Slabs | 1F | 32mm Isocheck 32T :7,SHE-06.FOURTH.dgn,Design Model:281277 | A_BSUK_ExpandedPolystyreneBoards | New Construction | A-FloorsSlabs::A_BSUK_ExpandedPolystyreneBoards | Identification - ID | Description: 32mm Isocheck 32T
A-FloorsSlabs A_BSUK_Slabs | 1F | 32mm Isocheck 32T :7,SHE-06.FOURTH.dgn,Design Model:281278 | A_BSUK_ExpandedPolystyreneBoards | New Construction | A-FloorsSlabs::A_BSUK_ExpandedPolystyreneBoards | Identification - ID | Description: 32mm Isocheck 32T
A-FloorsSlabs A_BSUK_Slabs | 1F | 7 ,SHE-06.FOURTH.dgn,Design Model:281279 | A_BSUK_ExpandedPolystyreneBoards | New Construction | A-FloorsSlabs::A_BSUK_ExpandedPolystyreneBoards
A-FloorsSlabs A_BSUK_Slabs | 1F | 7 ,SHE-06.FOURTH.dgn,Design Model:281280 | A_BSUK_ExpandedPolystyreneBoards | New Construction | A-FloorsSlabs::A_BSUK_ExpandedPolystyreneBoards
A-FloorsSlabs A_BSUK_Slabs | 1F | 32mm Isocheck 32T :7,SHE-06.FOURTH.dgn,Design Model:281281 | A_BSUK_ExpandedPolystyreneBoards | New Construction | A-FloorsSlabs::A_BSUK_ExpandedPolystyreneBoards | Identification - ID | Description: 32mm Isocheck 32T
A-FloorsSlabs A_BSUK_Slabs | 1F | 32mm Isocheck 32T :7,SHE-06.FOURTH.dgn,Design Model:281282 | A_BSUK_ExpandedPolystyreneBoards | New Construction | A-FloorsSlabs::A_BSUK_ExpandedPolystyreneBoards | Identification - ID | Description: 32mm Isocheck 32T
A-FloorsSlabs A_BSUK_Slabs | 1F | 32mm Isocheck 32T :7,SHE-06.FOURTH.dgn,Design Model:281283 | A_BSUK_ExpandedPolystyreneBoards | New Construction | A-FloorsSlabs::A_BSUK_ExpandedPolystyreneBoards | Identification - ID | Description: 32mm Isocheck 32T
A-FloorsSlabs A_BSUK_Slabs | 1F | 32mm Isocheck 32T :7,SHE-06.FOURTH.dgn,Design Model:281284 | A_BSUK_ExpandedPolystyreneBoards | New Construction | A-FloorsSlabs::A_BSUK_ExpandedPolystyreneBoards | Identification - ID | Description: 32mm Isocheck 32T
A-FloorsSlabs A_BSUK_Slabs | 1F | 32mm Isocheck 32T :7,SHE-06.FOURTH.dgn,Design Model:281285 | A_BSUK_ExpandedPolystyreneBoards | New Construction | A-FloorsSlabs::A_BSUK_ExpandedPolystyreneBoards | Identification - ID | Description: 32mm Isocheck 32T
A-FloorsSlabs A_BSUK_Slabs | 1F | 32mm Isocheck 32T :7,SHE-06.FOURTH.dgn,Design Model:281287 | A_BSUK_ExpandedPolystyreneBoards | New Construction | A-FloorsSlabs::A_BSUK_ExpandedPolystyreneBoards | Identification - ID | Description: 32mm Isocheck 32T
A-FloorsSlabs A_BSUK_Slabs | 1F | 32mm Isocheck 32T :7,SHE-06.FOURTH.dgn,Design Model:281288 | A_BSUK_ExpandedPolystyreneBoards | New Construction | A-FloorsSlabs::A_BSUK_ExpandedPolystyreneBoards | Identification - ID | Description: 32mm Isocheck 32T
A-FloorsSlabs A_BSUK_Slabs | 1F | 32mm Isocheck 32T :7,SHE-06.FOURTH.dgn,Design Model:281289 | A_BSUK_ExpandedPolystyreneBoards | New Construction | A-FloorsSlabs::A_BSUK_ExpandedPolystyreneBoards | Identification - ID | Description: 32mm Isocheck 32T
A-FloorsSlabs A_BSUK_Slabs | 1F | 32mm Isocheck 32T :7,SHE-06.FOURTH.dgn,Design Model:281290 | A_BSUK_ExpandedPolystyreneBoards | New Construction | A-FloorsSlabs::A_BSUK_ExpandedPolystyreneBoards | Identification - ID | Description: 32mm Isocheck 32T
A-FloorsSlabs A_BSUK_Slabs | 1F | window sill :7,SHE-06.FOURTH.dgn,Design Model:345146 | A_BSUK_Timber_Miscellaneous | New Construction | A-FrameElements::A_BSUK_Timber_Miscellaneous | Identification - ID | Description: window sill
A-FloorsSlabs A_BSUK_Slabs | 1F | window sill :7,SHE-06.FOURTH.dgn,Design Model:345174 | A_BSUK_Timber_Miscellaneous | New Construction | A-FrameElements::A_BSUK_Timber_Miscellaneous | Identification - ID | Description: window sill
A-FloorsSlabs A_BSUK_Slabs | 1F | window sill :7,SHE-06.FOURTH.dgn,Design Model:345254 | A_BSUK_Timber_Miscellaneous | New Construction | A-FrameElements::A_BSUK_Timber_Miscellaneous | Identification - ID | Description: window sill
A-FloorsSlabs A_BSUK_Slabs | 1F | window sill :7,SHE-06.FOURTH.dgn,Design Model:345601 | A_BSUK_Timber_Miscellaneous | New Construction | A-FrameElements::A_BSUK_Timber_Miscellaneous | Identification - ID | Description: window sill
A-FloorsSlabs A_BSUK_Slabs | 1F | window sill :7,SHE-06.FOURTH.dgn,Design Model:345642 | A_BSUK_Timber_Miscellaneous | New Construction | A-FrameElements::A_BSUK_Timber_Miscellaneous | Identification - ID | Description: window sill
A-FloorsSlabs A_BSUK_Slabs | 1F | window sill :7,SHE-06.FOURTH.dgn,Design Model:385665 | A_BSUK_Timber_Miscellaneous | New Construction | A-FrameElements::A_BSUK_Timber_Miscellaneous | Identification - ID | Description: window sill
A-FloorsSlabs A_BSUK_Slabs | 1F | window sill :7,SHE-06.FOURTH.dgn,Design Model:385680 | A_BSUK_Timber_Miscellaneous | New Construction | A-FrameElements::A_BSUK_Timber_Miscellaneous | Identification - ID | Description: window sill
A-FloorsSlabs A_BSUK_Slabs | 1F | window sill :7,SHE-06.FOURTH.dgn,Design Model:385708 | A_BSUK_Timber_Miscellaneous | New Construction | A-FrameElements::A_BSUK_Timber_Miscellaneous | Identification - ID | Description: window sill
A-FloorsSlabs A_BSUK_Slabs | 1F | window sill :7,SHE-06.FOURTH.dgn,Design Model:385736 | A_BSUK_Timber_Miscellaneous | New Construction | A-FrameElements::A_BSUK_Timber_Miscellaneous | Identification - ID | Description: window sill
A-FloorsSlabs A_BSUK_Slabs | 1F | window sill :7,SHE-06.FOURTH.dgn,Design Model:385764 | A_BSUK_Timber_Miscellaneous | New Construction | A-FrameElements::A_BSUK_Timber_Miscellaneous | Identification - ID | Description: window sill
A-FloorsSlabs A_BSUK_Slabs | 1F | window sill :7,SHE-06.FOURTH.dgn,Design Model:385792 | A_BSUK_Timber_Miscellaneous | New Construction | A-FrameElements::A_BSUK_Timber_Miscellaneous | Identification - ID | Description: window sill
A-FloorsSlabs A_BSUK_Slabs | 1F | window sill :7,SHE-06.FOURTH.dgn,Design Model:385820 | A_BSUK_Timber_Miscellaneous | New Construction | A-FrameElements::A_BSUK_Timber_Miscellaneous | Identification - ID | Description: window sill
A-FloorsSlabs A_BSUK_Slabs | 1F | window sill :7,SHE-06.FOURTH.dgn,Design Model:385848 | A_BSUK_Timber_Miscellaneous | New Construction | A-FrameElements::A_BSUK_Timber_Miscellaneous | Identification - ID | Description: window sill
A-FloorsSlabs A_BSUK_Slabs | 1F | window sill :7,SHE-06.FOURTH.dgn,Design Model:385876 | A_BSUK_Timber_Miscellaneous | New Construction | A-FrameElements::A_BSUK_Timber_Miscellaneous | Identification - ID | Description: window sill
A-FloorsSlabs A_BSUK_Slabs | 1F | window sill :7,SHE-06.FOURTH.dgn,Design Model:385904 | A_BSUK_Timber_Miscellaneous | New Construction | A-FrameElements::A_BSUK_Timber_Miscellaneous | Identification - ID | Description: window sill
A-FloorsSlabs A_BSUK_Slabs | 1F | window sill :7,SHE-06.FOURTH.dgn,Design Model:385958 | A_BSUK_Timber_Miscellaneous | New Construction | A-FrameElements::A_BSUK_Timber_Miscellaneous | Identification - ID | Description: window sill
A-FloorsSlabs A_BSUK_Slabs | 1F | window sill :7,SHE-06.FOURTH.dgn,Design Model:385986 | A_BSUK_Timber_Miscellaneous | New Construction | A-FrameElements::A_BSUK_Timber_Miscellaneous | Identification - ID | Description: window sill
A-FloorsSlabs A_BSUK_Slabs | 1F | window sill :7,SHE-06.FOURTH.dgn,Design Model:386014 | A_BSUK_Timber_Miscellaneous | New Construction | A-FrameElements::A_BSUK_Timber_Miscellaneous | Identification - ID | Description: window sill
A-FloorsSlabs A_BSUK_Slabs | 1F | window sill :7,SHE-06.FOURTH.dgn,Design Model:386042 | A_BSUK_Timber_Miscellaneous | New Construction | A-FrameElements::A_BSUK_Timber_Miscellaneous | Identification - ID | Description: window sill
A-FloorsSlabs A_BSUK_Slabs | 1F | window sill :7,SHE-06.FOURTH.dgn,Design Model:386070 | A_BSUK_Timber_Miscellaneous | New Construction | A-FrameElements::A_BSUK_Timber_Miscellaneous | Identification - ID | Description: window sill
A-FloorsSlabs A_BSUK_Slabs | 1F | window sill :7,SHE-06.FOURTH.dgn,Design Model:386098 | A_BSUK_Timber_Miscellaneous | New Construction | A-FrameElements::A_BSUK_Timber_Miscellaneous | Identification - ID | Description: window sill
A-FloorsSlabs A_BSUK_Slabs | 1F | window sill :7,SHE-06.FOURTH.dgn,Design Model:386126 | A_BSUK_Timber_Miscellaneous | New Construction | A-FrameElements::A_BSUK_Timber_Miscellaneous | Identification - ID | Description: window sill
A-FloorsSlabs A_BSUK_Slabs | 1F | window sill :7,SHE-06.FOURTH.dgn,Design Model:386154 | A_BSUK_Timber_Miscellaneous | New Construction | A-FrameElements::A_BSUK_Timber_Miscellaneous | Identification - ID | Description: window sill
A-FloorsSlabs A_BSUK_Slabs | 1F | window sill :7,SHE-06.FOURTH.dgn,Design Model:386182 | A_BSUK_Timber_Miscellaneous | New Construction | A-FrameElements::A_BSUK_Timber_Miscellaneous | Identification - ID | Description: window sill
A-FloorsSlabs A_BSUK_Slabs | 1F | 7 ,SHE-06.FOURTH.dgn,Design Model:387762 | A_BSUK_Timber_Miscellaneous |  | A-FrameElements::A_BSUK_Timber_Miscellaneous
A-FloorsSlabs A_BSUK_Slabs | 1F | 7 ,SHE-06.FOURTH.dgn,Design Model:407641 | A_BSUK_Ceramic_WallTiles | New Construction | A-Finishes::A_BSUK_Ceramic_WallTiles
A-FloorsSlabs A_BSUK_Slabs | 1F | 7 ,SHE-06.FOURTH.dgn,Design Model:437550 | A_BSUK_CeilingSoffitFinishes_Suspended | New Construction | A-Ceilings::A_BSUK_CeilingSoffitFinishes_Suspended
A-FloorsSlabs A_BSUK_Slabs | 1F | 7 ,SHE-06.FOURTH.dgn,Design Model:437583 | A_BSUK_CeilingSoffitFinishes_Suspended | New Construction | A-Ceilings::A_BSUK_CeilingSoffitFinishes_Suspended
A-FloorsSlabs A_BSUK_Slabs | 1F | 7 ,SHE-06.FOURTH.dgn,Design Model:437610 | A_BSUK_CeilingSoffitFinishes_Suspended | New Construction | A-Ceilings::A_BSUK_CeilingSoffitFinishes_Suspended
A-FloorsSlabs A_BSUK_Slabs | 1F | 7 ,SHE-06.FOURTH.dgn,Design Model:437637 | A_BSUK_CeilingSoffitFinishes_Suspended | New Construction | A-Ceilings::A_BSUK_CeilingSoffitFinishes_Suspended
A-FloorsSlabs A_BSUK_Slabs | 1F | 7 ,SHE-06.FOURTH.dgn,Design Model:437682 | A_BSUK_CeilingSoffitFinishes_Suspended | New Construction | A-Ceilings::A_BSUK_CeilingSoffitFinishes_Suspended
A-FloorsSlabs A_BSUK_Slabs | 1F | 7 ,SHE-06.FOURTH.dgn,Design Model:437721 | A_BSUK_CeilingSoffitFinishes_Suspended | New Construction | A-Ceilings::A_BSUK_CeilingSoffitFinishes_Suspended
A-FloorsSlabs A_BSUK_Slabs | 1F | 7 ,SHE-06.FOURTH.dgn,Design Model:437748 | A_BSUK_CeilingSoffitFinishes_Suspended | New Construction | A-Ceilings::A_BSUK_CeilingSoffitFinishes_Suspended
A-FloorsSlabs A_BSUK_Slabs | 1F | 7 ,SHE-06.FOURTH.dgn,Design Model:437775 | A_BSUK_CeilingSoffitFinishes_Suspended | New Construction | A-Ceilings::A_BSUK_CeilingSoffitFinishes_Suspended
A-FloorsSlabs A_BSUK_Slabs | 1F | 7 ,SHE-06.FOURTH.dgn,Design Model:437820 | A_BSUK_CeilingSoffitFinishes_Suspended | New Construction | A-Ceilings::A_BSUK_CeilingSoffitFinishes_Suspended
A-FloorsSlabs A_BSUK_Slabs | 1F | 7 ,SHE-06.FOURTH.dgn,Design Model:437853 | A_BSUK_CeilingSoffitFinishes_Suspended | New Construction | A-Ceilings::A_BSUK_CeilingSoffitFinishes_Suspended
A-FloorsSlabs A_BSUK_Slabs | 1F | 7 ,SHE-06.FOURTH.dgn,Design Model:437880 | A_BSUK_CeilingSoffitFinishes_Suspended | New Construction | A-Ceilings::A_BSUK_CeilingSoffitFinishes_Suspended
A-FloorsSlabs A_BSUK_Slabs | 1F | 7 ,SHE-06.FOURTH.dgn,Design Model:437913 | A_BSUK_CeilingSoffitFinishes_Suspended | New Construction | A-Ceilings::A_BSUK_CeilingSoffitFinishes_Suspended
A-FloorsSlabs A_BSUK_Slabs | 1F | 7 ,SHE-06.FOURTH.dgn,Design Model:437946 | A_BSUK_CeilingSoffitFinishes_Suspended | New Construction | A-Ceilings::A_BSUK_CeilingSoffitFinishes_Suspended
A-FloorsSlabs A_BSUK_Slabs | 1F | 7 ,SHE-06.FOURTH.dgn,Design Model:437979 | A_BSUK_CeilingSoffitFinishes_Suspended | New Construction | A-Ceilings::A_BSUK_CeilingSoffitFinishes_Suspended
A-FloorsSlabs A_BSUK_Slabs | 1F | 7 ,SHE-06.FOURTH.dgn,Design Model:438012 | A_BSUK_CeilingSoffitFinishes_Suspended | New Construction | A-Ceilings::A_BSUK_CeilingSoffitFinishes_Suspended
A-FloorsSlabs A_BSUK_Slabs | 1F | 7 ,SHE-06.FOURTH.dgn,Design Model:438042 | A_BSUK_CeilingSoffitFinishes_Suspended | New Construction | A-Ceilings::A_BSUK_CeilingSoffitFinishes_Suspended
A-FloorsSlabs A_BSUK_Slabs | 1F | 7 ,SHE-06.FOURTH.dgn,Design Model:438081 | A_BSUK_CeilingSoffitFinishes_Suspended | New Construction | A-Ceilings::A_BSUK_CeilingSoffitFinishes_Suspended
A-FloorsSlabs A_BSUK_Slabs | 1F | 7 ,SHE-06.FOURTH.dgn,Design Model:438120 | A_BSUK_CeilingSoffitFinishes_Suspended | New Construction | A-Ceilings::A_BSUK_CeilingSoffitFinishes_Suspended
A-FloorsSlabs A_BSUK_Slabs | 1F | 7 ,SHE-06.FOURTH.dgn,Design Model:438156 | A_BSUK_CeilingSoffitFinishes_Suspended | New Construction | A-Ceilings::A_BSUK_CeilingSoffitFinishes_Suspended
A-FloorsSlabs A_BSUK_Slabs | 1F | 7 ,SHE-06.FOURTH.dgn,Design Model:438171 | A_BSUK_CeilingSoffitFinishes_Suspended | New Construction | A-Ceilings::A_BSUK_CeilingSoffitFinishes_Suspended
A-FloorsSlabs A_BSUK_Slabs | 1F | 7 ,SHE-06.FOURTH.dgn,Design Model:438189 | A_BSUK_CeilingSoffitFinishes_Suspended | New Construction | A-Ceilings::A_BSUK_CeilingSoffitFinishes_Suspended
A-FloorsSlabs A_BSUK_Slabs | 1F | 7 ,SHE-06.FOURTH.dgn,Design Model:438210 | A_BSUK_CeilingSoffitFinishes_Suspended | New Construction | A-Ceilings::A_BSUK_CeilingSoffitFinishes_Suspended
A-FloorsSlabs A_BSUK_Slabs | 1F | 7 ,SHE-06.FOURTH.dgn,Design Model:438237 | A_BSUK_CeilingSoffitFinishes_Suspended | New Construction | A-Ceilings::A_BSUK_CeilingSoffitFinishes_Suspended
A-FloorsSlabs A_BSUK_Slabs | 1F | 7 ,SHE-06.FOURTH.dgn,Design Model:438252 | A_BSUK_CeilingSoffitFinishes_Suspended | New Construction | A-Ceilings::A_BSUK_CeilingSoffitFinishes_Suspended
A-FloorsSlabs A_BSUK_Slabs | 1F | 7 ,SHE-06.FOURTH.dgn,Design Model:438285 | A_BSUK_CeilingSoffitFinishes_Suspended | New Construction | A-Ceilings::A_BSUK_CeilingSoffitFinishes_Suspended
A-FloorsSlabs A_BSUK_Slabs | 1F | 7 ,SHE-06.FOURTH.dgn,Design Model:438312 | A_BSUK_CeilingSoffitFinishes_Suspended | New Construction | A-Ceilings::A_BSUK_CeilingSoffitFinishes_Suspended
A-FloorsSlabs A_BSUK_Slabs | 1F | 7 ,SHE-06.FOURTH.dgn,Design Model:438339 | A_BSUK_CeilingSoffitFinishes_Suspended | New Construction | A-Ceilings::A_BSUK_CeilingSoffitFinishes_Suspended
A-FloorsSlabs A_BSUK_Slabs | 1F | Fire board - ceiling (120 min) :7,SHE-06.FOURTH.dgn,Design Model:438360 | A_BSUK_CeilingSoffitFinishes_Suspended | New Construction | A-Ceilings::A_BSUK_CeilingSoffitFinishes_Suspended | Identification - ID | Description: Fire board - ceiling (120 min)
A-FloorsSlabs A_BSUK_Slabs | 1F | 7 ,SHE-06.FOURTH.dgn,Design Model:438381 | A_BSUK_CeilingSoffitFinishes_Suspended | New Construction | A-Ceilings::A_BSUK_CeilingSoffitFinishes_Suspended
A-FloorsSlabs A_BSUK_Slabs | 1F | 7 ,SHE-06.FOURTH.dgn,Design Model:438408 | A_BSUK_CeilingSoffitFinishes_Suspended | New Construction | A-Ceilings::A_BSUK_CeilingSoffitFinishes_Suspended
A-FloorsSlabs A_BSUK_Slabs | 1F | 7 ,SHE-06.FOURTH.dgn,Design Model:438435 | A_BSUK_CeilingSoffitFinishes_Suspended | New Construction | A-Ceilings::A_BSUK_CeilingSoffitFinishes_Suspended
A-FloorsSlabs A_BSUK_Slabs | 1F | 7 ,SHE-06.FOURTH.dgn,Design Model:438456 | A_BSUK_CeilingSoffitFinishes_Suspended | New Construction | A-Ceilings::A_BSUK_CeilingSoffitFinishes_Suspended
A-FloorsSlabs A_BSUK_Slabs | 1F | Stair 5 :7,SHE-06.FOURTH.dgn,Design Model:459223 | A_BSUK_Slabs | Identification - ID | Description: Stair 5
A-FloorsSlabs A_BSUK_Slabs | 1F | Stair 5 :7,SHE-06.FOURTH.dgn,Design Model:459292 | A_BSUK_Slabs | Identification - ID | Description: Stair 5
A-FloorsSlabs A_BSUK_Slabs | 1F | Stair 5 :7,SHE-06.FOURTH.dgn,Design Model:459359 | A_BSUK_Slabs | Identification - ID | Description: Stair 5
A-FloorsSlabs A_BSUK_Slabs | 1F | Stair 5 :7,SHE-06.FOURTH.dgn,Design Model:459387 | A_BSUK_Slabs | Identification - ID | Description: Stair 5
A-FloorsSlabs A_BSUK_Slabs | 1F | Stair 5 :7,SHE-06.FOURTH.dgn,Design Model:459415 | A_BSUK_Slabs | Identification - ID | Description: Stair 5
A-FloorsSlabs A_BSUK_Slabs | 1F | Stair 5 :7,SHE-06.FOURTH.dgn,Design Model:459443 | A_BSUK_Slabs | Identification - ID | Description: Stair 5
A-FloorsSlabs A_BSUK_Slabs | 1F | Stair 5 :7,SHE-06.FOURTH.dgn,Design Model:459471 | A_BSUK_Slabs | Identification - ID | Description: Stair 5
A-FloorsSlabs A_BSUK_Slabs | 1F | Stair 5 :7,SHE-06.FOURTH.dgn,Design Model:459499 | A_BSUK_Slabs | Identification - ID | Description: Stair 5
A-FloorsSlabs A_BSUK_Slabs | 1F | Stair 5 :7,SHE-06.FOURTH.dgn,Design Model:459527 | A_BSUK_Slabs | Identification - ID | Description: Stair 5
A-FloorsSlabs A_BSUK_Slabs | 1F | Stair 5 :7,SHE-06.FOURTH.dgn,Design Model:459555 | A_BSUK_Slabs | Identification - ID | Description: Stair 5
A-FloorsSlabs A_BSUK_Slabs | 1F | Stair 5 :7,SHE-06.FOURTH.dgn,Design Model:459569 | A_BSUK_Slabs | Identification - ID | Description: Stair 5
A-FloorsSlabs A_BSUK_Slabs | 1F | Stair 5 :7,SHE-06.FOURTH.dgn,Design Model:459581 | A_BSUK_Slabs | Identification - ID | Description: Stair 5
A-FloorsSlabs A_BSUK_Slabs | 1F | Stair 5 :7,SHE-06.FOURTH.dgn,Design Model:459596 | A_BSUK_Slabs | Identification - ID | Description: Stair 5
A-FloorsSlabs A_BSUK_Slabs | 1F | Stair 5 :7,SHE-06.FOURTH.dgn,Design Model:459721 | A_BSUK_Slabs | Identification - ID | Description: Stair 5
A-FloorsSlabs A_BSUK_Slabs | 1F | Stair 6 :7,SHE-06.FOURTH.dgn,Design Model:460213 | A_BSUK_Slabs | Identification - ID | Description: Stair 6
A-FloorsSlabs A_BSUK_Slabs | 1F | Stair 6 :7,SHE-06.FOURTH.dgn,Design Model:460228 | A_BSUK_Slabs | Identification - ID | Description: Stair 6
A-FloorsSlabs A_BSUK_Slabs | 1F | Stair 6 :7,SHE-06.FOURTH.dgn,Design Model:460243 | A_BSUK_Slabs | Identification - ID | Description: Stair 6
A-FloorsSlabs A_BSUK_Slabs | 1F | Stair 6 :7,SHE-06.FOURTH.dgn,Design Model:460258 | A_BSUK_Slabs | Identification - ID | Description: Stair 6
A-FloorsSlabs A_BSUK_Slabs | 1F | Stair 6 :7,SHE-06.FOURTH.dgn,Design Model:460273 | A_BSUK_Slabs | Identification - ID | Description: Stair 6
A-FloorsSlabs A_BSUK_Slabs | 1F | Stair 6 :7,SHE-06.FOURTH.dgn,Design Model:460288 | A_BSUK_Slabs | Identification - ID | Description: Stair 6
A-FloorsSlabs A_BSUK_Slabs | 1F | Stair 6 :7,SHE-06.FOURTH.dgn,Design Model:460289 | A_BSUK_Slabs | Identification - ID | Description: Stair 6
A-FloorsSlabs A_BSUK_Slabs | 1F | Stair 6 :7,SHE-06.FOURTH.dgn,Design Model:460301 | A_BSUK_Slabs | Identification - ID | Description: Stair 6
A-FloorsSlabs A_BSUK_Slabs | 1F | Stair 6 :7,SHE-06.FOURTH.dgn,Design Model:460316 | A_BSUK_Slabs | Identification - ID | Description: Stair 6
A-FloorsSlabs A_BSUK_Slabs | 1F | Stair 6 :7,SHE-06.FOURTH.dgn,Design Model:460342 | A_BSUK_Slabs | Identification - ID | Description: Stair 6
A-FloorsSlabs A_BSUK_Slabs | 1F | Stair 6 :7,SHE-06.FOURTH.dgn,Design Model:461413 | A_BSUK_Slabs | Identification - ID | Description: Stair 6
A-FloorsSlabs A_BSUK_Slabs | 1F | Stair 6 :7,SHE-06.FOURTH.dgn,Design Model:461463 | A_BSUK_Slabs | Identification - ID | Description: Stair 6
A-FloorsSlabs A_BSUK_Slabs | 1F | Stair 6 :7,SHE-06.FOURTH.dgn,Design Model:461475 | A_BSUK_Slabs | Identification - ID | Description: Stair 6
A-FloorsSlabs A_BSUK_Slabs | 1F | Stair 6 :7,SHE-06.FOURTH.dgn,Design Model:461490 | A_BSUK_Slabs | Identification - ID | Description: Stair 6
A-FloorsSlabs A_BSUK_Slabs | 1F | Stair 4 :7,SHE-06.FOURTH.dgn,Design Model:463136 | A_BSUK_Slabs | Identification - ID | Description: Stair 4
A-FloorsSlabs A_BSUK_Slabs | 1F | Stair 4 :7,SHE-06.FOURTH.dgn,Design Model:463137 | A_BSUK_Slabs | Identification - ID | Description: Stair 4
A-FloorsSlabs A_BSUK_Slabs | 1F | Stair 4 :7,SHE-06.FOURTH.dgn,Design Model:463138 | A_BSUK_Slabs | Identification - ID | Description: Stair 4
A-FloorsSlabs A_BSUK_Slabs | 1F | Stair 4 :7,SHE-06.FOURTH.dgn,Design Model:463139 | A_BSUK_Slabs | Identification - ID | Description: Stair 4
A-FloorsSlabs A_BSUK_Slabs | 1F | Stair 4 :7,SHE-06.FOURTH.dgn,Design Model:463140 | A_BSUK_Slabs | Identification - ID | Description: Stair 4
A-FloorsSlabs A_BSUK_Slabs | 1F | Stair 4 :7,SHE-06.FOURTH.dgn,Design Model:463141 | A_BSUK_Slabs | Identification - ID | Description: Stair 4
A-FloorsSlabs A_BSUK_Slabs | 1F | Stair 4 :7,SHE-06.FOURTH.dgn,Design Model:463142 | A_BSUK_Slabs | Identification - ID | Description: Stair 4
A-FloorsSlabs A_BSUK_Slabs | 1F | Stair 4 :7,SHE-06.FOURTH.dgn,Design Model:463143 | A_BSUK_Slabs | Identification - ID | Description: Stair 4
A-FloorsSlabs A_BSUK_Slabs | 1F | Stair 4 :7,SHE-06.FOURTH.dgn,Design Model:463144 | A_BSUK_Slabs | Identification - ID | Description: Stair 4
A-FloorsSlabs A_BSUK_Slabs | 1F | Stair 4 :7,SHE-06.FOURTH.dgn,Design Model:463145 | A_BSUK_Slabs | Identification - ID | Description: Stair 4
A-FloorsSlabs A_BSUK_Slabs | 1F | Stair 4 :7,SHE-06.FOURTH.dgn,Design Model:463146 | A_BSUK_Slabs | Identification - ID | Description: Stair 4
A-FloorsSlabs A_BSUK_Slabs | 1F | Stair 4 :7,SHE-06.FOURTH.dgn,Design Model:463147 | A_BSUK_Slabs | Identification - ID | Description: Stair 4
A-FloorsSlabs A_BSUK_Slabs | 1F | Stair 4 :7,SHE-06.FOURTH.dgn,Design Model:463148 | A_BSUK_Slabs | Identification - ID | Description: Stair 4
A-FloorsSlabs A_BSUK_Slabs | 1F | Stair 4 :7,SHE-06.FOURTH.dgn,Design Model:463149 | A_BSUK_Slabs | Identification - ID | Description: Stair 4
A-FloorsSlabs A_BSUK_Slabs | 1F | Stair 3 :7,SHE-06.FOURTH.dgn,Design Model:463516 | A_BSUK_Slabs | Identification - ID | Description: Stair 3
A-FloorsSlabs A_BSUK_Slabs | 1F | Stair 3 :7,SHE-06.FOURTH.dgn,Design Model:463517 | A_BSUK_Slabs | Identification - ID | Description: Stair 3
A-FloorsSlabs A_BSUK_Slabs | 1F | Stair 3 :7,SHE-06.FOURTH.dgn,Design Model:463518 | A_BSUK_Slabs | Identification - ID | Description: Stair 3
A-FloorsSlabs A_BSUK_Slabs | 1F | Stair 3 :7,SHE-06.FOURTH.dgn,Design Model:463519 | A_BSUK_Slabs | Identification - ID | Description: Stair 3
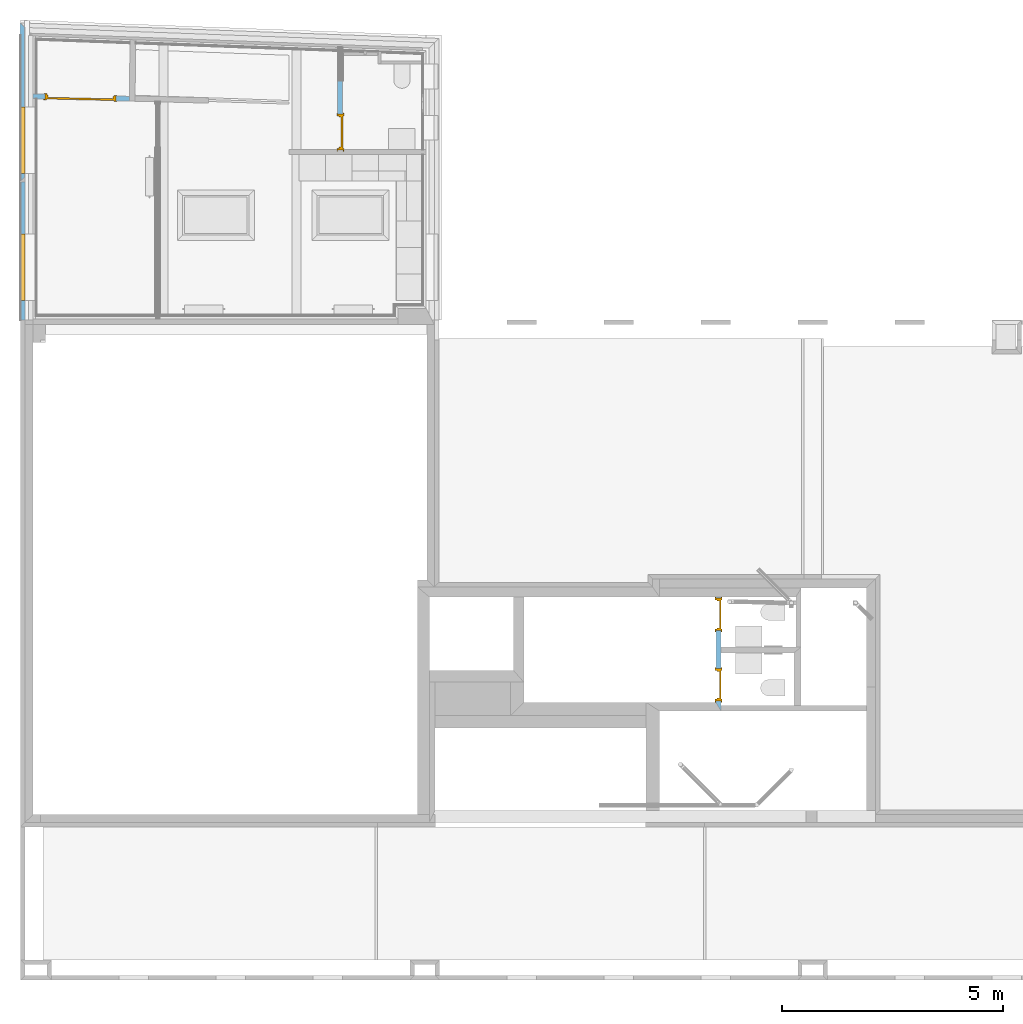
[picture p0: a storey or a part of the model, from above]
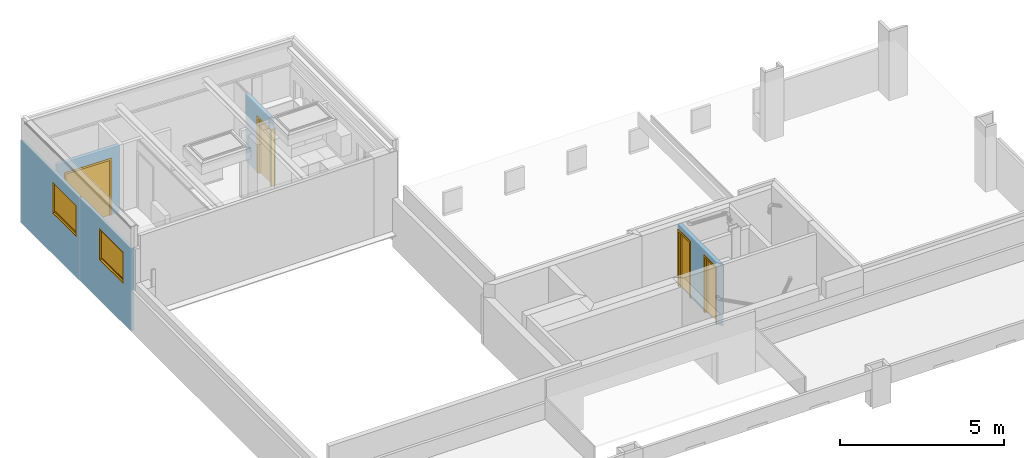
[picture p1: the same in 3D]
Properties of the parts of a building model (IFC2X3), part 11 of 17

# IfcSlab: A-FloorsSlabs A_BSUK_Slabs (1519)
Name | In | Description | Material | Phase | Part Definition
A-FloorsSlabs A_BSUK_Slabs | 1F | Stair 3 :7,SHE-06.FOURTH.dgn,Design Model:463520 | A_BSUK_Slabs | Identification - ID | Description: Stair 3
A-FloorsSlabs A_BSUK_Slabs | 1F | Stair 3 :7,SHE-06.FOURTH.dgn,Design Model:463521 | A_BSUK_Slabs | Identification - ID | Description: Stair 3
A-FloorsSlabs A_BSUK_Slabs | 1F | Stair 3 :7,SHE-06.FOURTH.dgn,Design Model:463522 | A_BSUK_Slabs | Identification - ID | Description: Stair 3
A-FloorsSlabs A_BSUK_Slabs | 1F | Stair 3 :7,SHE-06.FOURTH.dgn,Design Model:463523 | A_BSUK_Slabs | Identification - ID | Description: Stair 3
A-FloorsSlabs A_BSUK_Slabs | 1F | Stair 3 :7,SHE-06.FOURTH.dgn,Design Model:463524 | A_BSUK_Slabs | Identification - ID | Description: Stair 3
A-FloorsSlabs A_BSUK_Slabs | 1F | Stair 3 :7,SHE-06.FOURTH.dgn,Design Model:463525 | A_BSUK_Slabs | Identification - ID | Description: Stair 3
A-FloorsSlabs A_BSUK_Slabs | 1F | Stair 3 :7,SHE-06.FOURTH.dgn,Design Model:463526 | A_BSUK_Slabs | Identification - ID | Description: Stair 3
A-FloorsSlabs A_BSUK_Slabs | 1F | Stair 3 :7,SHE-06.FOURTH.dgn,Design Model:463527 | A_BSUK_Slabs | Identification - ID | Description: Stair 3
A-FloorsSlabs A_BSUK_Slabs | 1F | Stair 3 :7,SHE-06.FOURTH.dgn,Design Model:463528 | A_BSUK_Slabs | Identification - ID | Description: Stair 3
A-FloorsSlabs A_BSUK_Slabs | 1F | Stair 3 :7,SHE-06.FOURTH.dgn,Design Model:463911 | A_BSUK_Slabs | Identification - ID | Description: Stair 3
A-FloorsSlabs A_BSUK_Slabs | 1F | Fire board - ceiling (120 min) :7,SHE-06.FOURTH.dgn,Design Model:467098 | A_BSUK_CeilingSoffitFinishes_Suspended | New Construction | A-Ceilings::A_BSUK_CeilingSoffitFinishes_Suspended | Identification - ID | Description: Fire board - ceiling (120 min)
A-FloorsSlabs A_BSUK_Slabs | 1F | Fire board - ceiling (120 min) :7,SHE-06.FOURTH.dgn,Design Model:468012 | A_BSUK_CeilingSoffitFinishes_Suspended | New Construction | A-Ceilings::A_BSUK_CeilingSoffitFinishes_Suspended | Identification - ID | Description: Fire board - ceiling (120 min)
A-FloorsSlabs A_BSUK_Slabs | 1F | plasterboard - ceiling :7,SHE-06.FOURTH.dgn,Design Model:473692 | A_BSUK_CeilingSoffitFinishes_Suspended | New Construction | A-Ceilings::A_BSUK_CeilingSoffitFinishes_Suspended | Identification - ID | Description: plasterboard - ceiling
A-FloorsSlabs A_BSUK_Slabs | 1F | plasterboard - ceiling :7,SHE-06.FOURTH.dgn,Design Model:489881 | A_BSUK_CeilingSoffitFinishes_Suspended | New Construction | A-Ceilings::A_BSUK_CeilingSoffitFinishes_Suspended | Identification - ID | Description: plasterboard - ceiling
A-FloorsSlabs A_BSUK_Slabs | 1F | plasterboard - ceiling :7,SHE-06.FOURTH.dgn,Design Model:491293 | A_BSUK_CeilingSoffitFinishes_Suspended | New Construction | A-Ceilings::A_BSUK_CeilingSoffitFinishes_Suspended | Identification - ID | Description: plasterboard - ceiling
A-FloorsSlabs A_BSUK_Slabs | 1F | plasterboard - ceiling :7,SHE-06.FOURTH.dgn,Design Model:492526 | A_BSUK_CeilingSoffitFinishes_Suspended | New Construction | A-Ceilings::A_BSUK_CeilingSoffitFinishes_Suspended | Identification - ID | Description: plasterboard - ceiling
A-FloorsSlabs A_BSUK_Slabs | 1F | 7 ,SHE-06.FOURTH.dgn,Design Model:501214 | A_BSUK_CeilingSoffitFinishes_Suspended | New Construction | A-Ceilings::A_BSUK_CeilingSoffitFinishes_Suspended
A-FloorsSlabs A_BSUK_Slabs | 1F | 7 ,SHE-06.FOURTH.dgn,Design Model:501244 | A_BSUK_CeilingSoffitFinishes_Suspended | New Construction | A-Ceilings::A_BSUK_CeilingSoffitFinishes_Suspended
A-FloorsSlabs A_BSUK_Slabs | 1F | 7 ,SHE-06.FOURTH.dgn,Design Model:501324 | A_BSUK_CeilingSoffitFinishes_Suspended | New Construction | A-Ceilings::A_BSUK_CeilingSoffitFinishes_Suspended
A-FloorsSlabs A_BSUK_Slabs | 1F | 7 ,SHE-06.FOURTH.dgn,Design Model:501360 | A_BSUK_CeilingSoffitFinishes_Suspended | New Construction | A-Ceilings::A_BSUK_CeilingSoffitFinishes_Suspended
A-FloorsSlabs A_BSUK_Slabs | 1F | 7 ,SHE-06.FOURTH.dgn,Design Model:505726 | A_BSUK_CeilingSoffitFinishes_Suspended | New Construction | A-Ceilings::A_BSUK_CeilingSoffitFinishes_Suspended
A-FloorsSlabs A_BSUK_Slabs | 1F | 7 ,SHE-06.FOURTH.dgn,Design Model:505871 | A_BSUK_CeilingSoffitFinishes_Suspended | New Construction | A-Ceilings::A_BSUK_CeilingSoffitFinishes_Suspended
A-FloorsSlabs A_BSUK_Slabs | 1F | 7 ,SHE-06.FOURTH.dgn,Design Model:505938 | A_BSUK_CeilingSoffitFinishes_Suspended | New Construction | A-Ceilings::A_BSUK_CeilingSoffitFinishes_Suspended
A-FloorsSlabs A_BSUK_Slabs | 1F | 7 ,SHE-06.FOURTH.dgn,Design Model:505979 | A_BSUK_CeilingSoffitFinishes_Suspended | New Construction | A-Ceilings::A_BSUK_CeilingSoffitFinishes_Suspended
A-FloorsSlabs A_BSUK_Slabs | 1F | 7 ,SHE-06.FOURTH.dgn,Design Model:506020 | A_BSUK_CeilingSoffitFinishes_Suspended | New Construction | A-Ceilings::A_BSUK_CeilingSoffitFinishes_Suspended
A-FloorsSlabs A_BSUK_Slabs | 1F | 7 ,SHE-06.FOURTH.dgn,Design Model:514022 | A_BSUK_Ceramic_WallTiles | New Construction | A-Finishes::A_BSUK_Ceramic_WallTiles
A-FloorsSlabs A_BSUK_Slabs | 1F | 7 ,SHE-06.FOURTH.dgn,Design Model:514111 | A_BSUK_Ceramic_WallTiles | New Construction | A-Finishes::A_BSUK_Ceramic_WallTiles
A-FloorsSlabs A_BSUK_Slabs | 1F | GIFA Dry screed :7,SHE-06.FOURTH.dgn,Design Model:589686 | A_BSUK_InternalFinishes_FloorScreed | New Construction | A-FloorsSlabs::A_BSUK_InternalFinishes_FloorScreed | Identification - ID | Description: GIFA Dry screed
A-FloorsSlabs A_BSUK_Slabs | 1F | GIFA Dry screed :7,SHE-06.FOURTH.dgn,Design Model:589688 | A_BSUK_InternalFinishes_FloorScreed | New Construction | A-FloorsSlabs::A_BSUK_InternalFinishes_FloorScreed | Identification - ID | Description: GIFA Dry screed
A-FloorsSlabs A_BSUK_Slabs | 1F | 12mm MAGPLY :7,SHE-06.FOURTH.dgn,Design Model:590057 | A_BSUK_ExpandedPolystyreneBoards | New Construction | A-FloorsSlabs::A_BSUK_ExpandedPolystyreneBoards | Identification - ID | Description: 12mm MAGPLY
A-FloorsSlabs A_BSUK_Slabs | 1F | 12mm MAGPLY :7,SHE-06.FOURTH.dgn,Design Model:590059 | A_BSUK_ExpandedPolystyreneBoards | New Construction | A-FloorsSlabs::A_BSUK_ExpandedPolystyreneBoards | Identification - ID | Description: 12mm MAGPLY
A-FloorsSlabs A_BSUK_Slabs | 5F | 8 ,SHE-07.FIFTH.dgn,Design Model:125642 | A_BSUK_Slabs
A-FloorsSlabs A_BSUK_Slabs | 5F | 30mm Non-slip paver finish :8,SHE-07.FIFTH.dgn,Design Model:128062 | A_BSUK_ConcreteTiles_Plain | New Construction | A-Finishes::A_BSUK_ConcreteTiles_Plain | Identification - ID | Description: 30mm Non-slip paver finish
A-FloorsSlabs A_BSUK_Slabs | 5F | 15mm CDM MTA :8,SHE-07.FIFTH.dgn,Design Model:165428 | A_BSUK_InternalFinishes_FloorScreed | New Construction | A-FloorsSlabs::A_BSUK_InternalFinishes_FloorScreed | Identification - ID | Description: 15mm CDM MTA
A-FloorsSlabs A_BSUK_Slabs | 5F | 32mm Isocheck 32T :8,SHE-07.FIFTH.dgn,Design Model:177279 | A_BSUK_ExpandedPolystyreneBoards | New Construction | A-FloorsSlabs::A_BSUK_ExpandedPolystyreneBoards | Identification - ID | Description: 32mm Isocheck 32T
A-FloorsSlabs A_BSUK_Slabs | 5F | 32mm Isocheck 32T :8,SHE-07.FIFTH.dgn,Design Model:177361 | A_BSUK_ExpandedPolystyreneBoards | New Construction | A-FloorsSlabs::A_BSUK_ExpandedPolystyreneBoards | Identification - ID | Description: 32mm Isocheck 32T
A-FloorsSlabs A_BSUK_Slabs | 5F | 32mm Isocheck 32T :8,SHE-07.FIFTH.dgn,Design Model:177425 | A_BSUK_ExpandedPolystyreneBoards | New Construction | A-FloorsSlabs::A_BSUK_ExpandedPolystyreneBoards | Identification - ID | Description: 32mm Isocheck 32T
A-FloorsSlabs A_BSUK_Slabs | 5F | 8 ,SHE-07.FIFTH.dgn,Design Model:177489 | A_BSUK_ExpandedPolystyreneBoards | New Construction | A-FloorsSlabs::A_BSUK_ExpandedPolystyreneBoards
A-FloorsSlabs A_BSUK_Slabs | 5F | 8 ,SHE-07.FIFTH.dgn,Design Model:177919 | A_BSUK_Parquet_Floor | New Construction | A-Finishes::A_BSUK_Parquet_Floor
A-FloorsSlabs A_BSUK_Slabs | 5F | 8 ,SHE-07.FIFTH.dgn,Design Model:177920 | A_BSUK_Parquet_Floor | New Construction | A-Finishes::A_BSUK_Parquet_Floor
A-FloorsSlabs A_BSUK_Slabs | 5F | 8 ,SHE-07.FIFTH.dgn,Design Model:177921 | A_BSUK_Parquet_Floor | New Construction | A-Finishes::A_BSUK_Parquet_Floor
A-FloorsSlabs A_BSUK_Slabs | 5F | 8 ,SHE-07.FIFTH.dgn,Design Model:177922 | A_BSUK_Parquet_Floor | New Construction | A-Finishes::A_BSUK_Parquet_Floor
A-FloorsSlabs A_BSUK_Slabs | 5F | 8 ,SHE-07.FIFTH.dgn,Design Model:186063 | A_BSUK_CeilingSoffitFinishes_Suspended | New Construction | A-Ceilings::A_BSUK_CeilingSoffitFinishes_Suspended
A-FloorsSlabs A_BSUK_Slabs | 5F | 8 ,SHE-07.FIFTH.dgn,Design Model:186432 | A_BSUK_CeilingSoffitFinishes_Suspended | New Construction | A-Ceilings::A_BSUK_CeilingSoffitFinishes_Suspended
A-FloorsSlabs A_BSUK_Slabs | 5F | 8 ,SHE-07.FIFTH.dgn,Design Model:186499 | A_BSUK_CeilingSoffitFinishes_Suspended | New Construction | A-Ceilings::A_BSUK_CeilingSoffitFinishes_Suspended
A-FloorsSlabs A_BSUK_Slabs | 5F | 8 ,SHE-07.FIFTH.dgn,Design Model:186553 | A_BSUK_CeilingSoffitFinishes_Suspended | New Construction | A-Ceilings::A_BSUK_CeilingSoffitFinishes_Suspended
A-FloorsSlabs A_BSUK_Slabs | 5F | 8 ,SHE-07.FIFTH.dgn,Design Model:186581 | A_BSUK_CeilingSoffitFinishes_Suspended | New Construction | A-Ceilings::A_BSUK_CeilingSoffitFinishes_Suspended
A-FloorsSlabs A_BSUK_Slabs | 5F | 8 ,SHE-07.FIFTH.dgn,Design Model:186609 | A_BSUK_CeilingSoffitFinishes_Suspended | New Construction | A-Ceilings::A_BSUK_CeilingSoffitFinishes_Suspended
A-FloorsSlabs A_BSUK_Slabs | 5F | 8 ,SHE-07.FIFTH.dgn,Design Model:186637 | A_BSUK_CeilingSoffitFinishes_Suspended | New Construction | A-Ceilings::A_BSUK_CeilingSoffitFinishes_Suspended
A-FloorsSlabs A_BSUK_Slabs | 5F | 8 ,SHE-07.FIFTH.dgn,Design Model:186665 | A_BSUK_CeilingSoffitFinishes_Suspended | New Construction | A-Ceilings::A_BSUK_CeilingSoffitFinishes_Suspended
A-FloorsSlabs A_BSUK_Slabs | 5F | 8 ,SHE-07.FIFTH.dgn,Design Model:186882 | A_BSUK_CeilingSoffitFinishes_Suspended | New Construction | A-Ceilings::A_BSUK_CeilingSoffitFinishes_Suspended
A-FloorsSlabs A_BSUK_Slabs | 5F | 8 ,SHE-07.FIFTH.dgn,Design Model:187054 | A_BSUK_CeilingSoffitFinishes_Suspended | New Construction | A-Ceilings::A_BSUK_CeilingSoffitFinishes_Suspended
A-FloorsSlabs A_BSUK_Slabs | 5F | 8 ,SHE-07.FIFTH.dgn,Design Model:187631 | A_BSUK_CeilingSoffitFinishes_Suspended | New Construction | A-Ceilings::A_BSUK_CeilingSoffitFinishes_Suspended
A-FloorsSlabs A_BSUK_Slabs | 5F | 8 ,SHE-07.FIFTH.dgn,Design Model:188153 | A_BSUK_CeilingSoffitFinishes_Suspended | New Construction | A-Ceilings::A_BSUK_CeilingSoffitFinishes_Suspended
A-FloorsSlabs A_BSUK_Slabs | 5F | 8 ,SHE-07.FIFTH.dgn,Design Model:188991 | A_BSUK_CeilingSoffitFinishes_Suspended | New Construction | A-Ceilings::A_BSUK_CeilingSoffitFinishes_Suspended
A-FloorsSlabs A_BSUK_Slabs | 5F | 8 ,SHE-07.FIFTH.dgn,Design Model:189067 | A_BSUK_CeilingSoffitFinishes_Suspended | New Construction | A-Ceilings::A_BSUK_CeilingSoffitFinishes_Suspended
A-FloorsSlabs A_BSUK_Slabs | 5F | 8 ,SHE-07.FIFTH.dgn,Design Model:189654 | A_BSUK_CeilingSoffitFinishes_Suspended | New Construction | A-Ceilings::A_BSUK_CeilingSoffitFinishes_Suspended
A-FloorsSlabs A_BSUK_Slabs | 5F | 8 ,SHE-07.FIFTH.dgn,Design Model:189957 | A_BSUK_CeilingSoffitFinishes_Suspended | New Construction | A-Ceilings::A_BSUK_CeilingSoffitFinishes_Suspended
A-FloorsSlabs A_BSUK_Slabs | 5F | 8 ,SHE-07.FIFTH.dgn,Design Model:193630 | A_BSUK_CeilingSoffitFinishes_Suspended | New Construction | A-Ceilings::A_BSUK_CeilingSoffitFinishes_Suspended
A-FloorsSlabs A_BSUK_Slabs | 5F | 8 ,SHE-07.FIFTH.dgn,Design Model:194352 | A_BSUK_CeilingSoffitFinishes_Suspended | New Construction | A-Ceilings::A_BSUK_CeilingSoffitFinishes_Suspended
A-FloorsSlabs A_BSUK_Slabs | 5F | 8 ,SHE-07.FIFTH.dgn,Design Model:194432 | A_BSUK_CeilingSoffitFinishes_Suspended | New Construction | A-Ceilings::A_BSUK_CeilingSoffitFinishes_Suspended
A-FloorsSlabs A_BSUK_Slabs | 5F | 8 ,SHE-07.FIFTH.dgn,Design Model:194473 | A_BSUK_CeilingSoffitFinishes_Suspended | New Construction | A-Ceilings::A_BSUK_CeilingSoffitFinishes_Suspended
A-FloorsSlabs A_BSUK_Slabs | 5F | 8 ,SHE-07.FIFTH.dgn,Design Model:194838 | A_BSUK_CeilingSoffitFinishes_Suspended | New Construction | A-Ceilings::A_BSUK_CeilingSoffitFinishes_Suspended
A-FloorsSlabs A_BSUK_Slabs | 5F | 8 ,SHE-07.FIFTH.dgn,Design Model:194839 | A_BSUK_CeilingSoffitFinishes_Suspended | New Construction | A-Ceilings::A_BSUK_CeilingSoffitFinishes_Suspended
A-FloorsSlabs A_BSUK_Slabs | 5F | 8 ,SHE-07.FIFTH.dgn,Design Model:194894 | A_BSUK_CeilingSoffitFinishes_Suspended | New Construction | A-Ceilings::A_BSUK_CeilingSoffitFinishes_Suspended
A-FloorsSlabs A_BSUK_Slabs | 5F | 8 ,SHE-07.FIFTH.dgn,Design Model:194895 | A_BSUK_CeilingSoffitFinishes_Suspended | New Construction | A-Ceilings::A_BSUK_CeilingSoffitFinishes_Suspended
A-FloorsSlabs A_BSUK_Slabs | 5F | 8 ,SHE-07.FIFTH.dgn,Design Model:194950 | A_BSUK_CeilingSoffitFinishes_Suspended | New Construction | A-Ceilings::A_BSUK_CeilingSoffitFinishes_Suspended
A-FloorsSlabs A_BSUK_Slabs | 5F | 8 ,SHE-07.FIFTH.dgn,Design Model:194951 | A_BSUK_CeilingSoffitFinishes_Suspended | New Construction | A-Ceilings::A_BSUK_CeilingSoffitFinishes_Suspended
A-FloorsSlabs A_BSUK_Slabs | 5F | 8 ,SHE-07.FIFTH.dgn,Design Model:195006 | A_BSUK_CeilingSoffitFinishes_Suspended | New Construction | A-Ceilings::A_BSUK_CeilingSoffitFinishes_Suspended
A-FloorsSlabs A_BSUK_Slabs | 5F | 8 ,SHE-07.FIFTH.dgn,Design Model:195007 | A_BSUK_CeilingSoffitFinishes_Suspended | New Construction | A-Ceilings::A_BSUK_CeilingSoffitFinishes_Suspended
A-FloorsSlabs A_BSUK_Slabs | 5F | 8 ,SHE-07.FIFTH.dgn,Design Model:195061 | A_BSUK_CeilingSoffitFinishes_Suspended | New Construction | A-Ceilings::A_BSUK_CeilingSoffitFinishes_Suspended
A-FloorsSlabs A_BSUK_Slabs | 5F | 8 ,SHE-07.FIFTH.dgn,Design Model:195102 | A_BSUK_CeilingSoffitFinishes_Suspended | New Construction | A-Ceilings::A_BSUK_CeilingSoffitFinishes_Suspended
A-FloorsSlabs A_BSUK_Slabs | 5F | 8 ,SHE-07.FIFTH.dgn,Design Model:195130 | A_BSUK_CeilingSoffitFinishes_Suspended | New Construction | A-Ceilings::A_BSUK_CeilingSoffitFinishes_Suspended
A-FloorsSlabs A_BSUK_Slabs | 5F | 8 ,SHE-07.FIFTH.dgn,Design Model:195171 | A_BSUK_CeilingSoffitFinishes_Suspended | New Construction | A-Ceilings::A_BSUK_CeilingSoffitFinishes_Suspended
A-FloorsSlabs A_BSUK_Slabs | 5F | 8 ,SHE-07.FIFTH.dgn,Design Model:195213 | A_BSUK_CeilingSoffitFinishes_Suspended | New Construction | A-Ceilings::A_BSUK_CeilingSoffitFinishes_Suspended
A-FloorsSlabs A_BSUK_Slabs | 5F | 8 ,SHE-07.FIFTH.dgn,Design Model:195214 | A_BSUK_CeilingSoffitFinishes_Suspended | New Construction | A-Ceilings::A_BSUK_CeilingSoffitFinishes_Suspended
A-FloorsSlabs A_BSUK_Slabs | 5F | 8 ,SHE-07.FIFTH.dgn,Design Model:195255 | A_BSUK_CeilingSoffitFinishes_Suspended | New Construction | A-Ceilings::A_BSUK_CeilingSoffitFinishes_Suspended
A-FloorsSlabs A_BSUK_Slabs | 5F | 8 ,SHE-07.FIFTH.dgn,Design Model:195283 | A_BSUK_CeilingSoffitFinishes_Suspended | New Construction | A-Ceilings::A_BSUK_CeilingSoffitFinishes_Suspended
A-FloorsSlabs A_BSUK_Slabs | 5F | 8 ,SHE-07.FIFTH.dgn,Design Model:195311 | A_BSUK_CeilingSoffitFinishes_Suspended | New Construction | A-Ceilings::A_BSUK_CeilingSoffitFinishes_Suspended
A-FloorsSlabs A_BSUK_Slabs | 5F | 8 ,SHE-07.FIFTH.dgn,Design Model:195352 | A_BSUK_CeilingSoffitFinishes_Suspended | New Construction | A-Ceilings::A_BSUK_CeilingSoffitFinishes_Suspended
A-FloorsSlabs A_BSUK_Slabs | 5F | 8 ,SHE-07.FIFTH.dgn,Design Model:195380 | A_BSUK_CeilingSoffitFinishes_Suspended | New Construction | A-Ceilings::A_BSUK_CeilingSoffitFinishes_Suspended
A-FloorsSlabs A_BSUK_Slabs | 5F | 8 ,SHE-07.FIFTH.dgn,Design Model:195421 | A_BSUK_CeilingSoffitFinishes_Suspended | New Construction | A-Ceilings::A_BSUK_CeilingSoffitFinishes_Suspended
A-FloorsSlabs A_BSUK_Slabs | 5F | 8 ,SHE-07.FIFTH.dgn,Design Model:195463 | A_BSUK_CeilingSoffitFinishes_Suspended | New Construction | A-Ceilings::A_BSUK_CeilingSoffitFinishes_Suspended
A-FloorsSlabs A_BSUK_Slabs | 5F | 8 ,SHE-07.FIFTH.dgn,Design Model:195464 | A_BSUK_CeilingSoffitFinishes_Suspended | New Construction | A-Ceilings::A_BSUK_CeilingSoffitFinishes_Suspended
A-FloorsSlabs A_BSUK_Slabs | 5F | 8 ,SHE-07.FIFTH.dgn,Design Model:195533 | A_BSUK_CeilingSoffitFinishes_Suspended | New Construction | A-Ceilings::A_BSUK_CeilingSoffitFinishes_Suspended
A-FloorsSlabs A_BSUK_Slabs | 5F | 8 ,SHE-07.FIFTH.dgn,Design Model:195574 | A_BSUK_CeilingSoffitFinishes_Suspended | New Construction | A-Ceilings::A_BSUK_CeilingSoffitFinishes_Suspended
A-FloorsSlabs A_BSUK_Slabs | 5F | 8 ,SHE-07.FIFTH.dgn,Design Model:195631 | A_BSUK_CeilingSoffitFinishes_Suspended | New Construction | A-Ceilings::A_BSUK_CeilingSoffitFinishes_Suspended
A-FloorsSlabs A_BSUK_Slabs | 5F | 8 ,SHE-07.FIFTH.dgn,Design Model:195632 | A_BSUK_CeilingSoffitFinishes_Suspended | New Construction | A-Ceilings::A_BSUK_CeilingSoffitFinishes_Suspended
A-FloorsSlabs A_BSUK_Slabs | 5F | 8 ,SHE-07.FIFTH.dgn,Design Model:195686 | A_BSUK_CeilingSoffitFinishes_Suspended | New Construction | A-Ceilings::A_BSUK_CeilingSoffitFinishes_Suspended
A-FloorsSlabs A_BSUK_Slabs | 5F | 8 ,SHE-07.FIFTH.dgn,Design Model:195727 | A_BSUK_CeilingSoffitFinishes_Suspended | New Construction | A-Ceilings::A_BSUK_CeilingSoffitFinishes_Suspended
A-FloorsSlabs A_BSUK_Slabs | 5F | 8 ,SHE-07.FIFTH.dgn,Design Model:266283 | A_BSUK_CeilingSoffitFinishes_Suspended | New Construction | A-Ceilings::A_BSUK_CeilingSoffitFinishes_Suspended
A-FloorsSlabs A_BSUK_Slabs | 5F | 8 ,SHE-07.FIFTH.dgn,Design Model:266328 | A_BSUK_CeilingSoffitFinishes_Suspended | New Construction | A-Ceilings::A_BSUK_CeilingSoffitFinishes_Suspended
A-FloorsSlabs A_BSUK_Slabs | 5F | 8 ,SHE-07.FIFTH.dgn,Design Model:266349 | A_BSUK_CeilingSoffitFinishes_Suspended | New Construction | A-Ceilings::A_BSUK_CeilingSoffitFinishes_Suspended
A-FloorsSlabs A_BSUK_Slabs | 5F | 8 ,SHE-07.FIFTH.dgn,Design Model:266689 | A_BSUK_CeilingSoffitFinishes_Suspended | New Construction | A-Ceilings::A_BSUK_CeilingSoffitFinishes_Suspended
A-FloorsSlabs A_BSUK_Slabs | 5F | 8 ,SHE-07.FIFTH.dgn,Design Model:266873 | A_BSUK_CeilingSoffitFinishes_Suspended | New Construction | A-Ceilings::A_BSUK_CeilingSoffitFinishes_Suspended
A-FloorsSlabs A_BSUK_Slabs | 5F | 8 ,SHE-07.FIFTH.dgn,Design Model:266918 | A_BSUK_CeilingSoffitFinishes_Suspended | New Construction | A-Ceilings::A_BSUK_CeilingSoffitFinishes_Suspended
A-FloorsSlabs A_BSUK_Slabs | 5F | 8 ,SHE-07.FIFTH.dgn,Design Model:266939 | A_BSUK_CeilingSoffitFinishes_Suspended | New Construction | A-Ceilings::A_BSUK_CeilingSoffitFinishes_Suspended
A-FloorsSlabs A_BSUK_Slabs | 5F | 8 ,SHE-07.FIFTH.dgn,Design Model:266960 | A_BSUK_CeilingSoffitFinishes_Suspended | New Construction | A-Ceilings::A_BSUK_CeilingSoffitFinishes_Suspended
A-FloorsSlabs A_BSUK_Slabs | 5F | 8 ,SHE-07.FIFTH.dgn,Design Model:295615 | A_BSUK_CeilingSoffitFinishes_Suspended | New Construction | A-Ceilings::A_BSUK_CeilingSoffitFinishes_Suspended
A-FloorsSlabs A_BSUK_Slabs | 5F | 8 ,SHE-07.FIFTH.dgn,Design Model:295813 | A_BSUK_CeilingSoffitFinishes_Suspended | New Construction | A-Ceilings::A_BSUK_CeilingSoffitFinishes_Suspended
A-FloorsSlabs A_BSUK_Slabs | 5F | 8 ,SHE-07.FIFTH.dgn,Design Model:295946 | A_BSUK_CeilingSoffitFinishes_Suspended | New Construction | A-Ceilings::A_BSUK_CeilingSoffitFinishes_Suspended
A-FloorsSlabs A_BSUK_Slabs | 5F | 8 ,SHE-07.FIFTH.dgn,Design Model:295947 | A_BSUK_CeilingSoffitFinishes_Suspended | New Construction | A-Ceilings::A_BSUK_CeilingSoffitFinishes_Suspended
A-FloorsSlabs A_BSUK_Slabs | 5F | 8 ,SHE-07.FIFTH.dgn,Design Model:296100 | A_BSUK_CeilingSoffitFinishes_Suspended | New Construction | A-Ceilings::A_BSUK_CeilingSoffitFinishes_Suspended
A-FloorsSlabs A_BSUK_Slabs | 5F | 8 ,SHE-07.FIFTH.dgn,Design Model:296101 | A_BSUK_CeilingSoffitFinishes_Suspended | New Construction | A-Ceilings::A_BSUK_CeilingSoffitFinishes_Suspended
A-FloorsSlabs A_BSUK_Slabs | 5F | 8 ,SHE-07.FIFTH.dgn,Design Model:296251 | A_BSUK_CeilingSoffitFinishes_Suspended | New Construction | A-Ceilings::A_BSUK_CeilingSoffitFinishes_Suspended
A-FloorsSlabs A_BSUK_Slabs | 5F | 8 ,SHE-07.FIFTH.dgn,Design Model:296252 | A_BSUK_CeilingSoffitFinishes_Suspended | New Construction | A-Ceilings::A_BSUK_CeilingSoffitFinishes_Suspended
A-FloorsSlabs A_BSUK_Slabs | 5F | 18mm GIFA Dry screed :8,SHE-07.FIFTH.dgn,Design Model:367153 | A_BSUK_InternalFinishes_FloorScreed | New Construction | A-FloorsSlabs::A_BSUK_InternalFinishes_FloorScreed | Identification - ID | Description: 18mm GIFA Dry screed
A-FloorsSlabs A_BSUK_Slabs | 5F | 12mm MAGPLY :8,SHE-07.FIFTH.dgn,Design Model:367464 | A_BSUK_ExpandedPolystyreneBoards | New Construction | A-FloorsSlabs::A_BSUK_ExpandedPolystyreneBoards | Identification - ID | Description: 12mm MAGPLY
A-FloorsSlabs A_BSUK_Slabs | 5F | Fire barrier (Broof T4 compliant) :8,SHE-07.FIFTH.dgn,Design Model:377926 | A_BSUK_FireSecurityAndProtection |  | A-Protection::A_BSUK_FireSecurityAndProtection | Identification - ID | Description: Fire barrier (Broof T4 compliant)
A-FloorsSlabs A_BSUK_Slabs | 5F | Fire barrier (Broof T4 compliant) :8,SHE-07.FIFTH.dgn,Design Model:378007 | A_BSUK_FireSecurityAndProtection |  | A-Protection::A_BSUK_FireSecurityAndProtection | Identification - ID | Description: Fire barrier (Broof T4 compliant)
A-FloorsSlabs A_BSUK_Slabs | 5F | Fire barrier (Broof T4 compliant) :8,SHE-07.FIFTH.dgn,Design Model:378048 | A_BSUK_FireSecurityAndProtection |  | A-Protection::A_BSUK_FireSecurityAndProtection | Identification - ID | Description: Fire barrier (Broof T4 compliant)
A-FloorsSlabs A_BSUK_Slabs | 5F | Fire barrier (Broof T4 compliant) :8,SHE-07.FIFTH.dgn,Design Model:378102 | A_BSUK_FireSecurityAndProtection |  | A-Protection::A_BSUK_FireSecurityAndProtection | Identification - ID | Description: Fire barrier (Broof T4 compliant)
A-FloorsSlabs A_BSUK_Slabs | 5F | Fire barrier (Broof T4 compliant) :8,SHE-07.FIFTH.dgn,Design Model:378143 | A_BSUK_FireSecurityAndProtection |  | A-Protection::A_BSUK_FireSecurityAndProtection | Identification - ID | Description: Fire barrier (Broof T4 compliant)
A-FloorsSlabs A_BSUK_Slabs | 5F | Fire barrier (Broof T4 compliant) :8,SHE-07.FIFTH.dgn,Design Model:378184 | A_BSUK_FireSecurityAndProtection |  | A-Protection::A_BSUK_FireSecurityAndProtection | Identification - ID | Description: Fire barrier (Broof T4 compliant)
A-FloorsSlabs A_BSUK_Slabs | 5F | Fire barrier (Broof T4 compliant) :8,SHE-07.FIFTH.dgn,Design Model:378251 | A_BSUK_FireSecurityAndProtection |  | A-Protection::A_BSUK_FireSecurityAndProtection | Identification - ID | Description: Fire barrier (Broof T4 compliant)
A-FloorsSlabs A_BSUK_Slabs | 5F | Fire barrier (Broof T4 compliant) :8,SHE-07.FIFTH.dgn,Design Model:378305 | A_BSUK_FireSecurityAndProtection |  | A-Protection::A_BSUK_FireSecurityAndProtection | Identification - ID | Description: Fire barrier (Broof T4 compliant)
A-FloorsSlabs A_BSUK_Slabs | 5F | Fire barrier (Broof T4 compliant) :8,SHE-07.FIFTH.dgn,Design Model:378385 | A_BSUK_FireSecurityAndProtection |  | A-Protection::A_BSUK_FireSecurityAndProtection | Identification - ID | Description: Fire barrier (Broof T4 compliant)
A-FloorsSlabs A_BSUK_Slabs | 5F | Fire barrier (Broof T4 compliant) :8,SHE-07.FIFTH.dgn,Design Model:378532 | A_BSUK_FireSecurityAndProtection |  | A-Protection::A_BSUK_FireSecurityAndProtection | Identification - ID | Description: Fire barrier (Broof T4 compliant)
A-FloorsSlabs A_BSUK_Slabs | 5F | Bauder VIP TE (Flatboard Insulation) :8,SHE-07.FIFTH.dgn,Design Model:378643 | A_BSUK_ExpandedPolystyreneBoards | New Construction | A-FloorsSlabs::A_BSUK_ExpandedPolystyreneBoards | Identification - ID | Description: Bauder VIP TE (Flatboard Insulation)
A-FloorsSlabs A_BSUK_Slabs | 5F | Deck (PLY) :8,SHE-07.FIFTH.dgn,Design Model:378710 | A_BSUK_Timber_Miscellaneous | New Construction | A-FrameElements::A_BSUK_Timber_Miscellaneous | Identification - ID | Description: Deck (PLY)
A-FloorsSlabs A_BSUK_Slabs | 5F | 30mm Non-slip paver finish :8,SHE-07.FIFTH.dgn,Design Model:378817 | A_BSUK_ConcreteTiles_Plain | New Construction | A-Finishes::A_BSUK_ConcreteTiles_Plain | Identification - ID | Description: 30mm Non-slip paver finish
A-FloorsSlabs A_BSUK_Slabs | 5F | Bauder VIP TE (Flatboard Insulation) :8,SHE-07.FIFTH.dgn,Design Model:378818 | A_BSUK_ExpandedPolystyreneBoards | New Construction | A-FloorsSlabs::A_BSUK_ExpandedPolystyreneBoards | Identification - ID | Description: Bauder VIP TE (Flatboard Insulation)
A-FloorsSlabs A_BSUK_Slabs | 5F | Deck (PLY) :8,SHE-07.FIFTH.dgn,Design Model:378819 | A_BSUK_Timber_Miscellaneous | New Construction | A-FrameElements::A_BSUK_Timber_Miscellaneous | Identification - ID | Description: Deck (PLY)
A-FloorsSlabs A_BSUK_Slabs | 5F | Fire barrier (Broof T4 compliant) :8,SHE-07.FIFTH.dgn,Design Model:386432 | A_BSUK_FireSecurityAndProtection |  | A-Protection::A_BSUK_FireSecurityAndProtection | Identification - ID | Description: Fire barrier (Broof T4 compliant)
A-FloorsSlabs A_BSUK_Slabs | 5F | Fire barrier (Broof T4 compliant) :8,SHE-07.FIFTH.dgn,Design Model:386433 | A_BSUK_FireSecurityAndProtection |  | A-Protection::A_BSUK_FireSecurityAndProtection | Identification - ID | Description: Fire barrier (Broof T4 compliant)
A-FloorsSlabs A_BSUK_Slabs | 5F | Fire barrier (Broof T4 compliant) :8,SHE-07.FIFTH.dgn,Design Model:386487 | A_BSUK_FireSecurityAndProtection |  | A-Protection::A_BSUK_FireSecurityAndProtection | Identification - ID | Description: Fire barrier (Broof T4 compliant)
A-FloorsSlabs A_BSUK_Slabs | 5F | Fire barrier (Broof T4 compliant) :8,SHE-07.FIFTH.dgn,Design Model:386528 | A_BSUK_FireSecurityAndProtection |  | A-Protection::A_BSUK_FireSecurityAndProtection | Identification - ID | Description: Fire barrier (Broof T4 compliant)
A-FloorsSlabs A_BSUK_Slabs | 5F | Fire barrier (Broof T4 compliant) :8,SHE-07.FIFTH.dgn,Design Model:386933 | A_BSUK_FireSecurityAndProtection |  | A-Protection::A_BSUK_FireSecurityAndProtection | Identification - ID | Description: Fire barrier (Broof T4 compliant)
A-FloorsSlabs A_BSUK_Slabs | 5F | 8 ,SHE-07.FIFTH.dgn,Design Model:387342 | A_BSUK_ExpandedPolystyreneBoards |  | A-FloorsSlabs::A_BSUK_ExpandedPolystyreneBoards
A-FloorsSlabs A_BSUK_Slabs | 5F | 8 ,SHE-07.FIFTH.dgn,Design Model:387397 | A_BSUK_ExpandedPolystyreneBoards |  | A-FloorsSlabs::A_BSUK_ExpandedPolystyreneBoards
A-FloorsSlabs A_BSUK_Slabs | 5F | 8 ,SHE-07.FIFTH.dgn,Design Model:387451 | A_BSUK_ExpandedPolystyreneBoards |  | A-FloorsSlabs::A_BSUK_ExpandedPolystyreneBoards
A-FloorsSlabs A_BSUK_Slabs | 5F | 8 ,SHE-07.FIFTH.dgn,Design Model:387609 | A_BSUK_ExpandedPolystyreneBoards |  | A-FloorsSlabs::A_BSUK_ExpandedPolystyreneBoards
A-FloorsSlabs A_BSUK_Slabs | 5F | 8 ,SHE-07.FIFTH.dgn,Design Model:387676 | A_BSUK_ExpandedPolystyreneBoards |  | A-FloorsSlabs::A_BSUK_ExpandedPolystyreneBoards
A-FloorsSlabs A_BSUK_Slabs | 5F | 8 ,SHE-07.FIFTH.dgn,Design Model:387757 | A_BSUK_ExpandedPolystyreneBoards |  | A-FloorsSlabs::A_BSUK_ExpandedPolystyreneBoards
A-FloorsSlabs A_BSUK_Slabs | 5F | 8 ,SHE-07.FIFTH.dgn,Design Model:388095 | A_BSUK_ExpandedPolystyreneBoards |  | A-FloorsSlabs::A_BSUK_ExpandedPolystyreneBoards
A-FloorsSlabs A_BSUK_Slabs | 5F | 8 ,SHE-07.FIFTH.dgn,Design Model:388242 | A_BSUK_ExpandedPolystyreneBoards |  | A-FloorsSlabs::A_BSUK_ExpandedPolystyreneBoards
A-FloorsSlabs A_BSUK_Slabs | 5F | 8 ,SHE-07.FIFTH.dgn,Design Model:388615 | A_BSUK_Roofs |  | A-Roofs::A_BSUK_Roofs
A-FloorsSlabs A_BSUK_Slabs | 5F | 8 ,SHE-07.FIFTH.dgn,Design Model:388669 | A_BSUK_Roofs |  | A-Roofs::A_BSUK_Roofs
A-FloorsSlabs A_BSUK_Slabs | 5F | 8 ,SHE-07.FIFTH.dgn,Design Model:388777 | A_BSUK_Roofs |  | A-Roofs::A_BSUK_Roofs
A-FloorsSlabs A_BSUK_Slabs | 5F | 8 ,SHE-07.FIFTH.dgn,Design Model:388844 | A_BSUK_Roofs |  | A-Roofs::A_BSUK_Roofs
A-FloorsSlabs A_BSUK_Slabs | 5F | 8 ,SHE-07.FIFTH.dgn,Design Model:388897 | A_BSUK_Roofs |  | A-Roofs::A_BSUK_Roofs
A-FloorsSlabs A_BSUK_Slabs | 5F | 8 ,SHE-07.FIFTH.dgn,Design Model:389288 | A_BSUK_Roofs |  | A-Roofs::A_BSUK_Roofs
A-FloorsSlabs A_BSUK_Slabs | 5F | 8 ,SHE-07.FIFTH.dgn,Design Model:389328 | A_BSUK_Roofs |  | A-Roofs::A_BSUK_Roofs
A-FloorsSlabs A_BSUK_Slabs | 5F | 8 ,SHE-07.FIFTH.dgn,Design Model:389421 | A_BSUK_Steel_Miscellaneous |  | A-FrameElements::A_BSUK_Steel_Miscellaneous
A-FloorsSlabs A_BSUK_Slabs | 5F | 8 ,SHE-07.FIFTH.dgn,Design Model:390046 | A_BSUK_ExpandedPolystyreneBoards |  | A-FloorsSlabs::A_BSUK_ExpandedPolystyreneBoards
A-FloorsSlabs A_BSUK_Slabs | 5F | 8 ,SHE-07.FIFTH.dgn,Design Model:390075 | A_BSUK_ExpandedPolystyreneBoards |  | A-FloorsSlabs::A_BSUK_ExpandedPolystyreneBoards
A-FloorsSlabs A_BSUK_Slabs | 5F | 8 ,SHE-07.FIFTH.dgn,Design Model:390090 | A_BSUK_ExpandedPolystyreneBoards |  | A-FloorsSlabs::A_BSUK_ExpandedPolystyreneBoards
A-FloorsSlabs A_BSUK_Slabs | 5F | 8 ,SHE-07.FIFTH.dgn,Design Model:390105 | A_BSUK_ExpandedPolystyreneBoards |  | A-FloorsSlabs::A_BSUK_ExpandedPolystyreneBoards
A-FloorsSlabs A_BSUK_Slabs | 5F | 8 ,SHE-07.FIFTH.dgn,Design Model:390120 | A_BSUK_ExpandedPolystyreneBoards |  | A-FloorsSlabs::A_BSUK_ExpandedPolystyreneBoards
A-FloorsSlabs A_BSUK_Slabs | 5F | 8 ,SHE-07.FIFTH.dgn,Design Model:390135 | A_BSUK_ExpandedPolystyreneBoards |  | A-FloorsSlabs::A_BSUK_ExpandedPolystyreneBoards
A-FloorsSlabs A_BSUK_Slabs | 5F | 8 ,SHE-07.FIFTH.dgn,Design Model:390136 | A_BSUK_ExpandedPolystyreneBoards |  | A-FloorsSlabs::A_BSUK_ExpandedPolystyreneBoards
A-FloorsSlabs A_BSUK_Slabs | 5F | 8 ,SHE-07.FIFTH.dgn,Design Model:390189 | A_BSUK_ExpandedPolystyreneBoards |  | A-FloorsSlabs::A_BSUK_ExpandedPolystyreneBoards
A-FloorsSlabs A_BSUK_Slabs | 5F | 8 ,SHE-07.FIFTH.dgn,Design Model:390204 | A_BSUK_Roofs |  | A-Roofs::A_BSUK_Roofs
A-FloorsSlabs A_BSUK_Slabs | 5F | 8 ,SHE-07.FIFTH.dgn,Design Model:390219 | A_BSUK_Roofs |  | A-Roofs::A_BSUK_Roofs
A-FloorsSlabs A_BSUK_Slabs | 5F | 8 ,SHE-07.FIFTH.dgn,Design Model:390234 | A_BSUK_Roofs |  | A-Roofs::A_BSUK_Roofs
A-FloorsSlabs A_BSUK_Slabs | 5F | 8 ,SHE-07.FIFTH.dgn,Design Model:390249 | A_BSUK_Roofs |  | A-Roofs::A_BSUK_Roofs
A-FloorsSlabs A_BSUK_Slabs | 5F | 8 ,SHE-07.FIFTH.dgn,Design Model:390276 | A_BSUK_Roofs |  | A-Roofs::A_BSUK_Roofs
A-FloorsSlabs A_BSUK_Slabs | 5F | 8 ,SHE-07.FIFTH.dgn,Design Model:390303 | A_BSUK_Roofs |  | A-Roofs::A_BSUK_Roofs
A-FloorsSlabs A_BSUK_Slabs | 5F | 8 ,SHE-07.FIFTH.dgn,Design Model:390318 | A_BSUK_Roofs |  | A-Roofs::A_BSUK_Roofs
A-FloorsSlabs A_BSUK_Slabs | 5F | 8 ,SHE-07.FIFTH.dgn,Design Model:390333 | A_BSUK_Steel_Miscellaneous |  | A-FrameElements::A_BSUK_Steel_Miscellaneous
A-FloorsSlabs A_BSUK_Slabs | GF | 9 ,SHE-10.CONCRETE.dgn,Design Model:205626 | A_BSUK_Slabs | Existing to Remain
A-FloorsSlabs A_BSUK_Slabs | GF | 9 ,SHE-10.CONCRETE.dgn,Design Model:205640 | A_BSUK_Slabs | Existing to Remain
A-FloorsSlabs A_BSUK_Slabs | GF | 9 ,SHE-10.CONCRETE.dgn,Design Model:205654 | A_BSUK_Slabs | Existing to Remain
A-FloorsSlabs A_BSUK_Slabs | GF | 9 ,SHE-10.CONCRETE.dgn,Design Model:205668 | A_BSUK_Slabs | Existing to Remain
A-FloorsSlabs A_BSUK_Slabs | GF | 9 ,SHE-10.CONCRETE.dgn,Design Model:205682 | A_BSUK_Slabs | Existing to Remain
A-FloorsSlabs A_BSUK_Slabs | GF | 9 ,SHE-10.CONCRETE.dgn,Design Model:205696 | A_BSUK_Slabs | Existing to Remain
A-FloorsSlabs A_BSUK_Slabs | GF | 9 ,SHE-10.CONCRETE.dgn,Design Model:205710 | A_BSUK_Slabs | Existing to Remain
A-FloorsSlabs A_BSUK_Slabs | GF | 9 ,SHE-10.CONCRETE.dgn,Design Model:205724 | A_BSUK_Slabs | Existing to Remain
A-FloorsSlabs A_BSUK_Slabs | GF | 9 ,SHE-10.CONCRETE.dgn,Design Model:205752 | A_BSUK_Slabs | Existing to Remain
A-FloorsSlabs A_BSUK_Slabs | GF | 9 ,SHE-10.CONCRETE.dgn,Design Model:205766 | A_BSUK_Slabs | Existing to Remain
A-FloorsSlabs A_BSUK_Slabs | GF | 9 ,SHE-10.CONCRETE.dgn,Design Model:205780 | A_BSUK_Slabs | Existing to Remain
A-FloorsSlabs A_BSUK_Slabs | GF | 9 ,SHE-10.CONCRETE.dgn,Design Model:205794 | A_BSUK_Slabs | Existing to Remain
A-FloorsSlabs A_BSUK_Slabs | GF | 9 ,SHE-10.CONCRETE.dgn,Design Model:222997 | A_BSUK_Slabs | Existing to Remain
A-FloorsSlabs A_BSUK_Slabs | GF | 9 ,SHE-10.CONCRETE.dgn,Design Model:223011 | A_BSUK_Slabs | Existing to Remain
A-FloorsSlabs A_BSUK_Slabs | GF | 9 ,SHE-10.CONCRETE.dgn,Design Model:314619 | A_BSUK_Slabs | Existing to Remain
A-FloorsSlabs A_BSUK_Slabs | GF | 9 ,SHE-10.CONCRETE.dgn,Design Model:314660 | A_BSUK_Slabs | Existing to Remain
A-FloorsSlabs A_BSUK_Slabs | GF | 9 ,SHE-10.CONCRETE.dgn,Design Model:314680 | A_BSUK_Slabs | Existing to Remain
A-FloorsSlabs A_BSUK_Slabs | GF | 9 ,SHE-10.CONCRETE.dgn,Design Model:314694 | A_BSUK_Slabs | Existing to Remain
A-FloorsSlabs A_BSUK_Slabs | GF | 9 ,SHE-10.CONCRETE.dgn,Design Model:314709 | A_BSUK_Slabs | Existing to Remain
A-FloorsSlabs A_BSUK_Slabs | GF | 9 ,SHE-10.CONCRETE.dgn,Design Model:314723 | A_BSUK_Slabs | Existing to Remain
A-FloorsSlabs A_BSUK_Slabs | GF | 9 ,SHE-10.CONCRETE.dgn,Design Model:314737 | A_BSUK_Slabs | Existing to Remain
A-FloorsSlabs A_BSUK_Slabs | GF | 9 ,SHE-10.CONCRETE.dgn,Design Model:314751 | A_BSUK_Slabs | Existing to Remain
A-FloorsSlabs A_BSUK_Slabs | GF | 9 ,SHE-10.CONCRETE.dgn,Design Model:314765 | A_BSUK_Slabs | Existing to Remain
A-FloorsSlabs A_BSUK_Slabs | GF | 9 ,SHE-10.CONCRETE.dgn,Design Model:314779 | A_BSUK_Slabs | Existing to Remain
A-FloorsSlabs A_BSUK_Slabs | GF | 9 ,SHE-10.CONCRETE.dgn,Design Model:314793 | A_BSUK_Slabs | Existing to Remain
A-FloorsSlabs A_BSUK_Slabs | GF | 9 ,SHE-10.CONCRETE.dgn,Design Model:314807 | A_BSUK_Slabs | Existing to Remain
A-FloorsSlabs A_BSUK_Slabs | GF | 9 ,SHE-10.CONCRETE.dgn,Design Model:208086 | A_BSUK_Slabs | Existing to Remain
A-FloorsSlabs A_BSUK_Slabs | GF | 9 ,SHE-10.CONCRETE.dgn,Design Model:208100 | A_BSUK_Slabs | Existing to Remain
A-FloorsSlabs A_BSUK_Slabs | GF | 9 ,SHE-10.CONCRETE.dgn,Design Model:208114 | A_BSUK_Slabs | Existing to Remain
A-FloorsSlabs A_BSUK_Slabs | GF | 9 ,SHE-10.CONCRETE.dgn,Design Model:208128 | A_BSUK_Slabs | Existing to Remain
A-FloorsSlabs A_BSUK_Slabs | GF | 9 ,SHE-10.CONCRETE.dgn,Design Model:208142 | A_BSUK_Slabs | Existing to Remain
A-FloorsSlabs A_BSUK_Slabs | GF | 9 ,SHE-10.CONCRETE.dgn,Design Model:208156 | A_BSUK_Slabs | Existing to Remain
A-FloorsSlabs A_BSUK_Slabs | GF | 9 ,SHE-10.CONCRETE.dgn,Design Model:208170 | A_BSUK_Slabs | Existing to Remain
A-FloorsSlabs A_BSUK_Slabs | GF | 9 ,SHE-10.CONCRETE.dgn,Design Model:208184 | A_BSUK_Slabs | Existing to Remain
A-FloorsSlabs A_BSUK_Slabs | GF | 9 ,SHE-10.CONCRETE.dgn,Design Model:208198 | A_BSUK_Slabs | Existing to Remain
A-FloorsSlabs A_BSUK_Slabs | GF | 9 ,SHE-10.CONCRETE.dgn,Design Model:208212 | A_BSUK_Slabs | Existing to Remain
A-FloorsSlabs A_BSUK_Slabs | GF | 9 ,SHE-10.CONCRETE.dgn,Design Model:208226 | A_BSUK_Slabs | Existing to Remain
A-FloorsSlabs A_BSUK_Slabs | GF | 9 ,SHE-10.CONCRETE.dgn,Design Model:208240 | A_BSUK_Slabs | Existing to Remain
A-FloorsSlabs A_BSUK_Slabs | GF | 9 ,SHE-10.CONCRETE.dgn,Design Model:208254 | A_BSUK_Slabs | Existing to Remain
A-FloorsSlabs A_BSUK_Slabs | GF | 9 ,SHE-10.CONCRETE.dgn,Design Model:208268 | A_BSUK_Slabs | Existing to Remain
A-FloorsSlabs A_BSUK_Slabs | GF | 9 ,SHE-10.CONCRETE.dgn,Design Model:208282 | A_BSUK_Slabs | Existing to Remain
A-FloorsSlabs A_BSUK_Slabs | GF | 9 ,SHE-10.CONCRETE.dgn,Design Model:208296 | A_BSUK_Slabs | Existing to Remain
A-FloorsSlabs A_BSUK_Slabs | GF | 9 ,SHE-10.CONCRETE.dgn,Design Model:208310 | A_BSUK_Slabs | Existing to Remain
A-FloorsSlabs A_BSUK_Slabs | GF | 9 ,SHE-10.CONCRETE.dgn,Design Model:208324 | A_BSUK_Slabs | Existing to Remain
A-FloorsSlabs A_BSUK_Slabs | GF | 9 ,SHE-10.CONCRETE.dgn,Design Model:208338 | A_BSUK_Slabs | Existing to Remain
A-FloorsSlabs A_BSUK_Slabs | GF | 9 ,SHE-10.CONCRETE.dgn,Design Model:208352 | A_BSUK_Slabs | Existing to Remain
A-FloorsSlabs A_BSUK_Slabs | GF | 9 ,SHE-10.CONCRETE.dgn,Design Model:208366 | A_BSUK_Slabs | Existing to Remain
A-FloorsSlabs A_BSUK_Slabs | GF | 9 ,SHE-10.CONCRETE.dgn,Design Model:208380 | A_BSUK_Slabs | Existing to Remain
A-FloorsSlabs A_BSUK_Slabs | GF | 9 ,SHE-10.CONCRETE.dgn,Design Model:208394 | A_BSUK_Slabs | Existing to Remain
A-FloorsSlabs A_BSUK_Slabs | GF | 9 ,SHE-10.CONCRETE.dgn,Design Model:208408 | A_BSUK_Slabs | Existing to Remain
A-FloorsSlabs A_BSUK_Slabs | GF | 9 ,SHE-10.CONCRETE.dgn,Design Model:205625 | A_BSUK_Slabs | Existing to Remain
A-FloorsSlabs A_BSUK_Slabs | GF | 9 ,SHE-10.CONCRETE.dgn,Design Model:205834 | A_BSUK_Slabs
A-FloorsSlabs A_BSUK_Slabs | GF | 9 ,SHE-10.CONCRETE.dgn,Design Model:205982 | A_BSUK_Slabs
A-FloorsSlabs A_BSUK_Slabs | GF | 9 ,SHE-10.CONCRETE.dgn,Design Model:209136 | A_BSUK_Slabs | Existing to Remain
A-FloorsSlabs A_BSUK_Slabs | GF | 9 ,SHE-10.CONCRETE.dgn,Design Model:209137 | A_BSUK_Slabs | Existing to Remain
A-FloorsSlabs A_BSUK_Slabs | GF | 9 ,SHE-10.CONCRETE.dgn,Design Model:209206 | A_BSUK_Slabs | Existing to Remain
A-FloorsSlabs A_BSUK_Slabs | GF | 9 ,SHE-10.CONCRETE.dgn,Design Model:209616 | A_BSUK_Slabs | Existing to Remain
A-FloorsSlabs A_BSUK_Slabs | GF | 9 ,SHE-10.CONCRETE.dgn,Design Model:211024 | A_BSUK_Slabs | Existing to Remain
A-FloorsSlabs A_BSUK_Slabs | GF | 9 ,SHE-10.CONCRETE.dgn,Design Model:211025 | A_BSUK_Slabs | Existing to Remain
A-FloorsSlabs A_BSUK_Slabs | GF | 9 ,SHE-10.CONCRETE.dgn,Design Model:211092 | A_BSUK_Slabs | Existing to Remain
A-FloorsSlabs A_BSUK_Slabs | GF | 9 ,SHE-10.CONCRETE.dgn,Design Model:211093 | A_BSUK_Slabs | Existing to Remain
A-FloorsSlabs A_BSUK_Slabs | GF | 9 ,SHE-10.CONCRETE.dgn,Design Model:211315 | A_BSUK_Slabs | Existing to Remain
A-FloorsSlabs A_BSUK_Slabs | GF | 9 ,SHE-10.CONCRETE.dgn,Design Model:316944 | A_BSUK_Slabs | Existing to Remain
A-FloorsSlabs A_BSUK_Slabs | GF | 9 ,SHE-10.CONCRETE.dgn,Design Model:316945 | A_BSUK_Slabs
A-FloorsSlabs A_BSUK_Slabs | RL | 10 ,SHE-08.ROOF.dgn,Design Model:105330 | A_BSUK_Roofs | New Construction | A-Roofs::A_BSUK_Roofs
A-FloorsSlabs A_BSUK_Slabs | RL | 10 ,SHE-08.ROOF.dgn,Design Model:105344 | A_BSUK_Roofs | New Construction | A-Roofs::A_BSUK_Roofs
A-FloorsSlabs A_BSUK_Slabs | RL | 10 ,SHE-08.ROOF.dgn,Design Model:105359 | A_BSUK_Roofs | New Construction | A-Roofs::A_BSUK_Roofs
A-FloorsSlabs A_BSUK_Slabs | RL | 10 ,SHE-08.ROOF.dgn,Design Model:105370 | A_BSUK_Roofs | New Construction | A-Roofs::A_BSUK_Roofs
A-FloorsSlabs A_BSUK_Slabs | RL | 10 ,SHE-08.ROOF.dgn,Design Model:105384 | A_BSUK_Roofs | New Construction | A-Roofs::A_BSUK_Roofs
A-FloorsSlabs A_BSUK_Slabs | RL | 10 ,SHE-08.ROOF.dgn,Design Model:105398 | A_BSUK_Roofs | New Construction | A-Roofs::A_BSUK_Roofs
A-FloorsSlabs A_BSUK_Slabs | RL | 10 ,SHE-08.ROOF.dgn,Design Model:105412 | A_BSUK_Roofs | New Construction | A-Roofs::A_BSUK_Roofs
A-FloorsSlabs A_BSUK_Slabs | RL | 10 ,SHE-08.ROOF.dgn,Design Model:105426 | A_BSUK_Roofs | New Construction | A-Roofs::A_BSUK_Roofs
A-FloorsSlabs A_BSUK_Slabs | RL | 10 ,SHE-08.ROOF.dgn,Design Model:105440 | A_BSUK_Roofs | New Construction | A-Roofs::A_BSUK_Roofs
A-FloorsSlabs A_BSUK_Slabs | RL | 10 ,SHE-08.ROOF.dgn,Design Model:105454 | A_BSUK_Roofs | New Construction | A-Roofs::A_BSUK_Roofs
A-FloorsSlabs A_BSUK_Slabs | RL | 10 ,SHE-08.ROOF.dgn,Design Model:105468 | A_BSUK_Roofs | New Construction | A-Roofs::A_BSUK_Roofs
A-FloorsSlabs A_BSUK_Slabs | RL | 10 ,SHE-08.ROOF.dgn,Design Model:105482 | A_BSUK_Roofs | New Construction | A-Roofs::A_BSUK_Roofs
A-FloorsSlabs A_BSUK_Slabs | RL | 10 ,SHE-08.ROOF.dgn,Design Model:105497 | A_BSUK_Roofs | New Construction | A-Roofs::A_BSUK_Roofs
A-FloorsSlabs A_BSUK_Slabs | RL | 10 ,SHE-08.ROOF.dgn,Design Model:105508 | A_BSUK_Roofs | New Construction | A-Roofs::A_BSUK_Roofs
A-FloorsSlabs A_BSUK_Slabs | RL | 10 ,SHE-08.ROOF.dgn,Design Model:105522 | A_BSUK_Roofs | New Construction | A-Roofs::A_BSUK_Roofs
A-FloorsSlabs A_BSUK_Slabs | RL | 10 ,SHE-08.ROOF.dgn,Design Model:105536 | A_BSUK_Roofs | New Construction | A-Roofs::A_BSUK_Roofs
A-FloorsSlabs A_BSUK_Slabs | RL | 10 ,SHE-08.ROOF.dgn,Design Model:105551 | A_BSUK_Roofs | New Construction | A-Roofs::A_BSUK_Roofs
A-FloorsSlabs A_BSUK_Slabs | RL | 10 ,SHE-08.ROOF.dgn,Design Model:105562 | A_BSUK_Roofs | New Construction | A-Roofs::A_BSUK_Roofs
A-FloorsSlabs A_BSUK_Slabs | RL | 10 ,SHE-08.ROOF.dgn,Design Model:105576 | A_BSUK_Roofs | New Construction | A-Roofs::A_BSUK_Roofs
A-FloorsSlabs A_BSUK_Slabs | RL | 10 ,SHE-08.ROOF.dgn,Design Model:105590 | A_BSUK_Roofs | New Construction | A-Roofs::A_BSUK_Roofs
A-FloorsSlabs A_BSUK_Slabs | RL | 10 ,SHE-08.ROOF.dgn,Design Model:105604 | A_BSUK_Roofs | New Construction | A-Roofs::A_BSUK_Roofs
A-FloorsSlabs A_BSUK_Slabs | RL | 10 ,SHE-08.ROOF.dgn,Design Model:105618 | A_BSUK_Roofs | New Construction | A-Roofs::A_BSUK_Roofs
A-FloorsSlabs A_BSUK_Slabs | RL | 10 ,SHE-08.ROOF.dgn,Design Model:105632 | A_BSUK_Roofs | New Construction | A-Roofs::A_BSUK_Roofs
A-FloorsSlabs A_BSUK_Slabs | RL | 10 ,SHE-08.ROOF.dgn,Design Model:105646 | A_BSUK_Roofs | New Construction | A-Roofs::A_BSUK_Roofs
A-FloorsSlabs A_BSUK_Slabs | RL | 10 ,SHE-08.ROOF.dgn,Design Model:105660 | A_BSUK_Roofs | New Construction | A-Roofs::A_BSUK_Roofs
A-FloorsSlabs A_BSUK_Slabs | RL | 10 ,SHE-08.ROOF.dgn,Design Model:105674 | A_BSUK_Roofs | New Construction | A-Roofs::A_BSUK_Roofs
A-FloorsSlabs A_BSUK_Slabs | RL | 10 ,SHE-08.ROOF.dgn,Design Model:105689 | A_BSUK_Roofs | New Construction | A-Roofs::A_BSUK_Roofs
A-FloorsSlabs A_BSUK_Slabs | RL | 10 ,SHE-08.ROOF.dgn,Design Model:105700 | A_BSUK_Roofs | New Construction | A-Roofs::A_BSUK_Roofs
A-FloorsSlabs A_BSUK_Slabs | RL | 10 ,SHE-08.ROOF.dgn,Design Model:105714 | A_BSUK_Roofs | New Construction | A-Roofs::A_BSUK_Roofs
A-FloorsSlabs A_BSUK_Slabs | RL | 10 ,SHE-08.ROOF.dgn,Design Model:105728 | A_BSUK_Roofs | New Construction | A-Roofs::A_BSUK_Roofs
A-FloorsSlabs A_BSUK_Slabs | RL | 10 ,SHE-08.ROOF.dgn,Design Model:105742 | A_BSUK_Roofs | New Construction | A-Roofs::A_BSUK_Roofs
A-FloorsSlabs A_BSUK_Slabs | RL | 10 ,SHE-08.ROOF.dgn,Design Model:105756 | A_BSUK_Roofs | New Construction | A-Roofs::A_BSUK_Roofs
A-FloorsSlabs A_BSUK_Slabs | RL | 10 ,SHE-08.ROOF.dgn,Design Model:105770 | A_BSUK_Roofs | New Construction | A-Roofs::A_BSUK_Roofs
A-FloorsSlabs A_BSUK_Slabs | RL | 10 ,SHE-08.ROOF.dgn,Design Model:105784 | A_BSUK_Roofs | New Construction | A-Roofs::A_BSUK_Roofs
A-FloorsSlabs A_BSUK_Slabs | RL | 10 ,SHE-08.ROOF.dgn,Design Model:105798 | A_BSUK_Roofs | New Construction | A-Roofs::A_BSUK_Roofs
A-FloorsSlabs A_BSUK_Slabs | RL | 10 ,SHE-08.ROOF.dgn,Design Model:105812 | A_BSUK_Roofs | New Construction | A-Roofs::A_BSUK_Roofs
A-FloorsSlabs A_BSUK_Slabs | RL | 10 ,SHE-08.ROOF.dgn,Design Model:105826 | A_BSUK_Roofs | New Construction | A-Roofs::A_BSUK_Roofs
A-FloorsSlabs A_BSUK_Slabs | RL | 10 ,SHE-08.ROOF.dgn,Design Model:105840 | A_BSUK_Roofs | New Construction | A-Roofs::A_BSUK_Roofs
A-FloorsSlabs A_BSUK_Slabs | RL | 10 ,SHE-08.ROOF.dgn,Design Model:105854 | A_BSUK_Roofs | New Construction | A-Roofs::A_BSUK_Roofs
A-FloorsSlabs A_BSUK_Slabs | RL | 10 ,SHE-08.ROOF.dgn,Design Model:105868 | A_BSUK_Roofs | New Construction | A-Roofs::A_BSUK_Roofs
A-FloorsSlabs A_BSUK_Slabs | RL | 10 ,SHE-08.ROOF.dgn,Design Model:105883 | A_BSUK_Roofs | New Construction | A-Roofs::A_BSUK_Roofs
A-FloorsSlabs A_BSUK_Slabs | RL | 10 ,SHE-08.ROOF.dgn,Design Model:105909 | A_BSUK_Roofs | New Construction | A-Roofs::A_BSUK_Roofs
A-FloorsSlabs A_BSUK_Slabs | RL | 10 ,SHE-08.ROOF.dgn,Design Model:105925 | A_BSUK_Roofs | New Construction | A-Roofs::A_BSUK_Roofs
A-FloorsSlabs A_BSUK_Slabs | RL | 10 ,SHE-08.ROOF.dgn,Design Model:105938 | A_BSUK_Roofs | New Construction | A-Roofs::A_BSUK_Roofs
A-FloorsSlabs A_BSUK_Slabs | RL | 10 ,SHE-08.ROOF.dgn,Design Model:105952 | A_BSUK_Roofs | New Construction | A-Roofs::A_BSUK_Roofs
A-FloorsSlabs A_BSUK_Slabs | RL | 10 ,SHE-08.ROOF.dgn,Design Model:105963 | A_BSUK_Roofs | New Construction | A-Roofs::A_BSUK_Roofs
A-FloorsSlabs A_BSUK_Slabs | RL | 10 ,SHE-08.ROOF.dgn,Design Model:105977 | A_BSUK_Roofs | New Construction | A-Roofs::A_BSUK_Roofs
A-FloorsSlabs A_BSUK_Slabs | RL | 10 ,SHE-08.ROOF.dgn,Design Model:105991 | A_BSUK_Roofs | New Construction | A-Roofs::A_BSUK_Roofs
A-FloorsSlabs A_BSUK_Slabs | RL | 10 ,SHE-08.ROOF.dgn,Design Model:106002 | A_BSUK_Roofs | New Construction | A-Roofs::A_BSUK_Roofs
A-FloorsSlabs A_BSUK_Slabs | RL | 10 ,SHE-08.ROOF.dgn,Design Model:106016 | A_BSUK_Roofs | New Construction | A-Roofs::A_BSUK_Roofs
A-FloorsSlabs A_BSUK_Slabs | RL | 10 ,SHE-08.ROOF.dgn,Design Model:106030 | A_BSUK_Roofs | New Construction | A-Roofs::A_BSUK_Roofs
A-FloorsSlabs A_BSUK_Slabs | RL | 10 ,SHE-08.ROOF.dgn,Design Model:106041 | A_BSUK_Roofs | New Construction | A-Roofs::A_BSUK_Roofs
A-FloorsSlabs A_BSUK_Slabs | RL | 10 ,SHE-08.ROOF.dgn,Design Model:106055 | A_BSUK_Roofs | New Construction | A-Roofs::A_BSUK_Roofs
A-FloorsSlabs A_BSUK_Slabs | RL | 10 ,SHE-08.ROOF.dgn,Design Model:106066 | A_BSUK_Roofs | New Construction | A-Roofs::A_BSUK_Roofs
A-FloorsSlabs A_BSUK_Slabs | RL | 10 ,SHE-08.ROOF.dgn,Design Model:106080 | A_BSUK_Roofs | New Construction | A-Roofs::A_BSUK_Roofs
A-FloorsSlabs A_BSUK_Slabs | RL | 10 ,SHE-08.ROOF.dgn,Design Model:106091 | A_BSUK_Roofs | New Construction | A-Roofs::A_BSUK_Roofs
A-FloorsSlabs A_BSUK_Slabs | RL | 10 ,SHE-08.ROOF.dgn,Design Model:106105 | A_BSUK_Roofs | New Construction | A-Roofs::A_BSUK_Roofs
A-FloorsSlabs A_BSUK_Slabs | RL | 10 ,SHE-08.ROOF.dgn,Design Model:106116 | A_BSUK_Roofs | New Construction | A-Roofs::A_BSUK_Roofs
A-FloorsSlabs A_BSUK_Slabs | RL | 10 ,SHE-08.ROOF.dgn,Design Model:106130 | A_BSUK_Roofs | New Construction | A-Roofs::A_BSUK_Roofs
A-FloorsSlabs A_BSUK_Slabs | RL | 10 ,SHE-08.ROOF.dgn,Design Model:106141 | A_BSUK_Roofs | New Construction | A-Roofs::A_BSUK_Roofs
A-FloorsSlabs A_BSUK_Slabs | RL | 10 ,SHE-08.ROOF.dgn,Design Model:106155 | A_BSUK_Roofs | New Construction | A-Roofs::A_BSUK_Roofs
A-FloorsSlabs A_BSUK_Slabs | RL | 10 ,SHE-08.ROOF.dgn,Design Model:106169 | A_BSUK_Roofs | New Construction | A-Roofs::A_BSUK_Roofs
A-FloorsSlabs A_BSUK_Slabs | RL | 10 ,SHE-08.ROOF.dgn,Design Model:106185 | A_BSUK_Roofs | New Construction | A-Roofs::A_BSUK_Roofs
A-FloorsSlabs A_BSUK_Slabs | RL | 10 ,SHE-08.ROOF.dgn,Design Model:106196 | A_BSUK_Roofs | New Construction | A-Roofs::A_BSUK_Roofs
A-FloorsSlabs A_BSUK_Slabs | RL | 10 ,SHE-08.ROOF.dgn,Design Model:106210 | A_BSUK_Roofs | New Construction | A-Roofs::A_BSUK_Roofs
A-FloorsSlabs A_BSUK_Slabs | RL | 10 ,SHE-08.ROOF.dgn,Design Model:106226 | A_BSUK_Roofs | New Construction | A-Roofs::A_BSUK_Roofs
A-FloorsSlabs A_BSUK_Slabs | RL | 10 ,SHE-08.ROOF.dgn,Design Model:106237 | A_BSUK_Roofs | New Construction | A-Roofs::A_BSUK_Roofs
A-FloorsSlabs A_BSUK_Slabs | RL | 10 ,SHE-08.ROOF.dgn,Design Model:106251 | A_BSUK_Roofs | New Construction | A-Roofs::A_BSUK_Roofs
A-FloorsSlabs A_BSUK_Slabs | RL | 10 ,SHE-08.ROOF.dgn,Design Model:106267 | A_BSUK_Roofs | New Construction | A-Roofs::A_BSUK_Roofs
A-FloorsSlabs A_BSUK_Slabs | RL | 10 ,SHE-08.ROOF.dgn,Design Model:106278 | A_BSUK_Roofs | New Construction | A-Roofs::A_BSUK_Roofs
A-FloorsSlabs A_BSUK_Slabs | RL | 10 ,SHE-08.ROOF.dgn,Design Model:106292 | A_BSUK_Roofs | New Construction | A-Roofs::A_BSUK_Roofs
A-FloorsSlabs A_BSUK_Slabs | RL | 10 ,SHE-08.ROOF.dgn,Design Model:106306 | A_BSUK_Roofs | New Construction | A-Roofs::A_BSUK_Roofs
A-FloorsSlabs A_BSUK_Slabs | RL | 10 ,SHE-08.ROOF.dgn,Design Model:106320 | A_BSUK_Roofs | New Construction | A-Roofs::A_BSUK_Roofs
A-FloorsSlabs A_BSUK_Slabs | RL | 10 ,SHE-08.ROOF.dgn,Design Model:106334 | A_BSUK_Roofs | New Construction | A-Roofs::A_BSUK_Roofs
A-FloorsSlabs A_BSUK_Slabs | RL | 10 ,SHE-08.ROOF.dgn,Design Model:106348 | A_BSUK_Roofs | New Construction | A-Roofs::A_BSUK_Roofs
A-FloorsSlabs A_BSUK_Slabs | RL | 10 ,SHE-08.ROOF.dgn,Design Model:106362 | A_BSUK_Roofs | New Construction | A-Roofs::A_BSUK_Roofs
A-FloorsSlabs A_BSUK_Slabs | RL | 10 ,SHE-08.ROOF.dgn,Design Model:106376 | A_BSUK_Roofs | New Construction | A-Roofs::A_BSUK_Roofs
A-FloorsSlabs A_BSUK_Slabs | RL | 10 ,SHE-08.ROOF.dgn,Design Model:106390 | A_BSUK_Roofs | New Construction | A-Roofs::A_BSUK_Roofs
A-FloorsSlabs A_BSUK_Slabs | RL | 10 ,SHE-08.ROOF.dgn,Design Model:106404 | A_BSUK_Roofs | New Construction | A-Roofs::A_BSUK_Roofs
A-FloorsSlabs A_BSUK_Slabs | RL | 10 ,SHE-08.ROOF.dgn,Design Model:106419 | A_BSUK_Roofs | New Construction | A-Roofs::A_BSUK_Roofs
A-FloorsSlabs A_BSUK_Slabs | RL | 10 ,SHE-08.ROOF.dgn,Design Model:106430 | A_BSUK_Roofs | New Construction | A-Roofs::A_BSUK_Roofs
A-FloorsSlabs A_BSUK_Slabs | RL | 10 ,SHE-08.ROOF.dgn,Design Model:106444 | A_BSUK_Roofs | New Construction | A-Roofs::A_BSUK_Roofs
A-FloorsSlabs A_BSUK_Slabs | RL | 10 ,SHE-08.ROOF.dgn,Design Model:106458 | A_BSUK_Roofs | New Construction | A-Roofs::A_BSUK_Roofs
A-FloorsSlabs A_BSUK_Slabs | RL | 10 ,SHE-08.ROOF.dgn,Design Model:106472 | A_BSUK_Roofs | New Construction | A-Roofs::A_BSUK_Roofs
A-FloorsSlabs A_BSUK_Slabs | RL | 10 ,SHE-08.ROOF.dgn,Design Model:106486 | A_BSUK_Roofs | New Construction | A-Roofs::A_BSUK_Roofs
A-FloorsSlabs A_BSUK_Slabs | RL | 10 ,SHE-08.ROOF.dgn,Design Model:106500 | A_BSUK_Roofs | New Construction | A-Roofs::A_BSUK_Roofs
A-FloorsSlabs A_BSUK_Slabs | RL | 10 ,SHE-08.ROOF.dgn,Design Model:106514 | A_BSUK_Roofs | New Construction | A-Roofs::A_BSUK_Roofs
A-FloorsSlabs A_BSUK_Slabs | RL | 10 ,SHE-08.ROOF.dgn,Design Model:106528 | A_BSUK_Roofs | New Construction | A-Roofs::A_BSUK_Roofs
A-FloorsSlabs A_BSUK_Slabs | RL | 10 ,SHE-08.ROOF.dgn,Design Model:106542 | A_BSUK_Roofs | New Construction | A-Roofs::A_BSUK_Roofs
A-FloorsSlabs A_BSUK_Slabs | RL | 10 ,SHE-08.ROOF.dgn,Design Model:106557 | A_BSUK_Roofs | New Construction | A-Roofs::A_BSUK_Roofs
A-FloorsSlabs A_BSUK_Slabs | RL | 10 ,SHE-08.ROOF.dgn,Design Model:106568 | A_BSUK_Roofs | New Construction | A-Roofs::A_BSUK_Roofs
A-FloorsSlabs A_BSUK_Slabs | RL | 10 ,SHE-08.ROOF.dgn,Design Model:106582 | A_BSUK_Roofs | New Construction | A-Roofs::A_BSUK_Roofs
A-FloorsSlabs A_BSUK_Slabs | RL | 10 ,SHE-08.ROOF.dgn,Design Model:106596 | A_BSUK_Roofs | New Construction | A-Roofs::A_BSUK_Roofs
A-FloorsSlabs A_BSUK_Slabs | RL | 10 ,SHE-08.ROOF.dgn,Design Model:106610 | A_BSUK_Roofs | New Construction | A-Roofs::A_BSUK_Roofs
A-FloorsSlabs A_BSUK_Slabs | RL | 10 ,SHE-08.ROOF.dgn,Design Model:106624 | A_BSUK_Roofs | New Construction | A-Roofs::A_BSUK_Roofs
A-FloorsSlabs A_BSUK_Slabs | RL | 10 ,SHE-08.ROOF.dgn,Design Model:106638 | A_BSUK_Roofs | New Construction | A-Roofs::A_BSUK_Roofs
A-FloorsSlabs A_BSUK_Slabs | RL | 10 ,SHE-08.ROOF.dgn,Design Model:106652 | A_BSUK_Roofs | New Construction | A-Roofs::A_BSUK_Roofs
A-FloorsSlabs A_BSUK_Slabs | RL | 10 ,SHE-08.ROOF.dgn,Design Model:106666 | A_BSUK_Roofs | New Construction | A-Roofs::A_BSUK_Roofs
A-FloorsSlabs A_BSUK_Slabs | RL | 10 ,SHE-08.ROOF.dgn,Design Model:106680 | A_BSUK_Roofs | New Construction | A-Roofs::A_BSUK_Roofs
A-FloorsSlabs A_BSUK_Slabs | RL | 10 ,SHE-08.ROOF.dgn,Design Model:106695 | A_BSUK_Roofs | New Construction | A-Roofs::A_BSUK_Roofs
A-FloorsSlabs A_BSUK_Slabs | RL | 10 ,SHE-08.ROOF.dgn,Design Model:106706 | A_BSUK_Roofs | New Construction | A-Roofs::A_BSUK_Roofs
A-FloorsSlabs A_BSUK_Slabs | RL | 10 ,SHE-08.ROOF.dgn,Design Model:106720 | A_BSUK_Roofs | New Construction | A-Roofs::A_BSUK_Roofs
A-FloorsSlabs A_BSUK_Slabs | RL | 10 ,SHE-08.ROOF.dgn,Design Model:106734 | A_BSUK_Roofs | New Construction | A-Roofs::A_BSUK_Roofs
A-FloorsSlabs A_BSUK_Slabs | RL | 10 ,SHE-08.ROOF.dgn,Design Model:106748 | A_BSUK_Roofs | New Construction | A-Roofs::A_BSUK_Roofs
A-FloorsSlabs A_BSUK_Slabs | RL | 10 ,SHE-08.ROOF.dgn,Design Model:106762 | A_BSUK_Roofs | New Construction | A-Roofs::A_BSUK_Roofs
A-FloorsSlabs A_BSUK_Slabs | RL | 10 ,SHE-08.ROOF.dgn,Design Model:106776 | A_BSUK_Roofs | New Construction | A-Roofs::A_BSUK_Roofs
A-FloorsSlabs A_BSUK_Slabs | RL | 10 ,SHE-08.ROOF.dgn,Design Model:106791 | A_BSUK_Roofs | New Construction | A-Roofs::A_BSUK_Roofs
A-FloorsSlabs A_BSUK_Slabs | RL | 10 ,SHE-08.ROOF.dgn,Design Model:106805 | A_BSUK_Roofs | New Construction | A-Roofs::A_BSUK_Roofs
A-FloorsSlabs A_BSUK_Slabs | RL | 10 ,SHE-08.ROOF.dgn,Design Model:106821 | A_BSUK_Roofs | New Construction | A-Roofs::A_BSUK_Roofs
A-FloorsSlabs A_BSUK_Slabs | RL | 10 ,SHE-08.ROOF.dgn,Design Model:106832 | A_BSUK_Roofs | New Construction | A-Roofs::A_BSUK_Roofs
A-FloorsSlabs A_BSUK_Slabs | RL | 10 ,SHE-08.ROOF.dgn,Design Model:106846 | A_BSUK_Roofs | New Construction | A-Roofs::A_BSUK_Roofs
A-FloorsSlabs A_BSUK_Slabs | RL | 10 ,SHE-08.ROOF.dgn,Design Model:106857 | A_BSUK_Roofs | New Construction | A-Roofs::A_BSUK_Roofs
A-FloorsSlabs A_BSUK_Slabs | RL | 10 ,SHE-08.ROOF.dgn,Design Model:106871 | A_BSUK_Roofs | New Construction | A-Roofs::A_BSUK_Roofs
A-FloorsSlabs A_BSUK_Slabs | RL | 10 ,SHE-08.ROOF.dgn,Design Model:106885 | A_BSUK_Roofs | New Construction | A-Roofs::A_BSUK_Roofs
A-FloorsSlabs A_BSUK_Slabs | RL | 10 ,SHE-08.ROOF.dgn,Design Model:106896 | A_BSUK_Roofs | New Construction | A-Roofs::A_BSUK_Roofs
A-FloorsSlabs A_BSUK_Slabs | RL | 10 ,SHE-08.ROOF.dgn,Design Model:106910 | A_BSUK_Roofs | New Construction | A-Roofs::A_BSUK_Roofs
A-FloorsSlabs A_BSUK_Slabs | RL | 10 ,SHE-08.ROOF.dgn,Design Model:106924 | A_BSUK_Roofs | New Construction | A-Roofs::A_BSUK_Roofs
A-FloorsSlabs A_BSUK_Slabs | RL | 10 ,SHE-08.ROOF.dgn,Design Model:106935 | A_BSUK_Roofs | New Construction | A-Roofs::A_BSUK_Roofs
A-FloorsSlabs A_BSUK_Slabs | RL | 10 ,SHE-08.ROOF.dgn,Design Model:106949 | A_BSUK_Roofs | New Construction | A-Roofs::A_BSUK_Roofs
A-FloorsSlabs A_BSUK_Slabs | RL | 10 ,SHE-08.ROOF.dgn,Design Model:106963 | A_BSUK_Roofs | New Construction | A-Roofs::A_BSUK_Roofs
A-FloorsSlabs A_BSUK_Slabs | RL | 10 ,SHE-08.ROOF.dgn,Design Model:106977 | A_BSUK_Roofs | New Construction | A-Roofs::A_BSUK_Roofs
A-FloorsSlabs A_BSUK_Slabs | RL | 10 ,SHE-08.ROOF.dgn,Design Model:106988 | A_BSUK_Roofs | New Construction | A-Roofs::A_BSUK_Roofs
A-FloorsSlabs A_BSUK_Slabs | RL | 10 ,SHE-08.ROOF.dgn,Design Model:106999 | A_BSUK_Roofs | New Construction | A-Roofs::A_BSUK_Roofs
A-FloorsSlabs A_BSUK_Slabs | RL | 10 ,SHE-08.ROOF.dgn,Design Model:107013 | A_BSUK_Roofs | New Construction | A-Roofs::A_BSUK_Roofs
A-FloorsSlabs A_BSUK_Slabs | RL | 10 ,SHE-08.ROOF.dgn,Design Model:107027 | A_BSUK_Roofs | New Construction | A-Roofs::A_BSUK_Roofs
A-FloorsSlabs A_BSUK_Slabs | RL | 10 ,SHE-08.ROOF.dgn,Design Model:107041 | A_BSUK_Roofs | New Construction | A-Roofs::A_BSUK_Roofs
A-FloorsSlabs A_BSUK_Slabs | RL | 10 ,SHE-08.ROOF.dgn,Design Model:107052 | A_BSUK_Roofs | New Construction | A-Roofs::A_BSUK_Roofs
A-FloorsSlabs A_BSUK_Slabs | RL | 10 ,SHE-08.ROOF.dgn,Design Model:107063 | A_BSUK_Roofs | New Construction | A-Roofs::A_BSUK_Roofs
A-FloorsSlabs A_BSUK_Slabs | RL | 10 ,SHE-08.ROOF.dgn,Design Model:107077 | A_BSUK_Roofs | New Construction | A-Roofs::A_BSUK_Roofs
A-FloorsSlabs A_BSUK_Slabs | RL | 10 ,SHE-08.ROOF.dgn,Design Model:107091 | A_BSUK_Roofs | New Construction | A-Roofs::A_BSUK_Roofs
A-FloorsSlabs A_BSUK_Slabs | RL | 10 ,SHE-08.ROOF.dgn,Design Model:107102 | A_BSUK_Roofs | New Construction | A-Roofs::A_BSUK_Roofs
A-FloorsSlabs A_BSUK_Slabs | RL | 10 ,SHE-08.ROOF.dgn,Design Model:107116 | A_BSUK_Roofs | New Construction | A-Roofs::A_BSUK_Roofs
A-FloorsSlabs A_BSUK_Slabs | RL | 10 ,SHE-08.ROOF.dgn,Design Model:107127 | A_BSUK_Roofs | New Construction | A-Roofs::A_BSUK_Roofs
A-FloorsSlabs A_BSUK_Slabs | RL | 10 ,SHE-08.ROOF.dgn,Design Model:107141 | A_BSUK_Roofs | New Construction | A-Roofs::A_BSUK_Roofs
A-FloorsSlabs A_BSUK_Slabs | RL | 10 ,SHE-08.ROOF.dgn,Design Model:107155 | A_BSUK_Roofs | New Construction | A-Roofs::A_BSUK_Roofs
A-FloorsSlabs A_BSUK_Slabs | RL | 10 ,SHE-08.ROOF.dgn,Design Model:107166 | A_BSUK_Roofs | New Construction | A-Roofs::A_BSUK_Roofs
A-FloorsSlabs A_BSUK_Slabs | RL | 10 ,SHE-08.ROOF.dgn,Design Model:107180 | A_BSUK_Roofs | New Construction | A-Roofs::A_BSUK_Roofs
A-FloorsSlabs A_BSUK_Slabs | RL | 10 ,SHE-08.ROOF.dgn,Design Model:107191 | A_BSUK_Roofs | New Construction | A-Roofs::A_BSUK_Roofs
A-FloorsSlabs A_BSUK_Slabs | RL | 10 ,SHE-08.ROOF.dgn,Design Model:107205 | A_BSUK_Roofs | New Construction | A-Roofs::A_BSUK_Roofs
A-FloorsSlabs A_BSUK_Slabs | RL | 10 ,SHE-08.ROOF.dgn,Design Model:107219 | A_BSUK_Roofs | New Construction | A-Roofs::A_BSUK_Roofs
A-FloorsSlabs A_BSUK_Slabs | RL | 10 ,SHE-08.ROOF.dgn,Design Model:107233 | A_BSUK_Roofs | New Construction | A-Roofs::A_BSUK_Roofs
A-FloorsSlabs A_BSUK_Slabs | RL | 10 ,SHE-08.ROOF.dgn,Design Model:107248 | A_BSUK_Roofs | New Construction | A-Roofs::A_BSUK_Roofs
A-FloorsSlabs A_BSUK_Slabs | RL | 10 ,SHE-08.ROOF.dgn,Design Model:107259 | A_BSUK_Roofs | New Construction | A-Roofs::A_BSUK_Roofs
A-FloorsSlabs A_BSUK_Slabs | RL | 10 ,SHE-08.ROOF.dgn,Design Model:107273 | A_BSUK_Roofs | New Construction | A-Roofs::A_BSUK_Roofs
A-FloorsSlabs A_BSUK_Slabs | RL | 10 ,SHE-08.ROOF.dgn,Design Model:107287 | A_BSUK_Roofs | New Construction | A-Roofs::A_BSUK_Roofs
A-FloorsSlabs A_BSUK_Slabs | RL | 10 ,SHE-08.ROOF.dgn,Design Model:107301 | A_BSUK_Roofs | New Construction | A-Roofs::A_BSUK_Roofs
A-FloorsSlabs A_BSUK_Slabs | RL | 10 ,SHE-08.ROOF.dgn,Design Model:107315 | A_BSUK_Roofs | New Construction | A-Roofs::A_BSUK_Roofs
A-FloorsSlabs A_BSUK_Slabs | RL | 10 ,SHE-08.ROOF.dgn,Design Model:107329 | A_BSUK_Roofs | New Construction | A-Roofs::A_BSUK_Roofs
A-FloorsSlabs A_BSUK_Slabs | RL | 10 ,SHE-08.ROOF.dgn,Design Model:107343 | A_BSUK_Roofs | New Construction | A-Roofs::A_BSUK_Roofs
A-FloorsSlabs A_BSUK_Slabs | RL | 10 ,SHE-08.ROOF.dgn,Design Model:107357 | A_BSUK_Roofs | New Construction | A-Roofs::A_BSUK_Roofs
A-FloorsSlabs A_BSUK_Slabs | RL | 10 ,SHE-08.ROOF.dgn,Design Model:107371 | A_BSUK_Roofs | New Construction | A-Roofs::A_BSUK_Roofs
A-FloorsSlabs A_BSUK_Slabs | RL | 10 ,SHE-08.ROOF.dgn,Design Model:107386 | A_BSUK_Roofs | New Construction | A-Roofs::A_BSUK_Roofs
A-FloorsSlabs A_BSUK_Slabs | RL | 10 ,SHE-08.ROOF.dgn,Design Model:107397 | A_BSUK_Roofs | New Construction | A-Roofs::A_BSUK_Roofs
A-FloorsSlabs A_BSUK_Slabs | RL | 10 ,SHE-08.ROOF.dgn,Design Model:107411 | A_BSUK_Roofs | New Construction | A-Roofs::A_BSUK_Roofs
A-FloorsSlabs A_BSUK_Slabs | RL | 10 ,SHE-08.ROOF.dgn,Design Model:107425 | A_BSUK_Roofs | New Construction | A-Roofs::A_BSUK_Roofs
A-FloorsSlabs A_BSUK_Slabs | RL | 10 ,SHE-08.ROOF.dgn,Design Model:107439 | A_BSUK_Roofs | New Construction | A-Roofs::A_BSUK_Roofs
A-FloorsSlabs A_BSUK_Slabs | RL | 10 ,SHE-08.ROOF.dgn,Design Model:107453 | A_BSUK_Roofs | New Construction | A-Roofs::A_BSUK_Roofs
A-FloorsSlabs A_BSUK_Slabs | RL | 10 ,SHE-08.ROOF.dgn,Design Model:107467 | A_BSUK_Roofs | New Construction | A-Roofs::A_BSUK_Roofs
A-FloorsSlabs A_BSUK_Slabs | RL | 10 ,SHE-08.ROOF.dgn,Design Model:107481 | A_BSUK_Roofs | New Construction | A-Roofs::A_BSUK_Roofs
A-FloorsSlabs A_BSUK_Slabs | RL | 10 ,SHE-08.ROOF.dgn,Design Model:107495 | A_BSUK_Roofs | New Construction | A-Roofs::A_BSUK_Roofs
A-FloorsSlabs A_BSUK_Slabs | RL | 10 ,SHE-08.ROOF.dgn,Design Model:107509 | A_BSUK_Roofs | New Construction | A-Roofs::A_BSUK_Roofs
A-FloorsSlabs A_BSUK_Slabs | RL | 10 ,SHE-08.ROOF.dgn,Design Model:107524 | A_BSUK_Roofs | New Construction | A-Roofs::A_BSUK_Roofs
A-FloorsSlabs A_BSUK_Slabs | RL | 10 ,SHE-08.ROOF.dgn,Design Model:107535 | A_BSUK_Roofs | New Construction | A-Roofs::A_BSUK_Roofs
A-FloorsSlabs A_BSUK_Slabs | RL | 10 ,SHE-08.ROOF.dgn,Design Model:107549 | A_BSUK_Roofs | New Construction | A-Roofs::A_BSUK_Roofs
A-FloorsSlabs A_BSUK_Slabs | RL | 10 ,SHE-08.ROOF.dgn,Design Model:107563 | A_BSUK_Roofs | New Construction | A-Roofs::A_BSUK_Roofs
A-FloorsSlabs A_BSUK_Slabs | RL | 10 ,SHE-08.ROOF.dgn,Design Model:107577 | A_BSUK_Roofs | New Construction | A-Roofs::A_BSUK_Roofs
A-FloorsSlabs A_BSUK_Slabs | RL | 10 ,SHE-08.ROOF.dgn,Design Model:107591 | A_BSUK_Roofs | New Construction | A-Roofs::A_BSUK_Roofs
A-FloorsSlabs A_BSUK_Slabs | RL | 10 ,SHE-08.ROOF.dgn,Design Model:107605 | A_BSUK_Roofs | New Construction | A-Roofs::A_BSUK_Roofs
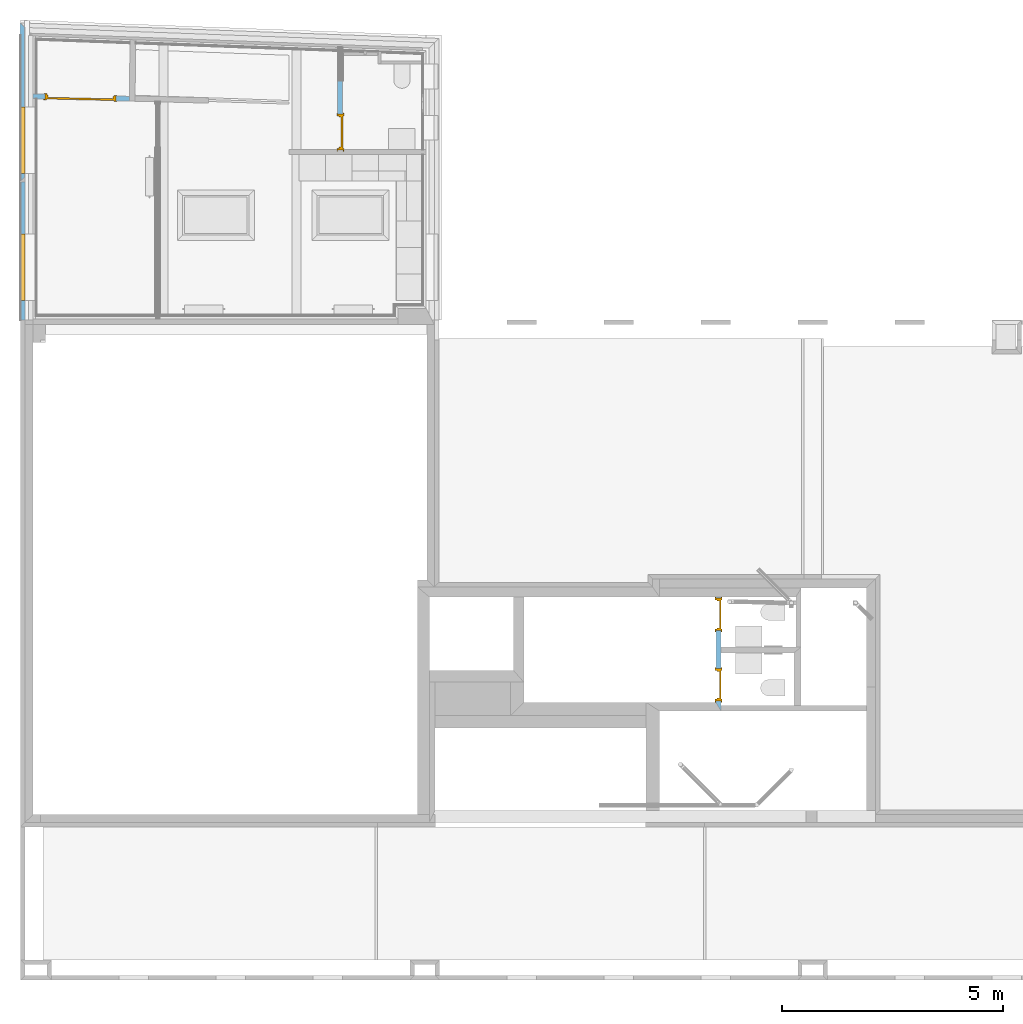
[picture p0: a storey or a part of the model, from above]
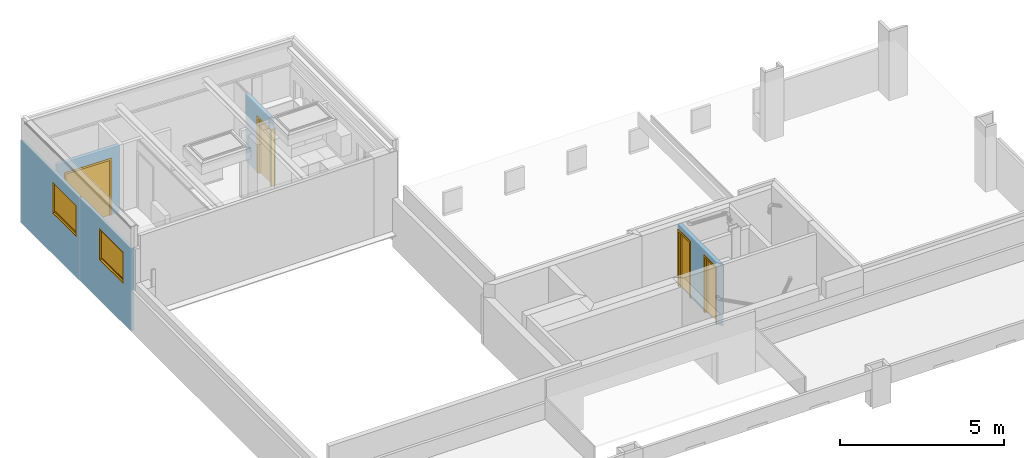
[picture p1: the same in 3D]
Properties of the parts of a building model (IFC2X3), part 12 of 17

# IfcSlab: A-FloorsSlabs A_BSUK_Slabs (1519)
Name | In | Description | Material | Phase | Part Definition
A-FloorsSlabs A_BSUK_Slabs | RL | 10 ,SHE-08.ROOF.dgn,Design Model:107620 | A_BSUK_Roofs | New Construction | A-Roofs::A_BSUK_Roofs
A-FloorsSlabs A_BSUK_Slabs | RL | 10 ,SHE-08.ROOF.dgn,Design Model:107634 | A_BSUK_Roofs | New Construction | A-Roofs::A_BSUK_Roofs
A-FloorsSlabs A_BSUK_Slabs | RL | 10 ,SHE-08.ROOF.dgn,Design Model:107650 | A_BSUK_Roofs | New Construction | A-Roofs::A_BSUK_Roofs
A-FloorsSlabs A_BSUK_Slabs | RL | 10 ,SHE-08.ROOF.dgn,Design Model:107661 | A_BSUK_Roofs | New Construction | A-Roofs::A_BSUK_Roofs
A-FloorsSlabs A_BSUK_Slabs | RL | 10 ,SHE-08.ROOF.dgn,Design Model:107675 | A_BSUK_Roofs | New Construction | A-Roofs::A_BSUK_Roofs
A-FloorsSlabs A_BSUK_Slabs | RL | 10 ,SHE-08.ROOF.dgn,Design Model:107686 | A_BSUK_Roofs | New Construction | A-Roofs::A_BSUK_Roofs
A-FloorsSlabs A_BSUK_Slabs | RL | 10 ,SHE-08.ROOF.dgn,Design Model:107700 | A_BSUK_Roofs | New Construction | A-Roofs::A_BSUK_Roofs
A-FloorsSlabs A_BSUK_Slabs | RL | 10 ,SHE-08.ROOF.dgn,Design Model:107715 | A_BSUK_Roofs | New Construction | A-Roofs::A_BSUK_Roofs
A-FloorsSlabs A_BSUK_Slabs | RL | 10 ,SHE-08.ROOF.dgn,Design Model:107726 | A_BSUK_Roofs | New Construction | A-Roofs::A_BSUK_Roofs
A-FloorsSlabs A_BSUK_Slabs | RL | 10 ,SHE-08.ROOF.dgn,Design Model:107740 | A_BSUK_Roofs | New Construction | A-Roofs::A_BSUK_Roofs
A-FloorsSlabs A_BSUK_Slabs | RL | 10 ,SHE-08.ROOF.dgn,Design Model:107754 | A_BSUK_Roofs | New Construction | A-Roofs::A_BSUK_Roofs
A-FloorsSlabs A_BSUK_Slabs | RL | 10 ,SHE-08.ROOF.dgn,Design Model:107768 | A_BSUK_Roofs | New Construction | A-Roofs::A_BSUK_Roofs
A-FloorsSlabs A_BSUK_Slabs | RL | 10 ,SHE-08.ROOF.dgn,Design Model:107782 | A_BSUK_Roofs | New Construction | A-Roofs::A_BSUK_Roofs
A-FloorsSlabs A_BSUK_Slabs | RL | 10 ,SHE-08.ROOF.dgn,Design Model:107796 | A_BSUK_Roofs | New Construction | A-Roofs::A_BSUK_Roofs
A-FloorsSlabs A_BSUK_Slabs | RL | 10 ,SHE-08.ROOF.dgn,Design Model:107810 | A_BSUK_Roofs | New Construction | A-Roofs::A_BSUK_Roofs
A-FloorsSlabs A_BSUK_Slabs | RL | 10 ,SHE-08.ROOF.dgn,Design Model:107824 | A_BSUK_Roofs | New Construction | A-Roofs::A_BSUK_Roofs
A-FloorsSlabs A_BSUK_Slabs | RL | 10 ,SHE-08.ROOF.dgn,Design Model:107838 | A_BSUK_Roofs | New Construction | A-Roofs::A_BSUK_Roofs
A-FloorsSlabs A_BSUK_Slabs | RL | 10 ,SHE-08.ROOF.dgn,Design Model:107853 | A_BSUK_Roofs | New Construction | A-Roofs::A_BSUK_Roofs
A-FloorsSlabs A_BSUK_Slabs | RL | 10 ,SHE-08.ROOF.dgn,Design Model:107864 | A_BSUK_Roofs | New Construction | A-Roofs::A_BSUK_Roofs
A-FloorsSlabs A_BSUK_Slabs | RL | 10 ,SHE-08.ROOF.dgn,Design Model:107878 | A_BSUK_Roofs | New Construction | A-Roofs::A_BSUK_Roofs
A-FloorsSlabs A_BSUK_Slabs | RL | 10 ,SHE-08.ROOF.dgn,Design Model:107892 | A_BSUK_Roofs | New Construction | A-Roofs::A_BSUK_Roofs
A-FloorsSlabs A_BSUK_Slabs | RL | 10 ,SHE-08.ROOF.dgn,Design Model:107906 | A_BSUK_Roofs | New Construction | A-Roofs::A_BSUK_Roofs
A-FloorsSlabs A_BSUK_Slabs | RL | 10 ,SHE-08.ROOF.dgn,Design Model:107920 | A_BSUK_Roofs | New Construction | A-Roofs::A_BSUK_Roofs
A-FloorsSlabs A_BSUK_Slabs | RL | 10 ,SHE-08.ROOF.dgn,Design Model:107934 | A_BSUK_Roofs | New Construction | A-Roofs::A_BSUK_Roofs
A-FloorsSlabs A_BSUK_Slabs | RL | 10 ,SHE-08.ROOF.dgn,Design Model:107948 | A_BSUK_Roofs | New Construction | A-Roofs::A_BSUK_Roofs
A-FloorsSlabs A_BSUK_Slabs | RL | 10 ,SHE-08.ROOF.dgn,Design Model:107962 | A_BSUK_Roofs | New Construction | A-Roofs::A_BSUK_Roofs
A-FloorsSlabs A_BSUK_Slabs | RL | 10 ,SHE-08.ROOF.dgn,Design Model:107976 | A_BSUK_Roofs | New Construction | A-Roofs::A_BSUK_Roofs
A-FloorsSlabs A_BSUK_Slabs | RL | 10 ,SHE-08.ROOF.dgn,Design Model:107991 | A_BSUK_Roofs | New Construction | A-Roofs::A_BSUK_Roofs
A-FloorsSlabs A_BSUK_Slabs | RL | 10 ,SHE-08.ROOF.dgn,Design Model:108002 | A_BSUK_Roofs | New Construction | A-Roofs::A_BSUK_Roofs
A-FloorsSlabs A_BSUK_Slabs | RL | 10 ,SHE-08.ROOF.dgn,Design Model:108016 | A_BSUK_Roofs | New Construction | A-Roofs::A_BSUK_Roofs
A-FloorsSlabs A_BSUK_Slabs | RL | 10 ,SHE-08.ROOF.dgn,Design Model:108030 | A_BSUK_Roofs | New Construction | A-Roofs::A_BSUK_Roofs
A-FloorsSlabs A_BSUK_Slabs | RL | 10 ,SHE-08.ROOF.dgn,Design Model:108044 | A_BSUK_Roofs | New Construction | A-Roofs::A_BSUK_Roofs
A-FloorsSlabs A_BSUK_Slabs | RL | 10 ,SHE-08.ROOF.dgn,Design Model:108058 | A_BSUK_Roofs | New Construction | A-Roofs::A_BSUK_Roofs
A-FloorsSlabs A_BSUK_Slabs | RL | 10 ,SHE-08.ROOF.dgn,Design Model:108072 | A_BSUK_Roofs | New Construction | A-Roofs::A_BSUK_Roofs
A-FloorsSlabs A_BSUK_Slabs | RL | 10 ,SHE-08.ROOF.dgn,Design Model:108086 | A_BSUK_Roofs | New Construction | A-Roofs::A_BSUK_Roofs
A-FloorsSlabs A_BSUK_Slabs | RL | 10 ,SHE-08.ROOF.dgn,Design Model:108100 | A_BSUK_Roofs | New Construction | A-Roofs::A_BSUK_Roofs
A-FloorsSlabs A_BSUK_Slabs | RL | 10 ,SHE-08.ROOF.dgn,Design Model:108114 | A_BSUK_Roofs | New Construction | A-Roofs::A_BSUK_Roofs
A-FloorsSlabs A_BSUK_Slabs | RL | 10 ,SHE-08.ROOF.dgn,Design Model:108129 | A_BSUK_Roofs | New Construction | A-Roofs::A_BSUK_Roofs
A-FloorsSlabs A_BSUK_Slabs | RL | 10 ,SHE-08.ROOF.dgn,Design Model:108140 | A_BSUK_Roofs | New Construction | A-Roofs::A_BSUK_Roofs
A-FloorsSlabs A_BSUK_Slabs | RL | 10 ,SHE-08.ROOF.dgn,Design Model:108154 | A_BSUK_Roofs | New Construction | A-Roofs::A_BSUK_Roofs
A-FloorsSlabs A_BSUK_Slabs | RL | 10 ,SHE-08.ROOF.dgn,Design Model:108168 | A_BSUK_Roofs | New Construction | A-Roofs::A_BSUK_Roofs
A-FloorsSlabs A_BSUK_Slabs | RL | 10 ,SHE-08.ROOF.dgn,Design Model:108182 | A_BSUK_Roofs | New Construction | A-Roofs::A_BSUK_Roofs
A-FloorsSlabs A_BSUK_Slabs | RL | 10 ,SHE-08.ROOF.dgn,Design Model:108196 | A_BSUK_Roofs | New Construction | A-Roofs::A_BSUK_Roofs
A-FloorsSlabs A_BSUK_Slabs | RL | 10 ,SHE-08.ROOF.dgn,Design Model:108210 | A_BSUK_Roofs | New Construction | A-Roofs::A_BSUK_Roofs
A-FloorsSlabs A_BSUK_Slabs | RL | 10 ,SHE-08.ROOF.dgn,Design Model:108225 | A_BSUK_Roofs | New Construction | A-Roofs::A_BSUK_Roofs
A-FloorsSlabs A_BSUK_Slabs | RL | 10 ,SHE-08.ROOF.dgn,Design Model:108239 | A_BSUK_Roofs | New Construction | A-Roofs::A_BSUK_Roofs
A-FloorsSlabs A_BSUK_Slabs | RL | 10 ,SHE-08.ROOF.dgn,Design Model:108255 | A_BSUK_Roofs | New Construction | A-Roofs::A_BSUK_Roofs
A-FloorsSlabs A_BSUK_Slabs | RL | 10 ,SHE-08.ROOF.dgn,Design Model:108266 | A_BSUK_Roofs | New Construction | A-Roofs::A_BSUK_Roofs
A-FloorsSlabs A_BSUK_Slabs | RL | 10 ,SHE-08.ROOF.dgn,Design Model:108280 | A_BSUK_Roofs | New Construction | A-Roofs::A_BSUK_Roofs
A-FloorsSlabs A_BSUK_Slabs | RL | 10 ,SHE-08.ROOF.dgn,Design Model:108291 | A_BSUK_Roofs | New Construction | A-Roofs::A_BSUK_Roofs
A-FloorsSlabs A_BSUK_Slabs | RL | 10 ,SHE-08.ROOF.dgn,Design Model:108305 | A_BSUK_Roofs | New Construction | A-Roofs::A_BSUK_Roofs
A-FloorsSlabs A_BSUK_Slabs | RL | 10 ,SHE-08.ROOF.dgn,Design Model:108319 | A_BSUK_Roofs | New Construction | A-Roofs::A_BSUK_Roofs
A-FloorsSlabs A_BSUK_Slabs | RL | 10 ,SHE-08.ROOF.dgn,Design Model:108330 | A_BSUK_Roofs | New Construction | A-Roofs::A_BSUK_Roofs
A-FloorsSlabs A_BSUK_Slabs | RL | 10 ,SHE-08.ROOF.dgn,Design Model:108344 | A_BSUK_Roofs | New Construction | A-Roofs::A_BSUK_Roofs
A-FloorsSlabs A_BSUK_Slabs | RL | 10 ,SHE-08.ROOF.dgn,Design Model:108358 | A_BSUK_Roofs | New Construction | A-Roofs::A_BSUK_Roofs
A-FloorsSlabs A_BSUK_Slabs | RL | 10 ,SHE-08.ROOF.dgn,Design Model:108369 | A_BSUK_Roofs | New Construction | A-Roofs::A_BSUK_Roofs
A-FloorsSlabs A_BSUK_Slabs | RL | 10 ,SHE-08.ROOF.dgn,Design Model:108383 | A_BSUK_Roofs | New Construction | A-Roofs::A_BSUK_Roofs
A-FloorsSlabs A_BSUK_Slabs | RL | 10 ,SHE-08.ROOF.dgn,Design Model:108397 | A_BSUK_Roofs | New Construction | A-Roofs::A_BSUK_Roofs
A-FloorsSlabs A_BSUK_Slabs | RL | 10 ,SHE-08.ROOF.dgn,Design Model:108411 | A_BSUK_Roofs | New Construction | A-Roofs::A_BSUK_Roofs
A-FloorsSlabs A_BSUK_Slabs | RL | 10 ,SHE-08.ROOF.dgn,Design Model:108422 | A_BSUK_Roofs | New Construction | A-Roofs::A_BSUK_Roofs
A-FloorsSlabs A_BSUK_Slabs | RL | 10 ,SHE-08.ROOF.dgn,Design Model:108433 | A_BSUK_Roofs | New Construction | A-Roofs::A_BSUK_Roofs
A-FloorsSlabs A_BSUK_Slabs | RL | 10 ,SHE-08.ROOF.dgn,Design Model:108447 | A_BSUK_Roofs | New Construction | A-Roofs::A_BSUK_Roofs
A-FloorsSlabs A_BSUK_Slabs | RL | 10 ,SHE-08.ROOF.dgn,Design Model:108461 | A_BSUK_Roofs | New Construction | A-Roofs::A_BSUK_Roofs
A-FloorsSlabs A_BSUK_Slabs | RL | 10 ,SHE-08.ROOF.dgn,Design Model:108475 | A_BSUK_Roofs | New Construction | A-Roofs::A_BSUK_Roofs
A-FloorsSlabs A_BSUK_Slabs | RL | 10 ,SHE-08.ROOF.dgn,Design Model:108486 | A_BSUK_Roofs | New Construction | A-Roofs::A_BSUK_Roofs
A-FloorsSlabs A_BSUK_Slabs | RL | 10 ,SHE-08.ROOF.dgn,Design Model:108497 | A_BSUK_Roofs | New Construction | A-Roofs::A_BSUK_Roofs
A-FloorsSlabs A_BSUK_Slabs | RL | 10 ,SHE-08.ROOF.dgn,Design Model:108511 | A_BSUK_Roofs | New Construction | A-Roofs::A_BSUK_Roofs
A-FloorsSlabs A_BSUK_Slabs | RL | 10 ,SHE-08.ROOF.dgn,Design Model:108525 | A_BSUK_Roofs | New Construction | A-Roofs::A_BSUK_Roofs
A-FloorsSlabs A_BSUK_Slabs | RL | 10 ,SHE-08.ROOF.dgn,Design Model:108536 | A_BSUK_Roofs | New Construction | A-Roofs::A_BSUK_Roofs
A-FloorsSlabs A_BSUK_Slabs | RL | 10 ,SHE-08.ROOF.dgn,Design Model:108550 | A_BSUK_Roofs | New Construction | A-Roofs::A_BSUK_Roofs
A-FloorsSlabs A_BSUK_Slabs | RL | 10 ,SHE-08.ROOF.dgn,Design Model:108561 | A_BSUK_Roofs | New Construction | A-Roofs::A_BSUK_Roofs
A-FloorsSlabs A_BSUK_Slabs | RL | 10 ,SHE-08.ROOF.dgn,Design Model:108575 | A_BSUK_Roofs | New Construction | A-Roofs::A_BSUK_Roofs
A-FloorsSlabs A_BSUK_Slabs | RL | 10 ,SHE-08.ROOF.dgn,Design Model:108589 | A_BSUK_Roofs | New Construction | A-Roofs::A_BSUK_Roofs
A-FloorsSlabs A_BSUK_Slabs | RL | 10 ,SHE-08.ROOF.dgn,Design Model:108600 | A_BSUK_Roofs | New Construction | A-Roofs::A_BSUK_Roofs
A-FloorsSlabs A_BSUK_Slabs | RL | 10 ,SHE-08.ROOF.dgn,Design Model:108614 | A_BSUK_Roofs | New Construction | A-Roofs::A_BSUK_Roofs
A-FloorsSlabs A_BSUK_Slabs | RL | 10 ,SHE-08.ROOF.dgn,Design Model:108628 | A_BSUK_Roofs | New Construction | A-Roofs::A_BSUK_Roofs
A-FloorsSlabs A_BSUK_Slabs | RL | 10 ,SHE-08.ROOF.dgn,Design Model:108642 | A_BSUK_Roofs | New Construction | A-Roofs::A_BSUK_Roofs
A-FloorsSlabs A_BSUK_Slabs | RL | 10 ,SHE-08.ROOF.dgn,Design Model:108656 | A_BSUK_Roofs | New Construction | A-Roofs::A_BSUK_Roofs
A-FloorsSlabs A_BSUK_Slabs | RL | 10 ,SHE-08.ROOF.dgn,Design Model:108670 | A_BSUK_Roofs | New Construction | A-Roofs::A_BSUK_Roofs
A-FloorsSlabs A_BSUK_Slabs | RL | 10 ,SHE-08.ROOF.dgn,Design Model:108684 | A_BSUK_Roofs | New Construction | A-Roofs::A_BSUK_Roofs
A-FloorsSlabs A_BSUK_Slabs | RL | 10 ,SHE-08.ROOF.dgn,Design Model:108698 | A_BSUK_Roofs | New Construction | A-Roofs::A_BSUK_Roofs
A-FloorsSlabs A_BSUK_Slabs | RL | 10 ,SHE-08.ROOF.dgn,Design Model:108712 | A_BSUK_Roofs | New Construction | A-Roofs::A_BSUK_Roofs
A-FloorsSlabs A_BSUK_Slabs | RL | 10 ,SHE-08.ROOF.dgn,Design Model:108723 | A_BSUK_Roofs | New Construction | A-Roofs::A_BSUK_Roofs
A-FloorsSlabs A_BSUK_Slabs | RL | 10 ,SHE-08.ROOF.dgn,Design Model:108737 | A_BSUK_Roofs | New Construction | A-Roofs::A_BSUK_Roofs
A-FloorsSlabs A_BSUK_Slabs | RL | 10 ,SHE-08.ROOF.dgn,Design Model:108751 | A_BSUK_Roofs | New Construction | A-Roofs::A_BSUK_Roofs
A-FloorsSlabs A_BSUK_Slabs | RL | 10 ,SHE-08.ROOF.dgn,Design Model:108762 | A_BSUK_Roofs | New Construction | A-Roofs::A_BSUK_Roofs
A-FloorsSlabs A_BSUK_Slabs | RL | 10 ,SHE-08.ROOF.dgn,Design Model:108776 | A_BSUK_Roofs | New Construction | A-Roofs::A_BSUK_Roofs
A-FloorsSlabs A_BSUK_Slabs | RL | 10 ,SHE-08.ROOF.dgn,Design Model:108790 | A_BSUK_Roofs | New Construction | A-Roofs::A_BSUK_Roofs
A-FloorsSlabs A_BSUK_Slabs | RL | 10 ,SHE-08.ROOF.dgn,Design Model:108804 | A_BSUK_Roofs | New Construction | A-Roofs::A_BSUK_Roofs
A-FloorsSlabs A_BSUK_Slabs | RL | 10 ,SHE-08.ROOF.dgn,Design Model:108815 | A_BSUK_Roofs | New Construction | A-Roofs::A_BSUK_Roofs
A-FloorsSlabs A_BSUK_Slabs | RL | 10 ,SHE-08.ROOF.dgn,Design Model:108826 | A_BSUK_Roofs | New Construction | A-Roofs::A_BSUK_Roofs
A-FloorsSlabs A_BSUK_Slabs | RL | 10 ,SHE-08.ROOF.dgn,Design Model:108840 | A_BSUK_Roofs | New Construction | A-Roofs::A_BSUK_Roofs
A-FloorsSlabs A_BSUK_Slabs | RL | 10 ,SHE-08.ROOF.dgn,Design Model:108854 | A_BSUK_Roofs | New Construction | A-Roofs::A_BSUK_Roofs
A-FloorsSlabs A_BSUK_Slabs | RL | 10 ,SHE-08.ROOF.dgn,Design Model:108868 | A_BSUK_Roofs | New Construction | A-Roofs::A_BSUK_Roofs
A-FloorsSlabs A_BSUK_Slabs | RL | 10 ,SHE-08.ROOF.dgn,Design Model:108879 | A_BSUK_Roofs | New Construction | A-Roofs::A_BSUK_Roofs
A-FloorsSlabs A_BSUK_Slabs | RL | 10 ,SHE-08.ROOF.dgn,Design Model:108890 | A_BSUK_Roofs | New Construction | A-Roofs::A_BSUK_Roofs
A-FloorsSlabs A_BSUK_Slabs | RL | 10 ,SHE-08.ROOF.dgn,Design Model:108904 | A_BSUK_Roofs | New Construction | A-Roofs::A_BSUK_Roofs
A-FloorsSlabs A_BSUK_Slabs | RL | 10 ,SHE-08.ROOF.dgn,Design Model:108918 | A_BSUK_Roofs | New Construction | A-Roofs::A_BSUK_Roofs
A-FloorsSlabs A_BSUK_Slabs | RL | 10 ,SHE-08.ROOF.dgn,Design Model:108929 | A_BSUK_Roofs | New Construction | A-Roofs::A_BSUK_Roofs
A-FloorsSlabs A_BSUK_Slabs | RL | 10 ,SHE-08.ROOF.dgn,Design Model:108943 | A_BSUK_Roofs | New Construction | A-Roofs::A_BSUK_Roofs
A-FloorsSlabs A_BSUK_Slabs | RL | 10 ,SHE-08.ROOF.dgn,Design Model:108954 | A_BSUK_Roofs | New Construction | A-Roofs::A_BSUK_Roofs
A-FloorsSlabs A_BSUK_Slabs | RL | 10 ,SHE-08.ROOF.dgn,Design Model:108968 | A_BSUK_Roofs | New Construction | A-Roofs::A_BSUK_Roofs
A-FloorsSlabs A_BSUK_Slabs | RL | 10 ,SHE-08.ROOF.dgn,Design Model:108982 | A_BSUK_Roofs | New Construction | A-Roofs::A_BSUK_Roofs
A-FloorsSlabs A_BSUK_Slabs | RL | 10 ,SHE-08.ROOF.dgn,Design Model:108993 | A_BSUK_Roofs | New Construction | A-Roofs::A_BSUK_Roofs
A-FloorsSlabs A_BSUK_Slabs | RL | 10 ,SHE-08.ROOF.dgn,Design Model:109007 | A_BSUK_Roofs | New Construction | A-Roofs::A_BSUK_Roofs
A-FloorsSlabs A_BSUK_Slabs | RL | 10 ,SHE-08.ROOF.dgn,Design Model:109018 | A_BSUK_Roofs | New Construction | A-Roofs::A_BSUK_Roofs
A-FloorsSlabs A_BSUK_Slabs | RL | 10 ,SHE-08.ROOF.dgn,Design Model:109032 | A_BSUK_Roofs | New Construction | A-Roofs::A_BSUK_Roofs
A-FloorsSlabs A_BSUK_Slabs | RL | 10 ,SHE-08.ROOF.dgn,Design Model:109043 | A_BSUK_Roofs | New Construction | A-Roofs::A_BSUK_Roofs
A-FloorsSlabs A_BSUK_Slabs | RL | 10 ,SHE-08.ROOF.dgn,Design Model:109057 | A_BSUK_Roofs | New Construction | A-Roofs::A_BSUK_Roofs
A-FloorsSlabs A_BSUK_Slabs | RL | 10 ,SHE-08.ROOF.dgn,Design Model:109071 | A_BSUK_Roofs | New Construction | A-Roofs::A_BSUK_Roofs
A-FloorsSlabs A_BSUK_Slabs | RL | 10 ,SHE-08.ROOF.dgn,Design Model:109085 | A_BSUK_Roofs | New Construction | A-Roofs::A_BSUK_Roofs
A-FloorsSlabs A_BSUK_Slabs | RL | 10 ,SHE-08.ROOF.dgn,Design Model:109099 | A_BSUK_Roofs | New Construction | A-Roofs::A_BSUK_Roofs
A-FloorsSlabs A_BSUK_Slabs | RL | 10 ,SHE-08.ROOF.dgn,Design Model:109110 | A_BSUK_Roofs | New Construction | A-Roofs::A_BSUK_Roofs
A-FloorsSlabs A_BSUK_Slabs | RL | 10 ,SHE-08.ROOF.dgn,Design Model:109124 | A_BSUK_Roofs | New Construction | A-Roofs::A_BSUK_Roofs
A-FloorsSlabs A_BSUK_Slabs | RL | 10 ,SHE-08.ROOF.dgn,Design Model:109138 | A_BSUK_Roofs | New Construction | A-Roofs::A_BSUK_Roofs
A-FloorsSlabs A_BSUK_Slabs | RL | 10 ,SHE-08.ROOF.dgn,Design Model:109149 | A_BSUK_Roofs | New Construction | A-Roofs::A_BSUK_Roofs
A-FloorsSlabs A_BSUK_Slabs | RL | 10 ,SHE-08.ROOF.dgn,Design Model:109164 | A_BSUK_Roofs | New Construction | A-Roofs::A_BSUK_Roofs
A-FloorsSlabs A_BSUK_Slabs | RL | 10 ,SHE-08.ROOF.dgn,Design Model:109175 | A_BSUK_Roofs | New Construction | A-Roofs::A_BSUK_Roofs
A-FloorsSlabs A_BSUK_Slabs | RL | 10 ,SHE-08.ROOF.dgn,Design Model:109190 | A_BSUK_Roofs | New Construction | A-Roofs::A_BSUK_Roofs
A-FloorsSlabs A_BSUK_Slabs | RL | 10 ,SHE-08.ROOF.dgn,Design Model:109201 | A_BSUK_Roofs | New Construction | A-Roofs::A_BSUK_Roofs
A-FloorsSlabs A_BSUK_Slabs | RL | 10 ,SHE-08.ROOF.dgn,Design Model:109215 | A_BSUK_Roofs | New Construction | A-Roofs::A_BSUK_Roofs
A-FloorsSlabs A_BSUK_Slabs | RL | 10 ,SHE-08.ROOF.dgn,Design Model:109229 | A_BSUK_Roofs | New Construction | A-Roofs::A_BSUK_Roofs
A-FloorsSlabs A_BSUK_Slabs | RL | 10 ,SHE-08.ROOF.dgn,Design Model:109243 | A_BSUK_Roofs | New Construction | A-Roofs::A_BSUK_Roofs
A-FloorsSlabs A_BSUK_Slabs | RL | 10 ,SHE-08.ROOF.dgn,Design Model:109254 | A_BSUK_Roofs | New Construction | A-Roofs::A_BSUK_Roofs
A-FloorsSlabs A_BSUK_Slabs | RL | 10 ,SHE-08.ROOF.dgn,Design Model:109268 | A_BSUK_Roofs | New Construction | A-Roofs::A_BSUK_Roofs
A-FloorsSlabs A_BSUK_Slabs | RL | 10 ,SHE-08.ROOF.dgn,Design Model:109279 | A_BSUK_Roofs | New Construction | A-Roofs::A_BSUK_Roofs
A-FloorsSlabs A_BSUK_Slabs | RL | 10 ,SHE-08.ROOF.dgn,Design Model:109293 | A_BSUK_Roofs | New Construction | A-Roofs::A_BSUK_Roofs
A-FloorsSlabs A_BSUK_Slabs | RL | 10 ,SHE-08.ROOF.dgn,Design Model:109304 | A_BSUK_Roofs | New Construction | A-Roofs::A_BSUK_Roofs
A-FloorsSlabs A_BSUK_Slabs | RL | 10 ,SHE-08.ROOF.dgn,Design Model:109318 | A_BSUK_Roofs | New Construction | A-Roofs::A_BSUK_Roofs
A-FloorsSlabs A_BSUK_Slabs | RL | 10 ,SHE-08.ROOF.dgn,Design Model:109332 | A_BSUK_Roofs | New Construction | A-Roofs::A_BSUK_Roofs
A-FloorsSlabs A_BSUK_Slabs | RL | 10 ,SHE-08.ROOF.dgn,Design Model:109347 | A_BSUK_Roofs | New Construction | A-Roofs::A_BSUK_Roofs
A-FloorsSlabs A_BSUK_Slabs | RL | 10 ,SHE-08.ROOF.dgn,Design Model:109373 | A_BSUK_Roofs | New Construction | A-Roofs::A_BSUK_Roofs
A-FloorsSlabs A_BSUK_Slabs | RL | 10 ,SHE-08.ROOF.dgn,Design Model:109389 | A_BSUK_Roofs | New Construction | A-Roofs::A_BSUK_Roofs
A-FloorsSlabs A_BSUK_Slabs | RL | 10 ,SHE-08.ROOF.dgn,Design Model:109400 | A_BSUK_Roofs | New Construction | A-Roofs::A_BSUK_Roofs
A-FloorsSlabs A_BSUK_Slabs | RL | 10 ,SHE-08.ROOF.dgn,Design Model:109415 | A_BSUK_Roofs | New Construction | A-Roofs::A_BSUK_Roofs
A-FloorsSlabs A_BSUK_Slabs | RL | 10 ,SHE-08.ROOF.dgn,Design Model:109426 | A_BSUK_Roofs | New Construction | A-Roofs::A_BSUK_Roofs
A-FloorsSlabs A_BSUK_Slabs | RL | 10 ,SHE-08.ROOF.dgn,Design Model:109441 | A_BSUK_Roofs | New Construction | A-Roofs::A_BSUK_Roofs
A-FloorsSlabs A_BSUK_Slabs | RL | 10 ,SHE-08.ROOF.dgn,Design Model:109466 | A_BSUK_Roofs | New Construction | A-Roofs::A_BSUK_Roofs
A-FloorsSlabs A_BSUK_Slabs | RL | 10 ,SHE-08.ROOF.dgn,Design Model:109492 | A_BSUK_Roofs | New Construction | A-Roofs::A_BSUK_Roofs
A-FloorsSlabs A_BSUK_Slabs | RL | 10 ,SHE-08.ROOF.dgn,Design Model:109518 | A_BSUK_Roofs | New Construction | A-Roofs::A_BSUK_Roofs
A-FloorsSlabs A_BSUK_Slabs | RL | 10 ,SHE-08.ROOF.dgn,Design Model:109544 | A_BSUK_Roofs | New Construction | A-Roofs::A_BSUK_Roofs
A-FloorsSlabs A_BSUK_Slabs | RL | 10 ,SHE-08.ROOF.dgn,Design Model:109555 | A_BSUK_Roofs | New Construction | A-Roofs::A_BSUK_Roofs
A-FloorsSlabs A_BSUK_Slabs | RL | 10 ,SHE-08.ROOF.dgn,Design Model:109569 | A_BSUK_Roofs | New Construction | A-Roofs::A_BSUK_Roofs
A-FloorsSlabs A_BSUK_Slabs | RL | 10 ,SHE-08.ROOF.dgn,Design Model:109580 | A_BSUK_Roofs | New Construction | A-Roofs::A_BSUK_Roofs
A-FloorsSlabs A_BSUK_Slabs | RL | 10 ,SHE-08.ROOF.dgn,Design Model:109609 | A_BSUK_Roofs | New Construction | A-Roofs::A_BSUK_Roofs
A-FloorsSlabs A_BSUK_Slabs | RL | 10 ,SHE-08.ROOF.dgn,Design Model:109620 | A_BSUK_Roofs | New Construction | A-Roofs::A_BSUK_Roofs
A-FloorsSlabs A_BSUK_Slabs | RL | 10 ,SHE-08.ROOF.dgn,Design Model:109634 | A_BSUK_Roofs | New Construction | A-Roofs::A_BSUK_Roofs
A-FloorsSlabs A_BSUK_Slabs | RL | 10 ,SHE-08.ROOF.dgn,Design Model:109645 | A_BSUK_Roofs | New Construction | A-Roofs::A_BSUK_Roofs
A-FloorsSlabs A_BSUK_Slabs | RL | 10 ,SHE-08.ROOF.dgn,Design Model:109674 | A_BSUK_Roofs | New Construction | A-Roofs::A_BSUK_Roofs
A-FloorsSlabs A_BSUK_Slabs | RL | 10 ,SHE-08.ROOF.dgn,Design Model:109685 | A_BSUK_Roofs | New Construction | A-Roofs::A_BSUK_Roofs
A-FloorsSlabs A_BSUK_Slabs | RL | 10 ,SHE-08.ROOF.dgn,Design Model:109714 | A_BSUK_Roofs | New Construction | A-Roofs::A_BSUK_Roofs
A-FloorsSlabs A_BSUK_Slabs | RL | 10 ,SHE-08.ROOF.dgn,Design Model:109726 | A_BSUK_Roofs | New Construction | A-Roofs::A_BSUK_Roofs
A-FloorsSlabs A_BSUK_Slabs | RL | 10 ,SHE-08.ROOF.dgn,Design Model:109740 | A_BSUK_Roofs | New Construction | A-Roofs::A_BSUK_Roofs
A-FloorsSlabs A_BSUK_Slabs | RL | 10 ,SHE-08.ROOF.dgn,Design Model:109754 | A_BSUK_Roofs | New Construction | A-Roofs::A_BSUK_Roofs
A-FloorsSlabs A_BSUK_Slabs | RL | 10 ,SHE-08.ROOF.dgn,Design Model:109768 | A_BSUK_Roofs | New Construction | A-Roofs::A_BSUK_Roofs
A-FloorsSlabs A_BSUK_Slabs | RL | 10 ,SHE-08.ROOF.dgn,Design Model:109796 | A_BSUK_Roofs | New Construction | A-Roofs::A_BSUK_Roofs
A-FloorsSlabs A_BSUK_Slabs | RL | 10 ,SHE-08.ROOF.dgn,Design Model:109807 | A_BSUK_Roofs | New Construction | A-Roofs::A_BSUK_Roofs
A-FloorsSlabs A_BSUK_Slabs | RL | 10 ,SHE-08.ROOF.dgn,Design Model:109836 | A_BSUK_Roofs | New Construction | A-Roofs::A_BSUK_Roofs
A-FloorsSlabs A_BSUK_Slabs | RL | 10 ,SHE-08.ROOF.dgn,Design Model:109847 | A_BSUK_Roofs | New Construction | A-Roofs::A_BSUK_Roofs
A-FloorsSlabs A_BSUK_Slabs | RL | 10 ,SHE-08.ROOF.dgn,Design Model:109861 | A_BSUK_Roofs | New Construction | A-Roofs::A_BSUK_Roofs
A-FloorsSlabs A_BSUK_Slabs | RL | 10 ,SHE-08.ROOF.dgn,Design Model:109872 | A_BSUK_Roofs | New Construction | A-Roofs::A_BSUK_Roofs
A-FloorsSlabs A_BSUK_Slabs | RL | 10 ,SHE-08.ROOF.dgn,Design Model:109901 | A_BSUK_Roofs | New Construction | A-Roofs::A_BSUK_Roofs
A-FloorsSlabs A_BSUK_Slabs | RL | 10 ,SHE-08.ROOF.dgn,Design Model:109912 | A_BSUK_Roofs | New Construction | A-Roofs::A_BSUK_Roofs
A-FloorsSlabs A_BSUK_Slabs | RL | 10 ,SHE-08.ROOF.dgn,Design Model:109926 | A_BSUK_Roofs | New Construction | A-Roofs::A_BSUK_Roofs
A-FloorsSlabs A_BSUK_Slabs | RL | 10 ,SHE-08.ROOF.dgn,Design Model:109937 | A_BSUK_Roofs | New Construction | A-Roofs::A_BSUK_Roofs
A-FloorsSlabs A_BSUK_Slabs | RL | 10 ,SHE-08.ROOF.dgn,Design Model:109966 | A_BSUK_Roofs | New Construction | A-Roofs::A_BSUK_Roofs
A-FloorsSlabs A_BSUK_Slabs | RL | 10 ,SHE-08.ROOF.dgn,Design Model:109978 | A_BSUK_Roofs | New Construction | A-Roofs::A_BSUK_Roofs
A-FloorsSlabs A_BSUK_Slabs | RL | 10 ,SHE-08.ROOF.dgn,Design Model:110006 | A_BSUK_Roofs | New Construction | A-Roofs::A_BSUK_Roofs
A-FloorsSlabs A_BSUK_Slabs | RL | 10 ,SHE-08.ROOF.dgn,Design Model:110018 | A_BSUK_Roofs | New Construction | A-Roofs::A_BSUK_Roofs
A-FloorsSlabs A_BSUK_Slabs | RL | 10 ,SHE-08.ROOF.dgn,Design Model:110046 | A_BSUK_Roofs | New Construction | A-Roofs::A_BSUK_Roofs
A-FloorsSlabs A_BSUK_Slabs | RL | 10 ,SHE-08.ROOF.dgn,Design Model:110058 | A_BSUK_Roofs | New Construction | A-Roofs::A_BSUK_Roofs
A-FloorsSlabs A_BSUK_Slabs | RL | 10 ,SHE-08.ROOF.dgn,Design Model:110087 | A_BSUK_Roofs | New Construction | A-Roofs::A_BSUK_Roofs
A-FloorsSlabs A_BSUK_Slabs | RL | 10 ,SHE-08.ROOF.dgn,Design Model:110103 | A_BSUK_Roofs | New Construction | A-Roofs::A_BSUK_Roofs
A-FloorsSlabs A_BSUK_Slabs | RL | 10 ,SHE-08.ROOF.dgn,Design Model:110114 | A_BSUK_Roofs | New Construction | A-Roofs::A_BSUK_Roofs
A-FloorsSlabs A_BSUK_Slabs | RL | 10 ,SHE-08.ROOF.dgn,Design Model:110129 | A_BSUK_Roofs | New Construction | A-Roofs::A_BSUK_Roofs
A-FloorsSlabs A_BSUK_Slabs | RL | 10 ,SHE-08.ROOF.dgn,Design Model:110140 | A_BSUK_Roofs | New Construction | A-Roofs::A_BSUK_Roofs
A-FloorsSlabs A_BSUK_Slabs | RL | 10 ,SHE-08.ROOF.dgn,Design Model:110154 | A_BSUK_Roofs | New Construction | A-Roofs::A_BSUK_Roofs
A-FloorsSlabs A_BSUK_Slabs | RL | 10 ,SHE-08.ROOF.dgn,Design Model:110165 | A_BSUK_Roofs | New Construction | A-Roofs::A_BSUK_Roofs
A-FloorsSlabs A_BSUK_Slabs | RL | 10 ,SHE-08.ROOF.dgn,Design Model:110179 | A_BSUK_Roofs | New Construction | A-Roofs::A_BSUK_Roofs
A-FloorsSlabs A_BSUK_Slabs | RL | 10 ,SHE-08.ROOF.dgn,Design Model:110194 | A_BSUK_Roofs | New Construction | A-Roofs::A_BSUK_Roofs
A-FloorsSlabs A_BSUK_Slabs | RL | 10 ,SHE-08.ROOF.dgn,Design Model:110205 | A_BSUK_Roofs | New Construction | A-Roofs::A_BSUK_Roofs
A-FloorsSlabs A_BSUK_Slabs | RL | 10 ,SHE-08.ROOF.dgn,Design Model:110219 | A_BSUK_Roofs | New Construction | A-Roofs::A_BSUK_Roofs
A-FloorsSlabs A_BSUK_Slabs | RL | 10 ,SHE-08.ROOF.dgn,Design Model:110230 | A_BSUK_Roofs | New Construction | A-Roofs::A_BSUK_Roofs
A-FloorsSlabs A_BSUK_Slabs | RL | 10 ,SHE-08.ROOF.dgn,Design Model:110245 | A_BSUK_Roofs | New Construction | A-Roofs::A_BSUK_Roofs
A-FloorsSlabs A_BSUK_Slabs | RL | 10 ,SHE-08.ROOF.dgn,Design Model:110256 | A_BSUK_Roofs | New Construction | A-Roofs::A_BSUK_Roofs
A-FloorsSlabs A_BSUK_Slabs | RL | 10 ,SHE-08.ROOF.dgn,Design Model:110271 | A_BSUK_Roofs | New Construction | A-Roofs::A_BSUK_Roofs
A-FloorsSlabs A_BSUK_Slabs | RL | 10 ,SHE-08.ROOF.dgn,Design Model:110282 | A_BSUK_Roofs | New Construction | A-Roofs::A_BSUK_Roofs
A-FloorsSlabs A_BSUK_Slabs | RL | 10 ,SHE-08.ROOF.dgn,Design Model:110296 | A_BSUK_Roofs | New Construction | A-Roofs::A_BSUK_Roofs
A-FloorsSlabs A_BSUK_Slabs | RL | 10 ,SHE-08.ROOF.dgn,Design Model:110310 | A_BSUK_Roofs | New Construction | A-Roofs::A_BSUK_Roofs
A-FloorsSlabs A_BSUK_Slabs | RL | 10 ,SHE-08.ROOF.dgn,Design Model:110324 | A_BSUK_Roofs | New Construction | A-Roofs::A_BSUK_Roofs
A-FloorsSlabs A_BSUK_Slabs | RL | 10 ,SHE-08.ROOF.dgn,Design Model:110335 | A_BSUK_Roofs | New Construction | A-Roofs::A_BSUK_Roofs
A-FloorsSlabs A_BSUK_Slabs | RL | 10 ,SHE-08.ROOF.dgn,Design Model:110349 | A_BSUK_Roofs | New Construction | A-Roofs::A_BSUK_Roofs
A-FloorsSlabs A_BSUK_Slabs | RL | 10 ,SHE-08.ROOF.dgn,Design Model:110360 | A_BSUK_Roofs | New Construction | A-Roofs::A_BSUK_Roofs
A-FloorsSlabs A_BSUK_Slabs | RL | 10 ,SHE-08.ROOF.dgn,Design Model:110374 | A_BSUK_Roofs | New Construction | A-Roofs::A_BSUK_Roofs
A-FloorsSlabs A_BSUK_Slabs | RL | 10 ,SHE-08.ROOF.dgn,Design Model:110389 | A_BSUK_Roofs | New Construction | A-Roofs::A_BSUK_Roofs
A-FloorsSlabs A_BSUK_Slabs | RL | 10 ,SHE-08.ROOF.dgn,Design Model:110400 | A_BSUK_Roofs | New Construction | A-Roofs::A_BSUK_Roofs
A-FloorsSlabs A_BSUK_Slabs | RL | 10 ,SHE-08.ROOF.dgn,Design Model:110414 | A_BSUK_Roofs | New Construction | A-Roofs::A_BSUK_Roofs
A-FloorsSlabs A_BSUK_Slabs | RL | 10 ,SHE-08.ROOF.dgn,Design Model:110425 | A_BSUK_Roofs | New Construction | A-Roofs::A_BSUK_Roofs
A-FloorsSlabs A_BSUK_Slabs | RL | 10 ,SHE-08.ROOF.dgn,Design Model:110439 | A_BSUK_Roofs | New Construction | A-Roofs::A_BSUK_Roofs
A-FloorsSlabs A_BSUK_Slabs | RL | 10 ,SHE-08.ROOF.dgn,Design Model:110453 | A_BSUK_Roofs | New Construction | A-Roofs::A_BSUK_Roofs
A-FloorsSlabs A_BSUK_Slabs | RL | 10 ,SHE-08.ROOF.dgn,Design Model:110468 | A_BSUK_Roofs | New Construction | A-Roofs::A_BSUK_Roofs
A-FloorsSlabs A_BSUK_Slabs | RL | 10 ,SHE-08.ROOF.dgn,Design Model:110479 | A_BSUK_Roofs | New Construction | A-Roofs::A_BSUK_Roofs
A-FloorsSlabs A_BSUK_Slabs | RL | 10 ,SHE-08.ROOF.dgn,Design Model:110493 | A_BSUK_Roofs | New Construction | A-Roofs::A_BSUK_Roofs
A-FloorsSlabs A_BSUK_Slabs | RL | 10 ,SHE-08.ROOF.dgn,Design Model:110504 | A_BSUK_Roofs | New Construction | A-Roofs::A_BSUK_Roofs
A-FloorsSlabs A_BSUK_Slabs | RL | 10 ,SHE-08.ROOF.dgn,Design Model:110519 | A_BSUK_Roofs | New Construction | A-Roofs::A_BSUK_Roofs
A-FloorsSlabs A_BSUK_Slabs | RL | 10 ,SHE-08.ROOF.dgn,Design Model:110530 | A_BSUK_Roofs | New Construction | A-Roofs::A_BSUK_Roofs
A-FloorsSlabs A_BSUK_Slabs | RL | 10 ,SHE-08.ROOF.dgn,Design Model:110545 | A_BSUK_Roofs | New Construction | A-Roofs::A_BSUK_Roofs
A-FloorsSlabs A_BSUK_Slabs | RL | 10 ,SHE-08.ROOF.dgn,Design Model:110556 | A_BSUK_Roofs | New Construction | A-Roofs::A_BSUK_Roofs
A-FloorsSlabs A_BSUK_Slabs | RL | 10 ,SHE-08.ROOF.dgn,Design Model:110570 | A_BSUK_Roofs | New Construction | A-Roofs::A_BSUK_Roofs
A-FloorsSlabs A_BSUK_Slabs | RL | 10 ,SHE-08.ROOF.dgn,Design Model:110584 | A_BSUK_Roofs | New Construction | A-Roofs::A_BSUK_Roofs
A-FloorsSlabs A_BSUK_Slabs | RL | 10 ,SHE-08.ROOF.dgn,Design Model:110598 | A_BSUK_Roofs | New Construction | A-Roofs::A_BSUK_Roofs
A-FloorsSlabs A_BSUK_Slabs | RL | 10 ,SHE-08.ROOF.dgn,Design Model:110609 | A_BSUK_Roofs | New Construction | A-Roofs::A_BSUK_Roofs
A-FloorsSlabs A_BSUK_Slabs | RL | 10 ,SHE-08.ROOF.dgn,Design Model:110623 | A_BSUK_Roofs | New Construction | A-Roofs::A_BSUK_Roofs
A-FloorsSlabs A_BSUK_Slabs | RL | 10 ,SHE-08.ROOF.dgn,Design Model:110634 | A_BSUK_Roofs | New Construction | A-Roofs::A_BSUK_Roofs
A-FloorsSlabs A_BSUK_Slabs | RL | 10 ,SHE-08.ROOF.dgn,Design Model:110648 | A_BSUK_Roofs | New Construction | A-Roofs::A_BSUK_Roofs
A-FloorsSlabs A_BSUK_Slabs | RL | 10 ,SHE-08.ROOF.dgn,Design Model:110663 | A_BSUK_Roofs | New Construction | A-Roofs::A_BSUK_Roofs
A-FloorsSlabs A_BSUK_Slabs | RL | 10 ,SHE-08.ROOF.dgn,Design Model:110674 | A_BSUK_Roofs | New Construction | A-Roofs::A_BSUK_Roofs
A-FloorsSlabs A_BSUK_Slabs | RL | 10 ,SHE-08.ROOF.dgn,Design Model:110688 | A_BSUK_Roofs | New Construction | A-Roofs::A_BSUK_Roofs
A-FloorsSlabs A_BSUK_Slabs | RL | 10 ,SHE-08.ROOF.dgn,Design Model:110699 | A_BSUK_Roofs | New Construction | A-Roofs::A_BSUK_Roofs
A-FloorsSlabs A_BSUK_Slabs | RL | 10 ,SHE-08.ROOF.dgn,Design Model:110713 | A_BSUK_Roofs | New Construction | A-Roofs::A_BSUK_Roofs
A-FloorsSlabs A_BSUK_Slabs | RL | 10 ,SHE-08.ROOF.dgn,Design Model:110727 | A_BSUK_Roofs | New Construction | A-Roofs::A_BSUK_Roofs
A-FloorsSlabs A_BSUK_Slabs | RL | 10 ,SHE-08.ROOF.dgn,Design Model:110738 | A_BSUK_Roofs | New Construction | A-Roofs::A_BSUK_Roofs
A-FloorsSlabs A_BSUK_Slabs | RL | 10 ,SHE-08.ROOF.dgn,Design Model:110753 | A_BSUK_Roofs | New Construction | A-Roofs::A_BSUK_Roofs
A-FloorsSlabs A_BSUK_Slabs | RL | 10 ,SHE-08.ROOF.dgn,Design Model:110767 | A_BSUK_Roofs | New Construction | A-Roofs::A_BSUK_Roofs
A-FloorsSlabs A_BSUK_Slabs | RL | 10 ,SHE-08.ROOF.dgn,Design Model:110778 | A_BSUK_Roofs | New Construction | A-Roofs::A_BSUK_Roofs
A-FloorsSlabs A_BSUK_Slabs | RL | 10 ,SHE-08.ROOF.dgn,Design Model:110792 | A_BSUK_Roofs | New Construction | A-Roofs::A_BSUK_Roofs
A-FloorsSlabs A_BSUK_Slabs | RL | 10 ,SHE-08.ROOF.dgn,Design Model:110803 | A_BSUK_Roofs | New Construction | A-Roofs::A_BSUK_Roofs
A-FloorsSlabs A_BSUK_Slabs | RL | 10 ,SHE-08.ROOF.dgn,Design Model:110818 | A_BSUK_Roofs | New Construction | A-Roofs::A_BSUK_Roofs
A-FloorsSlabs A_BSUK_Slabs | RL | 10 ,SHE-08.ROOF.dgn,Design Model:110832 | A_BSUK_Roofs | New Construction | A-Roofs::A_BSUK_Roofs
A-FloorsSlabs A_BSUK_Slabs | RL | 10 ,SHE-08.ROOF.dgn,Design Model:110843 | A_BSUK_Roofs | New Construction | A-Roofs::A_BSUK_Roofs
A-FloorsSlabs A_BSUK_Slabs | RL | 10 ,SHE-08.ROOF.dgn,Design Model:110857 | A_BSUK_Roofs | New Construction | A-Roofs::A_BSUK_Roofs
A-FloorsSlabs A_BSUK_Slabs | RL | 10 ,SHE-08.ROOF.dgn,Design Model:110868 | A_BSUK_Roofs | New Construction | A-Roofs::A_BSUK_Roofs
A-FloorsSlabs A_BSUK_Slabs | RL | 10 ,SHE-08.ROOF.dgn,Design Model:110883 | A_BSUK_Roofs | New Construction | A-Roofs::A_BSUK_Roofs
A-FloorsSlabs A_BSUK_Slabs | RL | 10 ,SHE-08.ROOF.dgn,Design Model:110897 | A_BSUK_Roofs | New Construction | A-Roofs::A_BSUK_Roofs
A-FloorsSlabs A_BSUK_Slabs | RL | 10 ,SHE-08.ROOF.dgn,Design Model:110909 | A_BSUK_Roofs | New Construction | A-Roofs::A_BSUK_Roofs
A-FloorsSlabs A_BSUK_Slabs | RL | 10 ,SHE-08.ROOF.dgn,Design Model:110923 | A_BSUK_Roofs | New Construction | A-Roofs::A_BSUK_Roofs
A-FloorsSlabs A_BSUK_Slabs | RL | 10 ,SHE-08.ROOF.dgn,Design Model:110937 | A_BSUK_Roofs | New Construction | A-Roofs::A_BSUK_Roofs
A-FloorsSlabs A_BSUK_Slabs | RL | 10 ,SHE-08.ROOF.dgn,Design Model:110949 | A_BSUK_Roofs | New Construction | A-Roofs::A_BSUK_Roofs
A-FloorsSlabs A_BSUK_Slabs | RL | 10 ,SHE-08.ROOF.dgn,Design Model:110963 | A_BSUK_Roofs | New Construction | A-Roofs::A_BSUK_Roofs
A-FloorsSlabs A_BSUK_Slabs | RL | 10 ,SHE-08.ROOF.dgn,Design Model:110977 | A_BSUK_Roofs | New Construction | A-Roofs::A_BSUK_Roofs
A-FloorsSlabs A_BSUK_Slabs | RL | 10 ,SHE-08.ROOF.dgn,Design Model:110989 | A_BSUK_Roofs | New Construction | A-Roofs::A_BSUK_Roofs
A-FloorsSlabs A_BSUK_Slabs | RL | 10 ,SHE-08.ROOF.dgn,Design Model:111004 | A_BSUK_Roofs | New Construction | A-Roofs::A_BSUK_Roofs
A-FloorsSlabs A_BSUK_Slabs | RL | 10 ,SHE-08.ROOF.dgn,Design Model:111018 | A_BSUK_Roofs | New Construction | A-Roofs::A_BSUK_Roofs
A-FloorsSlabs A_BSUK_Slabs | RL | 10 ,SHE-08.ROOF.dgn,Design Model:111034 | A_BSUK_Roofs | New Construction | A-Roofs::A_BSUK_Roofs
A-FloorsSlabs A_BSUK_Slabs | RL | 10 ,SHE-08.ROOF.dgn,Design Model:111045 | A_BSUK_Roofs | New Construction | A-Roofs::A_BSUK_Roofs
A-FloorsSlabs A_BSUK_Slabs | RL | 10 ,SHE-08.ROOF.dgn,Design Model:111060 | A_BSUK_Roofs | New Construction | A-Roofs::A_BSUK_Roofs
A-FloorsSlabs A_BSUK_Slabs | RL | 10 ,SHE-08.ROOF.dgn,Design Model:111071 | A_BSUK_Roofs | New Construction | A-Roofs::A_BSUK_Roofs
A-FloorsSlabs A_BSUK_Slabs | RL | 10 ,SHE-08.ROOF.dgn,Design Model:111085 | A_BSUK_Roofs | New Construction | A-Roofs::A_BSUK_Roofs
A-FloorsSlabs A_BSUK_Slabs | RL | 10 ,SHE-08.ROOF.dgn,Design Model:111096 | A_BSUK_Roofs | New Construction | A-Roofs::A_BSUK_Roofs
A-FloorsSlabs A_BSUK_Slabs | RL | 10 ,SHE-08.ROOF.dgn,Design Model:111110 | A_BSUK_Roofs | New Construction | A-Roofs::A_BSUK_Roofs
A-FloorsSlabs A_BSUK_Slabs | RL | 10 ,SHE-08.ROOF.dgn,Design Model:111125 | A_BSUK_Roofs | New Construction | A-Roofs::A_BSUK_Roofs
A-FloorsSlabs A_BSUK_Slabs | RL | 10 ,SHE-08.ROOF.dgn,Design Model:111136 | A_BSUK_Roofs | New Construction | A-Roofs::A_BSUK_Roofs
A-FloorsSlabs A_BSUK_Slabs | RL | 10 ,SHE-08.ROOF.dgn,Design Model:111150 | A_BSUK_Roofs | New Construction | A-Roofs::A_BSUK_Roofs
A-FloorsSlabs A_BSUK_Slabs | RL | 10 ,SHE-08.ROOF.dgn,Design Model:111161 | A_BSUK_Roofs | New Construction | A-Roofs::A_BSUK_Roofs
A-FloorsSlabs A_BSUK_Slabs | RL | 10 ,SHE-08.ROOF.dgn,Design Model:111176 | A_BSUK_Roofs | New Construction | A-Roofs::A_BSUK_Roofs
A-FloorsSlabs A_BSUK_Slabs | RL | 10 ,SHE-08.ROOF.dgn,Design Model:111187 | A_BSUK_Roofs | New Construction | A-Roofs::A_BSUK_Roofs
A-FloorsSlabs A_BSUK_Slabs | RL | 10 ,SHE-08.ROOF.dgn,Design Model:111202 | A_BSUK_Roofs | New Construction | A-Roofs::A_BSUK_Roofs
A-FloorsSlabs A_BSUK_Slabs | RL | 10 ,SHE-08.ROOF.dgn,Design Model:111213 | A_BSUK_Roofs | New Construction | A-Roofs::A_BSUK_Roofs
A-FloorsSlabs A_BSUK_Slabs | RL | 10 ,SHE-08.ROOF.dgn,Design Model:111227 | A_BSUK_Roofs | New Construction | A-Roofs::A_BSUK_Roofs
A-FloorsSlabs A_BSUK_Slabs | RL | 10 ,SHE-08.ROOF.dgn,Design Model:111241 | A_BSUK_Roofs | New Construction | A-Roofs::A_BSUK_Roofs
A-FloorsSlabs A_BSUK_Slabs | RL | 10 ,SHE-08.ROOF.dgn,Design Model:111255 | A_BSUK_Roofs | New Construction | A-Roofs::A_BSUK_Roofs
A-FloorsSlabs A_BSUK_Slabs | RL | 10 ,SHE-08.ROOF.dgn,Design Model:111266 | A_BSUK_Roofs | New Construction | A-Roofs::A_BSUK_Roofs
A-FloorsSlabs A_BSUK_Slabs | RL | 10 ,SHE-08.ROOF.dgn,Design Model:111280 | A_BSUK_Roofs | New Construction | A-Roofs::A_BSUK_Roofs
A-FloorsSlabs A_BSUK_Slabs | RL | 10 ,SHE-08.ROOF.dgn,Design Model:111291 | A_BSUK_Roofs | New Construction | A-Roofs::A_BSUK_Roofs
A-FloorsSlabs A_BSUK_Slabs | RL | 10 ,SHE-08.ROOF.dgn,Design Model:111305 | A_BSUK_Roofs | New Construction | A-Roofs::A_BSUK_Roofs
A-FloorsSlabs A_BSUK_Slabs | RL | 10 ,SHE-08.ROOF.dgn,Design Model:111320 | A_BSUK_Roofs | New Construction | A-Roofs::A_BSUK_Roofs
A-FloorsSlabs A_BSUK_Slabs | RL | 10 ,SHE-08.ROOF.dgn,Design Model:111331 | A_BSUK_Roofs | New Construction | A-Roofs::A_BSUK_Roofs
A-FloorsSlabs A_BSUK_Slabs | RL | 10 ,SHE-08.ROOF.dgn,Design Model:111345 | A_BSUK_Roofs | New Construction | A-Roofs::A_BSUK_Roofs
A-FloorsSlabs A_BSUK_Slabs | RL | 10 ,SHE-08.ROOF.dgn,Design Model:111356 | A_BSUK_Roofs | New Construction | A-Roofs::A_BSUK_Roofs
A-FloorsSlabs A_BSUK_Slabs | RL | 10 ,SHE-08.ROOF.dgn,Design Model:111370 | A_BSUK_Roofs | New Construction | A-Roofs::A_BSUK_Roofs
A-FloorsSlabs A_BSUK_Slabs | RL | 10 ,SHE-08.ROOF.dgn,Design Model:111384 | A_BSUK_Roofs | New Construction | A-Roofs::A_BSUK_Roofs
A-FloorsSlabs A_BSUK_Slabs | RL | 10 ,SHE-08.ROOF.dgn,Design Model:111396 | A_BSUK_Roofs | New Construction | A-Roofs::A_BSUK_Roofs
A-FloorsSlabs A_BSUK_Slabs | RL | 10 ,SHE-08.ROOF.dgn,Design Model:111424 | A_BSUK_Roofs | New Construction | A-Roofs::A_BSUK_Roofs
A-FloorsSlabs A_BSUK_Slabs | RL | 10 ,SHE-08.ROOF.dgn,Design Model:111435 | A_BSUK_Roofs | New Construction | A-Roofs::A_BSUK_Roofs
A-FloorsSlabs A_BSUK_Slabs | RL | 10 ,SHE-08.ROOF.dgn,Design Model:111450 | A_BSUK_Roofs | New Construction | A-Roofs::A_BSUK_Roofs
A-FloorsSlabs A_BSUK_Slabs | RL | 10 ,SHE-08.ROOF.dgn,Design Model:111464 | A_BSUK_Roofs | New Construction | A-Roofs::A_BSUK_Roofs
A-FloorsSlabs A_BSUK_Slabs | RL | 10 ,SHE-08.ROOF.dgn,Design Model:111475 | A_BSUK_Roofs | New Construction | A-Roofs::A_BSUK_Roofs
A-FloorsSlabs A_BSUK_Slabs | RL | 10 ,SHE-08.ROOF.dgn,Design Model:111489 | A_BSUK_Roofs | New Construction | A-Roofs::A_BSUK_Roofs
A-FloorsSlabs A_BSUK_Slabs | RL | 10 ,SHE-08.ROOF.dgn,Design Model:111500 | A_BSUK_Roofs | New Construction | A-Roofs::A_BSUK_Roofs
A-FloorsSlabs A_BSUK_Slabs | RL | 10 ,SHE-08.ROOF.dgn,Design Model:111515 | A_BSUK_Roofs | New Construction | A-Roofs::A_BSUK_Roofs
A-FloorsSlabs A_BSUK_Slabs | RL | 10 ,SHE-08.ROOF.dgn,Design Model:111529 | A_BSUK_Roofs | New Construction | A-Roofs::A_BSUK_Roofs
A-FloorsSlabs A_BSUK_Slabs | RL | 10 ,SHE-08.ROOF.dgn,Design Model:111540 | A_BSUK_Roofs | New Construction | A-Roofs::A_BSUK_Roofs
A-FloorsSlabs A_BSUK_Slabs | RL | 10 ,SHE-08.ROOF.dgn,Design Model:111554 | A_BSUK_Roofs | New Construction | A-Roofs::A_BSUK_Roofs
A-FloorsSlabs A_BSUK_Slabs | RL | 10 ,SHE-08.ROOF.dgn,Design Model:111565 | A_BSUK_Roofs | New Construction | A-Roofs::A_BSUK_Roofs
A-FloorsSlabs A_BSUK_Slabs | RL | 10 ,SHE-08.ROOF.dgn,Design Model:111580 | A_BSUK_Roofs | New Construction | A-Roofs::A_BSUK_Roofs
A-FloorsSlabs A_BSUK_Slabs | RL | 10 ,SHE-08.ROOF.dgn,Design Model:111594 | A_BSUK_Roofs | New Construction | A-Roofs::A_BSUK_Roofs
A-FloorsSlabs A_BSUK_Slabs | RL | 10 ,SHE-08.ROOF.dgn,Design Model:111606 | A_BSUK_Roofs | New Construction | A-Roofs::A_BSUK_Roofs
A-FloorsSlabs A_BSUK_Slabs | RL | 10 ,SHE-08.ROOF.dgn,Design Model:111620 | A_BSUK_Roofs | New Construction | A-Roofs::A_BSUK_Roofs
A-FloorsSlabs A_BSUK_Slabs | RL | 10 ,SHE-08.ROOF.dgn,Design Model:111634 | A_BSUK_Roofs | New Construction | A-Roofs::A_BSUK_Roofs
A-FloorsSlabs A_BSUK_Slabs | RL | 10 ,SHE-08.ROOF.dgn,Design Model:111646 | A_BSUK_Roofs | New Construction | A-Roofs::A_BSUK_Roofs
A-FloorsSlabs A_BSUK_Slabs | RL | 10 ,SHE-08.ROOF.dgn,Design Model:111660 | A_BSUK_Roofs | New Construction | A-Roofs::A_BSUK_Roofs
A-FloorsSlabs A_BSUK_Slabs | RL | 10 ,SHE-08.ROOF.dgn,Design Model:111674 | A_BSUK_Roofs | New Construction | A-Roofs::A_BSUK_Roofs
A-FloorsSlabs A_BSUK_Slabs | RL | 10 ,SHE-08.ROOF.dgn,Design Model:111686 | A_BSUK_Roofs | New Construction | A-Roofs::A_BSUK_Roofs
A-FloorsSlabs A_BSUK_Slabs | RL | 10 ,SHE-08.ROOF.dgn,Design Model:111701 | A_BSUK_Roofs | New Construction | A-Roofs::A_BSUK_Roofs
A-FloorsSlabs A_BSUK_Slabs | RL | 10 ,SHE-08.ROOF.dgn,Design Model:111715 | A_BSUK_Roofs | New Construction | A-Roofs::A_BSUK_Roofs
A-FloorsSlabs A_BSUK_Slabs | RL | 10 ,SHE-08.ROOF.dgn,Design Model:111731 | A_BSUK_Roofs | New Construction | A-Roofs::A_BSUK_Roofs
A-FloorsSlabs A_BSUK_Slabs | RL | 10 ,SHE-08.ROOF.dgn,Design Model:111742 | A_BSUK_Roofs | New Construction | A-Roofs::A_BSUK_Roofs
A-FloorsSlabs A_BSUK_Slabs | RL | 10 ,SHE-08.ROOF.dgn,Design Model:111757 | A_BSUK_Roofs | New Construction | A-Roofs::A_BSUK_Roofs
A-FloorsSlabs A_BSUK_Slabs | RL | 10 ,SHE-08.ROOF.dgn,Design Model:111768 | A_BSUK_Roofs | New Construction | A-Roofs::A_BSUK_Roofs
A-FloorsSlabs A_BSUK_Slabs | RL | 10 ,SHE-08.ROOF.dgn,Design Model:111782 | A_BSUK_Roofs | New Construction | A-Roofs::A_BSUK_Roofs
A-FloorsSlabs A_BSUK_Slabs | RL | 10 ,SHE-08.ROOF.dgn,Design Model:111793 | A_BSUK_Roofs | New Construction | A-Roofs::A_BSUK_Roofs
A-FloorsSlabs A_BSUK_Slabs | RL | 10 ,SHE-08.ROOF.dgn,Design Model:111807 | A_BSUK_Roofs | New Construction | A-Roofs::A_BSUK_Roofs
A-FloorsSlabs A_BSUK_Slabs | RL | 10 ,SHE-08.ROOF.dgn,Design Model:111818 | A_BSUK_Roofs | New Construction | A-Roofs::A_BSUK_Roofs
A-FloorsSlabs A_BSUK_Slabs | RL | 10 ,SHE-08.ROOF.dgn,Design Model:111832 | A_BSUK_Roofs | New Construction | A-Roofs::A_BSUK_Roofs
A-FloorsSlabs A_BSUK_Slabs | RL | 10 ,SHE-08.ROOF.dgn,Design Model:111843 | A_BSUK_Roofs | New Construction | A-Roofs::A_BSUK_Roofs
A-FloorsSlabs A_BSUK_Slabs | RL | 10 ,SHE-08.ROOF.dgn,Design Model:111857 | A_BSUK_Roofs | New Construction | A-Roofs::A_BSUK_Roofs
A-FloorsSlabs A_BSUK_Slabs | RL | 10 ,SHE-08.ROOF.dgn,Design Model:111871 | A_BSUK_Roofs | New Construction | A-Roofs::A_BSUK_Roofs
A-FloorsSlabs A_BSUK_Slabs | RL | 10 ,SHE-08.ROOF.dgn,Design Model:111882 | A_BSUK_Roofs | New Construction | A-Roofs::A_BSUK_Roofs
A-FloorsSlabs A_BSUK_Slabs | RL | 10 ,SHE-08.ROOF.dgn,Design Model:111896 | A_BSUK_Roofs | New Construction | A-Roofs::A_BSUK_Roofs
A-FloorsSlabs A_BSUK_Slabs | RL | 10 ,SHE-08.ROOF.dgn,Design Model:111907 | A_BSUK_Roofs | New Construction | A-Roofs::A_BSUK_Roofs
A-FloorsSlabs A_BSUK_Slabs | RL | 10 ,SHE-08.ROOF.dgn,Design Model:111921 | A_BSUK_Roofs | New Construction | A-Roofs::A_BSUK_Roofs
A-FloorsSlabs A_BSUK_Slabs | RL | 10 ,SHE-08.ROOF.dgn,Design Model:111935 | A_BSUK_Roofs | New Construction | A-Roofs::A_BSUK_Roofs
A-FloorsSlabs A_BSUK_Slabs | RL | 10 ,SHE-08.ROOF.dgn,Design Model:111946 | A_BSUK_Roofs | New Construction | A-Roofs::A_BSUK_Roofs
A-FloorsSlabs A_BSUK_Slabs | RL | 10 ,SHE-08.ROOF.dgn,Design Model:111960 | A_BSUK_Roofs | New Construction | A-Roofs::A_BSUK_Roofs
A-FloorsSlabs A_BSUK_Slabs | RL | 10 ,SHE-08.ROOF.dgn,Design Model:111971 | A_BSUK_Roofs | New Construction | A-Roofs::A_BSUK_Roofs
A-FloorsSlabs A_BSUK_Slabs | RL | 10 ,SHE-08.ROOF.dgn,Design Model:111985 | A_BSUK_Roofs | New Construction | A-Roofs::A_BSUK_Roofs
A-FloorsSlabs A_BSUK_Slabs | RL | 10 ,SHE-08.ROOF.dgn,Design Model:111999 | A_BSUK_Roofs | New Construction | A-Roofs::A_BSUK_Roofs
A-FloorsSlabs A_BSUK_Slabs | RL | 10 ,SHE-08.ROOF.dgn,Design Model:112010 | A_BSUK_Roofs | New Construction | A-Roofs::A_BSUK_Roofs
A-FloorsSlabs A_BSUK_Slabs | RL | 10 ,SHE-08.ROOF.dgn,Design Model:112024 | A_BSUK_Roofs | New Construction | A-Roofs::A_BSUK_Roofs
A-FloorsSlabs A_BSUK_Slabs | RL | 10 ,SHE-08.ROOF.dgn,Design Model:112035 | A_BSUK_Roofs | New Construction | A-Roofs::A_BSUK_Roofs
A-FloorsSlabs A_BSUK_Slabs | RL | 18mm MAGPLY Deck :10,SHE-08.ROOF.dgn,Design Model:105266 | A_BSUK_Timber_Miscellaneous | New Construction | A-FrameElements::A_BSUK_Timber_Miscellaneous | Identification - ID | Description: 18mm MAGPLY Deck
A-FloorsSlabs A_BSUK_Slabs | RL | 10 ,SHE-08.ROOF.dgn,Design Model:105267 | A_BSUK_Roofs |  | A-Roofs::A_BSUK_Roofs
A-FloorsSlabs A_BSUK_Slabs | RL | 10 ,SHE-08.ROOF.dgn,Design Model:105290 | A_BSUK_Roofs |  | A-Roofs::A_BSUK_Roofs
A-FloorsSlabs A_BSUK_Slabs | RL | 10 ,SHE-08.ROOF.dgn,Design Model:105302 | A_BSUK_Roofs |  | A-Roofs::A_BSUK_Roofs
A-FloorsSlabs A_BSUK_Slabs | RL | 10 ,SHE-08.ROOF.dgn,Design Model:105314 | A_BSUK_Roofs |  | A-Roofs::A_BSUK_Roofs
A-FloorsSlabs A_BSUK_Slabs | RL | 10 ,SHE-08.ROOF.dgn,Design Model:105315 | A_BSUK_Roofs | New Construction | A-Roofs::A_BSUK_Roofs
A-FloorsSlabs A_BSUK_Slabs | RL | 10 ,SHE-08.ROOF.dgn,Design Model:105894 | A_BSUK_Roofs | New Construction | A-Roofs::A_BSUK_Roofs
A-FloorsSlabs A_BSUK_Slabs | RL | 10 ,SHE-08.ROOF.dgn,Design Model:109358 | A_BSUK_Roofs | New Construction | A-Roofs::A_BSUK_Roofs
A-FloorsSlabs A_BSUK_Slabs | RL | 10 ,SHE-08.ROOF.dgn,Design Model:109477 | A_BSUK_Roofs | New Construction | A-Roofs::A_BSUK_Roofs
A-FloorsSlabs A_BSUK_Slabs | RL | 10 ,SHE-08.ROOF.dgn,Design Model:109503 | A_BSUK_Roofs | New Construction | A-Roofs::A_BSUK_Roofs
A-FloorsSlabs A_BSUK_Slabs | RL | 10 ,SHE-08.ROOF.dgn,Design Model:109529 | A_BSUK_Roofs | New Construction | A-Roofs::A_BSUK_Roofs
A-FloorsSlabs A_BSUK_Slabs | RL | 10 ,SHE-08.ROOF.dgn,Design Model:109594 | A_BSUK_Roofs | New Construction | A-Roofs::A_BSUK_Roofs
A-FloorsSlabs A_BSUK_Slabs | RL | 10 ,SHE-08.ROOF.dgn,Design Model:109659 | A_BSUK_Roofs | New Construction | A-Roofs::A_BSUK_Roofs
A-FloorsSlabs A_BSUK_Slabs | RL | 10 ,SHE-08.ROOF.dgn,Design Model:109699 | A_BSUK_Roofs | New Construction | A-Roofs::A_BSUK_Roofs
A-FloorsSlabs A_BSUK_Slabs | RL | 10 ,SHE-08.ROOF.dgn,Design Model:109725 | A_BSUK_Roofs | New Construction | A-Roofs::A_BSUK_Roofs
A-FloorsSlabs A_BSUK_Slabs | RL | 10 ,SHE-08.ROOF.dgn,Design Model:109821 | A_BSUK_Roofs | New Construction | A-Roofs::A_BSUK_Roofs
A-FloorsSlabs A_BSUK_Slabs | RL | 10 ,SHE-08.ROOF.dgn,Design Model:109886 | A_BSUK_Roofs | New Construction | A-Roofs::A_BSUK_Roofs
A-FloorsSlabs A_BSUK_Slabs | RL | 10 ,SHE-08.ROOF.dgn,Design Model:109951 | A_BSUK_Roofs | New Construction | A-Roofs::A_BSUK_Roofs
A-FloorsSlabs A_BSUK_Slabs | RL | 10 ,SHE-08.ROOF.dgn,Design Model:109977 | A_BSUK_Roofs | New Construction | A-Roofs::A_BSUK_Roofs
A-FloorsSlabs A_BSUK_Slabs | RL | 10 ,SHE-08.ROOF.dgn,Design Model:110017 | A_BSUK_Roofs | New Construction | A-Roofs::A_BSUK_Roofs
A-FloorsSlabs A_BSUK_Slabs | RL | 10 ,SHE-08.ROOF.dgn,Design Model:110057 | A_BSUK_Roofs | New Construction | A-Roofs::A_BSUK_Roofs
A-FloorsSlabs A_BSUK_Slabs | RL | 10 ,SHE-08.ROOF.dgn,Design Model:110072 | A_BSUK_Roofs | New Construction | A-Roofs::A_BSUK_Roofs
A-FloorsSlabs A_BSUK_Slabs | RL | 10 ,SHE-08.ROOF.dgn,Design Model:111449 | A_BSUK_Roofs | New Construction | A-Roofs::A_BSUK_Roofs
A-FloorsSlabs A_BSUK_Slabs | RL | 335mm Mineral Wool :10,SHE-08.ROOF.dgn,Design Model:112126 | A_BSUK_ExpandedPolystyreneBoards | New Construction | A-FloorsSlabs::A_BSUK_ExpandedPolystyreneBoards | Identification - ID | Description: 335mm Mineral Wool
A-FloorsSlabs A_BSUK_Slabs | RL | 10 ,SHE-08.ROOF.dgn,Design Model:141076 | A_BSUK_Roofs | New Construction | A-Roofs::A_BSUK_Roofs
A-FloorsSlabs A_BSUK_Slabs | RL | 10 ,SHE-08.ROOF.dgn,Design Model:141231 | A_BSUK_Timber_Miscellaneous | New Construction | A-FrameElements::A_BSUK_Timber_Miscellaneous
A-FloorsSlabs A_BSUK_Slabs | RL | 10 ,SHE-08.ROOF.dgn,Design Model:141272 | A_BSUK_Insulation | New Construction | A-Walls::A_BSUK_Insulation
A-FloorsSlabs A_BSUK_Slabs | RL | 10 ,SHE-08.ROOF.dgn,Design Model:141313 | A_BSUK_Insulation | New Construction | A-Walls::A_BSUK_Insulation
A-FloorsSlabs A_BSUK_Slabs | RL | 10 ,SHE-08.ROOF.dgn,Design Model:142273 | A_BSUK_Roofs | New Construction | A-Roofs::A_BSUK_Roofs
A-FloorsSlabs A_BSUK_Slabs | RL | 10 ,SHE-08.ROOF.dgn,Design Model:142302 | A_BSUK_Timber_Miscellaneous | New Construction | A-FrameElements::A_BSUK_Timber_Miscellaneous
A-FloorsSlabs A_BSUK_Slabs | RL | 10 ,SHE-08.ROOF.dgn,Design Model:142317 | A_BSUK_Insulation | New Construction | A-Walls::A_BSUK_Insulation
A-FloorsSlabs A_BSUK_Slabs | RL | 10 ,SHE-08.ROOF.dgn,Design Model:142332 | A_BSUK_Insulation | New Construction | A-Walls::A_BSUK_Insulation
A-FloorsSlabs A_BSUK_Slabs | RL | 10 ,SHE-08.ROOF.dgn,Design Model:142712 | A_BSUK_Roofs | New Construction | A-Roofs::A_BSUK_Roofs
A-FloorsSlabs A_BSUK_Slabs | RL | 10 ,SHE-08.ROOF.dgn,Design Model:142741 | A_BSUK_Timber_Miscellaneous | New Construction | A-FrameElements::A_BSUK_Timber_Miscellaneous
A-FloorsSlabs A_BSUK_Slabs | RL | 10 ,SHE-08.ROOF.dgn,Design Model:142756 | A_BSUK_Insulation | New Construction | A-Walls::A_BSUK_Insulation
A-FloorsSlabs A_BSUK_Slabs | RL | 10 ,SHE-08.ROOF.dgn,Design Model:142771 | A_BSUK_Insulation | New Construction | A-Walls::A_BSUK_Insulation
A-FloorsSlabs A_BSUK_Slabs | RL | 10 ,SHE-08.ROOF.dgn,Design Model:143597 | A_BSUK_Roofs | New Construction | A-Roofs::A_BSUK_Roofs
A-FloorsSlabs A_BSUK_Slabs | RL | 10 ,SHE-08.ROOF.dgn,Design Model:143626 | A_BSUK_Timber_Miscellaneous | New Construction | A-FrameElements::A_BSUK_Timber_Miscellaneous
A-FloorsSlabs A_BSUK_Slabs | RL | 10 ,SHE-08.ROOF.dgn,Design Model:143641 | A_BSUK_Insulation | New Construction | A-Walls::A_BSUK_Insulation
A-FloorsSlabs A_BSUK_Slabs | RL | 10 ,SHE-08.ROOF.dgn,Design Model:143656 | A_BSUK_Insulation | New Construction | A-Walls::A_BSUK_Insulation
A-FloorsSlabs A_BSUK_Slabs | RL | 10 ,SHE-08.ROOF.dgn,Design Model:143717 | A_BSUK_Roofs | New Construction | A-Roofs::A_BSUK_Roofs
A-FloorsSlabs A_BSUK_Slabs | RL | 10 ,SHE-08.ROOF.dgn,Design Model:143746 | A_BSUK_Timber_Miscellaneous | New Construction | A-FrameElements::A_BSUK_Timber_Miscellaneous
A-FloorsSlabs A_BSUK_Slabs | RL | 10 ,SHE-08.ROOF.dgn,Design Model:143761 | A_BSUK_Insulation | New Construction | A-Walls::A_BSUK_Insulation
A-FloorsSlabs A_BSUK_Slabs | RL | 10 ,SHE-08.ROOF.dgn,Design Model:143776 | A_BSUK_Insulation | New Construction | A-Walls::A_BSUK_Insulation
A-FloorsSlabs A_BSUK_Slabs | RL | 10 ,SHE-08.ROOF.dgn,Design Model:143777 | A_BSUK_Roofs | New Construction | A-Roofs::A_BSUK_Roofs
A-FloorsSlabs A_BSUK_Slabs | RL | 10 ,SHE-08.ROOF.dgn,Design Model:143806 | A_BSUK_Timber_Miscellaneous | New Construction | A-FrameElements::A_BSUK_Timber_Miscellaneous
A-FloorsSlabs A_BSUK_Slabs | RL | 10 ,SHE-08.ROOF.dgn,Design Model:143821 | A_BSUK_Insulation | New Construction | A-Walls::A_BSUK_Insulation
A-FloorsSlabs A_BSUK_Slabs | RL | 10 ,SHE-08.ROOF.dgn,Design Model:143836 | A_BSUK_Insulation | New Construction | A-Walls::A_BSUK_Insulation
A-FloorsSlabs A_BSUK_Slabs | RL | 10 ,SHE-08.ROOF.dgn,Design Model:144669 | A_BSUK_Roofs | New Construction | A-Roofs::A_BSUK_Roofs
A-FloorsSlabs A_BSUK_Slabs | RL | 10 ,SHE-08.ROOF.dgn,Design Model:144698 | A_BSUK_Timber_Miscellaneous | New Construction | A-FrameElements::A_BSUK_Timber_Miscellaneous
A-FloorsSlabs A_BSUK_Slabs | RL | 10 ,SHE-08.ROOF.dgn,Design Model:144713 | A_BSUK_Insulation | New Construction | A-Walls::A_BSUK_Insulation
A-FloorsSlabs A_BSUK_Slabs | RL | 10 ,SHE-08.ROOF.dgn,Design Model:144728 | A_BSUK_Insulation | New Construction | A-Walls::A_BSUK_Insulation
A-FloorsSlabs A_BSUK_Slabs | RL | 10 ,SHE-08.ROOF.dgn,Design Model:144729 | A_BSUK_Roofs | New Construction | A-Roofs::A_BSUK_Roofs
A-FloorsSlabs A_BSUK_Slabs | RL | 10 ,SHE-08.ROOF.dgn,Design Model:144758 | A_BSUK_Timber_Miscellaneous | New Construction | A-FrameElements::A_BSUK_Timber_Miscellaneous
A-FloorsSlabs A_BSUK_Slabs | RL | 10 ,SHE-08.ROOF.dgn,Design Model:144773 | A_BSUK_Insulation | New Construction | A-Walls::A_BSUK_Insulation
A-FloorsSlabs A_BSUK_Slabs | RL | 10 ,SHE-08.ROOF.dgn,Design Model:144788 | A_BSUK_Insulation | New Construction | A-Walls::A_BSUK_Insulation
A-FloorsSlabs A_BSUK_Slabs | RL | 10 ,SHE-08.ROOF.dgn,Design Model:145175 | A_BSUK_Roofs | New Construction | A-Roofs::A_BSUK_Roofs
A-FloorsSlabs A_BSUK_Slabs | RL | 10 ,SHE-08.ROOF.dgn,Design Model:145204 | A_BSUK_Timber_Miscellaneous | New Construction | A-FrameElements::A_BSUK_Timber_Miscellaneous
A-FloorsSlabs A_BSUK_Slabs | RL | 10 ,SHE-08.ROOF.dgn,Design Model:145219 | A_BSUK_Insulation | New Construction | A-Walls::A_BSUK_Insulation
A-FloorsSlabs A_BSUK_Slabs | RL | 10 ,SHE-08.ROOF.dgn,Design Model:145234 | A_BSUK_Insulation | New Construction | A-Walls::A_BSUK_Insulation
A-FloorsSlabs A_BSUK_Slabs | RL | 10 ,SHE-08.ROOF.dgn,Design Model:145235 | A_BSUK_Roofs | New Construction | A-Roofs::A_BSUK_Roofs
A-FloorsSlabs A_BSUK_Slabs | RL | 10 ,SHE-08.ROOF.dgn,Design Model:145270 | A_BSUK_Timber_Miscellaneous | New Construction | A-FrameElements::A_BSUK_Timber_Miscellaneous
A-FloorsSlabs A_BSUK_Slabs | RL | 10 ,SHE-08.ROOF.dgn,Design Model:145288 | A_BSUK_Insulation | New Construction | A-Walls::A_BSUK_Insulation
A-FloorsSlabs A_BSUK_Slabs | RL | 10 ,SHE-08.ROOF.dgn,Design Model:145306 | A_BSUK_Insulation | New Construction | A-Walls::A_BSUK_Insulation
A-FloorsSlabs A_BSUK_Slabs | RL | 10 ,SHE-08.ROOF.dgn,Design Model:145307 | A_BSUK_Roofs | New Construction | A-Roofs::A_BSUK_Roofs
A-FloorsSlabs A_BSUK_Slabs | RL | 10 ,SHE-08.ROOF.dgn,Design Model:145342 | A_BSUK_Timber_Miscellaneous | New Construction | A-FrameElements::A_BSUK_Timber_Miscellaneous
A-FloorsSlabs A_BSUK_Slabs | RL | 10 ,SHE-08.ROOF.dgn,Design Model:145360 | A_BSUK_Insulation | New Construction | A-Walls::A_BSUK_Insulation
A-FloorsSlabs A_BSUK_Slabs | RL | 10 ,SHE-08.ROOF.dgn,Design Model:145378 | A_BSUK_Insulation | New Construction | A-Walls::A_BSUK_Insulation
A-FloorsSlabs A_BSUK_Slabs | RL | 10 ,SHE-08.ROOF.dgn,Design Model:145895 | A_BSUK_Roofs | New Construction | A-Roofs::A_BSUK_Roofs
A-FloorsSlabs A_BSUK_Slabs | RL | 10 ,SHE-08.ROOF.dgn,Design Model:145924 | A_BSUK_Timber_Miscellaneous | New Construction | A-FrameElements::A_BSUK_Timber_Miscellaneous
A-FloorsSlabs A_BSUK_Slabs | RL | 10 ,SHE-08.ROOF.dgn,Design Model:145939 | A_BSUK_Insulation | New Construction | A-Walls::A_BSUK_Insulation
A-FloorsSlabs A_BSUK_Slabs | RL | 10 ,SHE-08.ROOF.dgn,Design Model:145954 | A_BSUK_Insulation | New Construction | A-Walls::A_BSUK_Insulation
A-FloorsSlabs A_BSUK_Slabs | RL | 10 ,SHE-08.ROOF.dgn,Design Model:145955 | A_BSUK_Roofs | New Construction | A-Roofs::A_BSUK_Roofs
A-FloorsSlabs A_BSUK_Slabs | RL | 10 ,SHE-08.ROOF.dgn,Design Model:145984 | A_BSUK_Timber_Miscellaneous | New Construction | A-FrameElements::A_BSUK_Timber_Miscellaneous
A-FloorsSlabs A_BSUK_Slabs | RL | 10 ,SHE-08.ROOF.dgn,Design Model:145999 | A_BSUK_Insulation | New Construction | A-Walls::A_BSUK_Insulation
A-FloorsSlabs A_BSUK_Slabs | RL | 10 ,SHE-08.ROOF.dgn,Design Model:146014 | A_BSUK_Insulation | New Construction | A-Walls::A_BSUK_Insulation
A-FloorsSlabs A_BSUK_Slabs | RL | 10 ,SHE-08.ROOF.dgn,Design Model:146015 | A_BSUK_Roofs | New Construction | A-Roofs::A_BSUK_Roofs
A-FloorsSlabs A_BSUK_Slabs | RL | 10 ,SHE-08.ROOF.dgn,Design Model:146044 | A_BSUK_Timber_Miscellaneous | New Construction | A-FrameElements::A_BSUK_Timber_Miscellaneous
A-FloorsSlabs A_BSUK_Slabs | RL | 10 ,SHE-08.ROOF.dgn,Design Model:146059 | A_BSUK_Insulation | New Construction | A-Walls::A_BSUK_Insulation
A-FloorsSlabs A_BSUK_Slabs | RL | 10 ,SHE-08.ROOF.dgn,Design Model:146074 | A_BSUK_Insulation | New Construction | A-Walls::A_BSUK_Insulation
A-FloorsSlabs A_BSUK_Slabs | RL | 10 ,SHE-08.ROOF.dgn,Design Model:146387 | A_BSUK_Roofs | New Construction | A-Roofs::A_BSUK_Roofs
A-FloorsSlabs A_BSUK_Slabs | RL | 10 ,SHE-08.ROOF.dgn,Design Model:146416 | A_BSUK_Timber_Miscellaneous | New Construction | A-FrameElements::A_BSUK_Timber_Miscellaneous
A-FloorsSlabs A_BSUK_Slabs | RL | 10 ,SHE-08.ROOF.dgn,Design Model:146431 | A_BSUK_Insulation | New Construction | A-Walls::A_BSUK_Insulation
A-FloorsSlabs A_BSUK_Slabs | RL | 10 ,SHE-08.ROOF.dgn,Design Model:146446 | A_BSUK_Insulation | New Construction | A-Walls::A_BSUK_Insulation
A-FloorsSlabs A_BSUK_Slabs | RL | 10 ,SHE-08.ROOF.dgn,Design Model:146447 | A_BSUK_Roofs | New Construction | A-Roofs::A_BSUK_Roofs
A-FloorsSlabs A_BSUK_Slabs | RL | 10 ,SHE-08.ROOF.dgn,Design Model:146482 | A_BSUK_Timber_Miscellaneous | New Construction | A-FrameElements::A_BSUK_Timber_Miscellaneous
A-FloorsSlabs A_BSUK_Slabs | RL | 10 ,SHE-08.ROOF.dgn,Design Model:146500 | A_BSUK_Insulation | New Construction | A-Walls::A_BSUK_Insulation
A-FloorsSlabs A_BSUK_Slabs | RL | 10 ,SHE-08.ROOF.dgn,Design Model:146518 | A_BSUK_Insulation | New Construction | A-Walls::A_BSUK_Insulation
A-FloorsSlabs A_BSUK_Slabs | RL | 10 ,SHE-08.ROOF.dgn,Design Model:146519 | A_BSUK_Roofs | New Construction | A-Roofs::A_BSUK_Roofs
A-FloorsSlabs A_BSUK_Slabs | RL | 10 ,SHE-08.ROOF.dgn,Design Model:146554 | A_BSUK_Timber_Miscellaneous | New Construction | A-FrameElements::A_BSUK_Timber_Miscellaneous
A-FloorsSlabs A_BSUK_Slabs | RL | 10 ,SHE-08.ROOF.dgn,Design Model:146572 | A_BSUK_Insulation | New Construction | A-Walls::A_BSUK_Insulation
A-FloorsSlabs A_BSUK_Slabs | RL | 10 ,SHE-08.ROOF.dgn,Design Model:146590 | A_BSUK_Insulation | New Construction | A-Walls::A_BSUK_Insulation
A-FloorsSlabs A_BSUK_Slabs | RL | 10 ,SHE-08.ROOF.dgn,Design Model:146818 | A_BSUK_Roofs | New Construction | A-Roofs::A_BSUK_Roofs
A-FloorsSlabs A_BSUK_Slabs | RL | 10 ,SHE-08.ROOF.dgn,Design Model:146847 | A_BSUK_Timber_Miscellaneous | New Construction | A-FrameElements::A_BSUK_Timber_Miscellaneous
A-FloorsSlabs A_BSUK_Slabs | RL | 10 ,SHE-08.ROOF.dgn,Design Model:146862 | A_BSUK_Insulation | New Construction | A-Walls::A_BSUK_Insulation
A-FloorsSlabs A_BSUK_Slabs | RL | 10 ,SHE-08.ROOF.dgn,Design Model:146877 | A_BSUK_Insulation | New Construction | A-Walls::A_BSUK_Insulation
A-FloorsSlabs A_BSUK_Slabs | RL | 10 ,SHE-08.ROOF.dgn,Design Model:146878 | A_BSUK_Roofs | New Construction | A-Roofs::A_BSUK_Roofs
A-FloorsSlabs A_BSUK_Slabs | RL | 10 ,SHE-08.ROOF.dgn,Design Model:146913 | A_BSUK_Timber_Miscellaneous | New Construction | A-FrameElements::A_BSUK_Timber_Miscellaneous
A-FloorsSlabs A_BSUK_Slabs | RL | 10 ,SHE-08.ROOF.dgn,Design Model:146931 | A_BSUK_Insulation | New Construction | A-Walls::A_BSUK_Insulation
A-FloorsSlabs A_BSUK_Slabs | RL | 10 ,SHE-08.ROOF.dgn,Design Model:146949 | A_BSUK_Insulation | New Construction | A-Walls::A_BSUK_Insulation
A-FloorsSlabs A_BSUK_Slabs | RL | 10 ,SHE-08.ROOF.dgn,Design Model:146950 | A_BSUK_Roofs | New Construction | A-Roofs::A_BSUK_Roofs
A-FloorsSlabs A_BSUK_Slabs | RL | 10 ,SHE-08.ROOF.dgn,Design Model:146985 | A_BSUK_Timber_Miscellaneous | New Construction | A-FrameElements::A_BSUK_Timber_Miscellaneous
A-FloorsSlabs A_BSUK_Slabs | RL | 10 ,SHE-08.ROOF.dgn,Design Model:147003 | A_BSUK_Insulation | New Construction | A-Walls::A_BSUK_Insulation
A-FloorsSlabs A_BSUK_Slabs | RL | 10 ,SHE-08.ROOF.dgn,Design Model:147021 | A_BSUK_Insulation | New Construction | A-Walls::A_BSUK_Insulation
A-FloorsSlabs A_BSUK_Slabs | RL | 10 ,SHE-08.ROOF.dgn,Design Model:147203 | A_BSUK_Roofs | New Construction | A-Roofs::A_BSUK_Roofs
A-FloorsSlabs A_BSUK_Slabs | RL | 10 ,SHE-08.ROOF.dgn,Design Model:147232 | A_BSUK_Timber_Miscellaneous | New Construction | A-FrameElements::A_BSUK_Timber_Miscellaneous
A-FloorsSlabs A_BSUK_Slabs | RL | 10 ,SHE-08.ROOF.dgn,Design Model:147247 | A_BSUK_Insulation | New Construction | A-Walls::A_BSUK_Insulation
A-FloorsSlabs A_BSUK_Slabs | RL | 10 ,SHE-08.ROOF.dgn,Design Model:147262 | A_BSUK_Insulation | New Construction | A-Walls::A_BSUK_Insulation
A-FloorsSlabs A_BSUK_Slabs | RL | 10 ,SHE-08.ROOF.dgn,Design Model:150196 | A_BSUK_Timber_Miscellaneous | New Construction | A-FrameElements::A_BSUK_Timber_Miscellaneous
A-FloorsSlabs A_BSUK_Slabs | RL | 10 ,SHE-08.ROOF.dgn,Design Model:150211 | A_BSUK_Insulation | New Construction | A-Walls::A_BSUK_Insulation
A-FloorsSlabs A_BSUK_Slabs | RL | 10 ,SHE-08.ROOF.dgn,Design Model:150226 | A_BSUK_Insulation | New Construction | A-Walls::A_BSUK_Insulation
A-FloorsSlabs A_BSUK_Slabs | RL | 10 ,SHE-08.ROOF.dgn,Design Model:150227 | A_BSUK_Roofs | New Construction | A-Roofs::A_BSUK_Roofs
A-FloorsSlabs A_BSUK_Slabs | RL | 10 ,SHE-08.ROOF.dgn,Design Model:155153 | A_BSUK_Roofs | New Construction | A-Roofs::A_BSUK_Roofs
A-FloorsSlabs A_BSUK_Slabs | RL | 10 ,SHE-08.ROOF.dgn,Design Model:155188 | A_BSUK_Timber_Miscellaneous | New Construction | A-FrameElements::A_BSUK_Timber_Miscellaneous
A-FloorsSlabs A_BSUK_Slabs | RL | 10 ,SHE-08.ROOF.dgn,Design Model:155206 | A_BSUK_Insulation | New Construction | A-Walls::A_BSUK_Insulation
A-FloorsSlabs A_BSUK_Slabs | RL | 10 ,SHE-08.ROOF.dgn,Design Model:155224 | A_BSUK_Insulation | New Construction | A-Walls::A_BSUK_Insulation
A-FloorsSlabs A_BSUK_Slabs | RL | 10 ,SHE-08.ROOF.dgn,Design Model:155226 | A_BSUK_Roofs | New Construction | A-Roofs::A_BSUK_Roofs
A-FloorsSlabs A_BSUK_Slabs | RL | 10 ,SHE-08.ROOF.dgn,Design Model:155267 | A_BSUK_Timber_Miscellaneous | New Construction | A-FrameElements::A_BSUK_Timber_Miscellaneous
A-FloorsSlabs A_BSUK_Slabs | RL | 10 ,SHE-08.ROOF.dgn,Design Model:155288 | A_BSUK_Insulation | New Construction | A-Walls::A_BSUK_Insulation
A-FloorsSlabs A_BSUK_Slabs | RL | 10 ,SHE-08.ROOF.dgn,Design Model:155309 | A_BSUK_Insulation | New Construction | A-Walls::A_BSUK_Insulation
A-FloorsSlabs A_BSUK_Slabs | RL | 10 ,SHE-08.ROOF.dgn,Design Model:156027 | A_BSUK_Roofs | New Construction | A-Roofs::A_BSUK_Roofs
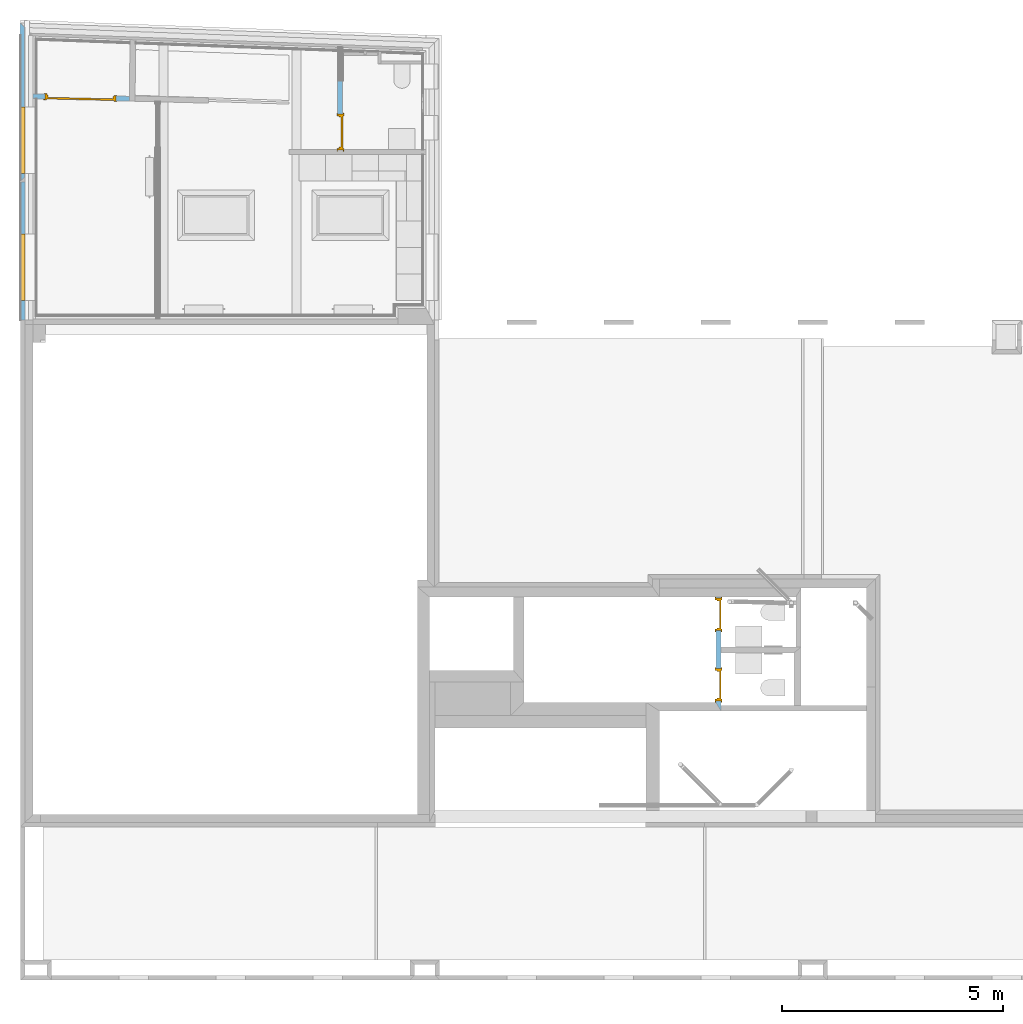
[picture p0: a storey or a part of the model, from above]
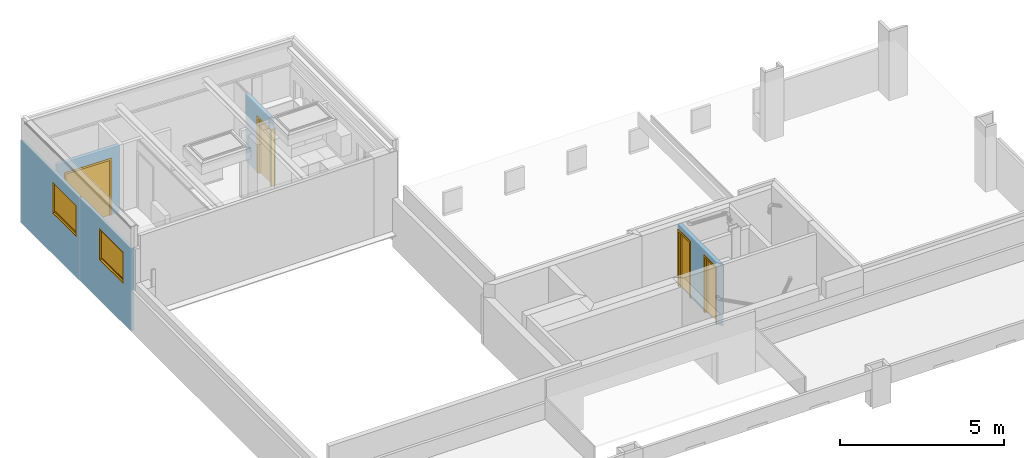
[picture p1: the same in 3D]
Properties of the parts of a building model (IFC2X3), part 13 of 17

# IfcSlab: A-FloorsSlabs A_BSUK_Slabs (1519)
Name | In | Description | Material | Phase | Part Definition
A-FloorsSlabs A_BSUK_Slabs | RL | 10 ,SHE-08.ROOF.dgn,Design Model:156062 | A_BSUK_Timber_Miscellaneous | New Construction | A-FrameElements::A_BSUK_Timber_Miscellaneous
A-FloorsSlabs A_BSUK_Slabs | RL | 10 ,SHE-08.ROOF.dgn,Design Model:156080 | A_BSUK_Insulation | New Construction | A-Walls::A_BSUK_Insulation
A-FloorsSlabs A_BSUK_Slabs | RL | 10 ,SHE-08.ROOF.dgn,Design Model:156098 | A_BSUK_Insulation | New Construction | A-Walls::A_BSUK_Insulation
A-FloorsSlabs A_BSUK_Slabs | RL | 10 ,SHE-08.ROOF.dgn,Design Model:156100 | A_BSUK_Roofs | New Construction | A-Roofs::A_BSUK_Roofs
A-FloorsSlabs A_BSUK_Slabs | RL | 10 ,SHE-08.ROOF.dgn,Design Model:156141 | A_BSUK_Timber_Miscellaneous | New Construction | A-FrameElements::A_BSUK_Timber_Miscellaneous
A-FloorsSlabs A_BSUK_Slabs | RL | 10 ,SHE-08.ROOF.dgn,Design Model:156162 | A_BSUK_Insulation | New Construction | A-Walls::A_BSUK_Insulation
A-FloorsSlabs A_BSUK_Slabs | RL | 10 ,SHE-08.ROOF.dgn,Design Model:156183 | A_BSUK_Insulation | New Construction | A-Walls::A_BSUK_Insulation
A-FloorsSlabs A_BSUK_Slabs | RL | 10 ,SHE-08.ROOF.dgn,Design Model:157331 | A_BSUK_Roofs | New Construction | A-Roofs::A_BSUK_Roofs
A-FloorsSlabs A_BSUK_Slabs | RL | 10 ,SHE-08.ROOF.dgn,Design Model:157366 | A_BSUK_Timber_Miscellaneous | New Construction | A-FrameElements::A_BSUK_Timber_Miscellaneous
A-FloorsSlabs A_BSUK_Slabs | RL | 10 ,SHE-08.ROOF.dgn,Design Model:157384 | A_BSUK_Insulation | New Construction | A-Walls::A_BSUK_Insulation
A-FloorsSlabs A_BSUK_Slabs | RL | 10 ,SHE-08.ROOF.dgn,Design Model:157402 | A_BSUK_Insulation | New Construction | A-Walls::A_BSUK_Insulation
A-FloorsSlabs A_BSUK_Slabs | RL | 10 ,SHE-08.ROOF.dgn,Design Model:157404 | A_BSUK_Roofs | New Construction | A-Roofs::A_BSUK_Roofs
A-FloorsSlabs A_BSUK_Slabs | RL | 10 ,SHE-08.ROOF.dgn,Design Model:157445 | A_BSUK_Timber_Miscellaneous | New Construction | A-FrameElements::A_BSUK_Timber_Miscellaneous
A-FloorsSlabs A_BSUK_Slabs | RL | 10 ,SHE-08.ROOF.dgn,Design Model:157466 | A_BSUK_Insulation | New Construction | A-Walls::A_BSUK_Insulation
A-FloorsSlabs A_BSUK_Slabs | RL | 10 ,SHE-08.ROOF.dgn,Design Model:157487 | A_BSUK_Insulation | New Construction | A-Walls::A_BSUK_Insulation
A-FloorsSlabs A_BSUK_Slabs | RL | 10 ,SHE-08.ROOF.dgn,Design Model:157488 | A_BSUK_Roofs | New Construction | A-Roofs::A_BSUK_Roofs
A-FloorsSlabs A_BSUK_Slabs | RL | 10 ,SHE-08.ROOF.dgn,Design Model:157523 | A_BSUK_Timber_Miscellaneous | New Construction | A-FrameElements::A_BSUK_Timber_Miscellaneous
A-FloorsSlabs A_BSUK_Slabs | RL | 10 ,SHE-08.ROOF.dgn,Design Model:157541 | A_BSUK_Insulation | New Construction | A-Walls::A_BSUK_Insulation
A-FloorsSlabs A_BSUK_Slabs | RL | 10 ,SHE-08.ROOF.dgn,Design Model:157559 | A_BSUK_Insulation | New Construction | A-Walls::A_BSUK_Insulation
A-FloorsSlabs A_BSUK_Slabs | RL | 10 ,SHE-08.ROOF.dgn,Design Model:157561 | A_BSUK_Roofs | New Construction | A-Roofs::A_BSUK_Roofs
A-FloorsSlabs A_BSUK_Slabs | RL | 10 ,SHE-08.ROOF.dgn,Design Model:157602 | A_BSUK_Timber_Miscellaneous | New Construction | A-FrameElements::A_BSUK_Timber_Miscellaneous
A-FloorsSlabs A_BSUK_Slabs | RL | 10 ,SHE-08.ROOF.dgn,Design Model:157623 | A_BSUK_Insulation | New Construction | A-Walls::A_BSUK_Insulation
A-FloorsSlabs A_BSUK_Slabs | RL | 10 ,SHE-08.ROOF.dgn,Design Model:157644 | A_BSUK_Insulation | New Construction | A-Walls::A_BSUK_Insulation
A-FloorsSlabs A_BSUK_Slabs | RL | 10 ,SHE-08.ROOF.dgn,Design Model:158205 | A_BSUK_Roofs | New Construction | A-Roofs::A_BSUK_Roofs
A-FloorsSlabs A_BSUK_Slabs | RL | 10 ,SHE-08.ROOF.dgn,Design Model:158240 | A_BSUK_Timber_Miscellaneous | New Construction | A-FrameElements::A_BSUK_Timber_Miscellaneous
A-FloorsSlabs A_BSUK_Slabs | RL | 10 ,SHE-08.ROOF.dgn,Design Model:158258 | A_BSUK_Insulation | New Construction | A-Walls::A_BSUK_Insulation
A-FloorsSlabs A_BSUK_Slabs | RL | 10 ,SHE-08.ROOF.dgn,Design Model:158276 | A_BSUK_Insulation | New Construction | A-Walls::A_BSUK_Insulation
A-FloorsSlabs A_BSUK_Slabs | RL | 10 ,SHE-08.ROOF.dgn,Design Model:158278 | A_BSUK_Roofs | New Construction | A-Roofs::A_BSUK_Roofs
A-FloorsSlabs A_BSUK_Slabs | RL | 10 ,SHE-08.ROOF.dgn,Design Model:158319 | A_BSUK_Timber_Miscellaneous | New Construction | A-FrameElements::A_BSUK_Timber_Miscellaneous
A-FloorsSlabs A_BSUK_Slabs | RL | 10 ,SHE-08.ROOF.dgn,Design Model:158340 | A_BSUK_Insulation | New Construction | A-Walls::A_BSUK_Insulation
A-FloorsSlabs A_BSUK_Slabs | RL | 10 ,SHE-08.ROOF.dgn,Design Model:158361 | A_BSUK_Insulation | New Construction | A-Walls::A_BSUK_Insulation
A-FloorsSlabs A_BSUK_Slabs | RL | 10 ,SHE-08.ROOF.dgn,Design Model:158362 | A_BSUK_Roofs | New Construction | A-Roofs::A_BSUK_Roofs
A-FloorsSlabs A_BSUK_Slabs | RL | 10 ,SHE-08.ROOF.dgn,Design Model:158397 | A_BSUK_Timber_Miscellaneous | New Construction | A-FrameElements::A_BSUK_Timber_Miscellaneous
A-FloorsSlabs A_BSUK_Slabs | RL | 10 ,SHE-08.ROOF.dgn,Design Model:158415 | A_BSUK_Insulation | New Construction | A-Walls::A_BSUK_Insulation
A-FloorsSlabs A_BSUK_Slabs | RL | 10 ,SHE-08.ROOF.dgn,Design Model:158433 | A_BSUK_Insulation | New Construction | A-Walls::A_BSUK_Insulation
A-FloorsSlabs A_BSUK_Slabs | RL | 10 ,SHE-08.ROOF.dgn,Design Model:158435 | A_BSUK_Roofs | New Construction | A-Roofs::A_BSUK_Roofs
A-FloorsSlabs A_BSUK_Slabs | RL | 10 ,SHE-08.ROOF.dgn,Design Model:158476 | A_BSUK_Timber_Miscellaneous | New Construction | A-FrameElements::A_BSUK_Timber_Miscellaneous
A-FloorsSlabs A_BSUK_Slabs | RL | 10 ,SHE-08.ROOF.dgn,Design Model:158497 | A_BSUK_Insulation | New Construction | A-Walls::A_BSUK_Insulation
A-FloorsSlabs A_BSUK_Slabs | RL | 10 ,SHE-08.ROOF.dgn,Design Model:158518 | A_BSUK_Insulation | New Construction | A-Walls::A_BSUK_Insulation
A-FloorsSlabs A_BSUK_Slabs | RL | 10 ,SHE-08.ROOF.dgn,Design Model:158519 | A_BSUK_Roofs | New Construction | A-Roofs::A_BSUK_Roofs
A-FloorsSlabs A_BSUK_Slabs | RL | 10 ,SHE-08.ROOF.dgn,Design Model:158554 | A_BSUK_Timber_Miscellaneous | New Construction | A-FrameElements::A_BSUK_Timber_Miscellaneous
A-FloorsSlabs A_BSUK_Slabs | RL | 10 ,SHE-08.ROOF.dgn,Design Model:158572 | A_BSUK_Insulation | New Construction | A-Walls::A_BSUK_Insulation
A-FloorsSlabs A_BSUK_Slabs | RL | 10 ,SHE-08.ROOF.dgn,Design Model:158590 | A_BSUK_Insulation | New Construction | A-Walls::A_BSUK_Insulation
A-FloorsSlabs A_BSUK_Slabs | RL | 10 ,SHE-08.ROOF.dgn,Design Model:158592 | A_BSUK_Roofs | New Construction | A-Roofs::A_BSUK_Roofs
A-FloorsSlabs A_BSUK_Slabs | RL | 10 ,SHE-08.ROOF.dgn,Design Model:158633 | A_BSUK_Timber_Miscellaneous | New Construction | A-FrameElements::A_BSUK_Timber_Miscellaneous
A-FloorsSlabs A_BSUK_Slabs | RL | 10 ,SHE-08.ROOF.dgn,Design Model:158654 | A_BSUK_Insulation | New Construction | A-Walls::A_BSUK_Insulation
A-FloorsSlabs A_BSUK_Slabs | RL | 10 ,SHE-08.ROOF.dgn,Design Model:158675 | A_BSUK_Insulation | New Construction | A-Walls::A_BSUK_Insulation
A-FloorsSlabs A_BSUK_Slabs | RL | 10 ,SHE-08.ROOF.dgn,Design Model:158676 | A_BSUK_Roofs | New Construction | A-Roofs::A_BSUK_Roofs
A-FloorsSlabs A_BSUK_Slabs | RL | 10 ,SHE-08.ROOF.dgn,Design Model:158711 | A_BSUK_Timber_Miscellaneous | New Construction | A-FrameElements::A_BSUK_Timber_Miscellaneous
A-FloorsSlabs A_BSUK_Slabs | RL | 10 ,SHE-08.ROOF.dgn,Design Model:158729 | A_BSUK_Insulation | New Construction | A-Walls::A_BSUK_Insulation
A-FloorsSlabs A_BSUK_Slabs | RL | 10 ,SHE-08.ROOF.dgn,Design Model:158747 | A_BSUK_Insulation | New Construction | A-Walls::A_BSUK_Insulation
A-FloorsSlabs A_BSUK_Slabs | RL | 10 ,SHE-08.ROOF.dgn,Design Model:158749 | A_BSUK_Roofs | New Construction | A-Roofs::A_BSUK_Roofs
A-FloorsSlabs A_BSUK_Slabs | RL | 10 ,SHE-08.ROOF.dgn,Design Model:158790 | A_BSUK_Timber_Miscellaneous | New Construction | A-FrameElements::A_BSUK_Timber_Miscellaneous
A-FloorsSlabs A_BSUK_Slabs | RL | 10 ,SHE-08.ROOF.dgn,Design Model:158811 | A_BSUK_Insulation | New Construction | A-Walls::A_BSUK_Insulation
A-FloorsSlabs A_BSUK_Slabs | RL | 10 ,SHE-08.ROOF.dgn,Design Model:158832 | A_BSUK_Insulation | New Construction | A-Walls::A_BSUK_Insulation
A-FloorsSlabs A_BSUK_Slabs | RL | 4.2mm Capping sheet :10,SHE-08.ROOF.dgn,Design Model:264476 | A_BSUK_InternalFinishes_FloorFloorboard | New Construction | A-FloorsSlabs::A_BSUK_InternalFinishes_FloorFloorboard | Identification - ID | Description: 4.2mm Capping sheet
A-FloorsSlabs A_BSUK_Slabs | GF | 15 ,SHE-14.BALCONY.dgn,Design Model:168902 | A_BSUK_StainlessSteelRailingSystems | New Construction | A-Finishes::A_BSUK_StainlessSteelRailingSystems
A-FloorsSlabs A_BSUK_Slabs | GF | 15 ,SHE-14.BALCONY.dgn,Design Model:169208 | A_BSUK_StainlessSteelRailingSystems | New Construction | A-Finishes::A_BSUK_StainlessSteelRailingSystems
A-FloorsSlabs A_BSUK_Slabs | GF | 15 ,SHE-14.BALCONY.dgn,Design Model:174220 | A_BSUK_StainlessSteelRailingSystems | New Construction | A-Finishes::A_BSUK_StainlessSteelRailingSystems
A-FloorsSlabs A_BSUK_Slabs | GF | 15 ,SHE-14.BALCONY.dgn,Design Model:174221 | A_BSUK_StainlessSteelRailingSystems | New Construction | A-Finishes::A_BSUK_StainlessSteelRailingSystems
A-FloorsSlabs A_BSUK_Slabs | GF | 15 ,SHE-14.BALCONY.dgn,Design Model:174278 | A_BSUK_StainlessSteelRailingSystems | New Construction | A-Finishes::A_BSUK_StainlessSteelRailingSystems
A-FloorsSlabs A_BSUK_Slabs | GF | 15 ,SHE-14.BALCONY.dgn,Design Model:174279 | A_BSUK_StainlessSteelRailingSystems | New Construction | A-Finishes::A_BSUK_StainlessSteelRailingSystems
A-FloorsSlabs A_BSUK_Slabs | GF | 16 ,SHE-12.STAIR.dgn,Design Model:224343 | A_BSUK_Slabs | Existing to Remain
A-FloorsSlabs A_BSUK_Slabs | GF | 16 ,SHE-12.STAIR.dgn,Design Model:220521 | A_BSUK_Slabs | Existing to Remain
A-FloorsSlabs A_BSUK_Slabs | GF | 16 ,SHE-12.STAIR.dgn,Design Model:220523 | A_BSUK_Slabs | Existing to Remain
A-FloorsSlabs A_BSUK_Slabs | 2F | shelving - bath :18,SHE-04.SECOND.dgn,Design Model:142164 | A_BSUK_Ceramic_WallTiles | New Construction | A-Finishes::A_BSUK_Ceramic_WallTiles | Identification - ID | Description: shelving - bath
A-FloorsSlabs A_BSUK_Slabs | 2F | shelving - bath :18,SHE-04.SECOND.dgn,Design Model:142179 | A_BSUK_Ceramic_WallTiles | New Construction | A-Finishes::A_BSUK_Ceramic_WallTiles | Identification - ID | Description: shelving - bath
A-FloorsSlabs A_BSUK_Slabs | 2F | shelving - bath :18,SHE-04.SECOND.dgn,Design Model:142194 | A_BSUK_Ceramic_WallTiles | New Construction | A-Finishes::A_BSUK_Ceramic_WallTiles | Identification - ID | Description: shelving - bath
A-FloorsSlabs A_BSUK_Slabs | 2F | shelving - bath :18,SHE-04.SECOND.dgn,Design Model:300477 | A_BSUK_Ceramic_WallTiles | New Construction | A-Finishes::A_BSUK_Ceramic_WallTiles | Identification - ID | Description: shelving - bath
A-FloorsSlabs A_BSUK_Slabs | 2F | shelving - bath :18,SHE-04.SECOND.dgn,Design Model:300491 | A_BSUK_Ceramic_WallTiles | New Construction | A-Finishes::A_BSUK_Ceramic_WallTiles | Identification - ID | Description: shelving - bath
A-FloorsSlabs A_BSUK_Slabs | 2F | shelving - bath :18,SHE-04.SECOND.dgn,Design Model:300505 | A_BSUK_Ceramic_WallTiles | New Construction | A-Finishes::A_BSUK_Ceramic_WallTiles | Identification - ID | Description: shelving - bath
A-FloorsSlabs A_BSUK_Slabs | 2F | shelving - bath :18,SHE-04.SECOND.dgn,Design Model:327204 | A_BSUK_Ceramic_WallTiles | New Construction | A-Finishes::A_BSUK_Ceramic_WallTiles | Identification - ID | Description: shelving - bath
A-FloorsSlabs A_BSUK_Slabs | 2F | 18 ,SHE-04.SECOND.dgn,Design Model:134765 | A_BSUK_CeilingSoffitFinishes_Suspended | New Construction | A-Ceilings::A_BSUK_CeilingSoffitFinishes_Suspended | Fire Resistance - Fire | Rating: FD60
A-FloorsSlabs A_BSUK_Slabs | 2F | 18 ,SHE-04.SECOND.dgn,Design Model:134792 | A_BSUK_CeilingSoffitFinishes_Suspended | New Construction | A-Ceilings::A_BSUK_CeilingSoffitFinishes_Suspended | Fire Resistance - Fire | Rating: FD60
A-FloorsSlabs A_BSUK_Slabs | 2F | 18 ,SHE-04.SECOND.dgn,Design Model:134816 | A_BSUK_CeilingSoffitFinishes_Suspended | New Construction | A-Ceilings::A_BSUK_CeilingSoffitFinishes_Suspended | Fire Resistance - Fire | Rating: FD60
A-FloorsSlabs A_BSUK_Slabs | 2F | 18 ,SHE-04.SECOND.dgn,Design Model:134859 | A_BSUK_InternalFinishes_FloorScreed | New Construction | A-FloorsSlabs::A_BSUK_InternalFinishes_FloorScreed
A-FloorsSlabs A_BSUK_Slabs | 2F | 18 ,SHE-04.SECOND.dgn,Design Model:134860 | A_BSUK_InternalFinishes_FloorScreed | New Construction | A-FloorsSlabs::A_BSUK_InternalFinishes_FloorScreed
A-FloorsSlabs A_BSUK_Slabs | 2F | 18 ,SHE-04.SECOND.dgn,Design Model:135695 | A_BSUK_Ceramic_WallTiles | New Construction | A-Finishes::A_BSUK_Ceramic_WallTiles
A-FloorsSlabs A_BSUK_Slabs | 2F | 18 ,SHE-04.SECOND.dgn,Design Model:135710 | A_BSUK_Ceramic_WallTiles | New Construction | A-Finishes::A_BSUK_Ceramic_WallTiles
A-FloorsSlabs A_BSUK_Slabs | 2F | 18 ,SHE-04.SECOND.dgn,Design Model:135725 | A_BSUK_Ceramic_WallTiles | New Construction | A-Finishes::A_BSUK_Ceramic_WallTiles
A-FloorsSlabs A_BSUK_Slabs | 2F | 18 ,SHE-04.SECOND.dgn,Design Model:135770 | A_BSUK_Ceramic_WallTiles | New Construction | A-Finishes::A_BSUK_Ceramic_WallTiles
A-FloorsSlabs A_BSUK_Slabs | 2F | 18 ,SHE-04.SECOND.dgn,Design Model:142049 | A_BSUK_InternalFinishes_FloorScreed | Existing to Remain | A-FloorsSlabs::A_BSUK_InternalFinishes_FloorScreed
A-FloorsSlabs A_BSUK_Slabs | 2F | 18 ,SHE-04.SECOND.dgn,Design Model:143321 | A_BSUK_Ceramic_WallTiles | New Construction | A-Finishes::A_BSUK_Ceramic_WallTiles
A-FloorsSlabs A_BSUK_Slabs | 2F | 18 ,SHE-04.SECOND.dgn,Design Model:143864 | A_BSUK_ExpandedPolystyreneBoards | New Construction | A-FloorsSlabs::A_BSUK_ExpandedPolystyreneBoards
A-FloorsSlabs A_BSUK_Slabs | 2F | 18 ,SHE-04.SECOND.dgn,Design Model:143891 | A_BSUK_ExpandedPolystyreneBoards | New Construction | A-FloorsSlabs::A_BSUK_ExpandedPolystyreneBoards
A-FloorsSlabs A_BSUK_Slabs | 2F | 18 ,SHE-04.SECOND.dgn,Design Model:143969 | A_BSUK_ExpandedPolystyreneBoards | New Construction | A-FloorsSlabs::A_BSUK_ExpandedPolystyreneBoards
A-FloorsSlabs A_BSUK_Slabs | 2F | 18 ,SHE-04.SECOND.dgn,Design Model:144064 | A_BSUK_ExpandedPolystyreneBoards | New Construction | A-FloorsSlabs::A_BSUK_ExpandedPolystyreneBoards
A-FloorsSlabs A_BSUK_Slabs | 2F | 18 ,SHE-04.SECOND.dgn,Design Model:144148 | A_BSUK_ExpandedPolystyreneBoards | New Construction | A-FloorsSlabs::A_BSUK_ExpandedPolystyreneBoards
A-FloorsSlabs A_BSUK_Slabs | 2F | 18 ,SHE-04.SECOND.dgn,Design Model:144277 | A_BSUK_ExpandedPolystyreneBoards | New Construction | A-FloorsSlabs::A_BSUK_ExpandedPolystyreneBoards
A-FloorsSlabs A_BSUK_Slabs | 2F | 18 ,SHE-04.SECOND.dgn,Design Model:144370 | A_BSUK_ExpandedPolystyreneBoards | New Construction | A-FloorsSlabs::A_BSUK_ExpandedPolystyreneBoards
A-FloorsSlabs A_BSUK_Slabs | 2F | 18 ,SHE-04.SECOND.dgn,Design Model:144454 | A_BSUK_ExpandedPolystyreneBoards | New Construction | A-FloorsSlabs::A_BSUK_ExpandedPolystyreneBoards
A-FloorsSlabs A_BSUK_Slabs | 2F | 18 ,SHE-04.SECOND.dgn,Design Model:144538 | A_BSUK_ExpandedPolystyreneBoards | New Construction | A-FloorsSlabs::A_BSUK_ExpandedPolystyreneBoards
A-FloorsSlabs A_BSUK_Slabs | 2F | 18 ,SHE-04.SECOND.dgn,Design Model:144628 | A_BSUK_ExpandedPolystyreneBoards | New Construction | A-FloorsSlabs::A_BSUK_ExpandedPolystyreneBoards
A-FloorsSlabs A_BSUK_Slabs | 2F | 18 ,SHE-04.SECOND.dgn,Design Model:144629 | A_BSUK_Parquet_Floor |  | A-Finishes::A_BSUK_Parquet_Floor
A-FloorsSlabs A_BSUK_Slabs | 2F | 18 ,SHE-04.SECOND.dgn,Design Model:144740 | A_BSUK_Carpet-Pile | New Construction | A-Finishes::A_BSUK_Carpet-Pile
A-FloorsSlabs A_BSUK_Slabs | 2F | 18 ,SHE-04.SECOND.dgn,Design Model:144773 | A_BSUK_Ceramic_FloorTiles |  | A-Finishes::A_BSUK_Ceramic_FloorTiles
A-FloorsSlabs A_BSUK_Slabs | 2F | 18 ,SHE-04.SECOND.dgn,Design Model:144788 | A_BSUK_Parquet_Floor |  | A-Finishes::A_BSUK_Parquet_Floor
A-FloorsSlabs A_BSUK_Slabs | 2F | 18 ,SHE-04.SECOND.dgn,Design Model:144899 | A_BSUK_Parquet_Floor |  | A-Finishes::A_BSUK_Parquet_Floor
A-FloorsSlabs A_BSUK_Slabs | 2F | 18 ,SHE-04.SECOND.dgn,Design Model:144914 | A_BSUK_Carpet-Pile |  | A-Finishes::A_BSUK_Carpet-Pile
A-FloorsSlabs A_BSUK_Slabs | 2F | 18 ,SHE-04.SECOND.dgn,Design Model:144959 | A_BSUK_Ceramic_FloorTiles |  | A-Finishes::A_BSUK_Ceramic_FloorTiles
A-FloorsSlabs A_BSUK_Slabs | 2F | 18 ,SHE-04.SECOND.dgn,Design Model:144974 | A_BSUK_Parquet_Floor |  | A-Finishes::A_BSUK_Parquet_Floor
A-FloorsSlabs A_BSUK_Slabs | 2F | 18 ,SHE-04.SECOND.dgn,Design Model:145109 | A_BSUK_Ceramic_FloorTiles |  | A-Finishes::A_BSUK_Ceramic_FloorTiles
A-FloorsSlabs A_BSUK_Slabs | 2F | 18 ,SHE-04.SECOND.dgn,Design Model:145124 | A_BSUK_Carpet-Pile |  | A-Finishes::A_BSUK_Carpet-Pile
A-FloorsSlabs A_BSUK_Slabs | 2F | 18 ,SHE-04.SECOND.dgn,Design Model:145163 | A_BSUK_Carpet-Pile |  | A-Finishes::A_BSUK_Carpet-Pile
A-FloorsSlabs A_BSUK_Slabs | 2F | 18 ,SHE-04.SECOND.dgn,Design Model:145196 | A_BSUK_Parquet_Floor |  | A-Finishes::A_BSUK_Parquet_Floor
A-FloorsSlabs A_BSUK_Slabs | 2F | 18 ,SHE-04.SECOND.dgn,Design Model:145313 | A_BSUK_Ceramic_FloorTiles |  | A-Finishes::A_BSUK_Ceramic_FloorTiles
A-FloorsSlabs A_BSUK_Slabs | 2F | 18 ,SHE-04.SECOND.dgn,Design Model:145328 | A_BSUK_Parquet_Floor |  | A-Finishes::A_BSUK_Parquet_Floor
A-FloorsSlabs A_BSUK_Slabs | 2F | 18 ,SHE-04.SECOND.dgn,Design Model:145427 | A_BSUK_Ceramic_FloorTiles |  | A-Finishes::A_BSUK_Ceramic_FloorTiles
A-FloorsSlabs A_BSUK_Slabs | 2F | 18 ,SHE-04.SECOND.dgn,Design Model:145448 | A_BSUK_Carpet-Pile |  | A-Finishes::A_BSUK_Carpet-Pile
A-FloorsSlabs A_BSUK_Slabs | 2F | 18 ,SHE-04.SECOND.dgn,Design Model:145631 | A_BSUK_Parquet_Floor |  | A-Finishes::A_BSUK_Parquet_Floor
A-FloorsSlabs A_BSUK_Slabs | 2F | 18 ,SHE-04.SECOND.dgn,Design Model:145632 | A_BSUK_Ceramic_FloorTiles |  | A-Finishes::A_BSUK_Ceramic_FloorTiles
A-FloorsSlabs A_BSUK_Slabs | 2F | 18 ,SHE-04.SECOND.dgn,Design Model:145633 | A_BSUK_Carpet-Pile |  | A-Finishes::A_BSUK_Carpet-Pile
A-FloorsSlabs A_BSUK_Slabs | 2F | 18 ,SHE-04.SECOND.dgn,Design Model:145634 | A_BSUK_Parquet_Floor |  | A-Finishes::A_BSUK_Parquet_Floor
A-FloorsSlabs A_BSUK_Slabs | 2F | 18 ,SHE-04.SECOND.dgn,Design Model:145739 | A_BSUK_Ceramic_FloorTiles |  | A-Finishes::A_BSUK_Ceramic_FloorTiles
A-FloorsSlabs A_BSUK_Slabs | 2F | 18 ,SHE-04.SECOND.dgn,Design Model:145754 | A_BSUK_Carpet-Pile | New Construction | A-Finishes::A_BSUK_Carpet-Pile
A-FloorsSlabs A_BSUK_Slabs | 2F | 18 ,SHE-04.SECOND.dgn,Design Model:145787 | A_BSUK_Carpet-Pile |  | A-Finishes::A_BSUK_Carpet-Pile
A-FloorsSlabs A_BSUK_Slabs | 2F | 18 ,SHE-04.SECOND.dgn,Design Model:145826 | A_BSUK_Carpet-Pile |  | A-Finishes::A_BSUK_Carpet-Pile
A-FloorsSlabs A_BSUK_Slabs | 2F | 18 ,SHE-04.SECOND.dgn,Design Model:145862 | A_BSUK_Carpet-Pile |  | A-Finishes::A_BSUK_Carpet-Pile
A-FloorsSlabs A_BSUK_Slabs | 2F | 18 ,SHE-04.SECOND.dgn,Design Model:145967 | A_BSUK_Carpet-Pile |  | A-Finishes::A_BSUK_Carpet-Pile
A-FloorsSlabs A_BSUK_Slabs | 2F | 18 ,SHE-04.SECOND.dgn,Design Model:154694 | A_BSUK_CeilingSoffitFinishes_Suspended | New Construction | A-Ceilings::A_BSUK_CeilingSoffitFinishes_Suspended
A-FloorsSlabs A_BSUK_Slabs | 2F | 18 ,SHE-04.SECOND.dgn,Design Model:154742 | A_BSUK_CeilingSoffitFinishes_Suspended |  | A-Ceilings::A_BSUK_CeilingSoffitFinishes_Suspended
A-FloorsSlabs A_BSUK_Slabs | 2F | 18 ,SHE-04.SECOND.dgn,Design Model:155063 | A_BSUK_CeilingSoffitFinishes_Suspended |  | A-Ceilings::A_BSUK_CeilingSoffitFinishes_Suspended
A-FloorsSlabs A_BSUK_Slabs | 2F | 18 ,SHE-04.SECOND.dgn,Design Model:155064 | A_BSUK_CeilingSoffitFinishes_Suspended | New Construction | A-Ceilings::A_BSUK_CeilingSoffitFinishes_Suspended
A-FloorsSlabs A_BSUK_Slabs | 2F | 18 ,SHE-04.SECOND.dgn,Design Model:155065 | A_BSUK_CeilingSoffitFinishes_Suspended |  | A-Ceilings::A_BSUK_CeilingSoffitFinishes_Suspended
A-FloorsSlabs A_BSUK_Slabs | 2F | 18 ,SHE-04.SECOND.dgn,Design Model:155066 | A_BSUK_CeilingSoffitFinishes_Suspended |  | A-Ceilings::A_BSUK_CeilingSoffitFinishes_Suspended
A-FloorsSlabs A_BSUK_Slabs | 2F | 18 ,SHE-04.SECOND.dgn,Design Model:155067 | A_BSUK_CeilingSoffitFinishes_Suspended |  | A-Ceilings::A_BSUK_CeilingSoffitFinishes_Suspended
A-FloorsSlabs A_BSUK_Slabs | 2F | 18 ,SHE-04.SECOND.dgn,Design Model:155068 | A_BSUK_CeilingSoffitFinishes_Suspended |  | A-Ceilings::A_BSUK_CeilingSoffitFinishes_Suspended
A-FloorsSlabs A_BSUK_Slabs | 2F | 18 ,SHE-04.SECOND.dgn,Design Model:155069 | A_BSUK_CeilingSoffitFinishes_Suspended |  | A-Ceilings::A_BSUK_CeilingSoffitFinishes_Suspended
A-FloorsSlabs A_BSUK_Slabs | 2F | 18 ,SHE-04.SECOND.dgn,Design Model:155084 | A_BSUK_CeilingSoffitFinishes_Suspended |  | A-Ceilings::A_BSUK_CeilingSoffitFinishes_Suspended
A-FloorsSlabs A_BSUK_Slabs | 2F | 18 ,SHE-04.SECOND.dgn,Design Model:155099 | A_BSUK_CeilingSoffitFinishes_Suspended |  | A-Ceilings::A_BSUK_CeilingSoffitFinishes_Suspended
A-FloorsSlabs A_BSUK_Slabs | 2F | 18 ,SHE-04.SECOND.dgn,Design Model:155370 | A_BSUK_CeilingSoffitFinishes_Suspended |  | A-Ceilings::A_BSUK_CeilingSoffitFinishes_Suspended
A-FloorsSlabs A_BSUK_Slabs | 2F | 18 ,SHE-04.SECOND.dgn,Design Model:155371 | A_BSUK_CeilingSoffitFinishes_Suspended |  | A-Ceilings::A_BSUK_CeilingSoffitFinishes_Suspended
A-FloorsSlabs A_BSUK_Slabs | 2F | 18 ,SHE-04.SECOND.dgn,Design Model:155619 | A_BSUK_CeilingSoffitFinishes_Suspended | New Construction | A-Ceilings::A_BSUK_CeilingSoffitFinishes_Suspended
A-FloorsSlabs A_BSUK_Slabs | 2F | 18 ,SHE-04.SECOND.dgn,Design Model:155620 | A_BSUK_CeilingSoffitFinishes_Suspended |  | A-Ceilings::A_BSUK_CeilingSoffitFinishes_Suspended
A-FloorsSlabs A_BSUK_Slabs | 2F | 18 ,SHE-04.SECOND.dgn,Design Model:155621 | A_BSUK_CeilingSoffitFinishes_Suspended | New Construction | A-Ceilings::A_BSUK_CeilingSoffitFinishes_Suspended
A-FloorsSlabs A_BSUK_Slabs | 2F | 18 ,SHE-04.SECOND.dgn,Design Model:155622 | A_BSUK_CeilingSoffitFinishes_Suspended | New Construction | A-Ceilings::A_BSUK_CeilingSoffitFinishes_Suspended
A-FloorsSlabs A_BSUK_Slabs | 2F | 18 ,SHE-04.SECOND.dgn,Design Model:155623 | A_BSUK_CeilingSoffitFinishes_Suspended | New Construction | A-Ceilings::A_BSUK_CeilingSoffitFinishes_Suspended
A-FloorsSlabs A_BSUK_Slabs | 2F | 18 ,SHE-04.SECOND.dgn,Design Model:155624 | A_BSUK_CeilingSoffitFinishes_Suspended |  | A-Ceilings::A_BSUK_CeilingSoffitFinishes_Suspended
A-FloorsSlabs A_BSUK_Slabs | 2F | 18 ,SHE-04.SECOND.dgn,Design Model:155626 | A_BSUK_CeilingSoffitFinishes_Suspended | New Construction | A-Ceilings::A_BSUK_CeilingSoffitFinishes_Suspended
A-FloorsSlabs A_BSUK_Slabs | 2F | 18 ,SHE-04.SECOND.dgn,Design Model:220881 | A_BSUK_CeilingSoffitFinishes_Suspended |  | A-Ceilings::A_BSUK_CeilingSoffitFinishes_Suspended
A-FloorsSlabs A_BSUK_Slabs | 2F | 18 ,SHE-04.SECOND.dgn,Design Model:220882 | A_BSUK_CeilingSoffitFinishes_Suspended | New Construction | A-Ceilings::A_BSUK_CeilingSoffitFinishes_Suspended
A-FloorsSlabs A_BSUK_Slabs | 2F | 18 ,SHE-04.SECOND.dgn,Design Model:220883 | A_BSUK_CeilingSoffitFinishes_Suspended | New Construction | A-Ceilings::A_BSUK_CeilingSoffitFinishes_Suspended
A-FloorsSlabs A_BSUK_Slabs | 2F | 18 ,SHE-04.SECOND.dgn,Design Model:229439 | A_BSUK_Ceramic_WallTiles | New Construction | A-Finishes::A_BSUK_Ceramic_WallTiles
A-FloorsSlabs A_BSUK_Slabs | 2F | 18 ,SHE-04.SECOND.dgn,Design Model:232461 | A_BSUK_Ceramic_FloorTiles |  | A-Finishes::A_BSUK_Ceramic_FloorTiles
A-FloorsSlabs A_BSUK_Slabs | 2F | 18 ,SHE-04.SECOND.dgn,Design Model:270352 | A_BSUK_Ceramic_WallTiles | New Construction | A-Finishes::A_BSUK_Ceramic_WallTiles
A-FloorsSlabs A_BSUK_Slabs | 2F | 18 ,SHE-04.SECOND.dgn,Design Model:270751 | A_BSUK_Ceramic_WallTiles | New Construction | A-Finishes::A_BSUK_Ceramic_WallTiles
A-FloorsSlabs A_BSUK_Slabs | 2F | shelving - bath :18,SHE-04.SECOND.dgn,Design Model:277457 | A_BSUK_Ceramic_WallTiles | New Construction | A-Finishes::A_BSUK_Ceramic_WallTiles | Identification - ID | Description: shelving - bath
A-FloorsSlabs A_BSUK_Slabs | 2F | shelving - bath :18,SHE-04.SECOND.dgn,Design Model:280881 | A_BSUK_Ceramic_WallTiles | New Construction | A-Finishes::A_BSUK_Ceramic_WallTiles | Identification - ID | Description: shelving - bath
A-FloorsSlabs A_BSUK_Slabs | 2F | 18 ,SHE-04.SECOND.dgn,Design Model:282366 | A_BSUK_Ceramic_WallTiles | New Construction | A-Finishes::A_BSUK_Ceramic_WallTiles
A-FloorsSlabs A_BSUK_Slabs | 2F | fire board - ceiling :18,SHE-04.SECOND.dgn,Design Model:385538 | A_BSUK_CeilingSoffitFinishes_Suspended | New Construction | A-Ceilings::A_BSUK_CeilingSoffitFinishes_Suspended | Identification - ID | Description: fire board - ceiling
A-FloorsSlabs A_BSUK_Slabs | 2F | fire board - ceiling :18,SHE-04.SECOND.dgn,Design Model:385553 | A_BSUK_CeilingSoffitFinishes_Suspended | New Construction | A-Ceilings::A_BSUK_CeilingSoffitFinishes_Suspended | Identification - ID | Description: fire board - ceiling
A-FloorsSlabs A_BSUK_Slabs | 2F | fire board - ceiling :18,SHE-04.SECOND.dgn,Design Model:385568 | A_BSUK_CeilingSoffitFinishes_Suspended | New Construction | A-Ceilings::A_BSUK_CeilingSoffitFinishes_Suspended | Identification - ID | Description: fire board - ceiling
A-FloorsSlabs A_BSUK_Slabs | 2F | fire board - ceiling :18,SHE-04.SECOND.dgn,Design Model:385583 | A_BSUK_CeilingSoffitFinishes_Suspended | New Construction | A-Ceilings::A_BSUK_CeilingSoffitFinishes_Suspended | Identification - ID | Description: fire board - ceiling
A-FloorsSlabs A_BSUK_Slabs | 2F | fire board - ceiling :18,SHE-04.SECOND.dgn,Design Model:385598 | A_BSUK_CeilingSoffitFinishes_Suspended | New Construction | A-Ceilings::A_BSUK_CeilingSoffitFinishes_Suspended | Identification - ID | Description: fire board - ceiling
A-FloorsSlabs A_BSUK_Slabs | 2F | fire board - ceiling :18,SHE-04.SECOND.dgn,Design Model:385627 | A_BSUK_CeilingSoffitFinishes_Suspended | New Construction | A-Ceilings::A_BSUK_CeilingSoffitFinishes_Suspended | Identification - ID | Description: fire board - ceiling
A-FloorsSlabs A_BSUK_Slabs | 2F | fire board - ceiling :18,SHE-04.SECOND.dgn,Design Model:385628 | A_BSUK_CeilingSoffitFinishes_Suspended | New Construction | A-Ceilings::A_BSUK_CeilingSoffitFinishes_Suspended | Identification - ID | Description: fire board - ceiling
A-FloorsSlabs A_BSUK_Slabs | 2F | fire board - ceiling :18,SHE-04.SECOND.dgn,Design Model:385643 | A_BSUK_CeilingSoffitFinishes_Suspended | New Construction | A-Ceilings::A_BSUK_CeilingSoffitFinishes_Suspended | Identification - ID | Description: fire board - ceiling
A-FloorsSlabs A_BSUK_Slabs | 2F | fire board - ceiling :18,SHE-04.SECOND.dgn,Design Model:385658 | A_BSUK_CeilingSoffitFinishes_Suspended | New Construction | A-Ceilings::A_BSUK_CeilingSoffitFinishes_Suspended | Identification - ID | Description: fire board - ceiling
A-FloorsSlabs A_BSUK_Slabs | 2F | fire board - ceiling :18,SHE-04.SECOND.dgn,Design Model:385673 | A_BSUK_CeilingSoffitFinishes_Suspended | New Construction | A-Ceilings::A_BSUK_CeilingSoffitFinishes_Suspended | Identification - ID | Description: fire board - ceiling
A-FloorsSlabs A_BSUK_Slabs | 2F | fire board - ceiling :18,SHE-04.SECOND.dgn,Design Model:385688 | A_BSUK_CeilingSoffitFinishes_Suspended | New Construction | A-Ceilings::A_BSUK_CeilingSoffitFinishes_Suspended | Identification - ID | Description: fire board - ceiling
A-FloorsSlabs A_BSUK_Slabs | 2F | fire board - ceiling :18,SHE-04.SECOND.dgn,Design Model:385703 | A_BSUK_CeilingSoffitFinishes_Suspended | New Construction | A-Ceilings::A_BSUK_CeilingSoffitFinishes_Suspended | Identification - ID | Description: fire board - ceiling
A-FloorsSlabs A_BSUK_Slabs | 2F | fire board - ceiling :18,SHE-04.SECOND.dgn,Design Model:385718 | A_BSUK_CeilingSoffitFinishes_Suspended | New Construction | A-Ceilings::A_BSUK_CeilingSoffitFinishes_Suspended | Identification - ID | Description: fire board - ceiling
A-FloorsSlabs A_BSUK_Slabs | 2F | fire board - ceiling :18,SHE-04.SECOND.dgn,Design Model:385733 | A_BSUK_CeilingSoffitFinishes_Suspended | New Construction | A-Ceilings::A_BSUK_CeilingSoffitFinishes_Suspended | Identification - ID | Description: fire board - ceiling
A-FloorsSlabs A_BSUK_Slabs | 2F | fire board - ceiling :18,SHE-04.SECOND.dgn,Design Model:385748 | A_BSUK_CeilingSoffitFinishes_Suspended | New Construction | A-Ceilings::A_BSUK_CeilingSoffitFinishes_Suspended | Identification - ID | Description: fire board - ceiling
A-FloorsSlabs A_BSUK_Slabs | 2F | fire board - ceiling :18,SHE-04.SECOND.dgn,Design Model:385777 | A_BSUK_CeilingSoffitFinishes_Suspended | New Construction | A-Ceilings::A_BSUK_CeilingSoffitFinishes_Suspended | Identification - ID | Description: fire board - ceiling
A-FloorsSlabs A_BSUK_Slabs | 2F | fire board - ceiling :18,SHE-04.SECOND.dgn,Design Model:385778 | A_BSUK_CeilingSoffitFinishes_Suspended | New Construction | A-Ceilings::A_BSUK_CeilingSoffitFinishes_Suspended | Identification - ID | Description: fire board - ceiling
A-FloorsSlabs A_BSUK_Slabs | 2F | fire board - ceiling :18,SHE-04.SECOND.dgn,Design Model:385793 | A_BSUK_CeilingSoffitFinishes_Suspended | New Construction | A-Ceilings::A_BSUK_CeilingSoffitFinishes_Suspended | Identification - ID | Description: fire board - ceiling
A-FloorsSlabs A_BSUK_Slabs | 2F | fire board - ceiling :18,SHE-04.SECOND.dgn,Design Model:385808 | A_BSUK_CeilingSoffitFinishes_Suspended | New Construction | A-Ceilings::A_BSUK_CeilingSoffitFinishes_Suspended | Identification - ID | Description: fire board - ceiling
A-FloorsSlabs A_BSUK_Slabs | 2F | fire board - ceiling :18,SHE-04.SECOND.dgn,Design Model:385823 | A_BSUK_CeilingSoffitFinishes_Suspended | New Construction | A-Ceilings::A_BSUK_CeilingSoffitFinishes_Suspended | Identification - ID | Description: fire board - ceiling

# IfcStair: S-Stairs-ConcreteRC (9)
In: GF
Material: S_BSUK_Stairs
Pset_StairCommon - FireExit: no; HandicapAccessible: no; HasNonSkidSurface: no; IsExternal: no
Thermal Transmittance - Is External: no; Is Below Grade: no
Stair Walkline - Walkline Offset Type: Custom
Stair Spiral - Inner Radius: 0 m; Sweep Angle: 0 deg
Stair Parameters - Monolithic Part Definition: S-Circulation::S_BSUK_Stairs; Stair Part Definition: S-Circulation::S_BSUK_Stairs; Riser Type: <none>; Riser Thickness: 0.02 m; Riser Tread Relationship: Riser Behind Tread; Begin With Riser: yes; End With Riser: no; Riser Part Definition: S-Circulation::S_BSUK_Stairs; Begin with Riser at Landings: yes; End with Riser at Landings: yes; Base Riser Offset: 0 m; Top Riser Offset: 0 m; Minimum Inside Depth: 0.1 m; Tread Type: Plane; Tread Thickness: 0.03 m; Tread Nosing Distance: 0.025 m; Tread Nosing Profile: <none>; Tread Part Definition: S-Circulation::S_BSUK_Stairs; Tread Nosing Radius/Chamfer: 0.015 m; Stringer Base Offset: 0 m; Stringer Top Seat Offset: 0 m; Stringer Profile: UC203x203x60; Carriage Offset: 0.2 m; Carriage Inset: 0 m; Stringer Offset: 0.0459 m; Left Stringer Type: <none>; Right Stringer Type: <none>; Stringer Part Definition: S-Circulation::S_BSUK_Stairs; Base Profile: Horizontal; Base Seat Distance: 0 m; Base Extension Type: Vertical; Base Extension Distance: 0 m; Top Profile: Vertical; Top Seat Distance: 0 m; Top Extension Type: Horizontal; Top Extension Distance: 0 m; Top Trim Distance: 0.002 m; Monolithic: yes; Monolithic Underside Profile: Smooth; Landing Thickness: 0.2 m; Landing Stringer Offset: 0.0459 m; Landing Part Definition: S-Circulation::S_BSUK_Stairs; Extend Landing On Approach: no; Extend Landing On Departure: no; Fire Exit: no; Place of Refuge: no; Break Line: Slanted; Display Fire Escape Rounding: no; 2D-Display: Undefined; BreakLine Distance: 0.28 m; BreakLine Weight: 1; CenterLine: yes; Up Label: UP; Display Up Label: no; Display Up Start Point And Arrow: yes; Display Nosing: yes; Display Stair Numbers: no; Stair Number By: Tread Number; Stair Number Location: 30; Extend Up Down Arrows: no; Down Label: DN; Display Down Graphics: no; Display Down Label: no; Display Down Arrow: no
Stair Dimensions - Riser Recommended Number: 20
Quantities - Tread Volume: 0 m3; Riser Volume: 0 m3; Left Stringer Length: 0 m; Right Stringer Length: 0 m
Identification - ID | Description: Insitu reinforced concrete stairs
Discipline - Discipline: Structural
Construction Phase - Phase: Existing to Remain
Classification - Uniclass2015: Ss_35_10_85
Accessibility - Accessibility | Handicap Accessible: no; Has Non-skid Surface: no
Name | Description | NumberOfRiser = Riser Actual Number | RiserHeight (m) = Riser Actual Height (m) | TreadLength (m) = Tread Depth (m) | Walkline Offset (m) | Stair Width (m) | Riser Target Height (m) | Stair Height (m) | Stair Actual Slope | Number Of Treads | Tread Area (m2) | Riser Area (m2) | Landing Top Area (m2) = Landing Bottom Area (m2) | Landing Side Area (m2) | Landing Perimeter (m) | Landing Volume (m3)
S-Stairs-ConcreteRC | Insitu reinforced concrete stairs :1,SHE-01.GROUND.dgn,Design Model:95231 | 16 | 0.189812 | 0.254 | 0.54 | 1.08 | 0.19 | 3.037 | 36.770000 | 16 | 4.82112 | 3.30829 | 0 | 0 | 0 | 0
S-Stairs-ConcreteRC | Insitu reinforced concrete stairs :16,SHE-12.STAIR.dgn,Design Model:220524 | 6 | 0.175 | 0.28 | 0.525 | 1.1 | 0.175 | 1.05 | 32.01 | 6 | 1.815 | 1.16673 | 0 | 0 | 0 | 0
S-Stairs-ConcreteRC | Insitu reinforced concrete stairs :16,SHE-12.STAIR.dgn,Design Model:220549 | 14 | 0.185714 | 0.24 | 0.525 | 1.1 | 0.186 | 2.6 | 37.730000 | 13 | 3.7895 | 2.8858 | 1.21 | 0.88 | 4.4 | 0.242
S-Stairs-ConcreteRC | Insitu reinforced concrete stairs :16,SHE-12.STAIR.dgn,Design Model:220670 | 9 | 0.182222 | 0.25 | 0.525 | 1.1 | 0.185 | 1.64 | 36.090000 | 9 | 2.7225 | 1.8209 | 0 | 0 | 0 | 0
S-Stairs-ConcreteRC | Insitu reinforced concrete stairs :16,SHE-12.STAIR.dgn,Design Model:220701 | 10 | 0.185 | 0.25 | 0.525 | 1.1 | 0.185 | 1.85 | 36.500000 | 10 | 3.025 | 2.0535 | 0 | 0 | 0 | 0
S-Stairs-ConcreteRC | Insitu reinforced concrete stairs :16,SHE-12.STAIR.dgn,Design Model:223613 | 19 | 0.183684 | 0.25 | 0.55 | 1.1 | 1.84 | 3.49 | 36.310000 | 18 | 5.445 | 3.87439 | 2.52332 | 1.35884 | 6.7942 | 0.504665
S-Stairs-ConcreteRC | Insitu reinforced concrete stairs :16,SHE-12.STAIR.dgn,Design Model:224369 | 10 | 0.185 | 0.28 | 0.525 | 1.1 | 0.185 | 1.85 | 33.45 | 10 | 3.025 | 2.0535 | 0 | 0 | 0 | 0
S-Stairs-ConcreteRC | Insitu reinforced concrete stairs :16,SHE-12.STAIR.dgn,Design Model:224402 | 4 | 0.175 | 0.28 | 0.525 | 1.1 | 0.175 | 0.7 | 32.01 | 4 | 1.21 | 0.777817 | 0 | 0 | 0 | 0
S-Stairs-ConcreteRC | Insitu reinforced concrete stairs :16,SHE-12.STAIR.dgn,Design Model:230112 | 10 | 0.1775 | 0.25 | 0.525 | 1.1 | 0.185 | 1.775 | 36.500000 | 10 | 3.025 | 1.97177 | 0 | 0 | 0 | 0

# IfcSystem (9)
Name | Description
SVP | SVP,Parameters.System ID
RW | RW,Parameters.System ID
SVP3 | SVP3 ,Parameters.System ID
SVP3-4-5 | SVP3-4-5 ,Parameters.System ID
SVP3-4-5-6 | SVP3-4-5-6 ,Parameters.System ID
SVP1 | SVP1 ,Parameters.System ID
EXT. Flat | EXT. Flat ,Parameters.System ID
EXT. AOV | EXT. AOV ,Parameters.System ID
DRM | DRM,Parameters.System ID

# IfcTransportElement: A-Ladder-withCage
In: GF
Type - Parametric Definition - Parametric | File Type: PAZ; Parametric | File Name: Ladder_Cage
Type - Discipline - Discipline: Architectural
Type - Construction Phase - Phase: New Construction
Type - Classification - Uniclass2015: Pr_25_30_85
Description: 16,SHE-12.STAIR.dgn,Design Model:270175; CapacityByWeight: 0 g; CapacityByNumber: 0; Material: A_BSUK_OtherFfe

# IfcWall: A-Walls-ExternalBlock (79)
Type - Wall Parameters - Type: Wall; Compound Wall Assembly: no
Type - Thermal Transmittance - Is External: yes; Is Below Grade: no
Type - Structural Usage - Structural | Material: Blockwork
Type - Space Bounding - Is Space Bounding: yes
Type - Materials - Part Definition: A-Walls::A_BSUK_WallsExternal_Block
Type - LEED Parameters - LEED | Pre-consumer Recycled (%): 0; LEED | Regional Material: no; LEED | Post-consumer Recycled (%): 0
Type - Fire Resistance - Fire | IsCombustible: no; Fire | Compartmentation: no
Type - Discipline - Discipline: Architectural
Type - Classification - Uniclass2015: Pr_20_93_52_01
Pset_WallCommon - Combustible: no; Compartmentation: no; IsExternal: yes; LoadBearing: no
Name | In | Description | Material | ID | Description | ID | Notes | Phase | FireRating = Fire | Rating | Part Definition | ID | Number
A-Walls-ExternalBlock | MF | Wall existing :2,SHE-02.MEZZANINE.dgn,Design Model:93344 | A_BSUK_WallsExternal_Block | Wall existing | general | Existing to Remain
7C | 1F | SFSWall fire lining :7 ,SHE-06.FOURTH.dgn,Design Model:101092 | A_BSUK_Roofs | SFSWall fire lining | fire board - internal mansard roof finish | New Construction | F60 | A-Roofs::A_BSUK_Roofs | 7C
7C | 1F | SFSWall fire lining :7 ,SHE-06.FOURTH.dgn,Design Model:101101 | A_BSUK_Roofs | SFSWall fire lining | fire board - internal mansard roof finish | New Construction | F60 | A-Roofs::A_BSUK_Roofs | 7C
7C | 1F | SFSWall fire lining :7 ,SHE-06.FOURTH.dgn,Design Model:102985 | A_BSUK_Roofs | SFSWall fire lining | fire board - internal mansard roof finish | New Construction | F60 | A-Roofs::A_BSUK_Roofs | 7C
7C | 1F | SFSWall fire lining :7 ,SHE-06.FOURTH.dgn,Design Model:548345 | A_BSUK_Roofs | SFSWall fire lining | fire board - internal mansard roof finish | New Construction | F60 | A-Roofs::A_BSUK_Roofs | 7C
7C | 1F | SFSWall fire lining :7 ,SHE-06.FOURTH.dgn,Design Model:548354 | A_BSUK_Roofs | SFSWall fire lining | fire board - internal mansard roof finish | New Construction | F60 | A-Roofs::A_BSUK_Roofs | 7C
7C | 1F | SFSWall fire lining :7 ,SHE-06.FOURTH.dgn,Design Model:548363 | A_BSUK_Roofs | SFSWall fire lining | fire board - internal mansard roof finish | New Construction | F60 | A-Roofs::A_BSUK_Roofs | 7C
7C | 1F | SFSWall fire lining :7 ,SHE-06.FOURTH.dgn,Design Model:548372 | A_BSUK_Roofs | SFSWall fire lining | fire board - internal mansard roof finish | New Construction | F60 | A-Roofs::A_BSUK_Roofs | 7C
7C | 1F | SFSWall fire lining :7 ,SHE-06.FOURTH.dgn,Design Model:548381 | A_BSUK_Roofs | SFSWall fire lining | fire board - internal mansard roof finish | New Construction | F60 | A-Roofs::A_BSUK_Roofs | 7C
7C | 1F | SFSWall fire lining :7 ,SHE-06.FOURTH.dgn,Design Model:548390 | A_BSUK_Roofs | SFSWall fire lining | fire board - internal mansard roof finish | New Construction | F60 | A-Roofs::A_BSUK_Roofs | 7C
7C | 1F | SFSWall fire lining :7 ,SHE-06.FOURTH.dgn,Design Model:548399 | A_BSUK_Roofs | SFSWall fire lining | fire board - internal mansard roof finish | New Construction | F60 | A-Roofs::A_BSUK_Roofs | 7C
7C | 1F | SFSWall fire lining :7 ,SHE-06.FOURTH.dgn,Design Model:548408 | A_BSUK_Roofs | SFSWall fire lining | fire board - internal mansard roof finish | New Construction | F60 | A-Roofs::A_BSUK_Roofs | 7C
7C | 1F | SFSWall fire lining :7 ,SHE-06.FOURTH.dgn,Design Model:548417 | A_BSUK_Roofs | SFSWall fire lining | fire board - internal mansard roof finish | New Construction | F60 | A-Roofs::A_BSUK_Roofs | 7C
7C | 1F | SFSWall fire lining :7 ,SHE-06.FOURTH.dgn,Design Model:548426 | A_BSUK_Roofs | SFSWall fire lining | fire board - internal mansard roof finish | New Construction | F60 | A-Roofs::A_BSUK_Roofs | 7C
7C | 1F | SFSWall fire lining :7 ,SHE-06.FOURTH.dgn,Design Model:548435 | A_BSUK_Roofs | SFSWall fire lining | fire board - internal mansard roof finish | New Construction | F60 | A-Roofs::A_BSUK_Roofs | 7C
7C | 1F | SFSWall fire lining :7 ,SHE-06.FOURTH.dgn,Design Model:548444 | A_BSUK_Roofs | SFSWall fire lining | fire board - internal mansard roof finish | New Construction | F60 | A-Roofs::A_BSUK_Roofs | 7C
7C | 1F | SFSWall fire lining :7 ,SHE-06.FOURTH.dgn,Design Model:548453 | A_BSUK_Roofs | SFSWall fire lining | fire board - internal mansard roof finish | New Construction | F60 | A-Roofs::A_BSUK_Roofs | 7C
7C | 1F | SFSWall fire lining :7 ,SHE-06.FOURTH.dgn,Design Model:548462 | A_BSUK_Roofs | SFSWall fire lining | fire board - internal mansard roof finish | New Construction | F60 | A-Roofs::A_BSUK_Roofs | 7C
7C | 1F | SFSWall fire lining :7 ,SHE-06.FOURTH.dgn,Design Model:548471 | A_BSUK_Roofs | SFSWall fire lining | fire board - internal mansard roof finish | New Construction | F60 | A-Roofs::A_BSUK_Roofs | 7C
7C | 1F | SFSWall fire lining :7 ,SHE-06.FOURTH.dgn,Design Model:548480 | A_BSUK_Roofs | SFSWall fire lining | fire board - internal mansard roof finish | New Construction | F60 | A-Roofs::A_BSUK_Roofs | 7C
7C | 1F | SFSWall fire lining :7 ,SHE-06.FOURTH.dgn,Design Model:548489 | A_BSUK_Roofs | SFSWall fire lining | fire board - internal mansard roof finish | New Construction | F60 | A-Roofs::A_BSUK_Roofs | 7C
7C | 1F | SFSWall fire lining :7 ,SHE-06.FOURTH.dgn,Design Model:548498 | A_BSUK_Roofs | SFSWall fire lining | fire board - internal mansard roof finish | New Construction | F60 | A-Roofs::A_BSUK_Roofs | 7C
7C | 1F | SFSWall fire lining :7 ,SHE-06.FOURTH.dgn,Design Model:548507 | A_BSUK_Roofs | SFSWall fire lining | fire board - internal mansard roof finish | New Construction | F60 | A-Roofs::A_BSUK_Roofs | 7C
7C | 1F | SFSWall fire lining :7 ,SHE-06.FOURTH.dgn,Design Model:548516 | A_BSUK_Roofs | SFSWall fire lining | fire board - internal mansard roof finish | New Construction | F60 | A-Roofs::A_BSUK_Roofs | 7C
7C | 1F | SFSWall fire lining :7 ,SHE-06.FOURTH.dgn,Design Model:548525 | A_BSUK_Roofs | SFSWall fire lining | fire board - internal mansard roof finish | New Construction | F60 | A-Roofs::A_BSUK_Roofs | 7C
7C | 1F | SFSWall fire lining :7 ,SHE-06.FOURTH.dgn,Design Model:548534 | A_BSUK_Roofs | SFSWall fire lining | fire board - internal mansard roof finish | New Construction | F60 | A-Roofs::A_BSUK_Roofs | 7C
7C | 1F | SFSWall fire lining :7 ,SHE-06.FOURTH.dgn,Design Model:548543 | A_BSUK_Roofs | SFSWall fire lining | fire board - internal mansard roof finish | New Construction | F60 | A-Roofs::A_BSUK_Roofs | 7C
7C | 1F | SFSWall fire lining :7 ,SHE-06.FOURTH.dgn,Design Model:548552 | A_BSUK_Roofs | SFSWall fire lining | fire board - internal mansard roof finish | New Construction | F60 | A-Roofs::A_BSUK_Roofs | 7C
7C | 1F | SFSWall fire lining :7 ,SHE-06.FOURTH.dgn,Design Model:548561 | A_BSUK_Roofs | SFSWall fire lining | fire board - internal mansard roof finish | New Construction | F60 | A-Roofs::A_BSUK_Roofs | 7C
7C | 1F | SFSWall fire lining :7 ,SHE-06.FOURTH.dgn,Design Model:548570 | A_BSUK_Roofs | SFSWall fire lining | fire board - internal mansard roof finish | New Construction | F60 | A-Roofs::A_BSUK_Roofs | 7C
7C | 1F | SFSWall fire lining :7 ,SHE-06.FOURTH.dgn,Design Model:548579 | A_BSUK_Roofs | SFSWall fire lining | fire board - internal mansard roof finish | New Construction | F60 | A-Roofs::A_BSUK_Roofs | 7C
7C | 1F | SFSWall fire lining :7 ,SHE-06.FOURTH.dgn,Design Model:548588 | A_BSUK_Roofs | SFSWall fire lining | fire board - internal mansard roof finish | New Construction | F60 | A-Roofs::A_BSUK_Roofs | 7C
7C | 1F | SFSWall fire lining :7 ,SHE-06.FOURTH.dgn,Design Model:548597 | A_BSUK_Roofs | SFSWall fire lining | fire board - internal mansard roof finish | New Construction | F60 | A-Roofs::A_BSUK_Roofs | 7C
7C | 1F | SFSWall fire lining :7 ,SHE-06.FOURTH.dgn,Design Model:548606 | A_BSUK_Roofs | SFSWall fire lining | fire board - internal mansard roof finish | New Construction | F60 | A-Roofs::A_BSUK_Roofs | 7C
7C | 1F | SFSWall fire lining :7 ,SHE-06.FOURTH.dgn,Design Model:548615 | A_BSUK_Roofs | SFSWall fire lining | fire board - internal mansard roof finish | New Construction | F60 | A-Roofs::A_BSUK_Roofs | 7C
7C | 1F | SFSWall fire lining :7 ,SHE-06.FOURTH.dgn,Design Model:548624 | A_BSUK_Roofs | SFSWall fire lining | fire board - internal mansard roof finish | New Construction | F60 | A-Roofs::A_BSUK_Roofs | 7C
7C | 1F | SFSWall fire lining :7 ,SHE-06.FOURTH.dgn,Design Model:548633 | A_BSUK_Roofs | SFSWall fire lining | fire board - internal mansard roof finish | New Construction | F60 | A-Roofs::A_BSUK_Roofs | 7C
7C | 1F | SFSWall fire lining :7 ,SHE-06.FOURTH.dgn,Design Model:548642 | A_BSUK_Roofs | SFSWall fire lining | fire board - internal mansard roof finish | New Construction | F60 | A-Roofs::A_BSUK_Roofs | 7C
7C | 1F | SFSWall fire lining :7 ,SHE-06.FOURTH.dgn,Design Model:548651 | A_BSUK_Roofs | SFSWall fire lining | fire board - internal mansard roof finish | New Construction | F60 | A-Roofs::A_BSUK_Roofs | 7C
7C | 1F | SFSWall fire lining :7 ,SHE-06.FOURTH.dgn,Design Model:548660 | A_BSUK_Roofs | SFSWall fire lining | fire board - internal mansard roof finish | New Construction | F60 | A-Roofs::A_BSUK_Roofs | 7C
7C | 1F | SFSWall fire lining :7 ,SHE-06.FOURTH.dgn,Design Model:548669 | A_BSUK_Roofs | SFSWall fire lining | fire board - internal mansard roof finish | New Construction | F60 | A-Roofs::A_BSUK_Roofs | 7C
7C | 1F | SFSWall fire lining :7 ,SHE-06.FOURTH.dgn,Design Model:548678 | A_BSUK_Roofs | SFSWall fire lining | fire board - internal mansard roof finish | New Construction | F60 | A-Roofs::A_BSUK_Roofs | 7C
7C | 1F | SFSWall fire lining :7 ,SHE-06.FOURTH.dgn,Design Model:548687 | A_BSUK_Roofs | SFSWall fire lining | fire board - internal mansard roof finish | New Construction | F60 | A-Roofs::A_BSUK_Roofs | 7C
7C | 1F | SFSWall fire lining :7 ,SHE-06.FOURTH.dgn,Design Model:548696 | A_BSUK_Roofs | SFSWall fire lining | fire board - internal mansard roof finish | New Construction | F60 | A-Roofs::A_BSUK_Roofs | 7C
7C | 1F | SFSWall fire lining :7 ,SHE-06.FOURTH.dgn,Design Model:548705 | A_BSUK_Roofs | SFSWall fire lining | fire board - internal mansard roof finish | New Construction | F60 | A-Roofs::A_BSUK_Roofs | 7C
7C | 1F | SFSWall fire lining :7 ,SHE-06.FOURTH.dgn,Design Model:548714 | A_BSUK_Roofs | SFSWall fire lining | fire board - internal mansard roof finish | New Construction | F60 | A-Roofs::A_BSUK_Roofs | 7C
7C | 1F | SFSWall fire lining :7 ,SHE-06.FOURTH.dgn,Design Model:548723 | A_BSUK_Roofs | SFSWall fire lining | fire board - internal mansard roof finish | New Construction | F60 | A-Roofs::A_BSUK_Roofs | 7C
7C | 1F | SFSWall fire lining :7 ,SHE-06.FOURTH.dgn,Design Model:548732 | A_BSUK_Roofs | SFSWall fire lining | fire board - internal mansard roof finish | New Construction | F60 | A-Roofs::A_BSUK_Roofs | 7C
7C | 1F | SFSWall fire lining :7 ,SHE-06.FOURTH.dgn,Design Model:548741 | A_BSUK_Roofs | SFSWall fire lining | fire board - internal mansard roof finish | New Construction | F60 | A-Roofs::A_BSUK_Roofs | 7C
7C | 1F | SFSWall fire lining :7 ,SHE-06.FOURTH.dgn,Design Model:548750 | A_BSUK_Roofs | SFSWall fire lining | fire board - internal mansard roof finish | New Construction | F60 | A-Roofs::A_BSUK_Roofs | 7C
7C | 1F | SFSWall fire lining :7 ,SHE-06.FOURTH.dgn,Design Model:548759 | A_BSUK_Roofs | SFSWall fire lining | fire board - internal mansard roof finish | New Construction | F60 | A-Roofs::A_BSUK_Roofs | 7C
7C | 1F | SFSWall fire lining :7 ,SHE-06.FOURTH.dgn,Design Model:548768 | A_BSUK_Roofs | SFSWall fire lining | fire board - internal mansard roof finish | New Construction | F60 | A-Roofs::A_BSUK_Roofs | 7C
7C | 1F | SFSWall fire lining :7 ,SHE-06.FOURTH.dgn,Design Model:548777 | A_BSUK_Roofs | SFSWall fire lining | fire board - internal mansard roof finish | New Construction | F60 | A-Roofs::A_BSUK_Roofs | 7C
7C | 1F | SFSWall fire lining :7 ,SHE-06.FOURTH.dgn,Design Model:548786 | A_BSUK_Roofs | SFSWall fire lining | fire board - internal mansard roof finish | New Construction | F60 | A-Roofs::A_BSUK_Roofs | 7C
7C | 1F | SFSWall fire lining :7 ,SHE-06.FOURTH.dgn,Design Model:548795 | A_BSUK_Roofs | SFSWall fire lining | fire board - internal mansard roof finish | New Construction | F60 | A-Roofs::A_BSUK_Roofs | 7C
7C | 1F | SFSWall fire lining :7 ,SHE-06.FOURTH.dgn,Design Model:548804 | A_BSUK_Roofs | SFSWall fire lining | fire board - internal mansard roof finish | New Construction | F60 | A-Roofs::A_BSUK_Roofs | 7C
7C | 1F | SFSWall fire lining :7 ,SHE-06.FOURTH.dgn,Design Model:548813 | A_BSUK_Roofs | SFSWall fire lining | fire board - internal mansard roof finish | New Construction | F60 | A-Roofs::A_BSUK_Roofs | 7C
7C | 1F | SFSWall fire lining :7 ,SHE-06.FOURTH.dgn,Design Model:548822 | A_BSUK_Roofs | SFSWall fire lining | fire board - internal mansard roof finish | New Construction | F60 | A-Roofs::A_BSUK_Roofs | 7C
7C | 1F | SFSWall fire lining :7 ,SHE-06.FOURTH.dgn,Design Model:548831 | A_BSUK_Roofs | SFSWall fire lining | fire board - internal mansard roof finish | New Construction | F60 | A-Roofs::A_BSUK_Roofs | 7C
7C | 1F | SFSWall fire lining :7 ,SHE-06.FOURTH.dgn,Design Model:548840 | A_BSUK_Roofs | SFSWall fire lining | fire board - internal mansard roof finish | New Construction | F60 | A-Roofs::A_BSUK_Roofs | 7C
7C | 1F | SFSWall fire lining :7 ,SHE-06.FOURTH.dgn,Design Model:548849 | A_BSUK_Roofs | SFSWall fire lining | fire board - internal mansard roof finish | New Construction | F60 | A-Roofs::A_BSUK_Roofs | 7C
7C | 1F | SFSWall fire lining :7 ,SHE-06.FOURTH.dgn,Design Model:548858 | A_BSUK_Roofs | SFSWall fire lining | fire board - internal mansard roof finish | New Construction | F60 | A-Roofs::A_BSUK_Roofs | 7C
7C | 1F | SFSWall fire lining :7 ,SHE-06.FOURTH.dgn,Design Model:548867 | A_BSUK_Roofs | SFSWall fire lining | fire board - internal mansard roof finish | New Construction | F60 | A-Roofs::A_BSUK_Roofs | 7C
7C | 1F | SFSWall fire lining :7 ,SHE-06.FOURTH.dgn,Design Model:548876 | A_BSUK_Roofs | SFSWall fire lining | fire board - internal mansard roof finish | New Construction | F60 | A-Roofs::A_BSUK_Roofs | 7C
7C | 1F | SFSWall fire lining :7 ,SHE-06.FOURTH.dgn,Design Model:548885 | A_BSUK_Roofs | SFSWall fire lining | fire board - internal mansard roof finish | New Construction | F60 | A-Roofs::A_BSUK_Roofs | 7C
7C | 1F | SFSWall fire lining :7 ,SHE-06.FOURTH.dgn,Design Model:548894 | A_BSUK_Roofs | SFSWall fire lining | fire board - internal mansard roof finish | New Construction | F60 | A-Roofs::A_BSUK_Roofs | 7C
7C | 1F | SFSWall fire lining :7 ,SHE-06.FOURTH.dgn,Design Model:548903 | A_BSUK_Roofs | SFSWall fire lining | fire board - internal mansard roof finish | New Construction | F60 | A-Roofs::A_BSUK_Roofs | 7C
7C | 1F | SFSWall fire lining :7 ,SHE-06.FOURTH.dgn,Design Model:548912 | A_BSUK_Roofs | SFSWall fire lining | fire board - internal mansard roof finish | New Construction | F60 | A-Roofs::A_BSUK_Roofs | 7C
7C | 1F | SFSWall fire lining :7 ,SHE-06.FOURTH.dgn,Design Model:548921 | A_BSUK_Roofs | SFSWall fire lining | fire board - internal mansard roof finish | New Construction | F60 | A-Roofs::A_BSUK_Roofs | 7C
7C | 1F | SFSWall fire lining :7 ,SHE-06.FOURTH.dgn,Design Model:548930 | A_BSUK_Roofs | SFSWall fire lining | fire board - internal mansard roof finish | New Construction | F60 | A-Roofs::A_BSUK_Roofs | 7C
7C | 1F | SFSWall fire lining :7 ,SHE-06.FOURTH.dgn,Design Model:548939 | A_BSUK_Roofs | SFSWall fire lining | fire board - internal mansard roof finish | New Construction | F60 | A-Roofs::A_BSUK_Roofs | 7C
7C | 1F | SFSWall fire lining :7 ,SHE-06.FOURTH.dgn,Design Model:548948 | A_BSUK_Roofs | SFSWall fire lining | fire board - internal mansard roof finish | New Construction | F60 | A-Roofs::A_BSUK_Roofs | 7C
7C | 1F | SFSWall fire lining :7 ,SHE-06.FOURTH.dgn,Design Model:548957 | A_BSUK_Roofs | SFSWall fire lining | fire board - internal mansard roof finish | New Construction | F60 | A-Roofs::A_BSUK_Roofs | 7C
7C | 1F | SFSWall fire lining :7 ,SHE-06.FOURTH.dgn,Design Model:548966 | A_BSUK_Roofs | SFSWall fire lining | fire board - internal mansard roof finish | New Construction | F60 | A-Roofs::A_BSUK_Roofs | 7C
7C | 1F | SFSWall fire lining :7 ,SHE-06.FOURTH.dgn,Design Model:548975 | A_BSUK_Roofs | SFSWall fire lining | fire board - internal mansard roof finish | New Construction | F60 | A-Roofs::A_BSUK_Roofs | 7C
7C | 1F | SFSWall fire lining :7 ,SHE-06.FOURTH.dgn,Design Model:548984 | A_BSUK_Roofs | SFSWall fire lining | fire board - internal mansard roof finish | New Construction | F60 | A-Roofs::A_BSUK_Roofs | 7C
7C | 1F | SFSWall fire lining :7 ,SHE-06.FOURTH.dgn,Design Model:548993 | A_BSUK_Roofs | SFSWall fire lining | fire board - internal mansard roof finish | New Construction | F60 | A-Roofs::A_BSUK_Roofs | 7C
7C | 1F | SFSWall fire lining :7 ,SHE-06.FOURTH.dgn,Design Model:549002 | A_BSUK_Roofs | SFSWall fire lining | fire board - internal mansard roof finish | New Construction | F60 | A-Roofs::A_BSUK_Roofs | 7C
7C | 1F | SFSWall fire lining :7 ,SHE-06.FOURTH.dgn,Design Model:549011 | A_BSUK_Roofs | SFSWall fire lining | fire board - internal mansard roof finish | New Construction | F60 | A-Roofs::A_BSUK_Roofs | 7C

# IfcWall: A-Walls-ExternalBrick (2)
In: MF
Type - Wall Parameters - Type: Wall; Compound Wall Assembly: no
Type - Thermal Transmittance - Is External: yes; Is Below Grade: no
Type - Structural Usage - Structural | Material: Brickwork
Type - Space Bounding - Is Space Bounding: yes
Type - Materials - Part Definition: A-Walls::A_BSUK_WallsExternal_Brick
Type - LEED Parameters - LEED | Pre-consumer Recycled (%): 0; LEED | Regional Material: no; LEED | Post-consumer Recycled (%): 0
Type - Fire Resistance - Fire | IsCombustible: no; Fire | Compartmentation: no
Type - Discipline - Discipline: Architectural
Type - Classification - Uniclass2015: Pr_20_93_52_27
Material: A_BSUK_WallsExternal_Brick
Pset_WallCommon - Combustible: no; Compartmentation: no; IsExternal: yes; LoadBearing: no
Identification - ID | Description: Wall existing; ID | Notes: general
Construction Phase - Phase: Existing to Remain
Name | Description
A-Walls-ExternalBrick | Wall existing :2,SHE-02.MEZZANINE.dgn,Design Model:93862
A-Walls-ExternalBrick | Wall existing :2,SHE-02.MEZZANINE.dgn,Design Model:94165

# IfcWall: A-Walls-Internal (100)
Type - Wall Parameters - Type: Wall; Compound Wall Assembly: no
Type - Thermal Transmittance - Is External: no; Is Below Grade: no
Type - Space Bounding - Is Space Bounding: yes
Type - Materials - Part Definition: A-Walls::A_BSUK_WallsInternal
Type - LEED Parameters - LEED | Pre-consumer Recycled (%): 0; LEED | Regional Material: no; LEED | Post-consumer Recycled (%): 0
Type - Fire Resistance - Fire | IsCombustible: no; Fire | Compartmentation: no
Type - Discipline - Discipline: Architectural
Type - Classification - Uniclass2015: EF_25_10
Material: A_BSUK_WallsInternal
Pset_WallCommon - Combustible: no; Compartmentation: no; FireRating: F60; IsExternal: no; LoadBearing: no
Identification - ID | Number: 7C; ID | Description: SFSWall fire lining; ID | Notes: fire board - internal mansard roof finish
Fire Resistance - Fire | Rating: F60
Construction Phase - Phase: New Construction
Name | In | Description
7C | 1F | SFSWall fire lining :7 ,SHE-06.FOURTH.dgn,Design Model:100849
7C | 1F | SFSWall fire lining :7 ,SHE-06.FOURTH.dgn,Design Model:100858
7C | 1F | SFSWall fire lining :7 ,SHE-06.FOURTH.dgn,Design Model:100876
7C | 1F | SFSWall fire lining :7 ,SHE-06.FOURTH.dgn,Design Model:100885
7C | 1F | SFSWall fire lining :7 ,SHE-06.FOURTH.dgn,Design Model:100921
7C | 1F | SFSWall fire lining :7 ,SHE-06.FOURTH.dgn,Design Model:100948
7C | 1F | SFSWall fire lining :7 ,SHE-06.FOURTH.dgn,Design Model:100975
7C | 1F | SFSWall fire lining :7 ,SHE-06.FOURTH.dgn,Design Model:101002
7C | 1F | SFSWall fire lining :7 ,SHE-06.FOURTH.dgn,Design Model:101029
7C | 1F | SFSWall fire lining :7 ,SHE-06.FOURTH.dgn,Design Model:101056
7C | 1F | SFSWall fire lining :7 ,SHE-06.FOURTH.dgn,Design Model:101083
7C | 1F | SFSWall fire lining :7 ,SHE-06.FOURTH.dgn,Design Model:101119
7C | 1F | SFSWall fire lining :7 ,SHE-06.FOURTH.dgn,Design Model:101128
7C | 1F | SFSWall fire lining :7 ,SHE-06.FOURTH.dgn,Design Model:101155
7C | 1F | SFSWall fire lining :7 ,SHE-06.FOURTH.dgn,Design Model:101193
7C | 1F | SFSWall fire lining :7 ,SHE-06.FOURTH.dgn,Design Model:101247
7C | 1F | SFSWall fire lining :7 ,SHE-06.FOURTH.dgn,Design Model:101256
7C | 1F | SFSWall fire lining :7 ,SHE-06.FOURTH.dgn,Design Model:101274
7C | 1F | SFSWall fire lining :7 ,SHE-06.FOURTH.dgn,Design Model:101283
7C | 1F | SFSWall fire lining :7 ,SHE-06.FOURTH.dgn,Design Model:101319
7C | 1F | SFSWall fire lining :7 ,SHE-06.FOURTH.dgn,Design Model:101346
7C | 1F | SFSWall fire lining :7 ,SHE-06.FOURTH.dgn,Design Model:101373
7C | 1F | SFSWall fire lining :7 ,SHE-06.FOURTH.dgn,Design Model:101400
7C | 1F | SFSWall fire lining :7 ,SHE-06.FOURTH.dgn,Design Model:101427
7C | 1F | SFSWall fire lining :7 ,SHE-06.FOURTH.dgn,Design Model:101454
7C | 1F | SFSWall fire lining :7 ,SHE-06.FOURTH.dgn,Design Model:101481
7C | 1F | SFSWall fire lining :7 ,SHE-06.FOURTH.dgn,Design Model:101517
7C | 1F | SFSWall fire lining :7 ,SHE-06.FOURTH.dgn,Design Model:101526
7C | 1F | SFSWall fire lining :7 ,SHE-06.FOURTH.dgn,Design Model:101571
7C | 1F | SFSWall fire lining :7 ,SHE-06.FOURTH.dgn,Design Model:101607
7C | 1F | SFSWall fire lining :7 ,SHE-06.FOURTH.dgn,Design Model:469199
7C | 1F | SFSWall fire lining :7 ,SHE-06.FOURTH.dgn,Design Model:469208
7C | 1F | SFSWall fire lining :7 ,SHE-06.FOURTH.dgn,Design Model:469443
7C | 1F | SFSWall fire lining :7 ,SHE-06.FOURTH.dgn,Design Model:469452
7C | 1F | SFSWall fire lining :7 ,SHE-06.FOURTH.dgn,Design Model:469479
7C | 1F | SFSWall fire lining :7 ,SHE-06.FOURTH.dgn,Design Model:469488
7C | 1F | SFSWall fire lining :7 ,SHE-06.FOURTH.dgn,Design Model:469497
7C | 1F | SFSWall fire lining :7 ,SHE-06.FOURTH.dgn,Design Model:469506
7C | 1F | SFSWall fire lining :7 ,SHE-06.FOURTH.dgn,Design Model:469515
7C | 1F | SFSWall fire lining :7 ,SHE-06.FOURTH.dgn,Design Model:469750
7C | 1F | SFSWall fire lining :7 ,SHE-06.FOURTH.dgn,Design Model:469759
7C | 1F | SFSWall fire lining :7 ,SHE-06.FOURTH.dgn,Design Model:469768
7C | 1F | SFSWall fire lining :7 ,SHE-06.FOURTH.dgn,Design Model:469777
7C | 1F | SFSWall fire lining :7 ,SHE-06.FOURTH.dgn,Design Model:469786
7C | 1F | SFSWall fire lining :7 ,SHE-06.FOURTH.dgn,Design Model:469795
7C | 1F | SFSWall fire lining :7 ,SHE-06.FOURTH.dgn,Design Model:469804
7C | 1F | SFSWall fire lining :7 ,SHE-06.FOURTH.dgn,Design Model:469813
7C | 1F | SFSWall fire lining :7 ,SHE-06.FOURTH.dgn,Design Model:469822
7C | 1F | SFSWall fire lining :7 ,SHE-06.FOURTH.dgn,Design Model:469831
7C | 1F | SFSWall fire lining :7 ,SHE-06.FOURTH.dgn,Design Model:469840
7C | 1F | SFSWall fire lining :7 ,SHE-06.FOURTH.dgn,Design Model:469851
7C | 1F | SFSWall fire lining :7 ,SHE-06.FOURTH.dgn,Design Model:469860
7C | 1F | SFSWall fire lining :7 ,SHE-06.FOURTH.dgn,Design Model:469869
7C | 1F | SFSWall fire lining :7 ,SHE-06.FOURTH.dgn,Design Model:469878
7C | 1F | SFSWall fire lining :7 ,SHE-06.FOURTH.dgn,Design Model:469887
7C | 1F | SFSWall fire lining :7 ,SHE-06.FOURTH.dgn,Design Model:469896
7C | 1F | SFSWall fire lining :7 ,SHE-06.FOURTH.dgn,Design Model:469905
7C | 1F | SFSWall fire lining :7 ,SHE-06.FOURTH.dgn,Design Model:469914
7C | 1F | SFSWall fire lining :7 ,SHE-06.FOURTH.dgn,Design Model:469923
7C | 1F | SFSWall fire lining :7 ,SHE-06.FOURTH.dgn,Design Model:469932
7C | 5F | SFSWall fire lining :8 ,SHE-07.FIFTH.dgn,Design Model:264350
7C | 5F | SFSWall fire lining :8 ,SHE-07.FIFTH.dgn,Design Model:264359
7C | 5F | SFSWall fire lining :8 ,SHE-07.FIFTH.dgn,Design Model:264368
7C | 5F | SFSWall fire lining :8 ,SHE-07.FIFTH.dgn,Design Model:264377
7C | 5F | SFSWall fire lining :8 ,SHE-07.FIFTH.dgn,Design Model:264386
7C | 5F | SFSWall fire lining :8 ,SHE-07.FIFTH.dgn,Design Model:264395
7C | 5F | SFSWall fire lining :8 ,SHE-07.FIFTH.dgn,Design Model:264405
7C | 5F | SFSWall fire lining :8 ,SHE-07.FIFTH.dgn,Design Model:264414
7C | 5F | SFSWall fire lining :8 ,SHE-07.FIFTH.dgn,Design Model:264423
7C | 5F | SFSWall fire lining :8 ,SHE-07.FIFTH.dgn,Design Model:264432
7C | 5F | SFSWall fire lining :8 ,SHE-07.FIFTH.dgn,Design Model:264610
7C | 5F | SFSWall fire lining :8 ,SHE-07.FIFTH.dgn,Design Model:264619
7C | 5F | SFSWall fire lining :8 ,SHE-07.FIFTH.dgn,Design Model:264628
7C | 5F | SFSWall fire lining :8 ,SHE-07.FIFTH.dgn,Design Model:264637
7C | 5F | SFSWall fire lining :8 ,SHE-07.FIFTH.dgn,Design Model:264646
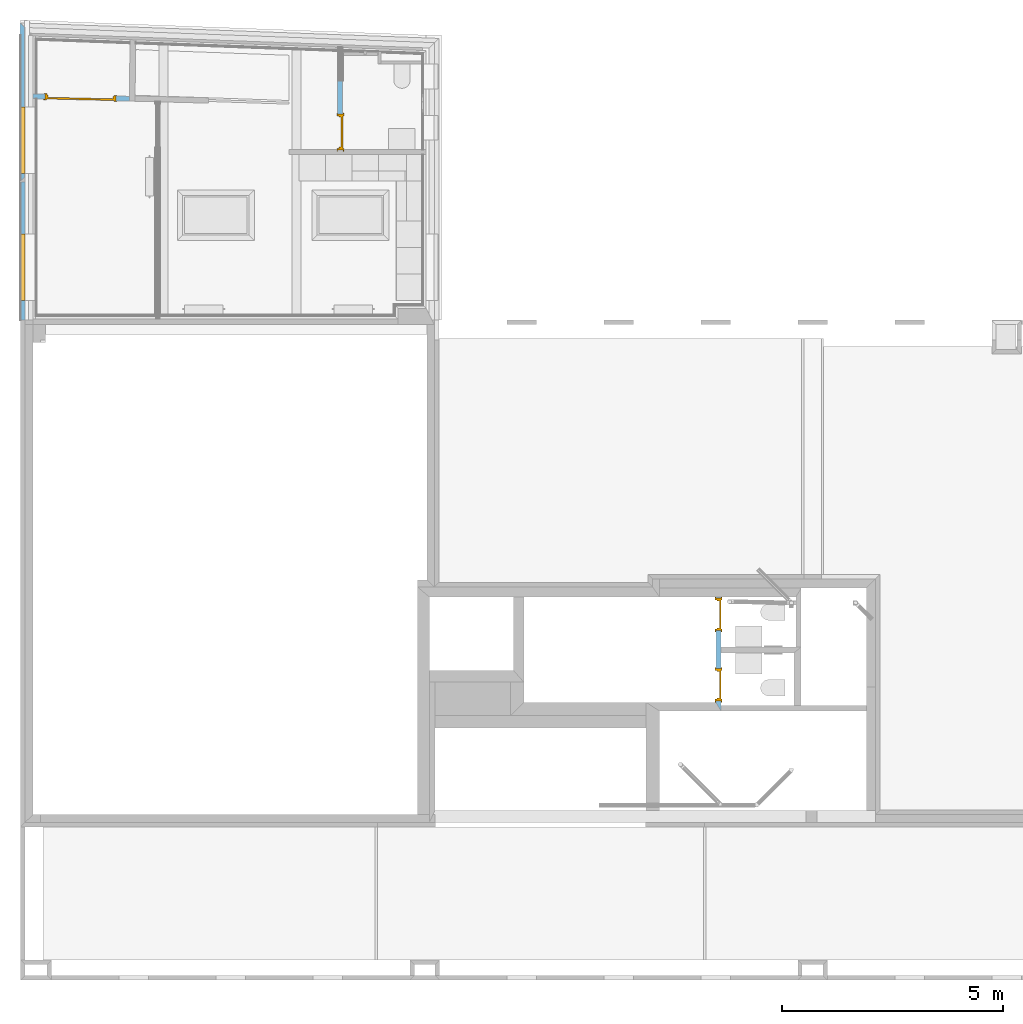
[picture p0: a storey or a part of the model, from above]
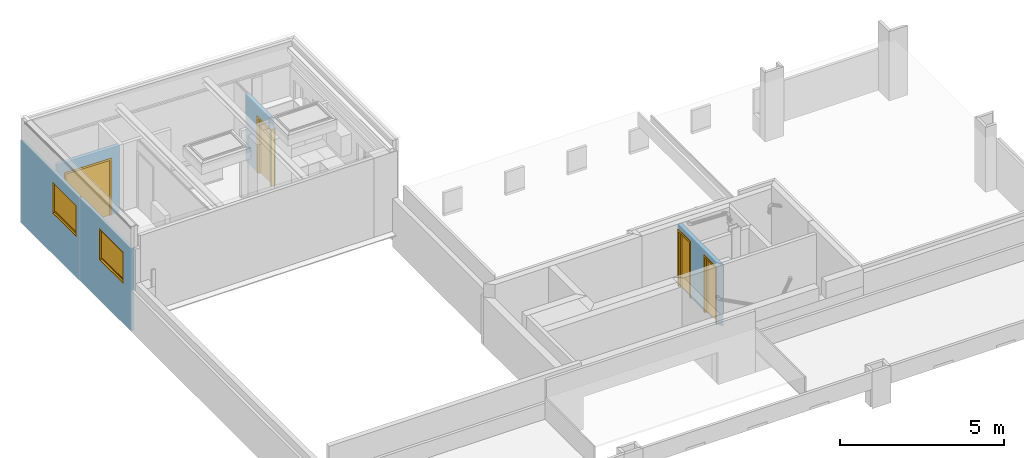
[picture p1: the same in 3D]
Properties of the parts of a building model (IFC2X3), part 15 of 17

# IfcWall: SHE_A-Walls_Type06d_ExternalWallInsulation_48mm (227)
Name | In | Description
6D | 3F | U-Value 0.5 - FacadeInsulation :6,SHE-05.THIRD.dgn,Design Model:141962
6D | 3F | U-Value 0.5 - FacadeInsulation :6,SHE-05.THIRD.dgn,Design Model:141965
6D | 3F | U-Value 0.5 - FacadeInsulation :6,SHE-05.THIRD.dgn,Design Model:141966
6D | 3F | U-Value 0.5 - FacadeInsulation :6,SHE-05.THIRD.dgn,Design Model:141967
6D | 3F | U-Value 0.5 - FacadeInsulation :6,SHE-05.THIRD.dgn,Design Model:141968
6D | 3F | U-Value 0.5 - FacadeInsulation :6,SHE-05.THIRD.dgn,Design Model:141969
6D | 3F | U-Value 0.5 - FacadeInsulation :6,SHE-05.THIRD.dgn,Design Model:141978
6D | 3F | U-Value 0.5 - FacadeInsulation :6,SHE-05.THIRD.dgn,Design Model:141979
6D | 3F | U-Value 0.5 - FacadeInsulation :6,SHE-05.THIRD.dgn,Design Model:141980
6D | 3F | U-Value 0.5 - FacadeInsulation :6,SHE-05.THIRD.dgn,Design Model:142263
6D | 3F | U-Value 0.5 - FacadeInsulation :6,SHE-05.THIRD.dgn,Design Model:142268
6D | 3F | U-Value 0.5 - FacadeInsulation :6,SHE-05.THIRD.dgn,Design Model:142542
6D | 3F | U-Value 0.5 - FacadeInsulation :6,SHE-05.THIRD.dgn,Design Model:171807
6D | 2F | U-Value 0.5 - FacadeInsulation :18,SHE-04.SECOND.dgn,Design Model:141882
6D | 2F | U-Value 0.5 - FacadeInsulation :18,SHE-04.SECOND.dgn,Design Model:141883
6D | 2F | U-Value 0.5 - FacadeInsulation :18,SHE-04.SECOND.dgn,Design Model:141893
6D | 2F | U-Value 0.5 - FacadeInsulation :18,SHE-04.SECOND.dgn,Design Model:141894
6D | 2F | U-Value 0.5 - FacadeInsulation :18,SHE-04.SECOND.dgn,Design Model:141895
6D | 2F | U-Value 0.5 - FacadeInsulation :18,SHE-04.SECOND.dgn,Design Model:141896
6D | 2F | U-Value 0.5 - FacadeInsulation :18,SHE-04.SECOND.dgn,Design Model:141897
6D | 2F | U-Value 0.5 - FacadeInsulation :18,SHE-04.SECOND.dgn,Design Model:141900
6D | 2F | U-Value 0.5 - FacadeInsulation :18,SHE-04.SECOND.dgn,Design Model:141901
6D | 2F | U-Value 0.5 - FacadeInsulation :18,SHE-04.SECOND.dgn,Design Model:141902
6D | 2F | U-Value 0.5 - FacadeInsulation :18,SHE-04.SECOND.dgn,Design Model:141903
6D | 2F | U-Value 0.5 - FacadeInsulation :18,SHE-04.SECOND.dgn,Design Model:141904
6D | 2F | U-Value 0.5 - FacadeInsulation :18,SHE-04.SECOND.dgn,Design Model:141907
6D | 2F | U-Value 0.5 - FacadeInsulation :18,SHE-04.SECOND.dgn,Design Model:141908
6D | 2F | U-Value 0.5 - FacadeInsulation :18,SHE-04.SECOND.dgn,Design Model:141909
6D | 2F | U-Value 0.5 - FacadeInsulation :18,SHE-04.SECOND.dgn,Design Model:141910
6D | 2F | U-Value 0.5 - FacadeInsulation :18,SHE-04.SECOND.dgn,Design Model:141911
6D | 2F | U-Value 0.5 - FacadeInsulation :18,SHE-04.SECOND.dgn,Design Model:141912
6D | 2F | U-Value 0.5 - FacadeInsulation :18,SHE-04.SECOND.dgn,Design Model:141913
6D | 2F | U-Value 0.5 - FacadeInsulation :18,SHE-04.SECOND.dgn,Design Model:141914
6D | 2F | U-Value 0.5 - FacadeInsulation :18,SHE-04.SECOND.dgn,Design Model:141917
6D | 2F | U-Value 0.5 - FacadeInsulation :18,SHE-04.SECOND.dgn,Design Model:141918
6D | 2F | U-Value 0.5 - FacadeInsulation :18,SHE-04.SECOND.dgn,Design Model:141919
6D | 2F | U-Value 0.5 - FacadeInsulation :18,SHE-04.SECOND.dgn,Design Model:141920
6D | 2F | U-Value 0.5 - FacadeInsulation :18,SHE-04.SECOND.dgn,Design Model:141921
6D | 2F | U-Value 0.5 - FacadeInsulation :18,SHE-04.SECOND.dgn,Design Model:141922
6D | 2F | U-Value 0.5 - FacadeInsulation :18,SHE-04.SECOND.dgn,Design Model:141923
6D | 2F | U-Value 0.5 - FacadeInsulation :18,SHE-04.SECOND.dgn,Design Model:141924
6D | 2F | U-Value 0.5 - FacadeInsulation :18,SHE-04.SECOND.dgn,Design Model:141927
6D | 2F | U-Value 0.5 - FacadeInsulation :18,SHE-04.SECOND.dgn,Design Model:141928
6D | 2F | U-Value 0.5 - FacadeInsulation :18,SHE-04.SECOND.dgn,Design Model:141929
6D | 2F | U-Value 0.5 - FacadeInsulation :18,SHE-04.SECOND.dgn,Design Model:141931
6D | 2F | U-Value 0.5 - FacadeInsulation :18,SHE-04.SECOND.dgn,Design Model:141934
6D | 2F | U-Value 0.5 - FacadeInsulation :18,SHE-04.SECOND.dgn,Design Model:141938
6D | 2F | U-Value 0.5 - FacadeInsulation :18,SHE-04.SECOND.dgn,Design Model:141939
6D | 2F | U-Value 0.5 - FacadeInsulation :18,SHE-04.SECOND.dgn,Design Model:141940
6D | 2F | U-Value 0.5 - FacadeInsulation :18,SHE-04.SECOND.dgn,Design Model:141941
6D | 2F | U-Value 0.5 - FacadeInsulation :18,SHE-04.SECOND.dgn,Design Model:141942
6D | 2F | U-Value 0.5 - FacadeInsulation :18,SHE-04.SECOND.dgn,Design Model:141943
6D | 2F | U-Value 0.5 - FacadeInsulation :18,SHE-04.SECOND.dgn,Design Model:141944
6D | 2F | U-Value 0.5 - FacadeInsulation :18,SHE-04.SECOND.dgn,Design Model:141945
6D | 2F | U-Value 0.5 - FacadeInsulation :18,SHE-04.SECOND.dgn,Design Model:141948
6D | 2F | U-Value 0.5 - FacadeInsulation :18,SHE-04.SECOND.dgn,Design Model:141949
6D | 2F | U-Value 0.5 - FacadeInsulation :18,SHE-04.SECOND.dgn,Design Model:141950
6D | 2F | U-Value 0.5 - FacadeInsulation :18,SHE-04.SECOND.dgn,Design Model:141951
6D | 2F | U-Value 0.5 - FacadeInsulation :18,SHE-04.SECOND.dgn,Design Model:141952
6D | 2F | U-Value 0.5 - FacadeInsulation :18,SHE-04.SECOND.dgn,Design Model:141953
6D | 2F | U-Value 0.5 - FacadeInsulation :18,SHE-04.SECOND.dgn,Design Model:141954
6D | 2F | U-Value 0.5 - FacadeInsulation :18,SHE-04.SECOND.dgn,Design Model:141955
6D | 2F | U-Value 0.5 - FacadeInsulation :18,SHE-04.SECOND.dgn,Design Model:141956
6D | 2F | U-Value 0.5 - FacadeInsulation :18,SHE-04.SECOND.dgn,Design Model:141957
6D | 2F | U-Value 0.5 - FacadeInsulation :18,SHE-04.SECOND.dgn,Design Model:141958
6D | 2F | U-Value 0.5 - FacadeInsulation :18,SHE-04.SECOND.dgn,Design Model:141959
6D | 2F | U-Value 0.5 - FacadeInsulation :18,SHE-04.SECOND.dgn,Design Model:141960
6D | 2F | U-Value 0.5 - FacadeInsulation :18,SHE-04.SECOND.dgn,Design Model:141961
6D | 2F | U-Value 0.5 - FacadeInsulation :18,SHE-04.SECOND.dgn,Design Model:141962
6D | 2F | U-Value 0.5 - FacadeInsulation :18,SHE-04.SECOND.dgn,Design Model:141965
6D | 2F | U-Value 0.5 - FacadeInsulation :18,SHE-04.SECOND.dgn,Design Model:141966
6D | 2F | U-Value 0.5 - FacadeInsulation :18,SHE-04.SECOND.dgn,Design Model:141967
6D | 2F | U-Value 0.5 - FacadeInsulation :18,SHE-04.SECOND.dgn,Design Model:141968
6D | 2F | U-Value 0.5 - FacadeInsulation :18,SHE-04.SECOND.dgn,Design Model:141969
6D | 2F | U-Value 0.5 - FacadeInsulation :18,SHE-04.SECOND.dgn,Design Model:141978
6D | 2F | U-Value 0.5 - FacadeInsulation :18,SHE-04.SECOND.dgn,Design Model:141979
6D | 2F | U-Value 0.5 - FacadeInsulation :18,SHE-04.SECOND.dgn,Design Model:141980
6D | 2F | U-Value 0.5 - FacadeInsulation :18,SHE-04.SECOND.dgn,Design Model:142263
6D | 2F | U-Value 0.5 - FacadeInsulation :18,SHE-04.SECOND.dgn,Design Model:142268
6D | 2F | U-Value 0.5 - FacadeInsulation :18,SHE-04.SECOND.dgn,Design Model:142542
6D | 2F | U-Value 0.5 - FacadeInsulation :18,SHE-04.SECOND.dgn,Design Model:171807

# IfcWall: SHE_A-Walls_Type06e_ExternalWallPenthouse_280mm (32)
Type - Description: SHE_A-Walls_Type06e_ExternalWallPenthouse_280mm
Type - Wall Parameters - Type: Wall; Compound Wall Assembly: yes
Type - Thermal Transmittance - Is External: no; Is Below Grade: no
Type - Space Bounding - Is Space Bounding: yes
Type - Materials - Part Definition: A-CompoundWalls::SHE_A-Walls_Type06e_ExternalWallPenthouse_280mm
Type - LEED Parameters - LEED | Pre-consumer Recycled (%): 0; LEED | Regional Material: no; LEED | Post-consumer Recycled (%): 0
Type - Identification - ID | Description: SHE_A-Walls_Type06e_ExternalWallPenthouse_280mm
Type - Fire Resistance - Fire | IsCombustible: no; Fire | Compartmentation: no; Fire | Surface Spread of Flame: A2-s1,d0 or better
Type - Discipline - Discipline: Architectural
Type - Construction Phase - Phase: New Construction
Type - Classification - Uniclass2015: EF_25_10
Type - Acoustical Parameters - Acoustic Rating (STC): (min. Rw+Ctr 48)
Pset_WallCommon - AcousticRating: Rw 52dB , Rw+Ctr 48dB; Combustible: no; Compartmentation: no; FireRating: F60; IsExternal: no; LoadBearing: no; SurfaceSpreadOfFlame: A2-s1 ,d0 or better
Identification - ID | Type ID: U-Value 0.18; ID | Number: 6E; ID | Description: SFSWall; ID | Notes: SHE_A-Walls_Type06e_ExternalWallPenthouse_280mm
Fire Resistance - Fire | Rating: F60
Acoustical Parameters - Acoustic Rating (STC): Rw 52dB , Rw+Ctr 48dB
Name | In | Description
6E | 1F | U-Value 0.18 - SFSWall :7 ,SHE-06.FOURTH.dgn,Design Model:376624
6E | 1F | U-Value 0.18 - SFSWall :7 ,SHE-06.FOURTH.dgn,Design Model:376764
6E | 1F | U-Value 0.18 - SFSWall :7 ,SHE-06.FOURTH.dgn,Design Model:376873
6E | 1F | U-Value 0.18 - SFSWall :7 ,SHE-06.FOURTH.dgn,Design Model:376874
6E | 1F | U-Value 0.18 - SFSWall :7 ,SHE-06.FOURTH.dgn,Design Model:377033
6E | 1F | U-Value 0.18 - SFSWall :7 ,SHE-06.FOURTH.dgn,Design Model:377082
6E | 1F | U-Value 0.18 - SFSWall :7 ,SHE-06.FOURTH.dgn,Design Model:377137
6E | 1F | U-Value 0.18 - SFSWall :7 ,SHE-06.FOURTH.dgn,Design Model:377192
6E | 1F | U-Value 0.18 - SFSWall :7 ,SHE-06.FOURTH.dgn,Design Model:377301
6E | 1F | U-Value 0.18 - SFSWall :7 ,SHE-06.FOURTH.dgn,Design Model:377302
6E | 1F | U-Value 0.18 - SFSWall :7 ,SHE-06.FOURTH.dgn,Design Model:377411
6E | 1F | U-Value 0.18 - SFSWall :7 ,SHE-06.FOURTH.dgn,Design Model:377412
6E | 1F | U-Value 0.18 - SFSWall :7 ,SHE-06.FOURTH.dgn,Design Model:377521
6E | 1F | U-Value 0.18 - SFSWall :7 ,SHE-06.FOURTH.dgn,Design Model:377522
6E | 1F | U-Value 0.18 - SFSWall :7 ,SHE-06.FOURTH.dgn,Design Model:377631
6E | 1F | U-Value 0.18 - SFSWall :7 ,SHE-06.FOURTH.dgn,Design Model:377632
6E | 1F | U-Value 0.18 - SFSWall :7 ,SHE-06.FOURTH.dgn,Design Model:377741
6E | 1F | U-Value 0.18 - SFSWall :7 ,SHE-06.FOURTH.dgn,Design Model:377742
6E | 1F | U-Value 0.18 - SFSWall :7 ,SHE-06.FOURTH.dgn,Design Model:377851
6E | 1F | U-Value 0.18 - SFSWall :7 ,SHE-06.FOURTH.dgn,Design Model:377852
6E | 1F | U-Value 0.18 - SFSWall :7 ,SHE-06.FOURTH.dgn,Design Model:377961
6E | 1F | U-Value 0.18 - SFSWall :7 ,SHE-06.FOURTH.dgn,Design Model:377962
6E | 1F | U-Value 0.18 - SFSWall :7 ,SHE-06.FOURTH.dgn,Design Model:378071
6E | 1F | U-Value 0.18 - SFSWall :7 ,SHE-06.FOURTH.dgn,Design Model:378072
6E | 1F | U-Value 0.18 - SFSWall :7 ,SHE-06.FOURTH.dgn,Design Model:378181
6E | 1F | U-Value 0.18 - SFSWall :7 ,SHE-06.FOURTH.dgn,Design Model:378182
6E | 5F | U-Value 0.18 - SFSWall :8 ,SHE-07.FIFTH.dgn,Design Model:204325
6E | 5F | U-Value 0.18 - SFSWall :8 ,SHE-07.FIFTH.dgn,Design Model:204435
6E | 5F | U-Value 0.18 - SFSWall :8 ,SHE-07.FIFTH.dgn,Design Model:210006
6E | 5F | U-Value 0.18 - SFSWall :8 ,SHE-07.FIFTH.dgn,Design Model:210116
6E | 5F | U-Value 0.18 - SFSWall :8 ,SHE-07.FIFTH.dgn,Design Model:212671
6E | 5F | U-Value 0.18 - SFSWall :8 ,SHE-07.FIFTH.dgn,Design Model:213117

# IfcWall: SHE_A-Walls_Type06f_ExternalWallInsulation_48+15mm (87)
Type - Description: SHE_A-Walls_Type06f_ExternalWallInsulation_48+15mm
Type - Wall Parameters - Type: Wall; Compound Wall Assembly: yes
Type - Thermal Transmittance - Is External: no; Is Below Grade: no
Type - Space Bounding - Is Space Bounding: yes
Type - Materials - Part Definition: A-CompoundWalls::SHE_A-Walls_Type06f_ExternalWallInsulation_48+15mm
Type - LEED Parameters - LEED | Pre-consumer Recycled (%): 0; LEED | Regional Material: no; LEED | Post-consumer Recycled (%): 0
Type - Identification - ID | Description: SHE_A-Walls_Type06f_ExternalWallInsulation_48+15mm
Type - Fire Resistance - Fire | IsCombustible: no; Fire | Compartmentation: no
Type - Discipline - Discipline: Architectural
Type - Construction Phase - Phase: New Construction
Type - Classification - Uniclass2015: EF_25_10
Pset_WallCommon - Combustible: no; Compartmentation: no; FireRating: F60; IsExternal: no; LoadBearing: no
Identification - ID | Type ID: U-Value 0.5; ID | Number: 6F; ID | Description: FacadeInsulation; ID | Keynote: https://www.british-gyp sum.com/products/board-products/gyproc-thermaline-plus-48mm; ID | Notes: SHE_A-Walls_Type06f_ExternalWallInsulation_48+15mm
Fire Resistance - Fire | Rating: F60
Name | In | Description | AcousticRating = Acoustic Rating (STC)
6F | 1F | U-Value 0.5 - FacadeInsulation :4,SHE-03.FIRST.dgn,Design Model:376780 | req. 48
6F | 1F | U-Value 0.5 - FacadeInsulation :4,SHE-03.FIRST.dgn,Design Model:376817 | req. 48
6F | 1F | U-Value 0.5 - FacadeInsulation :4,SHE-03.FIRST.dgn,Design Model:376854 | req. 48
6F | 1F | U-Value 0.5 - FacadeInsulation :4,SHE-03.FIRST.dgn,Design Model:376928 | req. 48
6F | 1F | U-Value 0.5 - FacadeInsulation :4,SHE-03.FIRST.dgn,Design Model:376965 | req. 48
6F | 1F | U-Value 0.5 - FacadeInsulation :4,SHE-03.FIRST.dgn,Design Model:377002 | req. 48
6F | 1F | U-Value 0.5 - FacadeInsulation :4,SHE-03.FIRST.dgn,Design Model:377872 | req. 48
6F | 1F | U-Value 0.5 - FacadeInsulation :4,SHE-03.FIRST.dgn,Design Model:378370
6F | 1F | U-Value 0.5 - FacadeInsulation :4,SHE-03.FIRST.dgn,Design Model:378444
6F | 1F | U-Value 0.5 - FacadeInsulation :4,SHE-03.FIRST.dgn,Design Model:378833
6F | 1F | U-Value 0.5 - FacadeInsulation :4,SHE-03.FIRST.dgn,Design Model:381139
6F | 1F | U-Value 0.5 - FacadeInsulation :4,SHE-03.FIRST.dgn,Design Model:381140
6F | 1F | U-Value 0.5 - FacadeInsulation :4,SHE-03.FIRST.dgn,Design Model:381141
6F | 1F | U-Value 0.5 - FacadeInsulation :4,SHE-03.FIRST.dgn,Design Model:383873 | req. 48
6F | 1F | U-Value 0.5 - FacadeInsulation :4,SHE-03.FIRST.dgn,Design Model:383910 | req. 48
6F | 1F | U-Value 0.5 - FacadeInsulation :4,SHE-03.FIRST.dgn,Design Model:383947 | req. 48
6F | 1F | U-Value 0.5 - FacadeInsulation :4,SHE-03.FIRST.dgn,Design Model:383984 | req. 48
6F | 1F | U-Value 0.5 - FacadeInsulation :4,SHE-03.FIRST.dgn,Design Model:384021 | req. 48
6F | 1F | U-Value 0.5 - FacadeInsulation :4,SHE-03.FIRST.dgn,Design Model:384058 | req. 48
6F | 1F | U-Value 0.5 - FacadeInsulation :4,SHE-03.FIRST.dgn,Design Model:384095 | req. 48
6F | 1F | U-Value 0.5 - FacadeInsulation :4,SHE-03.FIRST.dgn,Design Model:387639 | req. 48
6F | 1F | U-Value 0.5 - FacadeInsulation :4,SHE-03.FIRST.dgn,Design Model:387945 | req. 48
6F | 1F | U-Value 0.5 - FacadeInsulation :4,SHE-03.FIRST.dgn,Design Model:388254 | req. 48
6F | 1F | U-Value 0.5 - FacadeInsulation :4,SHE-03.FIRST.dgn,Design Model:388591 | req. 48
6F | 1F | U-Value 0.5 - FacadeInsulation :4,SHE-03.FIRST.dgn,Design Model:388592 | req. 48
6F | 1F | U-Value 0.5 - FacadeInsulation :4,SHE-03.FIRST.dgn,Design Model:388593 | req. 48
6F | 1F | U-Value 0.5 - FacadeInsulation :4,SHE-03.FIRST.dgn,Design Model:389291 | req. 48
6F | 1F | U-Value 0.5 - FacadeInsulation :4,SHE-03.FIRST.dgn,Design Model:389292 | req. 48
6F | 1F | U-Value 0.5 - FacadeInsulation :4,SHE-03.FIRST.dgn,Design Model:389293 | req. 48
6F | 3F | U-Value 0.5 - FacadeInsulation :6,SHE-05.THIRD.dgn,Design Model:445172 | req. 48
6F | 3F | U-Value 0.5 - FacadeInsulation :6,SHE-05.THIRD.dgn,Design Model:445209 | req. 48
6F | 3F | U-Value 0.5 - FacadeInsulation :6,SHE-05.THIRD.dgn,Design Model:445448 | req. 48
6F | 3F | U-Value 0.5 - FacadeInsulation :6,SHE-05.THIRD.dgn,Design Model:445449 | req. 48
6F | 3F | U-Value 0.5 - FacadeInsulation :6,SHE-05.THIRD.dgn,Design Model:445672 | req. 48
6F | 3F | U-Value 0.5 - FacadeInsulation :6,SHE-05.THIRD.dgn,Design Model:445673 | req. 48
6F | 3F | U-Value 0.5 - FacadeInsulation :6,SHE-05.THIRD.dgn,Design Model:445784 | req. 48
6F | 3F | U-Value 0.5 - FacadeInsulation :6,SHE-05.THIRD.dgn,Design Model:445785 | req. 48
6F | 3F | U-Value 0.5 - FacadeInsulation :6,SHE-05.THIRD.dgn,Design Model:445896 | req. 48
6F | 3F | U-Value 0.5 - FacadeInsulation :6,SHE-05.THIRD.dgn,Design Model:445897 | req. 48
6F | 3F | U-Value 0.5 - FacadeInsulation :6,SHE-05.THIRD.dgn,Design Model:446007 | req. 48
6F | 3F | U-Value 0.5 - FacadeInsulation :6,SHE-05.THIRD.dgn,Design Model:446008 | req. 48
6F | 3F | U-Value 0.5 - FacadeInsulation :6,SHE-05.THIRD.dgn,Design Model:446009 | req. 48
6F | 3F | U-Value 0.5 - FacadeInsulation :6,SHE-05.THIRD.dgn,Design Model:446112 | req. 48
6F | 3F | U-Value 0.5 - FacadeInsulation :6,SHE-05.THIRD.dgn,Design Model:446149 | req. 48
6F | 3F | U-Value 0.5 - FacadeInsulation :6,SHE-05.THIRD.dgn,Design Model:446186 | req. 48
6F | 3F | U-Value 0.5 - FacadeInsulation :6,SHE-05.THIRD.dgn,Design Model:446223 | req. 48
6F | 3F | U-Value 0.5 - FacadeInsulation :6,SHE-05.THIRD.dgn,Design Model:446477 | req. 48
6F | 3F | U-Value 0.5 - FacadeInsulation :6,SHE-05.THIRD.dgn,Design Model:446478 | req. 48
6F | 3F | U-Value 0.5 - FacadeInsulation :6,SHE-05.THIRD.dgn,Design Model:446480 | req. 48
6F | 3F | U-Value 0.5 - FacadeInsulation :6,SHE-05.THIRD.dgn,Design Model:446481 | req. 48
6F | 3F | U-Value 0.5 - FacadeInsulation :6,SHE-05.THIRD.dgn,Design Model:446482 | req. 48
6F | 3F | U-Value 0.5 - FacadeInsulation :6,SHE-05.THIRD.dgn,Design Model:446483 | req. 48
6F | 3F | U-Value 0.5 - FacadeInsulation :6,SHE-05.THIRD.dgn,Design Model:446753 | req. 48
6F | 3F | U-Value 0.5 - FacadeInsulation :6,SHE-05.THIRD.dgn,Design Model:446970 | req. 48
6F | 3F | U-Value 0.5 - FacadeInsulation :6,SHE-05.THIRD.dgn,Design Model:447159 | req. 48
6F | 3F | U-Value 0.5 - FacadeInsulation :6,SHE-05.THIRD.dgn,Design Model:447388 | req. 48
6F | 3F | U-Value 0.5 - FacadeInsulation :6,SHE-05.THIRD.dgn,Design Model:447563 | req. 48
6F | 3F | U-Value 0.5 - FacadeInsulation :6,SHE-05.THIRD.dgn,Design Model:447728 | req. 48
6F | 2F | U-Value 0.5 - FacadeInsulation :18,SHE-04.SECOND.dgn,Design Model:378238 | req. 48
6F | 2F | U-Value 0.5 - FacadeInsulation :18,SHE-04.SECOND.dgn,Design Model:378275 | req. 48
6F | 2F | U-Value 0.5 - FacadeInsulation :18,SHE-04.SECOND.dgn,Design Model:378440 | req. 48
6F | 2F | U-Value 0.5 - FacadeInsulation :18,SHE-04.SECOND.dgn,Design Model:378622 | req. 48
6F | 2F | U-Value 0.5 - FacadeInsulation :18,SHE-04.SECOND.dgn,Design Model:378623 | req. 48
6F | 2F | U-Value 0.5 - FacadeInsulation :18,SHE-04.SECOND.dgn,Design Model:378624 | req. 48
6F | 2F | U-Value 0.5 - FacadeInsulation :18,SHE-04.SECOND.dgn,Design Model:378731 | req. 48
6F | 2F | U-Value 0.5 - FacadeInsulation :18,SHE-04.SECOND.dgn,Design Model:378768 | req. 48
6F | 2F | U-Value 0.5 - FacadeInsulation :18,SHE-04.SECOND.dgn,Design Model:378906 | req. 48
6F | 2F | U-Value 0.5 - FacadeInsulation :18,SHE-04.SECOND.dgn,Design Model:378943 | req. 48
6F | 2F | U-Value 0.5 - FacadeInsulation :18,SHE-04.SECOND.dgn,Design Model:379081 | req. 48
6F | 2F | U-Value 0.5 - FacadeInsulation :18,SHE-04.SECOND.dgn,Design Model:379118 | req. 48
6F | 2F | U-Value 0.5 - FacadeInsulation :18,SHE-04.SECOND.dgn,Design Model:379564 | req. 48
6F | 2F | U-Value 0.5 - FacadeInsulation :18,SHE-04.SECOND.dgn,Design Model:379565 | req. 48
6F | 2F | U-Value 0.5 - FacadeInsulation :18,SHE-04.SECOND.dgn,Design Model:379566 | req. 48
6F | 2F | U-Value 0.5 - FacadeInsulation :18,SHE-04.SECOND.dgn,Design Model:379567 | req. 48
6F | 2F | U-Value 0.5 - FacadeInsulation :18,SHE-04.SECOND.dgn,Design Model:379568 | req. 48
6F | 2F | U-Value 0.5 - FacadeInsulation :18,SHE-04.SECOND.dgn,Design Model:379569 | req. 48
6F | 2F | U-Value 0.5 - FacadeInsulation :18,SHE-04.SECOND.dgn,Design Model:379570 | req. 48
6F | 2F | U-Value 0.5 - FacadeInsulation :18,SHE-04.SECOND.dgn,Design Model:379735 | req. 48
6F | 2F | U-Value 0.5 - FacadeInsulation :18,SHE-04.SECOND.dgn,Design Model:380133 | req. 48
6F | 2F | U-Value 0.5 - FacadeInsulation :18,SHE-04.SECOND.dgn,Design Model:380134 | req. 48
6F | 2F | U-Value 0.5 - FacadeInsulation :18,SHE-04.SECOND.dgn,Design Model:380135 | req. 48
6F | 2F | U-Value 0.5 - FacadeInsulation :18,SHE-04.SECOND.dgn,Design Model:380271 | req. 48
6F | 2F | U-Value 0.5 - FacadeInsulation :18,SHE-04.SECOND.dgn,Design Model:380272 | req. 48
6F | 2F | U-Value 0.5 - FacadeInsulation :18,SHE-04.SECOND.dgn,Design Model:380273 | req. 48
6F | 2F | U-Value 0.5 - FacadeInsulation :18,SHE-04.SECOND.dgn,Design Model:380473 | req. 48
6F | 2F | U-Value 0.5 - FacadeInsulation :18,SHE-04.SECOND.dgn,Design Model:380474 | req. 48
6F | 2F | U-Value 0.5 - FacadeInsulation :18,SHE-04.SECOND.dgn,Design Model:380475 | req. 48

# IfcWallStandardCase: A-Walls-Concrete (3)
Type - Wall Parameters - Type: Wall; Compound Wall Assembly: no
Type - Thermal Transmittance - Is External: no; Is Below Grade: no
Type - Structural Usage - Structural | Function: Load-bearing; Structural | Material: Concrete
Type - Space Bounding - Is Space Bounding: yes
Type - Materials - Part Definition: A-Walls::A_BSUK_Walls_Concrete
Type - LEED Parameters - LEED | Pre-consumer Recycled (%): 0; LEED | Regional Material: no; LEED | Post-consumer Recycled (%): 0
Type - Fire Resistance - Fire | IsCombustible: no; Fire | Compartmentation: no
Type - Discipline - Discipline: Architectural
Type - Classification - Uniclass2015: Ss_25_11_16_70
Material: A_BSUK_Walls_Concrete 0.25 m
Pset_WallCommon - Combustible: no; Compartmentation: no; IsExternal: no; LoadBearing: yes
Name | In | Description
A-Walls-Concrete | 1F | 4 ,SHE-03.FIRST.dgn,Design Model:456184
A-Walls-Concrete | 3F | 6 ,SHE-05.THIRD.dgn,Design Model:543929
A-Walls-Concrete | 2F | 18,SHE-04.SECOND.dgn,Design Model:442929

# IfcWallStandardCase: A-Walls-ExternalBlock (201)
Type - Wall Parameters - Type: Wall; Compound Wall Assembly: no
Type - Thermal Transmittance - Is External: yes; Is Below Grade: no
Type - Structural Usage - Structural | Material: Blockwork
Type - Space Bounding - Is Space Bounding: yes
Type - Materials - Part Definition: A-Walls::A_BSUK_WallsExternal_Block
Type - LEED Parameters - LEED | Pre-consumer Recycled (%): 0; LEED | Regional Material: no; LEED | Post-consumer Recycled (%): 0
Type - Fire Resistance - Fire | IsCombustible: no; Fire | Compartmentation: no
Type - Discipline - Discipline: Architectural
Type - Classification - Uniclass2015: Pr_20_93_52_01
Pset_WallCommon - Combustible: no; Compartmentation: no; IsExternal: yes; LoadBearing: no
Name | In | Description | Material | ID | Description | ID | Notes | Phase
A-Walls-ExternalBlock | GF | Wall existing :1,SHE-01.GROUND.dgn ,Design Model:95457 | A_BSUK_WallsExternal_Block 0.1 m | Wall existing | general | Existing to Remain
A-Walls-ExternalBlock | GF | Wall existing :1,SHE-01.GROUND.dgn ,Design Model:95493 | A_BSUK_WallsExternal_Block 0.1 m | Wall existing | general | Existing to Remain
A-Walls-ExternalBlock | GF | Wall existing :1,SHE-01.GROUND.dgn ,Design Model:95502 | A_BSUK_WallsExternal_Block 0.1 m | Wall existing | general | Existing to Remain
A-Walls-ExternalBlock | GF | Wall existing :1,SHE-01.GROUND.dgn ,Design Model:95511 | A_BSUK_WallsExternal_Block 0.1 m | Wall existing | general | Existing to Remain
A-Walls-ExternalBlock | GF | Wall existing :1,SHE-01.GROUND.dgn ,Design Model:95524 | A_BSUK_WallsExternal_Block 0.1 m | Wall existing | general | Existing to Remain
A-Walls-ExternalBlock | GF | Wall existing :1,SHE-01.GROUND.dgn ,Design Model:95543 | A_BSUK_WallsExternal_Block 0.1 m | Wall existing | general | Existing to Remain
A-Walls-ExternalBlock | GF | Wall existing :1,SHE-01.GROUND.dgn ,Design Model:95939 | A_BSUK_WallsExternal_Block 0.174 m | Wall existing | general | Existing to Remain
A-Walls-ExternalBlock | GF | Wall existing :1,SHE-01.GROUND.dgn ,Design Model:95964 | A_BSUK_WallsExternal_Block 0.187 m | Wall existing | general | Existing to Remain
A-Walls-ExternalBlock | GF | Wall existing :1,SHE-01.GROUND.dgn ,Design Model:95979 | A_BSUK_WallsExternal_Block 0.189 m | Wall existing | general | Existing to Remain
A-Walls-ExternalBlock | GF | Wall existing :1,SHE-01.GROUND.dgn ,Design Model:96004 | A_BSUK_WallsExternal_Block 0.17 m | Wall existing | general | Existing to Remain
A-Walls-ExternalBlock | GF | Wall existing :1,SHE-01.GROUND.dgn ,Design Model:96013 | A_BSUK_WallsExternal_Block 0.264901 m | Wall existing | general | Existing to Remain
A-Walls-ExternalBlock | GF | Wall existing :1,SHE-01.GROUND.dgn ,Design Model:96022 | A_BSUK_WallsExternal_Block 0.164 m | Wall existing | general | Existing to Remain
A-Walls-ExternalBlock | GF | Wall existing :1,SHE-01.GROUND.dgn ,Design Model:96043 | A_BSUK_WallsExternal_Block 0.18 m | Wall existing | general | Existing to Remain
A-Walls-ExternalBlock | GF | Wall existing :1,SHE-01.GROUND.dgn ,Design Model:96097 | A_BSUK_WallsExternal_Block 0.18 m | Wall existing | general | Existing to Remain
A-Walls-ExternalBlock | GF | Wall existing :1,SHE-01.GROUND.dgn ,Design Model:96106 | A_BSUK_WallsExternal_Block 0.195 m | Wall existing | general | Existing to Remain
A-Walls-ExternalBlock | GF | Wall existing :1,SHE-01.GROUND.dgn ,Design Model:96133 | A_BSUK_WallsExternal_Block 0.159 m | Wall existing | general | Existing to Remain
A-Walls-ExternalBlock | GF | Wall existing :1,SHE-01.GROUND.dgn ,Design Model:96142 | A_BSUK_WallsExternal_Block 0.224 m | Wall existing | general | Existing to Remain
A-Walls-ExternalBlock | GF | Wall existing :1,SHE-01.GROUND.dgn ,Design Model:96187 | A_BSUK_WallsExternal_Block 0.065 m | Wall existing | general | Existing to Remain
A-Walls-ExternalBlock | GF | Wall existing :1,SHE-01.GROUND.dgn ,Design Model:96222 | A_BSUK_WallsExternal_Block 0.265 m | Wall existing | general | Existing to Remain
A-Walls-ExternalBlock | GF | Wall existing :1,SHE-01.GROUND.dgn ,Design Model:96250 | A_BSUK_WallsExternal_Block 0.131 m | Wall existing | general | Existing to Remain
A-Walls-ExternalBlock | GF | Wall existing :1,SHE-01.GROUND.dgn ,Design Model:96265 | A_BSUK_WallsExternal_Block 0.138 m | Wall existing | general | Existing to Remain
A-Walls-ExternalBlock | GF | Wall existing :1,SHE-01.GROUND.dgn ,Design Model:96274 | A_BSUK_WallsExternal_Block 0.233 m | Wall existing | general | Existing to Remain
A-Walls-ExternalBlock | GF | Wall existing :1,SHE-01.GROUND.dgn ,Design Model:96377 | A_BSUK_WallsExternal_Block 0.379 m | Wall existing | general | Existing to Remain
A-Walls-ExternalBlock | GF | Wall existing :1,SHE-01.GROUND.dgn ,Design Model:96386 | A_BSUK_WallsExternal_Block 0.406 m | Wall existing | general | Existing to Remain
A-Walls-ExternalBlock | GF | Wall existing :1,SHE-01.GROUND.dgn ,Design Model:96648 | A_BSUK_WallsExternal_Block 0.175 m | Wall existing | general | Existing to Remain
A-Walls-ExternalBlock | GF | Wall existing :1,SHE-01.GROUND.dgn ,Design Model:96657 | A_BSUK_WallsExternal_Block 0.086 m | Wall existing | general | Existing to Remain
A-Walls-ExternalBlock | GF | Wall existing :1,SHE-01.GROUND.dgn ,Design Model:287316 | A_BSUK_WallsExternal_Block 0.1241 m | Wall existing | general | Existing to Remain
A-Walls-ExternalBlock | MF | Wall existing :2,SHE-02.MEZZANINE.dgn ,Design Model:93176 | A_BSUK_WallsExternal_Block 0.086 m | Wall existing | general | Existing to Remain
A-Walls-ExternalBlock | MF | Wall existing :2,SHE-02.MEZZANINE.dgn ,Design Model:93185 | A_BSUK_WallsExternal_Block 0.175 m | Wall existing | general | Existing to Remain
A-Walls-ExternalBlock | MF | Wall existing :2,SHE-02.MEZZANINE.dgn ,Design Model:93194 | A_BSUK_WallsExternal_Block 0.199996 m | Wall existing | general | Existing to Remain
A-Walls-ExternalBlock | MF | Wall existing :2,SHE-02.MEZZANINE.dgn ,Design Model:93203 | A_BSUK_WallsExternal_Block 0.200191 m | Wall existing | general | Existing to Remain
A-Walls-ExternalBlock | MF | Wall existing :2,SHE-02.MEZZANINE.dgn ,Design Model:93212 | A_BSUK_WallsExternal_Block 0.200292 m | Wall existing | general | Existing to Remain
A-Walls-ExternalBlock | MF | Wall existing :2,SHE-02.MEZZANINE.dgn ,Design Model:93223 | A_BSUK_WallsExternal_Block 0.159 m | Wall existing | general | Existing to Remain
A-Walls-ExternalBlock | MF | Wall existing :2,SHE-02.MEZZANINE.dgn ,Design Model:93232 | A_BSUK_WallsExternal_Block 0.224 m | Wall existing | general | Existing to Remain
A-Walls-ExternalBlock | MF | Wall existing :2,SHE-02.MEZZANINE.dgn ,Design Model:93241 | A_BSUK_WallsExternal_Block 0.17 m | Wall existing | general | Existing to Remain
A-Walls-ExternalBlock | MF | Wall existing :2,SHE-02.MEZZANINE.dgn ,Design Model:93250 | A_BSUK_WallsExternal_Block 0.164 m | Wall existing | general | Existing to Remain
A-Walls-ExternalBlock | MF | Wall existing :2,SHE-02.MEZZANINE.dgn ,Design Model:93259 | A_BSUK_WallsExternal_Block 0.264901 m | Wall existing | general | Existing to Remain
A-Walls-ExternalBlock | MF | Wall existing :2,SHE-02.MEZZANINE.dgn ,Design Model:93295 | A_BSUK_WallsExternal_Block 0.174 m | Wall existing | general | Existing to Remain
A-Walls-ExternalBlock | MF | Wall existing :2,SHE-02.MEZZANINE.dgn ,Design Model:93306 | A_BSUK_WallsExternal_Block 0.18 m | Wall existing | general | Existing to Remain
A-Walls-ExternalBlock | MF | Wall existing :2,SHE-02.MEZZANINE.dgn ,Design Model:93335 | A_BSUK_WallsExternal_Block 0.284945 m | Wall existing | general | Existing to Remain
A-Walls-ExternalBlock | MF | Wall existing :2,SHE-02.MEZZANINE.dgn ,Design Model:93353 | A_BSUK_WallsExternal_Block 0.205 m | Wall existing | general | Existing to Remain
A-Walls-ExternalBlock | MF | Wall existing :2,SHE-02.MEZZANINE.dgn ,Design Model:93369 | A_BSUK_WallsExternal_Block 0.118 m | Wall existing | general | Existing to Remain
A-Walls-ExternalBlock | MF | Wall existing :2,SHE-02.MEZZANINE.dgn ,Design Model:93388 | A_BSUK_WallsExternal_Block 0.194 m | Wall existing | general | Existing to Remain
A-Walls-ExternalBlock | MF | Wall existing :2,SHE-02.MEZZANINE.dgn ,Design Model:93397 | A_BSUK_WallsExternal_Block 0.12 m | Wall existing | general | Existing to Remain
A-Walls-ExternalBlock | MF | Wall existing :2,SHE-02.MEZZANINE.dgn ,Design Model:93406 | A_BSUK_WallsExternal_Block 0.167 m | Wall existing | general | Existing to Remain
A-Walls-ExternalBlock | MF | Wall existing :2,SHE-02.MEZZANINE.dgn ,Design Model:93415 | A_BSUK_WallsExternal_Block 0.137 m | Wall existing | general | Existing to Remain
A-Walls-ExternalBlock | MF | Wall existing :2,SHE-02.MEZZANINE.dgn ,Design Model:93424 | A_BSUK_WallsExternal_Block 0.12 m | Wall existing | general | Existing to Remain
A-Walls-ExternalBlock | MF | Wall existing :2,SHE-02.MEZZANINE.dgn ,Design Model:93433 | A_BSUK_WallsExternal_Block 0.3 m | Wall existing | general | Existing to Remain
A-Walls-ExternalBlock | MF | Wall existing :2,SHE-02.MEZZANINE.dgn ,Design Model:93442 | A_BSUK_WallsExternal_Block 0.3 m | Wall existing | general | Existing to Remain
A-Walls-ExternalBlock | MF | Wall existing :2,SHE-02.MEZZANINE.dgn ,Design Model:93451 | A_BSUK_WallsExternal_Block 0.3 m | Wall existing | general | Existing to Remain
A-Walls-ExternalBlock | MF | Wall existing :2,SHE-02.MEZZANINE.dgn ,Design Model:93460 | A_BSUK_WallsExternal_Block 0.277934 m | Wall existing | general | Existing to Remain
A-Walls-ExternalBlock | MF | Wall existing :2,SHE-02.MEZZANINE.dgn ,Design Model:93469 | A_BSUK_WallsExternal_Block 0.754777 m | Wall existing | general | Existing to Remain
A-Walls-ExternalBlock | MF | Wall existing :2,SHE-02.MEZZANINE.dgn ,Design Model:93487 | A_BSUK_WallsExternal_Block 0.1 m | Wall existing | general | Existing to Remain
A-Walls-ExternalBlock | MF | Wall existing :2,SHE-02.MEZZANINE.dgn ,Design Model:93496 | A_BSUK_WallsExternal_Block 0.1 m | Wall existing | general | Existing to Remain
A-Walls-ExternalBlock | MF | Wall existing :2,SHE-02.MEZZANINE.dgn ,Design Model:93505 | A_BSUK_WallsExternal_Block 0.1 m | Wall existing | general | Existing to Remain
A-Walls-ExternalBlock | MF | Wall existing :2,SHE-02.MEZZANINE.dgn ,Design Model:93514 | A_BSUK_WallsExternal_Block 0.1 m | Wall existing | general | Existing to Remain
A-Walls-ExternalBlock | MF | Wall existing :2,SHE-02.MEZZANINE.dgn ,Design Model:93550 | A_BSUK_WallsExternal_Block 0.1 m | Wall existing | general | Existing to Remain
A-Walls-ExternalBlock | MF | Wall existing :2,SHE-02.MEZZANINE.dgn ,Design Model:93595 | A_BSUK_WallsExternal_Block 0.1 m | Wall existing | general | Existing to Remain
A-Walls-ExternalBlock | MF | Wall existing :2,SHE-02.MEZZANINE.dgn ,Design Model:93649 | A_BSUK_WallsExternal_Block 0.187 m | Wall existing | general | Existing to Remain
A-Walls-ExternalBlock | MF | Wall existing :2,SHE-02.MEZZANINE.dgn ,Design Model:93660 | A_BSUK_WallsExternal_Block 0.195 m | Wall existing | general | Existing to Remain
A-Walls-ExternalBlock | MF | Wall existing :2,SHE-02.MEZZANINE.dgn ,Design Model:93681 | A_BSUK_WallsExternal_Block 0.18 m | Wall existing | general | Existing to Remain
A-Walls-ExternalBlock | MF | Wall existing :2,SHE-02.MEZZANINE.dgn ,Design Model:93706 | A_BSUK_WallsExternal_Block 0.189 m | Wall existing | general | Existing to Remain
A-Walls-ExternalBlock | MF | Wall existing :2,SHE-02.MEZZANINE.dgn ,Design Model:93880 | A_BSUK_WallsExternal_Block 0.125 m | Wall existing | general | Existing to Remain
A-Walls-ExternalBlock | MF | Wall existing :2,SHE-02.MEZZANINE.dgn ,Design Model:93889 | A_BSUK_WallsExternal_Block 0.125 m | Wall existing | general | Existing to Remain
A-Walls-ExternalBlock | MF | Wall existing :2,SHE-02.MEZZANINE.dgn ,Design Model:93898 | A_BSUK_WallsExternal_Block 0.125 m | Wall existing | general | Existing to Remain
A-Walls-ExternalBlock | MF | Wall existing :2,SHE-02.MEZZANINE.dgn ,Design Model:94037 | A_BSUK_WallsExternal_Block 0.13 m | Wall existing | general | Existing to Remain
A-Walls-ExternalBlock | MF | Wall existing :2,SHE-02.MEZZANINE.dgn ,Design Model:94046 | A_BSUK_WallsExternal_Block 0.368 m | Wall existing | general | Existing to Remain
A-Walls-ExternalBlock | MF | Upstand :2,SHE-02.MEZZANINE.dgn,Design Model:94055 | A_BSUK_WallsExternal_Block 0.12 m | Upstand | roof light - kdl - flat 1 | New Construction
A-Walls-ExternalBlock | MF | Upstand :2,SHE-02.MEZZANINE.dgn,Design Model:94064 | A_BSUK_WallsExternal_Block 0.12 m | Upstand | roof light - kdl - flat 1 | New Construction
A-Walls-ExternalBlock | MF | Upstand :2,SHE-02.MEZZANINE.dgn,Design Model:94073 | A_BSUK_WallsExternal_Block 0.12 m | Upstand | roof light - kdl - flat 1 | New Construction
A-Walls-ExternalBlock | MF | Upstand :2,SHE-02.MEZZANINE.dgn,Design Model:94082 | A_BSUK_WallsExternal_Block 0.12 m | Upstand | roof light - kdl - flat 1 | New Construction
A-Walls-ExternalBlock | MF | Upstand :2,SHE-02.MEZZANINE.dgn,Design Model:94091 | A_BSUK_WallsExternal_Block 0.12 m | Upstand | roof light - kdl - flat 1 | New Construction
A-Walls-ExternalBlock | MF | Upstand :2,SHE-02.MEZZANINE.dgn,Design Model:94100 | A_BSUK_WallsExternal_Block 0.12 m | Upstand | roof light - kdl - flat 1 | New Construction
A-Walls-ExternalBlock | MF | Upstand :2,SHE-02.MEZZANINE.dgn,Design Model:94109 | A_BSUK_WallsExternal_Block 0.12 m | Upstand | roof light - kdl - flat 1 | New Construction
A-Walls-ExternalBlock | MF | Upstand :2,SHE-02.MEZZANINE.dgn,Design Model:94118 | A_BSUK_WallsExternal_Block 0.12 m | Upstand | roof light - kdl - flat 1 | New Construction
A-Walls-ExternalBlock | MF | Wall existing :2,SHE-02.MEZZANINE.dgn ,Design Model:94147 | A_BSUK_WallsExternal_Block 0.454 m | Wall existing | general | Existing to Remain
A-Walls-ExternalBlock | MF | Wall existing :2,SHE-02.MEZZANINE.dgn ,Design Model:94201 | A_BSUK_WallsExternal_Block 0.115702 m | Wall existing | general | Existing to Remain
A-Walls-ExternalBlock | MF | Wall existing :2,SHE-02.MEZZANINE.dgn ,Design Model:94210 | A_BSUK_WallsExternal_Block 0.173917 m | Wall existing | general | Existing to Remain
A-Walls-ExternalBlock | MF | Wall existing :2,SHE-02.MEZZANINE.dgn ,Design Model:94266 | A_BSUK_WallsExternal_Block 0.265 m | Wall existing | general | Existing to Remain
A-Walls-ExternalBlock | MF | Wall existing :2,SHE-02.MEZZANINE.dgn ,Design Model:94275 | A_BSUK_WallsExternal_Block 0.1 m | Wall existing | general | Existing to Remain
A-Walls-ExternalBlock | MF | Wall existing :2,SHE-02.MEZZANINE.dgn ,Design Model:94284 | A_BSUK_WallsExternal_Block 0.1 m | Wall existing | general | Existing to Remain
A-Walls-ExternalBlock | MF | Wall existing :2,SHE-02.MEZZANINE.dgn ,Design Model:94293 | A_BSUK_WallsExternal_Block 0.265 m | Wall existing | general | Existing to Remain
A-Walls-ExternalBlock | MF | Wall existing :2,SHE-02.MEZZANINE.dgn ,Design Model:203521 | A_BSUK_WallsExternal_Block 0.1241 m | Wall existing | general | Existing to Remain
A-Walls-ExternalBlock | 1F | FacadeBlockwork :4,SHE-03.FIRST.dgn ,Design Model:123162 | A_BSUK_WallsExternal_Block 0.1 m | FacadeBlockwork | existing | Existing to Remain
A-Walls-ExternalBlock | 1F | FacadeBlockwork :4,SHE-03.FIRST.dgn ,Design Model:123171 | A_BSUK_WallsExternal_Block 0.1 m | FacadeBlockwork | existing | Existing to Remain
A-Walls-ExternalBlock | 1F | FacadeBlockwork :4,SHE-03.FIRST.dgn ,Design Model:123180 | A_BSUK_WallsExternal_Block 0.1 m | FacadeBlockwork | existing | Existing to Remain
A-Walls-ExternalBlock | 1F | FacadeBlockwork :4,SHE-03.FIRST.dgn ,Design Model:123189 | A_BSUK_WallsExternal_Block 0.1 m | FacadeBlockwork | existing | Existing to Remain
A-Walls-ExternalBlock | 1F | FacadeBlockwork :4,SHE-03.FIRST.dgn ,Design Model:123198 | A_BSUK_WallsExternal_Block 0.1 m | FacadeBlockwork | existing | Existing to Remain
A-Walls-ExternalBlock | 1F | FacadeBlockwork :4,SHE-03.FIRST.dgn ,Design Model:123207 | A_BSUK_WallsExternal_Block 0.1 m | FacadeBlockwork | existing | Existing to Remain
A-Walls-ExternalBlock | 1F | FacadeBlockwork :4,SHE-03.FIRST.dgn ,Design Model:123216 | A_BSUK_WallsExternal_Block 0.1 m | FacadeBlockwork | existing | Existing to Remain
A-Walls-ExternalBlock | 1F | FacadeBlockwork :4,SHE-03.FIRST.dgn ,Design Model:123225 | A_BSUK_WallsExternal_Block 0.1 m | FacadeBlockwork | existing | Existing to Remain
A-Walls-ExternalBlock | 1F | FacadeBlockwork :4,SHE-03.FIRST.dgn ,Design Model:124098 | A_BSUK_WallsExternal_Block 0.1 m | FacadeBlockwork | existing | Existing to Remain
A-Walls-ExternalBlock | 1F | FacadeBlockwork :4,SHE-03.FIRST.dgn ,Design Model:124107 | A_BSUK_WallsExternal_Block 0.1 m | FacadeBlockwork | existing | Existing to Remain
A-Walls-ExternalBlock | 1F | FacadeBlockwork :4,SHE-03.FIRST.dgn ,Design Model:124116 | A_BSUK_WallsExternal_Block 0.1 m | FacadeBlockwork | existing | Existing to Remain
A-Walls-ExternalBlock | 1F | FacadeBlockwork :4,SHE-03.FIRST.dgn ,Design Model:124125 | A_BSUK_WallsExternal_Block 0.1 m | FacadeBlockwork | existing | Existing to Remain
A-Walls-ExternalBlock | 1F | FacadeBlockwork :4,SHE-03.FIRST.dgn ,Design Model:124134 | A_BSUK_WallsExternal_Block 0.1 m | FacadeBlockwork | existing | Existing to Remain
A-Walls-ExternalBlock | 1F | FacadeBlockwork :4,SHE-03.FIRST.dgn ,Design Model:124143 | A_BSUK_WallsExternal_Block 0.1 m | FacadeBlockwork | existing | Existing to Remain
A-Walls-ExternalBlock | 1F | FacadeBlockwork :4,SHE-03.FIRST.dgn ,Design Model:124152 | A_BSUK_WallsExternal_Block 0.1 m | FacadeBlockwork | existing | Existing to Remain
A-Walls-ExternalBlock | 1F | FacadeBlockwork :4,SHE-03.FIRST.dgn ,Design Model:124161 | A_BSUK_WallsExternal_Block 0.1 m | FacadeBlockwork | existing | Existing to Remain
A-Walls-ExternalBlock | 1F | FacadeBlockwork :4,SHE-03.FIRST.dgn ,Design Model:124170 | A_BSUK_WallsExternal_Block 0.1 m | FacadeBlockwork | existing | Existing to Remain
A-Walls-ExternalBlock | 1F | FacadeBlockwork :4,SHE-03.FIRST.dgn ,Design Model:124179 | A_BSUK_WallsExternal_Block 0.1 m | FacadeBlockwork | existing | Existing to Remain
A-Walls-ExternalBlock | 1F | FacadeBlockwork :4,SHE-03.FIRST.dgn ,Design Model:124188 | A_BSUK_WallsExternal_Block 0.1 m | FacadeBlockwork | existing | Existing to Remain
A-Walls-ExternalBlock | 1F | FacadeBlockwork :4,SHE-03.FIRST.dgn ,Design Model:124197 | A_BSUK_WallsExternal_Block 0.1 m | FacadeBlockwork | existing | Existing to Remain
A-Walls-ExternalBlock | 1F | FacadeBlockwork :4,SHE-03.FIRST.dgn ,Design Model:124206 | A_BSUK_WallsExternal_Block 0.1 m | FacadeBlockwork | existing | Existing to Remain
A-Walls-ExternalBlock | 1F | FacadeBlockwork :4,SHE-03.FIRST.dgn ,Design Model:124215 | A_BSUK_WallsExternal_Block 0.1 m | FacadeBlockwork | existing | Existing to Remain
A-Walls-ExternalBlock | 1F | FacadeBlockwork :4,SHE-03.FIRST.dgn ,Design Model:124224 | A_BSUK_WallsExternal_Block 0.1 m | FacadeBlockwork | existing | Existing to Remain
A-Walls-ExternalBlock | 1F | FacadeBlockwork :4,SHE-03.FIRST.dgn ,Design Model:124233 | A_BSUK_WallsExternal_Block 0.1 m | FacadeBlockwork | existing | Existing to Remain
A-Walls-ExternalBlock | 1F | FacadeBlockwork :4,SHE-03.FIRST.dgn ,Design Model:124242 | A_BSUK_WallsExternal_Block 0.1 m | FacadeBlockwork | existing | Existing to Remain
A-Walls-ExternalBlock | 1F | FacadeBlockwork :4,SHE-03.FIRST.dgn ,Design Model:124251 | A_BSUK_WallsExternal_Block 0.1 m | FacadeBlockwork | existing | Existing to Remain
A-Walls-ExternalBlock | 1F | FacadeBlockwork :4,SHE-03.FIRST.dgn ,Design Model:124800 | A_BSUK_WallsExternal_Block 0.1 m | FacadeBlockwork | existing | Existing to Remain
A-Walls-ExternalBlock | 1F | FacadeBlockwork :4,SHE-03.FIRST.dgn ,Design Model:124809 | A_BSUK_WallsExternal_Block 0.1 m | FacadeBlockwork | existing | Existing to Remain
A-Walls-ExternalBlock | 1F | FacadeBlockwork :4,SHE-03.FIRST.dgn ,Design Model:124818 | A_BSUK_WallsExternal_Block 0.1 m | FacadeBlockwork | existing | Existing to Remain
A-Walls-ExternalBlock | 1F | FacadeBlockwork :4,SHE-03.FIRST.dgn ,Design Model:124827 | A_BSUK_WallsExternal_Block 0.1 m | FacadeBlockwork | existing | Existing to Remain
A-Walls-ExternalBlock | 1F | FacadeBlockwork :4,SHE-03.FIRST.dgn ,Design Model:124836 | A_BSUK_WallsExternal_Block 0.1 m | FacadeBlockwork | existing | Existing to Remain
A-Walls-ExternalBlock | 1F | FacadeBlockwork :4,SHE-03.FIRST.dgn ,Design Model:125043 | A_BSUK_WallsExternal_Block 0.1 m | FacadeBlockwork | existing | Existing to Remain
A-Walls-ExternalBlock | 1F | FacadeBlockwork :4,SHE-03.FIRST.dgn ,Design Model:341944 | A_BSUK_WallsExternal_Block 0.1 m | FacadeBlockwork | existing | Existing to Remain
A-Walls-ExternalBlock | 1F | FacadeBlockwork :4,SHE-03.FIRST.dgn ,Design Model:341953 | A_BSUK_WallsExternal_Block 0.1 m | FacadeBlockwork | existing | Existing to Remain
A-Walls-ExternalBlock | 1F | FacadeBlockwork :4,SHE-03.FIRST.dgn ,Design Model:341962 | A_BSUK_WallsExternal_Block 0.1 m | FacadeBlockwork | existing | Existing to Remain
A-Walls-ExternalBlock | 1F | FacadeBlockwork :4,SHE-03.FIRST.dgn ,Design Model:341971 | A_BSUK_WallsExternal_Block 0.1 m | FacadeBlockwork | existing | Existing to Remain
A-Walls-ExternalBlock | 1F | FacadeBlockwork :4,SHE-03.FIRST.dgn ,Design Model:341980 | A_BSUK_WallsExternal_Block 0.1 m | FacadeBlockwork | existing | Existing to Remain
A-Walls-ExternalBlock | 1F | FacadeBlockwork :4,SHE-03.FIRST.dgn ,Design Model:341989 | A_BSUK_WallsExternal_Block 0.1 m | FacadeBlockwork | existing | Existing to Remain
A-Walls-ExternalBlock | 1F | FacadeBlockwork :4,SHE-03.FIRST.dgn ,Design Model:341998 | A_BSUK_WallsExternal_Block 0.1 m | FacadeBlockwork | existing | Existing to Remain
A-Walls-ExternalBlock | 1F | FacadeBlockwork :4,SHE-03.FIRST.dgn ,Design Model:342007 | A_BSUK_WallsExternal_Block 0.1 m | FacadeBlockwork | existing | Existing to Remain
A-Walls-ExternalBlock | 1F | FacadeBlockwork :4,SHE-03.FIRST.dgn ,Design Model:342016 | A_BSUK_WallsExternal_Block 0.1 m | FacadeBlockwork | existing | Existing to Remain
A-Walls-ExternalBlock | 1F | FacadeBlockwork :4,SHE-03.FIRST.dgn ,Design Model:350342 | A_BSUK_WallsExternal_Block 0.1 m | FacadeBlockwork | existing | Existing to Remain
A-Walls-ExternalBlock | 3F | FacadeBlockwork :6,SHE-05.THIRD.dgn ,Design Model:123162 | A_BSUK_WallsExternal_Block 0.1 m | FacadeBlockwork | existing | Existing to Remain
A-Walls-ExternalBlock | 3F | FacadeBlockwork :6,SHE-05.THIRD.dgn ,Design Model:123171 | A_BSUK_WallsExternal_Block 0.1 m | FacadeBlockwork | existing | Existing to Remain
A-Walls-ExternalBlock | 3F | FacadeBlockwork :6,SHE-05.THIRD.dgn ,Design Model:123180 | A_BSUK_WallsExternal_Block 0.1 m | FacadeBlockwork | existing | Existing to Remain
A-Walls-ExternalBlock | 3F | FacadeBlockwork :6,SHE-05.THIRD.dgn ,Design Model:123189 | A_BSUK_WallsExternal_Block 0.1 m | FacadeBlockwork | existing | Existing to Remain
A-Walls-ExternalBlock | 3F | FacadeBlockwork :6,SHE-05.THIRD.dgn ,Design Model:123198 | A_BSUK_WallsExternal_Block 0.1 m | FacadeBlockwork | existing | Existing to Remain
A-Walls-ExternalBlock | 3F | FacadeBlockwork :6,SHE-05.THIRD.dgn ,Design Model:123207 | A_BSUK_WallsExternal_Block 0.1 m | FacadeBlockwork | existing | Existing to Remain
A-Walls-ExternalBlock | 3F | FacadeBlockwork :6,SHE-05.THIRD.dgn ,Design Model:123216 | A_BSUK_WallsExternal_Block 0.1 m | FacadeBlockwork | existing | Existing to Remain
A-Walls-ExternalBlock | 3F | FacadeBlockwork :6,SHE-05.THIRD.dgn ,Design Model:123225 | A_BSUK_WallsExternal_Block 0.1 m | FacadeBlockwork | existing | Existing to Remain
A-Walls-ExternalBlock | 3F | FacadeBlockwork :6,SHE-05.THIRD.dgn ,Design Model:124098 | A_BSUK_WallsExternal_Block 0.1 m | FacadeBlockwork | existing | Existing to Remain
A-Walls-ExternalBlock | 3F | FacadeBlockwork :6,SHE-05.THIRD.dgn ,Design Model:124107 | A_BSUK_WallsExternal_Block 0.1 m | FacadeBlockwork | existing | Existing to Remain
A-Walls-ExternalBlock | 3F | FacadeBlockwork :6,SHE-05.THIRD.dgn ,Design Model:124116 | A_BSUK_WallsExternal_Block 0.1 m | FacadeBlockwork | existing | Existing to Remain
A-Walls-ExternalBlock | 3F | FacadeBlockwork :6,SHE-05.THIRD.dgn ,Design Model:124125 | A_BSUK_WallsExternal_Block 0.1 m | FacadeBlockwork | existing | Existing to Remain
A-Walls-ExternalBlock | 3F | FacadeBlockwork :6,SHE-05.THIRD.dgn ,Design Model:124134 | A_BSUK_WallsExternal_Block 0.1 m | FacadeBlockwork | existing | Existing to Remain
A-Walls-ExternalBlock | 3F | FacadeBlockwork :6,SHE-05.THIRD.dgn ,Design Model:124143 | A_BSUK_WallsExternal_Block 0.1 m | FacadeBlockwork | existing | Existing to Remain
A-Walls-ExternalBlock | 3F | FacadeBlockwork :6,SHE-05.THIRD.dgn ,Design Model:124152 | A_BSUK_WallsExternal_Block 0.1 m | FacadeBlockwork | existing | Existing to Remain
A-Walls-ExternalBlock | 3F | FacadeBlockwork :6,SHE-05.THIRD.dgn ,Design Model:124161 | A_BSUK_WallsExternal_Block 0.1 m | FacadeBlockwork | existing | Existing to Remain
A-Walls-ExternalBlock | 3F | FacadeBlockwork :6,SHE-05.THIRD.dgn ,Design Model:124170 | A_BSUK_WallsExternal_Block 0.1 m | FacadeBlockwork | existing | Existing to Remain
A-Walls-ExternalBlock | 3F | FacadeBlockwork :6,SHE-05.THIRD.dgn ,Design Model:124179 | A_BSUK_WallsExternal_Block 0.1 m | FacadeBlockwork | existing | Existing to Remain
A-Walls-ExternalBlock | 3F | FacadeBlockwork :6,SHE-05.THIRD.dgn ,Design Model:124188 | A_BSUK_WallsExternal_Block 0.1 m | FacadeBlockwork | existing | Existing to Remain
A-Walls-ExternalBlock | 3F | FacadeBlockwork :6,SHE-05.THIRD.dgn ,Design Model:124197 | A_BSUK_WallsExternal_Block 0.1 m | FacadeBlockwork | existing | Existing to Remain
A-Walls-ExternalBlock | 3F | FacadeBlockwork :6,SHE-05.THIRD.dgn ,Design Model:124206 | A_BSUK_WallsExternal_Block 0.1 m | FacadeBlockwork | existing | Existing to Remain
A-Walls-ExternalBlock | 3F | FacadeBlockwork :6,SHE-05.THIRD.dgn ,Design Model:124215 | A_BSUK_WallsExternal_Block 0.1 m | FacadeBlockwork | existing | Existing to Remain
A-Walls-ExternalBlock | 3F | FacadeBlockwork :6,SHE-05.THIRD.dgn ,Design Model:124224 | A_BSUK_WallsExternal_Block 0.1 m | FacadeBlockwork | existing | Existing to Remain
A-Walls-ExternalBlock | 3F | FacadeBlockwork :6,SHE-05.THIRD.dgn ,Design Model:124233 | A_BSUK_WallsExternal_Block 0.1 m | FacadeBlockwork | existing | Existing to Remain
A-Walls-ExternalBlock | 3F | FacadeBlockwork :6,SHE-05.THIRD.dgn ,Design Model:124242 | A_BSUK_WallsExternal_Block 0.1 m | FacadeBlockwork | existing | Existing to Remain
A-Walls-ExternalBlock | 3F | FacadeBlockwork :6,SHE-05.THIRD.dgn ,Design Model:124251 | A_BSUK_WallsExternal_Block 0.1 m | FacadeBlockwork | existing | Existing to Remain
A-Walls-ExternalBlock | 3F | FacadeBlockwork :6,SHE-05.THIRD.dgn ,Design Model:124800 | A_BSUK_WallsExternal_Block 0.1 m | FacadeBlockwork | existing | Existing to Remain
A-Walls-ExternalBlock | 3F | FacadeBlockwork :6,SHE-05.THIRD.dgn ,Design Model:124809 | A_BSUK_WallsExternal_Block 0.1 m | FacadeBlockwork | existing | Existing to Remain
A-Walls-ExternalBlock | 3F | FacadeBlockwork :6,SHE-05.THIRD.dgn ,Design Model:124818 | A_BSUK_WallsExternal_Block 0.1 m | FacadeBlockwork | existing | Existing to Remain
A-Walls-ExternalBlock | 3F | FacadeBlockwork :6,SHE-05.THIRD.dgn ,Design Model:124827 | A_BSUK_WallsExternal_Block 0.1 m | FacadeBlockwork | existing | Existing to Remain
A-Walls-ExternalBlock | 3F | FacadeBlockwork :6,SHE-05.THIRD.dgn ,Design Model:124836 | A_BSUK_WallsExternal_Block 0.1 m | FacadeBlockwork | existing | Existing to Remain
A-Walls-ExternalBlock | 3F | FacadeBlockwork :6,SHE-05.THIRD.dgn ,Design Model:125043 | A_BSUK_WallsExternal_Block 0.1 m | FacadeBlockwork | existing | Existing to Remain
A-Walls-ExternalBlock | RL | Upstand :10,SHE-08.ROOF.dgn,Design Model:105104 | A_BSUK_WallsExternal_Block 0.2 m | Upstand | AOV 2 - access roof light | New Construction
A-Walls-ExternalBlock | RL | Upstand :10,SHE-08.ROOF.dgn,Design Model:105113 | A_BSUK_WallsExternal_Block 0.2 m | Upstand | AOV 2 - access roof light | New Construction
A-Walls-ExternalBlock | RL | Upstand :10,SHE-08.ROOF.dgn,Design Model:105122 | A_BSUK_WallsExternal_Block 0.2 m | Upstand | AOV 2 - access roof light | New Construction
A-Walls-ExternalBlock | RL | Upstand :10,SHE-08.ROOF.dgn,Design Model:105131 | A_BSUK_WallsExternal_Block 0.2 m | Upstand | AOV 2 - access roof light | New Construction
A-Walls-ExternalBlock | RL | Upstand :10,SHE-08.ROOF.dgn,Design Model:105140 | A_BSUK_WallsExternal_Block 0.2 m | Upstand | AOV 1 - fan | New Construction
A-Walls-ExternalBlock | RL | Upstand :10,SHE-08.ROOF.dgn,Design Model:105149 | A_BSUK_WallsExternal_Block 0.2 m | Upstand | AOV 1 - fan | New Construction
A-Walls-ExternalBlock | RL | Upstand :10,SHE-08.ROOF.dgn,Design Model:105158 | A_BSUK_WallsExternal_Block 0.2 m | Upstand | AOV 1 - fan | New Construction
A-Walls-ExternalBlock | RL | Upstand :10,SHE-08.ROOF.dgn,Design Model:105167 | A_BSUK_WallsExternal_Block 0.2 m | Upstand | AOV 1 - fan | New Construction
A-Walls-ExternalBlock | RL | Upstand :10,SHE-08.ROOF.dgn,Design Model:105176 | A_BSUK_Roofs 0.25 m | Upstand | mansard roof | New Construction | Materials - Part Definition: A-Roofs::A_BSUK_Roofs
A-Walls-ExternalBlock | RL | Upstand :10,SHE-08.ROOF.dgn,Design Model:105185 | A_BSUK_Roofs 0.25 m | Upstand | mansard roof | New Construction | Materials - Part Definition: A-Roofs::A_BSUK_Roofs
A-Walls-ExternalBlock | RL | Upstand :10,SHE-08.ROOF.dgn,Design Model:105194 | A_BSUK_Roofs 0.25 m | Upstand | mansard roof | New Construction | Materials - Part Definition: A-Roofs::A_BSUK_Roofs
A-Walls-ExternalBlock | RL | Upstand :10,SHE-08.ROOF.dgn,Design Model:105203 | A_BSUK_Roofs 0.25 m | Upstand | mansard roof | New Construction | Materials - Part Definition: A-Roofs::A_BSUK_Roofs
A-Walls-ExternalBlock | 2F | FacadeBlockwork :18,SHE-04.SECOND.dgn ,Design Model:123162 | A_BSUK_WallsExternal_Block 0.1 m | FacadeBlockwork | existing | Existing to Remain
A-Walls-ExternalBlock | 2F | FacadeBlockwork :18,SHE-04.SECOND.dgn ,Design Model:123171 | A_BSUK_WallsExternal_Block 0.1 m | FacadeBlockwork | existing | Existing to Remain
A-Walls-ExternalBlock | 2F | FacadeBlockwork :18,SHE-04.SECOND.dgn ,Design Model:123180 | A_BSUK_WallsExternal_Block 0.1 m | FacadeBlockwork | existing | Existing to Remain
A-Walls-ExternalBlock | 2F | FacadeBlockwork :18,SHE-04.SECOND.dgn ,Design Model:123189 | A_BSUK_WallsExternal_Block 0.1 m | FacadeBlockwork | existing | Existing to Remain
A-Walls-ExternalBlock | 2F | FacadeBlockwork :18,SHE-04.SECOND.dgn ,Design Model:123198 | A_BSUK_WallsExternal_Block 0.1 m | FacadeBlockwork | existing | Existing to Remain
A-Walls-ExternalBlock | 2F | FacadeBlockwork :18,SHE-04.SECOND.dgn ,Design Model:123207 | A_BSUK_WallsExternal_Block 0.1 m | FacadeBlockwork | existing | Existing to Remain
A-Walls-ExternalBlock | 2F | FacadeBlockwork :18,SHE-04.SECOND.dgn ,Design Model:123216 | A_BSUK_WallsExternal_Block 0.1 m | FacadeBlockwork | existing | Existing to Remain
A-Walls-ExternalBlock | 2F | FacadeBlockwork :18,SHE-04.SECOND.dgn ,Design Model:123225 | A_BSUK_WallsExternal_Block 0.1 m | FacadeBlockwork | existing | Existing to Remain
A-Walls-ExternalBlock | 2F | FacadeBlockwork :18,SHE-04.SECOND.dgn ,Design Model:124098 | A_BSUK_WallsExternal_Block 0.1 m | FacadeBlockwork | existing | Existing to Remain
A-Walls-ExternalBlock | 2F | FacadeBlockwork :18,SHE-04.SECOND.dgn ,Design Model:124107 | A_BSUK_WallsExternal_Block 0.1 m | FacadeBlockwork | existing | Existing to Remain
A-Walls-ExternalBlock | 2F | FacadeBlockwork :18,SHE-04.SECOND.dgn ,Design Model:124116 | A_BSUK_WallsExternal_Block 0.1 m | FacadeBlockwork | existing | Existing to Remain
A-Walls-ExternalBlock | 2F | FacadeBlockwork :18,SHE-04.SECOND.dgn ,Design Model:124125 | A_BSUK_WallsExternal_Block 0.1 m | FacadeBlockwork | existing | Existing to Remain
A-Walls-ExternalBlock | 2F | FacadeBlockwork :18,SHE-04.SECOND.dgn ,Design Model:124134 | A_BSUK_WallsExternal_Block 0.1 m | FacadeBlockwork | existing | Existing to Remain
A-Walls-ExternalBlock | 2F | FacadeBlockwork :18,SHE-04.SECOND.dgn ,Design Model:124143 | A_BSUK_WallsExternal_Block 0.1 m | FacadeBlockwork | existing | Existing to Remain
A-Walls-ExternalBlock | 2F | FacadeBlockwork :18,SHE-04.SECOND.dgn ,Design Model:124152 | A_BSUK_WallsExternal_Block 0.1 m | FacadeBlockwork | existing | Existing to Remain
A-Walls-ExternalBlock | 2F | FacadeBlockwork :18,SHE-04.SECOND.dgn ,Design Model:124161 | A_BSUK_WallsExternal_Block 0.1 m | FacadeBlockwork | existing | Existing to Remain
A-Walls-ExternalBlock | 2F | FacadeBlockwork :18,SHE-04.SECOND.dgn ,Design Model:124170 | A_BSUK_WallsExternal_Block 0.1 m | FacadeBlockwork | existing | Existing to Remain
A-Walls-ExternalBlock | 2F | FacadeBlockwork :18,SHE-04.SECOND.dgn ,Design Model:124179 | A_BSUK_WallsExternal_Block 0.1 m | FacadeBlockwork | existing | Existing to Remain
A-Walls-ExternalBlock | 2F | FacadeBlockwork :18,SHE-04.SECOND.dgn ,Design Model:124188 | A_BSUK_WallsExternal_Block 0.1 m | FacadeBlockwork | existing | Existing to Remain
A-Walls-ExternalBlock | 2F | FacadeBlockwork :18,SHE-04.SECOND.dgn ,Design Model:124197 | A_BSUK_WallsExternal_Block 0.1 m | FacadeBlockwork | existing | Existing to Remain
A-Walls-ExternalBlock | 2F | FacadeBlockwork :18,SHE-04.SECOND.dgn ,Design Model:124206 | A_BSUK_WallsExternal_Block 0.1 m | FacadeBlockwork | existing | Existing to Remain
A-Walls-ExternalBlock | 2F | FacadeBlockwork :18,SHE-04.SECOND.dgn ,Design Model:124215 | A_BSUK_WallsExternal_Block 0.1 m | FacadeBlockwork | existing | Existing to Remain
A-Walls-ExternalBlock | 2F | FacadeBlockwork :18,SHE-04.SECOND.dgn ,Design Model:124224 | A_BSUK_WallsExternal_Block 0.1 m | FacadeBlockwork | existing | Existing to Remain
A-Walls-ExternalBlock | 2F | FacadeBlockwork :18,SHE-04.SECOND.dgn ,Design Model:124233 | A_BSUK_WallsExternal_Block 0.1 m | FacadeBlockwork | existing | Existing to Remain
A-Walls-ExternalBlock | 2F | FacadeBlockwork :18,SHE-04.SECOND.dgn ,Design Model:124242 | A_BSUK_WallsExternal_Block 0.1 m | FacadeBlockwork | existing | Existing to Remain
A-Walls-ExternalBlock | 2F | FacadeBlockwork :18,SHE-04.SECOND.dgn ,Design Model:124251 | A_BSUK_WallsExternal_Block 0.1 m | FacadeBlockwork | existing | Existing to Remain
A-Walls-ExternalBlock | 2F | FacadeBlockwork :18,SHE-04.SECOND.dgn ,Design Model:124800 | A_BSUK_WallsExternal_Block 0.1 m | FacadeBlockwork | existing | Existing to Remain
A-Walls-ExternalBlock | 2F | FacadeBlockwork :18,SHE-04.SECOND.dgn ,Design Model:124809 | A_BSUK_WallsExternal_Block 0.1 m | FacadeBlockwork | existing | Existing to Remain
A-Walls-ExternalBlock | 2F | FacadeBlockwork :18,SHE-04.SECOND.dgn ,Design Model:124818 | A_BSUK_WallsExternal_Block 0.1 m | FacadeBlockwork | existing | Existing to Remain
A-Walls-ExternalBlock | 2F | FacadeBlockwork :18,SHE-04.SECOND.dgn ,Design Model:124827 | A_BSUK_WallsExternal_Block 0.1 m | FacadeBlockwork | existing | Existing to Remain
A-Walls-ExternalBlock | 2F | FacadeBlockwork :18,SHE-04.SECOND.dgn ,Design Model:124836 | A_BSUK_WallsExternal_Block 0.1 m | FacadeBlockwork | existing | Existing to Remain
A-Walls-ExternalBlock | 2F | FacadeBlockwork :18,SHE-04.SECOND.dgn ,Design Model:125043 | A_BSUK_WallsExternal_Block 0.1 m | FacadeBlockwork | existing | Existing to Remain

# IfcWallStandardCase: A-Walls-ExternalBrick (105)
Type - Wall Parameters - Type: Wall; Compound Wall Assembly: no
Type - Thermal Transmittance - Is External: yes; Is Below Grade: no
Type - Structural Usage - Structural | Material: Brickwork
Type - Space Bounding - Is Space Bounding: yes
Type - Materials - Part Definition: A-Walls::A_BSUK_WallsExternal_Brick
Type - LEED Parameters - LEED | Pre-consumer Recycled (%): 0; LEED | Regional Material: no; LEED | Post-consumer Recycled (%): 0
Type - Fire Resistance - Fire | IsCombustible: no; Fire | Compartmentation: no
Type - Discipline - Discipline: Architectural
Type - Classification - Uniclass2015: Pr_20_93_52_27
Pset_WallCommon - Combustible: no; Compartmentation: no; IsExternal: yes; LoadBearing: no
Name | In | Description | Material | ID | Description | ID | Notes | Phase
A-Walls-ExternalBrick | GF | Wall existing :1,SHE-01.GROUND.dgn ,Design Model:95277 | A_BSUK_WallsExternal_Brick 0.1 m | Wall existing | general | Existing to Remain
A-Walls-ExternalBrick | GF | Wall existing :1,SHE-01.GROUND.dgn ,Design Model:95286 | A_BSUK_WallsExternal_Brick 0.1 m | Wall existing | general | Existing to Remain
A-Walls-ExternalBrick | GF | Wall existing :1,SHE-01.GROUND.dgn ,Design Model:95295 | A_BSUK_WallsExternal_Brick 0.1 m | Wall existing | general | Existing to Remain
A-Walls-ExternalBrick | GF | Wall existing :1,SHE-01.GROUND.dgn ,Design Model:95304 | A_BSUK_WallsExternal_Brick 0.1 m | Wall existing | general | Existing to Remain
A-Walls-ExternalBrick | GF | Wall existing :1,SHE-01.GROUND.dgn ,Design Model:95313 | A_BSUK_WallsExternal_Brick 0.1 m | Wall existing | general | Existing to Remain
A-Walls-ExternalBrick | GF | Wall existing :1,SHE-01.GROUND.dgn ,Design Model:95322 | A_BSUK_WallsExternal_Brick 0.1 m | Wall existing | general | Existing to Remain
A-Walls-ExternalBrick | GF | Wall existing :1,SHE-01.GROUND.dgn ,Design Model:95331 | A_BSUK_WallsExternal_Brick 0.1 m | Wall existing | general | Existing to Remain
A-Walls-ExternalBrick | GF | Wall existing :1,SHE-01.GROUND.dgn ,Design Model:95340 | A_BSUK_WallsExternal_Brick 0.1 m | Wall existing | general | Existing to Remain
A-Walls-ExternalBrick | GF | Wall existing :1,SHE-01.GROUND.dgn ,Design Model:95349 | A_BSUK_WallsExternal_Brick 0.1 m | Wall existing | general | Existing to Remain
A-Walls-ExternalBrick | GF | Wall existing :1,SHE-01.GROUND.dgn ,Design Model:95358 | A_BSUK_WallsExternal_Brick 0.1 m | Wall existing | general | Existing to Remain
A-Walls-ExternalBrick | GF | Wall existing :1,SHE-01.GROUND.dgn ,Design Model:95367 | A_BSUK_WallsExternal_Brick 0.1 m | Wall existing | general | Existing to Remain
A-Walls-ExternalBrick | GF | Wall existing :1,SHE-01.GROUND.dgn ,Design Model:95376 | A_BSUK_WallsExternal_Brick 0.1 m | Wall existing | general | Existing to Remain
A-Walls-ExternalBrick | GF | Wall existing :1,SHE-01.GROUND.dgn ,Design Model:95385 | A_BSUK_WallsExternal_Brick 0.1 m | Wall existing | general | Existing to Remain
A-Walls-ExternalBrick | GF | Wall existing :1,SHE-01.GROUND.dgn ,Design Model:95394 | A_BSUK_WallsExternal_Brick 0.1 m | Wall existing | general | Existing to Remain
A-Walls-ExternalBrick | GF | Wall existing :1,SHE-01.GROUND.dgn ,Design Model:95403 | A_BSUK_WallsExternal_Brick 0.1 m | Wall existing | general | Existing to Remain
A-Walls-ExternalBrick | GF | Wall existing :1,SHE-01.GROUND.dgn ,Design Model:95412 | A_BSUK_WallsExternal_Brick 0.1 m | Wall existing | general | Existing to Remain
A-Walls-ExternalBrick | GF | Wall existing :1,SHE-01.GROUND.dgn ,Design Model:95421 | A_BSUK_WallsExternal_Brick 0.1 m | Wall existing | general | Existing to Remain
A-Walls-ExternalBrick | GF | Wall existing :1,SHE-01.GROUND.dgn ,Design Model:95430 | A_BSUK_WallsExternal_Brick 0.1 m | Wall existing | general | Existing to Remain
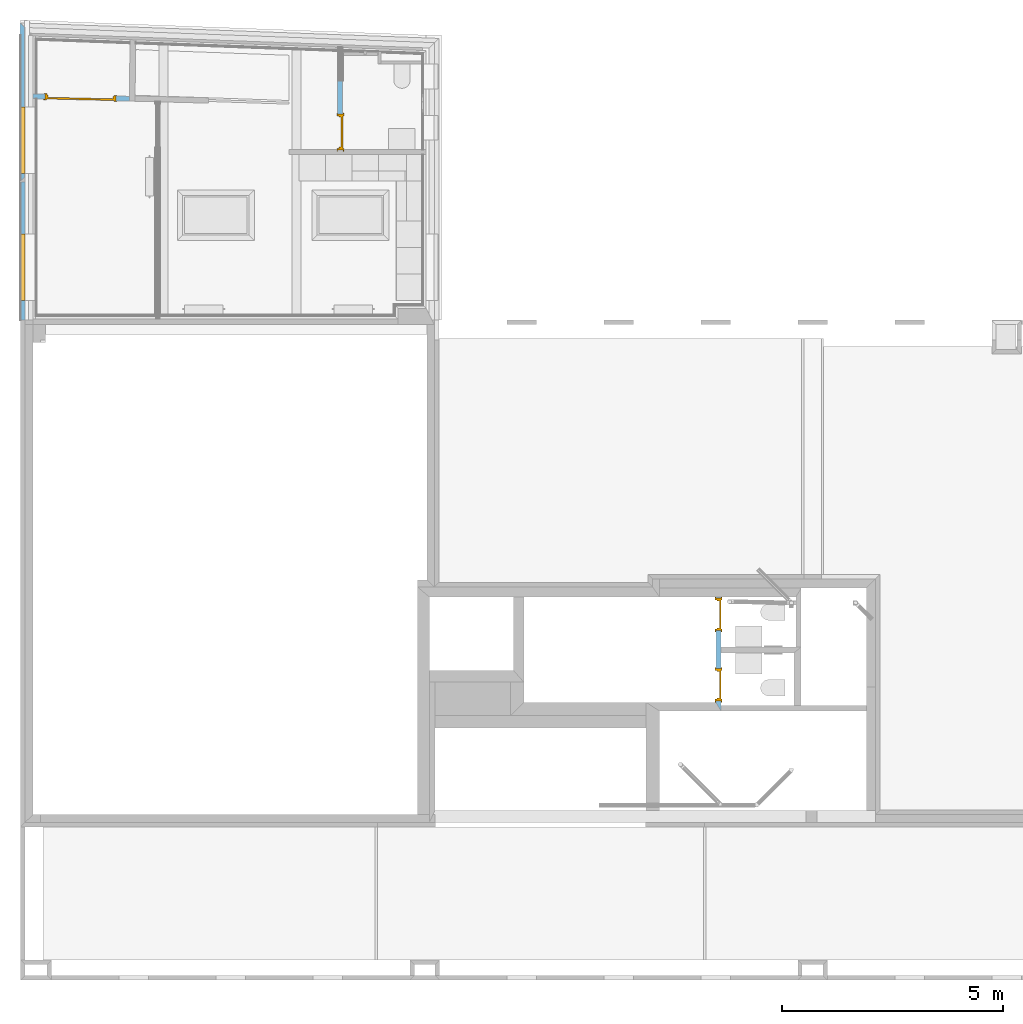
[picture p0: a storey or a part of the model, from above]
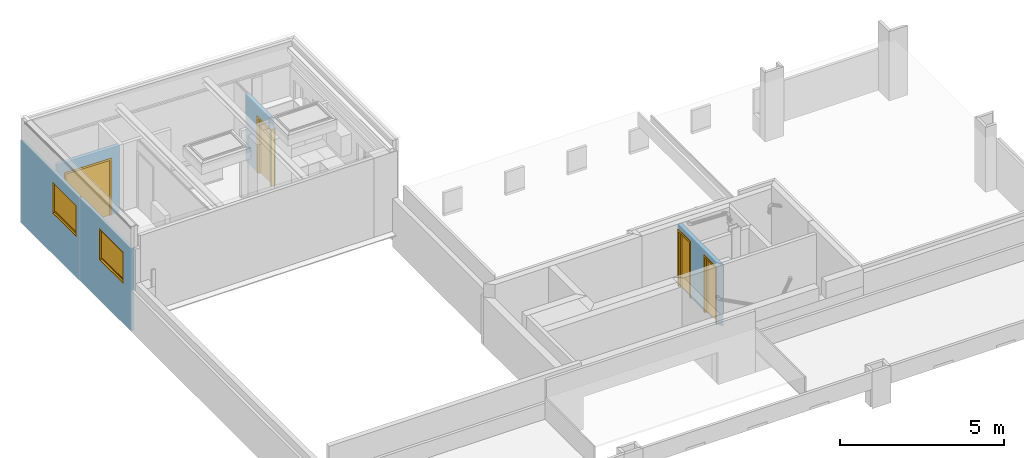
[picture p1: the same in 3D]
Properties of the parts of a building model (IFC2X3), part 17 of 17

# IfcWallStandardCase: default (125)
Name | In | Description | Material | Wall Function | Part Definition
default | 3F | 6 ,SHE-05.THIRD.dgn,Design Model:125160 | A_BSUK_WallInternal_Finishes_Plasterboard 0.013 m | Finish | A-Walls::A_BSUK_WallInternal_Finishes_Plasterboard
default | 3F | 6 ,SHE-05.THIRD.dgn,Design Model:125169 | A_BSUK_Insulation 0.036 m | Rigid Insulation | A-Walls::A_BSUK_Insulation
default | 3F | 6 ,SHE-05.THIRD.dgn,Design Model:126329 | A_BSUK_WallInternal_Finishes_Plasterboard 0.015 m | Finish | A-Walls::A_BSUK_WallInternal_Finishes_Plasterboard
default | 3F | 6 ,SHE-05.THIRD.dgn,Design Model:126338 | A_BSUK_WallInternal_Finishes_Plasterboard 0.015 m | Finish | A-Walls::A_BSUK_WallInternal_Finishes_Plasterboard
default | 3F | 6 ,SHE-05.THIRD.dgn,Design Model:126347 | A_BSUK_Insulation 0.05 m | Structure | A-Walls::A_BSUK_Insulation
default | 3F | 6 ,SHE-05.THIRD.dgn,Design Model:126356 | A_BSUK_WallInternal_Finishes_Plasterboard 0.015 m | Finish | A-Walls::A_BSUK_WallInternal_Finishes_Plasterboard
default | 3F | 6 ,SHE-05.THIRD.dgn,Design Model:126365 | A_BSUK_WallInternal_Finishes_Plasterboard 0.015 m | Finish | A-Walls::A_BSUK_WallInternal_Finishes_Plasterboard
default | 3F | 6 ,SHE-05.THIRD.dgn,Design Model:126374 | A_BSUK_Walls_Timber 0.015 m | Finish | A-Walls::A_BSUK_Walls_Timber
default | 3F | 6 ,SHE-05.THIRD.dgn,Design Model:128119 | A_BSUK_Walls_Timber 0.015 m |  | A-Walls::A_BSUK_Walls_Timber
default | 3F | 6 ,SHE-05.THIRD.dgn,Design Model:128128 | A_BSUK_WallInternal_Finishes_Plasterboard 0.015 m |  | A-Walls::A_BSUK_WallInternal_Finishes_Plasterboard
default | 3F | 6 ,SHE-05.THIRD.dgn,Design Model:128137 | A_BSUK_WallInternal_Finishes_Plasterboard 0.015 m |  | A-Walls::A_BSUK_WallInternal_Finishes_Plasterboard
default | 3F | 6 ,SHE-05.THIRD.dgn,Design Model:128146 | A_BSUK_Insulation 0.05 m |  | A-Walls::A_BSUK_Insulation
default | 3F | 6 ,SHE-05.THIRD.dgn,Design Model:128155 | A_BSUK_WallInternal_Finishes_Plasterboard 0.015 m |  | A-Walls::A_BSUK_WallInternal_Finishes_Plasterboard
default | 3F | 6 ,SHE-05.THIRD.dgn,Design Model:128166 | A_BSUK_WallInternal_Finishes_Plasterboard 0.015 m |  | A-Walls::A_BSUK_WallInternal_Finishes_Plasterboard
default | 3F | 6 ,SHE-05.THIRD.dgn,Design Model:128177 | A_BSUK_Walls_Timber 0.015 m |  | A-Walls::A_BSUK_Walls_Timber
default | 3F | 6 ,SHE-05.THIRD.dgn,Design Model:128834 | A_BSUK_Walls_Timber 0.015 m |  | A-Walls::A_BSUK_Walls_Timber
default | 3F | 6 ,SHE-05.THIRD.dgn,Design Model:128843 | A_BSUK_WallInternal_Finishes_Plasterboard 0.013 m |  | A-Walls::A_BSUK_WallInternal_Finishes_Plasterboard
default | 3F | 6 ,SHE-05.THIRD.dgn,Design Model:128852 | A_BSUK_Insulation 0.036 m |  | A-Walls::A_BSUK_Insulation
default | 3F | 6 ,SHE-05.THIRD.dgn,Design Model:130799 | A_BSUK_Walls_Timber 0.015 m |  | A-Walls::A_BSUK_Walls_Timber
default | 3F | 6 ,SHE-05.THIRD.dgn,Design Model:131208 | A_BSUK_Walls_Timber 0.015 m |  | A-Walls::A_BSUK_Walls_Timber
default | 3F | 6 ,SHE-05.THIRD.dgn,Design Model:131345 | A_BSUK_Walls_Timber 0.015 m |  | A-Walls::A_BSUK_Walls_Timber
default | 3F | 6 ,SHE-05.THIRD.dgn,Design Model:131360 | A_BSUK_Walls_Timber 0.015 m |  | A-Walls::A_BSUK_Walls_Timber
default | 3F | 6 ,SHE-05.THIRD.dgn,Design Model:131375 | A_BSUK_Walls_Timber 0.015 m |  | A-Walls::A_BSUK_Walls_Timber
default | 3F | 6 ,SHE-05.THIRD.dgn,Design Model:132321 | A_BSUK_Walls_Timber 0.015 m |  | A-Walls::A_BSUK_Walls_Timber
default | 1F | 7 ,SHE-06.FOURTH.dgn,Design Model:334314 | A_BSUK_WallInternal_Finishes_Plasterboard 0.015 m |  | A-Walls::A_BSUK_WallInternal_Finishes_Plasterboard
default | 1F | 7 ,SHE-06.FOURTH.dgn,Design Model:334325 | A_BSUK_WallInternal_Finishes_Plasterboard 0.015 m |  | A-Walls::A_BSUK_WallInternal_Finishes_Plasterboard
default | 1F | 7 ,SHE-06.FOURTH.dgn,Design Model:406639 | A_BSUK_Walls_Timber 0.015 m |  | A-Walls::A_BSUK_Walls_Timber
default | 1F | 7 ,SHE-06.FOURTH.dgn,Design Model:406656 | A_BSUK_WallInternal_Finishes_Plasterboard 0.015 m |  | A-Walls::A_BSUK_WallInternal_Finishes_Plasterboard
default | 1F | 7 ,SHE-06.FOURTH.dgn,Design Model:406731 | A_BSUK_Walls_Timber 0.015 m |  | A-Walls::A_BSUK_Walls_Timber
default | 1F | 7 ,SHE-06.FOURTH.dgn,Design Model:406748 | A_BSUK_Walls_Timber 0.015 m |  | A-Walls::A_BSUK_Walls_Timber
default | 1F | 7 ,SHE-06.FOURTH.dgn,Design Model:406759 | A_BSUK_WallInternal_Finishes_Plasterboard 0.015 m |  | A-Walls::A_BSUK_WallInternal_Finishes_Plasterboard
default | 1F | 7 ,SHE-06.FOURTH.dgn,Design Model:406770 | A_BSUK_WallInternal_Finishes_Plasterboard 0.015 m |  | A-Walls::A_BSUK_WallInternal_Finishes_Plasterboard
default | 1F | 7 ,SHE-06.FOURTH.dgn,Design Model:406798 | A_BSUK_Walls_Timber 0.015 m |  | A-Walls::A_BSUK_Walls_Timber
default | 1F | 7 ,SHE-06.FOURTH.dgn,Design Model:406815 | A_BSUK_Walls_Timber 0.015 m |  | A-Walls::A_BSUK_Walls_Timber
default | 1F | 7 ,SHE-06.FOURTH.dgn,Design Model:407005 | A_BSUK_Walls_Timber 0.015 m |  | A-Walls::A_BSUK_Walls_Timber
default | 1F | 7 ,SHE-06.FOURTH.dgn,Design Model:407616 | A_BSUK_Walls_Timber 0.015 m |  | A-Walls::A_BSUK_Walls_Timber
default | 2F | 18 ,SHE-04.SECOND.dgn,Design Model:122667 | A_BSUK_Walls_Timber 0.015 m |  | A-Walls::A_BSUK_Walls_Timber
default | 2F | 18 ,SHE-04.SECOND.dgn,Design Model:122734 | A_BSUK_Walls_Timber 0.015 m |  | A-Walls::A_BSUK_Walls_Timber
default | 2F | 18 ,SHE-04.SECOND.dgn,Design Model:123270 | A_BSUK_WallInternal_Finishes_Plasterboard 0.013 m | Finish | A-Walls::A_BSUK_WallInternal_Finishes_Plasterboard
default | 2F | 18 ,SHE-04.SECOND.dgn,Design Model:123279 | A_BSUK_Insulation 0.036 m | Rigid Insulation | A-Walls::A_BSUK_Insulation
default | 2F | 18 ,SHE-04.SECOND.dgn,Design Model:123414 | A_BSUK_WallInternal_Finishes_Plasterboard 0.013 m | Finish | A-Walls::A_BSUK_WallInternal_Finishes_Plasterboard
default | 2F | 18 ,SHE-04.SECOND.dgn,Design Model:123423 | A_BSUK_Insulation 0.036 m | Rigid Insulation | A-Walls::A_BSUK_Insulation
default | 2F | 18 ,SHE-04.SECOND.dgn,Design Model:123522 | A_BSUK_WallInternal_Finishes_Plasterboard 0.013 m | Finish | A-Walls::A_BSUK_WallInternal_Finishes_Plasterboard
default | 2F | 18 ,SHE-04.SECOND.dgn,Design Model:123531 | A_BSUK_Insulation 0.036 m | Rigid Insulation | A-Walls::A_BSUK_Insulation
default | 2F | 18 ,SHE-04.SECOND.dgn,Design Model:123540 | A_BSUK_WallInternal_Finishes_Plasterboard 0.013 m | Finish | A-Walls::A_BSUK_WallInternal_Finishes_Plasterboard
default | 2F | 18 ,SHE-04.SECOND.dgn,Design Model:123549 | A_BSUK_Insulation 0.036 m | Rigid Insulation | A-Walls::A_BSUK_Insulation
default | 2F | 18 ,SHE-04.SECOND.dgn,Design Model:124260 | A_BSUK_WallInternal_Finishes_Plasterboard 0.013 m | Finish | A-Walls::A_BSUK_WallInternal_Finishes_Plasterboard
default | 2F | 18 ,SHE-04.SECOND.dgn,Design Model:124269 | A_BSUK_Insulation 0.036 m | Rigid Insulation | A-Walls::A_BSUK_Insulation
default | 2F | 18 ,SHE-04.SECOND.dgn,Design Model:124296 | A_BSUK_WallInternal_Finishes_Plasterboard 0.013 m | Finish | A-Walls::A_BSUK_WallInternal_Finishes_Plasterboard
default | 2F | 18 ,SHE-04.SECOND.dgn,Design Model:124305 | A_BSUK_Insulation 0.036 m | Rigid Insulation | A-Walls::A_BSUK_Insulation
default | 2F | 18 ,SHE-04.SECOND.dgn,Design Model:124314 | A_BSUK_WallInternal_Finishes_Plasterboard 0.013 m | Finish | A-Walls::A_BSUK_WallInternal_Finishes_Plasterboard
default | 2F | 18 ,SHE-04.SECOND.dgn,Design Model:124323 | A_BSUK_Insulation 0.036 m | Rigid Insulation | A-Walls::A_BSUK_Insulation
default | 2F | 18 ,SHE-04.SECOND.dgn,Design Model:124350 | A_BSUK_WallInternal_Finishes_Plasterboard 0.013 m | Finish | A-Walls::A_BSUK_WallInternal_Finishes_Plasterboard
default | 2F | 18 ,SHE-04.SECOND.dgn,Design Model:124359 | A_BSUK_Insulation 0.036 m | Rigid Insulation | A-Walls::A_BSUK_Insulation
default | 2F | 18 ,SHE-04.SECOND.dgn,Design Model:124899 | A_BSUK_WallInternal_Finishes_Plasterboard 0.013 m | Finish | A-Walls::A_BSUK_WallInternal_Finishes_Plasterboard
default | 2F | 18 ,SHE-04.SECOND.dgn,Design Model:124908 | A_BSUK_Insulation 0.036 m | Rigid Insulation | A-Walls::A_BSUK_Insulation
default | 2F | 18 ,SHE-04.SECOND.dgn,Design Model:124917 | A_BSUK_WallInternal_Finishes_Plasterboard 0.013 m | Finish | A-Walls::A_BSUK_WallInternal_Finishes_Plasterboard
default | 2F | 18 ,SHE-04.SECOND.dgn,Design Model:124926 | A_BSUK_Insulation 0.036 m | Rigid Insulation | A-Walls::A_BSUK_Insulation
default | 2F | 18 ,SHE-04.SECOND.dgn,Design Model:125025 | A_BSUK_WallInternal_Finishes_Plasterboard 0.013 m | Finish | A-Walls::A_BSUK_WallInternal_Finishes_Plasterboard
default | 2F | 18 ,SHE-04.SECOND.dgn,Design Model:125034 | A_BSUK_Insulation 0.036 m | Rigid Insulation | A-Walls::A_BSUK_Insulation
default | 2F | 18 ,SHE-04.SECOND.dgn,Design Model:125160 | A_BSUK_WallInternal_Finishes_Plasterboard 0.013 m | Finish | A-Walls::A_BSUK_WallInternal_Finishes_Plasterboard
default | 2F | 18 ,SHE-04.SECOND.dgn,Design Model:125169 | A_BSUK_Insulation 0.036 m | Rigid Insulation | A-Walls::A_BSUK_Insulation
default | 2F | 18 ,SHE-04.SECOND.dgn,Design Model:125304 | A_BSUK_Walls_Timber 0.015 m | Finish | A-Walls::A_BSUK_Walls_Timber
default | 2F | 18 ,SHE-04.SECOND.dgn,Design Model:126329 | A_BSUK_WallInternal_Finishes_Plasterboard 0.015 m | Finish | A-Walls::A_BSUK_WallInternal_Finishes_Plasterboard
default | 2F | 18 ,SHE-04.SECOND.dgn,Design Model:126338 | A_BSUK_WallInternal_Finishes_Plasterboard 0.015 m | Finish | A-Walls::A_BSUK_WallInternal_Finishes_Plasterboard
default | 2F | 18 ,SHE-04.SECOND.dgn,Design Model:126347 | A_BSUK_Insulation 0.05 m | Structure | A-Walls::A_BSUK_Insulation
default | 2F | 18 ,SHE-04.SECOND.dgn,Design Model:126356 | A_BSUK_WallInternal_Finishes_Plasterboard 0.015 m | Finish | A-Walls::A_BSUK_WallInternal_Finishes_Plasterboard
default | 2F | 18 ,SHE-04.SECOND.dgn,Design Model:126365 | A_BSUK_WallInternal_Finishes_Plasterboard 0.015 m | Finish | A-Walls::A_BSUK_WallInternal_Finishes_Plasterboard
default | 2F | 18 ,SHE-04.SECOND.dgn,Design Model:126374 | A_BSUK_Walls_Timber 0.015 m | Finish | A-Walls::A_BSUK_Walls_Timber
default | 2F | 18 ,SHE-04.SECOND.dgn,Design Model:126646 | A_BSUK_WallInternal_Finishes_Plasterboard 0.013 m |  | A-Walls::A_BSUK_WallInternal_Finishes_Plasterboard
default | 2F | 18 ,SHE-04.SECOND.dgn,Design Model:128119 | A_BSUK_Walls_Timber 0.015 m |  | A-Walls::A_BSUK_Walls_Timber
default | 2F | 18 ,SHE-04.SECOND.dgn,Design Model:128128 | A_BSUK_WallInternal_Finishes_Plasterboard 0.015 m |  | A-Walls::A_BSUK_WallInternal_Finishes_Plasterboard
default | 2F | 18 ,SHE-04.SECOND.dgn,Design Model:128137 | A_BSUK_WallInternal_Finishes_Plasterboard 0.015 m |  | A-Walls::A_BSUK_WallInternal_Finishes_Plasterboard
default | 2F | 18 ,SHE-04.SECOND.dgn,Design Model:128146 | A_BSUK_Insulation 0.05 m |  | A-Walls::A_BSUK_Insulation
default | 2F | 18 ,SHE-04.SECOND.dgn,Design Model:128155 | A_BSUK_WallInternal_Finishes_Plasterboard 0.015 m |  | A-Walls::A_BSUK_WallInternal_Finishes_Plasterboard
default | 2F | 18 ,SHE-04.SECOND.dgn,Design Model:128166 | A_BSUK_WallInternal_Finishes_Plasterboard 0.015 m |  | A-Walls::A_BSUK_WallInternal_Finishes_Plasterboard
default | 2F | 18 ,SHE-04.SECOND.dgn,Design Model:128177 | A_BSUK_Walls_Timber 0.015 m |  | A-Walls::A_BSUK_Walls_Timber
default | 2F | 18 ,SHE-04.SECOND.dgn,Design Model:128834 | A_BSUK_Walls_Timber 0.015 m |  | A-Walls::A_BSUK_Walls_Timber
default | 2F | 18 ,SHE-04.SECOND.dgn,Design Model:128843 | A_BSUK_WallInternal_Finishes_Plasterboard 0.013 m |  | A-Walls::A_BSUK_WallInternal_Finishes_Plasterboard
default | 2F | 18 ,SHE-04.SECOND.dgn,Design Model:128852 | A_BSUK_Insulation 0.036 m |  | A-Walls::A_BSUK_Insulation
default | 2F | 18 ,SHE-04.SECOND.dgn,Design Model:130799 | A_BSUK_Walls_Timber 0.015 m |  | A-Walls::A_BSUK_Walls_Timber
default | 2F | 18 ,SHE-04.SECOND.dgn,Design Model:131208 | A_BSUK_Walls_Timber 0.015 m |  | A-Walls::A_BSUK_Walls_Timber
default | 2F | 18 ,SHE-04.SECOND.dgn,Design Model:131345 | A_BSUK_Walls_Timber 0.015 m |  | A-Walls::A_BSUK_Walls_Timber
default | 2F | 18 ,SHE-04.SECOND.dgn,Design Model:131360 | A_BSUK_Walls_Timber 0.015 m |  | A-Walls::A_BSUK_Walls_Timber
default | 2F | 18 ,SHE-04.SECOND.dgn,Design Model:131375 | A_BSUK_Walls_Timber 0.015 m |  | A-Walls::A_BSUK_Walls_Timber
default | 2F | 18 ,SHE-04.SECOND.dgn,Design Model:132321 | A_BSUK_Walls_Timber 0.015 m |  | A-Walls::A_BSUK_Walls_Timber

# IfcWindow: A-Awning (34)
Type - Description: Awning Window; OperationType: USERDEFINED; ParameterTakesPrecedence: no; Sizeable: no
Type - Lining - LiningDepth: 0.1 m; LiningThickness: 0.042 m
Type - Window Parameters - Parametric | File Type: PAZ; Parametric | File Name: HM_SNG_Awning; Dimension | Frame Width: 1.36 m; Dimension | Frame Height: 1.455 m; Dimension | Frame Depth: 0.1 m; Dimension | Frame Depth Match Wall: no; Dimension | Frame Thickness: 0.042 m
Type - Window Dimensions- Extended - Dimension | Rough Opening Offset: 0 m; Dimension | Number of Frames: 0
Type - Window - Window | Type: Awning
Type - Thermal Transmittance - Is External: no; Is Below Grade: no
Type - Identification - ID | Description: Awning Window
Type - Fire Resistance - Fire | IsCombustible: no; Fire | Compartmentation: no
Type - Discipline - Discipline: Architectural
Type - Classification - Uniclass2015: Pr_30_59_98
Material: A_BSUK_Windows
Window Dimensions- Extended - Dimension | Mullion Thickness: 0 m; Dimension | Mullion Spacing: 0 m; Dimension | Mullion Offset-Left: 0 m; Dimension | Mullion Offset-Right: 0 m; Dimension | Mullion Offset-Horizontal: 0 m; Dimension | Muntin Horizontal Spacing: 0 m; Dimension | Muntin Vertical Spacing: 0 m; Dimension | Muntin Thickness: 0 m; Dimension | Muntin Inset Distance: 0 m; Dimension | Top Sash Height: 0 m
Identification - ID | Notes: Tilt & Turn Window
Construction Phase - Phase: New Construction
Name | In | Description | OverallHeight (m) = Dimension | Frame Height (m) | OverallWidth (m) = Dimension | Frame Width (m) | Window | Type | ID | Type ID | ID | Number | ID | Description | ID | Keynote | ID | Asset Tag | ID | Name (Alternate)
0.08 | 1 | U-Value 1.4 - bedroom :1,SHE-01.GROUND.dgn,Design Model:107404 | 1.2 | 1.5 | Pivot | U-Value 1.4 | 0.08 | bedroom | Rw 37dB, Rw+Ctr 35dB , trickle vent 45dB | G-Value 0.6 | Window - Glazing | Notes: security - Part Q / PAS24 compliance
0.10 | 0 | commercial side window :1,SHE-01.GROUND.dgn,Design Model:107761 | 1.2 | 1.5 | Pivot |  | 0.10 | commercial side window |  | G-Value 0.6 | Window - Glazing | Notes: security - Part Q / PAS24 compliance
0.12 | 0 | commercial side window :1,SHE-01.GROUND.dgn,Design Model:108118 | 1.2 | 1.5 | Pivot |  | 0.12 | commercial side window |  | G-Value 0.6 | Window - Glazing | Notes: security - Part Q / PAS24 compliance
0.14 | 0 | commercial side window :1,SHE-01.GROUND.dgn,Design Model:108475 | 1.2 | 1.5 | Pivot |  | 0.14 | commercial side window |  | G-Value 0.6 | Window - Glazing | Notes: security - Part Q / PAS24 compliance
0.15 | F | commercial side window / WC :1,SHE-01.GROUND.dgn,Design Model:108701 | 1.2 | 1.5 | Pivot |  | 0.15 | commercial side window / WC |  | G-Value 0.6 | Window - Glazing | Notes: security - Part Q / PAS24 compliance
0.19 | 2 | U-Value 1.4 - bedroom :2,SHE-02.MEZZANINE.dgn,Design Model:98458 | 1.2 | 1.5 | Pivot | U-Value 1.4 | 0.19 | bedroom | Rw 37dB, Rw+Ctr 35dB , trickle vent 45dB | G-Value 0.6
0.20 | 2 | U-Value 1.4 - bedroom :2,SHE-02.MEZZANINE.dgn,Design Model:98684 | 1.2 | 1.5 | Pivot | U-Value 1.4 | 0.20 | bedroom | Rw 37dB, Rw+Ctr 35dB , trickle vent 45dB | G-Value 0.6
0.21 | 01 | U-Value 1.4 - KDL :2 ,SHE-02.MEZZANINE.dgn,Design Model:98910 | 1.2 | 1.5 | Pivot | U-Value 1.4 | 0.21 | KDL | Rw 34dB, Rw+Ctr 30dB , trickle vent 45dB | G-Value 0.6
0.22 | 01 | U-Value 1.4 - bathroom :2,SHE-02.MEZZANINE.dgn,Design Model:99136 | 0.75 | 0.56 | Pivot | U-Value 1.4 | 0.22 | bathroom |  | G-Value 0.6
0.23 | 01 | U-Value 1.4 - bathroom :2,SHE-02.MEZZANINE.dgn,Design Model:99362 | 0.75 | 0.56 | Pivot | U-Value 1.4 | 0.23 | bathroom |  | G-Value 0.6
4.01 | 25 | U-Value 1.2 - dormer front bedroom :7,SHE-06.FOURTH.dgn,Design Model:124802 | 1.5 | 1.15 | Tilt & Turn | U-Value 1.2 | 4.01 | dormer front bedroom | Rw 46dB, Rw+Ctr 40dB | G-Value 0.4 | mechanical ventilation
4.02 | 25 | U-Value 1.2 - dormer front bedroom :7,SHE-06.FOURTH.dgn,Design Model:125028 | 1.5 | 1.15 | Tilt & Turn | U-Value 1.2 | 4.02 | dormer front bedroom | Rw 46dB, Rw+Ctr 40dB | G-Value 0.4 | mechanical ventilation
4.03 | 25 | U-Value 1.2 - dormer front bedroom :7,SHE-06.FOURTH.dgn,Design Model:125254 | 1.5 | 1.15 | Tilt & Turn | U-Value 1.2 | 4.03 | dormer front bedroom | Rw 46dB, Rw+Ctr 40dB | G-Value 0.4 | mechanical ventilation
4.04 | 25 | U-Value 1.2 - dormer front bedroom :7,SHE-06.FOURTH.dgn,Design Model:125480 | 1.5 | 1.15 | Tilt & Turn | U-Value 1.2 | 4.04 | dormer front bedroom | Rw 46dB, Rw+Ctr 40dB | G-Value 0.4 | mechanical ventilation
4.05 | 25 | U-Value 1.2 - dormer front bath :7,SHE-06.FOURTH.dgn,Design Model:125706 | 1.5 | 1.15 | Tilt & Turn | U-Value 1.2 | 4.05 | dormer front bath | Rw 34dB, Rw+Ctr 30dB | G-Value 0.4
4.06 | ensuite | U-Value 1.2 - dormer front bath :7,SHE-06.FOURTH.dgn,Design Model:125932 | 1.5 | 1.15 | Tilt & Turn | U-Value 1.2 | 4.06 | dormer front bath | Rw 34dB, Rw+Ctr 30dB | G-Value 0.4
4.07 | 1 | U-Value 1.2 - dormer front bedroom :7,SHE-06.FOURTH.dgn,Design Model:126158 | 1.5 | 1.15 | Tilt & Turn | U-Value 1.2 | 4.07 | dormer front bedroom | Rw 46dB, Rw+Ctr 40dB | G-Value 0.4 | mechanical ventilation
4.08 | 1 | U-Value 1.2 - dormer front bedroom :7,SHE-06.FOURTH.dgn,Design Model:126384 | 1.5 | 1.15 | Tilt & Turn | U-Value 1.2 | 4.08 | dormer front bedroom | Rw 46dB, Rw+Ctr 40dB | G-Value 0.4 | mechanical ventilation
4.09 | 2 | U-Value 1.2 - dormer front bedroom :7,SHE-06.FOURTH.dgn,Design Model:126610 | 1.5 | 1.15 | Tilt & Turn | U-Value 1.2 | 4.09 | dormer front bedroom | Rw 46dB, Rw+Ctr 40dB | G-Value 0.4 | mechanical ventilation
4.10 | 3 | U-Value 1.2 - dormer front bedroom :7,SHE-06.FOURTH.dgn,Design Model:126836 | 1.5 | 1.15 |  | U-Value 1.2 | 4.10 | dormer front bedroom | Rw 46dB, Rw+Ctr 40dB | G-Value 0.4 | mechanical ventilation
4.11 | 25 | U-Value 1.2 - dormer side bedroom :7,SHE-06.FOURTH.dgn,Design Model:127062 | 1.5 | 1.15 |  | U-Value 1.2 | 4.11 | dormer side bedroom | Rw 46dB, Rw+Ctr 40dB | G-Value 0.4 | mechanical ventilation
4.13 | 26 | U-Value 1.2 - dormer side bath :7,SHE-06.FOURTH.dgn,Design Model:127514 | 1.5 | 1.15 |  | U-Value 1.2 | 4.13 | dormer side bath | Rw 34dB, Rw+Ctr 30dB | G-Value 0.4
4.14 | 26 | U-Value 1.2 - dormer rear bedroom :7,SHE-06.FOURTH.dgn,Design Model:127740 | 1.5 | 1.15 |  | U-Value 1.2 | 4.14 | dormer rear bedroom | Rw 37dB, Rw+Ctr 35dB | G-Value 0.4 | mechanical ventilation
4.15 | 26 | U-Value 1.2 - dormer rear bedroom :7,SHE-06.FOURTH.dgn,Design Model:127966 | 1.5 | 1.15 |  | U-Value 1.2 | 4.15 | dormer rear bedroom | Rw 37dB, Rw+Ctr 35dB | G-Value 0.4 | mechanical ventilation
4.16 | 26 | U-Value 1.2 - dormer rear bedroom :7,SHE-06.FOURTH.dgn,Design Model:128192 | 1.5 | 1.15 |  | U-Value 1.2 | 4.16 | dormer rear bedroom | Rw 37dB, Rw+Ctr 35dB | G-Value 0.4 | mechanical ventilation
4.17 | 1 | U-Value 1.2 - dormer rear bedroom :7,SHE-06.FOURTH.dgn,Design Model:128418 | 1.5 | 1.15 |  | U-Value 1.2 | 4.17 | dormer rear bedroom | Rw 37dB, Rw+Ctr 35dB | G-Value 0.4 | mechanical ventilation
4.18 | 1 | U-Value 1.2 - dormer rear bedroom :7,SHE-06.FOURTH.dgn,Design Model:128644 | 1.5 | 1.15 |  | U-Value 1.2 | 4.18 | dormer rear bedroom | Rw 37dB, Rw+Ctr 35dB | G-Value 0.4 | mechanical ventilation
4.19 | 23 | U-Value 1.2 - dormer rear bedroom :7,SHE-06.FOURTH.dgn,Design Model:128870 | 1.5 | 1.15 |  | U-Value 1.2 | 4.19 | dormer rear bedroom | Rw 37dB, Rw+Ctr 35dB | G-Value 0.4 | mechanical ventilation
4.20 | 1 | U-Value 1.2 - dormer rear bedroom :7,SHE-06.FOURTH.dgn,Design Model:129096 | 1.5 | 1.15 |  | U-Value 1.2 | 4.20 | dormer rear bedroom | Rw 37dB, Rw+Ctr 35dB | G-Value 0.4 | mechanical ventilation
4.21 | 2 | U-Value 1.2 - dormer rear bedroom :7,SHE-06.FOURTH.dgn,Design Model:129322 | 1.5 | 1.15 |  | U-Value 1.2 | 4.21 | dormer rear bedroom | Rw 37dB, Rw+Ctr 35dB | G-Value 0.4 | mechanical ventilation
4.22 | 23 | U-Value 1.2 - sliding rear windows :7,SHE-06.FOURTH.dgn,Design Model:129548 | 1.5 | 1.15 |  | U-Value 1.2 | 4.22 | sliding rear windows | Rw 37dB, Rw+Ctr 35dB | G-Value 0.4 | mechanical ventilation
4.23 | 3 | U-Value 1.2 - dormer rear bedroom :7,SHE-06.FOURTH.dgn,Design Model:129774 | 1.5 | 1.15 |  | U-Value 1.2 | 4.23 | dormer rear bedroom | Rw 37dB, Rw+Ctr 35dB | G-Value 0.4 | mechanical ventilation
4.24 | 23 | U-Value 1.2 - dormer side bedroom :7,SHE-06.FOURTH.dgn,Design Model:130000 | 1.5 | 1.15 |  | U-Value 1.2 | 4.24 | dormer side bedroom | Rw 46dB, Rw+Ctr 40dB | G-Value 0.4 | mechanical ventilation
4.12 | 24 | U-Value 1.2 - dormer side bedroom :7,SHE-06.FOURTH.dgn,Design Model:130452 | 1.5 | 1.15 |  | U-Value 1.2 | 4.12 | dormer side bedroom | Rw 46dB, Rw+Ctr 40dB | G-Value 0.4 | mechanical ventilation

# IfcWindow: A-Fixed (48)
Type - Description: Fixed Window; OperationType: USERDEFINED; ParameterTakesPrecedence: no; Sizeable: no
Type - Lining - LiningDepth: 0.1 m; LiningThickness: 0.042 m
Type - Window Parameters - Parametric | File Type: PAZ; Parametric | File Name: HM_Fixed; Dimension | Frame Width: 1.36 m; Dimension | Frame Height: 1.455 m; Dimension | Frame Depth: 0.1 m; Dimension | Frame Depth Match Wall: no; Dimension | Frame Thickness: 0.042 m
Type - Window Dimensions- Extended - Dimension | Number of Frames: 0
Type - Window - Window | Type: Fixed
Type - Thermal Transmittance - Is External: no; Is Below Grade: no
Type - Identification - ID | Description: Fixed Window
Type - Fire Resistance - Fire | IsCombustible: no; Fire | Compartmentation: no
Type - Discipline - Discipline: Architectural
Type - Classification - Uniclass2015: Pr_30_59_98
Material: A_BSUK_Window_Frames
Window Dimensions- Extended - Dimension | Rough Opening Offset: 0 m; Dimension | Mullion Thickness: 0 m; Dimension | Mullion Spacing: 0 m; Dimension | Mullion Offset-Left: 0 m; Dimension | Mullion Offset-Right: 0 m; Dimension | Mullion Offset-Horizontal: 0 m; Dimension | Muntin Horizontal Spacing: 0 m; Dimension | Muntin Vertical Spacing: 0 m; Dimension | Muntin Thickness: 0 m; Dimension | Muntin Inset Distance: 0 m; Dimension | Top Sash Height: 0 m
Construction Phase - Phase: New Construction
Name | In | Description | OverallHeight (m) | OverallWidth (m) | Dimension | Frame Width (m) | Dimension | Frame Height (m) | Glazing | Notes | ID | Number | ID | Description | ID | Asset Tag | ID | Notes
0.01 | 0 | commercial side window :1,SHE-01.GROUND.dgn,Design Model:106209 | 0.3 | 1.5 | 1.5 | 0.3 | security - Part Q / PAS24 compliance | 0.01 | commercial side window | G-Value 0.6 | Fixed Window
0.02 | UNDERCROFT (front) | commercial shopfront :1 ,SHE-01.GROUND.dgn,Design Model:106471 | 2 | 1.9 | 1.9 | 2 | safety glass - both sides | 0.02 | commercial shopfront | G-Value 0.6 | Fixed Window
0.03 | UNDERCROFT (front) | commercial shopfront :1 ,SHE-01.GROUND.dgn,Design Model:106602 | 2 | 0.55 | 0.55 | 2 | safety glass - both sides | 0.03 | commercial shopfront | G-Value 0.6 | Fixed Window
0.04 | UNDERCROFT (front) | commercial shopfront :1 ,SHE-01.GROUND.dgn,Design Model:106868 | 2 | 1.9 | 1.9 | 2 | safety glass - both sides | 0.04 | commercial shopfront | G-Value 0.6 | Fixed Window
0.09 | 1 | U-Value 1.4 - bedroom :1,SHE-01.GROUND.dgn,Design Model:107630 | 0.3 | 1.5 | 1.5 | 0.3 | security - Part Q / PAS24 compliance | 0.09 | bedroom | G-Value 0.6 | Fixed Window | Identification - ID | Type ID: U-Value 1.4; ID | Keynote: Rw 37dB, Rw+Ctr 35dB
0.11 | 0 | commercial side window :1,SHE-01.GROUND.dgn,Design Model:107987 | 0.3 | 1.5 | 1.5 | 0.3 | security - Part Q / PAS24 compliance | 0.11 | commercial side window | G-Value 0.6 | Fixed Window
0.13 | 0 | commercial side window :1,SHE-01.GROUND.dgn,Design Model:108344 | 0.3 | 1.5 | 1.5 | 0.3 | security - Part Q / PAS24 compliance | 0.13 | commercial side window | G-Value 0.6 | Fixed Window
0.16 | F | commercial side window / WC :1,SHE-01.GROUND.dgn,Design Model:108927 | 0.3 | 1.5 | 1.5 | 0.3 | security - Part Q / PAS24 compliance | 0.16 | commercial side window / WC | G-Value 0.6 | Fixed Window
0.06 | UNDERCROFT (front) | entrance hall shopfront :1,SHE-01.GROUND.dgn,Design Model:137329 | 3.83 | 1.59 | 1.59 | 3.83 | safety glass - both sides | 0.06 | entrance hall shopfront | G-Value 0.6 | Fixed Window
0.05 | UNDERCROFT (front) | entrance hall shopfront :1,SHE-01.GROUND.dgn,Design Model:137460 | 3.83 | 1.59 | 1.59 | 3.83 | safety glass - both sides | 0.05 | entrance hall shopfront | G-Value 0.6 | Fixed Window
0.07 | UNDERCROFT (front) | entrance hall shopfront :1,SHE-01.GROUND.dgn,Design Model:137591 | 3.83 | 1.59 | 1.59 | 3.83 | safety glass - both sides | 0.07 | entrance hall shopfront | G-Value 0.6 | Fixed Window
0.24 | UNDERCROFT (front) | entrance hall shopfront :1,SHE-01.GROUND.dgn,Design Model:288478 | 2.127 | 0.48 | 0.48 | 2.127 | safety glass - obscure panel - entry phone | 0.24 | entrance hall shopfront |  | Fixed Window
0.25 | UNDERCROFT (front) | entrance hall shopfront :1,SHE-01.GROUND.dgn,Design Model:288984 | 2.127 | 0.48 | 0.48 | 2.127 | safety glass - obscure panel - letterbox | 0.25 | entrance hall shopfront |  | Fixed Window
0.17 | MF | U-Value 1.4 - KDL :2 ,SHE-02.MEZZANINE.dgn,Design Model:98188 | 1.5 | 0.9 | 0.9 | 1.5 | security - Part Q / PAS24 compliance | 0.17 | KDL | G-Value 0.6 | Roof Light | Identification - ID | Type ID: U-Value 1.4; ID | Keynote: Rw 34dB, Rw+Ctr 30dB
0.18 | MF | U-Value 1.4 - KDL :2 ,SHE-02.MEZZANINE.dgn,Design Model:98323 | 1.5 | 0.9 | 0.9 | 1.5 | security - Part Q / PAS24 compliance | 0.18 | KDL | G-Value 0.6 | Roof Light | Identification - ID | Type ID: U-Value 1.4; ID | Keynote: Rw 34dB, Rw+Ctr 30dB
5.17 | ter.24 | brise-soleil/shading :8 ,SHE-07.FIFTH.dgn,Design Model:100980 | 2.1 | 0.55 | 0.75 | 2.1 | safety glass - single layer | 5.17 | brise-soleil/shading |  | frameless glass
5.18 | ter.24 | brise-soleil/shading :8 ,SHE-07.FIFTH.dgn,Design Model:101115 | 2.1 | 0.55 | 0.75 | 2.1 | safety glass - single layer | 5.18 | brise-soleil/shading |  | frameless glass
5.19 | ter.24 | brise-soleil/shading :8 ,SHE-07.FIFTH.dgn,Design Model:101250 | 2.1 | 0.55 | 0.75 | 2.1 | safety glass - single layer | 5.19 | brise-soleil/shading |  | frameless glass
5.20 | ter.25 | brise-soleil/shading :8 ,SHE-07.FIFTH.dgn,Design Model:101520 | 2.1 | 0.55 | 0.75 | 2.1 | safety glass - single layer | 5.20 | brise-soleil/shading |  | frameless glass
5.21 | ter.25 | brise-soleil/shading :8 ,SHE-07.FIFTH.dgn,Design Model:101655 | 2.1 | 0.55 | 0.75 | 2.1 | safety glass - single layer | 5.21 | brise-soleil/shading |  | frameless glass
5.22 | ter.25 | brise-soleil/shading :8 ,SHE-07.FIFTH.dgn,Design Model:101790 | 2.1 | 0.55 | 0.75 | 2.1 | safety glass - single layer | 5.22 | brise-soleil/shading |  | frameless glass
5.23 | ter.25 | brise-soleil/shading :8 ,SHE-07.FIFTH.dgn,Design Model:101925 | 1.935 | 0.55 | 0.75 | 1.935 | safety glass - single layer | 5.23 | brise-soleil/shading |  | frameless glass
5.24 | ter.23 | brise-soleil/shading :8 ,SHE-07.FIFTH.dgn,Design Model:102060 | 2.1 | 0.55 | 0.75 | 2.1 | safety glass - single layer | 5.24 | brise-soleil/shading |  | frameless glass
5.25 | ter.23 | brise-soleil/shading :8 ,SHE-07.FIFTH.dgn,Design Model:102330 | 2.1 | 0.55 | 0.75 | 2.1 | safety glass - single layer | 5.25 | brise-soleil/shading |  | frameless glass
5.26 | ter.23 | brise-soleil/shading :8 ,SHE-07.FIFTH.dgn,Design Model:102465 | 2.1 | 0.55 | 0.75 | 2.1 | safety glass - single layer | 5.26 | brise-soleil/shading |  | frameless glass
5.27 | ter.26 | brise-soleil/shading :8 ,SHE-07.FIFTH.dgn,Design Model:102600 | 2.1 | 0.55 | 0.75 | 2.1 | safety glass - single layer | 5.27 | brise-soleil/shading |  | frameless glass
5.28 | ter.26 | brise-soleil/shading :8 ,SHE-07.FIFTH.dgn,Design Model:102735 | 2.1 | 0.55 | 0.75 | 2.1 | safety glass - single layer | 5.28 | brise-soleil/shading |  | frameless glass
5.29 | ter.26 | brise-soleil/shading :8 ,SHE-07.FIFTH.dgn,Design Model:102870 | 2.1 | 0.55 | 0.75 | 2.1 | safety glass - single layer | 5.29 | brise-soleil/shading |  | frameless glass
5.30 | ter.24 | brise-soleil/shading :8 ,SHE-07.FIFTH.dgn,Design Model:119721 | 1.935 | 0.55 | 0.75 | 1.935 | safety glass - single layer | 5.30 | brise-soleil/shading |  | frameless glass
5.31 | ter.26 | brise-soleil/shading :8 ,SHE-07.FIFTH.dgn,Design Model:120004 | 1.935 | 0.55 | 0.75 | 1.935 | safety glass - single layer | 5.31 | brise-soleil/shading |  | frameless glass
5.32 | ter.23 | brise-soleil/shading :8 ,SHE-07.FIFTH.dgn,Design Model:120135 | 1.935 | 0.55 | 0.75 | 1.935 | safety glass - single layer | 5.32 | brise-soleil/shading |  | frameless glass
5.15 | k/d/l | U-Value 1.2 - fixed rear window :8,SHE-07.FIFTH.dgn,Design Model:220645 | 2.2 | 1.6 | 1.6 | 2.2 | safety glass - both sides | 5.15 | fixed rear window | G-Value 0.4 | Patio Doors | Identification - ID | Type ID: U-Value 1.2; ID | Keynote: Rw 34dB, Rw+Ctr 30dB; ID | Name (Alternate): mechanical ventilation
5.16 | k/d/l | U-Value 1.2 - sliding rear windows :8,SHE-07.FIFTH.dgn,Design Model:220776 | 2.2 | 1.6 | 1.6 | 2.2 | safety glass - both sides | 5.16 | sliding rear windows | G-Value 0.4 | Patio Doors | Identification - ID | Type ID: U-Value 1.2; ID | Keynote: Rw 34dB, Rw+Ctr 30dB; ID | Name (Alternate): mechanical ventilation
5.14 | k/d/l | U-Value 1.2 - sliding rear windows :8,SHE-07.FIFTH.dgn,Design Model:220907 | 2.2 | 1.6 | 1.6 | 2.2 | safety glass - both sides | 5.14 | sliding rear windows | G-Value 0.4 | Patio Doors | Identification - ID | Type ID: U-Value 1.2; ID | Keynote: Rw 34dB, Rw+Ctr 30dB; ID | Name (Alternate): mechanical ventilation
5.13 | k/d/l | U-Value 1.2 - fixed rear window :8,SHE-07.FIFTH.dgn,Design Model:221038 | 2.2 | 1.6 | 1.6 | 2.2 | safety glass - both sides | 5.13 | fixed rear window | G-Value 0.4 | Patio Doors | Identification - ID | Type ID: U-Value 1.2; ID | Keynote: Rw 34dB, Rw+Ctr 30dB; ID | Name (Alternate): mechanical ventilation
5.12 | k/d/l | U-Value 1.2 - fixed rear window :8,SHE-07.FIFTH.dgn,Design Model:221169 | 2.2 | 1.6 | 1.6 | 2.2 | safety glass - both sides | 5.12 | fixed rear window | G-Value 0.4 | Patio Doors | Identification - ID | Type ID: U-Value 1.2; ID | Keynote: Rw 34dB, Rw+Ctr 30dB; ID | Name (Alternate): mechanical ventilation
5.11 | k/d/l | U-Value 1.2 - sliding rear windows :8,SHE-07.FIFTH.dgn,Design Model:221300 | 2.2 | 1.6 | 1.6 | 2.2 | safety glass - both sides | 5.11 | sliding rear windows | G-Value 0.4 | Patio Doors | Identification - ID | Type ID: U-Value 1.2; ID | Keynote: Rw 34dB, Rw+Ctr 30dB; ID | Name (Alternate): mechanical ventilation
5.10 | k/d/l | U-Value 1.2 - fixed rear window :8,SHE-07.FIFTH.dgn,Design Model:221431 | 2.2 | 1.6 | 1.6 | 2.2 | safety glass - both sides | 5.10 | fixed rear window | G-Value 0.4 | Patio Doors | Identification - ID | Type ID: U-Value 1.2; ID | Keynote: Rw 34dB, Rw+Ctr 30dB; ID | Name (Alternate): mechanical ventilation
5.09 | k/d/l | U-Value 1.2 - sliding rear windows :8,SHE-07.FIFTH.dgn,Design Model:221562 | 2.2 | 1.6 | 1.6 | 2.2 | safety glass - both sides | 5.09 | sliding rear windows | G-Value 0.4 | Patio Doors | Identification - ID | Type ID: U-Value 1.2; ID | Keynote: Rw 34dB, Rw+Ctr 30dB; ID | Name (Alternate): mechanical ventilation
5.08 | 25 | U-Value 1.2 - sliding front window :8,SHE-07.FIFTH.dgn,Design Model:223051 | 2.2 | 1.6 | 1.6 | 2.2 | safety glass - both sides | 5.08 | sliding front window | G-Value 0.4 | Patio Doors | Identification - ID | Type ID: U-Value 1.2; ID | Keynote: Rw 46dB, Rw+Ctr 40dB; ID | Name (Alternate): mechanical ventilation
5.07 | k/d/l | U-Value 1.2 - fixed front window :8,SHE-07.FIFTH.dgn,Design Model:223186 | 2.2 | 1.6 | 1.6 | 2.2 | safety glass - both sides | 5.07 | fixed front window | G-Value 0.4 | Patio Doors | Identification - ID | Type ID: U-Value 1.2; ID | Keynote: Rw 46dB, Rw+Ctr 40dB; ID | Name (Alternate): mechanical ventilation
5.05 | k/d/l | U-Value 1.2 - sliding front window :8,SHE-07.FIFTH.dgn,Design Model:223321 | 2.2 | 1.6 | 1.6 | 2.2 | safety glass - both sides | 5.05 | sliding front window | G-Value 0.4 | Patio Doors | Identification - ID | Type ID: U-Value 1.2; ID | Keynote: Rw 46dB, Rw+Ctr 40dB; ID | Name (Alternate): mechanical ventilation
5.06 | 25 | U-Value 1.2 - fixed front window :8,SHE-07.FIFTH.dgn,Design Model:223456 | 2.2 | 1.6 | 1.6 | 2.2 | safety glass - both sides | 5.06 | fixed front window | G-Value 0.4 | Patio Doors | Identification - ID | Type ID: U-Value 1.2; ID | Keynote: Rw 46dB, Rw+Ctr 40dB; ID | Name (Alternate): mechanical ventilation
5.01 | 24 | U-Value 1.2 - fixed front window :8,SHE-07.FIFTH.dgn,Design Model:223591 | 2.2 | 1.6 | 1.6 | 2.2 | safety glass - both sides | 5.01 | fixed front window | G-Value 0.4 | Patio Doors | Identification - ID | Type ID: U-Value 1.2; ID | Keynote: Rw 46dB, Rw+Ctr 40dB; ID | Name (Alternate): mechanical ventilation
5.02 | 24 | U-Value 1.2 - sliding front window :8,SHE-07.FIFTH.dgn,Design Model:223726 | 2.2 | 1.6 | 1.6 | 2.2 | safety glass - both sides | 5.02 | sliding front window | G-Value 0.4 | Patio Doors | Identification - ID | Type ID: U-Value 1.2; ID | Keynote: Rw 46dB, Rw+Ctr 40dB; ID | Name (Alternate): mechanical ventilation
5.03 | 24 | U-Value 1.2 - fixed front window :8,SHE-07.FIFTH.dgn,Design Model:223861 | 2.2 | 1.6 | 1.6 | 2.2 | safety glass - both sides | 5.03 | fixed front window | G-Value 0.4 | Patio Doors | Identification - ID | Type ID: U-Value 1.2; ID | Keynote: Rw 46dB, Rw+Ctr 40dB; ID | Name (Alternate): mechanical ventilation
5.04 | 24 | U-Value 1.2 - sliding front window :8,SHE-07.FIFTH.dgn,Design Model:223996 | 2.2 | 1.6 | 1.6 | 2.2 | safety glass - both sides | 5.04 | sliding front window | G-Value 0.4 | Patio Doors | Identification - ID | Type ID: U-Value 1.2; ID | Keynote: Rw 46dB, Rw+Ctr 40dB; ID | Name (Alternate): mechanical ventilation
6.01 | flat roof | U-Value 1.2 - AOV2 access over common parts :10,SHE-08.ROOF.dgn ,Design Model:104968 | 2.038 | 1 | 1 | 2 | self-opening , safety glass | 6.01 | AOV2 access over common parts | G-Value 0.4 | Roof Light | Identification - ID | Type ID: U-Value 1.2
